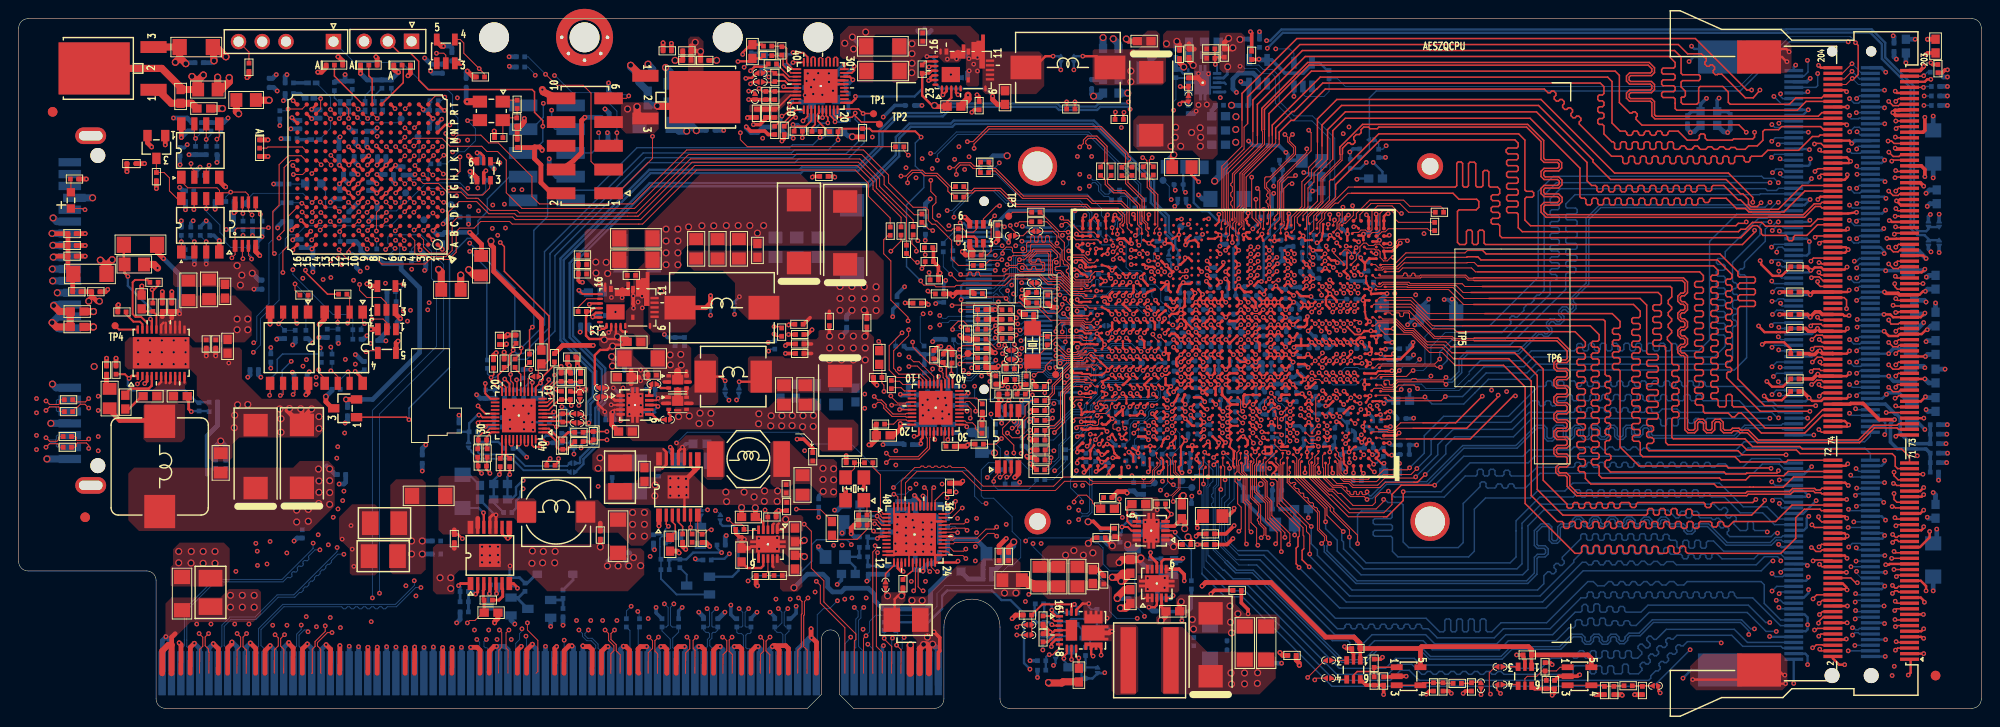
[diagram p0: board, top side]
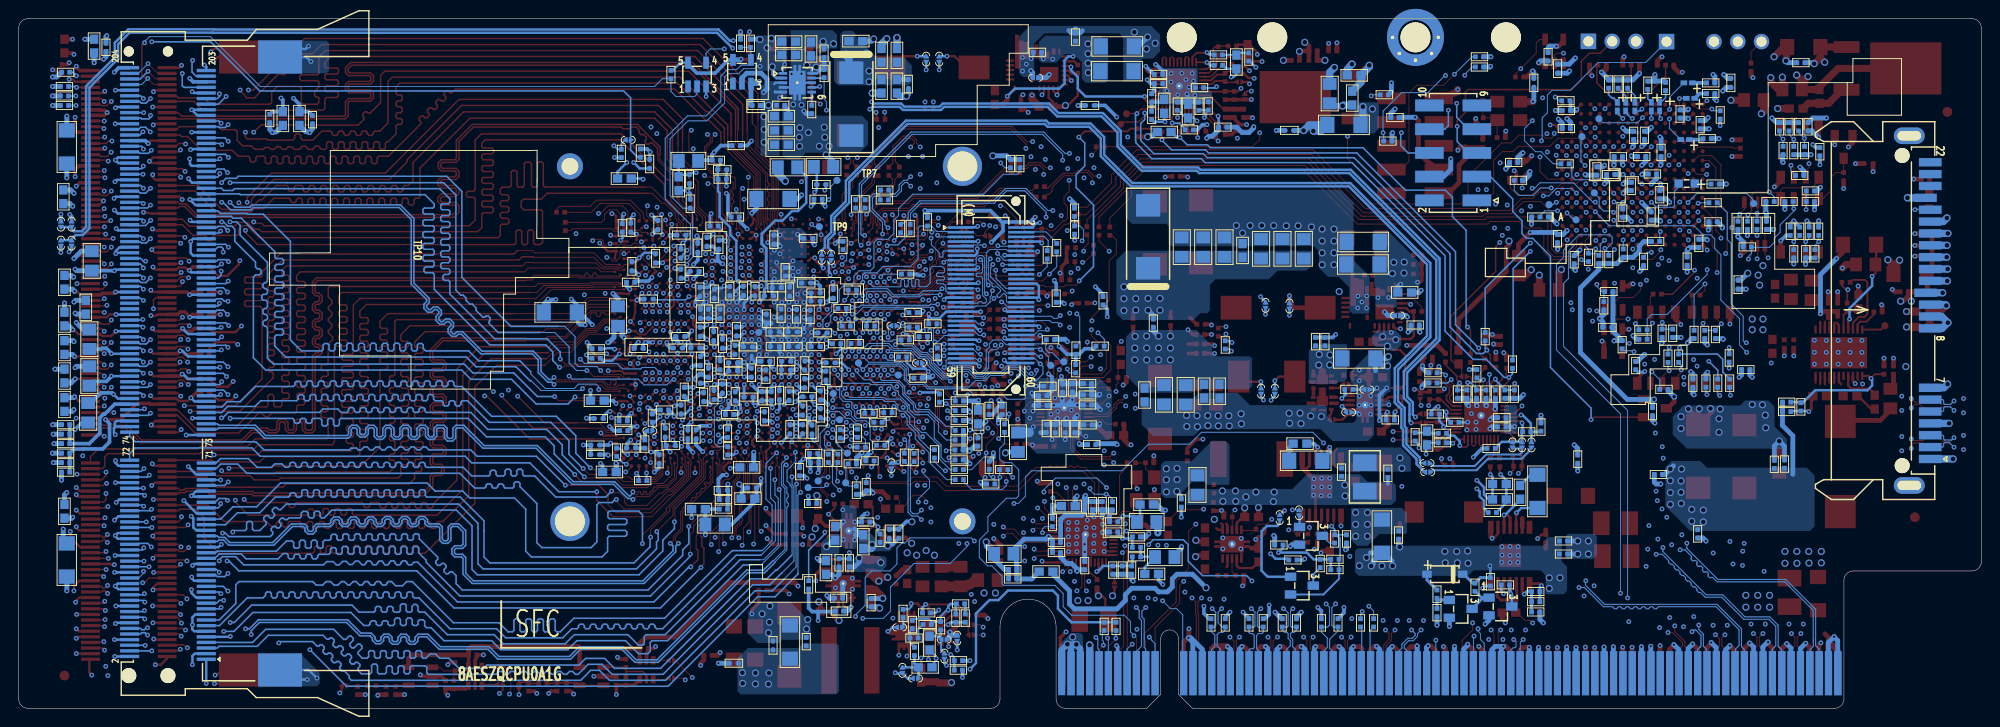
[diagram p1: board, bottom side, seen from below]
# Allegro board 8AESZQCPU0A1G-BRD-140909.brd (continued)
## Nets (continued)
DDR3_CPU_CH1_DQ45: P4.150(DQ45) U14.T1(DDR3_1_DQ_45)
DDR3_CPU_CH1_DQ46: P4.160(DQ46) U14.Y4(DDR3_1_DQ_46)
DDR3_CPU_CH1_DQ47: P4.162(DQ47) U14.Y2(DDR3_1_DQ_47)
DDR3_CPU_CH1_DQ48: P4.165(DQ48) U14.W14(DDR3_1_DQ_48)
DDR3_CPU_CH1_DQ49: P4.167(DQ49) U14.W13(DDR3_1_DQ_49)
DDR3_CPU_CH1_DQ50: P4.177(DQ50) U14.W10(DDR3_1_DQ_50)
DDR3_CPU_CH1_DQ51: P4.179(DQ51) U14.Y11(DDR3_1_DQ_51)
DDR3_CPU_CH1_DQ52: P4.166(DQ52) U14.Y16(DDR3_1_DQ_52)
DDR3_CPU_CH1_DQ53: P4.168(DQ53) U14.Y14(DDR3_1_DQ_53)
DDR3_CPU_CH1_DQ54: P4.174(DQ54) U14.W8(DDR3_1_DQ_54)
DDR3_CPU_CH1_DQ55: P4.176(DQ55) U14.Y10(DDR3_1_DQ_55)
DDR3_CPU_CH1_DQ56: P4.183(DQ56) U14.AC8(DDR3_1_DQ_56)
DDR3_CPU_CH1_DQ57: P4.185(DQ57) U14.AD8(DDR3_1_DQ_57)
DDR3_CPU_CH1_DQ58: P4.191(DQ58) U14.AD15(DDR3_1_DQ_58)
DDR3_CPU_CH1_DQ59: P4.193(DQ59) U14.AC17(DDR3_1_DQ_59)
DDR3_CPU_CH1_DQ60: P4.180(DQ60) U14.AC11(DDR3_1_DQ_60)
DDR3_CPU_CH1_DQ61: P4.182(DQ61) U14.AC9(DDR3_1_DQ_61)
DDR3_CPU_CH1_DQ62: P4.192(DQ62) U14.AC14(DDR3_1_DQ_62)
DDR3_CPU_CH1_DQ63: P4.194(DQ63) U14.AC15(DDR3_1_DQ_63)
DDR3_CPU_CH1_DQS_DN0: P4.10(DQS0#) U14.B37(D\D\R\3\_\1\_\D\Q\S\0\)
DDR3_CPU_CH1_DQS_DN1: P4.25(DQS1#) U14.B30(D\D\R\3\_\1\_\D\Q\S\1\)
DDR3_CPU_CH1_DQS_DN2: P4.43(DQS2#) U14.C22(D\D\R\3\_\1\_\D\Q\S\2\)
DDR3_CPU_CH1_DQS_DN3: P4.60(DQS3#) U14.L29(D\D\R\3\_\1\_\D\Q\S\3\)
DDR3_CPU_CH1_DQS_DN4: P4.139(DQS4#) U14.U12(D\D\R\3\_\1\_\D\Q\S\4\)
DDR3_CPU_CH1_DQS_DN5: P4.154(DQS5#) U14.W3(D\D\R\3\_\1\_\D\Q\S\5\)
DDR3_CPU_CH1_DQS_DN6: P4.171(DQS6#) U14.W7(D\D\R\3\_\1\_\D\Q\S\6\)
DDR3_CPU_CH1_DQS_DN7: P4.186(DQS7#) U14.AD11(D\D\R\3\_\1\_\D\Q\S\7\)
DDR3_CPU_CH1_DQS_DN8: P4.75(DQS8#) U14.D14(DDR3_1_DQSBECC_0)
DDR3_CPU_CH1_DQS_DP0: P4.12(DQS0) U14.D37(DDR3_1_DQS_0)
DDR3_CPU_CH1_DQS_DP1: P4.27(DQS1) U14.D30(DDR3_1_DQS_1)
DDR3_CPU_CH1_DQS_DP2: P4.45(DQS2) U14.A21(DDR3_1_DQS_2)
DDR3_CPU_CH1_DQS_DP3: P4.62(DQS3) U14.M29(DDR3_1_DQS_3)
DDR3_CPU_CH1_DQS_DP4: P4.141(DQS4) U14.U11(DDR3_1_DQS_4)
DDR3_CPU_CH1_DQS_DP5: P4.156(DQS5) U14.W1(DDR3_1_DQS_5)
DDR3_CPU_CH1_DQS_DP6: P4.173(DQS6) U14.Y7(DDR3_1_DQS_6)
DDR3_CPU_CH1_DQS_DP7: P4.188(DQS7) U14.AD12(DDR3_1_DQS_7)
DDR3_CPU_CH1_DQS_DP8: P4.77(DQS8) U14.B14(DDR3_1_DQSECC_0)
DDR3_CPU_CH1_ECC0: P4.69(CB0) U14.D15(DDR3_1_DQECC_0)
DDR3_CPU_CH1_ECC1: P4.71(CB1) U14.C15(DDR3_1_DQECC_1)
DDR3_CPU_CH1_ECC2: P4.81(CB2) U14.D12(DDR3_1_DQECC_2)
DDR3_CPU_CH1_ECC3: P4.83(CB3) U14.E12(DDR3_1_DQECC_3)
DDR3_CPU_CH1_ECC4: P4.72(CB4) U14.D17(DDR3_1_DQECC_4)
DDR3_CPU_CH1_ECC5: P4.74(CB5) U14.B17(DDR3_1_DQECC_5)
DDR3_CPU_CH1_ECC6: P4.80(CB6) U14.C13(DDR3_1_DQECC_6)
DDR3_CPU_CH1_ECC7: P4.82(CB7) U14.B12(DDR3_1_DQECC_7)
DDR3_CPU_CH1_MA0: P4.107(A0) U14.H17(DDR3_1_MA_0)
DDR3_CPU_CH1_MA1: P4.105(A1) U14.G17(DDR3_1_MA_1)
DDR3_CPU_CH1_MA2: P4.106(A2) U14.G18(DDR3_1_MA_2)
DDR3_CPU_CH1_MA3: P4.103(A3) U14.P21(DDR3_1_MA_3)
DDR3_CPU_CH1_MA4: P4.104(A4) U14.M21(DDR3_1_MA_4)
DDR3_CPU_CH1_MA5: P4.99(A5) U14.H22(DDR3_1_MA_5)
DDR3_CPU_CH1_MA6: P4.100(A6) U14.J21(DDR3_1_MA_6)
DDR3_CPU_CH1_MA7: P4.98(A7) U14.J22(DDR3_1_MA_7)
DDR3_CPU_CH1_MA8: P4.97(A8) U14.H21(DDR3_1_MA_8)
DDR3_CPU_CH1_MA9: P4.92(A9) U14.M22(DDR3_1_MA_9)
DDR3_CPU_CH1_MA10: P4.117(A10/AP) U14.L18(DDR3_1_MA_10)
DDR3_CPU_CH1_MA11: P4.96(A11) U14.P22(DDR3_1_MA_11)
DDR3_CPU_CH1_MA12: P4.95(A12) U14.G25(DDR3_1_MA_12)
DDR3_CPU_CH1_MA13: P4.130(A13) U14.G3(DDR3_1_MA_13)
DDR3_CPU_CH1_MA14: P4.90(A14) U14.G26(DDR3_1_MA_14)
DDR3_CPU_CH1_MA15: P4.88(A15) U14.H26(DDR3_1_MA_15)
DDR3_CPU_CH1_ODT0: P4.126(ODT0) U14.L2(DDR3_1_ODT_0)
DDR3_CPU_CH1_ODT1: P4.128(NC/ODT1) U14.N2(DDR3_1_ODT_1)
DDR3_CPU_CH1_RAS_N: P4.122(RAS#) U14.L8(D\D\R\3\_\1\_\R\A\S\)
DDR3_CPU_CH1_RESET_N: N46.2 P4.30(RESET#) R292.2
DDR3_CPU_CH1_RESET_R_N: N46.1 R275.1 U14.N11(D\D\R\3\_\1\_\D\R\A\M\R\S\T\)
DDR3_CPU_CH1_VREF: C449.1 R317.1 R319.2 U14.R29(DDR3_1_VREF)
DDR3_CPU_CH1_VREFCA: C403.1 P4.84(VREFCA) R286.1 R291.2
DDR3_CPU_CH1_VREFDQ: N25.2 P4.1(VREFDQ)
DDR3_CPU_CH1_WE_N: P4.121(WE#) U14.N7(D\D\R\3\_\1\_\W\E\)
DDR3_VCCA_PWROK: U1.2(IN) U7.A9(IO_2_A9/DIFFIO_T11N) U13.2(IN)
ERROR_CPU_N0: R47.2 U7.K14(IO_3_K14/DIFFIO_R17N) U14.AL65(E\R\R\O\R\0\)
ERROR_CPU_N1: R41.2 U7.K13(IO_3_K13/DIFFIO_R16N) U14.AL62(E\R\R\O\R\1\)
ERROR_CPU_N2: R43.2 U7.K12(IO_3_K12/DIFFIO_R15N) U14.AL63(E\R\R\O\R\2\)
FLEX_CLK_SE0: R237.2 R250.2 U14.AH59(FLEX_CLK_SE0)
FLEX_CLK_SE1: R83.2 R85.2 U14.AG56(FLEX_CLK_SE1)
FP_PWR_BTN_N: R207.2 S1.B8(PWR_BTN#) U7.B16(IO_2_B16/DIFFIO_T21N)
FP_RST_BTN_N: TP8.1 U7.F1(IO_1_F1/DIFFIO_L7P)
FPGA_JMPR1: J5.2 U7.E1(IO_1_E1/DIFFIO_L6P)
GBE_CPU_SDP0_1: TP15.1 U14.T48(GBE_SDP0_1)
GBE_CPU_WOL: R103.1 R106.1 U14.V63(GBE_WOL)
GBE_OBSN: R285.1 U14.H50(GBE_OBSN)
GBE_OBSP: R285.2 U14.G50(GBE_OBSP)
GBE_RXN_0: TP16.1 U14.K48(GBE_RXN_0)
GBE_RXP_0: TP17.1 U14.H48(GBE_RXP_0)
GBE_TXN_0: TP20.1 U14.B48(GBE_TXN_0)
GBE_TXP_0: TP18.1 U14.D48(GBE_TXP_0)
GPIO_CPU_11: R46.2 U7.B5(IO_2_B5) U14.AN63(SMB_DATA1)
GPIO_CPU_12: R31.2 U7.B14(IO_2_B14/DIFFIO_T19N) U14.AR63(SMB_CLK1)
GPIO_CPU_SUS0: R101.2 U7.C13(IO_2_C13/DIFFIO_T21P) U14.V66(GPIO_SUS0)
GPIO_CPU_SUS1: R304.2 R314.2 TP19.1 U14.W54(GPIO_SUS1)
GPIO_CPU_SUS2: U7.K1(IO_1_K1/DIFFIO_L13N) U14.T53(GPIO_SUS2)
GPIO_CPU_SUS6: R288.2 U7.D10(IO_2_D10) U14.AC52(P\M\U\_\S\L\P\_\D\D\R\V\T\T\)
GPIO_CPU_SUS7: R270.2 U7.H4(IO_1_H4/DIFFIO_L12P) U14.Y50(P\M\U\_\S\L\P\_\L\A\N\)
I2C_ID_A0: R205.2 R213.1 U9.1(A0)
I2C_ID_A1: R204.2 R212.1 U9.2(A2)
I2C_ID_A2: R203.2 R211.1 U9.3(A3)
ID_EEPROM_VCC: C39.1 U4.3(C) U9.8(VCC)
ID_EEPROM_WP_P: R192.1 R195.1 U9.7(WP)
INTRUDER_N: R254.1 U14.AD53(I\N\T\R\U\D\E\R\)
IRQ_ILB_SERIRQ_CPU: R221.1 U7.C2(IO_1_C2/DIFFIO_L1N) U14.AT50(ILB_SERIRQ)
LED_SEG0_0_HI: D8.2 U7.R11(IO_4_R11/DIFFIO_B17P)
LED_SEG0_0_HI_R: D8.1 R156.1
LED_SEG0_1_HI: D2.2 U7.R12(IO_4_R12/DIFFIO_B19P)
LED_SEG0_1_HI_R: D2.1 R150.1
LED_SEG0_2_HI: D9.2 U7.R13(IO_4_R13/DIFFIO_B21N)
LED_SEG0_2_HI_R: D9.1 R175.1
LED_SEG0_3_HI: D3.2 U7.R14(IO_4_R14/DIFFIO_B22N)
LED_SEG0_3_HI_R: D3.1 R158.1
LED_SEG1_0_HI_R: D4.1 R151.1
LED_SEG1_0_LO: D4.2 U7.R8(IO_4_R8/DIFFIO_B11N)
LED_SEG1_1_HI_R: D5.1 R152.1
LED_SEG1_1_LO: D5.2 U7.R9(IO_4_R9/DIFFIO_B13N)
LED_SEG1_2_HI_R: D6.1 R153.1
LED_SEG1_2_LO: D6.2 U7.T10(IO_4_T10/DIFFIO_B14N)
LED_SEG1_3_HI_R: D7.1 R154.1
LED_SEG1_3_LO: D7.2 U7.T11(IO_4_T11/DIFFIO_B17N)
LPC_CLKRUN_N: R81.2 U14.AH48(L\P\C\_\C\L\K\R\U\N\)
LPC_FRAME_N: R32.1 U7.H3(IO_1_H3/DIFFIO_L11P)
LPC_FRAME_N_R: R32.2 U14.AH56(L\P\C\_\F\R\A\M\E\)
LPC_LAD0: R38.1 U7.B3(IO_2_B3/DIFFIO_T3P)
LPC_LAD0_R: R38.2 U14.AG54(LPC_AD0)
LPC_LAD1: R24.1 U7.E8(IO_2_E8)
LPC_LAD1_R: R24.2 U14.AM53(LPC_AD1)
LPC_LAD2: R42.1 U7.C10(IO_2_C10)
LPC_LAD2_R: R42.2 U14.AL53(LPC_AD2)
LPC_LAD3: R33.1 U7.B4(IO_2_B4/DIFFIO_T4P)
LPC_LAD3_R: R33.2 U14.AG59(LPC_AD3)
MARGIN_DN: N54.1 U7.E7(IO_2_E7/DIFFIO_T7N)
MARGIN_UP: N53.1 U7.E6(IO_2_E6)
MB_PCIE0_RX0_N: S1.A18(PCIE0_RX0_N) U14.BE64(PCIE_RXN_0)
MB_PCIE0_RX0_P: S1.A17(PCIE0_RX0_P) U14.BE63(PCIE_RXP_0)
MB_PCIE0_RX1_N: S1.A22(PCIE0_RX1_N) U14.BH64(PCIE_RXN_1)
MB_PCIE0_RX1_P: S1.A21(PCIE0_RX1_P) U14.BJ63(PCIE_RXP_1)
MB_PCIE0_RX2_N: S1.A26(PCIE0_RX2_N) U14.BK62(PCIE_RXN_2)
MB_PCIE0_RX2_P: S1.A25(PCIE0_RX2_P) U14.BJ62(PCIE_RXP_2)
MB_PCIE0_RX3_N: S1.A30(PCIE0_RX3_N) U14.BH58(PCIE_RXN_3)
MB_PCIE0_RX3_P: S1.A29(PCIE0_RX3_P) U14.BG58(PCIE_RXP_3)
MB_PCIE0_RX4_N: S1.A66(PCIE1_RX0_N) U14.BH57(PCIE_RXN_4)
MB_PCIE0_RX4_P: S1.A65(PCIE1_RX0_P) U14.BG57(PCIE_RXP_4)
MB_PCIE0_RX5_N: S1.A70(PCIE1_RX1_N) U14.BF54(PCIE_RXN_5)
MB_PCIE0_RX5_P: S1.A69(PCIE1_RX1_P) U14.BD54(PCIE_RXP_5)
MB_PCIE0_RX6_N: S1.A74(PCIE1_RX2_N) U14.BG53(PCIE_RXN_6)
MB_PCIE0_RX6_P: S1.A73(PCIE1_RX2_P) U14.BF53(PCIE_RXP_6)
MB_PCIE0_RX7_N: S1.A78(PCIE1_RX3_N) U14.BG50(PCIE_RXN_7)
MB_PCIE0_RX7_P: S1.A77(PCIE1_RX3_P) U14.BE50(PCIE_RXP_7)
MEMHOT_V1P0_N: R184.1 U14.AL46(M\E\M\H\O\T\) U37.4(OUT)
MEMHOT_V3P3_N: P1.198(EVENT#) P4.198(EVENT#) R148.1 U37.2(IN)
NCSI_ARB_OUT: TP14.1 U14.Y59(RSVD13)
PCIE0_MB_TX0_C_N: C253.1 U14.BL61(PCIE_TXN_0)
PCIE0_MB_TX0_C_P: C254.1 U14.BK60(PCIE_TXP_0)
PCIE0_MB_TX0_N: C253.2 C490.2 S1.B16(PCIE0_TX0_N)
PCIE0_MB_TX0_P: C254.2 C489.2 S1.B15(PCIE0_TX0_P)
PCIE0_MB_TX1_C_N: C235.1 U14.BM58(PCIE_TXN_1)
PCIE0_MB_TX1_C_P: C240.1 U14.BL59(PCIE_TXP_1)
PCIE0_MB_TX1_N: C235.2 C492.2 S1.B20(PCIE0_TX1_N)
PCIE0_MB_TX1_P: C240.2 C491.2 S1.B19(PCIE0_TX1_P)
PCIE0_MB_TX2_C_N: C40.1 U14.BN57(PCIE_TXN_2)
PCIE0_MB_TX2_C_P: C41.1 U14.BL57(PCIE_TXP_2)
PCIE0_MB_TX2_N: C40.2 C494.2 S1.B24(PCIE0_TX2_N)
PCIE0_MB_TX2_P: C41.2 C493.2 S1.B23(PCIE0_TX2_P)
PCIE0_MB_TX3_C_N: C29.1 U14.BN55(PCIE_TXN_3)
PCIE0_MB_TX3_C_P: C37.1 U14.BL55(PCIE_TXP_3)
PCIE0_MB_TX3_N: C29.2 C496.2 S1.B28(PCIE0_TX3_N)
PCIE0_MB_TX3_P: C37.2 C495.2 S1.B27(PCIE0_TX3_P)
PCIE0_MB_TX4_C_N: C242.1 U14.BK54(PCIE_TXN_4)
PCIE0_MB_TX4_C_P: C243.1 U14.BM54(PCIE_TXP_4)
PCIE0_MB_TX4_N: C242.2 S1.B68(PCIE1_TX0_N)
PCIE0_MB_TX4_P: C243.2 S1.B67(PCIE1_TX0_P)
PCIE0_MB_TX5_C_N: C33.1 U14.BL53(PCIE_TXN_5)
PCIE0_MB_TX5_C_P: C35.1 U14.BN53(PCIE_TXP_5)
PCIE0_MB_TX5_N: C33.2 S1.B72(PCIE1_TX1_N)
PCIE0_MB_TX5_P: C35.2 S1.B71(PCIE1_TX1_P)
PCIE0_MB_TX6_C_N: C34.1 U14.BM52(PCIE_TXN_6)
PCIE0_MB_TX6_C_P: C36.1 U14.BL52(PCIE_TXP_6)
PCIE0_MB_TX6_N: C34.2 S1.B76(PCIE1_TX2_N)
PCIE0_MB_TX6_P: C36.2 S1.B75(PCIE1_TX2_P)
PCIE0_MB_TX7_C_N: C32.1 U14.BL50(PCIE_TXN_7)
PCIE0_MB_TX7_C_P: C31.1 U14.BN50(PCIE_TXP_7)
PCIE0_MB_TX7_N: C32.2 S1.B80(PCIE1_TX3_N)
PCIE0_MB_TX7_P: C31.2 S1.B79(PCIE1_TX3_P)
PHSFLT_VCCP: R54.2 U12.18(PHSFLT_N)
PHY_MDIO0_I2C_CLK: R112.2 U14.W56(GBE_MDIO0_I2C_CLK)
PHY_MDIO0_I2C_DATA: R289.2 U14.W59(GBE_MDIO0_I2C_DATA)
PHY_MDIO1_I2C_CLK: R281.2 S1.A9(SVR_ID2/GPIO2)
PHY_MDIO1_I2C_CLK_MUX: R281.1 U14.Y54(GBE_MDIO1_I2C_CLK)
PHY_MDIO1_I2C_DATA: S1.A10(SVR_ID3/GPIO3) U14.Y53(GBE_MDIO1_I2C_DATA)
PLTRST_N: R84.2 U7.K5(IO_1_K5/DIFFIO_L15P) U14.AE62(P\M\U\_\P\L\T\R\S\T\)
PLTRST_PCIE1_N: R168.2 S1.B39(PCIE1_RESET#) U7.T15(IO_4_T15/DIFFIO_B23N)
PLTRST_PCIE2_N: R162.2 S1.A11(PCIE0_RESET#) U7.T2(IO_4_T2/DIFFIO_B2P)
PM_DDR_VTT_PWRGD: R146.2 U7.A6(IO_2_A6/DIFFIO_T8N) U38.9(PGOOD)
PM_V1P0_EN: N19.1 U7.E3(IO_1_E3/DIFFIO_L2N)
PM_V1P0_PWRGD: R354.2 R356.2 U7.A5(IO_2_A5/DIFFIO_T6P) U31.7(PGOOD)
PM_V1P1_EN: R123.2 U7.E9(IO_2_E9/DIFFIO_T12P) U25.7(EN)
PM_V1P1_PWRGD: R122.2 U7.L4(IO_1_L4/DIFFIO_L18N) U25.6(PG)
PM_V1P5_EN: R121.1 U7.M3(IO_1_M3/DIFFIO_L18P) U28.5(EN)
PM_V1P5_PWRGD: R118.2 U7.J1(IO_1_J1/DIFFIO_L11N) U28.3(PG)
PM_V1P8_EN: R341.1 U7.F4(IO_1_F4/DIFFIO_L5N) U30.5(EN)
PM_V1P8_PWRGD: R343.2 U7.L2(IO_1_L2/DIFFIO_L16P) U30.3(PG)
PM_V1P35_EN: R116.1 U7.H2(IO_1_H2/DIFFIO_L10P) U26.5(EN)
PM_V1P35_PWRGD: R337.2 U7.N1(IO_1_N1/DIFFIO_L19P) U26.3(PG)
PM_V3P3_PWRGD: R44.1 R52.1 U7.C3(IO_1_C3/DIFFIO_L2P) U8.1(EN) U17.3(PGOOD)
PM_V3P3_V1P9_EN: U7.E4(IO_1_E4/DIFFIO_L3N) U17.2(EN)
PM_V5A_PWRGD: C155.2 N20.1 R127.1 U29.3(VREG5)
PM_VCCP_EN: R264.2 U7.F2(IO_1_F2) U23.17(EN)
PM_VCCP_PWRGD: R251.2 U7.L1(IO_1_L1/DIFFIO_L15N) U23.9(PWRGD_VRDY1)
PM_VDDQ_EN: N4.1 R173.2 U3.17(EN) U7.H1(IO_1_H1/DIFFIO_L10N)
PM_VDDQ_PWRGD: R172.2 U3.9(PWRGD_VRDY1) U7.A8(IO_2_A8/DIFFIO_T11P) U11.2(IN) U36.2(IN)
PM_VNN_EN: R255.2 U7.L3(IO_1_L3/DIFFIO_L19N) U23.10(PWROK_ENL2_INMODE)
PM_VNN_PWRGD: R273.2 U7.L5(IO_1_L5) U23.3(VRDY2)
PMU_AC_PRESENT: R301.2 U14.AA47(PMU_AC_PRESENT)
PMU_GPE_N: R92.2 U14.AB63(P\M\U\_\G\P\E\)
PMU_SLP_S3_N: U7.B9(IO_2_B9/DIFFIO_T12N) U14.AF65(P\M\U\_\S\L\P\_\S\3\)
PMU_SLP_S45_N: U7.K4(IO_1_K4/DIFFIO_L16N) U14.V64(P\M\U\_\S\L\P\_\S\4\5\)
PMU_SUSCLK: R245.2 U14.AD58(PMU_SUSCLK)
PMU_WAKE_N: R80.2 U14.AD66(P\M\U\_\W\A\K\E\)
PWM1_VCCP: U12.19(PWM) U23.21(PWM1)
PWM1_VDDQ_CH01: U2.19(PWM) U3.21(PWM1)
PWM1_VNN: U20.3(PWM) U23.25(PWM1_L2)
PWRGD_COREPWR: N40.2 R61.1 R228.1 U7.F6(IO_1_F6/DIFFIO_L7N)
PWRGD_XDP_CPU: P2.41(HOOK1) R56.1 U7.G1(IO_1_G1/DIFFIO_L9P)
RSMRST_N: R277.1 U7.K2(IO_1_K2/DIFFIO_L14N) U14.AC47(R\S\M\R\S\T\)
RST_CPU_N: C70.1 R57.2 R58.2 U14.Y63(C\P\U\_\R\E\S\E\T\)
RST_XDP_CPURST_N: P2.46(RESET#/HOOK6) R58.1
RST_XDP_N: P2.48(DBR#/HOOK7) R60.1 U7.G3(IO_1_G3/DIFFIO_L8N)
RTEST_CPU_N: C312.1 P2.47(HOOK3) R244.1 U14.AD50(R\T\E\S\T\)
SA0: P4.197(SA0) R163.2
SA0_16765987: P1.197(SA0) R155.2
SA1: P4.201(SA1) R160.2
SA1_16765629: P1.201(SA1) R145.2
SA1_LED: D1.2 R25.2
SATA1_ACTIVITY: D1.1 P3.18
SATA3G_RX0_C_DN: C429.2 U14.H63(SATA_RXN_0)
SATA3G_RX0_C_DP: C428.2 U14.H62(SATA_RXP_0)
SATA3G_RX_DN0: C429.1 S1.A34(SATA0_RX_N)
SATA3G_RX_DP0: C428.1 S1.A33(SATA0_RX_P)
SATA6G_RX0_C_DN: C106.1 U14.M64(SATA3_RXN_0)
SATA6G_RX0_C_DP: C104.1 U14.M62(SATA3_RXP_0)
SATA6G_RX_DN0: C106.2 P3.5
SATA6G_RX_DP0: C104.2 P3.6
SATA6G_TX0_C_DN: C109.1 U14.T64(SATA3_TXN_0)
SATA6G_TX0_C_DP: C112.1 U14.R66(SATA3_TXP_0)
SATA6G_TX_DN0: C109.2 P3.3
SATA6G_TX_DP0: C112.2 P3.2
SATA_OBSN: R283.1 U14.L52(SATA_OBSN)
SATA_OBSP: R283.2 U14.J52(SATA_OBSP)
SGMII_RX_C_DN1: C430.2 U14.L46(GBE_RXN_1)
SGMII_RX_C_DP1: C431.2 U14.J46(GBE_RXP_1)
SGMII_RX_DN1: C430.1 S1.A46(GE0_RX_N)
SGMII_RX_DP1: C431.1 S1.A45(GE0_RX_P)
SGMII_TX_DN1: S1.B48(GE0_TX_N) U14.B46(GBE_TXN_1)
SGMII_TX_DP1: S1.B47(GE0_TX_P) U14.D46(GBE_TXP_1)
SMB_3V3_HOST_ALERT_N: R206.2 S1.B12(I2C_ALERT#) U7.C11(IO_2_C11) U14.AL58(SMBALRT_N0)
SMB_3V3_HOST_CLK: N9.1 N21.1 N22.1 R215.2 R241.2 R253.1 U8.2(SCLO) U14.AN62(SMB_CLK0) U21.9(SMBCLK) U27.6(SCLK)
SMB_3V3_HOST_DATA: N8.1 N23.1 N24.1 R62.2 R201.2 R249.1 U8.7(SDAO) U14.AP62(SMB_DATA0) U21.8(SMBDAT) U27.5(SDATA)
SMB_3V3_XDP_CLK: N9.2 P2.53(SCL)
SMB_3V3_XDP_DATA: N8.2 P2.51(SDA)
SMB_3V3A_HOST_CLK: P1.202(SCL) P4.202(SCL) R194.2 R208.1 S1.B5(I2C_SCL) U5.2(SCL) U7.J16(IO_3_J16/DIFFIO_R13N) U8.3(SCLI) U9.6(SCL)
SMB_3V3A_HOST_DATA: P1.200(SDA) P4.200(SDA) R193.2 R200.1 S1.B6(I2C_DATA) U5.1(SDA) U7.J15(IO_3_J15/DIFFIO_R14N) U8.6(SDAI) U9.5(SDA)
SMB_GBE_CPU_ALERT_N: R313.1 S1.A42(NIC_SMBUS_ALERT#) U14.T55(G\B\E\_\S\M\B\A\L\R\T\)
SMB_GBE_CPU_CLK: R115.1 R117.2 S1.B43(NIC_SMBUS_SCL)
SMB_GBE_CPU_DATA: R67.2 R78.1 S1.B44(NIC_SMBUS_SDA)
SMB_PECI_CLK_UART_TXD: R215.1 R216.2 R751.1 U14.AR65(SMB_CLK2)
SMB_PECI_DATA_UART_RXD: R201.1 R217.2 R752.1 U14.AN65(SMB_DATA2)
SMB_PMBUS_3V3STBY_CLK: R74.2 R253.2 TP1.1 U3.20(SM_CLK) U23.20(SM_CLK)
SMB_PMBUS_3V3STBY_DATA: C80.1 R72.2 R249.2 TP2.1 U3.19(SM_DIO) U23.19(SM_DIO)
SPI_CPLD_CLK: JP5.6 R247.1 R257.1 U7.C15(IO_3_C15/DIFFIO_R2P)
SPI_CPLD_CS0_N: JP1.1 R49.1 R232.2 U7.D13(IO_3_D13)
SPI_CPLD_CS1_N: JP1.3 R229.1 R235.2 U7.D15(IO_3_D15/DIFFIO_R4P)
SPI_CPLD_MISO_N: JP5.7 R48.2 U7.D14(IO_3_D14/DIFFIO_R3P)
SPI_CPLD_MOSI_N: JP5.8 R248.1 R258.1 U7.C14(IO_3_C14/DIFFIO_R1N)
SPI_CPU_CLK: R34.2 U7.E12(IO_3_E12)
SPI_CPU_CLK_R: R34.1 U14.AF46(SPI_CLK)
SPI_CPU_CS0_N: R96.2 U7.E14(IO_3_E14/DIFFIO_R1P)
SPI_CPU_CS0_R_N: R96.1 R99.1 U14.Y65(S\P\I\_\C\S\0\)
SPI_CPU_CS1_N: R93.2 U7.E13(IO_3_E13/DIFFIO_R2N)
SPI_CPU_CS1_R_N: R93.1 U14.AC58(S\P\I\_\C\S\1\)
SPI_CPU_MISO_N: R196.1 U14.AD59(SPI_MISO)
SPI_CPU_MOSI_N: R89.2 U7.E16(IO_3_E16/DIFFIO_R7P)
SPI_CPU_MOSI_R_N: R89.1 U14.AB62(SPI_MOSI)
SPI_CS#: JP1.2 JP5.5
SPI_GBE_CLK: R308.2 U24.6(SCK)
SPI_GBE_CS_N: R310.2 U24.1(CS)
SPI_GBE_MISO: R307.1 U14.W60(GBE_EE_DO)
SPI_GBE_MISO_R: R307.2 U24.2(SO)
SPI_GBE_MOSI: R300.2 U24.5(SI)
SPI_MISO_P: R196.2 U7.E15(IO_3_E15/DIFFIO_R6P)
SPI_SO_R: R48.1 U15.2(SO/IO1) U16.2(SO/IO1)
SRTCST_N: C384.1 R267.1 U14.AD49(S\R\T\C\R\S\T\)
SUSPWRDNACK: R282.1 U14.Y57(SUSPWRDNACK)
SVID_ALERT_N: N10.1 R20.1 R29.2 R66.1
SVID_CLK: N5.2 N6.1 R21.1 R70.1 R174.2
SVID_DATA: N7.2 R22.1 R23.2 R45.1 R73.1
SW_VNN: C364.2 L7.1 N44.1 U18.4(S) U18.8(S1) U19.1(D1) U19.2(D2) U19.5(D3) U19.6(D4) U19.7(D) U20.9(SWITCH)
SYS_RST_N: R218.2 S1.B11(SYS_RESET#) U7.A10(IO_2_A10/DIFFIO_T13P)
SYSPWRGD_L: D10.2 U7.E10(IO_2_E10/DIFFIO_T15P)
TGND_VCCP: N39.1 U12.24(TGND)
TGND_VDDQ_CH01: N29.1 U2.24(TGND)
THERMAL_INT#: R187.2 U5.3(O.S) U7.J14(IO_3_J14/DIFFIO_R14P)
TP_CPU_AJ31: TP10.1 U14.AJ31(VCCRAMCPUSI0GT_MOD3_1P03)
TP_CPU_AL31: TP9.1 U14.AL31(VCCCORE7VIDSI0GT_1P03)
TP_CPU_AL32: TP7.1 U14.AL32(VCCCORE6VIDSI0GT_1P03)
UART0_RXD: R752.2 S1.B32(SATA0_TX_N)
UART0_TXD: R751.2 S1.B31(SATA0_TX_P)
UART1_SOC_RXD: C327.2 JP2.1 S1.A8(COM_RX) U14.AG50(UART1_RXD)
UART1_SOC_TXD: C13.1 JP2.5 R303.1 S1.A7(COM_TX) U14.AH50(UART1_TXD)
USB_CPEN_GPIO_SUS17: U7.T4(IO_4_T4/DIFFIO_B5P) U14.T58(GBE_SDP0_0)
USB_OBSP: R227.1 U14.AR48(USB_OBSP)
USB_OC_N: U7.E5(IO_1_E5) U14.AD63(U\S\B\_\O\C\0\)
USB_RCOMP: C264.1 U14.AT46(USB_RCOMPI) U14.AT48(USB_RCOMPO)
USB_SOC_DN0: S1.B10(USB_N) U14.BC45(USB_DN_1)
USB_SOC_DP0: S1.B9(USB_P) U14.BA45(USB_DP_1)
VNN: C73.2 C74.2 C85.2 C87.2 C100.1 C101.1 C105.1 C297.2 C298.2 C307.1 C308.1 C310.1 C313.2 C329.1 C365.1 C370.1 C371.1 C374.1 L7.2 N35.1 N43.1 R261.1 R296.1 U14.AD36(VNN#AD36) U14.AD39(VNN#AD39) U14.AF36(VNN#AF36) U14.AF39(VNN#AF39) U14.AG36(VNN#AG36) U14.AG39(VNN#AG39) U14.AJ36(VNN#AJ36) U14.AJ39(VNN#AJ39) U14.AL36(VNN#AL36) U14.AL39(VNN#AL39) U14.AM25(VNN#AM25) U14.AM26(VNN#AM26) U14.AM28(VNN#AM28) U14.AM29(VNN#AM29) U14.AM31(VNN#AM31) U14.AM32(VNN#AM32) U14.AM34(VNN#AM34) U14.AM36(VNN#AM36) U14.AM38(VNN#AM38) U14.AM39(VNN#AM39) U14.AM41(VNN#AM41) U14.AM42(VNN#AM42)
VNN_RCSM: R104.1 R111.2 R240.2
VNN_RCSP: R105.1 R111.1 R240.1
VR_V1P1_SENSE: C478.2 R327.2 R331.2 R335.2 U14.AF32(VCCRAMCPUSI1_1P03_SENSE)
VR_VCCP_AVN_RTN: N15.1 R242.2 U14.AF2(VSSCPUVIDSI0_1P03_SENSE)
VR_VCCP_AVN_VSEN: N17.1 R246.2 U14.AE3(VCCCPUVIDSI0_1P03_SENSE)
VR_VNN_RTN: N49.1 N52.2
VR_VNN_VSEN: N47.1 N48.1 N50.2
VREF_DQ_CH01_OP_FB: R132.1 R135.1 R136.2 U33.3(IN-) U33.4(OUTPUT)
VREF_DQ_CH01_OP_FB_16766195: R134.1 R137.1 R138.2 U35.3(IN-) U35.4(OUTPUT)
VREF_DQ_CH01_RW: R129.1 R131.2 U32.5(RW) U33.1(IN+)
VREF_DQ_CH01_RW_16766171: R130.1 R133.2 U34.5(RW) U35.1(IN+)
VREG_3.3V: C66.2 R52.2 U17.18(VREG)
VTT_CPU_DDR: C2.1 C14.1 C174.1 C176.1 C197.1 C205.1 C207.1 C208.1 C209.1 C210.1 C216.1 C219.1 P1.203(VTT1) P1.204(VTT2) P4.203(VTT1) P4.204(VTT2) R164.1 U38.3(VO) U38.5(VOSNS)
XDP_CPU_PRDY_N: P2.5(OBSFN_A1) U14.AW56(C\X\_\P\R\D\Y\)
XDP_CPU_PREQ_N: P2.3(OBSFN_A0) R198.1 U14.AY53(C\X\_\P\R\E\Q\)
XDP_CPU_TCK: P2.57(TCK0) R76.1 TP6.1 U14.AD65(TCK)
XDP_CPU_TDI: P2.56(TDI) R69.1 TP5.1 U14.AC56(TDI)
XDP_CPU_TDO: P2.52(TDO) R236.1 TP11.1 U14.AF63(TDO)
XDP_CPU_TMS: P2.58(TMS) R75.1 TP12.1 U14.AC53(TMS)
XDP_CPU_TRST_N: P2.54(TRSTN) R64.1 TP13.1 U14.AA46(T\R\S\T\)
XDP_DFX_PORT0: P2.9(OBSDATA_A0) U14.BC64(DFX_PORT0)
XDP_DFX_PORT1: P2.11(OBSDATA_A1) U14.AY58(DFX_PORT1)
XDP_DFX_PORT2: P2.15(OBSDATA_A2) U14.AW58(DFX_PORT2)
XDP_DFX_PORT3: P2.17(OBSDATA_A3) U14.AR57(DFX_PORT3)
XDP_DFX_PORT4: P2.27(OBSDATA_B0) U14.AT54(DFX_PORT4)
XDP_DFX_PORT5: P2.29(OBSDATA_B1) U14.AY56(DFX_PORT5)
XDP_DFX_PORT6: P2.33(OBSDATA_B2) U14.AY63(DFX_PORT6)
XDP_DFX_PORT7: P2.35(OBSDATA_B3) U14.AW62(DFX_PORT7)
XDP_DFX_PORT8: P2.10(OBSDATA_C0) U14.AY59(DFX_PORT8)
XDP_DFX_PORT9: P2.12(OBSDATA_C1) U14.AT60(DFX_PORT9)
XDP_DFX_PORT10: P2.16(OBSDATA_C2) U14.BB63(DFX_PORT10)
XDP_DFX_PORT11: P2.18(OBSDATA_C3) U14.AT59(DFX_PORT11)
XDP_DFX_PORT12: P2.28(OBSDATA_D0) U14.AW64(DFX_PORT12)
XDP_DFX_PORT13: P2.30(OBSDATA_D1) U14.AW66(DFX_PORT13)
XDP_DFX_PORT14: P2.34(OBSDATA_D2) U14.AY65(DFX_PORT14)
XDP_DFX_PORT15: P2.36(OBSDATA_D3) U14.AR59(DFX_PORT15)
XDP_DFX_PORT_CLK0: R209.2 U14.AV63(DFX_PORT_CLK0)
XDP_DFX_PORT_CLK1: R214.2 U14.AV65(DFX_PORT_CLK1)
XDP_PWRGD: P2.45(HOOK2) R61.2
XDP_RSMRST_N: R53.1 U7.G2(IO_1_G2/DIFFIO_L8P)
XDP_RSMRST_R_N: P2.39(PWRGOOD/HOOK0) R53.2
N16766151: N22.2 U34.3(SCL)
N16766163: N24.2 U34.4(SDA)
N16766213: C169.1 N26.1 R134.2
N16797885: R298.1 U14.E5(DDR3_1_MON1P)
N16797887: R298.2 U14.C5(DDR3_1_MON1N)
N16797893: R311.1 U14.A8(DDR3_1_MON2P)
N16797895: R311.2 U14.A6(DDR3_1_MON2N)
N16797957: R306.1 U14.T26(DDR3_1_DQPU)
N16797963: C425.1 U14.T25(DDR3_1_CMDPU)
N16797972: R274.1 U14.T32(DDR3_1_ODTPU)
N16826964: N21.2 U32.3(SCL)
N16835626: N23.2 U32.4(SDA)
N16835653: C168.1 N25.1 R132.2
N16856509: R27.1 U14.BP8(DDR3_0_MON1P)
N16856512: R27.2 U14.BP6(DDR3_0_MON1N)
N16856524: R30.1 U14.BK5(DDR3_0_MON2P)
N16856527: R30.2 U14.BK3(DDR3_0_MON2N)
N16858306: R188.1 U14.AW21(DDR3_0_DQPU)
N16858466: C250.1 U14.BA26(DDR3_0_CMDPU)
N16858576: R223.1 U14.AW20(DDR3_0_ODTPU)
N16872739: R219.1 U14.BC38(PCIE_OBSP)
N16872742: R219.2 U14.BA38(PCIE_OBSN)
N16874707: R310.1 U14.R59(GBE_EE_CS)
N16874710: R300.1 U14.W51(GBE_EE_DI)
N16874713: R308.1 U14.T50(GBE_EE_SK)
N16877224: N41.1 U14.AG60(RSVD12)
N16885695: R272.1 U14.R55(SATA3_OBSP)
N16885698: R272.2 U14.R53(SATA3_OBSN)
N16894176: C71.1 R63.2 U14.AJ65(BRTCX1_PAD) X2.2
N16894194: C98.1 R63.1 U14.AJ63(BRTCX2_PAD) X2.1
N16894680: C323.1 U14.AD55(BVCCRTC_EXTPAD)
N16894802: N40.1 U14.AH60(COREPWROK)
N16898105: R238.1 U14.AG46(RCOMP_CORE_LVT)
N16898543: R29.1 U14.BC62(S\V\I\D\_\A\L\E\R\T\)
N16898546: N5.1 U14.BB60(SVID_CLK)
N16898549: N7.1 U14.AW53(SVID_DATA)
N16918882: R269.1 U24.7(HOLD#)
N16925199: P2.4(OBSFN_C0) R209.1
N16925202: P2.6(OBSFN_C1) R214.1
N16945830: R332.2 U14.AF34(VSSRAMCPUSI1_1P03_SENSE)
N17019721: R109.2 U27.1(X2)
N17019726: C116.1 R109.1 X3.3(X3)
N17019783: C125.1 U27.2(X1) X3.1(X1)
N17020063: R113.1 U27.37(DIFF_STOP_N_3V3)
N17022785: R126.2 U27.18(CLKREQB_N)
N17022924: R119.1 R120.2 U27.4(VREF0_2X_FSLA)
N17022990: N18.1 U27.13(VSEL_PCI_25M_PCI4_2X)
N17023227: R322.1 U27.31(PCI_STOP_N_3V3)
N17023993: R82.1 U21.11(DFB_OUT_NC)
N17024019: R82.2 U21.10(DFB_OUT_NC_N)
N17024141: R95.2 U21.32(OE4_N)
N17024148: R91.2 U21.38(OE5_N)
N17024192: R65.2 R71.1 U21.2(HIBW_BYPM_LOBW_N)
N17031771: C473.1 L21.2 R328.1 R330.1
N17058712: D11.1(ANODE) R340.1
N17058714: R340.2 R345.1 U42.1(GATE)
N17058720: R338.2 U41.1(GATE) U42.3(DRAIN)
N17058814: C450.2 L11.1 U29.10(SW1) U29.11(SW2)
N17059267: R233.2 R234.1 U15.3(WP#/IO2)
N17059277: R230.2 R231.1 U16.3(WP#/IO2)
N17059466: R256.2 U15.7(HOLD#/IO3)
N17059528: R260.2 U16.7(HOLD#/IO3)
N17060112: C103.1 L10.1 R87.2 R88.1 U17.6(LL_6) U17.7(LL_7) U17.8(LL_8) U17.9(LL_9) U17.10(LL_10) U17.11(LL_11)
N17060116: C92.1 R88.2
N17060175: C53.1 R36.2 U17.19(VDD)
N17060208: R44.2 U17.20(MODE)
N17060212: R55.2 U17.21(TRIP)
N17060239: R90.1 U17.4(VBST)
N17060256: C103.2 R90.2
N17060272: C389.2 C395.1 R87.1
N17062735: Q2.1(ADJ/GND) R149.1 R161.2
N17064609: Q1.1(ADJ/GND) R12.2 R14.2
N17089314: R183.1 U6.5(DIR)
N17090644: R199.2 U8.5(RDY)
N17142707: R171.2 R179.1 U5.7(A0)
N17142719: R170.2 R178.1 U5.6(A1)
N17142732: R169.2 R177.1 U5.5(A2)
N17144878: C111.1 R100.2 U23.1(RCSP)
N17144894: C111.2 R97.2 U23.2(RCSM)
N17145414: C107.1 N17.2 U23.4(VSEN)
N17145423: C107.2 N15.2 U23.5(VRTN)
N17145876: C94.1 C95.1 R79.2 U23.8(V18A)
N17146129: C367.1 R68.2 R262.1 U23.11(VINSEN)
N17146590: R279.2 U23.6(RRES)
N17146868: N10.2 U23.13(SVT_SVALERT)
N17146877: R73.2 U23.15(SV_DIO_VIDSEL0)
N17146886: R70.2 U23.14(SV_CLK_VIDSEL1)
N17147965: C368.1 R263.1 U23.12(VDDIO_SVADDR)
N17148213: C110.2 R104.2 U23.29(RCSM_L2)
N17148219: C110.1 R105.2 U23.30(RCSP_L2)
N17148656: C414.1 N47.2 N48.2 R296.2 U23.27(VSEN_L2)
N17148665: C414.2 N49.2 R280.2 U23.26(VRTN_L2)
N17149089: C419.1 R284.2 R287.1
N17149196: U23.37(ISEN_2) U23.38(IRTN_2)
N17149216: U23.35(ISEN_3) U23.36(IRTN_3)
N17149500: C444.1 R107.2 R316.1 R320.1
N17149614: U23.33(ISEN_2_L2) U23.34(IRTN_2_L2)
N17149691: C369.1 R265.1 U23.18(ADDR_PROT)
N17152659: C292.2 L5.1 N38.1 U12.6(SW1) U12.7(SW2) U12.8(SW3) U12.9(SW4) U12.10(SW5) U12.11(SW6)
N17152745: C292.1 U12.17(BOOST)
N17154210: C364.1 N42.2
N17167628: N11.1 U20.10(HI_GATE)
N17167629: N11.2 U18.3(G)
N17167636: N16.1 U20.6(LO_GATE)
N17167639: N16.2 U19.3(G)
N17167672: N42.1 U20.1(BOOT)
N17167678: C108.2 R276.2 U20.4(VCC)
N17167679: C96.2 N12.2 N14.2 U20.2(HVCC) U20.5(LVCC)
N17167680: N45.1 U20.8(MODE)
N17168063: C6.1 R2.2 U3.1(RCSP)
N17168068: C6.2 R6.2 U3.2(RCSM)
N17168091: C16.1 N1.2 U3.4(VSEN)
N17168094: C16.2 N2.2 U3.5(VRTN)
N17168118: C25.1 C26.1 R16.2 U3.8(V18A)
N17168130: C200.1 R19.2 R165.1 U3.11(VINSEN)
N17168147: R157.2 U3.6(RRES)
N17168149: R20.2 U3.13(SVT_SVALERT)
N17168150: R22.2 U3.15(SV_DIO_VIDSEL0)
N17168151: R21.2 U3.14(SV_CLK_VIDSEL1)
N17168168: C199.1 R167.1 U3.12(VDDIO_SVADDR)
N17168181: R140.1 U3.39(ISEN_1)
N17168182: R143.1 U3.40(IRTN_1)
N17168188: C184.1 R140.2 R142.1
N17168191: U3.37(ISEN_2) U3.38(IRTN_2)
N17168196: U3.35(ISEN_3) U3.36(IRTN_3)
N17168203: U3.33(ISEN_2_L2) U3.34(IRTN_2_L2)
N17168208: C204.1 R166.1 U3.18(ADDR_PROT)
N17168279: U3.31(ISEN_1_L2) U3.32(IRTN_1_L2)
N17179290: C156.1 N19.2 N20.2 R346.2 U31.15(ENABLE)
N17179770: R128.2 U31.5(RT_SYNC)
N17179844: C158.1 U31.2(VREF)
N17180503: C486.1 U31.14(BOOT)
N17180512: C486.2 N55.2
N17180842: L14.1 N55.1 U31.12(SW)
N17181045: N59.1 N60.2 R353.1 R355.1
N17181051: C487.2 R342.2 R347.2 R348.1 R349.1 U31.1(FB)
N17181054: N57.2 N58.1 R349.2 R352.2
N17181057: C497.1 R347.1 R353.2
N17181086: R352.1 R355.2 U31.8(VSNS)
N17181203: C487.1 C488.1 U31.3(COMP)
N17181207: C488.2 R342.1
N17181386: C497.2 R348.2
N17226208: C476.1 U30.7(SS)
N17226226: R333.1 R334.1 U30.8(FB)
N17226252: C139.1 U28.7(SS)
N17226270: R124.1 R125.1 U28.8(FB)
N17226296: C122.1 U26.7(SS)
N17226314: R321.1 R323.1 U26.8(FB)
N17250574: C10.1 R3.1 R5.2 U38.1(REFIN)
N17250701: N4.2 R10.1 U38.7(EN)
N17251874: C201.1 U38.6(REFOUT)
N17255840: R8.2 U2.18(PHSFLT_N)
N17255975: C20.2 L1.1 N28.1 U2.6(SW1) U2.7(SW2) U2.8(SW3) U2.9(SW4) U2.10(SW5) U2.11(SW6)
N17255997: C20.1 U2.17(BOOST)
N17388894: R350.1 S1.A5(SVR_ID0/GPIO0)
N17389012: R351.1 S1.A6(SVR_ID1/GPIO1)
N17417846: R7.2 U3.3(VRDY2)
N17417864: R18.2 U3.10(PWROK_ENL2_INMODE)
N17418022: R147.2 U3.30(RCSP_L2)
N17418057: R147.1 U3.29(RCSM_L2)
N17438894: N36.2 N52.1
N17439936: N35.2 N50.1
N17467924: C450.1 R315.2
N17467927: R315.1 U29.12(VBST)
N17470556: R302.1 U25.12(VBST)
N17536513: C27.1 L2.2 R13.1 X1.4(VCC)
N17536522: R13.2 X1.1(OE)
N17552359: R305.2 R312.2 U24.3(WP#)
N17555377: TP47.1 U7.D1(IO_1_D1/DIFFIO_L4P)
N17555397: TP48.1 U7.J3(IO_1_J3/DIFFIO_L14P)
N17555432: TP49.1 U7.F14(IO_3_F14/DIFFIO_R3N)
N17555507: TP51.1 U7.D7(IO_2_D7/DIFFIO_T6N)
N17555530: TP52.1 U7.R10(IO_4_R10/DIFFIO_B16P)
N17799133: N51.2 U14.C60(SATA_RXN_3) U14.C62(SATA_RXN_2) U14.D60(SATA_RXP_3) U14.E62(SATA_RXP_2) U14.G62(SATA_RXP_1) U14.G64(SATA_RXN_1) U14.L63(SATA3_RXP_1) U14.L65(SATA3_RXN_1)
N18063596: D10.1 R191.1
N18398429: R94.2 U21.19(OE1_N)
N18398432: R293.2 U21.22(OE2_N)
N18398435: R102.2 U21.28(OE3_N)
N170603760: TP4.1 U17.22(RF)

Pads without a net: B1 1 2; B2 1 2; B3 1 2; JP3 6 7 8; JP5 1 2 9 10; P1 118 120; P2 21 22 23 24 55; P3 20 21 22; P4 118 120; S1 A37 A38 A41 A49 A50 A53 A54 A57 A58 A61 A62 B40 B51 B52 B55 B56 B59 B60 B63 B64; U1 1; U2 5 23 25; U3 22 23 24 25; U7 A2 A4 A7 A11 A12 A13 A15 B1 B6 B7 B10 B11 B12 B13 C4 C6 C9 D2 D3 D4 D5 D6 D8 D9 D11 D12 D16 E2 E11 F5 F11 F12 F13 F15 F16 G4 G12 G13 G14 G15 G16 H12 H13 H14 H15 H16 J4 J5 J12 J13 L11 L12 L13 L14 L16 M1 M2 M6 M7 M8 M9 M10 M11 M12 M13 M14 M15 M16 N2 N3 N5 N6 N7 N8 N9 N10 N11 N12 N13 N14 N15 N16 P2 P4 P5 P6 P7 P8 P9 P10 P11 P12 P13 P14 P15 R1 R3 R4 R5 R6 R7 R16 T5 T12 T13; U11 1; U12 5 23 25; U13 1; U14 A42 A54 AB65 AC25 AC26 AH51 AH54 AJ34 AL34 AL49 AP20 AP21 AT34 AT51 AT63 AU34 AY46 B44 B53 B57 BA41 BA46 BB19 BB41 BB42 BD19 BD23 BD37 BD42 BD46 BE34 BE41 BF37 BF38 BF45 BF46 BG5 BG19 BG25 BG26 BG34 BG38 BG41 BG42 BG45 BG49 BH3 BH19 BH25 BH42 BH49 BK40 BL39 BL41 BL44 BL46 BL48 BM40 BM43 BM49 BN39 BN41 BN44 BN46 BN48 BP43 BP49 C42 C54 D44 D53 D57 E57 E58 G10 G42 H10 H42 J13 J38 J44 K4 L4 L7 L13 L25 L26 L38 L44 N8 P38 R37 R63 R65; U17 5; U21 13 26 27 30 33 34 40; U23 22 23 24; U27 8 9 10 16 42 43; U31 16; U36 1; U37 1

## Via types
v1: diameter 0.508, hole 0.254, TOP to BOTTOM, 2553 vias
v2: diameter 0.762, hole 0.508, TOP to BOTTOM, 302 vias
v3: diameter 0.635, hole 0.381, TOP to BOTTOM, 5 vias

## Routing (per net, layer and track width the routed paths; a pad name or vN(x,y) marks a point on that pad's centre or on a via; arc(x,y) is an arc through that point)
3.3V_FB: length 12.9
  TOP w0.203: R77.2 11.37,35.75 v1(11.81,35.31)
  TOP w0.254: v1(11.81,35.31) 12.07,35.57 U17.1
  BOTTOM w0.254: R268.2 19.37,32.77 C389.1 19.11,32.7 17.78,34.04 12.19,34.04 11.68,34.54 11.68,35.18 v1(11.81,35.31)
5V_EN: length 2.1
  TOP w0.305: U29.7 52.94,13.35 53.37,12.93 v1(53.37,12.85)
  BOTTOM w0.305: R336.1 52.54,13.08 53.14,13.08 v1(53.37,12.85)
5V_FB: length 4.3
  TOP w0.305: U29.2 49.12,12.45 v1(48.89,12.22)
  BOTTOM w0.305: R344.1 C484.1 R339.1 48.62,12.5 v1(48.89,12.22)
5V_GOOD: length 2.7
  TOP w0.305: U29.6 51.72,12.85 51.78,12.78 51.78,12.48 51.79,12.48 51.79,11.99 51.78,11.99 51.78,11.98 51.39,11.58 R127.2
5V_SS: length 3.5
  TOP w0.305: v1(50.37,12.27) 50.37,12.5 50.42,12.55 U29.4
  BOTTOM w0.305: U41.3 50.24,12.14 v1(50.37,12.27) 50.37,12.48 50.48,12.6 C483.1
12V_HOLD: length 14.7
  TOP w0.254: C135.1 47.03,18.61 v1(47.47,18.16)
  TOP w0.508: C135.1 46.61,19.1 ; U29.13 49.12,20.33
  L8_SIG w0.254: v1(47.47,18.16) 51.38,18.16 52.58,16.97 v1(52.58,15.24)
  BOTTOM w0.254: v1(52.58,15.24) 52.53,15.19 R336.2
  BOTTOM w0.305: R336.2 53.59,13.98 R338.1 54.42,13.4 55.36,14.34 D11.2
AGND_V1P0: length 6.3
  TOP w0.203: U31.4 U31.17
  TOP w0.254: v1(110.37,8.15) 110.69,8.15 110.89,8.35 U31.4
  TOP w0.508: C158.2 109.61,8.83 110.2,8.24 110.2,7.98 ; 110.2,7.98 v1(110.37,8.15) ; 110.2,7.98 R128.1
  BOTTOM w0.508: N56.2 110.05,7.83 v1(110.37,8.15) 110.37,7.65 N57.1
GND: length 1598.2
  TOP w0.102: 141.11,50.63 141.11,50.68 v1(141.13,50.7) ; v1(146.66,50.63) 146.66,50.63 146.63,50.63 ; U14.AP28 132.76,42.25 131.97,42.25 U14.AP29 ; v1(144.51,28.72) 144.51,28.71 144.51,28.71 U14.F4 ; U14.D6 143.93,27.16 v1(143.93,27.13) 143.93,27.1 U14.C6 ; 144.58,33.43 v1(144.59,33.42)
  TOP w0.127: v1(131.35,27.4) 131.35,27.23 131.57,27.01 131.57,26.67 131.51,26.61 U14.A30
  TOP w0.152: U14.AE64 115,37.48 115.33,37.48 U14.AD62 ; R116.2 v1(121.82,21.24) ; U14.AP64 114.46,42.01 U14.AN66
  TOP w0.157: v1(145.06,25.3) 144.95,25.4 144.86,25.4 144.45,25.81 U14.A5 ; 95.26,18 U27.17
  TOP w0.178: v1(131.18,32.38) 131.31,32.38 131.72,32.79 U14.R30 ; U14.A33 129.94,25.93 129.94,26.67 U14.C33 ; U14.AL9 142.97,40.01 143.62,40.01 U14.AK5 ; U14.T31 U14.T29 U14.T28
  TOP w0.203: U14.BG66 113.4,49.26 113.36,49.3 113.36,49.48 v1(113.28,49.56) 113.5,49.5 U14.BJ66 ; v1(112.61,42.21) 112.62,42.21 112.81,42.01 U14.AN66 ; U14.E46 123.65,28.02 123.32,28.35 ; 123.3,28.37 123.03,27.87 U14.E48 ; v1(146.09,26.22) 145.8,26.22 U14.C3 145.52,27.01 145.52,27.31 U14.E3 ; U14.BD65 114.78,47.19 114.86,47.27 U14.BD63 ; U14.BK10 141.11,50.63 ; U14.M56 U14.M54 ; v1(146.77,30.15) U14.K1 ; U14.AY62 v1(116.27,45.72) U14.BB62 ; v1(128.41,28.43) 128.41,28.1 U14.E37 ; v1(116.64,28.89) 116.64,28.99 U14.H59 U14.G59 ; v1(137.44,50.55) U14.BL19 ; v1(137.44,50.55) U14.BK19 ; v1(137.44,50.55) U14.BK18 U14.BK17 ; v1(144.59,33.42) U14.R5 ; U14.AA3 145.46,36.08 145.75,36.08 145.76,36.09 U14.AB1 ; U14.F1 v1(146.66,28.38) ; v1(146.09,32.62) 145.85,32.86 U14.R2 145.58,32.86 145.57,32.88 145.19,32.88 145.17,32.86 144.9,32.86 U14.R4 ; U14.T62 116.33,33.52 v1(116.35,33.63) 116.29,33.77 U14.U62 ; U14.BP58 117.3,52.79 v1(117.3,52.79) ; 118.05,28.94 v1(118.05,28.91) 118.11,28.91 U14.G56 ; 118.05,28.94 U14.H56 ; 118.05,28.94 118.05,28.95 U14.H58 ; U14.BK21 135.67,50.62 135.67,50.76 ; U14.BP55 119.42,52.62 119.27,52.76 v1(119.27,52.87) ; U14.BN37 128.42,52.04 U14.BP37 v1(128.42,52.87) ; 119.77,27.45 v1(119.77,27.34) ; 119.77,27.45 119.77,27.63 U14.E54 ; 119.77,27.45 119.17,27.83 U14.E55 ; U14.AK64 114.68,40.11 114.09,40.11 113.82,40.39 U14.AK66 v1(113.18,40.39) ; U14.C58 117.25,27.3 U14.D59 U14.E59 116.47,28.4 116.47,28.37 ; U14.AA66 113.81,35.79 114.59,35.79 U14.AA64 115.52,35.65 115.53,35.66 U14.AA62 116.54,36.18 v1(116.55,36.18) 116.55,36.31 U14.AD62 ; U14.G34 U14.E34 U14.D33 ; U14.E16 U14.E18 v1(137.86,27.4) 137.87,27.39 U14.C18 ; U14.BK42 125.68,50.08 125.25,49.99 v1(124.85,49.59) U14.BK44 ; 132.31,27.44 v1(132.31,27.44) 132.31,27.44 ; 132.31,27.44 U14.E28 ; 132.31,27.44 132.3,27.44 U14.E30 ; U14.BK39 U14.BK37 128.54,50.6 v1(128.54,50.65) ; U14.E40 v1(127.27,28.53) 127.46,28.35 U14.E39 ; v1(144.62,44.85) U14.AW5 ; v1(144.62,44.85) U14.AY5 U14.BB5 ; v1(144.62,44.85) U14.AV4 ; v1(122.01,25.22) 122.04,25.22 122.29,25.48 122.3,25.48 122.5,25.68 U14.A48 122.46,25.84 122.46,26.59 U14.C49 ; U14.BK28 133.01,50.7 133.01,50.72 133.03,50.74 ; 114.21,25.36 114.09,25.24 v1(113.99,25.24) ; 114.21,25.36 114.21,25.4 U14.A66 ; 114.21,25.36 U14.A64 ; U14.BP40 126.88,52.38 v1(127.32,52.38) ; v1(112.75,39.09) 112.85,39.09 112.95,39.19 113.47,39.19 U14.AG66 114.12,38.95 114.17,39 U14.AG64 115.02,39 115.07,38.95 U14.AG63 ; v1(142.28,52.79) 142.15,52.79 141.93,52.57 U14.BP10 ; U26.6 119.64,20.39 v1(119.2,20.83) ; v1(128.54,50.65) 128.37,50.82 U14.BL37 ; v1(128.54,50.65) 128.67,50.52 128.67,50.09 U14.BK36 ; U14.C51 121.01,25.85 U14.A51 121.06,25.5 v1(120.87,25.3) ; U14.N63 115.03,31.73 U14.N65 114.07,31.73 U14.M66 113.72,32.03 113.53,32.21 v1(113.53,32.53) ; v1(146.74,31.78) 146.41,31.78 U14.N1 ; 133.03,50.74 133.03,50.47 U14.BK27 ; 133.03,50.74 v1(133.04,50.75) ; U14.F63 U14.E64 U14.C64 U14.C66 113.46,26.75 113.26,26.55 v1(113.26,26.25) ; U14.BM62 U14.BP62 115.25,52.42 115.27,52.71 v1(115.29,52.73) 115.17,52.72 U14.BP64 U14.BM64 ; U14.BH60 116.51,49.1 116.51,48.66 v1(116.49,48.64) 116.06,48.64 U14.BF62 ; v1(122.07,50.77) U14.BK49 ; 95.26,19.2 93.66,20.8 U27.48 ; U14.BP46 123.98,52.36 v1(124.41,52.36) ; v1(144.45,31.57) 144.34,31.67 U14.N5 ; v1(124.15,50.68) U14.BK46 ; v1(124.15,50.68) U14.BM45 ; v1(124.15,50.68) U14.BK45 ; U14.R56 U14.T56 ; U14.A62 115.48,25.54 v1(115.28,25.34) 115.38,25.41 115.53,25.38 U14.A61 ; v1(116.47,28.28) 116.47,28.37 ; 116.47,28.37 U14.E61 ; 135.67,50.76 135.58,50.67 U14.BK22 ; 135.67,50.76 v1(135.67,50.78) ; v1(116.45,29.63) 116.14,29.94 U14.J63 ; v1(131.55,52.99) 131.55,52.6 131.5,52.55 131.5,52.54 131.3,52.35 U14.BP31 131.3,52.29 131.44,52.14 131.44,51.9 U14.BN30 ; U14.AK62 115.49,40.09 v1(115.38,40.09) U14.AH62 116.17,38.92 v1(116.18,38.92) 116.18,38.9 U14.AF62 ; U14.BF4 U14.BE5 ; U14.B55 U14.D55 ; U14.BK51 v1(120.93,49.76) ; v1(120.93,49.76) U14.BK53 ; v1(120.93,49.76) U14.BH50 ; U14.H66 113.4,29.19 v1(113.27,29.07) ; v1(124.86,28.67) 124.86,28.76 U14.E45 U14.C45 124.36,26.03 U14.A45 124.13,25.5 124.41,25.21 v1(124.47,25.21) ; v1(113.11,47.81) 113.25,47.95 U14.BE66 ; U14.AT5 U14.AP5 U14.AN5 ; U14.BK24 v1(134.37,50.01) ; v1(134.37,50.01) U14.BL25 ; v1(134.37,50.01) U14.BK26 ; U14.BK48 122.77,49.95 122.61,49.79 122.61,49.78 ; U14.A59 116.97,25.77 116.73,25.46 116.62,25.36 v1(116.62,24.92) ; v1(113.26,43.74) 113.26,43.65 113.46,43.45 U14.AT66 113.77,43.5 U14.AT64 ; v1(134.26,24.97) 134.26,25.19 134.57,25.5 U14.A24 ; v1(120.93,52.83) 120.86,52.76 U14.BP52 ; U14.T47 122.91,33.8 122.91,34.09 123.28,34.46 ; v1(139.13,25.23) 139.13,25.75 U14.A15 ; v1(147.08,40.64) 147.04,40.59 U14.AL1 ; v1(140.29,52.84) 140.31,52.82 U14.BP13 ; v1(140.6,25.18) 140.51,25.27 U14.A12 ; v1(129.13,28.45) 128.84,28.11 U14.E36 ; U14.BB65 114.07,46.42 113.86,46.42 113.76,46.52 U14.BB66 113.28,46.95 v1(112.96,46.95) ; U14.BF1 U14.BG1 ; U14.N62 v1(116.34,32.29) U14.R62 ; U14.AW26 133.29,44.45 133.29,44.33 v1(133.25,44.3) 133.09,44.3 132.97,44.39 U14.AW28 ; U14.BM22 135.67,51.35 135.86,52.21 U14.BP22 135.8,52.74 135.9,52.84 v1(135.9,52.94) ; U14.AL42 124.92,41.3 ; U14.BH62 v1(115.29,49.17) 115.28,49.06 115.27,49.06 U14.BG63 ; U14.AG5 143.69,39.15 v1(143.69,39.19) ; U14.BM61 U14.BP61 ; U14.AR62 U14.AR60 ; U14.BK64 U14.BK66 113.39,50.54 v1(113.18,50.75) ; U14.E14 U14.E13 v1(140.29,27.42) ; U14.BD60 U14.BD62 ; v1(113.56,33.76) 113.63,33.69 U14.U65 ; U14.Y60 U14.W62 116.04,34.82 v1(116.04,34.43) ; U14.E49 U14.G48 ; U14.E52 v1(121.07,28.06) ; v1(121.07,28.06) U14.D51 ; v1(121.07,28.06) U14.E50 ; U14.BN14 U14.BL14 U14.BK15 139.08,49.82 v1(138.92,49.82) ; U14.A18 137.64,25.22 ; U14.M60 116.97,31.02 v1(117,30.99) ; U14.AD4 U14.AD2 ; U14.AH57 U14.AG57 ; U14.E10 U14.D10 U14.B10 141.79,26.2 142.14,25.85 U14.A9 142.14,25.43 v1(141.99,25.27) ; U14.A57 118,24.93 v1(117.86,24.79) ; v1(129.86,49.85) U14.BL34 ; U14.K32 U14.K34
  TOP w0.254: U14.BJ1 v1(146.72,49.72) ; U7.G6 39.82,55.62 v1(39.32,55.12) 38.83,54.62 U7.F7 ; U14.BM66 U14.BP66 113.85,52.52 v1(114.09,52.75) ; P1.143 200.92,50.25 200.9,50.24 199.95,50.24 v1(199.9,50.29) ; U14.U65 114.54,33.69 114.68,33.82 114.71,33.82 v1(114.71,33.82) 114.73,33.82 114.73,33.82 114.85,33.82 114.9,33.77 U14.U63 ; U14.BD34 v1(129.15,46.73) U14.BB34 ; v1(122.63,49.74) 122.61,49.76 122.61,49.78 123.28,49.78 123.56,49.49 U14.BG46 ; P1.41 203.43,17.25 204.47,18.29 v1(204.47,18.92) ; v1(142.7,32.18) 142.39,32.18 U14.N10 ; U12.22 61.47,41.83 v1(61.42,41.88) 61.42,41.99 61.76,42.33 U12.21 ; U14.AW46 U14.AY45 124.48,45.47 124.52,45.47 v1(124.61,45.56) 124.74,45.43 125.37,45.43 U14.BA42 ; U14.J63 114.71,29.94 U14.J64 114.62,29.99 114.44,29.81 113.85,29.81 U14.J66 ; v1(70.59,23.69) 71.24,23.04 U25.5 ; P1.58 v1(195.59,22.35) ; v1(204.09,12.57) 204.09,13.08 203.52,13.65 P1.29 ; P1.178 195.9,60.75 196.13,60.52 v1(196.13,60.45) ; v1(125.17,34.65) U14.W42 v1(125.17,35.45) ; v1(125.17,34.65) U14.V44 ; v1(125.17,34.65) U14.V42 ; v1(140.65,35.21) 140.66,35.21 U14.W11 ; P1.17 v1(203.8,10.05) ; U14.BD32 v1(130.55,47.49) U14.BE32 ; U14.L50 121.41,31.4 ; 121.41,31.4 121.47,31.4 U14.N50 ; 121.41,31.4 121.4,31.42 121.4,31.43 v1(121.31,31.52) ; v1(195.61,62.43) 195.49,62.55 P1.184 ; P1.205 188.28,4.1 188.82,3.56 v1(188.98,3.56) ; P1.205 185.19,3.07 v1(179.12,3.07) ; P1.205 187.68,2.64 v1(189.05,2.64) ; U14.AM46 v1(124.37,41.85) ; v1(124.37,41.85) U14.AP44 v1(124.37,42.65) ; v1(124.37,41.85) U14.AM44 124.92,41.3 124.92,40.8 U14.AL44 ; U14.AA66 112.83,35.88 v1(112.67,36.04) ; U14.BB54 119.64,46.53 v1(119.29,46.18) ; v1(195.38,4.67) 194.79,4.67 194.12,5.34 P1.2 ; U14.AA25 v1(134.77,35.45) U14.AA23 ; U2.21 97.78,67.73 97.56,67.51 97.56,67.28 97.61,67.23 ; P1.67 v1(203.75,25.05) ; U14.W4 v1(144,34.65) ; v1(144,34.65) 144.03,34.68 U14.Y5 ; v1(144,34.65) 144.03,34.62 U14.V5 ; U14.L30 131.72,30.57 v1(132.06,30.23) 132.06,30.21 U14.J29 ; v1(140.3,44.36) 139.88,43.94 139.88,43.17 U14.AR13 ; v1(140.3,44.36) 141.02,43.63 U14.AT11 ; v1(140.3,44.36) 140.19,44.46 140.19,44.49 U14.AW14 ; U14.AD14 139.86,37.54 v1(139.51,37.19) ; P1.23 203.52,11.85 203.91,11.46 v1(203.91,11.35) ; v1(128.89,47.71) 128.89,47.41 U14.BC37 ; v1(124.37,42.65) U14.AP46 123.93,42.21 123.37,42.21 U14.AN47 ; v1(124.37,42.65) U14.AT44 U14.AU44 U14.AW44 ; v1(117.84,48.15) 118,48.15 U14.BE57 ; U14.G34 v1(129.39,29.09) U14.H34 129.4,29.83 v1(129.32,29.83) 129.37,29.83 U14.K34 129.4,30.6 v1(129.35,30.6) 129.38,30.6 U14.L34 129.41,31.34 v1(129.36,31.35) 129.49,31.49 U14.N34 v1(129.36,32.16) 129.41,32.16 U14.P34 ; v1(137.6,43.14) U14.AR17 138.34,43.13 138.34,43.14 v1(138.36,43.16) ; v1(137.6,43.14) U14.AR19 ; v1(137.6,43.14) U14.AT19 ; v1(200.85,29.11) 200.99,29.25 P1.73 ; U14.AW9 v1(142.55,44.43) ; U14.AN5 144.54,41.4 144.54,41.4 v1(144.54,41.39) 144.54,41.39 144.53,41.39 144.51,41.39 U14.AL5 ; v1(137.98,36.49) 137.63,36.84 U14.AC18 U14.AC20 ; P1.53 203.48,20.85 v1(203.84,21.21) ; U29.9 51.72,18.66 52.18,18.2 v1(52.34,18.2) ; U14.AT5 144.03,43.49 143.86,43.66 ; v1(121.22,41.65) U14.AM50 U14.AL50 ; U14.BD38 v1(127.16,47.87) ; P1.32 v1(195.56,14.55) ; U14.BA49 122.3,45.54 122.68,45.52 122.76,45.6 v1(122.89,45.59) ; U14.BG32 130.2,48.66 v1(130.55,49.01) U14.BH32 ; U27.34 97.26,20 U27.49 ; U14.BF29 132.48,48.57 132.63,48.58 v1(132.61,48.58) ; U14.AD41 126.73,37.08 126.73,37.06 v1(126.74,37.05) ; 93.42,8.94 93.55,10.39 93.73,10.57 93.73,11.68 94.08,12.04 v2(94.47,12.04) ; v1(116.55,36.18) 116.97,36.56 U14.AC59 ; v1(122.54,37.93) 122.61,38 ; 122.61,38 122.72,38.11 U14.AG48 ; 122.61,38 U14.AE47 123.04,37.91 U14.AD47 ; U12.4 64.4,40.54 64.63,40.31 65.04,40.31 ; U7.K9 37.32,59.12 v1(37.45,59.12) ; v1(117.07,26.8) U14.C58 ; U14.BK44 125.33,50.59 U14.BL43 ; U14.W16 138.17,34.33 v1(137.82,34.34) 137.98,34.5 U14.W17 ; U14.G48 122.63,28.86 122.87,28.87 v1(122.96,28.96) ; U14.BC30 v1(131.83,47.11) ; v1(100.51,65.66) 100.29,65.88 U2.4 ; U14.AF28 U14.AG28 v1(132.37,39.45) U14.AJ28 ; U14.K42 125.59,30.23 v1(124.83,30.99) U14.M44 ; U14.M37 128.79,31.01 v1(128.84,31) ; U14.AA28 v1(133.17,35.45) U14.AA26 ; v1(195.7,51.31) 195.54,51.15 P1.146 ; v1(123.19,46.35) 123.19,46.38 U14.BC46 123.43,46.73 123.06,47.1 123.06,47.12 122.81,47.37 v1(122.81,47.37) 122.73,47.37 122.43,47.67 122.43,47.69 U14.BE49 ; U14.E43 125.41,27.99 v1(125.57,28.14) ; v1(125.17,35.45) U14.AA42 ; v1(125.17,35.45) U14.AA44 ; P1.138 195.42,48.75 v1(195.76,49.08) 195.49,49.35 P1.140 ; v1(97.36,67.18) 97.56,67.18 97.61,67.23 ; v1(117,30.99) 116.97,30.95 U14.L60 116.35,30.36 115.99,30.36 U14.K62 ; U14.AD2 146.02,37.37 146.02,37.36 147.85,37.36 149.19,38.71 v1(149.19,39.15) ; U14.AG23 v1(135.56,38.66) ; v1(195.66,57.1) 195.66,56.83 195.38,56.55 P1.164 ; U14.T20 v1(137.33,33.66) U14.T18 ; U14.F66 113.77,28.38 113.27,27.87 v1(113.27,27.41) 113.42,27.57 U14.E66 ; U14.AU62 115.98,44.04 116.41,44.04 116.71,43.74 v1(116.79,43.74) 116.8,43.9 116.74,43.96 116.76,44.31 116.97,44.51 U14.AW59 ; P1.196 195.42,66.15 v1(195.58,65.98) ; U14.E22 135.74,27.99 135.28,27.99 ; v1(120.01,39.67) U14.AH53 U14.AG53 ; U14.AY52 120.11,46.11 v1(120.1,46.11) 120.1,46.23 U14.BB53 ; 195.56,12.75 195.55,12.75 195.55,12.98 195.18,13.35 P1.28 ; 195.56,12.75 P1.26 ; 195.56,12.75 v1(195.63,12.67) ; U14.H37 128.49,29.05 129.08,28.45 v1(129.13,28.45) ; U14.AP42 v1(125.97,42.65) U14.AP41 ; U14.G32 130.78,29.09 130.91,29.09 v1(131.02,29.09) 131.07,29.09 131.51,28.65 131.51,28.22 131.33,28.04 U14.E31 ; U14.BM3 U14.BP3 145.26,52.88 v1(145.25,52.89) ; U14.AF44 v1(124.36,37.85) U14.AD46 123.86,37.35 123.86,36.75 U14.AC46 ; U14.AM55 v1(118.94,41.65) ; v1(200.15,52.2) 200.28,52.2 200.43,52.05 P1.149 ; U14.BA29 v1(132.53,46.35) ; U14.P44 v1(124.83,31.76) ; U20.11 66.44,31.96 U20.7 ; 144.34,36.71 144.34,37.07 U14.AD5 ; 144.34,36.71 U14.AB5 ; 144.34,36.71 144.52,36.9 v1(144.57,36.9) ; U14.M57 118.11,32.15 v1(118.16,32.21) 118.11,32.16 118.11,32.02 117.77,31.68 117.74,31.68 117.63,31.56 U14.M59 ; U14.BD50 121.5,47.11 121.37,47.24 120.76,47.24 v1(120.68,47.17) 120.68,47.24 120.43,47.49 U14.BD53 ; v1(29.33,49.04) 29.33,49.14 U7.A16 ; U14.U14 139.88,33.63 v1(139.52,33.99) ; U14.T31 131.05,33.43 131.05,32.56 131.16,32.44 131.16,32.4 v1(131.18,32.38) ; U14.AY55 U14.AW55 119.03,44.3 v1(118.87,44.15) ; U14.W19 137.25,34.85 v1(137.6,35.2) ; U14.AP36 v1(129.17,41.85) U14.AP34 ; v1(63.13,40.22) 63.4,40.48 63.4,40.92 U12.2 ; U7.J10 35.82,57.61 v1(36.3,57.12) ; U14.W57 118.21,34.61 U14.Y56 118.55,35.66 v1(118.54,35.66) ; v1(137.6,35.2) 137.25,35.55 U14.Y19 136.81,35.96 U14.AB20 ; v1(137.6,35.2) U14.Y17 ; P1.195 200.98,65.85 v1(200.79,66.04) ; U14.AR60 116.97,42.18 v1(116.97,42.17) ; U14.M38 v1(127.4,30.99) ; U14.AL29 132.35,41.03 v1(132.37,41.05) ; U14.BD59 117.02,46.9 117.01,46.9 v1(116.99,46.88) 116.98,46.89 116.98,46.9 116.97,46.91 U14.BD60 ; U14.C33 130.02,27.46 U14.D33 ; v1(37.32,57.12) 37.32,57.14 37.81,57.62 U7.J8 ; U7.T1 45.46,63.98 v1(45.57,63.98) ; 86.01,66.8 86.41,67.2 U3.27 ; 86.01,66.8 U3.26 ; 86.01,66.8 U3.41 ; U14.R12 140.14,32.36 v1(139.85,32.36) ; U14.AC23 v1(135.57,36.25) U14.AC21 ; U2.22 97.61,67.23 ; P1.35 200.21,15.45 200.13,15.37 v1(199.77,15.37) ; U21.41 98.72,32.76 U21.4 ; U2.1 98.79,65.75 v1(98.89,65.65) 99.29,66.04 U2.2 ; U14.AW25 v1(134.52,45.2) U14.AW23 ; U14.AL38 v1(127.57,41.05) ; U14.AT53 120.46,43.26 v1(120.8,43.62) ; U14.T34 129.39,32.9 ; 129.39,32.9 129.02,33.29 U14.T36 U14.V36 ; 129.39,32.9 U14.P34 ; U14.V32 v1(130.77,34.65) U14.W32 ; v1(144.51,28.72) 144.51,28.64 144.17,28.3 U14.F5 ; v1(189.2,69.2) 189.17,69.2 188.67,69.7 P1.206 186.22,69.76 187.02,70.56 189.13,70.56 v1(189.43,70.26) ; P1.64 195.42,24.15 195.72,23.85 v1(195.76,23.85) ; U14.AG10 141.47,39.12 141.42,39.17 v1(141.41,39.17) U14.AH11 ; U14.BD45 124.33,47.49 124.82,47.98 v1(124.82,48.21) 125.19,48.21 U14.BE42 ; C97.2 188.78,34.42 187.61,34.42 v1(187.05,34.98) ; U14.AM12 v1(141.02,41.16) ; v1(203.84,7.49) 203.71,7.49 203.55,7.65 P1.9 ; U14.H54 U14.H52 120.52,29.09 120.69,28.91 v1(120.89,28.74) ; v1(144.45,31.57) 144.42,31.57 144.22,31.36 U14.M5 ; U7.T16 29.76,64.62 v1(29.36,65.02) ; U14.K50 v1(121.44,30.61) ; U14.AA29 132.31,35.51 v1(132.37,35.45) ; 143.86,43.66 v1(143.84,43.68) 143.84,43.98 U14.AV5 ; 143.86,43.66 U14.AU4 ; v1(128.1,32.52) U14.R38 ; P1.14 v1(195.64,9.15) ; C56.2 188.64,46.28 187.68,46.28 186.44,47.52 186.44,47.8 v1(186.33,47.9) ; U27.44 95.26,19.2 U27.49 ; v1(146.41,44.38) 146.37,44.42 U14.AV2 U14.AV4 ; U14.AJ32 U14.AG34 v1(129.17,39.45) ; v1(128.41,28.43) U14.H38 ; 137.88,41.88 137.88,41.89 v1(137.9,41.91) ; 137.88,41.88 137.88,41.79 U14.AM18 ; 137.88,41.88 137.84,41.03 U14.AL18 U14.AL20 ; v1(122.89,45.59) 123.04,45.44 123.04,44.78 U14.AW47 ; v1(122.89,45.59) 122.76,45.46 122.76,45.38 U14.AW49 ; U7.B15 v1(31.25,51.06) ; P1.44 195.4,18.15 195.66,18.4 v1(195.66,18.44) 195.34,18.75 P1.46 ; U14.BF4 144.56,48.11 U14.BF3 ; U14.T52 120.9,33.41 120.9,34.18 v1(120.81,34.26) U14.W53 121.13,35.31 U14.Y51 ; v1(203.84,23.62) 203.46,23.25 P1.61 ; U12.1 62.9,40.87 62.65,40.61 v1(62.15,40.61) ; U7.B2 v1(44.32,50.12) ; U14.AP32 130.75,42.63 v1(130.77,42.65) U14.AP31 ; U14.AW32 v1(130.55,45.2) U14.AW31 U14.AW30 ; v1(137.97,40.39) 138.36,40.77 U14.AL17 ; v1(38.33,57.12) 38.33,57.12 U7.H7 ; v1(130.77,36.25) U14.AC32 ; v1(130.77,36.25) U14.AA31 ; v1(130.77,36.25) U14.AC31 ; U7.G8 v1(38.32,55.12) 38.82,55.62 U7.G7 ; P1.157 201.26,54.45 201.12,54.3 v1(200.92,54.3) 201.38,53.85 P1.155 ; U10.2 102.49,50.21 102.24,50.47 100.57,50.47 R35.2 ; U14.E21 136.46,27.81 v1(136.81,27.46) 137.16,27.82 U14.E19 ; 98.06,16.4 U27.24 100.36,15.6 v1(100.51,15.75) ; 98.06,16.4 U27.25 ; 98.06,16.4 U27.49 ; P1.38 195.38,16.35 195.63,16.1 v1(195.63,16.05) ; U14.AG25 134,38.68 134,38.68 v1(133.96,38.64) ; 94.06,16.8 U27.11 ; 94.06,16.8 93.66,16.4 U27.12 ; 94.06,16.8 U27.49 ; U14.BM1 U14.BP1 146.08,52.65 146.36,52.94 v1(146.53,52.94) ; U14.M52 120.23,31.56 120.22,31.62 v1(120.13,31.71) 120.05,31.63 119.99,31.63 U14.M54 ; v1(107.19,34.65) 107.19,34.25 106.95,34.01 106.95,33.76 R85.1 ; U14.AA5 144.01,35.84 U14.AA3 ; U28.6 79.17,16.74 ; U14.B26 134.07,26.3 U14.A24 ; U14.AD34 U14.AC34 v1(129.17,36.25) U14.AC36 ; U14.AJ44 v1(124.37,39.45) ; v1(124.37,39.45) U14.AG44 ; v1(124.37,39.45) U14.AJ46 123.73,40.09 123.34,40.09 U14.AJ47 ; P1.190 v1(195.67,64.35) ; U7.G5 v1(40.34,55.15) ; 135.28,27.99 U14.E23 ; 135.28,27.99 135.28,28.21 v1(134.96,28.53) ; U14.AT16 138.38,43.16 138.37,43.16 138.36,43.16 v1(138.36,43.16) ; U14.BE66 114.16,47.51 U14.BD65 ; v1(40.27,64.17) U7.T6 ; U14.H1 147.43,29.19 v1(147.7,29.46) ; P1.52 195.4,20.55 v1(195.61,20.35) ; v1(125.57,28.14) 125.57,28.15 125.6,28.11 125.6,28.08 125.6,28.07 125.69,27.99 U14.E41 ; v1(125.57,28.14) U14.D42 ; v1(131.09,50.63) 131.41,50.95 U14.BL30 ; v1(131.09,50.63) 131.08,50.62 U14.BK31 ; v1(131.09,50.63) 131.23,50.63 131.61,50.26 U14.BK30 ; v1(141.03,37.18) 140.99,37.18 U14.AC12 ; U14.P34 U14.P32 ; C99.2 188.66,32.97 187.22,32.97 v1(186.77,33.43) ; U14.Y48 U14.W48 123.13,34.5 123.32,34.5 123.28,34.46 v1(123.28,34.43) ; U14.BK1 146.54,50.54 146.63,50.63 ; U14.AH17 137.99,39.52 138.34,39.17 v1(138.35,39.17) 138.36,39.16 138.37,39.16 138.71,38.82 U14.AG16 ; U14.BC5 144.05,47.63 U14.BE5 143.6,48.05 v1(143.6,48.22) ; U7.K8 37.34,58.14 v1(37.32,58.14) ; v1(146.91,27.09) 146.55,27.09 U14.E1 ; v1(126.81,29.85) 126.5,29.51 U14.H41 ; U14.Y8 v1(142.19,35.91) ; C93.2 66.84,35.65 ; C93.2 67.35,35.98 67.16,36.17 ; C93.2 67.35,35.32 67.18,35.15 ; N18.2 92.75,12.25 v2(92.96,12.04) ; P1.158 192.78,54.75 192.51,54.47 v1(192.51,54.45) ; v1(138.36,43.16) 138.35,43.16 138.34,43.16 U14.AT17 ; U14.AA36 v1(128.37,35.45) U14.W36 ; v1(129.15,45.97) U14.BA34 U14.AW34 ; U14.BG1 146.96,48.91 147.05,49.01 147.06,49.01 147.47,49.41 147.47,49.43 v1(147.83,49.78) ; U14.BK58 117.72,50.28 118.24,50.28 U14.BK57 118.31,50.26 118.83,49.73 v1(119.08,49.73) 118.97,49.84 U14.BK56 ; v1(126.81,29.09) 126.5,28.75 U14.G41 ; v1(195.55,7.42) 195.4,7.42 195.34,7.35 P1.8 ; 60.15,33.93 59.84,34.24 v1(59.84,34.32) ; 30.3,30.99 31.34,32.03 v2(31.34,32.04) ; U14.BH41 126.22,49.76 U14.BK42 ; U7.A1 v1(45.32,49.12) ; 137.64,25.22 v1(137.63,25.21) ; U14.T5 144.58,33.43 ; U14.AW19 v1(137.79,45.2) ; v1(186.56,38.94) 186.65,38.94 186.88,39.18 188.9,39.18 189.61,38.46 C88.2 ; U14.AC28 v1(132.37,36.25) U14.AC29 ; U14.AD9 142.18,37.54 142.52,37.88 142.52,37.98 142.56,38.02 v1(142.56,38.14) ; U14.BB57 118.18,46.53 v1(118.53,46.18) 118.88,46.53 U14.BB56 ; U14.P37 128.45,32.13 128.82,31.76 v1(128.86,31.76) ; U14.AD52 v1(120.43,37.65) ; P1.152 195.74,52.95 v1(196.64,53.08) ; U14.B41 126.04,26.53 v1(126.04,26.68) 126.04,27.1 U14.D41 ; U14.AL14 139.88,40.59 v1(140.23,40.23) ; U14.AP26 v1(133.97,42.65) U14.AP25 ; U14.AG57 v1(118.53,38.23) ; v1(114.96,5.59) 114.76,5.79 114.76,6.48 114.94,6.66 U31.11 115.57,6.66 115.82,6.4 v1(115.82,5.69) ; v1(203.84,22.86) 203.63,22.65 P1.59 ; U14.T56 v1(118.15,33.67) ; v1(126.91,32.8) 126.89,32.83 126.89,32.86 U14.T41 U14.T42 ; U14.M46 v1(123.41,30.97) ; U14.H46 123.78,28.9 123.3,28.37 123.32,28.35 v1(123.32,28.27) ; U14.AY12 v1(140.28,45.84) ; U14.BM5 U14.BP5 144.45,52.57 v1(144.21,52.82) ; U14.BK8 v1(143.37,49.92) ; U14.BG37 v1(128.56,48.63) ; U14.AP39 v1(127.57,42.65) U14.AP38 ; U14.AW50 U14.AW52 v1(120.42,44.15) ; v1(186.17,40.91) 186.17,40.89 186.8,40.26 188.07,40.26 188.07,40.26 188.49,40.26 188.49,40.26 189.22,40.26 C77.2 ; U7.K7 v1(38.34,58.14) ; v1(119.05,49.05) 119.08,49.01 U14.BG54 ; v1(116.51,40.13) 116.6,40.23 116.64,40.23 116.7,40.29 116.97,40.54 U14.AL59 U14.AM59 ; v1(117.3,52.79) 117.3,52.73 117.11,52.53 U14.BP59 ; U7.L10 35.78,59.62 v1(35.31,60.1) ; P1.47 203.58,19.05 203.84,19.3 v1(203.84,19.43) ; v1(118.86,36.21) 118.89,36.24 118.89,36.24 118.93,36.28 118.95,36.28 U14.AC55 ; v1(116.51,52.81) 116.29,52.6 U14.BP61 ; P1.137 203.77,48.45 v1(204.09,48.13) ; U14.U9 142.17,33.58 v1(141.81,33.93) ; v1(124.86,28.67) U14.H44 ; U14.AG26 v1(133.97,39.45) ; P1.20 v1(195.67,10.95) ; P1.70 195.5,25.95 v1(195.71,26.16) ; U14.AD20 U14.AD18 137.94,37.88 v1(137.95,37.89) 137.97,37.88 138.02,37.88 U14.AD17 ; P1.3 v1(203.84,5.85) ; U14.W39 v1(127.57,34.65) ; U7.G10 v1(36.32,56.12) U7.H9 ; U14.N48 122.78,31.44 v1(122.87,31.34) 122.86,31.33 122.8,31.33 U14.L48 ; v1(133.16,42.66) 133.16,42.64 U14.AP28 ; v1(134.94,33.04) 135.07,33.16 135.07,33.45 U14.T23 U14.T21 ; U14.AC50 121.18,36.23 v1(121.18,36.23) ; U14.BA17 v1(138.49,45.97) U14.BB17 ; U14.AK5 144.66,40.37 v1(144.69,40.4) 144.75,40.34 U14.AK3 ; U7.G9 v1(36.32,55.12) ; U14.AB1 146.89,36.09 v1(146.93,36.13) ; U14.AD56 v1(118.15,37.65) ; v1(121.56,42.16) 121.62,42.21 U14.AR50 ; U14.AM20 v1(136.37,41.05) U14.AM21 ; U14.AY38 127.09,45.66 127.09,45.69 v1(127.08,45.7) ; v1(118.8,27.41) 118.95,27.41 119.21,27.15 U14.D55 ; U14.AL55 v1(118.91,40.22) ; P1.170 195.83,58.35 v1(196.02,58.54) 195.61,58.95 P1.172 ; U14.AR56 U14.AT57 118.47,43.61 v1(118.52,43.61) ; v1(126.57,46.73) U14.BD41 ; U14.AM23 v1(135.57,41.85) U14.AP23 ; v1(203.84,8.51) 203.58,8.25 P1.11 ; U7.K11 34.85,58.62 v1(35.34,58.14) U7.K10 ; P1.78 195.39,30.75 v1(195.81,30.32) 195.64,30.15 P1.76 ; U14.R52 v1(120.43,32.27) ; U14.BH34 v1(129.15,49.01) ; U7.R15 v1(31.35,63.09) ; P1.79 v1(203.85,31.05) ; U14.P29 v1(132.77,31.76) ; U7.R2 v1(44.34,63.11) ; U14.AR8 v1(142.17,42.44) ; U14.Y13 v1(139.9,35.91) ; U14.AG41 v1(125.97,39.45) ; U14.E25 134.04,27.97 U14.E27 133.35,27.56 v1(133.21,27.41) 133.37,27.26 U14.D26 134.06,27.41 U14.E25
  TOP w0.305: R86.1 59.13,33.84 59.92,33.84 N13.2 60.05,33.83 60.35,34.14 v1(60.66,34.14) ; U29.5 51.09,13.33 51.09,12.39 51.13,12.35 v1(51.13,12.27) ; 72.37,25.47 71.89,25.95 U25.9
  TOP w0.381: U6.2 49.76,57.3 v1(49.99,57.53) ; v1(206.38,68.33) 206.12,68.33 205.8,68.01 C14.2 ; R129.2 145.73,5.27 v1(145.92,5.46) ; C72.2 188.43,42.15 v1(188.42,42.14) ; v1(60.33,45.59) 60.07,45.59 59.88,45.78 C58.2 C54.2 C50.2 ; P1.163 203.46,56.25 v1(203.84,55.88) ; v2(125.12,18.34) 125.41,18.05 C137.2 ; v1(78.11,65.15) 78.12,65.14 N3.2 79.94,65.14 R11.1 C19.2 ; C129.2 129.16,18.67 v1(130.05,19.56) ; v1(167.03,3.58) 166.93,3.58 166.78,3.43 164.78,3.43 C167.2 ; C9.2 131.93,72.28 v1(131.8,72.4) ; v1(203.96,56.9) 203.96,57.67 203.58,58.05 P1.169 ; P1.189 201.26,64.05 201.21,63.99 200.77,63.99 v1(200.53,63.75) 200.84,63.45 P1.187 ; R121.2 76.71,18.73 77.1,18.35 77.38,18.35 v1(77.64,18.08) ; U30.6 124.15,14.89 124.71,14.33 v1(124.71,13.64) ; v1(164.08,4.67) 163.87,4.89 R130.2 ; v1(78.61,62.47) 79.31,62.47 79.92,63.08 C25.2 ; C166.2 147.38,3.37 U33.2 v1(148.46,3.43) ; C102.2 57.7,33.94 v1(57.45,34.19) ; C168.2 154.8,1.84 v1(154.56,1.6) ; v1(90.32,23.5) 90.43,23.6 X3.2 ; v1(203.96,63.25) 203.96,61.85 203.76,61.65 P1.181 ; C65.2 188.47,44.55 v1(188.42,44.5) ; v1(129.92,18.16) 129.29,17.53 C138.2 ; U32.2 142.82,5.86 142.7,5.99 142.7,6.34 C162.2 142.06,6.4 v1(141.86,6.6) ; v1(99.55,38.62) 98.93,38 R71.2 ; v2(114.45,17.65) 115.06,18.26 C133.2 ; U34.2 161.16,5.18 161.04,5.3 161.04,5.46 160.97,5.52 C163.2 v1(160.27,5.71) ; R135.2 150.94,1.84 v1(150.62,1.52) ; 65.71,44.5 U12.13 ; v1(200.79,59.94) 200.88,59.85 P1.175 ; v1(97.94,8.18) 98.55,7.57 98.55,6.14 98.42,6.01 S1.A1 ; v1(65.76,44.12) 65.74,43.26 65.81,43.18 ; C128.2 115.74,19.27 115,20 114.46,20 v2(114.43,19.96)
  TOP w0.508: C84.2 v1(21.08,37.72) ; v1(54.97,6.86) 54.37,6.26 S1.A43 ; v1(84.79,8.51) 84.79,7.65 85.37,7.06 S1.A12 ; v1(71.25,6.6) 70.59,6.6 70.37,6.38 S1.A27 ; C51.2 v1(7.11,48.39) ; v1(73.94,17.34) 73.53,17.74 R123.1 ; U24.4 106.97,25.08 v1(106.59,24.71) ; C5.2 C11.2 v2(70.23,69.34) ; v1(32.16,41.07) 32.74,41.66 U16.4 ; U38.11 126.17,67.47 R10.2 ; v1(13.18,45.19) 13.16,45.16 C66.1 ; C46.2 v1(7.11,49.53) ; v2(30.18,32.05) 30.3,31.93 30.3,31 ; v1(57.56,6.6) 57.37,6.42 S1.A40 ; C39.2 v1(14.73,55.63) ; v1(68.71,6.6) 69.06,6.6 69.34,6.32 69.34,3.78 S1.A28 ; S1.A56 v1(41.37,6.5) ; C141.2 104.9,17.4 v1(105.66,18.16) ; v1(60.37,6.68) 60.44,6.6 61.04,6.6 61.37,6.27 S1.A36 ; v2(123.93,71.37) 123.93,71.3 124.21,71.02 C8.2 ; S1.A68 29.37,6.47 28.91,6.93 v1(28.91,7.04) ; S1.A71 26.37,6.17 v1(26.9,6.71) ; v1(104.5,42.66) C70.2 ; v2(84.05,17.98) 83.89,17.82 C130.1 ; U1.3 47.31,69.03 v1(47.37,69.09) ; v1(80.64,6.6) 80.75,6.71 80.9,6.71 ; v2(118.52,71.63) 118.75,71.4 R1.2 ; S1.A20 77.37,6.35 77.11,6.6 v1(76.58,6.6) ; v1(75.06,6.6) 74.72,6.6 74.37,6.25 S1.A23 ; v1(107.87,26.97) 108.01,26.84 108.67,26.84 R106.2 ; C69.2 v1(16.38,44.58) ; v1(100.53,49.78) R35.2 ; U5.4 21.46,56.43 21.97,55.92 21.98,55.92 22.1,55.8 v1(22.15,55.8) ; R77.1 v1(10.41,37.47) ; v1(89.08,18.69) 89.08,19.28 89.42,19.62 R119.2 89.88,19.64 C125.2 ; C156.2 106.68,9.98 v1(106.3,9.6) ; v1(41.66,67.69) 41.91,67.94 J3.3 ; v1(25.79,48.45) 25.36,48.89 U8.4 ; v1(18.8,6.96) 18.37,6.53 S1.A79 ; R137.2 v1(168.72,1.46) ; U11.3 40.31,42.21 40.82,41.71 v1(40.85,41.71) ; C78.2 105.06,40.62 104.74,40.3 v1(104.6,40.3) ; v1(50.93,9.14) 50.93,9.27 51.28,9.63 C155.1 ; C95.2 58.9,36.03 v1(58.9,36.7) 58.74,36.87 C89.2 ; C83.2 v1(20.07,37.72) ; v1(72.77,6.6) 73.04,6.6 73.37,6.27 S1.A24 ; 125.22,71.12 C7.2 125.79,70.55 ; C27.2 50.92,61.73 v1(50.88,61.77) ; C142.2 105.92,17.25 v2(106.47,17.8) ; C149.2 115.46,14.83 C148.1 ; v1(17.17,7.01) 17.37,6.81 S1.A80 ; R55.1 10.6,43.12 v1(10.67,43.18) ; v1(70.59,23.69) 72.66,25.77 U25.8 ; S1.A39 58.37,6.17 58.88,6.68 v1(59.21,6.68) ; C154.1 124.22,11.24 v2(124.38,11.4) ; R76.2 105.65,36.67 105.41,36.91 v1(105.41,36.98) ; v1(48.37,6.53) 49.05,6.53 49.37,6.21 S1.A48 ; v1(77.64,18.08) 77.35,17.79 C139.2 78.09,17.13 ; v1(107.19,34.65) 107.22,34.65 107.24,34.67 C98.2 ; J2.3 38.35,69.6 v1(38.23,69.72) ; S1.A75 22.37,6.47 22.81,6.91 v1(22.81,7.09) ; C134.2 71.04,17.35 v1(71.37,17.02) ; R99.2 108.33,28.71 v1(108.18,28.86) ; S1.A15 82.37,6.41 82.07,6.71 80.9,6.71 ; C28.2 55.13,60.01 55.19,60.07 ; 30.3,31 C114.2 30.25,30.33 28.7,31.88 ; 30.3,31 v2(31.34,32.04) ; U13.3 v1(37.69,40.56) ; v1(107.06,42.44) 107.34,42.17 C71.2 ; C17.2 v1(69.84,71.16) ; v1(30.89,6.88) 30.37,6.36 S1.A67 ; v1(70.66,16.64) 70.48,16.81 C136.1 ; v1(24.43,67.49) 24.64,67.69 C13.2 ; C126.1 v2(77.35,21.49) ; R124.2 78.91,13.24 v1(79.04,13.11) ; X3.4 v1(88.48,23.41) ; C30.2 v1(11.58,57.43) ; 55.19,60.07 55.75,60.07 56.01,59.82 v1(56.01,59.72) ; 55.19,60.07 55.19,58.83 55.88,58.14 55.88,56.26 57.02,55.12 JP3.2 ; v1(9.53,44.83) 9.27,44.58 C64.2 ; C96.1 66.37,35.43 ; C96.1 65.53,36.12 ; C96.1 65.53,34.72 ; 80.9,6.71 81.37,6.24 S1.A16 ; v1(104.5,38.05) 104.42,38.05 104.39,38.07 104.24,38.07 103.81,38.51 R64.2 ; C42.2 v1(7.11,50.8) ; v1(99.55,38.62) 99.86,38.31 C91.2 ; v1(20.83,6.91) 21.37,6.37 S1.A76 ; S1.A55 v1(42.37,6.55) ; v1(64.71,6.64) 64.73,6.62 64.97,6.62 65.35,6.24 S1.A32 ; C80.2 52.39,39.94 v1(52.32,40.01) 52.13,39.81 C81.2 ; U29.8 52.5,18.36 v1(52.34,18.2) ; S1.A51 v1(46.37,6.52) ; S1.A60 v1(37.37,6.53) ; v1(79.12,6.6) 78.88,6.6 78.37,6.1 S1.A19 ; v1(51.13,6.63) 50.88,6.63 50.37,6.12 S1.A47 ; v2(84.07,16.23) 83.93,16.37 C143.2 ; C131.2 v2(62.23,17.27) ; R25.1 v1(7.24,56.64) ; v1(88.54,27.03) C116.2 ; C135.2 46.61,17.12 ; 87.88,29.08 87.88,28.83 ; U9.4 v1(21.46,50.04) ; C2.2 v1(204.24,71.6) ; S1.A44 53.37,6.23 v1(53.77,6.63) ; C68.2 v1(15.37,44.58) ; J1.3 34.67,69.27 34.22,69.72 v1(34.16,69.72) ; R126.1 94.61,12.19 v2(94.47,12.04) ; v1(32.89,6.81) 33.37,6.33 S1.A64 ; v1(63.04,6.6) 62.88,6.6 62.37,6.1 S1.A35 ; S1.A59 v1(38.37,6.54) ; S1.A72 25.37,6.41 v1(24.79,6.99) ; S1.A52 v1(45.37,6.51) ; C169.2 v1(172.91,1.46) ; v1(67.18,6.6) 66.52,6.6 66.27,6.35 66.27,3.85 S1.A31 ; C94.2 v1(58.04,36.58) ; C12.2 v2(74.68,69.34) ; J4.3 v1(26.67,59.05) ; S1.A63 v1(34.37,6.71) ; C92.2 v1(9.4,37.47) ; C25.2 C26.2 ; U15.4 v1(26.9,41.12) ; 25.35,30.4 C115.2
  TOP w0.762: JP3.10 57.79,65.19 56.12,65.97 v1(56.03,66.22) ; v2(117.55,11.76) 117.55,11.91 118.34,12.7 C153.1 ; C53.2 14.48,47.5 v1(14.86,47.12) ; C76.2 v2(8,40.81) ; v1(101.57,65.61) 101.57,65.2 100.81,64.44 C24.2 ; S1.A4 95.4,6.75 v2(95.42,6.77) ; 9.4,47.29 C57.2 ; 9.4,47.29 v2(8.74,47.96) ; 9.4,47.29 9.4,47.4 v2(10.01,48.01) ; v2(20.9,69.29) C4.2 21.13,70.76 v2(22.17,69.72) ; X1.2 v1(47.98,64.92) ; v2(21.79,64.19) R14.1 ; v2(22.53,67.49) 22.53,67.03 21.72,66.22 C18.2 v2(21.29,67.54) ; v2(26.8,65.08) 25.4,65.08 C21.2 ; v2(48.16,46.94) 48.77,46.33 C55.2 ; v2(117.02,14.02) 117.7,14.02 118.14,14.45 C144.2 118.11,13.61 v2(117.96,13.61) ; v2(124.6,22.76) 124.48,22.64 124.48,22.43 C124.1 ; v2(110.19,2.76) 110.23,2.71 111.61,2.71 111.74,2.84 113.42,2.84 C165.2 ; v2(47.29,46.35) C61.2
  TOP w1.016: C145.2 C146.2
  L2_GND w0.381: 15.9,7.01 15.74,7.17 v1(15.74,7.66)
  L3_SIG w0.254: v1(124.37,42.65) 124.5,42.78 124.5,43.62 123.7,44.42 123.7,45.85 v1(123.19,46.35)
  BOTTOM w0.178: v1(143.6,48.22) 144.03,47.78 C279.2
  BOTTOM w0.203: R227.2 121.02,41.44 v1(121.22,41.65) ; v1(138.92,49.82) 138.83,49.82 138.58,50.07 138.58,50.61 C256.2 ; v1(124.37,39.45) 124.38,39.44 124.38,38.84 C331.2
  BOTTOM w0.254: v1(107.31,45.54) 107.41,45.45 P2.25 ; P4.140 199.19,49.35 199.61,48.93 v1(199.61,48.67) 199.52,48.75 P4.138 ; R275.2 142.21,31.93 142.46,32.18 v1(142.7,32.18) ; P4.29 191.24,13.65 191.49,13.9 v1(191.49,14.05) ; C318.2 129.58,39.86 v1(129.17,39.45) 129.55,39.06 C329.2 ; C346.2 126.02,36.2 126.74,36.92 v1(126.74,37.05) ; P4.175 191.34,59.85 191.41,59.79 v1(191.61,59.79) ; v1(178.99,70.86) 179.29,70.56 180.29,70.56 181.15,69.7 ; v1(188.32,17.54) 188.32,17.54 188.62,17.25 P4.41 ; P4.155 191.08,53.85 v1(191.68,54.45) P4.157 ; C425.2 133.51,27.11 v1(133.21,27.41) ; v1(121.18,36.23) 121.93,36.98 C344.2 ; N36.1 123.32,47.69 123.32,46.74 123.19,46.61 v1(123.19,46.35) ; P4.190 199.56,64.35 v1(199.64,64.26) ; 112.98,36.35 114.33,36.35 114.97,37 R245.1 ; 112.98,36.35 113.3,36.66 N41.2 ; 112.98,36.35 v1(112.67,36.04) ; v1(140.29,27.42) 140.7,27.84 C423.2 140.82,28.23 C415.2 ; C377.2 127.66,32.95 v1(128.1,32.52) ; v1(107.21,36.6) 107.56,36.95 P2.59 ; P4.164 199.51,56.55 v1(199.7,56.36) ; P2.13 107.7,48.45 107.44,48.7 v1(107.44,49.18) ; v1(134.77,35.45) 134.66,35.45 C350.2 C343.2 ; P4.32 199.47,14.55 199.47,14.55 v1(199.74,14.55) ; P4.78 199.53,30.75 199.71,30.57 199.71,30.21 199.65,30.15 ; v1(115.38,40.09) 115.35,40.06 114.95,40.06 114.69,39.8 R237.1 ; R295.1 120.96,27.95 v1(121.07,28.06) ; v1(123.75,55.44) 123.75,55.47 123.63,55.59 C233.2 ; P4.79 v1(191.41,31.05) ; R238.2 122.04,38.44 v1(122.54,37.93) ; v1(120.42,44.15) 120.36,44.2 R221.2 ; R346.1 111.86,10.21 v1(111.56,10.52) ; C381.2 126.36,33.35 v1(126.91,32.8) 126.57,32.8 C393.2 ; P4.59 191.18,22.65 v1(191.51,22.74) 191.01,23.25 P4.61 ; P4.189 v1(191.48,64.05) 190.88,63.45 P4.187 ; P4.53 190.95,20.85 v1(192.33,22.23) ; P4.195 191.3,65.85 v1(191.44,65.99) ; P4.172 199.37,58.95 v1(199.65,58.67) 199.33,58.35 P4.170 ; v1(112.75,39.09) 112.76,39.1 C323.2 ; v1(191.83,56.68) 191.83,56.62 191.46,56.25 P4.163 ; v1(144.19,58.41) 143.55,57.77 C226.2 ; v1(134.96,28.53) 134.96,28.74 134.71,28.99 C416.2 ; P4.38 v1(199.68,16.35) ; v1(187.35,7.7) 187.4,7.65 P4.9 ; C410.2 127.48,29.35 v1(128.41,28.43) ; C273.2 139.14,49.6 v1(138.92,49.82) ; v1(104.5,42.66) 104.48,42.66 104.26,42.45 P2.38 ; v1(116.62,24.92) N51.1 ; P4.58 199.25,22.35 v1(199.56,22.04) ; v1(132.37,39.45) 132.45,39.37 C332.2 132.61,38.85 C337.2 ; v1(191.7,58.8) 191.67,58.77 191.67,58.23 191.49,58.05 P4.169 ; C308.2 125.92,42.6 v1(125.97,42.65) ; C359.2 125.35,35.26 v1(125.17,35.45) ; v1(125.97,39.45) 126.63,38.79 C330.2 ; P4.143 191.34,50.25 191.6,50 v1(191.6,49.95) 191.6,48.72 191.33,48.45 P4.137 ; P4.196 v1(199.64,66.15) ; v1(107.34,49.99) 107.39,49.99 107.43,49.95 P2.7 ; P4.47 191.01,19.05 191.31,19.36 191.31,20.32 v1(191.54,20.55) ; P4.28 199.4,13.35 v1(199.67,13.08) 199.34,12.75 P4.26 ; v1(107.38,47.16) 107.58,46.95 P2.19 ; R226.2 119.24,40.96 119.24,41.34 v1(118.94,41.65) ; v1(145.25,52.89) 145.42,52.73 C252.2 ; C457.2 v1(138,20.39) ; v1(199.64,9.07) 199.56,9.15 P4.14 ; v1(107.39,51.59) 107.49,51.49 109.17,51.49 P2.1 ; R188.2 145.92,57.42 v1(144.93,58.41) ; P4.2 v1(199.72,5.55) ; R279.1 54.97,30.61 v1(54.95,30.62) ; P2.31 110.76,43.95 v1(110.99,43.73) ; C384.2 111.64,33.81 113.51,33.81 v1(113.56,33.76) ; P4.149 191.48,52.05 v1(191.66,52.23) ; v1(199.67,29.29) 199.8,29.42 199.8,29.99 199.65,30.15 ; P2.26 101.1,45.45 100.84,45.19 v1(100.84,43.74) 101.05,43.95 P2.32 ; v1(128.37,35.45) 128.38,35.47 C349.2 128.38,37.11 C342.2 ; v1(199.75,20.14) 199.34,20.55 P4.52 ; 199.65,30.15 P4.76 ; P4.158 199.62,54.75 v1(199.8,54.57) ; 112.61,41.97 112.67,41.91 112.67,41.31 C312.2 ; 112.61,41.97 v1(112.61,42.21) ; 112.61,41.97 112.38,41.75 111.47,41.75 110.77,42.45 P2.37 107.07,42.45 v1(107.06,42.44) ; v1(121.56,42.16) 121.54,42.19 121.54,42.21 121.45,42.3 R224.2 ; P4.35 191.23,15.45 v1(191.39,15.29) ; P4.8 v1(199.75,7.35) ; v1(110.72,4.6) 110.95,4.83 N58.2 ; C178.2 101.43,69.76 v1(101.68,69.52) ; P4.73 v1(192.08,29.25) ; v1(117,30.99) 117.25,30.99 R278.1 ; P4.23 191.02,11.85 191.52,12.34 v1(191.52,12.7) ; v1(178.08,3.23) 178.95,4.1 P4.205 181,3.07 v1(179.12,3.07) ; v1(199.57,51.34) 199.38,51.15 P4.146 ; P4.70 199.33,25.95 199.64,26.26 v1(199.64,26.51) ; 181.15,69.7 179.21,69.7 v1(178.73,69.22) ; 181.15,69.7 P4.206 ; C411.2 126.39,29.09 v1(126.81,29.09) ; v1(116.34,32.29) 116.55,32.08 R271.1 ; v1(199.76,53.32) 199.39,52.95 P4.152 ; P4.44 199.41,18.15 199.66,18.4 v1(199.66,18.5) 199.41,18.75 P4.46 ; C227.2 134.24,56.66 R189.2 v1(134.28,55.87) ; C310.2 130.29,42.17 130.75,42.63 v1(130.77,42.65) ; C382.2 137.2,33.8 v1(137.33,33.66) ; v1(127.57,42.65) 127.56,42.66 C307.2 ; U38.4 127.19,66.45 ; C390.2 139.75,32.46 v1(139.85,32.36) ; v1(104.55,37.26) 104.24,36.95 P2.60 ; v1(104.49,39.64) 104.3,39.45 P2.50 ; v1(135.9,52.94) 136.04,52.81 C250.2 ; C320.2 123.51,40.15 123.73,39.92 123.77,39.92 124.25,39.45 v1(124.37,39.45) ; P2.14 104.46,48.45 v1(104.5,48.49) ; P4.181 v1(191.49,61.65) ; P4.11 191.22,8.25 191.41,8.44 v1(191.41,8.94) 191.41,9.73 191.09,10.05 P4.17 ; v1(100.74,51.97) 100.92,51.97 100.97,51.92 101.12,51.92 101.59,51.45 P2.2 ; P2.49 107.57,39.45 107.47,39.34 v1(107.24,39.34) ; v1(191.85,25.86) 191.04,25.05 P4.67 ; C231.2 138.21,56.13 138.21,55.58 v1(138.44,55.36) 138.49,55.41 C232.2 ; C275.2 141.96,48.74 143.07,48.74 v1(143.6,48.22) ; C251.2 144.5,52.52 v1(144.21,52.82) ; P4.64 v1(199.64,24.15) ; U38.8 U38.11 ; P2.8 100.7,49.95 v1(100.53,49.78) ; P4.3 191.16,5.85 191.41,5.6 v1(191.41,4.67) ; P2.20 104.28,46.95 104.37,46.86 v1(104.5,46.86) ; N45.2 66.75,31.67 v1(66.55,31.47) ; v1(127.57,41.05) 127.67,40.94 C319.2 ; P4.184 v1(199.67,62.55) ; P4.20 v1(199.59,10.95) ; v1(124.37,42.65) 124.24,42.77 C299.2 ; U37.3 v1(136.45,65.48)
  BOTTOM w0.305: v1(51.13,12.27) 51.14,12.28 51.14,12.33 51.37,12.56 C483.2 ; v1(128.54,50.65) 128.56,50.63 C260.2 ; v1(123.41,30.97) 124.08,30.97 C397.2 ; v1(146.74,31.78) 146.91,31.78 147.46,31.23 C401.2 ; v1(123.28,34.43) 123.62,34.77 C354.2 ; N56.1 v1(109.58,6.24) ; R294.1 117.34,28.19 v1(116.64,28.89) ; C317.2 136.64,40.78 v1(136.37,41.05) ; C287.2 132.8,45.14 133.25,44.69 v1(133.25,44.3) ; R228.2 113.84,40.69 113.54,40.39 v1(113.18,40.39) ; C288.2 134.43,45.12 v1(134.52,45.2) 134.75,44.97 135.43,44.97 C294.2 ; C327.1 120.05,39.63 v1(120.01,39.67) ; C290.2 127.51,45.27 v1(127.08,45.7) ; v1(130.77,36.25) 130.72,36.2 C353.2 ; C306.2 135.46,41.74 v1(135.57,41.85) 135.68,41.74 C305.2 C304.2 ; C345.2 135.54,36.23 v1(135.57,36.25) ; C303.2 129.08,41.77 v1(129.17,41.85) ; v1(132.77,31.76) 132.77,32.5 133.17,32.9 C380.2 ; 127.19,66.45 U38.11 ; v1(129.15,45.97) 129.37,45.74 C286.2 129.37,44.26 C296.2 ; v1(128.86,31.76) 128.86,31.77 128.6,32.03 C375.2 ; C289.2 130.63,45.12 v1(130.55,45.2) ; C376.2 124.48,33.97 v1(125.17,34.65) ; v1(129.36,32.16) 129.47,32.26 C379.2 C378.2 130.64,32.93 v1(131.18,32.38) 131.42,32.63 C383.2
  BOTTOM w0.381: v1(144.45,31.57) 144.87,31.14 C402.2 ; v1(69.09,40.01) 69.41,39.69 C326.2 C325.2 ; C412.2 125.12,28.93 v1(124.86,28.67) ; C316.2 132.6,40.82 v1(132.37,41.05) ; v1(122.63,49.74) 122.39,49.97 C264.2 ; v1(136.81,27.46) 137.52,28.17 C418.2 ; 153.82,42.88 152.96,43.74 v1(152.53,43.74) ; 153.82,42.88 153.82,43.33 v1(153.37,43.79) ; 153.82,42.88 C302.2 ; v1(196.13,60.45) 196.26,60.58 196.3,60.58 196.47,60.75 P4.178 ; C257.2 125.04,49.79 v1(124.85,49.59) ; v1(203.96,29.84) 203.23,30.58 C396.2 ; C293.2 124.24,45.2 v1(124.61,45.56) 124.66,45.51 C284.2 ; C281.2 138.55,46.02 v1(138.49,45.97) 138.49,46.42 C280.2 ; C204.2 C195.2 87.7,64.88 R166.2 ; 122.83,44.83 122.83,45.54 v1(122.89,45.59) ; C335.2 138.07,38.89 v1(138.35,39.17) 138.96,38.56 C334.2 ; C453.2 v2(124.6,22.76) ; v1(144.51,28.72) 144.92,28.3 C424.2 ; v3(132.9,23.98) 132.51,23.59 132.26,23.59 ; v1(204.55,52.85) 204.34,52.64 N32.1 ; v1(132.37,35.45) 132.35,35.43 C352.2 ; C432.2 141.48,25.78 v1(141.99,25.27) ; C492.1 76.64,9.59 76.2,10.03 v1(76.2,11.05) ; v1(144.62,44.85) 144.97,45.2 C283.2 ; v1(78.99,10.29) 78.36,9.65 C491.1 ; v1(137.97,40.39) 138.57,39.79 C322.2 ; R213.2 R212.2 ; v1(92.53,6.71) 92.42,6.59 S1.B7 ; v1(80.39,10.29) 80.9,9.78 C490.1 ; C340.2 137.77,36.69 v1(137.98,36.49) ; C438.2 126.44,26.28 v1(126.04,26.68) ; v1(124.47,25.21) 124.4,25.29 C435.2 124.4,27.18 C426.2 ; C489.1 82.61,9.59 83.19,10.16 v1(83.19,10.92) ; C248.2 141.68,52.2 v1(142.28,52.79) ; v1(137.44,50.55) 137.34,50.45 C268.2 ; R274.2 129.51,30.76 v1(129.35,30.6) ; 132.26,23.59 C446.2 ; 132.26,23.59 132.65,23.2 132.65,22.49 C451.2 ; C373.2 134.95,33.05 v1(134.94,33.04) 134.94,33.48 C363.2 ; N31.1 v1(205.49,52.88) ; R223.2 143.73,43.79 v1(143.84,43.68) ; v1(92.51,63.27) 93.75,64.52 C198.2 ; v1(146.66,28.38) 146.86,28.18 C422.2 ; v1(143.69,39.19) 144.15,38.73 C336.2 ; R242.1 148.87,38.7 148.87,38.83 v1(149.19,39.15) ; C255.2 20.89,50.61 v1(21.46,50.04) ; v1(137.82,34.34) C366.2 ; v1(82.85,62.46) 82.85,62.46 83.34,62.46 83.9,61.9 R173.1 ; C496.1 68.2,10.22 v1(68.2,10.79) ; v1(146.91,27.09) 146.98,27.16 C427.2 ; C495.1 70.61,10.41 v1(70.99,10.79) ; R181.2 146.23,58.94 v1(146.25,58.96) ; v1(134.26,24.97) 134.69,24.97 135.13,24.54 C449.2 135.04,23.23 R317.2 ; C413.2 146.34,29.72 v1(146.77,30.15) ; v1(137.86,27.4) 138.41,27.95 C417.2 ; v1(137.6,43.14) 137.6,43.61 C291.2 ; C351.2 136.5,35.43 136.82,35.76 C357.2 137.19,35.76 137.6,35.35 v1(137.6,35.2) ; v2(114.43,19.96) 114.46,20 115,20 115.82,19.18 C464.2 C463.2 ; R332.1 72.52,15.88 v1(72.39,16) ; v1(133.96,38.64) 134.06,38.54 C328.2 ; v1(132.77,31.76) 133.08,31.45 C398.2 ; v1(146.09,32.62) 146.39,32.92 C385.2 ; v1(134.37,50.01) 134.44,50.09 C263.2 ; R275.2 141.78,31.93 C391.2 ; v1(129.17,36.25) 129.62,36.7 C341.2 ; v1(135.56,38.66) 135.64,38.73 C321.2 ; C441.2 63.5,24 ; C241.2 138.15,55.07 v1(138.44,55.36) ; v1(135.67,50.78) 136.06,50.39 C261.2 ; v1(120.55,19.94) R321.2 119.82,20.46 119.46,20.83 v1(119.2,20.83) ; C222.2 v1(17.27,58.17) ; v1(101.14,34.47) C360.2
  BOTTOM w0.508: 127.66,63.99 128.02,64.36 C197.2 ; v1(54.86,32.38) 55.04,32.56 C367.2 R262.2 ; v1(75.56,10.29) 74.87,9.59 C493.1 ; C244.2 37.89,52.55 v1(37.45,52.11) ; C225.2 38.4,58.2 v1(38.34,58.14) ; v1(24.79,6.99) 24.37,6.56 S1.B73 ; R177.2 21.26,59.19 21.26,58.47 v1(21.21,58.42) ; C420.2 104.32,27.43 v2(104.42,27.33) ; v1(203.84,41.27) 203.1,40.54 C324.2 ; C210.2 178.56,62.03 v1(178.87,61.62) 179.3,61.72 C209.2 ; R277.2 108.31,30.82 v1(108.17,30.67) ; S1.B69 28.37,6.5 v1(28.91,7.04) ; C214.2 43.96,62.72 v1(44.34,63.11) ; 119.94,18.57 120.47,18.57 ; 119.94,18.57 120.57,19.2 ; 119.94,18.57 C470.2 ; C211.2 v1(29.12,62.01) ; C311.2 v1(205.1,43.38) ; R1.2 118.75,71.4 v2(118.52,71.63) ; C276.2 203.3,48.92 v1(204.09,48.13) ; v1(30.89,6.88) 31.37,6.4 S1.B66 ; 97.64,72.54 97.37,72.28 C170.2 ; C404.2 96.06,30.37 C409.2 ; 120.9,61.34 C196.2 121.01,61.29 ; C223.2 34.27,61.02 v1(34.39,61.14) ; v1(79.12,6.6) 79.37,6.36 S1.B18 ; v1(61.42,41.88) 61.57,42.04 N39.2 ; C403.2 v1(206.36,30.35) ; C203.2 31.42,63.16 v1(31.35,63.09) ; C439.2 146.06,25.3 146.06,26.19 v1(146.09,26.22) ; C174.2 v1(202.92,71.6) ; S1.B77 20.37,6.45 v1(20.83,6.91) ; 96.19,72.52 96.43,72.28 C170.2 ; v1(204.08,43.48) 203.9,43.66 C301.2 ; v1(204.09,31.96) 204.28,31.78 C386.2 ; v1(76.58,6.6) 76.56,6.6 76.37,6.42 S1.B21 ; C456.1 99.29,21.64 v1(99.39,21.74) R322.2 ; 64.82,37.41 C90.2 63.65,37.44 63.63,37.47 ; 64.82,37.41 64.82,36.12 ; 64.82,37.41 64.03,36.63 v2(63.53,36.63) ; v1(204.09,39.24) 204.19,39.34 C333.2 ; C392.2 105.18,31.03 v1(105.18,30.52) ; R305.1 105.71,26.9 v1(105.71,27.33) ; C455.2 94.04,21.22 R318.2 93.28,20.9 C459.2 ; C455.2 C454.2 95.11,20.67 v1(94.95,20.5) ; C455.2 v1(94.06,20.47) ; v1(52.55,30.88) 52.32,31.11 C400.2 ; v1(43.43,46.86) 43.56,46.99 C274.2 ; S1.B82 15.37,7.24 15.74,7.62 v1(15.74,7.66) 16.37,7.03 S1.B81 ; v1(52.96,32.38) 53.01,32.44 C368.2 ; 120.55,18.06 v1(120.55,18.03) ; R299.2 v1(206.39,27.3) ; v1(27.71,51.41) 27.71,51.52 C247.2 ; v1(53.98,32.38) 54.03,32.44 R263.2 ; C208.2 182.42,61.7 v1(182.85,61.62) 183.13,61.95 C207.2 ; S1.B37 v1(60.37,6.68) ; C485.2 117.56,11.75 v2(117.55,11.76) ; v2(123.93,71.37) 123.93,71.2 123.83,71.09 C179.2 ; C285.2 25.73,45.82 v2(24.99,46.56) ; v1(132.77,72.4) C173.2 ; R212.2 v1(18.8,47.52) ; R231.2 v1(32.13,39.69) ; v1(29.46,17.91) 29.78,18.22 C465.2 ; v1(97.87,31.04) 98.02,30.89 C408.2 97.01,30.37 C409.2 ; C437.2 22.15,28.07 v2(21.62,28.6) 21.06,28.04 C436.2 ; C407.2 98.93,30.37 ; 98.93,30.37 98.93,30.91 v1(98.83,31.01) ; 98.93,30.37 98.95,30.39 C406.2 ; v1(118.8,27.41) 118.86,27.41 119.36,26.92 R303.2 ; C170.2 96.93,72.72 ; C206.2 63.18,63.69 v1(62.74,64.14) ; S1.B78 19.37,6.39 v1(18.8,6.96) ; v1(32.89,6.81) 32.37,6.28 S1.B65 ; v1(52.58,29.91) 52.37,30.12 C405.2 ; v1(203.96,36.45) 203.81,36.6 C356.2 ; R144.1 52.58,68.63 v1(52.5,68.71) ; C176.2 200.66,71.88 v1(200.57,71.97) ; v1(131.35,27.4) 131.35,25.8 R306.2 ; v1(90.75,13.61) 90.9,13.76 C481.2 C480.2 C479.2 ; v1(73.94,17.34) 73.77,17.51 U39.2 ; v1(131.55,52.99) 131.06,53.48 C238.2 ; v1(44.07,68.2) 44.3,67.97 C186.2 ; C473.2 86.33,16.4 85.57,17.16 v1(85.57,17.31) ; v1(125.98,63.91) 125.71,63.63 C201.2 ; R167.2 84.87,65.4 ; R167.2 84.63,64.88 C200.2 ; R167.2 85.11,64.88 C199.2 ; v1(59.84,34.32) 59.84,34.47 59.5,34.81 R255.1 ; C217.2 38.01,61.76 v1(38.35,62.1) ; C237.2 204.44,55.47 v1(204.09,55.12) ; C249.2 v1(22.21,51.24) ; C462.1 122.28,19.46 v1(121.77,19.96) ; v1(46.86,9.14) 47.23,9.51 R344.2 ; R183.2 50.48,58.16 50.88,57.76 v1(50.88,57.71) ; R264.1 51.99,32.06 v1(52.03,32.02) ; v1(63.04,6.6) 63.37,6.28 S1.B34 ; R265.2 C369.2 49.37,33.18 v1(49,33.55) ; v1(47.98,64.92) 47.88,65.02 C188.2 ; v1(36.02,37.85) 36.08,37.85 36.8,37.12 C347.2 ; C474.2 v1(204.85,12.57) ; C183.2 47.18,69.28 v1(47.37,69.09) ; C202.2 v1(45.57,63.98) ; S1.B13 84.37,7.08 v1(84.84,7.54) 84.58,7.54 83.37,6.33 S1.B14 ; S1.B49 v1(48.37,6.53) ; v1(67.18,6.6) 67.37,6.42 S1.B30 ; v1(89.08,18.69) 89.43,18.35 C468.2 ; JP5.4 57.53,56.9 56.77,57.66 v1(56.77,58.8) ; C442.2 34.99,24.19 34.8,24 v1(34.29,24) ; C175.2 90.21,70.83 v2(89.2,71.83) ; R192.2 17.6,55.37 v1(17.22,55.75) ; C309.2 145.87,43.85 v1(146.41,44.38) ; R333.2 122.22,14.35 v1(122.63,13.94) 122.99,14.3 C476.2 ; 63.04,15.75 63.93,16.64 C132.2 64.19,16.64 ; v1(16.56,63.17) 18.05,63.17 C213.2 ; 97.82,32.47 v1(97.26,33.03) C361.2 96.95,33.54 C372.2 ; 97.82,32.47 U21.41 98.32,32.37 ; 97.82,32.47 C387.2 ; C234.2 38.04,55.41 v1(38.32,55.12) ; C215.2 72.54,61.85 v2(72.52,61.82) ; C315.2 40.49,41.34 v1(40.85,41.71) 40.84,41.71 40.39,42.16 C300.2 ; C475.2 95.93,18.52 U27.49 ; R197.2 97.02,53.99 v1(97.54,54.52) ; v1(96.75,31.34) 97,31.09 C409.2 ; v1(71.25,6.6) 71.37,6.48 S1.B26 ; S1.B62 v1(35.37,6.64) ; S1.B17 80.34,3.78 80.34,6.3 v1(80.64,6.6) ; C434.2 v1(206.29,26.29) ; v1(54.97,6.86) 54.97,6.76 55.37,6.36 S1.B42 ; 64.19,16.64 65.38,16.64 ; 64.19,16.64 65.07,15.75 65.07,15.44 v2(65.28,15.24) ; 98.32,32.37 C362.2 ; 98.32,32.37 98.38,32.42 C388.2 ; J5.3 48.14,52.54 48.14,51.82 v1(48.13,51.82) ; U42.2 v1(56.92,8.76) ; v1(130.76,67.08) 130.98,66.85 U36.3 131.65,64.63 R164.2 ; S1.B61 v1(36.37,6.58) ; S1.B54 v1(43.37,6.52) ; C230.2 v1(38.33,57.12) ; v1(31.09,36.02) 30.86,35.79 C358.2 ; v1(36.3,57.12) 36.25,57.18 C229.2 ; C461.2 93.95,18.87 v1(94.01,18.82) ; R234.2 27.67,39.56 v1(27.61,39.5) ; v1(58.24,8.89) R345.2 ; v1(204.22,20.45) 204.32,20.35 C458.2 ; S1.B58 v1(39.37,6.58) ; S1.B53 v1(44.37,6.55) ; S1.B38 59.37,6.52 v1(59.21,6.68) ; U41.2 52.68,9.42 v1(53.09,9.02) ; C218.2 35.72,61.76 v1(35.32,62.16) ; v1(68.71,6.6) 68.37,6.26 S1.B29 ; v1(101.7,68.22) 101.51,68.03 N29.2 ; v1(45.32,49.12) 45.35,49.16 C258.2 ; S1.B46 51.37,6.39 v1(51.13,6.63) 52.01,6.63 52.37,6.27 S1.B45 ; C282.2 204.4,46.33 204.22,46.15 v1(204.11,46.15) ; v1(27.66,66.07) 27.28,66.45 C189.2 ; v1(37.45,59.12) 37.37,59.04 C224.2 ; S1.B57 v1(40.37,6.55) ; v2(115.01,65.51) 114.81,65.71 C191.2 ; v2(20.9,69.29) 20.69,69.09 C185.2 ; C399.2 106.77,30.44 v1(106.51,30.71) ; U30.11 121.83,13.3 R341.2 ; R325.1 67.92,17.07 v1(68.02,16.97) ; S1.B22 75.37,6.29 v1(75.06,6.6) ; C494.1 73.28,9.78 v1(72.77,10.29) ; v1(119.77,27.34) 120.36,26.82 R304.1 ; C466.2 62.36,17.27 ; C355.2 v1(206.12,36.3) ; v1(64.71,6.64) 64.37,6.3 S1.B33 ; C236.2 33.72,54.52 v1(33.35,54.15) ; R178.2 R179.2 v1(18.22,59.25) ; S1.B50 v1(47.37,6.53) ; R286.2 v1(206.31,29.34) ; S1.B25 72.37,6.3 72.67,6.6 v1(72.77,6.6) ; R155.1 v1(206.38,66.55) ; S1.B70 27.37,6.24 v1(26.9,6.71) ; v1(34.92,30.53) 35.18,30.78 C394.2 ; C501.2 v1(135.13,4.83) ; C228.2 42.33,57.06 v1(42.4,57.13) ; v1(22.81,7.09) 22.86,7.09 23.37,6.58 S1.B74 ; C221.2 v1(204.85,63.37) ; R280.1 v1(47.12,31.37) ; v2(106.47,17.8) 106.47,17.37 C471.2 105.64,15.98 104.52,14.86 C477.2 C482.2 ; C277.2 v1(31.48,46.69) ; R211.2 v1(20.07,47.55) ; v1(34.32,52.15) 34.4,52.24 C245.2 ; S1.B41 v1(56.37,6.63)
  BOTTOM w0.762: P3.19 v2(7.91,54.63) ; v2(3.61,34.7) 4,34.3 P3.7 ; C194.2 69.72,68.07 v2(69.22,68.58) ; P3.12 v2(3.64,45.74) ; P3.13 v2(3.6,47.01) ; v2(95.42,6.77) 95.4,6.75 S1.A4 ; P3.11 v2(4.13,44.47) ; C181.2 117.68,71.09 v2(117.12,71.65) ; v2(72.52,61.82) 71.91,62.43 C212.2 70.64,61.77 v2(71.48,61.77) ; C193.2 115.7,65.51 v2(115.01,65.51) ; C460.2 88.11,19.79 v1(88.11,18.77) ; P3.1 v2(3.02,26.68) ; C192.2 v2(118.67,65.84) ; P3.17 4.07,52.09 v2(3.68,52.48) ; v2(67.34,68.94) 67.37,68.93 67.84,68.38 R149.2 ; P3.4 v2(3.44,30.49) ; C182.2 v2(116.03,71.78)
  vias: v1(1.91,33.15) v1(1.91,31.62) v1(1.91,29.21) v1(1.91,27.69) v1(8.51,33.4) v1(8.51,31.88) v1(8.51,29.08) v1(8.51,27.56) v1(12.78,39.37) v1(12.78,38.1) v1(12.78,36.83) v1(14.05,39.37) v1(14.05,38.1) v1(14.05,36.83) v1(15.32,39.37) v1(15.32,38.1) v1(15.32,36.83) v1(16.59,39.37) v1(16.59,38.1) v1(16.59,36.83) v1(17.86,39.37) v1(17.86,38.1) v1(17.86,36.83) v1(19.05,9.02) v1(20.57,9.02) v1(22.48,36.96) v1(23.11,9.02) v1(24.64,9.02) v1(27.18,8.89) v1(28.7,8.89) v1(30.77,9.81) v1(31.86,8.73) v1(32.05,18.57) v1(33.13,17.5) v1(33.34,9.71) v1(33.66,20.45) v1(34.42,8.63) v1(34.61,18.11) v1(35.56,19.56) v1(35.69,17.03) v1(35.86,15.19) v1(41.43,13.11) v1(42.5,12.03) v1(48.77,8.38) v1(49.58,17.3) v1(49.56,16.38) v1(49.58,15.62) v1(50.29,8.38) v1(50.42,17.32) v1(50.42,16.36) v1(50.42,15.6) v1(51.18,7.37) v1(51.28,17.3) v1(51.28,16.41) v1(51.33,15.62) v1(52.7,7.37) v1(54.07,30.62) v1(54.07,29.86) v1(54.56,31.54) v1(55.04,29.79) v1(59.69,9.4) v1(61.21,9.4) v1(62.48,9.4) v1(64.01,9.4) v1(65.33,33.45) v1(65.3,32.44) v1(65.35,31.47) v1(65.79,42.82) v1(66.27,43.48) v1(66.55,36.2) v1(66.55,35.05) v1(66.55,33.43) v1(66.57,32.44) v1(66.7,44.12) v1(66.73,42.85) v1(67.36,9.6) v1(69.72,24.61) v1(69.72,23.67) v1(69.72,22.76) v1(70.59,24.61) v1(70.64,22.76) v1(71.4,24.56) v1(71.45,23.67) v1(71.45,22.81) v1(79.2,18.19) v1(79.22,17.07) v1(81.03,11.68) v1(81.15,18.24) v1(81.15,17.07) v1(82.55,11.68) v1(84.15,65.61) v1(84.3,67.13) v1(84.43,67.94) v1(84.79,66.47) v1(85.01,65.74) v1(85.12,67.28) v1(85.22,12.45) v1(85.55,67.97) v1(85.99,65.66) v1(86.69,67.94) v1(86.7,67.03) v1(87.13,66.09) v1(89.15,11.81) v1(90.53,33.63) v1(90.53,32.11) v1(90.68,11.81) v1(93.8,17.63) v1(93.85,27.56) v1(93.85,26.04) v1(93.85,16.79) v1(94.01,19.68) v1(94.23,37.85) v1(94.23,36.32) v1(94.94,57.85) v1(94.95,19.33) v1(94.92,18.49) v1(94.97,17.65) v1(94.97,16.81) v1(95.5,13.59) v1(95.66,20.14) v1(95.78,19.35) v1(95.94,16.74) v1(96.01,56.77) v1(96.01,24) v1(95.96,17.55) v1(96.67,58.82) v1(96.72,32.46) v1(96.75,19.89) v1(96.75,19.13) v1(96.77,18.36) v1(96.82,17.6) v1(96.77,16.76) v1(97.03,13.59) v1(97.36,31.9) v1(97.54,42.29) v1(97.54,40.77) v1(97.64,17.53) v1(97.66,19.89) v1(97.69,19.13) v1(97.69,18.36) v1(97.66,16.76) v1(97.75,57.75) v1(98.35,33.15) v1(98.45,52.73) v1(98.83,31.78) v1(98.81,24) v1(99.14,33.22) v1(99.24,32.44) v1(99.34,22.52) v1(99.53,51.66) v1(99.54,31.47) v1(100.15,58.75) v1(100.46,20.32) v1(100.6,60.1) v1(101.22,57.67) v1(101.69,59.02) v1(102.18,68.94) v1(102.36,17.3) v1(102.36,15.77) v1(102.49,20.32) v1(102.49,18.8) v1(102.59,69.65) v1(102.59,68.2) v1(105.66,19.68) v1(112.39,21.46) v1(112.39,19.94) v1(113.28,59.05) v1(113.54,57.15) v1(113.54,55.63) v1(114.81,59.05) v1(118.09,20.43) v1(120.8,13.92) v1(120.8,12.75) v1(121.74,18.06) v1(122.61,12.9) v1(126.24,67.92) v1(127.3,67.89) v1(157.6,34.05) v1(159.21,33.9) v2(17.12,16.79) v2(17.12,15.57) v2(18.44,15.54) v2(18.47,16.79) v2(19.74,16.79) v2(19.74,15.52) v2(21.01,16.79) v2(21.01,15.52) v2(23.11,31.37) v2(23.06,30.02) v2(23.37,47.37) v2(23.42,32.49) v2(23.72,45.29) v2(23.88,46.35) v2(24.51,32.51) v2(27.94,32.03) v2(28.07,30.99) v2(28.07,29.54) v2(28.98,32.08) v2(32.13,31.22) v2(32.13,29.95) v2(45.09,13.97) v2(46.23,13.97) v2(46.23,12.83) v2(54.91,15.52) v2(54.97,16.84) v2(56.13,16.79) v2(56.06,15.57) v2(57.4,16.79) v2(57.35,15.57) v2(62.99,15.24) v2(63.45,37.64) v2(64.14,15.24) v2(65.79,16.13) v2(66.55,15.27) v2(68.1,23.9) v2(68.07,22.73) v2(69.27,51.28) v2(69.27,50.01) v2(69.27,48.74) v2(69.27,47.47) v2(70.54,51.28) v2(70.54,50.01) v2(70.54,48.74) v2(70.54,47.47) v2(70.61,31.23) v2(71.68,51.51) v2(71.76,31.28) v2(72.8,30.47) v2(72.9,31.59) v2(73.1,51.64) v2(74.02,30.51) v2(74.07,31.57) v2(74.37,51.64) v2(75.72,51.66) v2(75.67,23.14) v2(75.74,22.12) v2(76.99,51.66) v2(77.62,23.14) v2(78.23,51.66) v2(78.69,22.63) v2(79.04,50.85) v2(79.2,31.52) v2(79.17,30.45) v2(79.71,51.66) v2(79.81,23.27) v2(79.78,22.15) v2(80.52,31.31) v2(80.47,30.23) v2(81.2,23.27) v2(81.15,22.15) v2(81.64,30.23) v2(81.66,31.31) v2(82.78,31.32) v2(82.75,30.25) v2(83.92,31.32) v2(83.87,30.14) v2(85.04,31.34) v2(85.01,30.16) v2(88.39,71.17) v2(89.33,70.56) v2(90.63,72.36) v2(112.01,16.38) v2(112.9,16.89) v2(113.92,16.38) v2(114.94,16.64) v2(122.81,71.12) v2(123.29,60.15) v2(123.75,61.11) v2(123.8,62.18) v2(124.33,60.15) v2(125.5,61.62) v2(125.58,9.5) v2(125.7,8.48) v2(126.42,62.13) v2(126.44,60.15) v2(126.47,61.11) v2(129.62,10.95) v2(129.67,9.22) v2(129.77,8.08) v2(130.45,10.11) v3(126.24,64.57) v3(127.13,64.62)
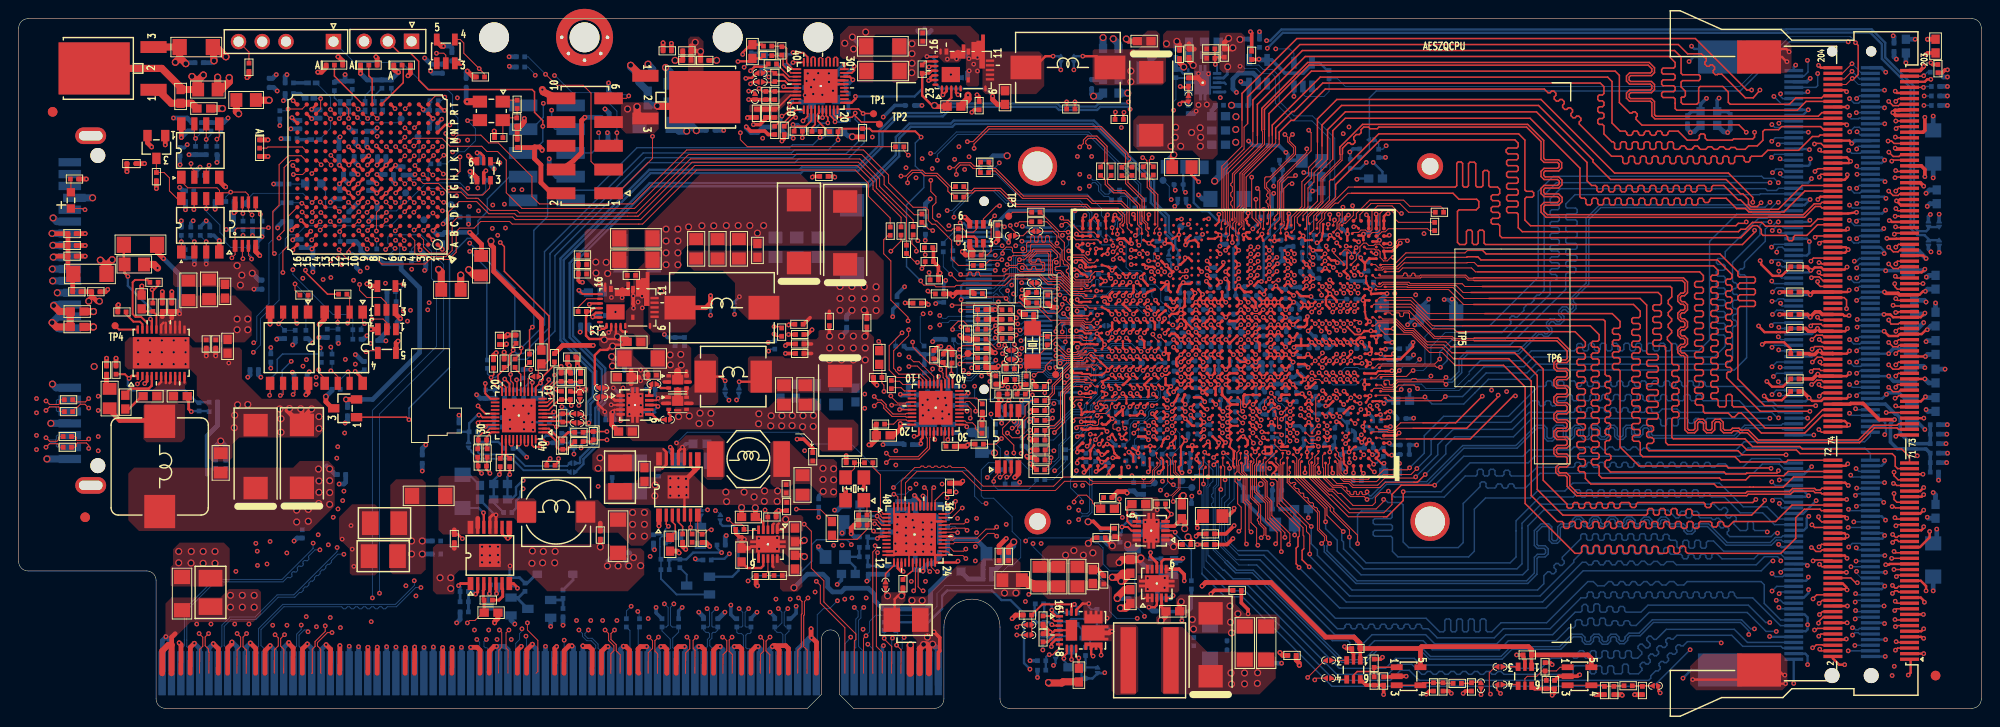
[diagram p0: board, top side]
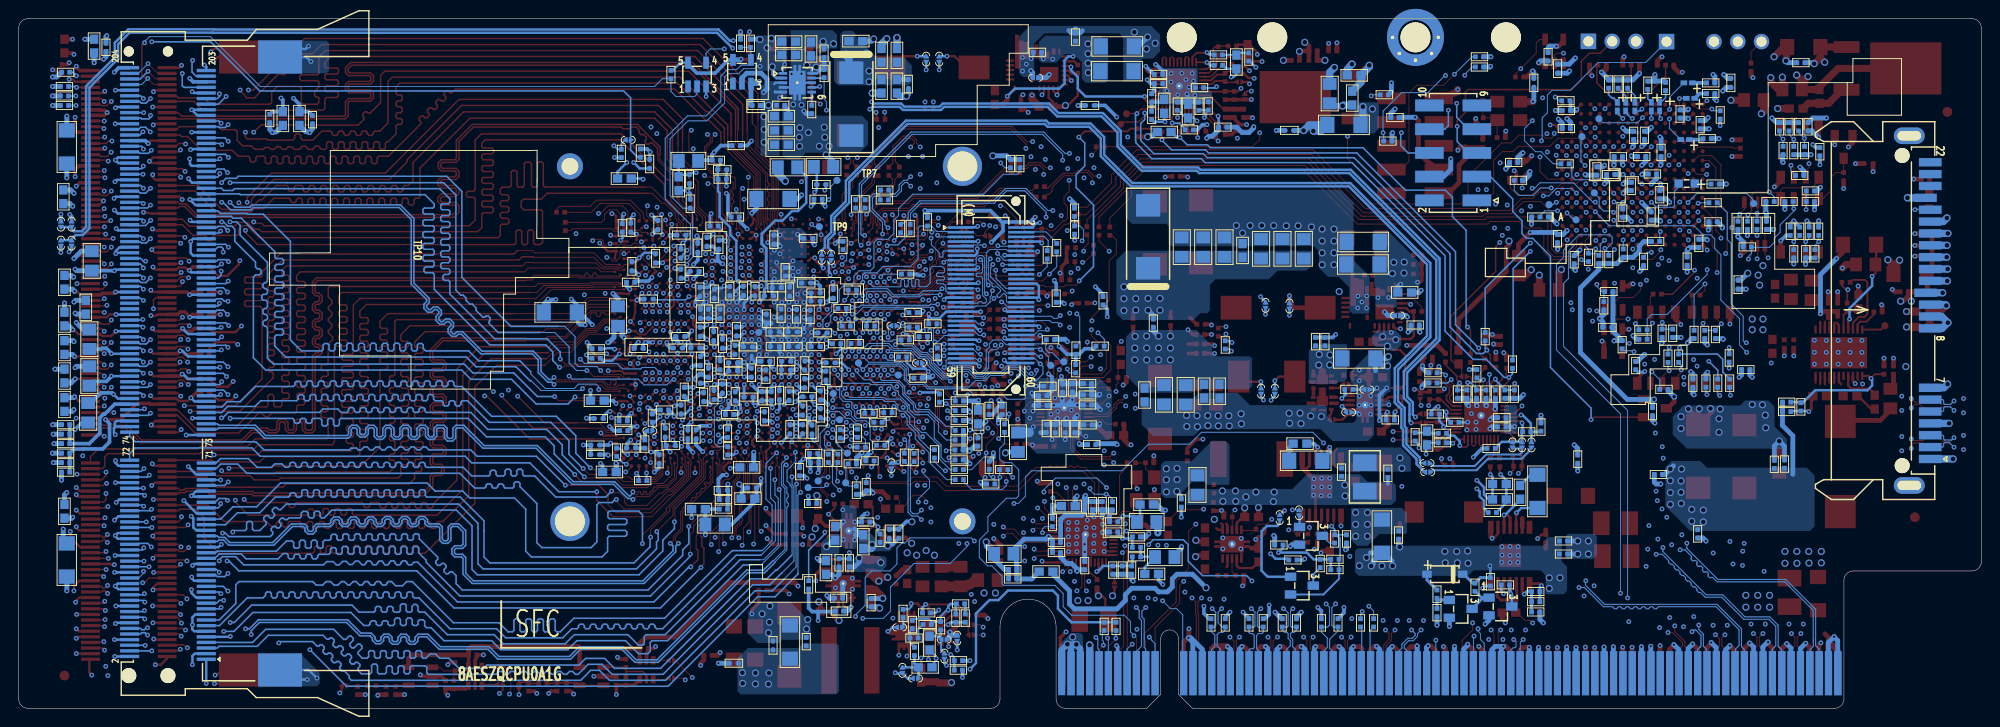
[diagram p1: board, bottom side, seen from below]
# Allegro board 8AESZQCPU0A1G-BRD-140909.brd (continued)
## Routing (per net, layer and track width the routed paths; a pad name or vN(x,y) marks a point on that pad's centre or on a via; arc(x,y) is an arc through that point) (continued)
V1P0: length 249.6
  TOP w0.099: v1(107.14,40.46) 106.99,40.62 C78.1 ; 48.93,58.56 U6.6
  TOP w0.203: U14.AC38 U14.AA38 ; U14.AT21 v1(136.42,43.47) U14.AU21
  TOP w0.254: v1(133.97,43.45) U14.AU26 v1(133.17,43.45) ; v1(133.97,43.45) U14.AT25 v1(134.77,43.45) ; v1(133.97,43.45) U14.AU25 v1(134.77,43.45) ; v1(133.97,43.45) U14.AT26 v1(133.17,43.45) ; N6.2 106.01,49.95 v1(105.92,49.86) ; U14.N42 v1(125.41,32.14) U14.P42 ; U14.W38 v1(128.37,34.65) U14.V38 128.07,34.15 U14.T37 ; v1(126.77,43.45) U14.AU41 ; v1(126.77,43.45) U14.AT39 ; v1(126.77,43.45) U14.AU39 v1(127.57,43.45) ; U14.AU41 v1(125.97,43.45) ; U14.AU41 126.66,44.26 126.66,44.29 v1(126.67,44.3) 126.6,44.38 U14.AW41 ; v1(123.58,33.86) 123.61,33.89 123.61,33.89 U14.V46 ; U14.BA37 128.52,45.63 128.61,45.63 v1(128.61,45.63) 128.6,45.63 U14.AY37 ; U14.W25 v1(133.97,35.45) U14.W26 ; v1(127.57,43.45) U14.AT38 ; v1(127.57,43.45) U14.AU38 v1(128.37,43.45) ; v1(126.68,33.8) 126.71,33.83 126.71,33.84 U14.V39 ; v1(126.68,33.8) 126.68,33.96 U14.V41 ; v1(126.68,33.8) 126.69,33.8 126.71,33.79 126.88,33.79 U14.T39 ; v1(125.97,43.45) U14.AT41 ; v1(125.97,43.45) U14.AT42 ; U14.N41 126.5,31.71 v1(126.81,31.37) ; U14.V25 v1(133.97,34.65) U14.V26 ; U14.AG38 v1(127.57,39.45) U14.AJ38 ; U14.L42 v1(125.41,31.37) ; v1(133.17,43.45) U14.AU28 ; v1(133.17,43.45) U14.AT28 ; v1(134.77,43.45) U14.AU23 ; v1(134.77,43.45) U14.AT23 v1(135.57,42.65) U14.AT21 ; U14.V20 v1(136.37,34.65) U14.W21 ; 132.37,37.05 132.37,37.06 U14.AD28 ; 132.37,37.05 U14.AD29 ; 132.37,37.05 v1(132.37,37.04) ; v1(126.77,35.45) U14.AA41 ; U14.AF38 v1(127.57,37.85) U14.AD38 ; U14.AJ29 v1(132.37,40.25) 132.75,40.63 U14.AL28 ; U14.V23 v1(135.56,34.65) 135.57,34.65 U14.V21 ; U14.T44 U14.R44 v1(124.83,32.52) ; U14.AA38 v1(127.57,35.45) 127.18,35.84 U14.AA39 ; U14.L41 126.5,30.95 v1(126.81,30.61) 126.5,30.28 U14.K41 ; v1(127.15,32) 126.93,32.01 U14.P41 ; U14.W23 135.55,35.43 v1(135.55,35.46) 135.57,35.46 U14.AA21 ; v1(128.37,43.45) U14.AU36 ; v1(128.37,43.45) U14.AT36 ; v1(129.17,43.45) U14.AU36 ; U14.AU36 U14.AW36 ; U14.AC42 v1(125.17,36.25) ; U14.AC44 v1(124.35,36.24) ; U14.AC39 v1(126.77,36.25) U14.AC41 ; U14.W46 v1(124.37,34.65) U14.W44 ; U14.T45 U14.R46 v1(123.43,32.52) ; U14.W41 126.38,35.04 v1(126.77,34.65)
  TOP w0.381: v1(126.11,19.3) 126.11,19.96 L12.2
  TOP w0.508: R69.2 R75.2 104.67,36.47 v1(104.83,36.63) ; 48.93,58.56 48.68,58.56 v1(48.11,59.13) ; v1(101.23,52.55) 101.26,52.55 101.77,52.04 U10.6 ; R50.2 110.54,42.92 v1(111.07,42.92) ; R45.2 107.56,44.04 v1(107.29,44.04) 107.29,44.01 107.92,43.38 R51.1 ; R23.1 89.22,61.15 v2(89.2,61.16) ; v2(50.53,50) 50.53,49.59 50.83,49.3 50.83,46.75 55.93,41.64 R66.2 ; L3.1 123.42,59.05 v2(123.6,59.23)
  L3_SIG w0.381: v1(113.03,53.26) 113.03,54.36 111.76,55.63 v1(111.76,56.24) ; v1(101.23,52.55) 101.47,52.31 101.47,51.66 100.63,50.83 98.76,50.83 98,50.07 v1(97,50.07)
  L5_SIG w0.254: 127.61,33.02 127.46,32.87 127.46,32.41 127.15,32.11 v1(127.15,32)
  L5_SIG w0.381: v1(126.68,33.8) 127.4,33.8 ; 127.3,35.1 127.15,35.1 126.77,34.72 v1(126.77,34.65) ; v1(127.15,32) 126.81,31.66 v1(126.81,31.37) v1(126.81,30.61) ; v1(126.77,36.25) 127.4,36.25 ; v1(126.77,35.45) v1(127.57,35.45)
  L7_VCC w0.762: v2(105.77,59.13) 105.54,59.13 102.57,62.1 90.14,62.1 v2(89.2,61.16)
  L8_SIG w0.381: v1(113.21,46.33) 113.13,46.41 110.46,46.41 108.1,44.04 v1(107.29,44.04) ; v1(97,50.07) 97,49.63 98.01,48.63 98.01,47.87 98.7,47.17 101.24,47.17 101.63,46.79 101.63,45.14 102.29,44.48 102.29,42.29 v1(100.81,40.82) ; v1(107.14,40.46) 107.34,40.46 109.45,42.57 110.49,42.57 110.84,42.92 v1(111.07,42.92)
  L10_SIG w0.381: 98.27,39.47 98.04,39.24 v1(97.79,39.24)
  L10_SIG w0.508: v2(89.2,61.16) 88.58,61.79 88.58,62.8 87.52,63.86 82.87,63.86 82.5,63.48 82.5,63.2 81.79,62.48 80.11,62.48 78.18,60.55 48.98,60.55 48.17,59.74 48.17,59.19 v1(48.11,59.13) 48.17,59.07 48.17,58.41 49.91,56.67 49.91,50.62 v2(50.53,50)
  BOTTOM w0.254: P2.44 100.94,40.95 v1(100.81,40.82) ; v1(116.2,3.81) 116.14,3.75 N59.2 114.9,3.2 N60.1 ; C286.1 128.41,45.43 v1(128.61,45.63) ; P2.43 107.76,40.95 107.27,40.46 v1(107.14,40.46) ; C381.1 125.13,32.82 v1(124.83,32.52) 124.37,32.06 C397.1 ; v1(127.57,39.45) 127.67,39.45 128.5,40.28 C318.1
  BOTTOM w0.305: v1(128.37,34.65) 128.6,34.42 C375.1
  BOTTOM w0.381: C342.1 127.39,37.68 v1(127.57,37.85) ; C357.1 136.51,34.79 v1(136.37,34.65) ; C316.1 132.77,39.85 v1(132.37,40.25) ; C359.1 126.41,34.3 v1(126.77,34.65) ; R220.2 113.9,46.46 113.77,46.33 v1(113.21,46.33) ; C373.1 135.61,34.6 v1(135.56,34.65) 135.52,34.7 C363.1 134.01,34.7 v1(133.97,34.65) ; v1(123.7,53.72) 124.02,54.04 C239.2 ; v1(125.41,31.37) 125.41,30.6 C412.1 ; v1(126.81,31.37) 126.81,31.38 C393.1 ; v1(123.43,32.52) 123.91,33 C376.1 ; v1(127.57,35.45) 127.42,35.6 C349.1 126.8,36.22 v1(126.77,36.25) ; C354.1 124.18,36.08 124.34,36.24 v1(124.35,36.24) ; C410.1 127.09,30.34 v1(126.81,30.61) 126.54,30.34 C411.1 ; C257.1 126.24,50.29 v1(126.67,50.72) ; v1(127.57,39.45) 127.6,39.42 C330.1 ; C352.1 131.73,36.4 v1(132.37,37.04) ; C304.1 137.06,43.02 136.69,43.39 ; v1(105.92,49.86) 104.67,51.1 104.67,51.92 ; 104.67,51.92 106.02,53.26 v1(113.03,53.26) ; 104.67,51.92 104.55,52.04 101.74,52.04 v1(101.23,52.55) ; C377.1 126.8,33.92 v1(126.68,33.8) ; v1(97,50.07) 97.02,50.1 R202.1
  BOTTOM w0.508: R236.2 99.1,39.5 98.04,39.5 v1(97.79,39.24) ; R185.2 R184.2 104.28,59.13 v2(105.77,59.13) ; C287.1 132.46,44.16 v1(133.17,43.45) ; v1(113.03,53.26) 112.77,53 R198.2 ; v1(113.25,42.51) 113.41,42.35 R225.1 ; R174.1 88.24,61.68 88.74,61.25 89.11,61.25 v2(89.2,61.16) ; L16.2 122.84,58.55 123.52,59.23 v2(123.6,59.23) ; C350.1 C343.1 132.44,36.98 132.37,37.04 v1(132.37,37.04) ; v1(128.52,49.45) 128.74,49.67 C260.1
  BOTTOM w0.762: v2(127.97,56.41) 128.78,57.23 L17.1
  vias: v2(129.72,3.78) v2(129.77,2.59) v2(131.17,3.78) v2(131.17,2.62) v2(132.54,2.67) v2(132.56,3.81)
V1P0_LDOOUT: length 7.2
  TOP w0.203: v1(113.43,5.38) 113.35,5.38 113.15,5.59 U31.10
  TOP w0.254: C165.1 113.43,4.3 v1(113.43,5.38) ; v1(110.5,6.6) 110.5,6.89 110.96,7.35 U31.6
  L5_SIG w0.203: v1(113.43,5.38) 112.09,6.72 110.62,6.72 v1(110.5,6.6)
V1P1: length 31.2
  TOP w0.157: U14.AG32 v1(130.77,39.45) ; U14.AG29 v1(131.57,39.45) ; U14.AG31 v1(130.77,38.65)
  TOP w0.254: U14.AD32 130.75,37.07 131.34,37.07 131.36,37.05 v1(131.57,37.05) U14.AD31 ; U14.AF29 v1(132.37,37.85) ; v1(130.77,38.65) U14.AF31
  TOP w0.508: U25.1 v1(68.51,19.51) ; C120.1 84,24.94
  L3_SIG w0.508: v1(68.51,19.51) 68.51,18.97 69.25,18.24 75.46,18.24 v1(75.71,18.49) 76.32,19.1 82.22,19.1 86.08,22.97 v2(86.08,23.22)
  BOTTOM w0.305: v1(130.77,38.65) 130.81,38.61 131.41,38.61 C332.1
  BOTTOM w0.381: v2(86.08,23.22) 85.6,22.73 C452.2 ; 131.57,37.76 v1(131.57,37.05) 131.48,37.13 C341.1
  BOTTOM w0.508: R327.1 75.6,18.38 v1(75.71,18.49)
  vias: v2(86.06,25.68) v2(86.06,24.49) v2(87.2,25.64) v2(87.2,24.46) v2(87.2,23.16)
V1P1_FB: length 14.6
  TOP w0.157: U25.2 69.29,19.71 v1(69.52,19.48)
  BOTTOM w0.157: C478.1 R331.1 68.61,16.06 68.61,17.29 68.6,17.29 68.6,18.07 68.61,18.08 68.61,18.21 68.8,18.39 68.89,18.39 R324.2 ; R324.2 69.19,19.15 v1(69.52,19.48) ; R324.2 R325.2
  BOTTOM w0.203: U40.2 70.39,12.18 68.72,13.86 C478.1
V1P1_MARGIN_DN_D: length 2.2
  BOTTOM w0.203: U40.3 71.48,14.31 R335.1
V1P1_MARGIN_DN_G: length 10.2
  BOTTOM w0.254: U40.1 76.36,14.08 77.01,14.73 77.01,17.82 77.01,17.82 77.01,18.96 76.45,19.52 75.33,19.52 75.08,19.77 N54.2
V1P1_MARGIN_UP_D: length 1.6
  BOTTOM w0.097: U39.3 69.74,17.68 R324.1
V1P1_MARGIN_UP_G: length 1.2
  BOTTOM w0.254: N53.2 72.95,20.55 U39.1
V1P1_SS: length 2.2
  TOP w0.157: U25.4 70.59,19.91 71.04,19.46 C134.1
V1P1_SW: length 4.1
  TOP w0.305: U25.10 71.24,27.72 v1(71.02,27.94) 70.59,27.51 U25.11
  BOTTOM w0.381: v1(71.02,27.94) 71.4,28.32 C421.2
V1P1_VBST: length 2
  BOTTOM w0.381: R302.2 74.07,27.89 C421.1
V1P1_VREGS: length 2.8
  TOP w0.157: C136.2 70.26,18.85 70.26,19.63 69.94,19.95 U25.3
V1P5: length 23.3
  TOP w0.254: 80.77,15.11 80.67,15.22 U28.9
  BOTTOM w0.508: v2(82.96,12.9) 84.4,14.35 86.06,14.35 86.56,13.84 86.56,12.98 87.09,12.46 88.02,12.46 88.42,12.85 90.91,12.85 91.59,12.17 91.59,11.53 92.48,10.64 97.04,10.64 97.56,11.16 97.56,12.57 99.34,14.35 L20.1
V1P5_CLK_LVIO: length 13.1
  TOP w0.254: U27.30 v1(99.81,18.4)
  BOTTOM w0.508: R329.1 R326.1 99.4,17.99 v1(99.81,18.4) 100.1,18.11 102.41,18.11 103.34,17.18 C471.1 103.25,16.23 103.25,15.44 103.19,15.38 C477.1 C482.1 101.6,13.84 L20.2
V1P5_CLK_VDD_CORE: length 17.2
  TOP w0.152: U27.40 96.86,22.62 v1(96.76,22.72)
  TOP w0.157: v1(96.75,14.68) 96.86,14.79 U27.21
  L3_SIG w0.508: v1(96.76,22.72) 98.76,20.72 98.76,16.76 97.92,15.93 97.33,15.93 96.82,15.42 96.82,14.76 v1(96.75,14.68)
  BOTTOM w0.508: R329.2 98.51,16.16 97.84,15.49 97.33,15.49 96.82,14.99 96.82,14.76 v1(96.75,14.68) 96.6,14.83 C475.1 ; v1(96.76,22.72) 96.95,22.52 C456.2
V1P5_CLK_VDDIF: length 10.6
  TOP w0.254: U27.41 96.46,22.17 v1(95.85,22.78)
  BOTTOM w0.508: 95.94,22.53 95.94,22.69 v1(95.85,22.78) ; 95.94,22.53 95.54,22.13 C454.1 C455.1 ; 95.94,22.53 95.94,20.95 96.24,20.65 98.04,20.65 98.51,20.18 R326.2
V1P8: length 10
  TOP w0.254: U14.AL41 v1(125.97,41.05) ; U14.AU47 123.24,43.78 v1(123.56,43.45) U14.AU46 ; U14.AF41 v1(125.96,38.66) 125.57,38.27 U14.AF42 ; U14.AJ41 v1(125.97,40.25)
  TOP w0.762: v2(120.07,16.08) 119.91,15.93 C144.1 118.08,15.93 v2(117.75,15.6)
  BOTTOM w0.203: C319.1 126.7,40.27 125.98,40.27 v1(125.97,40.25)
  BOTTOM w0.381: v1(125.97,41.05) v1(125.97,40.25) ; C295.1 123.15,43.87 v1(123.56,43.45)
  BOTTOM w0.508: v2(120.07,16.08) 120.07,15.63 120.57,15.13 R334.2
V1P8A: length 26.5
  TOP w0.254: v1(38.28,60.17) 38.82,59.63 U7.L7 ; U7.K6 v1(39.32,58.12) U7.J7 ; U7.G11 34.85,55.62 v1(35.31,55.17) 35.82,54.65 U7.F10 ; U7.J9 v1(36.32,58.12) ; U7.H8 v1(38.32,56.12) ; U7.H10 v1(35.32,56.12)
  TOP w0.762: 19.2,66.95 C18.1 R12.1 17.32,66.47 15.32,68.48 Q1.2 ; 19.2,66.95 v2(18.54,67.61) ; 19.2,66.95 19.2,67.21 v2(19.76,67.77) ; C21.1 23.29,63.87 v2(23.53,63.63)
  BOTTOM w0.508: C224.1 35.9,58.55 v1(36.32,58.12) ; v1(38.32,56.12) 38.15,56.3 C234.1 ; v1(35.32,56.12) 34.75,56.7 C229.1 ; C225.1 39.29,58.16 v1(39.32,58.12)
V1P35: length 18.2
  TOP w0.254: U14.V34 v1(129.17,34.65) U14.W34 v1(129.17,35.45) U14.AA34 U14.AA32 ; U14.V31 v1(131.57,34.65) ; v1(131.57,42.65) U14.AT31
  TOP w0.381: 117.73,18.16 117.51,18.38 C128.1 ; v2(117.02,17.4) 116.27,18.15 C133.1 ; v1(125.98,18.41) 126.24,18.67 C129.1 ; C138.1 v1(126.11,17.53)
  BOTTOM w0.381: 117.09,17.65 116.84,17.91 C463.1 ; 116.7,17.51 116.5,17.51 C464.1 ; v1(125.29,25.34) C435.1 125.39,26.39 C426.1 ; v1(129.17,34.65) 129.47,34.35 C379.1 C378.1 130.81,33.89 v1(131.57,34.65) ; v1(125.65,24.61) 125.92,24.88 C438.1 ; v1(125.53,22.71) 125.49,22.67 C453.1
  BOTTOM w0.762: v2(118.67,17.53) 118.67,17.22 118.8,17.09 C470.1
V3P3: length 222.8
  TOP w0.203: U30.2 U30.1
  TOP w0.254: U26.2 123.3,18.5 123.44,18.36 ; U14.AW42 125.68,44.65 v1(125.87,44.44) 125.68,44.07 U14.AU42 ; U14.AD42 v1(125.17,37.05) ; U14.AD44 v1(124.37,37.05) ; 81.86,19.28 81.69,19.1 U28.1 81.17,19.62 81.33,19.79 ; 80.8,19.76 80.67,19.63 U28.2 ; U30.1 120.5,11.82 ; U14.AJ42 v1(125.17,40.25)
  TOP w0.381: v1(97.33,43.21) 97.31,43.21 97.16,43.36 C67.2 ; v2(123.57,17.3) 123.8,17.53 C137.1 ; 98.41,46.42 98.41,47.27 R41.1 97.88,49.23 R37.2 ; U34.1 161.86,4.47 C163.1 ; C79.2 84.38,40.01 v1(84.89,40.51) ; R65.1 98.36,38.73 v1(98.68,38.73) ; R101.1 101.63,28.27 v1(101.52,28.17) ; C162.1 143.55,6.38 U32.1 ; R112.1 108.88,25.53 v1(108.22,26.18)
  TOP w0.508: v1(104.57,49.89) 104.77,50.08 R31.1 ; v1(98.58,46.58) 98.41,46.42 R43.1 ; 149.91,6.4 150.11,6.6 161.54,6.6 161.86,6.29 C163.1 167.89,5.71 168.28,5.33 U35.5 ; 149.91,6.4 149.99,6.32 U33.5 ; 149.91,6.4 C162.1 143.52,6.97 142.88,7.62 139.83,7.62 133.99,13.46 127,13.46 v1(126.62,13.08) ; R94.1 91.72,30.37 91.72,29.66 91.72,29.26 L8.1 91.77,28.78 91.19,28.19 v1(90.98,28.19) ; R62.1 101.64,39.5 R60.2 101,39.61 v1(100.71,39.9) ; U22.2 v3(35.02,33.06) ; R95.1 103.08,30.84 103.1,30.89 v1(103.1,30.93) 103.1,31.66 R91.1 ; R47.1 99.72,44.35 v1(99.95,44.12) 100.36,44.53 102.07,44.53 R46.1 ; R56.2 v1(104.57,41.63) 104.57,41.63 R57.1 ; R115.2 117.6,23.18 118.46,23.18 v1(118.6,23.04) ; v1(91.82,34.59) 91.48,34.94 91.48,35.41 R78.2 ; R81.1 104.99,34.69 105.13,34.54 v1(105.23,34.54) 105.23,34.67 105.7,35.14 R80.1 ; v1(108.46,35.03) 108.46,34.87 108.85,34.48 R83.1 ; R102.1 101.4,28.04 v1(101.52,28.17) ; R84.1 104.89,33.2 v1(105.11,32.97) 104.77,32.62 U24.8 ; v1(108.26,27.52) 108.38,27.65 R103.2 ; R92.1 108.37,31.86 v1(108.22,31.71) ; v1(101.02,24.31) 100.81,24.1 R113.2
  TOP w0.762: L6.1 v2(8,42.46) ; C153.2 118.44,10.72 v2(117.88,10.72)
  L5_SIG w0.508: v2(8.08,36.58) 8.08,38.48 9.54,39.95 9.54,42.46 ; 9.54,42.46 v2(8,42.46) ; 9.54,42.46 9.54,43.07 10.79,44.32 10.79,46.99 12.7,48.9 12.7,62.55 16.17,66.01 24.05,66.01 28.6,70.56 JP2.3 ; v1(126.62,13.08) 126.62,11.91 125.09,10.39 123.04,10.39 121.72,11.71 120.29,11.71 119.3,10.72 v2(117.88,10.72)
  BOTTOM w0.305: v1(125.17,37.05) 125.28,37.17 C346.1 ; v1(124.37,37.05) 124.29,36.98 C344.1 ; C320.1 125.09,40.18 v1(125.17,40.25) ; C299.1 C293.1 125.87,44.45 v1(125.87,44.44)
  BOTTOM w0.381: R241.1 95.01,38.48 95.93,38.48 96.53,37.88 R243.2 97.83,37.88 v1(98.68,38.73) ; L21.1 88.04,13.72 v1(87.58,13.26) ; C392.1 105.12,32.32 105.41,32.03 105.41,31.81 105.79,31.43 R269.2 ; C338.2 v1(26.97,36.4) ; R250.1 96.9,37.86
  BOTTOM w0.508: R312.1 106.92,24 v1(107.11,24.2) ; C485.1 118.02,10.86 v2(117.88,10.72) ; v1(92.48,28.22) 92.58,28.32 94.63,28.32 R293.1 ; 96.9,37.86 R243.2 ; C394.1 35.18,32.89 v3(35.02,33.06) 37.88,33.06 42.9,38.07 42.9,44.98 40.92,46.96 R216.1 40.91,47.58 R217.1 39,47.58 R210.1 37.25,48.27 36.6,48.92 36.6,49.45 36.09,49.96 R206.1 ; v1(105.11,32.97) 104.78,32.63 C392.1 ; R282.2 108.91,28.72 108.92,28.71 ; v1(108.22,26.18) 108.3,26.18 108.71,26.59 R301.1 ; C442.1 33.88,25.02 v2(33.27,25.62) 32.94,25.95 ; R268.1 C395.2 21.27,30.26 20.17,29.16 20.17,25.04 ; R314.1 119.67,22.9 R313.2 118.81,23.26 v1(118.6,23.04) ; R288.1 108.92,28.71 ; 108.92,28.71 108.92,27.67 R297.1 108.38,27.65 v1(108.26,27.52) 107.73,28.05 R289.1 ; v1(108.22,31.71) 108.36,31.85 R270.1 ; v1(87.3,21.21) 87.6,21.21 88.2,21.8 L18.1 ; C462.2 122.89,17.98 v2(123.57,17.3)
  vias: v2(29.74,21.21) v2(29.74,19.94) v2(30.99,21.29) v2(30.99,20.02) v2(32.08,25.6) v2(32.13,24.33) v2(32.13,23.11) v2(32.11,21.92) v2(33.27,24.36) v2(33.27,23.09) v2(33.27,21.82) v2(82.07,20.22)
V3P3_CLK_PCI: length 4.2
  TOP w0.254: v1(91.88,18.18) 92.08,18.37 92.51,18.37 92.54,18.4 U27.7
  BOTTOM w0.254: R328.2 C468.1 91.01,18.18 v1(91.88,18.18) 92.39,18.69 C461.1
V3P3_CLK_VDD25: length 7.4
  TOP w0.254: U27.15 94.46,14.82 v1(94.64,14.64) 94.5,14.64 94.48,14.66 94.39,14.66 94.06,14.99 U27.14
  BOTTOM w0.254: R330.2 90.84,15.3 C481.1 C480.1 C479.1 93.98,15.24 94.58,14.64 v1(94.64,14.64)
V3P3_CLK_XTAL: length 5.8
  TOP w0.099: U27.3 92.42,20 v1(91.85,20.57)
  BOTTOM w0.203: v1(91.85,20.57) 92.39,20.03 C459.1
  BOTTOM w0.254: L18.2 90.02,20.27 C460.1 90.98,20.57 v1(91.85,20.57)
V3P3_CLKBUF_VDD: length 19.4
  TOP w0.157: U21.16 v1(94.26,31.96) ; v1(94.34,33.6) 94.38,33.56 U21.12 ; v1(101.47,31.8) 101.31,31.96 U21.35 ; v1(94.33,30.46) 94.42,30.36 U21.20 ; v1(95.81,29.11) 96.16,29.11 96.32,29.27 U21.21 ; v1(99.42,28.75) 99.52,28.86 U21.29 ; v1(101.6,33.73) 101.45,33.73 101.28,33.56 U21.39 ; v1(101.45,30.13) 101.45,30.21 101.29,30.36 U21.31
  TOP w0.254: U21.25 97.92,28.95 98.02,28.85 v1(98.02,28.75)
  TOP w0.508: v1(94.33,30.46) 94.33,29.89 93.66,29.22 L8.2
  BOTTOM w0.508: R259.1 95.19,34.75 95.19,34.31 95.19,34.31 C372.1 94.42,33.52 v1(94.34,33.6) ; C406.1 100.65,29.5 ; C388.1 101.39,32.42 ; C409.1 96.51,29.48 ; v1(94.33,30.46) 94.46,30.33 C404.1 ; C387.1 94.76,32.47 v1(94.26,31.96) ; 101.42,33.45 R266.1 100.88,32.87 100.85,32.85
  BOTTOM w1.016: C420.1 101.88,29.51
V3P3_CLKBUF_VDDA: length 5.1
  TOP w0.157: U21.1 99.92,35.66 v1(99.8,35.79) 99.8,36.87 C91.1
  BOTTOM w0.381: C360.1 99.43,35.42 v1(99.8,35.79)
  BOTTOM w0.508: R266.2 99.43,34.01 C360.1
V3P3_CLKBUF_VDDR: length 4
  TOP w0.157: v1(98.42,35.52) 98.42,35.51 98.32,35.41 U21.5
  BOTTOM w0.381: C362.1 98.42,34.81 v1(98.42,35.52)
  BOTTOM w0.508: C362.1 98.3,34.73 C361.1 97.24,34.75 R259.2
V3P3_SF100: length 38
  TOP w0.152: v1(41.76,30.89) 41.49,31.16 U22.1
  BOTTOM w0.152: JP5.3 52.53,56.9 50.14,54.51 50.14,53.16 49.15,52.17 49.15,50.8 48.64,50.29 48.01,50.29 46.1,48.39 46.1,36.47 41.76,32.13 v1(41.76,30.89)
V3P3_SPI: length 11.6
  TOP w0.305: v1(36,36.06) 36.81,35.25 U16.8
  TOP w0.508: v1(30.73,33.55) 30.96,33.78 U15.8 ; v3(32.87,33.35) 32.87,32.8 33.56,32.11 U22.3
  BOTTOM w0.305: C347.1 36.72,35.97 36.09,35.97 v1(36,36.06)
  BOTTOM w0.508: v1(34.21,39.05) 34.16,39.1 R230.1 ; R233.1 29.59,39.17 v1(29.31,38.89) ; R235.1 36.88,39.5 v1(37.26,39.88) ; R260.1 33.52,34 v3(32.87,33.35) ; R256.1 29.46,35.79 v1(29.29,35.97) ; R232.1 30.98,39.56 v1(31.45,39.09) ; C358.1 30.86,33.68 v1(30.73,33.55)
V3P3A: length 213.5
  TOP w0.102: U7.H6 v1(40.32,56.12)
  TOP w0.203: v1(49.94,30.17) 50.1,30.33 U23.28
  TOP w0.254: U7.T14 31.82,64.58 v1(31.35,64.11) ; U7.P16 v1(29.24,63.21) ; R7.1 79.9,68.66 78.74,68.66 v1(78.31,68.22) ; U7.A3 42.82,49.19 v1(42.96,49.05) ; U7.T3 43.28,64.16 v1(43.28,64.08) ; U7.C1 v1(44.33,51.13) ; U3.28 88.92,67.6 v1(89.26,67.26) ; U7.J6 v1(40.32,58.12) ; U7.A14 31.82,49.6 v1(31.37,49.15) ; v1(37.32,60.05) 37.4,60.05 U7.L8 ; U7.L9 v1(36.32,60.12) ; U7.P1 44.83,62.62 v1(45.26,63.05) ; U7.J11 v1(34.32,58.12) ; v1(204.6,67.31) 204.22,67.31 203.96,67.05 P1.199 ; U14.AG42 v1(125.17,39.45) ; U7.F9 v1(36.32,54.12) ; U7.F8 v1(38.32,54.12) ; U7.H11 v1(34.32,56.12)
  TOP w0.305: v1(29.21,51.18) 29.65,51.62 U7.C16
  TOP w0.381: R18.1 80.2,61.4 79.83,61.77 78.31,61.77 v1(77.85,62.23) ; v1(81.31,21.18) 81.34,21.15 C123.1 ; C9.1 132.68,69.43 v1(132.72,69.47)
  TOP w0.508: C81.1 52.13,38.93 v1(52.2,38.99) ; C7.1 125.22,69.27 v2(125.68,68.81) ; v2(124.66,68.63) 124.21,69.09 C8.1 ; U10.1 101.77,49.26 102.1,48.93 R40.1 101.33,48.51 v1(100.97,48.87) ; v1(40.59,39.29) 40.39,39.09 40.39,38.05 U13.5 ; U4.1 v1(15.68,60.3) ; v1(54.1,63.12) 54.1,62.8 54.05,62.76 54.05,62.72 53.87,62.54 53.87,62.45 53.73,62.3 53.59,62.3 L2.1 53.34,62.25 C28.1 ; C5.1 71.95,70.9 ; C5.1 71.95,69.77 ; C5.1 72.47,70.36 ; U8.8 23.15,53.14 v1(23.05,53.04) ; 25.78,60.83 v1(26.67,60.83) ; J3.1 40.13,68.4 40.28,68.25 40.38,68.25 40.56,68.07 v1(40.64,68.07) ; v1(14.22,60.07) 13.78,60.51 U4.2 ; R16.1 78.02,63.23 v1(77.98,63.19) ; U1.5 44.73,71.36 45.24,70.85 v1(45.45,70.85) ; JP3.4 59.36,58.6 60.22,59.46 60.22,62.89 v1(60.58,63.25) ; U5.8 v1(17.4,61.09) ; J2.1 v1(36.58,67.94) ; C12.1 v2(72.96,70.29) ; v1(32,68.07) 32.38,68.07 32.89,68.58 J1.1 ; v1(48.29,57.44) 48.35,57.44 48.93,56.86 U6.1 ; C55.1 49.53,48.46 49.53,49.66 v1(48.26,50.93) ; R74.1 50.8,37.76 v1(51.09,38.05) ; C89.1 59.79,37.43 v1(59.79,36.63) 60.12,36.3 R79.1 ; R118.1 81.04,20.92 v1(81.31,21.18) ; U11.5 37.73,45.18 37.5,45.42 v1(37.26,45.42) ; C17.1 v1(68.95,71.22) ; R72.1 v1(51.94,38.11)
  TOP w0.762: v2(68.34,64.48) 68.4,64.41 72.87,64.41 Q2.2 ; C61.1 45.21,46.69 v2(44.93,46.96) ; 17.22,69.6 C4.1 Q1.3 ; 17.22,69.6 v2(16.76,69.14) ; 17.22,69.6 17.27,69.6 v2(17.88,68.99)
  L3_SIG w0.508: v1(107.29,32.97) 107.5,33.18 107.5,33.88 108,34.39 108.84,34.39 110.24,35.79 111.96,35.79 v1(112.19,35.56)
  BOTTOM w0.102: 125.27,38.8 125.21,38.74 C331.1
  BOTTOM w0.254: 124.46,68.07 124.58,67.95 U38.10 125.15,68.38 ; R148.2 140.02,68.26 139.19,69.09 U37.5 ; v1(108.2,4.19) 108.2,4.21 107.57,4.84 107.57,10.13 106.12,11.58 105.17,11.58 104.15,12.6 99.35,12.6 98.8,12.06 98.8,10.65 97.55,9.4 97.54,9.4 97.35,9.21 R350.2 R351.2 ; v1(58.12,32.28) 58.34,32.28 58.86,31.76 R273.1
  BOTTOM w0.305: v1(125.17,39.45) 125.27,39.35 125.27,38.8
  BOTTOM w0.381: 124.46,10.35 125.09,10.35 125.48,10.73 R337.1 ; 124.46,10.35 v1(124.46,9.4) ; 124.46,10.35 122.68,10.35 R343.1 ; v1(89.26,67.26) 88.85,66.85 C190.1 88.48,66.07 C195.1 ; v1(18.03,60.33) 17.72,60.01 C222.1 ; v1(49.94,30.17) 49.99,30.12 C405.1 C400.1 ; R356.1 v1(109.01,3.3) ; R203.1 19.43,51.54 v1(20.07,52.17) 20.45,51.79 C255.1 ; v1(18.67,52.17) 18.41,51.92 R204.1 ; P4.199 191.33,67.05 v1(191.69,67.41) ; U37.5 138.38,68.91 137.44,67.97 135.48,67.97 134.06,69.39 U36.5 ; C202.1 43.96,64.97 R162.1 ; R252.1 v1(54.79,36.25) ; R168.1 v1(27.94,62.36)
  BOTTOM w0.508: v1(29.24,63.21) 29.54,62.9 C211.1 ; v1(34.32,58.12) 34.27,58.18 C223.1 ; R200.2 v1(25.02,50.6) ; C236.1 34.32,55.49 v1(34.32,56.12) ; R191.2 v1(27.28,56.11) ; v1(63.12,66.93) 63.12,65.98 R159.1 ; C245.1 36.32,54.11 v1(36.32,54.12) ; R141.1 v1(52.48,69.72) ; v2(17.88,68.99) 17.98,69.09 C185.1 ; C218.1 36.05,60.39 v1(36.32,60.12) ; v1(48.26,50.93) 45.57,50.93 C258.1 44.74,50.71 v1(44.33,51.13) ; v1(45.26,63.05) 44.85,62.64 C214.1 ; C194.1 69.46,64.48 v2(68.34,64.48) ; v1(22.4,63.17) 21.91,62.67 R169.1 R170.1 R171.1 ; v1(60.58,63.25) 62.27,63.25 C206.1 ; J5.1 46.15,52.58 v1(45.42,51.84) ; R244.2 111.71,37.31 111.43,37.03 v1(111.43,36.93) ; v1(28.32,65.02) 28.51,65.21 R158.2 ; C274.1 v1(42.96,49.05) ; R199.1 v1(26.04,50.47) 25.49,49.92 R208.2 ; v1(60.07,40.26) 60.13,40.32 C314.1 ; 34.92,67.12 v1(34.92,67.82) ; 34.92,67.12 R154.2 ; 34.92,67.12 33.91,67.12 R156.2 ; C217.1 37.19,60.17 v1(37.32,60.05) ; v1(36.58,67.94) 37.27,67.25 R153.2 R152.2 R151.2 39.88,67.31 v1(40.64,68.07) ; R145.1 205.93,67.56 v1(206.38,67.56) ; v1(17.4,61.09) 18.1,61.79 C213.1 ; v1(38.32,54.12) 38.37,54.08 C244.1 ; v1(45.45,70.85) 45.47,70.87 46.16,70.87 46.35,70.68 C183.1 ; v1(29.21,51.18) 29.15,51.24 C247.1 ; v1(31.35,64.11) 31.42,64.05 C203.1 ; U36.5 132.79,69.39 v1(132.72,69.47) ; v1(112.19,35.56) 112.29,35.56 112.42,35.43 113.22,35.43 R254.2 ; v1(62.99,61.59) 63.06,61.53 R176.1 ; R251.1 59.28,35.91 59.79,36.41 v1(59.79,36.63) ; v1(25.91,35.43) 25.64,35.7 C348.1 ; v2(124.66,68.63) 124.41,68.38 R146.1 123.82,69.21 ; R194.1 v1(21.02,53.4) ; C228.1 40.5,57.95 v1(40.32,58.12) ; R150.2 28.51,67.63 v1(28.7,67.82) ; R160.1 v1(206.38,65.53) ; R187.1 18.99,57.49 v1(19.41,57.91) ; 107.35,32.91 v1(107.29,32.97) ; 107.35,32.91 107.36,32.9 R267.2 ; 107.35,32.91 C399.1 ; R218.1 36.13,47.18 v1(36.55,46.76) ; R190.1 48.9,56.51 48.37,57.04 48.37,57.36 v1(48.29,57.44) ; v1(77.85,62.23) 77.85,62.12 78.36,61.61 79.09,61.61 79.67,62.2 R172.1 ; C202.1 43.38,63.98 v1(43.28,64.08) ; C433.1 43.18,27.81 v1(43.56,28.19) ; C277.1 31.48,49.04 v1(31.37,49.15) 31.2,49.31 R207.1 ; R175.2 v1(28.07,60.96) ; R193.1 v1(23.05,53.04) 22.99,52.97 C249.1 ; C230.1 40.09,56.35 v1(40.32,56.12) ; R163.1 v1(206.38,64.52) ; R205.1 v1(17.4,52.17) ; R195.2 v1(17.84,53.35)
  BOTTOM w0.762: v2(68.34,64.48) 68.28,64.54 R161.1
  vias: v2(72.39,71.27)
V5A: length 54.9
  TOP w0.254: N12.1 61.65,34.68 61.65,37.8 62.2,38.35 62.97,38.35 62.97,38.36 63.37,38.76 v2(63.55,38.76) 63.7,38.91 64.67,38.91 65.1,39.52 ; U2.3 99.79,65.35 99.34,64.9 C24.1 ; v2(97.99,64.52) 97.74,64.52 96.67,65.58 R8.1 96.69,67.94 97.41,67.94 97.7,68.23 U2.20 ; C126.2 79.05,20.47 79.67,19.85 U28.4 ; U12.3 63.9,39.93 v2(64.06,39.78) 63.8,39.52 61.06,39.52 60.71,39.88 60.71,41.91 60.74,41.95 R54.1 61.19,42.47 61.55,42.83 U12.20
  TOP w0.305: v1(47.07,13.13) 47.29,13.35 U29.1 ; C154.2 122.28,10.85 U30.4
  TOP w0.381: C124.2 123.67,19.5 U26.4 ; v1(94.84,43.38) 94.87,43.36 C67.1 ; C79.1 v1(82.37,40.01)
  TOP w0.508: v2(7.49,43.56) 7.49,43.69 7.81,44.01 7.81,44.13 ; L4.1 C64.1 7.81,44.13 ; 7.81,44.13 8.38,43.56 v2(8.64,43.56) ; v1(134.95,5.97) 135.25,5.66 C164.2 ; C124.2 124.76,19.99 v2(124.76,19.23) ; v2(122.22,9.4) 122.3,9.4 122.75,9.85 C154.2 ; C24.1 98.12,64.39 v2(97.99,64.52) ; C82.1 65.1,39.52 64.31,39.52 v2(64.06,39.78) ; v2(78.82,21.46) C126.2 ; C131.1 62.23,19.81
  TOP w0.762: Q2.3 66.73,63.12 66.17,63.68 v2(66.17,64.39)
  BOTTOM w0.305: v1(47.07,13.13) 47.23,12.97 R339.2 C484.2
  BOTTOM w0.381: v1(132.05,51.31) 132.88,52.13 C246.2 ; R354.1 v1(108.21,5.1) ; v1(131.6,60.71) 132.08,60.22 C220.2 ; C338.1 v1(26.97,38.61)
  BOTTOM w0.762: v2(66.17,64.39) 66.17,62.69 C212.1
  vias: v2(62.66,39.45) v2(65.15,64.14) v2(65.68,20.95) v2(65.68,19.68) v2(65.68,18.41) v2(66.95,20.95) v2(66.95,19.68) v2(66.95,18.41)
V12A: length 72.2
  TOP w0.254: v1(62.71,31.72) 62.71,31.83 61.96,32.58 N14.1 ; 16.13,41.4 16.24,41.29 U17.15 ; U17.16 15.74,41.27 ; U17.14 16.74,41.38 ; U2.14 100.49,69.63 v1(100.36,69.49) ; 15.49,41.27 15.24,41.02 U17.17 ; 68.86,25.65 69.29,26.08 U25.13 69.29,27.44 68.99,27.74 ; U17.13 17.24,41.37 ; U12.16 62.75,45.45
  TOP w0.381: R19.1 81.92,60.96 v1(81.66,60.71) ; v1(83.29,28.8) 84,28.8 84.96,27.84 C113.1 ; U18.5 71.85,34.92 ; C38.1 84.99,56.92 v1(84.91,56.85) ; C150.2 127.94,12.62 v1(127.56,12.24) ; C75.1 82.45,41.1 v1(82.37,41.02) ; C85.1 82.22,38.99 v1(82.04,38.81) ; v1(102.54,65.66) 102.77,65.43 C23.1 ; C87.1 v1(82.04,37.97) ; U18.2 69.07,34.92 ; U18.6 71.46,36.1
  TOP w0.508: R36.1 14.81,48.82 v1(15.49,48.13) ; C69.1 C68.1 15.37,41.91 ; C69.1 16.38,41.78 ; C69.1 16.95,42.48 v1(17.21,42.23) ; 16.37,6.78 16.37,7.61 16.74,7.98 ; C127.1 40.67,20.09 ; v1(61.47,38.84) 58.2,38.84 R68.1
  TOP w0.635: S1.A81 16.37,6.78 16,6.78 15.37,6.15 S1.A82 ; S1.A2 97.42,6.54 97.13,6.83 v2(96.82,6.83) 96.82,6.78 96.42,6.37 S1.A3
  TOP w0.762: U18.7 70.51,36.07
  BOTTOM w0.254: v1(100.36,69.49) 100.55,69.68 C178.1
  BOTTOM w0.381: R276.1 62.8,31.64 v1(62.71,31.72) ; C452.1 v1(85.6,20.45)
  BOTTOM w0.508: C472.1 v2(43.18,16.51) ; v1(17.21,42.23) 17.21,46.42 v1(15.49,48.13) ; C469.1 v2(43.18,17.91) ; v1(61.34,40.26) 61.02,40.58 C314.2 ; C433.2 v1(43.18,25.4) ; C348.2 24.75,35.67 v1(24.51,35.43)
  BOTTOM w0.635: S1.A3 96.42,6.37 96.82,6.78 v2(96.82,6.83) 97.13,6.83 ; S1.B1 98.42,6.23 v2(97.79,6.86) 97.76,6.83 97.13,6.83 ; 97.13,6.83 97.42,6.54 S1.A2
  vias: v1(63.42,43.97) v1(64.57,43.94) v1(99.36,69.47) v2(22.66,12.09) v2(22.66,10.82) v2(23.37,41.66) v2(23.37,40.51) v2(23.93,12.09) v2(23.93,10.82) v2(24.51,41.66) v2(24.51,40.51) v2(25.2,12.09) v2(25.2,10.82) v2(42.04,17.91) v2(42.04,16.51) v2(61.75,47.75) v2(61.77,46.58) v2(62,25.68) v2(62.2,26.8) v2(62.87,47.73) v2(63.02,46.53) v2(69.7,37.82) v2(69.72,36.75) v2(70.84,37.87) v2(70.89,36.73) v2(95.58,71.12) v2(95.58,70.05) v2(95.58,69.04) v2(95.55,68.02) v2(95.58,11.53) v2(96.67,11.53) v2(97.23,7.62) v2(105.49,12.34) v2(106.71,12.34)
V12A_PM_V1P0: length 12.8
  TOP w0.203: v1(112.65,5.23) 112.65,5.23 U31.9
  TOP w1.016: L13.1 107.71,13.72 108.17,13.26 108.41,13.26 108.46,13.21 108.5,13.21 108.65,13.06 C145.1 C146.1
  L8_SIG w0.254: v1(112.65,5.23) 112.65,5.85 113.03,6.22 115.44,6.22 115.95,6.73 115.95,9.14 v1(116.46,9.65)
VCC3P3_SATA1: length 11.9
  TOP w0.762: v2(3.74,43.1) 4.38,42.46 L6.2 C76.1 4.05,40.81 v2(3.58,41.27)
  BOTTOM w0.762: P3.9 4.23,41.93 v2(3.58,41.27) 4.2,40.66 P3.8 ; v2(3.74,43.1) 3.84,43.2 P3.10
VCC5_SATA1: length 16.9
  TOP w0.508: v2(3.57,50.82) 3.59,50.8 C42.1 C46.1 ; C51.1 3.81,48.39 v2(3.7,48.28) ; C51.1 C46.1 ; C51.1 5.27,47.05 C57.1 5.78,46.42 L4.2 ; v2(3.66,49.55) 3.68,49.53 C46.1
  BOTTOM w0.762: P3.14 v2(3.7,48.28) ; P3.15 v2(3.66,49.55) ; P3.16 v2(3.57,50.82)
VCCA_PCIE_1P0: length 0.7
  TOP w0.102: U14.AW38 U14.AW39
VCCA_PLLDDR0_AVN: length 19.2
  TOP w0.254: v1(131.57,43.45) U14.AU31
  L3_SIG w0.254: v1(131.57,43.45) 131.55,43.45 131.05,43.95 130.3,43.95 129.15,45.09 128.38,45.09 128.03,45.45 128.03,52.36 126.15,54.25 125.81,54.25 v1(124.84,55.22)
  BOTTOM w0.254: L16.1 124.6,57.63 C233.1 124.6,55.46 v1(124.84,55.22)
VCCA_PLLDDR1_AVN: length 19.8
  TOP w0.254: U14.W31 v1(130.77,35.45)
  TOP w0.381: v1(130.05,21.41) 130.05,21.21 129.54,20.7 128.93,20.7 L12.1
  L3_SIG w0.381: v1(130.05,21.41) 128.96,21.41 127.99,22.38 127.99,25.22 129.91,27.14 129.91,34.59 v1(130.77,35.45)
  BOTTOM w0.305: v1(130.77,35.45) 130.55,35.24 C353.1
VCCACKDDR_0: length 19.3
  TOP w0.254: U14.AT32 v1(130.77,43.45) U14.AU32
  BOTTOM w0.254: L17.2 125.73,56.93 125.73,54.1 126.62,53.21 127.25,53.21 128.27,52.2 129.06,52.2 130.49,50.76 130.49,50.32
  BOTTOM w0.305: v1(130.77,43.45) 130.21,44.01 C296.1 130.21,44.81 130.01,45.02 130.01,49.23 130.49,49.72 130.49,50.32
VCCACKDDR_1: length 44.8
  TOP w0.254: v1(126.25,56.35) 125.45,57.14 125.45,57.64 125.22,57.87 L3.2 ; U14.V28 v1(133.17,34.65) U14.W28
  L3_SIG w0.127: 135.38,43.55 135.38,43.51 ; 135.38,43.51 135.38,43.45 134.98,43.05 133.33,43.05 133.32,43.05 132.89,43.05 132.55,43.39 132.55,43.89 135,43.89 135.38,43.51 ; 136.03,35.21 135.87,35.05 135.27,35.05 134.41,34.19 133.62,34.19 v1(133.17,34.65) 133.17,34.8 133.56,35.2 133.56,35.7 133.72,35.87 134.17,35.87 135.05,36.75 135.84,36.75 136.05,36.54 136.71,36.54 136.83,36.67
  L3_SIG w0.254: 136.03,35.21 136.83,36.02 136.83,37.52 136.98,37.67 136.98,39.47 136.84,39.61 136.84,42.09 135.38,43.55 ; v1(126.25,56.35) 129.16,53.44 129.16,49.9 129.67,49.4 129.67,45.35 130.58,44.44 131.59,44.44 132.13,43.89 132.55,43.89
  BOTTOM w0.305: C380.1 133.12,34.07 133.12,34.61 v1(133.17,34.65)
VCCCLKDDR0: length 28.8
  TOP w0.254: U14.AU29 132.35,43.47 132.35,42.68 ; 132.35,42.68 132.34,42.68 U14.AT29 ; 132.35,42.68 v1(132.37,42.66)
  L10_SIG w0.254: v1(137.5,57.34) 137.5,56.1 136.4,54.99 134.97,54.99 133.87,53.9 133.02,53.9 132.37,53.25 132.37,52.83 130.62,51.08 130.62,49.92 129.93,49.23 129.93,44.69 130.34,44.28 131.54,44.28 132.4,43.42 132.4,42.68 v1(132.37,42.66)
  BOTTOM w0.254: v1(137.5,57.34) 137.55,57.29 138.05,57.29 C231.1 138.24,57.1 139.17,57.1 C232.1 L15.2
  BOTTOM w0.305: C289.1 131.58,44.15 132.4,43.34 132.4,42.68 v1(132.37,42.66)
VCCCLKDDR1: length 20.4
  TOP w0.254: U14.W29 v1(132.37,34.65) U14.V29
  L3_SIG w0.254: v1(130.57,24.61) 130.44,24.74 130.44,32.75 132.34,34.65 v1(132.37,34.65)
  BOTTOM w0.305: v1(132.37,34.65) 132.39,34.63 C383.1
  BOTTOM w0.381: L19.2 133.7,19.67 131.23,22.13 C451.1 131.05,22.62 C446.1 130.57,24.07 v1(130.57,24.61)
VCCP: length 61.1
  TOP w0.102: 144.58,37.94 v1(144.58,37.94)
  TOP w0.127: U14.AD21 v1(135.57,37.85) ; v1(134.77,37.85) U14.AD23
  TOP w0.203: U14.AE1 146.87,37.72 v1(147.1,37.94) ; v1(146.97,39.16) U14.AH1
  TOP w0.254: U14.AJ23 v1(134.77,40.25) U14.AJ25 v1(133.97,40.25) U14.AJ26 ; v1(133.97,37.85) U14.AD26 ; v1(133.97,37.85) U14.AF26 ; v1(133.97,37.85) U14.AD25 v1(134.77,37.85) U14.AF25 ; v1(145.24,39.68) 145.27,39.65 U14.AH3 ; v1(145.24,39.68) 145.48,39.91 U14.AJ2 ; v1(145.24,39.68) 145.09,39.83 U14.AJ4 ; U14.AJ21 v1(136.37,39.45) ; v1(136.37,39.45) U14.AK20 ; v1(136.37,39.45) U14.AG21 ; v1(136.45,38.63) 136.64,38.82 U14.AG19 ; U14.AJ5 143.89,39.67 143.89,39.67 143.49,39.67 143.49,39.67 143.45,39.67 U14.AH7 143.28,39.52 v1(142.93,39.17) ; v1(142.93,39.17) 142.96,39.17 U14.AG7 ; v1(142.93,39.17) U14.AH8 ; U14.AL21 v1(135.57,41.05) U14.AL23 v1(134.77,41.05) U14.AL25 v1(133.97,41.05) U14.AL26 ; U14.AF23 v1(135.57,37.85) U14.AD23 ; U14.AG17 U14.AG19 ; U14.AG19 U14.AH19 ; U14.AH10 v1(142.17,39.17) 142.2,39.17 U14.AG8 ; U14.AG11 141,38.82 140.66,39.16 v1(140.65,39.16) 140.65,39.17 U14.AH13 ; U14.AE5 144.58,37.94 ; U14.AF21 v1(136.37,37.85) U14.AF20 ; v1(136.37,37.05) U14.AD21 ; U14.AG13 140.23,38.82 v1(139.88,39.17) U14.AH14 ; U14.AH4 144.51,38.74 U14.AF4 144.76,38.11 v1(144.58,37.94) ; U14.AH16 139.09,39.2 139.11,39.18 v1(139.11,39.18) 139.47,38.82 U14.AG14
  TOP w0.381: v1(87.33,56.85) 87.25,56.92 C38.2 ; C74.1 90.75,42.34 v2(90.47,42.62) ; C23.2 102.25,64.05 v1(101.98,63.78) ; 84.68,41.81 83.97,41.1 C75.2 ; C73.1 86.74,42.49
  BOTTOM w0.254: v1(77.11,44.04) 76.59,43.52 N37.1 ; v1(133.97,37.85) 133.94,37.88 C337.1 ; v1(149.25,37.82) 149.25,37.74 148.97,37.47 R246.1
  BOTTOM w0.381: C340.1 136.86,37.85 v1(136.37,37.85) ; C351.1 136.19,36.88 v1(136.37,37.05) ; C297.1 98.98,45.47 99.19,45.67 v1(99.19,45.8) ; v1(142.17,39.17) v1(142.93,39.17) 143.18,38.92 C336.1 ; v1(125.22,53.72) 124.9,54.04 C239.1 ; v1(136.45,38.63) 136.53,38.56 C335.1 ; C334.1 140.27,38.56 140.65,38.94 v1(140.65,39.16) ; v1(139.11,39.18) 139.31,39.18 139.69,39.56 C322.1 139.88,39.6 v1(139.88,39.17) ; v1(136.37,39.45) 136.73,39.81 C317.1 ; v1(134.77,37.85) 134.95,37.67 C345.1 ; v1(149.38,41.03) 149.95,41.03 150.19,41.27 150.19,42.29 C302.1 ; C321.1 135.64,40.98 v1(135.57,41.05) ; v1(134.77,40.25) 134.7,40.18 C328.1 ; C302.1 149.94,42.37 v1(148.62,41.05) ; C302.1 150.27,43.18 v1(150.88,43.79) ; v1(94.79,45.11) 93.98,44.3 C298.1 ; v2(91.74,45.11) 91.77,45.09
  BOTTOM w0.508: v2(89.15,42.6) 88.6,42.04 C313.1 ; C238.1 126.67,54.51 v1(126.24,54.94) ; v1(145.24,39.68) 145.44,39.87 145.44,40.5 C309.1 146.3,40.5 146.3,39.7 146.84,39.16 v1(146.97,39.16)
  vias: v2(87.88,45.14) v2(87.88,43.87) v2(87.88,42.6) v2(89.15,45.14) v2(89.15,43.87) v2(90.47,45.11) v2(90.47,43.84) v2(91.74,43.84) v2(91.74,42.57)
VCCP_RCSM: length 28.1
  TOP w0.152: R59.2 81.5,40.84 v1(80.82,40.84) ; R98.2 v1(62.94,29.62)
  TOP w0.254: R97.1 60.47,29.62 R98.2
  L8_SIG w0.152: v1(62.94,29.62) 63.09,29.47 65.31,29.47 67.23,31.39 67.23,33.42 68.26,34.44 68.6,34.44 69.88,34.44 71.65,36.22 71.65,37.56 72.53,38.43 75.13,38.43 76.45,39.75 78.87,39.75 79.96,40.84 v1(80.82,40.84)
VCCP_RCSP: length 28.1
  TOP w0.152: v1(80.82,40.06) 81.06,39.81 R59.1 ; R98.1 v1(62.94,28.73)
  TOP w0.254: R100.1 61.29,28.54 R98.1
  L8_SIG w0.152: v1(80.82,40.06) 80,40.06 79.29,39.34 76.68,39.34 75.36,38.02 72.69,38.02 72.06,37.39 72.06,35.99 70.1,34.04 68.43,34.04 67.64,33.25 67.64,31.56 67.64,31.23 65.47,29.06 63.27,29.06 v1(62.94,28.73)
VCCP_TSEN_N: length 8.2
  TOP w0.203: v1(59.94,32.41) 60.05,32.51 N13.1
  TOP w0.254: R110.2 57.76,26.38 v1(57.76,26.72)
  L8_SIG w0.254: v1(59.94,32.41) 59.94,31.88 58.9,30.84 58.9,28.68 57.76,27.53 v1(57.76,26.72)
VCCP_TSEN_P: length 11.6
  TOP w0.178: R86.2 C102.1 57.84,33.05 56.72,31.93 U23.7
  TOP w0.203: v1(59.13,32.39) 59.03,32.5 R86.2
  TOP w0.254: R110.1 56.5,26.35 v1(56.87,26.72)
  L8_SIG w0.254: v1(59.13,32.39) 59.05,32.32 59.05,31.78 58.32,31.04 58.32,29.03 56.87,27.58 v1(56.87,26.72)
VCCP_VR_HOT_N: length 83.8
  TOP w0.102: U7.F3 v1(43.32,54.12)
  TOP w0.127: U23.16 53.32,35.07 53.28,35.12 v1(53.28,35.15)
  TOP w0.178: U3.16 86.01,63.22 v1(86,63.22)
  L3_SIG w0.097: v1(43.32,54.12) 43.16,54.12 42.83,54.45 42.83,55.35 43.8,56.32 43.8,57.14 44.94,58.28 45.76,58.28 47.8,60.32 48.48,60.32 50.62,62.46 55.16,62.46 55.49,62.79 58.6,62.79 61.09,60.29 80,60.29 81.68,61.97 84.56,61.97 85.74,63.15 85.93,63.15 v1(86,63.22) ; v1(41.15,42.52) 41.68,41.99 42.09,41.99 46.86,37.21 52.41,37.21 53.28,36.35 v1(53.28,35.15)
  L8_SIG w0.097: v1(43.32,54.12) 43.32,53.43 44.88,51.87 44.88,49.07 42.93,47.12 42.93,45.34 41.15,43.56 v1(41.15,42.52)
  BOTTOM w0.203: R252.2 53.74,35.13 53.3,35.13 v1(53.28,35.15)
VDDQ_CPU_DDR: length 402.3
  TOP w0.152: U14.BG9 142.12,48.7 142.12,47.1 U14.BC10
  TOP w0.203: U14.L5 v1(143.83,30.16) U14.J5 ; U14.G7 v1(143.71,28.46) U14.G5 ; U14.K26 v1(134.06,30.61) ; U14.E7 142.92,27.99 v1(142.34,27.41) 142.34,27.95 U14.E9 ; U14.K18 138.01,30.59 138.02,30.59 v1(138.04,30.61) ; U14.BC13 139.83,47.07 v1(139.8,47.1) ; v1(136.04,32.52) U14.R22 ; U14.BK13 140.31,50.53 v1(140.31,50.62) 140.34,50.62 U14.BK12
  TOP w0.254: U14.BH17 v1(138.49,49.01) U14.BG15 ; U14.M3 v1(145.71,31.42) ; P1.110 195.42,40.35 195.68,40.6 v1(195.68,40.65) ; P1.85 203.54,32.85 v1(204.03,33.34) ; U14.H14 v1(140.02,28.71) U14.H13 ; U14.L22 135.69,30.58 v1(136.04,30.23) U14.L21 ; U14.P25 v1(134.06,32.9) U14.P26 ; P1.101 v1(204.02,37.65) ; U14.N13 v1(140.64,31.23) ; P1.94 195.6,35.55 v1(195.9,35.85) ; v1(204.22,40.51) 204.09,40.51 203.63,40.05 P1.109 201.27,40.05 201.06,39.84 200.11,39.84 v1(199.6,40.35) ; U14.BF13 140.44,47.94 140.84,47.94 v1(141.1,47.68) ; v1(204.01,44.63) 203.76,44.63 203.38,44.25 P1.123 ; U14.P18 137.68,32.55 v1(138.04,32.9) 138.38,32.56 U14.P17 ; 143.88,50.74 143.73,50.59 U14.BL7 ; 143.88,50.74 v1(143.89,50.75) ; 143.88,50.74 U14.BK6 ; v1(203.96,46.99) 203.62,46.65 P1.131 ; v1(191.57,33.22) 191.9,32.89 192.87,32.89 193.13,33.15 P1.86 195.6,33.15 v1(195.9,33.45) ; v1(203.96,35.25) P1.93 ; U14.BC15 139.74,47.07 139.78,47.07 v1(139.8,47.1) ; v1(113.86,69.79) 115.33,69.79 116.58,68.54 116.94,68.48 117.02,68.53 ; P1.124 195.66,44.55 v1(195.86,44.75) ; U14.BM9 142.19,50.77 v1(142.18,50.76) 142.16,50.74 U14.BK9 ; U14.BC10 142.23,46.36 v1(142.24,46.1) ; U14.BJ4 145.33,49.96 145.47,50.09 v1(145.6,50.09) ; v1(195.85,42.03) 195.81,42 195.34,42 195.19,42.15 P1.116 ; U14.BE19 v1(137.79,47.49) 138.14,47.14 U14.BD17 ; v1(133.81,48.25) 133.8,48.24 U14.BE26 ; U14.AY19 v1(137.79,45.97) ; U14.K17 138.06,30.58 138.06,30.59 v1(138.04,30.61) ; v1(195.63,47.22) 195.36,46.95 P1.132 193.11,46.95 192.88,47.18 192.17,47.18 191.86,46.86 v1(191.74,46.86) ; U14.BC7 v1(143.66,46.39) ; v1(134.06,30.61) U14.K25 ; U14.K10 141.31,30.6 141.07,30.6 v1(141.01,30.66) ; U14.BD21 136.15,47.52 v1(135.8,47.87) 135.45,48.22 U14.BF23 ; v1(199.58,42.15) 200.27,42.15 200.57,41.85 P1.115 203.52,41.85 v1(203.96,42.29) ; v1(134.68,47.57) 134.63,47.57 134.17,47.11 U14.BD25 ; U14.R21 v1(136.04,32.52) ; U14.AY21 135.83,45.56 135.83,45.58 v1(135.81,45.59) 135.8,45.57 135.79,45.57 U14.AY23 ; P1.102 195.6,37.95 v1(195.9,38.25) ; U14.N14 v1(139.88,31.23)
  TOP w0.381: R136.1 153.05,1.84 v1(153.29,1.6) ; C97.1 191.97,35.25 192.48,35.76 v1(192.51,35.76) 192.72,35.55 P1.94 ; P1.102 194.1,37.97 193.01,37.97 v1(192.72,38.25) 192.56,38.25 192.17,37.87 191.65,37.87 191.57,37.95 C88.1 ; C56.1 191.36,47.25 v1(191.74,46.86) ; U32.6 144.17,2.48 R131.1 C166.1 v1(146.05,1.47) ; v1(191.57,33.22) 190.88,33.91 C99.1 ; v1(131.55,10.11) 131.55,10.57 130.82,11.29 C150.1 ; v1(199.63,44.55) 199.77,44.41 201.08,44.41 201.24,44.25 P1.123 ; P1.110 192.77,40.35 v1(192.47,40.65) 192.16,40.35 191.51,40.35 191.2,40.65 C77.1 ; C72.1 191.41,42.15 v1(191.71,41.85) 191.71,41.9 192.23,42.42 192.71,42.42 192.98,42.15 P1.116 ; U34.6 162.2,2.1 R133.1 C167.1 164.34,1.65 v1(164.08,1.4) ; P1.124 192.01,44.55 v1(191.71,44.25) 191.41,44.55 C65.1
  TOP w0.508: v1(48.01,68.2) 48.64,67.56 R9.1 ; v2(129.46,71.7) 129,71.24 R5.1 129.8,70.57 v2(129.92,70.68) ; v1(13.46,58.29) C30.1 ; C164.1 136.69,5.17 137.01,4.85 137.01,4.62 v1(137.03,4.6) ; v1(171.58,1.4) 171.51,1.46 R138.1
  L3_SIG w0.508: v1(43.43,69.6) 43.56,69.6 44.96,68.2 v1(48.01,68.2) 49.17,67.03 56.59,67.03 58.34,65.28 58.34,63.83 61.21,60.96 65.74,60.96 66.8,62.03 69.98,62.03 70.82,62.87 74.42,62.87 v1(75.44,61.85) 77.6,64.01 78.84,64.01 79.58,64.74 90.17,64.74 90.3,64.87 96.29,64.87 v1(96.65,64.52) 97.43,63.73 99.09,63.73 100.23,64.87 106.63,64.87 107.65,63.86 115.75,63.86 117.02,65.13 117.02,66.22 117.86,67.06 v2(119,67.06)
  L5_SIG w0.508: v1(43.43,69.6) 43.43,69.57 42.95,69.09 28.83,69.09 v1(27.56,67.82) 24.99,65.25 16.48,65.25 13.46,62.23 v1(13.46,58.29) 13.46,51.56 20.65,44.37 24.69,44.37 v1(25.17,44.86) 27.28,42.75 38.13,42.75 39.29,41.58 v1(39.29,39.32)
  BOTTOM w0.178: C273.1 138.92,48.41 138.92,48.58 v1(138.49,49.01)
  BOTTOM w0.254: P4.110 v1(199.6,40.35) ; P4.109 191.87,40.05 v1(192.47,40.65) ; C226.1 142.48,59.47 v1(142.43,59.53) ; P4.131 191.53,46.65 v1(191.74,46.86) ; v1(143.89,50.75) 143.96,50.75 144.03,50.82 144.36,50.82 C251.1 ; v1(192.51,35.76) 192.46,35.71 192.33,35.71 191.87,35.25 P4.93 ; P4.85 191.2,32.85 v1(191.57,33.22) ; N27.1 v1(113.86,69.79) ; C252.1 145.39,50.95 145.39,50.32 145.54,50.16 145.54,50.15 v1(145.6,50.09) ; v1(191.71,41.85) 191.7,41.85 P4.115 ; v1(199.77,46.82) 199.64,46.95 P4.132 ; v1(200.09,37.95) 200.09,37.95 P4.102 ; P4.123 191.71,44.25 v1(191.71,44.25) ; P4.101 191.87,37.65 192.47,38.25 v1(192.72,38.25) ; P4.94 200.09,35.55 v1(200.09,35.55) ; P4.124 v1(199.63,44.55) ; v1(141.01,30.66) 140.97,30.62 140.97,30.29 140.82,30.14 C415.1 ; v1(199.58,42.15) P4.116 ; v1(199.85,33.6) 199.39,33.15 P4.86
  BOTTOM w0.305: U38.2 128.92,67.45 129.31,67.84 129.31,68.61 v2(129.36,68.66) ; C423.1 139.74,28.43 v1(140.02,28.71) ; v1(143.71,28.46) 143.95,28.22 C424.1
  BOTTOM w0.381: C279.1 144.09,46.82 v1(143.66,46.39) ; v1(140.64,31.23) 140.45,31.42 C391.1 139.88,31.36 v1(139.88,31.23) ; v1(134.06,30.61) 134.06,29.98 C416.1 ; v1(139.8,47.1) 139.69,46.99 C281.1 ; C402.1 145.76,31.38 v1(145.71,31.42) ; C398.1 134.38,31.84 134.04,32.18 134.04,32.88 v1(134.06,32.9) ; v1(135.81,45.59) 135.81,45.5 136.28,45.04 136.73,45.04 136.75,45.06 C291.1 ; v1(149.26,31.05) 149.21,31.01 C401.1 ; C280.1 137.19,46.57 v1(137.79,45.97) ; C417.1 138.41,30.25 v1(138.04,30.61) ; v1(142.24,46.1) 142.62,45.72 143.95,45.72 C283.1 ; v1(136.53,18.55) L19.1 C457.1 R319.1 ; C413.1 144.38,30.16 v1(143.83,30.16) ; v1(204.62,48.85) 204.34,49.12 N34.1 ; C275.1 141.11,47.68 v1(141.1,47.68) ; v1(140.31,50.62) 140.28,50.64 C256.1 ; v1(135.8,47.87) 135.09,47.87 ; 135.09,47.87 134.79,47.57 v1(134.68,47.57) ; 135.09,47.87 135.2,47.98 135.2,49 C263.1 135.41,49.12 135.71,49.43 C261.1 ; v1(199.85,33.6) 200,33.76 201.19,33.76 202.29,32.66 C396.1 ; C432.1 141.74,27.41 v1(142.34,27.41) ; C324.1 201.16,38.46 201.09,38.52 200.61,38.52 200.09,38 v1(200.09,37.95) ; C366.1 138.31,32.9 v1(138.04,32.9) ; C220.1 134.86,60.22 v1(135.59,59.49) 135.8,59.28 R182.1 137.23,58.66 L15.1 ; v1(142.18,50.76) 141.72,51.23 C248.1 ; v1(142.43,59.53) 142.76,59.86 R180.1 ; C246.1 133.78,52.58 134.11,52.91 134.11,54.93 v1(134.29,55.11) ; C427.1 C422.1 v1(149.58,28.18) ; C418.1 137.09,30.23 v1(136.04,30.23) ; N33.1 v1(205.49,48.77) ; v1(200.09,35.55) 200.09,35.51 200.61,34.98 201.98,34.98 C356.1 ; C268.1 137.34,47.94 v1(137.79,47.49) ; C424.1 143.95,27.83 R292.1 ; C276.1 199.78,46.84 v1(199.77,46.82) ; C382.1 136.36,32.83 v1(136.04,32.52) ; C439.1 147.54,25.3 147.54,26 v1(147.74,26.21) ; C385.1 v1(148.82,34.03)
  BOTTOM w0.508: v1(204.85,23.09) 205.1,22.83 C458.1 ; v1(204.03,33.34) 204.11,33.25 C386.1 ; C474.1 205.23,18.03 v1(205.23,19.18) ; v1(203.96,46.99) 203.81,46.84 C276.1 ; v1(203.96,42.29) 203.86,42.19 C301.1 ; v1(204.01,44.63) 204.24,44.86 C282.1 ; C189.1 27.15,67.41 v1(27.56,67.82) ; C237.1 204.5,54 v1(204.22,53.72) ; v2(130.68,71.57) 130.72,71.62 R139.1 ; v1(203.96,35.25) 204.39,34.82 C355.1 ; C191.1 116,67.28 C193.1 ; C285.1 v1(25.17,44.86) ; v1(204.22,40.51) 204.62,40.92 C311.1 ; R309.1 v1(205.42,24.42) ; C186.1 44.09,68.94 v1(43.43,69.6) ; C221.1 v1(204.85,56.77) ; v1(48.01,68.2) 47.88,68.07 C188.1 ; 39.41,40.77 39.41,40.34 R239.1 39.26,39.36 v1(39.29,39.32) ; 39.41,40.77 R222.1 ; 39.41,40.77 C315.1 ; C198.1 v1(96.65,64.52) ; v1(204.02,37.65) 204.24,37.87 C333.1 ; R291.1 v1(206.23,28.32) ; C215.1 v1(75.44,61.85)
  BOTTOM w0.762: v2(121.46,70) 121.46,69.82 121.16,69.52 121.16,68.1
  vias: v2(119,68.2) v2(119.25,70.1)
VDDQ_CPU_SEN_N: length 156.7
  TOP w0.254: N2.1 78.51,67.03 v1(78.31,66.83)
  L5_SIG w0.254: v1(133.53,71.45) 133.35,71.27 133.34,71.27 133.24,71.17 131.71,71.17 130.57,70.03 123.86,70.03 123.07,69.24 118.12,69.24 117.27,68.4 117.27,65.86 114.71,63.3 94.03,63.3 92.6,64.72 88.55,64.72 88.39,64.57 77.9,64.57 77.36,65.11 77.36,66.52 77.61,66.78 78.06,66.78 78.11,66.83 v1(78.31,66.83)
  BOTTOM w0.254: N31.2 N32.2 204.34,51.29 204.11,51.06 203.23,51.06 202.79,51.5 202.79,66.58 199.72,69.65 199.72,71.22 198.27,72.66 189.15,72.66 189.13,72.64 135.12,72.64 133.92,71.45 v1(133.53,71.45)
VDDQ_CPU_SEN_P: length 158.3
  TOP w0.254: N1.1 78.95,67.97 78.45,67.46 78.05,67.46 77.99,67.41 v1(77.8,67.41)
  L5_SIG w0.254: v1(133.6,70.64) 133.43,70.82 131.86,70.82 130.71,69.67 124,69.67 123.22,68.88 118.26,68.88 117.63,68.25 117.63,65.71 114.86,62.94 93.88,62.94 92.46,64.37 88.7,64.37 88.54,64.21 77.75,64.21 77,64.96 77,66.67 77.75,67.41 v1(77.8,67.41)
  BOTTOM w0.254: N33.2 N34.2 204.34,50.22 203.92,50.64 203.15,50.64 202.43,51.36 202.43,66.43 199.36,69.5 199.36,71.07 198.12,72.31 189.3,72.31 189.28,72.29 135.26,72.29 133.79,70.82 133.72,70.82 133.6,70.7 v1(133.6,70.64)
VDDQ_RCSM: length 46.7
  TOP w0.152: R15.2 v1(112.13,64.9)
  TOP w0.254: v1(76.96,69.22) 76.99,69.24 78.21,69.24 R4.2 79.39,69.55 R6.1
  L3_SIG w0.152: v1(76.96,69.22) 80.37,69.22 81.46,68.12 83.41,68.12 83.97,68.68 87.66,68.68 88.19,68.15 90.7,68.15 94.28,71.73 103.99,71.73 105,70.71 105,66.42 105.77,65.66 107.01,65.66 107.77,64.9 v1(112.13,64.9)
VDDQ_RCSP: length 46.9
  TOP w0.152: v1(113.02,64.9) R15.1
  TOP w0.254: v1(77.47,69.98) 77.47,70.18 78.31,71.02 R4.1 79.54,71.02 R2.1
  L3_SIG w0.152: v1(77.47,69.98) 77.47,69.85 77.67,69.65 80.54,69.65 81.64,68.55 83.23,68.55 84.05,69.37 91.31,69.37 94.08,72.14 103.82,72.14 104.16,72.14 105.41,70.88 105.41,66.6 105.99,66.01 107.34,66.01 108.03,65.33 112.8,65.33 113.02,65.11 v1(113.02,64.9)
VDDQ_TSEN_N: length 44.5
  TOP w0.203: N3.1 78.51,66.05 v1(78.11,66.05)
  TOP w0.254: v1(117.35,63.8) 117.31,63.77 R17.2
  L8_SIG w0.254: v1(117.35,63.8) 117.35,65.66 116.74,66.27 98.3,66.27 97.54,65.51 94.85,65.51 93.63,64.29 80.34,64.29 78.58,66.05 v1(78.11,66.05)
VDDQ_TSEN_P: length 47.6
  TOP w0.203: U3.7 80.94,66 C19.1 R11.2 79.54,66.03 v1(79.22,66.34)
  TOP w0.254: R17.1 118.2,63.72 v1(118.26,63.78)
  L8_SIG w0.254: v1(118.26,63.78) 117.83,64.21 117.83,65.79 116.84,66.78 98.04,66.78 97.28,66.01 94.55,66.01 93.33,64.8 80.85,64.8 79.3,66.34 v1(79.22,66.34)
7-SEGMENT CONTROL: length 5.3
  TOP w0.099: J4.2 26.54,59.94 26.67,60.07 30.35,60.07 30.8,59.62 U7.L15
C0_CLK: length 2.6
  TOP w0.099: U15.6 28.3,33.61 28.17,33.48 v1(27.99,33.48)
  BOTTOM w0.097: R257.2 28.19,33.57 28.1,33.48 v1(27.99,33.48)
C0_CS: length 1.8
  TOP w0.099: R49.2 30.96,44.21 U15.1
C0_MO: length 2.2
  TOP w0.099: v1(26.85,33.5) 26.9,33.55 U15.5
  BOTTOM w0.097: R258.2 26.92,33.58 v1(26.85,33.5)
C1_CLK: length 2.7
  TOP w0.099: U16.6 34.14,35.51 33.53,36.12 v1(33.4,36.12)
  BOTTOM w0.097: R247.2 33.53,36.25 v1(33.4,36.12)
C1_CS: length 2.1
  TOP w0.099: U16.1 36.81,41.38 37.01,41.17 v1(37.01,41.17)
  BOTTOM w0.097: v1(37.01,41.17) 36.64,40.8 R229.2
C1_MO: length 2.6
  TOP w0.099: v1(32.11,36.22) 32.11,35.94 32.38,35.66 32.38,35.66 32.74,35.3 U16.5
  BOTTOM w0.097: v1(32.11,36.22) 32.11,36.74 R248.2
CLK_14M_SOC: length 62.5
  TOP w0.099: R120.1 87.02,20.04 85.8,21.26 83.57,21.26 83.52,21.31 v1(83.21,21.31)
  TOP w0.254: U14.AM56 118.21,41.61 v1(118.15,41.61)
  L3_SIG w0.097: v1(106.55,38.94) 106.58,38.96 106.58,39.24 107.06,39.73 108.05,39.73 109.73,41.4 114.45,41.4 115.09,40.77 115.54,40.77 116.05,41.27 117.86,41.27 118.15,41.56 v1(118.15,41.61)
  L10_SIG w0.097: v1(83.21,21.31) 83.21,27.69 84.48,28.96 84.75,28.96 92.65,36.85 92.65,39.97 95.65,42.97 95.65,43.64 97.23,45.22 104.22,45.22 105.23,44.21 105.23,42.31 105.75,41.79 105.75,39.74 v1(106.55,38.94)
CLK_25M_CPLD: length 5
  TOP w0.102: U7.H5 v1(41.32,56.12)
  BOTTOM w0.097: R186.2 43.81,57.99 43.81,56.9 43.49,56.57 42.58,56.57
  BOTTOM w0.102: 42.58,56.57 41.76,56.57 41.32,56.13 v1(41.32,56.12)
CLK_25M_CPLD_R: length 8.8
  TOP w0.099: X1.3 48.08,62.94 v1(48.03,62.89)
  BOTTOM w0.097: v1(48.03,62.89) 48.87,62.05 48.87,60.73 47.7,59.56 47.09,59.56 45.8,58.27 R186.1
CLK_96M_SOC_USB_DN: length 58.6
  TOP w0.104: U14.BA50 121.62,45.65 121.62,45.86 121.51,45.97 v1(121.2,45.97) ; v1(96.77,12.57) 96.67,12.57 96.24,13 96.24,14.81 96.46,15.02 U27.20
  L10_SIG w0.104: v1(121.2,45.97) 121.05,45.97 120.85,45.77 120.85,45.34 120.37,44.86 119.37,44.86 119.3,44.79 116.67,44.79 114.91,43.03 114.91,41.12 113.47,39.68 111.97,39.68 111.93,39.64 110.17,39.64 109.36,38.83 109.36,25.03 106.68,22.35 106.68,19.18 107.33,18.53 107.33,17.13 106.39,16.19 105.07,16.19 103.16,14.29 99.43,14.29 98.49,15.23 96.68,15.23 96.34,14.89 96.34,13.01 96.51,12.84 96.51,12.84 96.52,12.84 96.52,12.83 v1(96.77,12.57)
CLK_96M_SOC_USB_DP: length 58.9
  TOP w0.104: v1(121.2,46.73) 121.55,46.38 U14.BB50 ; v1(95.76,12.57) 95.79,12.57 95.95,12.73 95.95,14.93 96.06,15.04 U27.19
  L10_SIG w0.104: v1(95.76,12.57) 96.08,12.9 96.07,12.9 96.07,15 96.57,15.5 98.6,15.5 99.54,14.56 103.05,14.56 104.96,16.46 106.28,16.46 107.06,17.24 107.06,18.42 106.41,19.07 106.41,22.46 109.09,25.14 109.09,38.94 110.06,39.9 111.82,39.9 111.86,39.95 113.36,39.95 114.64,41.23 114.64,43.14 116.56,45.06 119.19,45.06 119.25,45.12 120.26,45.12 120.59,45.45 120.59,45.99 121.2,46.6 v1(121.2,46.73)
CLK_100M_CLKBUFF_DN: length 35.5
  TOP w0.091: U21.7 97.52,35.26 96.15,36.63 95.9,36.63 95.3,36.63 v1(95.25,36.58) ; v1(101.35,16.03) 101.02,16.36 99.84,16.36 99.45,16.74 98.91,16.74 U27.26
  L10_SIG w0.094: v1(95.25,36.58) 95.66,36.17 95.66,30.55 97.07,29.14 97.07,28.01 95.92,26.86 95.92,25.72 94.15,23.94 94.15,22.19 95.25,21.09 96.16,21.09 96.32,20.93 96.54,20.93 96.69,21.09 96.91,21.09 97.07,20.93 97.29,20.93 97.45,21.09 98.34,21.09 98.87,20.56 98.87,20.2 98.78,20.1 98.75,20.1 98.65,20.01 98.65,19.82 98.75,19.73 98.78,19.73 98.87,19.63 98.87,19.44 98.78,19.35 98.75,19.35 98.65,19.26 98.65,19.07 98.75,18.97 98.78,18.97 98.87,18.88 98.87,18.69 98.78,18.6 98.75,18.6 98.65,18.5 98.65,18.32 98.75,18.22 98.78,18.22 98.87,18.13 98.87,17.94 98.78,17.85 98.75,17.85 98.65,17.75 98.65,17.57 98.75,17.47 98.78,17.47 98.87,17.38 98.87,17 99.6,16.27 101.1,16.27 v1(101.35,16.03)
CLK_100M_CLKBUFF_DP: length 35.7
  TOP w0.091: v1(95.25,37.59) 95.76,37.08 95.9,37.08 96.34,37.09 97.92,35.5 U21.6 ; U27.27 99.64,17.2 100.03,16.81 101.12,16.81 v1(101.35,17.04)
  L10_SIG w0.094: v1(101.35,17.04) 101.04,16.74 99.8,16.74 99.34,17.2 99.34,20.75 98.54,21.56 95.44,21.56 94.61,22.38 94.61,23.75 96.39,25.53 96.39,26.67 97.54,27.81 97.54,29.34 96.13,30.75 96.13,31.75 96.14,31.76 96.14,36.7 v1(95.25,37.59)
CLK_100M_PCIE0_SLOT_DN: length 40.9
  TOP w0.107: S1.A14 83.37,6.23 83.74,6.6 83.74,10.04 83.82,10.12 83.82,11.43 v1(83.44,11.81) ; v1(91.54,32.36) 91.92,32.74 92.22,32.74 92.56,32.41 92.56,32.13 93.45,31.24 94.89,31.24 94.97,31.16 U21.18
  L10_SIG w0.114: v1(83.44,11.81) 83.81,12.19 83.81,13.63 84.77,14.59 84.77,15.48 84.66,15.59 84.66,15.94 84.77,16.05 84.77,16.33 84.58,16.52 84.58,16.79 84.77,16.98 84.77,17.24 84.58,17.43 84.58,17.7 84.77,17.89 84.77,27.03 88.67,30.93 91.46,30.93 92.37,31.84 92.37,32.52 92.16,32.73 91.92,32.73 v1(91.54,32.36)
CLK_100M_PCIE0_SLOT_DP: length 41
  TOP w0.107: v1(91.54,33.38) 91.92,32.99 92.33,32.99 92.81,32.51 92.81,32.23 93.55,31.49 94.89,31.49 94.97,31.56 U21.17 ; v1(84.45,11.81) 84.07,11.43 84.07,10.01 83.99,9.93 83.99,6.6 84.37,6.23 S1.A13
  L10_SIG w0.114: v1(91.54,33.38) 91.92,33 92.27,33 92.63,32.64 92.63,31.72 91.57,30.66 88.78,30.66 85.04,26.92 85.04,14.48 84.08,13.52 84.08,12.19 v1(84.45,11.81)
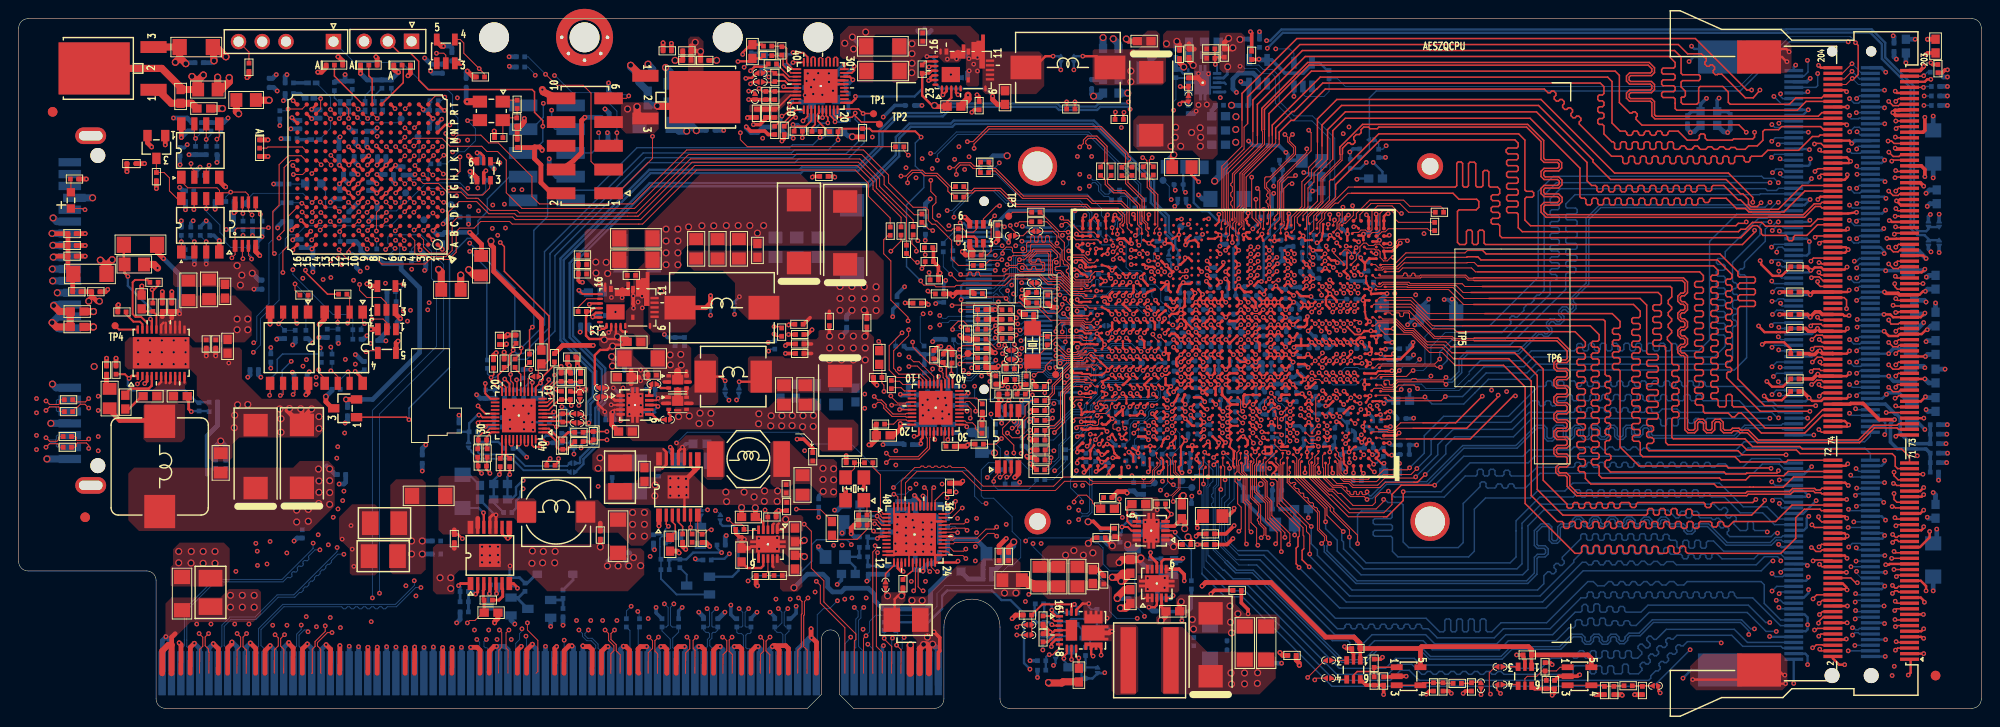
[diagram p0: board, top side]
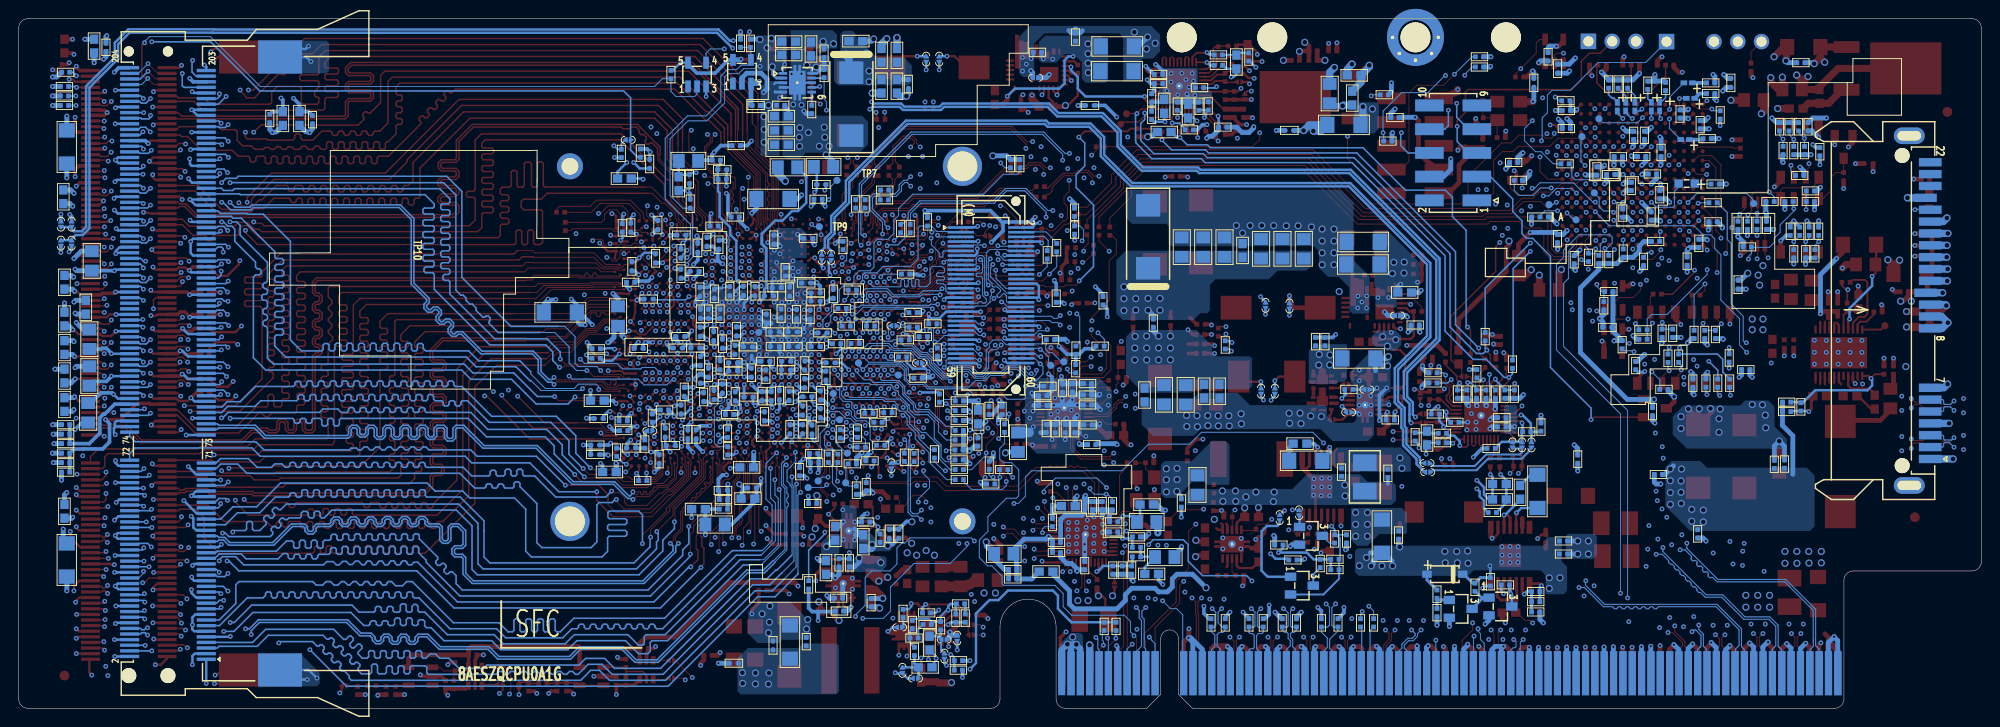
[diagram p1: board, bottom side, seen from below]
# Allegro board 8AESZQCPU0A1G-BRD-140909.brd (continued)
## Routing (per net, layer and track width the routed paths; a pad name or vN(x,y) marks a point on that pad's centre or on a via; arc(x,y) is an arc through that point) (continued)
CLK_100M_PCIE1_SLOT_DN: length 64.9
  TOP w0.107: U21.24 97.52,29.01 97.47,28.96 97.47,27.8 96.35,26.67 93.22,26.67 v1(92.84,26.29)
  L10_SIG w0.114: v1(59.94,8.38) 60.32,8.01 60.32,7.5 62.6,5.22 81.54,5.22 82.73,6.4 82.73,9.04 84.43,10.74 85.62,10.74 86.58,11.7 86.58,13.55 90.12,17.09 90.12,21.13 89.33,21.92 89.33,25.15 90.85,26.66 92.46,26.66 v1(92.84,26.29)
  BOTTOM w0.107: S1.B36 61.37,6.07 61.74,6.44 61.74,6.76 61.26,7.24 60.78,7.24 60.33,7.69 60.33,8 v1(59.94,8.38)
CLK_100M_PCIE1_SLOT_DP: length 64.9
  TOP w0.107: U21.23 97.12,29.01 97.22,28.91 97.22,27.9 96.24,26.92 93.22,26.92 v1(92.84,27.3)
  L10_SIG w0.114: v1(60.96,8.38) 60.59,8.01 60.59,7.61 62.71,5.49 63.92,5.49 64.12,5.69 64.38,5.69 64.58,5.49 64.84,5.49 65.04,5.69 65.29,5.69 65.5,5.49 65.75,5.49 65.95,5.69 66.21,5.69 66.41,5.49 66.66,5.49 66.87,5.69 67.12,5.69 67.32,5.49 67.58,5.49 67.78,5.69 68.04,5.69 68.24,5.49 81.43,5.49 82.46,6.52 82.46,9.15 84.32,11.01 85.51,11.01 86.31,11.81 86.31,13.66 89.85,17.2 89.85,21.02 89.07,21.81 89.07,25.26 90.74,26.93 92.46,26.93 v1(92.84,27.3)
  BOTTOM w0.107: S1.B35 62.37,6.07 61.99,6.44 61.99,6.87 61.37,7.49 60.88,7.49 60.58,7.8 60.58,8 v1(60.96,8.38)
CLK_100M_SOC_GBE_DN: length 34.5
  TOP w0.081: 114.79,23.92 114.81,23.92 114.95,24.05 121.11,24.05 121.51,24.46 121.51,25.4 122.12,26 122.12,26.5 121.74,26.87 U14.D50
  TOP w0.091: 114.79,23.92 114.55,23.92 114.17,24.3 111.91,24.3 110.93,23.31 103,23.31 100.99,25.32 96.08,25.32 94.89,24.13 94.89,22.25 94.86,22.23 U27.45
CLK_100M_SOC_GBE_DP: length 34.3
  TOP w0.081: U14.B50 121.82,25.97 121.33,25.48 121.33,24.54 121.03,24.24 114.95,24.24 114.81,24.37 114.79,24.37
  TOP w0.091: U27.46 94.46,22.23 94.43,22.25 94.43,24.32 95.89,25.78 96.43,25.78 96.57,25.92 96.79,25.92 96.93,25.78 97.16,25.78 97.3,25.92 97.52,25.92 97.66,25.78 97.89,25.78 98.03,25.92 98.25,25.92 98.4,25.78 98.62,25.78 98.76,25.92 98.99,25.92 99.13,25.78 99.35,25.78 99.49,25.92 99.72,25.92 99.86,25.78 101.18,25.78 103.19,23.77 110.74,23.77 111.72,24.75 114.36,24.75 114.74,24.37 114.79,24.37
CLK_100M_SOC_HFHPLL_DN: length 36.6
  TOP w0.091: U14.J37 v1(128.8,29.47) ; v1(100.97,21.44) 100.9,21.44 99.83,20.37 99.51,20.37 99.48,20.4 U27.35
  L3_SIG w0.081: v1(128.8,29.47) 128.51,29.76 128.34,29.76 127.94,29.35 127.94,27.56 126.1,25.72 121.88,25.72 121.47,25.32 121.47,24.5 121.62,24.36 121.62,24.34
  L3_SIG w0.094: 121.62,24.34 121.62,24.08 121.01,23.47 118.01,23.47 117.07,22.53 101.76,22.53 100.97,21.74 v1(100.97,21.44)
CLK_100M_SOC_HFHPLL_DP: length 36.4
  TOP w0.091: U27.36 99.48,20.8 99.51,20.83 99.64,20.83 100.24,21.42 v1(100.24,22.15) ; U14.L37 128.8,30.25 v1(128.8,30.23)
  L3_SIG w0.081: v1(128.8,30.23) 128.51,29.94 128.27,29.94 127.75,29.43 127.75,27.64 126.02,25.91 121.8,25.91 121.29,25.39 121.29,24.5 121.15,24.36 121.15,24.34
  L3_SIG w0.094: 121.15,24.34 121.15,24.27 120.82,23.94 117.81,23.94 116.87,23 101.56,23 100.71,22.15 v1(100.24,22.15)
CLK_100M_SOC_MPLL0_DN: length 78.4
  TOP w0.091: v1(104.65,18.42) 104.35,18.72 103.68,18.72 102.72,17.75 100.15,17.75 100,17.6 U27.28 ; U14.BM13 140.08,51.76 v1(140.12,51.8)
  L3_SIG w0.081: v1(140.12,51.8) 140.2,51.88 140.2,52.21 140.12,52.29 140.06,52.29 140.04,52.3 139.9,52.3 138.72,51.12 138.72,50.39 137.25,48.92 137.25,45.06 137.57,44.74 137.57,43.94 137.2,43.58 137.2,42.89 137.49,42.61 137.49,37.16 137.29,36.96 137.29,35.59 137,35.3 137,34.04 136.76,33.8 136.76,30.66 137.44,29.99 137.44,26.76 137.58,26.61 137.58,26.59
  L3_SIG w0.094: 137.58,26.59 137.58,26.05 135.98,24.45 135.98,23.82 132.3,20.14 125.34,20.14 124.25,21.23 122.65,21.23 121.85,22.03 119.42,22.03 118.58,21.18 116.03,21.18 115.58,20.74 115.58,19.67 114.88,18.97 111.99,18.97 111.46,19.51 111.46,20.85 110.79,21.51 107.44,21.51 106.86,20.93 106.86,19.53 106,18.68 104.9,18.68 v1(104.65,18.42)
CLK_100M_SOC_MPLL0_DP: length 78.2
  TOP w0.091: v1(104.65,19.41) 104.42,19.18 104.35,19.18 104.35,19.18 103.49,19.18 102.53,18.21 100.19,18.21 99.97,18 98.86,18 U27.29 ; U14.BN12 140.77,52.25 v1(140.79,52.26)
  L3_SIG w0.081: v1(140.79,52.26) 140.41,52.26 140.2,52.47 140.13,52.47 140.11,52.49 139.82,52.49 138.54,51.2 138.54,50.47 137.06,48.99 137.06,44.98 137.38,44.66 137.38,44.02 137.02,43.66 137.02,42.82 137.3,42.53 137.3,37.23 137.1,37.03 137.1,35.67 136.82,35.38 136.82,34.12 136.58,33.88 136.58,30.59 137.25,29.92 137.25,26.76 137.11,26.61 137.11,26.59
  L3_SIG w0.094: v1(104.65,19.41) 104.9,19.15 105.81,19.15 106.39,19.73 106.39,21.12 107.25,21.98 110.99,21.98 111.93,21.04 111.93,19.7 112.18,19.44 114.69,19.44 115.11,19.87 115.11,20.93 115.83,21.65 118.38,21.65 119.23,22.5 122.05,22.5 122.85,21.7 124.44,21.7 125.53,20.61 132.1,20.61 135.51,24.02 135.51,24.64 137.11,26.25 137.11,26.59
CLK_100M_SOC_MPLL1_DN: length 59.2
  TOP w0.091: v1(101.47,19.05) 101.24,19.28 99.87,19.28 99.77,19.18 98.89,19.18 98.87,19.2 U27.32 ; U14.L14 139.67,30.57 v1(140.01,30.23)
  L3_SIG w0.081: v1(140.01,30.23) 140.02,30.23 140.1,30.15 140.1,30.03 140.18,29.95 140.34,29.95 140.72,29.56 140.72,28.6 139.89,27.77 139.89,23.2 139.25,22.57 139.25,22.36 139.24,22.35
  L3_SIG w0.094: v1(101.47,19.05) 101.77,19.34 102.73,19.34 103.04,19.03 103.04,17.25 104.44,15.84 109.25,15.84 110.06,15.04 115.78,15.04 116.09,15.36 116.1,15.36 116.7,15.96 116.7,15.96 116.93,16.19 118.5,16.19 119.64,15.05 119.66,15.05 119.68,15.04 135.84,15.04 139.24,18.44 139.24,22.35
CLK_100M_SOC_MPLL1_DP: length 58.9
  TOP w0.091: v1(101.47,20.07) 101.14,19.74 99.68,19.74 99.58,19.63 98.89,19.63 U27.33 ; U14.J14 139.67,29.83 v1(140.02,29.48)
  L3_SIG w0.081: v1(140.02,29.48) 140.1,29.56 140.1,29.68 140.18,29.76 140.26,29.76 140.54,29.49 140.54,28.68 139.71,27.85 139.71,23.28 139.12,22.69 138.92,22.69 138.91,22.68
  L3_SIG w0.094: v1(101.47,20.07) 101.73,19.81 102.92,19.81 103.5,19.23 103.5,17.44 104.63,16.31 104.88,16.31 104.99,16.43 105.25,16.43 105.37,16.31 105.63,16.31 105.75,16.43 106.01,16.43 106.12,16.31 106.38,16.31 106.5,16.43 106.76,16.43 106.87,16.31 107.13,16.31 107.25,16.43 107.51,16.43 107.63,16.31 107.88,16.31 108,16.43 108.26,16.43 108.38,16.31 108.64,16.31 108.75,16.43 109.01,16.43 109.13,16.31 109.45,16.31 110.25,15.51 115.58,15.51 115.9,15.83 115.9,15.83 116.23,16.15 116.23,16.15 116.73,16.66 118.7,16.66 119.84,15.52 119.86,15.52 119.87,15.51 135.64,15.51 138.77,18.64 138.77,22.54 138.91,22.68
CLK_100M_SOC_PCIE_DN: length 45.5
  TOP w0.091: v1(122.62,46.7) 122.57,46.74 122.57,46.79 U14.BD49 ; U21.15 95,32.36 94.99,32.37 94.96,32.37 94.87,32.46 94.24,32.46 94.23,32.46 93.43,32.46 v1(93.41,32.44)
  L8_SIG w0.094: v1(122.62,46.7) 122.49,46.57 122.49,45.69 121.42,44.62 116.58,44.62 114.47,42.5 114.47,38.14 113.02,36.69 112.53,36.69 111.28,35.44 111.28,33.93 109.92,32.58 108.36,32.58 107.26,31.47 105.52,31.47 103.28,29.24 96.86,29.24 95.58,30.52 95.58,31.86 94.82,32.63 93.6,32.63 v1(93.41,32.44)
CLK_100M_SOC_PCIE_DP: length 45.2
  TOP w0.091: U14.BB49 121.99,46.61 121.99,46.64 v1(121.9,46.73) ; U21.14 95,32.76 94.9,32.66 94.03,32.66 93.32,33.38 v1(93.32,33.43)
  L8_SIG w0.094: v1(93.32,33.43) 93.45,33.43 93.78,33.1 95.01,33.1 96.05,32.06 96.05,30.71 97.06,29.71 103.08,29.71 105.32,31.94 107.06,31.94 108.16,33.05 109.72,33.05 110.81,34.13 110.81,35.64 112.33,37.16 112.82,37.16 114,38.33 114,42.7 116.39,45.09 121.23,45.09 122.02,45.88 122.02,46.61 v1(121.9,46.73)
CLK_100M_SOC_SATA3_DN: length 34.5
  TOP w0.091: v1(117.68,29.87) 117.18,29.87 117.09,29.97 117.09,30.34 U14.L59 ; v1(98.3,14.63) 98.12,14.63 97.66,15.09 U27.23
  L8_SIG w0.094: v1(98.3,14.63) 98.4,14.63 98.66,14.89 98.97,14.89 99.15,15.07 99.34,15.07 99.53,14.89 99.72,14.89 99.9,15.07 100.1,15.07 100.28,14.89 100.47,14.89 100.66,15.07 100.85,15.07 101.03,14.89 101.22,14.89 101.41,15.07 101.6,15.07 101.78,14.89 101.98,14.89 102.16,15.07 102.35,15.07 102.53,14.89 102.73,14.89 102.91,15.07 103.1,15.07 103.29,14.89 103.99,14.89 105.09,15.99 108.9,15.99 111.42,18.5 111.42,23.51 112.76,24.85 115.35,24.85 115.8,25.3 115.8,25.47 116.36,26.03 116.89,26.03 117.54,26.68 117.54,27.79 117.12,28.21 117.12,29.25 117.68,29.8 v1(117.68,29.87)
CLK_100M_SOC_SATA3_DP: length 34.7
  TOP w0.091: v1(118.38,29.96) 118.15,30.19 U14.L57 ; v1(97.49,14.63) 97.26,14.86 U27.22
  L8_SIG w0.094: v1(118.38,29.96) 118.38,29.83 117.59,29.05 117.59,28.4 118.01,27.98 118.01,26.48 117.09,25.56 116.56,25.56 116.27,25.27 116.27,25.11 115.55,24.38 112.95,24.38 111.89,23.32 111.89,18.31 109.1,15.52 105.28,15.52 104.18,14.42 98.89,14.42 98.63,14.16 98.08,14.16 97.61,14.63 v1(97.49,14.63)
CLK_100M_SOC_SATA_DN: length 23.4
  TOP w0.091: v1(102.39,31.8) 102.36,31.83 102.36,32.19 101.74,32.82 101.38,32.82 101.32,32.76 U21.37 ; v1(119.42,30.26) 119.77,30.61 U14.L54
  L5_SIG w0.081: 112.64,29.62 112.65,29.63 114.09,29.63 114.66,30.2 116.68,30.2 117.39,29.49 118.45,29.49 118.95,30 119.16,30 v1(119.42,30.26)
  L5_SIG w0.094: 112.64,29.62 112.51,29.76 112.25,29.76 110.96,28.46 109.23,28.46 109.12,28.57 108.86,28.57 108.74,28.46 104.83,28.46 102.39,30.9 v1(102.39,31.8)
CLK_100M_SOC_SATA_DP: length 23.6
  TOP w0.091: U14.J54 119.72,29.85 v1(119.32,29.45) ; U21.36 101.55,32.36 101.9,32 101.9,31.24 101.82,31.15 v1(101.82,31.05)
  L5_SIG w0.081: 112.56,29.29 112.72,29.45 114.16,29.45 114.74,30.02 116.6,30.02 117.31,29.31 118.53,29.31 119.03,29.81 119.2,29.81 119.28,29.73 119.32,29.69 v1(119.32,29.45)
  L5_SIG w0.094: v1(101.82,31.05) 101.82,30.81 104.63,27.99 111.16,27.99 112.45,29.29 112.56,29.29
CLK_100M_XDP_DN: length 29.9
  TOP w0.091: v1(97.92,23.62) 97.71,23.42 97.71,21.66 U27.38
  L10_SIG w0.094: v1(98.55,41.02) 98.3,41.27 97.16,41.27 96.9,41.02 96.9,38.76 97.25,38.41 97.25,35.52 97.69,35.08 98.91,35.08 100.45,33.54 100.45,28.36 99.95,27.86 99.95,27.73 99.96,27.73 99.96,27.59 99.83,27.46 99.69,27.46 99.69,27.47 99.56,27.47 99.42,27.33 99.42,27.2 99.43,27.2 99.43,27.06 99.29,26.93 99.16,26.93 99.16,26.93 99.02,26.93 98.89,26.8 98.89,26.67 98.89,26.66 98.89,26.53 98.76,26.4 98.63,26.4 98.62,26.4 98.49,26.4 98.36,26.27 98.36,26.14 98.36,26.13 98.36,26 98.23,25.87 98.1,25.87 98.09,25.87 97.96,25.87 97.66,25.57 97.66,23.88 v1(97.92,23.62)
  BOTTOM w0.091: P2.42 101.14,41.45 101.1,41.49 99.66,41.49 99.44,41.27 98.81,41.27 v1(98.55,41.02)
CLK_100M_XDP_DP: length 30.1
  TOP w0.091: v1(96.9,23.62) 96.94,23.62 97.26,23.3 U27.39
  L10_SIG w0.094: v1(96.9,23.62) 97.19,23.91 97.19,25.77 99.98,28.55 99.98,33.35 98.72,34.61 97.5,34.61 96.78,35.33 96.78,38.22 96.43,38.57 96.43,41.22 96.96,41.74 98.26,41.74 v1(98.55,42.04)
  BOTTOM w0.091: P2.40 99.47,41.95 99.25,41.73 98.86,41.73 v1(98.55,42.04)
CLK_C: length 14.1
  TOP w0.099: R117.1 117.78,21.98 v1(117.78,22.4) ; U14.P50 121.57,32.52 121.46,32.41 121.31,32.41 v1(121.28,32.38)
  L5_SIG w0.097: v1(117.78,22.4) 118.1,22.72 118.1,23.2 118.54,23.65 119.2,23.65 119.56,24 119.56,25.9 121.84,28.18 121.84,31.78 121.31,32.31 121.31,32.36 v1(121.28,32.38)
CLK_LPC0: length 65.7
  TOP w0.099: R28.1 96.57,52.82 95.82,52.82 92.88,55.76 92.6,56.04 92.6,56.87 90.2,59.27 71.67,59.27 65.9,53.5 65.5,53.5 53.84,53.5 52.17,55.17 52.17,58.66 51.24,59.59 50.1,59.59 49.55,60.15 46.15,60.15 45.3,61 42.2,61 U7.M4
CLK_LPC0_R: length 47.3
  TOP w0.099: R28.2 97.39,51.26 97.58,51.26 97.72,51.12 v1(97.8,51.12)
  TOP w0.254: U14.AG51 v1(120.81,38.23)
  L3_SIG w0.097: v1(101.09,36.17) 101.09,36.25 101.42,36.58 101.42,37.34 101.7,37.62 101.7,47.19 101.04,47.85 99.09,47.85 97.76,49.17 96.4,49.17 96.23,49.35 96.2,49.35 95.79,49.76 95.79,50.75 96.16,51.12 97.46,51.12 v1(97.8,51.12)
  BOTTOM w0.097: v1(101.09,36.17) 101.09,35.79 101.52,35.36 101.89,35.36 102.98,36.45 104.11,36.45 104.75,35.81 106.17,35.81 106.65,35.33 107.7,35.33 108.41,36.04 109.5,36.04 110.11,35.43 111.15,35.43 112.52,36.8 112.52,37.19 113,37.67 113.31,37.67
  BOTTOM w0.102: 113.31,37.67 113.54,37.67 113.55,37.68 113.55,37.68 114.36,38.48 116.33,38.48 116.89,39.04 119.08,39.04 119.51,38.61 120.44,38.61 v1(120.81,38.23)
CLK_LPC1: length 2.7
  TOP w0.099: R26.1 106.34,53.09 TP3.1
CLK_LPC1_R: length 21.5
  TOP w0.099: R26.2 109.32,53.09 111.38,51.03 112.06,51.03 112.14,50.95 v1(112.29,50.95)
  TOP w0.254: v1(122.61,41.71) 122.61,41.54 U14.AM49
  L5_SIG w0.097: v1(112.29,50.95) 112.6,51.26 113.97,51.26 114.86,50.37 114.86,48.27 115.77,47.36 117.87,47.36 118.64,46.58 120.25,46.58 120.5,46.34 120.5,45.49 122.4,43.59 122.4,41.91 v1(122.61,41.71)
CLKPWRGD: length 105.6
  TOP w0.099: U21.3 99.12,35.19 98.91,35.41 98.91,35.86 98.65,36.12 v1(98.65,36.25) 98.65,36.35 98.17,36.83 97.51,36.83 96.56,37.79 96.55,37.79 95.68,38.66 95.68,39.16 v1(95.65,39.19) ; v1(93.64,22.91) 93.7,22.91 93.72,22.89 93.8,22.89 94.07,22.62 94.07,21.61 U27.47
  TOP w0.102: U7.K3 v1(43.32,59.12)
  L3_SIG w0.097: v1(49.12,55.68) 49.95,55.68 51.98,57.71 52.01,57.71 52.02,57.71 55.15,57.71 55.16,57.71 55.55,57.71 55.77,57.49 84.19,57.49 84.31,57.38 88.9,57.38 93.9,52.37 93.9,47.22 94.34,46.78 94.34,42.91 94.36,42.89 94.36,42.88 95.81,41.43 95.81,39.35 v1(95.65,39.19)
  L10_SIG w0.097: v1(98.65,36.25) 100.23,36.25 100.69,35.79 100.69,34.27 101.07,33.89 101.07,27.57 99.55,26.05 99.55,23.75 98.06,22.26 95.72,22.26 95.25,22.73 95.25,23.4 v1(95.38,23.53) ; v1(49.12,55.68) 49.12,55.88 47.6,57.41 47.6,59.16 45.87,60.88 44.07,60.88 43.79,60.6 43.79,59.84 43.32,59.37 v1(43.32,59.12)
  BOTTOM w0.097: R318.1 92.96,22.4 93.45,22.89 93.59,22.89 93.59,22.89 93.59,22.75 93.72,22.75 93.72,22.83 v1(93.64,22.91) 94.92,22.91 95.38,23.37 v1(95.38,23.53)
CPLD_AD1: length 5.2
  TOP w0.152: U7.T7 41.15,66.95 41.15,68.71 J3.2
CPLD_AD2: length 4.4
  TOP w0.152: J2.2 37.47,67.69 37.82,67.33 U7.T8
CPLD_AD3: length 5.5
  TOP w0.152: U7.T9 33.78,67.66 J1.2
CPLD_TCK: length 42.9
  TOP w0.099: U7.P3 42.82,62.61 v1(42.34,62.13) ; v1(67.82,61.21) 67.82,58.85 64.08,55.12 JP3.1
  L5_SIG w0.097: v1(42.34,62.13) 42.88,62.66 42.88,65.3 43.99,66.42 53.59,66.42 54.91,67.74 v1(55.27,67.74) 55.45,67.74 57.68,65.51 59.36,65.51 62.33,62.53 65.76,62.53 67.08,61.21 v1(67.82,61.21)
  BOTTOM w0.097: v1(55.27,67.74) 55.27,67.84 54.48,68.63 R144.2
CPLD_TDI: length 37.8
  TOP w0.099: v1(65.28,65.54) 65.02,65.28 JP3.9
  TOP w0.102: U7.L6 v1(39.34,60.1)
  L5_SIG w0.097: v1(39.34,60.1) 39.34,64.56 42.47,67.69 52.95,67.69 54.42,69.17 56.66,69.17 60.09,65.74 65.18,65.74 65.28,65.64 65.28,65.54 v1(65.28,65.54)
  BOTTOM w0.097: v1(65.28,65.54) 65.15,65.66 R159.2
CPLD_TDO: length 39.4
  TOP w0.099: JP3.3 62.1,57.66 61.24,58.52 61.24,65.84 60.4,66.67 57.56,66.67 v1(56.38,67.86)
  TOP w0.102: U7.M5 v1(41.32,61.12)
  L5_SIG w0.097: v1(41.32,61.12) 41.94,61.74 41.94,65.15 43.71,66.93 53.21,66.93 54.75,68.47 55.89,68.47 56.38,67.98 v1(56.38,67.86)
  BOTTOM w0.097: v1(56.38,67.86) 54.51,69.72 R141.2
CPLD_TMS: length 36
  TOP w0.099: JP3.5 63.91,60.2 64.01,60.3 v1(64.01,61.59)
  TOP w0.102: U7.N4 v1(41.33,62.12)
  L5_SIG w0.097: v1(57.33,67.72) 57.33,67.78 56.29,68.82 54.57,68.82 53.09,67.34 43.31,67.34 40.82,64.85 40.82,62.63 v1(41.33,62.12)
  BOTTOM w0.097: R176.2 63.94,61.53 v1(64.01,61.59) 64.01,63.91 62.03,65.89 59.22,65.89 57.39,67.72 v1(57.33,67.72)
CPU_GBE_LED_0: length 7.2
  TOP w0.254: U14.P46 v1(123.43,31.76)
  BOTTOM w0.097: R295.2 119.39,28.75
  BOTTOM w0.102: 119.39,28.75 119.84,29.19 119.84,30.28 120.04,30.48 120.47,30.48 121.01,31.02 121.46,31.02 122.2,31.76 v1(123.43,31.76)
CPU_GBE_LED_1: length 7
  TOP w0.254: U14.W50 v1(122.34,34.26)
  BOTTOM w0.097: 120.98,32.84 120.85,32.72 120.85,32.08 120.55,31.78 120.55,31.27 120.32,31.04 118.93,31.04 R278.2
  BOTTOM w0.102: v1(122.34,34.26) 122.15,34.08 122.15,33.23 121.76,32.84 120.98,32.84
CPU_GBE_LED_2: length 8.1
  TOP w0.254: U14.P48 122.81,32.17 v1(122.9,32.17)
  BOTTOM w0.097: 118.9,30.05 118.9,28.78 118.27,28.15 R294.2
  BOTTOM w0.102: 118.9,30.05 118.95,30.1 118.95,30.39 119.33,30.77 120.38,30.77 120.9,31.29 120.9,31.72 121.13,31.95 121.59,31.95 121.78,32.14 122.87,32.14 v1(122.9,32.17)
CPU_GBE_LED_3: length 1.2
  TOP w0.254: U14.R58 117.4,32.26 v1(117.37,32.26)
  BOTTOM w0.097: R271.2 117.44,32.2
  BOTTOM w0.102: 117.44,32.2 v1(117.37,32.26)
CPU_IERR_N: length 138.9
  TOP w0.099: v1(27.85,50.32) 27.85,50.59 28.4,51.13 28.4,57.88 29.15,58.62 U7.K16
  TOP w0.254: U14.AM52 120.46,41.65 v1(120.45,41.65)
  L3_SIG w0.097: v1(120.45,41.65) 120.45,41.61 120.45,41.6 120.45,41.07 120.93,40.59 120.93,39.47 120.7,39.24 116.84,39.24 116.47,39.61 115.87,39.61 115.71,39.45 115.06,39.45 113.71,40.8 110.44,40.8 109.6,39.95 109.6,38.13 107.38,35.91 104.54,35.91 104.07,36.37 103,36.37 101.93,35.31 100.99,35.31 100.41,35.89 100.41,36.45 99.72,37.13 97.76,37.13 96.65,38.25 96.65,42.09 v1(96.77,42.21) 96.77,43.28 95.91,44.15 95.91,46.21 94.71,47.41 94.71,52.9 89.43,58.19 87.05,58.19 87.05,58.19 56.44,58.19 55.78,58.85 51.23,58.85 50.42,58.04 50.42,57.28 49.73,56.59 48.26,56.59 47.45,55.78 47.45,53.2 46.89,52.64 46.89,51.77 44.81,49.68 42.54,49.68 41.52,48.67 36.25,48.67 35.33,49.58 28.59,49.58 v1(27.85,50.32)
  BOTTOM w0.097: R243.1 96.47,39.18 96.47,41.91 v1(96.77,42.21)
CPU_MCERR_N: length 126.1
  TOP w0.099: v1(27.36,48.67) 27.2,48.82 27.2,53.19 27.86,53.85 27.86,58.18 28.82,59.13 30.24,59.13 30.75,58.62 U7.K15 ; R37.1 96.91,48.63 v1(97,48.54)
  TOP w0.254: U14.AL52 120.45,40.23 v1(120.45,40.18)
  L5_SIG w0.097: v1(27.36,48.67) 27.4,48.62 34.9,48.62 35.18,48.34 41.1,48.34 43.41,50.65 44.53,50.65 44.93,51.05 44.93,55.35 46.2,56.62 51.23,56.62 51.94,57.33 83.67,57.33 84.61,56.39 84.99,56.39 84.99,56.39 90.07,56.39 95.28,51.18 95.28,48.65 95.62,48.31 96.77,48.31 v1(97,48.54) 97.84,48.54 98.3,48.08 101.88,48.08 103.88,46.08 106.49,46.08 106.78,46.37 108.04,46.37 109.14,45.26 109.14,42.39 110.21,41.33 113.56,41.33 115.24,39.65 116.48,39.65 116.88,39.25 118.23,39.25 118.31,39.17 120.09,39.17 120.45,39.52 v1(120.45,40.18)
CPU_NMI: length 113.1
  TOP w0.099: v1(33.34,52.11) U7.C12
  TOP w0.254: U14.AL56 v1(118.15,40.22)
  L3_SIG w0.097: v1(118.15,40.22) 118.15,40.76 117.93,40.97 116.15,40.97 115.7,40.51 114.99,40.51 114.3,41.2 110.06,41.2 107.83,38.97 107.15,38.97 106.89,38.71 106.89,38.37 105.98,37.46 104.94,37.46 104.75,37.64 103.89,37.64 102.92,38.61 102.92,52.32 100.89,54.36 97.99,54.36 97.72,54.09 95.04,54.09 89.88,59.24 60.15,59.24 58.27,61.12 51.83,61.12 49.01,58.29 48.26,58.29 48.25,58.29 47.7,58.29 44.86,55.45 44.86,54.11 42.86,52.11 41.66,52.11 41.16,51.61 35.99,51.61 34.98,52.63 33.86,52.63 v1(33.34,52.11)
  BOTTOM w0.097: v1(118.15,40.22) 118.4,40.47 R226.1
CPU_PROCHOT_1P0_N: length 23.1
  TOP w0.099: U10.4 103.22,52.36 104.6,53.75 104.93,53.75 v1(104.95,53.77)
  TOP w0.254: U14.BB59 v1(117.76,46.18)
  L5_SIG w0.097: v1(104.95,53.77) 104.98,53.75 109.07,53.75 111.19,51.63 111.19,50.43 111.71,49.91 112.79,49.91 112.87,49.99 113.69,49.99 113.98,49.7 113.98,48.55 116.09,46.44 117.5,46.44 v1(117.76,46.18)
  BOTTOM w0.097: R220.1 117.48,46.46 v1(117.76,46.18)
CPU_PROCHOT_3P3_N: length 81.3
  TOP w0.099: U10.3 103.22,48.75 R40.2 103.65,48.51 104.05,48.92 104.05,52.32 v1(104.43,52.71)
  TOP w0.102: v1(39.33,52.24) 39.33,52.14 U7.C7
  L3_SIG w0.097: v1(104.43,52.71) 103.04,52.71 100.79,54.95 94.72,54.95 90.07,59.59 60.29,59.59 58.42,61.47 51.69,61.47 48.86,58.64 47.59,58.64 46.73,57.78 45.47,57.78 45.01,57.32 45.01,56.65 43.87,55.51 43.87,53.9 42.56,52.6 41.58,52.6 41.17,52.19 39.38,52.19 v1(39.33,52.24)
CPU_PROCHOT_DIR: length 88
  TOP w0.099: v1(97.6,56.5) 97.6,55.31 98.15,54.76 98.15,54.1 97.79,53.74 97.79,52.45 98.08,52.16 98.23,52.16 99.29,51.1 99.76,51.1 99.98,51.32 R35.1 101.03,51.32 101.4,50.95 102.16,50.95 102.49,51.28 102.49,51.8 U10.5
  TOP w0.102: U7.C8 v1(37.33,51.13)
  L3_SIG w0.097: v1(91.34,61.14) 93.81,58.67 95.61,58.67 97.6,56.68 v1(97.6,56.5)
  L8_SIG w0.097: v1(46.94,65.33) 47.27,65.66 52.98,65.66 55.24,63.4 57.68,63.4 60.33,60.76 77.14,60.76 77.98,61.59 79.71,61.59 80.14,62.03 90.65,62.03 91.34,61.34 v1(91.34,61.14)
  L10_SIG w0.097: v1(46.94,65.33) 46.74,65.13 46.74,63.68 44.75,61.7 42.98,61.7 41.88,60.6 39.09,60.6 38.76,60.27 38.76,59.41 37.85,58.5 37.85,51.91 37.33,51.39 v1(37.33,51.13)
CPU_PWRBTN_N: length 119.3
  TOP w0.102: v1(44.32,57.07) 44.29,57.07 43.82,57.54 U7.J2
  TOP w0.254: U14.AC49 v1(121.96,36.25)
  L3_SIG w0.097: v1(110.77,27.56) 110.77,27.61 112.14,28.98 112.14,31.06 113.13,32.05 113.79,32.05 115.32,33.58 115.32,34.51 115.73,34.92 121.29,34.92 121.96,35.59 v1(121.96,36.25) 121.15,37.05 114.67,37.05 112.04,34.42 109.58,34.42 109.1,33.94 108.29,33.94 108.06,33.71 108.06,33 107.59,32.54 104.62,32.54 104.37,32.79 101.45,32.79 99.88,34.36 95.93,34.36 94.83,35.46 94.2,35.46 93.73,35.93 93.73,40.54 93.04,41.23 93.04,46.18 91.43,47.79 91.43,50.03 86.05,55.41 84.34,55.41 83.56,56.18 54.44,56.18 54.22,56.41 52.56,56.41 50.98,54.83 50.98,54.2 50.73,53.95 v1(50.73,53.86)
  L8_SIG w0.097: v1(44.32,57.07) 44.32,56.79 45.01,56.11 46.47,56.11 48.39,54.18 50.39,54.18 50.62,53.95 50.63,53.95 v1(50.73,53.86)
  BOTTOM w0.097: R297.2 110.68,27.65 v1(110.77,27.56)
CPU_RSTBTN_N: length 99
  TOP w0.102: U7.B8 v1(38.32,50.12)
  TOP w0.254: v1(117.36,41.65) 117.41,41.65 U14.AM58
  L5_SIG w0.097: v1(38.32,50.12) 38.32,50.49 39.83,51.99 39.83,56.38 41.14,57.68 43.23,57.68 44.22,58.67 45.59,58.67 45.92,59.01 45.92,59.62 46.3,59.99 52.79,59.99 53.73,60.93 59.46,60.93 60.93,59.47 85.71,59.47 86,59.18 90.4,59.18 94.51,55.07 100.24,55.07 100.84,54.47 100.84,54.47 103.44,51.87 104.72,51.87 105.26,52.41 108.53,52.41 109.68,51.26 109.68,48.46 116.49,41.65 v1(117.36,41.65)
  BOTTOM w0.102: R210.2 38.31,50.12 v1(38.32,50.12)
CPU_RSVD_AR51: length 13.6
  TOP w0.099: v1(111.67,43.23) 111.66,43.22 111.66,42.81 111.12,42.27 110.1,42.27 108.99,43.38 R51.2
  TOP w0.254: v1(120.82,42.91) 120.84,42.88 120.86,42.88 U14.AR51
  BOTTOM w0.097: v1(111.67,43.23) 112.45,43.23
  BOTTOM w0.102: v1(120.82,42.91) 120.78,42.91 120.75,42.94 120.08,42.94 119.89,43.13 112.55,43.13 112.45,43.23
CPU_RSVD_AR53: length 35.5
  TOP w0.254: U14.AR53 v1(120.8,42.19)
  L5_SIG w0.097: v1(112.24,42.75) 112.19,42.8 111.5,42.8 111.19,42.49 110.78,42.49 110.41,42.85 110.41,45.59 107.89,48.12 107.89,50.07 107.55,50.4 97.66,50.4 97.45,50.61 96.72,50.61 96.22,50.11 v1(96.22,50.04)
  BOTTOM w0.097: R197.1 R202.2 96.46,51.63 96.06,51.23 96.06,50.19 v1(96.22,50.04) ; v1(120.8,42.19) 120.75,42.24 120.32,42.24 119.63,42.93 112.34,42.93 112.24,42.83 v1(112.24,42.75)
CPU_RSVD_AR54: length 5.5
  TOP w0.254: U14.AR54 119.28,42.2 v1(119.28,42.19)
  BOTTOM w0.102: R225.2 115.12,42.72 118.77,42.72 119.28,42.21 v1(119.28,42.19)
CPU_THERMTRIP_1P0_N: length 79.6
  TOP w0.099: v1(111.4,44.25) 111.33,44.25 111.23,44.35 110.31,44.35 110.2,44.23 R50.1
  TOP w0.102: U6.4 50.48,58.47 50.58,58.37 v1(51.49,58.37)
  TOP w0.254: U14.AT56 v1(119.26,43.64)
  L5_SIG w0.097: v1(51.49,58.37) 53.67,58.37 53.98,58.06 85.13,58.06 85.46,57.73 89.72,57.73 95.46,51.99 97.66,51.99 98.91,50.75 101.47,50.75 101.57,50.65 107.72,50.65 108.18,50.19 108.18,48.26 110.72,45.72 110.72,44.76 111.24,44.25 v1(111.4,44.25)
  BOTTOM w0.102: v1(111.4,44.25) 111.48,44.25 111.53,44.3 113.34,44.3 113.6,44.04 116.52,44.04 117.1,44.63 119.1,44.63 119.28,44.45 119.28,43.66 v1(119.26,43.64)
CPU_THERMTRIP_3P3_N: length 21.2
  TOP w0.102: U7.C5 v1(40.29,51.1) ; v1(46.02,55.69) 47.36,55.69 48.11,54.94 49.66,54.94 50.38,55.66 U6.3
  L3_SIG w0.097: v1(46.02,55.69) 45.95,55.62 45.95,53.17 44.49,51.71 41.8,51.71 41.19,51.1 v1(40.29,51.1)
  BOTTOM w0.097: v1(46.02,55.69) 47.15,55.69 47.96,54.89 49.45,54.89 49.97,55.41 R190.2
CSN1_VCCP: length 29.8
  L8_SIG w0.254: v1(59.41,27.2) 60.58,27.2 61.97,28.59 61.97,33.57 67.37,38.98 73.38,38.98 75.38,40.98 75.38,41.83 75.71,42.16 v1(76.59,42.16)
  BOTTOM w0.203: R290.2 59.08,28.41 C419.2
  BOTTOM w0.254: N37.2 v1(76.59,42.16) ; v1(59.41,27.2) 59.41,28.08 C419.2
CSN1_VCCP_R: length 2.1
  TOP w0.178: U23.40 56.12,28.79 v1(56.55,28.36)
  BOTTOM w0.381: v1(56.55,28.36) 56.61,28.41 R290.1
CSN1_VDDQ_CH01: length 39.4
  L5_SIG w0.254: v1(80.26,67.56) 80.75,68.05 83.54,68.05 84.07,68.58 87.02,68.58 87.96,67.64 87.96,66.83 88.57,66.22 94.89,66.22 95.27,65.84 97.8,65.84 98.26,66.29 101.53,66.29 101.68,66.45 110.88,66.45 112.01,67.58 112.01,67.59 112.75,68.33 v1(112.9,68.33)
  BOTTOM w0.254: R143.2 81.13,68.81 80.75,68.43 C184.2 79.71,67.86 80.01,67.56 v1(80.26,67.56) ; N27.2 v1(112.9,68.33)
CSN1_VNN: length 35.5
  TOP w0.254: R108.2 v1(52.54,25.02)
  L10_SIG w0.254: v1(76.81,32.99) 76.81,32.88 76.56,32.63 76.56,31.25 74.42,29.11 65.08,29.11 63.78,27.81 62.07,27.81 61.41,28.47 58.87,28.47 57.79,27.4 56.43,27.4 53.98,24.94 v1(53.98,24.39)
  BOTTOM w0.254: v1(76.81,32.99) 77.06,33.25 N43.2 ; v1(52.54,25.02) 52.3,24.78 C444.2 R316.2 52.7,22.35 53.21,22.86 53.21,23.66 53.94,24.38 53.98,24.38 v1(53.98,24.39)
CSN1_VNN_R: length 2.2
  TOP w0.203: R108.1 52.12,27.17 52.12,28.79 U23.32
CSP1_VCCP: length 26.6
  L8_SIG w0.254: v1(60.17,27.86) 60.72,27.86 61.61,28.76 61.61,33.72 67.22,39.33 73.23,39.33 75.02,41.12 75.02,41.75 74.71,42.06 v1(74.03,42.06)
  BOTTOM w0.254: R287.2 60.17,28.2 v1(60.17,27.86) ; N38.2 v1(74.03,42.06)
CSP1_VCCP_R: length 3.9
  TOP w0.178: U23.39 54.92,28.16 55.11,27.97 55.65,27.97 v1(55.8,28.12)
  BOTTOM w0.254: v1(55.8,28.12) 55.8,28.58 56.4,29.17 56.96,29.17 R284.1
CSP1_VDDQ_CH01: length 39.3
  L5_SIG w0.254: v1(111.51,68.33) 111.51,67.79 110.52,66.8 98.05,66.8 97.59,66.34 95.48,66.34 95.1,66.73 88.82,66.73 88.49,67.06 88.49,67.84 87.25,69.09 83.69,69.09 83.19,68.58 79.6,68.58 78.97,69.22 78.23,69.22 v1(77.62,68.61)
  BOTTOM w0.254: 78.27,69.25 v1(77.62,68.61) ; 78.27,69.25 R142.2 78.29,69.27 78.27,69.25 ; N28.2 v1(111.51,68.33)
CSP1_VNN: length 33.2
  L10_SIG w0.254: v1(53.98,23.5) 53.34,24.13 53.34,24.81 56.28,27.75 57.65,27.75 58.72,28.83 61.56,28.83 62.22,28.16 63.64,28.16 64.73,29.26 64.94,29.46 74.27,29.46 76.2,31.4 76.2,32.76 v1(76,32.97)
  BOTTOM w0.254: N44.2 75.59,33.45 76,33.05 v1(76,32.97) ; R320.2 53.21,21.4 53.21,22.21 53.67,22.67 53.67,23.19 v1(53.98,23.5)
CSP1_VNN_R: length 2.1
  TOP w0.203: R107.1 51.72,26.94 U23.31
CTBTRIGINOUT: length 2.8
  TOP w0.099: v1(123.49,41.02) 123.28,41.02 U14.AM47
  BOTTOM w0.097: v1(123.49,41.02) 123.11,41.4 123.11,42.02 R224.1
CTBTRIGOUT: length 35.4
  TOP w0.254: U14.AL47 122.66,40.19 v1(122.66,40.13)
  BOTTOM w0.097: 115.77,53.57 114.33,55.02 106.75,55.02 104.62,57.15 103.12,57.15 102.87,57.4 R185.1 ; 122.35,43.43 122.45,43.33 122.91,43.33 123.01,43.23 123.01,42.52
  BOTTOM w0.102: v1(122.66,40.13) 123.14,40.61 123.8,40.61 123.95,40.77 123.95,41.58 123.01,42.52 ; 122.35,43.43 122.2,43.59 122.2,44.78 121.6,45.38 120.82,45.38 120.63,45.58 120.63,46.26 120.06,46.82 118.89,46.82 118.49,47.22 118.49,49.83 118.14,50.19 116.99,50.19 116.36,50.83 116.36,52.22 115.85,52.73 115.85,53.49 115.77,53.57
DAT_C: length 33.7
  TOP w0.099: R67.1 92.35,38.3 92.35,38.94 v1(92.02,39.27)
  TOP w0.254: U14.T59 117.28,33.58 117.28,33.66 117.32,33.69 v1(117.34,33.71)
  L5_SIG w0.097: v1(117.34,33.71) 116.83,33.71 116.51,34.04 115.59,34.04 113.38,31.83 112.27,31.83 110.97,30.53 109.96,30.53 108.38,32.11 105.08,32.11 104.55,32.64 101.75,32.64 100.38,34.01 100.37,34.01 100.3,34.08 98.13,34.08 96.7,35.51 96.7,37.62 95.83,38.48 92.94,38.48 92.15,39.27 v1(92.02,39.27)
DDR3_0_DRAM_PWROK: length 31.4
  TOP w0.102: v1(138.49,48.25) 138.14,48.6 U14.BG17
  BOTTOM w0.097: U36.4 131.65,70.68 R139.2 C173.1
  BOTTOM w0.102: v1(138.49,48.25) 138.48,48.25 138.08,48.65 138.08,49.18 138.1,49.2 138.1,51.76 140.82,54.48 140.82,61.01 138.43,63.4 136.45,63.4 134.87,64.97 134.87,67.67 134.19,68.35 133.17,68.35 132.69,68.83 131.95,68.83 131.65,69.14 U36.4
DDR3_0_VCCA_PWROK: length 127.1
  TOP w0.099: U1.4 47.25,71.57 47.62,71.2 47.62,70.1 v1(49.28,68.45) 49.85,67.88 R9.2
  TOP w0.102: v1(138.49,47.49) 138.14,47.84 U14.BE17
  L5_SIG w0.097: v1(130.68,68.71) 130.68,67.72 128.93,65.96 125.53,65.96 124.89,65.33 121.92,65.33 119.61,63.02 116.87,63.02 115.8,61.95 96.16,61.95 94.71,60.5 88.8,60.5 87.27,62.03 80.32,62.03 79.89,61.59 77.95,61.59 77.51,61.15 69.97,61.15 67.49,63.63 67.49,64.77 65.84,66.42 60.17,66.42 56.9,69.7 54.2,69.7 53.78,69.27 52.73,68.22 49.5,68.22 v1(49.28,68.45)
  BOTTOM w0.097: v1(130.68,68.71) 130.97,68.71 131.22,68.46 132.43,68.46 132.97,67.92 134.09,67.92 134.47,67.54 134.47,64.77 136.37,62.87 138.38,62.87 140.31,60.93 140.31,54.89 138.94,53.52 C241.1 137.9,53.26 137.9,49.28 137.88,49.27 137.88,48.27 138.49,47.67 v1(138.49,47.49)
DDR3_1_DRAM_PWROK: length 156.9
  TOP w0.099: U11.4 40.31,45.32 40.41,45.42 41,45.42 41.05,45.36 v1(41.14,45.36)
  TOP w0.152: v1(138.03,31.37) 138.38,31.02 U14.L17
  L3_SIG w0.152: v1(138.03,31.37) 138.03,31.33 138.56,30.8 138.56,25.3 132.82,19.56 131.44,19.56 131.19,19.3 131.19,18.41 129.54,16.76 125.27,16.76 123.95,18.09 122.86,18.09 122.05,17.28 120.01,17.28 119.52,17.77 119.52,18.21 119.2,18.53 110.98,18.53 110.11,17.65 109.41,17.65 v1(109.4,17.64)
  L3_SIG w0.254: v1(34.14,27.99) 42.34,19.79 52.68,19.79 54.08,18.39 54.08,14.99 54.61,14.45 60.81,14.45 63.25,16.89 66.93,16.89 v1(67.56,16.26)
  L8_SIG w0.097: v1(34.14,27.99) 33.88,28.24 33.88,33.78 35.48,35.38 36.07,35.38 38.86,38.18 38.86,40.94 39.56,41.64 39.56,43.65 41.14,45.22 v1(41.14,45.36)
  L8_SIG w0.152: v1(67.56,16.26) 68.39,15.43 76.24,15.43 v1(78.04,13.63) ; v1(89.09,17.51) 90.28,17.51 91.59,16.21 98.96,16.21 100.74,17.98 102.72,17.98 103.99,16.71 108.64,16.71 109.4,17.48 v1(109.4,17.64)
  BOTTOM w0.097: v1(41.14,45.36) 41.14,45.15 40.59,44.6 R222.2 40.39,44.51 C300.1
  BOTTOM w0.152: v1(78.04,13.63) 78.61,14.2 83.31,14.2 84.86,15.75 84.86,17.53 85.38,18.04 88.61,18.04 89.09,17.56 v1(89.09,17.51)
DDR3_1_VCCA_PWROK: length 156.6
  TOP w0.099: U13.4 38.19,38.27 37.28,38.27 v1(37.17,38.16)
  TOP w0.254: U14.N17 138.38,31.79 v1(138.03,32.14)
  L3_SIG w0.254: 41.78,19.02 52.68,19.02 53.44,18.26 53.44,14.81 54.79,13.46
  L3_SIG w0.305: v1(138.03,32.14) 138.35,31.82 141.58,31.82 142.06,31.34 142.06,30.33 141.38,29.64 141.38,24.43 141.04,24.1 141.04,16.22 138.82,14.01 126.96,14.01 126.49,14.48 120.27,14.48 120.19,14.4 119.23,14.4 118.92,14.71 116.33,14.71 115.73,14.1 97.27,14.1 97.25,14.12 93.09,14.12 91.84,15.38 68.9,15.38 66.98,13.46 54.79,13.46 ; 41.78,19.02 v1(34.04,26.77)
  L8_SIG w0.097: v1(37.17,38.16) 36.4,37.39 35.81,37.39 32.26,33.83 32.26,32.89 33.36,31.8 33.36,27.3 33.88,26.77 v1(34.04,26.77)
  BOTTOM w0.097: R239.2 38.23,38.27 37.28,38.27 v1(37.17,38.16)
  BOTTOM w0.254: C390.1 138.67,31.49 v1(138.03,32.14)
DDR3_CPU_CH0_BA0: length 109.7
  TOP w0.102: v1(141.21,52.87) 141.29,52.79 141.29,52.18 141.06,51.96 141.06,51.33 U14.BL12
  TOP w0.157: v1(200.56,43.13) 200.64,43.05 P1.119
  L5_SIG w0.191: v1(142.34,62.21) 142.34,63.93 144.47,66.07 173.84,66.07 177.19,62.71 178.69,62.71 179.93,61.47 179.93,59.97 183.81,56.1 183.81,53.64 184,53.45 187.6,53.45 187.73,53.31 187.73,52.88 187.54,52.69 184.49,52.69 184.3,52.5 184.3,50.84 184.49,50.65 184.89,50.65 185.12,50.88 185.12,51.64 185.55,52.08 186.5,52.08 186.69,51.89 186.69,50.84 186.88,50.65 187.87,50.65 188.03,50.5 188.03,50.05 187.84,49.86 186.91,49.86 186.72,49.67 186.72,48.78 186.52,48.59 186.07,48.59 185.88,48.78 185.88,49.67 185.69,49.86 184.84,49.86 184.56,49.58 184.56,48.77 184.75,48.58 184.95,48.58 185.14,48.39 185.14,48.01 184.95,47.82 184.75,47.82 184.56,47.63 184.56,46.99 184.86,46.69 187.55,46.69 188.34,45.9 188.8,45.9 191.34,43.36 192.02,43.36 192.11,43.46 192.26,43.6 196.03,43.6 196.57,43.05 197.28,43.05 197.7,43.48 200.21,43.48 v1(200.56,43.13)
  L8_SIG w0.191: v1(141.21,52.87) 141.21,53.04 140.82,53.43 140.82,61.51 141.52,62.21 v1(142.34,62.21)
DDR3_CPU_CH0_BA1: length 108.6
  TOP w0.102: U14.BL10 141.28,51.25 141.28,51.82 141.62,52.16 141.62,53.55 v1(141.69,53.63)
  TOP w0.157: P1.108 193.17,39.75 192.99,39.92 192.34,39.92 v1(191.87,39.45)
  L5_SIG w0.191: v1(191.87,39.45) 191.85,39.47 189.51,39.47 188.72,40.26 176.37,40.26 175.15,41.48 174.6,41.48 174.42,41.29 174.15,41.29 173.88,41.56 173.88,41.83 174.2,42.16 174.2,42.42 173.93,42.69 173.66,42.69 173.34,42.37 173.07,42.37 172.8,42.64 172.8,42.91 173.12,43.23 173.12,43.5 172.81,43.82 171.74,43.82 171.55,44.01 171.55,44.39 171.74,44.58 172.81,44.58 173,44.77 173,45.15 172.81,45.34 171.74,45.34 171.55,45.53 171.55,45.91 171.74,46.1 172.81,46.1 173,46.29 173,46.68 172.81,46.87 171.74,46.87 171.55,47.06 171.55,47.44 171.74,47.63 172.81,47.63 173,47.82 173,48.2 172.81,48.39 171.74,48.39 171.55,48.58 171.55,48.96 171.74,49.15 172.81,49.15 173,49.34 173,49.72 172.81,49.91 171.74,49.91 171.55,50.1 171.55,50.49 171.74,50.68 172.81,50.68 173,50.87 173,51.25 172.81,51.44 171.74,51.44 171.55,51.63 171.55,52.01 171.74,52.2 172.81,52.2 173,52.39 173,52.77 172.81,52.96 171.74,52.96 171.55,53.15 171.55,53.53 171.74,53.72 172.81,53.72 173,53.91 173,54.3 172.81,54.49 171.74,54.49 171.55,54.68 171.55,55.06 171.74,55.25 172.81,55.25 173,55.44 173,55.82 172.81,56.01 171.74,56.01 171.55,56.2 171.55,56.58 171.74,56.77 172.81,56.77 173,56.96 173,57.34 172.81,57.53 171.74,57.53 171.55,57.72 171.55,58.11 171.74,58.3 172.81,58.3 173,58.49 173,58.87 172.81,59.06 171.74,59.06 171.55,59.25 171.55,59.63 171.74,59.82 172.81,59.82 173,60.01 173,60.53 171.7,61.82 148.64,61.82 146.69,59.87 146.69,58.04 143.33,54.69 142.75,54.69 v1(141.69,53.63)
DDR3_CPU_CH0_BA2: length 107.6
  TOP w0.157: U14.BC8 142.55,46.72 v1(142.93,46.34) ; P1.91 201.02,34.65 v1(200.85,34.35)
  L5_SIG w0.102: 149.4,48.49 148.13,48.49 147.73,48.9 145.57,48.9 145.41,49.05 145.07,49.05 144.8,48.78 144.8,47.98 143.96,47.14 143.73,47.14 v1(142.93,46.34)
  L5_SIG w0.191: v1(200.85,34.35) 200.85,34.6 200.45,35 199.54,35 198.15,33.61 198.15,20.43 197.83,20.12 197.1,20.12 196.4,20.82 195.41,20.82 195,20.41 195,18.52 193.17,16.69 165.23,16.69 160.93,20.98 160.93,42.67 159.57,44.04 159.3,44.04 159,43.74 158.73,43.74 158.46,44.01 158.46,44.28 158.76,44.58 158.76,44.85 158.49,45.12 158.22,45.12 157.92,44.81 157.65,44.81 157.38,45.08 157.38,45.35 157.68,45.66 157.68,45.92 155.13,48.48 149.41,48.48 149.4,48.49
DDR3_CPU_CH0_CAS_N: length 113.3
  TOP w0.157: P1.125 201.02,44.85 200.74,45.14 v1(200.74,45.44) ; v1(133.82,49.01) 133.47,49.36 U14.BH26
  L5_SIG w0.102: v1(133.82,49.01) 133.82,50.04 134.09,50.31 134.09,52.11 136.3,54.32 136.3,55.25
  L5_SIG w0.191: 136.3,55.25 137.08,56.03 137.08,57.85 137.37,58.14 137.37,63 142.15,67.78 174.58,67.78 177.94,64.43 179.4,64.43 181.55,62.28 181.94,62.28 182.13,62.47 182.13,64.02 182.32,64.21 182.7,64.21 182.89,64.02 182.89,62.4 183.08,62.2 183.46,62.2 183.65,62.4 183.65,64.02 183.84,64.21 184.23,64.21 184.42,64.02 184.42,62.4 184.61,62.2 184.99,62.2 185.18,62.4 185.18,64.02 185.37,64.21 185.75,64.21 185.94,64.02 185.94,62.4 186.38,61.95 188.82,61.95 189.48,61.29 189.48,59.89 189.94,59.44 189.94,46.28 191.06,45.16 193.75,45.16 194.13,45.54 194.13,46.28 194.46,46.61 197.15,46.61 198.14,45.62 200.56,45.62 v1(200.74,45.44)
DDR3_CPU_CH0_CK_DN0: length 110.9
  TOP w0.157: v1(200.09,41.55) 200.34,41.12 201.12,41.12 201.25,41.25 P1.113 ; v1(136.5,46.35) 136.15,46.7 U14.BC21
  L5_SIG w0.102: v1(136.5,46.35) 136.5,46.23 136.66,46.07 136.91,46.07 137.01,46.17 137.01,47.79 137.9,48.67 137.9,51.77 141.5,55.37 141.5,55.41 141.51,55.43
  L5_SIG w0.135: 141.51,55.43 142.11,56.03 143.32,56.03 145.51,58.23 145.51,60.62 147.82,62.93 172.33,62.93 175.12,60.15 175.12,59.47 174.83,59.18 174.26,59.18 174.12,59.05 174.12,58.78 174.26,58.64 174.83,58.64 175.12,58.36 175.12,57.87 174.83,57.58 174.26,57.58 174.12,57.45 174.12,57.18 174.26,57.04 174.83,57.04 175.12,56.76 175.12,56.27 174.83,55.98 174.26,55.98 174.12,55.85 174.12,55.58 174.26,55.44 174.83,55.44 175.12,55.16 175.12,54.67 174.83,54.38 174.26,54.38 174.12,54.25 174.12,53.98 174.26,53.84 174.83,53.84 175.12,53.56 175.12,53.07 174.83,52.78 174.26,52.78 174.12,52.65 174.12,52.38 174.26,52.24 174.83,52.24 175.12,51.96 175.12,51.47 174.83,51.18 174.26,51.18 174.12,51.05 174.12,50.78 174.26,50.64 174.83,50.64 175.12,50.36 175.12,49.87 174.83,49.58 174.26,49.58 174.12,49.45 174.12,49.18 174.26,49.04 174.83,49.04 175.12,48.76 175.12,48.27 174.83,47.98 174.26,47.98 174.12,47.85 174.12,47.58 174.26,47.44 174.83,47.44 175.12,47.16 175.12,46.67 174.83,46.38 174.26,46.38 174.12,46.25 174.12,45.98 174.26,45.84 174.83,45.84 175.12,45.55 175.12,43.86 177.29,41.68 188.55,41.68 190.04,40.2 197.11,40.2 198.27,41.36 199.66,41.36 199.87,41.58 200.06,41.58 v1(200.09,41.55)
DDR3_CPU_CH0_CK_DN1: length 112.2
  TOP w0.157: U14.BG21 136.15,48.98 v1(136.5,48.63) ; P1.114 192.77,41.55 v1(192.47,41.85)
  L5_SIG w0.102: 142.4,57.31 142.38,57.29 142.38,57.25 136.4,51.27 136.4,50.85 136.61,50.65 136.61,50.5 136.45,50.35 136.45,49.96 136.55,49.86 136.55,49.66 136.35,49.46 136.35,48.79 v1(136.5,48.63)
  L5_SIG w0.135: v1(192.47,41.85) 192.47,41.78 192.07,41.38 191.53,41.38 191.45,41.46 190.56,41.46 189.16,42.86 178.98,42.86 178.11,43.73 178.11,45.54 177.82,45.82 176.37,45.82 176.23,45.96 176.23,46.23 176.37,46.36 177.82,46.36 178.11,46.65 178.11,47.14 177.82,47.42 176.37,47.42 176.23,47.56 176.23,47.83 176.37,47.96 177.82,47.96 178.11,48.25 178.11,48.74 177.82,49.02 176.37,49.02 176.23,49.16 176.23,49.43 176.37,49.56 177.82,49.56 178.11,49.85 178.11,50.34 177.82,50.62 176.37,50.62 176.23,50.76 176.23,51.03 176.37,51.16 177.82,51.16 178.11,51.45 178.11,51.94 177.82,52.22 176.37,52.22 176.23,52.36 176.23,52.63 176.37,52.76 177.82,52.76 178.11,53.05 178.11,53.54 177.82,53.82 176.37,53.82 176.23,53.96 176.23,54.23 176.37,54.36 177.82,54.36 178.11,54.65 178.11,55.14 177.82,55.43 176.37,55.43 176.23,55.56 176.23,55.83 176.37,55.96 177.82,55.96 178.11,56.25 178.11,56.74 177.82,57.03 176.37,57.03 176.23,57.16 176.23,57.43 176.37,57.56 177.82,57.56 178.11,57.85 178.11,58.68 172.72,64.07 147.37,64.07 143.28,59.99 143.28,58.19 142.4,57.31
DDR3_CPU_CH0_CK_DP0: length 111
  TOP w0.157: v1(136.5,45.59) 136.15,45.94 U14.BA21 ; v1(200.85,40.35) 201.15,40.65 P1.111
  L5_SIG w0.102: v1(136.5,45.59) 136.5,45.76 136.61,45.87 137,45.87 137.22,46.09 137.22,47.71 138.1,48.59 138.1,50.45 138.22,50.57 138.22,50.78 138.1,50.9 138.1,51.69 141.64,55.23 141.68,55.23 141.7,55.25
  L5_SIG w0.135: v1(200.85,40.35) 200.1,41.1 198.38,41.1 197.22,39.94 189.93,39.94 188.45,41.42 177.18,41.42 174.85,43.75 174.85,45.45 174.72,45.58 174.15,45.58 173.86,45.87 173.86,46.35 174.15,46.64 174.72,46.64 174.85,46.78 174.85,47.05 174.72,47.18 174.15,47.18 173.86,47.47 173.86,47.96 174.15,48.24 174.72,48.24 174.85,48.38 174.85,48.65 174.72,48.78 174.15,48.78 173.86,49.07 173.86,49.56 174.15,49.84 174.72,49.84 174.85,49.98 174.85,50.25 174.72,50.38 174.15,50.38 173.86,50.67 173.86,51.16 174.15,51.44 174.72,51.44 174.85,51.58 174.85,51.85 174.72,51.98 174.15,51.98 173.86,52.27 173.86,52.76 174.15,53.04 174.72,53.04 174.85,53.18 174.85,53.45 174.72,53.58 174.15,53.58 173.86,53.87 173.86,54.36 174.15,54.64 174.72,54.64 174.85,54.78 174.85,55.05 174.72,55.18 174.15,55.18 173.86,55.47 173.86,55.96 174.15,56.24 174.72,56.24 174.85,56.38 174.85,56.65 174.72,56.78 174.15,56.78 173.86,57.07 173.86,57.56 174.15,57.84 174.72,57.84 174.85,57.98 174.85,58.25 174.72,58.38 174.15,58.38 173.86,58.67 173.86,59.16 174.15,59.44 174.72,59.44 174.85,59.58 174.85,60.04 172.22,62.67 147.93,62.67 145.77,60.52 145.77,58.12 143.42,55.77 142.22,55.77 141.7,55.25
DDR3_CPU_CH0_CK_DP1: length 112.2
  TOP w0.157: v1(136.5,47.87) 136.15,48.22 U14.BF21 ; v1(191.74,40.92) 191.95,41.12 192.84,41.12 193.01,40.95 P1.112
  L5_SIG w0.102: v1(136.5,47.87) 136.66,48.03 136.66,48.21 136.67,48.22 136.68,48.22 136.97,48.51 136.97,51.55 142.53,57.11 142.57,57.11 142.59,57.13
  L5_SIG w0.135: 142.59,57.13 143.54,58.08 143.54,59.88 147.47,63.81 172.61,63.81 177.85,58.57 177.85,57.96 177.72,57.83 176.26,57.83 175.97,57.54 175.97,57.05 176.26,56.76 177.72,56.76 177.85,56.63 177.85,56.36 177.72,56.23 176.26,56.23 175.97,55.94 175.97,55.45 176.26,55.16 177.72,55.16 177.85,55.03 177.85,54.76 177.72,54.62 176.26,54.62 175.97,54.34 175.97,53.85 176.26,53.56 177.72,53.56 177.85,53.43 177.85,53.16 177.72,53.02 176.26,53.02 175.97,52.74 175.97,52.25 176.26,51.96 177.72,51.96 177.85,51.83 177.85,51.56 177.72,51.42 176.26,51.42 175.97,51.14 175.97,50.65 176.26,50.36 177.72,50.36 177.85,50.23 177.85,49.96 177.72,49.82 176.26,49.82 175.97,49.54 175.97,49.05 176.26,48.76 177.72,48.76 177.85,48.63 177.85,48.36 177.72,48.22 176.26,48.22 175.97,47.94 175.97,47.45 176.26,47.16 177.72,47.16 177.85,47.03 177.85,46.76 177.72,46.62 176.26,46.62 175.97,46.34 175.97,45.85 176.26,45.56 177.72,45.56 177.85,45.43 177.85,43.62 178.87,42.6 189.05,42.6 190.45,41.2 191.34,41.2 191.62,40.92 v1(191.74,40.92)
DDR3_CPU_CH0_CKE0: length 109.4
  TOP w0.157: P1.87 201.15,33.45 200.92,33.23 200.81,33.23 v1(200.77,33.19) ; v1(145.24,48.65) 144.91,48.65 U14.BG4
  L5_SIG w0.191: v1(145.24,48.65) 146.85,47.04 152.86,47.04 154.41,45.49 154.41,25.3 165.84,13.87 176.12,13.87 176.31,14.06 176.31,14.57 176.5,14.76 176.88,14.76 177.07,14.57 177.07,14.06 177.26,13.87 177.64,13.87 177.83,14.06 177.83,14.57 178.02,14.76 178.41,14.76 178.6,14.57 178.6,14.06 178.79,13.87 179.17,13.87 179.36,14.06 179.36,14.57 179.55,14.76 179.93,14.76 180.12,14.57 180.12,14.06 180.31,13.87 180.69,13.87 180.88,14.06 180.88,14.57 181.07,14.76 181.45,14.76 181.64,14.57 181.64,14.06 181.83,13.87 182.22,13.87 182.41,14.06 182.41,14.47 182.6,14.66 182.98,14.66 183.17,14.47 183.17,14.06 183.36,13.87 187.88,13.87 188.29,13.46 193.24,13.46 194.44,14.66 194.44,15.68 195.34,16.59 198.5,16.59 199.19,17.27 200.71,17.27 201.57,18.13 201.57,32.38 v1(200.77,33.19)
DDR3_CPU_CH0_CKE1: length 109.6
  TOP w0.102: v1(147.07,48.26) 146.81,48.26 146.43,47.88 146.05,47.88 146.05,47.89 146.04,47.89 145.67,48.26 145.67,48.9 145.51,49.05 145.15,49.05 145.05,49.15 144.2,49.15 U14.BH5
  TOP w0.157: P1.89 201.32,34.05 201.15,33.89 200.55,33.89 v1(200.09,34.35)
  L5_SIG w0.191: v1(147.07,48.26) 147.42,47.91 153.19,47.91 155.3,45.8 155.3,25.73 165.24,15.79 166.81,15.79 167,15.6 167,15.2 167.19,15.01 167.57,15.01 167.76,15.2 167.76,15.6 167.95,15.79 168.33,15.79 168.52,15.6 168.52,15.2 168.71,15.01 169.1,15.01 169.29,15.2 169.29,15.6 169.48,15.79 169.86,15.79 170.05,15.6 170.05,15.2 170.24,15.01 170.62,15.01 170.81,15.2 170.81,15.6 171,15.79 171.38,15.79 171.57,15.6 171.57,15.2 171.76,15.01 172.14,15.01 172.33,15.2 172.33,15.6 172.52,15.79 172.91,15.79 173.1,15.6 173.1,15.2 173.29,15.01 173.67,15.01 173.86,15.2 173.86,15.6 174.05,15.79 174.43,15.79 174.62,15.6 174.62,15.2 174.81,15.01 175.19,15.01 175.38,15.2 175.38,15.6 175.57,15.79 186.4,15.79 187.15,15.03 189.41,15.03 189.69,14.76 193.29,14.76 193.62,15.09 193.62,16.03 195.35,17.75 198.35,17.75 198.73,18.13 198.73,33.36 199.72,34.35 v1(200.09,34.35)
DDR3_CPU_CH0_CS_N0: length 112.1
  TOP w0.157: v1(134.62,48.26) 134.56,48.26 U14.BE25 ; P1.127 v1(203.76,45.45)
  L5_SIG w0.102: 136.96,54.96 136.96,54.59 134.85,52.49 134.85,48.49 v1(134.62,48.26)
  L5_SIG w0.191: 136.96,54.96 138.12,56.12 138.12,58.7 138.71,59.28 138.71,63.22 139,63.51 139.66,63.51 139.93,63.78 139.93,64.44 142.7,67.21 174.35,67.21 174.35,67.18 177.67,63.86 179.16,63.86 181.08,61.94 181.08,61.28 181.27,61.09 183.08,61.09 183.29,60.88 183.29,60.13 183.48,59.94 185.54,59.94 185.73,60.13 185.73,60.97 185.92,61.16 188.24,61.16 188.75,60.65 188.75,59.8 188.51,59.55 186.73,59.55 186.49,59.31 185.92,59.31 185.7,59.09 185.7,58.38 185.92,58.17 189,58.17 189.36,57.81 189.36,46.33 190.9,44.79 191.94,44.79 192.15,44.58 194.83,44.58 195.58,45.33 197.11,45.33 197.37,45.07 199.84,45.07 200.1,44.81 201.85,44.81 202.5,45.45 v1(203.76,45.45)
DDR3_CPU_CH0_CS_N1: length 111.1
  TOP w0.157: U14.BB25 134.22,46.35 v1(134.63,46.76) ; v1(200.8,46.24) 200.98,46.05 P1.129
  L5_SIG w0.102: 132.54,50.79 132.54,49.83 132.21,49.5 132.21,47.13 132.61,46.73 132.69,46.73 132.91,46.51 132.91,46.16 132.59,45.84 132.59,45.52 132.81,45.3 134.07,45.3 134.41,45.64 134.41,46.33 134.43,46.34 134.43,46.56 v1(134.63,46.76)
  L5_SIG w0.191: v1(200.8,46.24) 199.44,46.24 196.12,49.56 195.94,49.56 195.73,49.78 195.7,49.78 193.85,51.63 193.85,62.37 186.15,70.07 139.28,70.07 133.82,64.61 133.82,53.43 133.81,53.41 133.81,53.35 132.54,52.08 132.54,50.79
DDR3_CPU_CH0_DQ0: length 86.9
  TOP w0.102: U14.AM15 139.47,41.16 v1(139.5,41.16)
  TOP w0.157: P1.5 201.04,6.45 v1(200.81,6.22)
  L3_SIG w0.102: 147.22,33.38 144.9,35.69 144.4,35.69 143.13,36.97 143.13,37.16 142.64,37.65 142.33,37.65 142.18,37.8 142.18,38.05 141.79,38.43 140.84,38.43 140.27,39.01 140.27,39.37 139.85,39.79 139.85,40.81 v1(139.5,41.16)
  L3_SIG w0.135: v1(200.81,6.22) 196.34,6.22 195.96,6.6 193.24,6.6 192.91,6.93 191.19,6.93 189.46,5.2 165.42,5.2 155.52,15.1 155.52,26.21 149.46,32.27 148.33,32.27 147.22,33.38
DDR3_CPU_CH0_DQ1: length 86.8
  TOP w0.102: U14.AM14 140.23,41.16 v1(140.26,41.16)
  TOP w0.157: v1(200.89,7.14) 200.98,7.05 P1.7
  L3_SIG w0.102: v1(140.26,41.16) 140.62,40.8 140.62,39.95 141.03,39.54 141.03,39 141.27,38.76 143.6,38.76 144.12,38.24 144.12,36.75 144.7,36.17 145.07,36.17 147.42,33.81
  L3_SIG w0.135: v1(200.89,7.14) 200.65,6.9 199.35,6.9 199.07,7.18 196.08,7.18 195.86,6.96 195.32,6.96 195.04,7.24 190.7,7.24 189.23,5.77 165.66,5.77 165.2,6.22 165.2,6.65 164.8,7.06 164.36,7.06 156.09,15.34 156.09,26.58 149.42,33.25 147.99,33.25 147.42,33.81
DDR3_CPU_CH0_DQ2: length 86.9
  TOP w0.102: v1(143.38,40.45) 143.33,40.5 143.26,40.5 142.96,40.81 U14.AL8
  TOP w0.157: v1(200.81,8.74) 200.92,8.85 P1.13
  L3_SIG w0.102: v1(143.38,40.45) 144.1,40.45 144.53,40.01 145.04,40.01 145.08,40.06 145.66,40.06 146.09,39.63 147.21,39.63 148.59,38.25 152.34,38.25 153.55,37.04
  L3_SIG w0.135: 153.55,37.04 153.95,36.64 153.95,33.91 157.83,30.03 158.02,30.03 158.14,30.16 158.33,30.16 158.52,29.97 158.52,29.78 158.4,29.65 158.4,29.46 160.17,27.69 160.17,27.06 160.31,26.93 160.49,26.93 160.63,26.8 160.63,26.53 160.49,26.39 160.31,26.39 160.17,26.26 160.17,25.99 160.31,25.85 160.49,25.85 160.63,25.72 160.63,25.45 160.49,25.31 160.31,25.31 160.17,25.18 160.17,24.91 160.31,24.78 160.49,24.78 160.63,24.64 160.63,24.37 160.49,24.24 160.31,24.24 160.17,24.1 160.17,23.83 160.31,23.7 160.49,23.7 160.63,23.56 160.63,23.3 160.49,23.16 160.24,23.16 160.13,23.05 160.13,22.74 160.24,22.62 160.49,22.62 160.63,22.49 160.63,22.22 160.49,22.08 160.31,22.08 160.17,21.95 160.17,21.68 160.31,21.55 160.49,21.55 160.63,21.41 160.63,21.14 160.49,21.01 160.31,21.01 160.17,20.87 160.17,14.25 164.11,10.32 186.05,10.32 186.73,9.63 190.33,9.63 190.53,9.83 192.19,9.83 192.42,9.6 192.48,9.6 192.5,9.58 192.87,9.58 192.88,9.6 195.83,9.6 196.32,9.11 196.45,9.11 197.03,8.53 200.56,8.53 200.76,8.74 v1(200.81,8.74)
DDR3_CPU_CH0_DQ3: length 86.9
  TOP w0.102: U14.AM8 143.26,41.51 v1(143.51,41.26)
  TOP w0.157: v1(200.76,9.5) 200.81,9.45 P1.15
  L3_SIG w0.102: v1(143.51,41.26) 144.03,41.26 144.32,40.98 145.03,40.98 145.16,41.1 147.43,41.1 148.7,39.83 152.63,39.83 154.03,38.43
  L3_SIG w0.135: v1(200.76,9.5) 200.75,9.52 197.21,9.52 196.72,10.01 195.98,10.01 195.29,10.69 189.43,10.69 189.09,10.35 187.52,10.35 186.42,11.45 167.85,11.45 166.98,12.32 166.79,12.32 166.66,12.19 166.47,12.19 166.28,12.38 166.28,12.57 166.41,12.7 166.41,12.89 165.79,13.51 165.6,13.51 165.17,13.08 164.98,13.08 164.78,13.27 164.78,13.46 165.22,13.89 165.22,14.08 165.02,14.27 164.83,14.27 164.43,13.87 164.24,13.87 164.05,14.06 164.05,14.25 164.45,14.66 164.45,14.85 164.26,15.04 164.07,15.04 163.67,14.63 163.48,14.63 163.28,14.82 163.28,15.01 163.69,15.42 163.69,15.61 163.5,15.8 163.31,15.8 162.9,15.39 162.71,15.39 162.52,15.58 162.52,15.77 162.93,16.18 162.93,16.37 162.33,16.97 162.33,28.48 155.24,35.57 155.24,37.21 154.03,38.43
DDR3_CPU_CH0_DQ4: length 86.9
  TOP w0.102: v1(138.74,41.16) 138.71,41.16 U14.AM17
  TOP w0.157: v1(192.71,6.32) 192.71,6.31 192.87,6.15 P1.4
  L3_SIG w0.102: v1(138.74,41.16) 138.73,41.15 138.73,38.2 139.13,37.8 139.13,36.72 138.76,36.35 138.76,35.56 139.77,34.55 140.83,34.55
  L3_SIG w0.135: 140.83,34.55 142.93,34.55 144.05,33.43 144.05,31.23 144.69,30.59 148.48,30.59 154.39,24.68 154.39,13.54 156.11,11.82 156.11,11.63 156.1,11.62 156.1,11.43 156.3,11.24 156.49,11.24 156.56,11.32 156.75,11.32 156.94,11.13 156.94,10.94 156.87,10.86 156.87,10.67 157.06,10.48 157.25,10.48 157.32,10.56 157.51,10.56 157.71,10.37 157.71,10.18 157.63,10.1 157.63,9.91 157.82,9.72 158.01,9.72 158.09,9.8 158.28,9.8 158.47,9.6 158.47,9.41 158.39,9.34 158.39,9.15 158.58,8.96 158.77,8.96 158.85,9.03 159.04,9.03 159.54,8.53 159.54,8.34 159.34,8.14 159.34,7.95 159.54,7.76 159.73,7.76 159.91,7.94 160.13,7.94 164.01,4.07 191.9,4.07 192.71,4.88 v1(192.71,6.32)
DDR3_CPU_CH0_DQ5: length 86.9
  TOP w0.102: U14.AL15 139.38,40.54 v1(139.38,40.37)
  TOP w0.157: P1.6 193.02,6.75 192.96,6.81 192.35,6.81 192.02,6.48 v1(191.95,6.48)
  L3_SIG w0.102: v1(139.38,40.37) 139.49,40.26 139.49,38.6 139.7,38.39 140.31,38.39 140.64,38.07 140.64,37.75 140.64,37.75 140.64,36.6 140.79,36.45 142.95,36.45 144.88,34.52 145.29,34.52 146.52,33.29
  L3_SIG w0.135: 146.52,33.29 148.26,31.55 149.39,31.55 154.95,25.98 154.95,14.85 155.34,14.46 155.34,14.2 155.18,14.04 155.18,13.85 155.38,13.66 155.57,13.66 155.72,13.81 155.91,13.81 156.1,13.62 156.1,13.43 155.95,13.28 155.95,13.09 156.14,12.9 156.33,12.9 156.48,13.05 156.67,13.05 156.86,12.86 156.86,12.67 156.71,12.52 156.71,12.33 156.9,12.14 157.09,12.14 157.24,12.29 157.43,12.29 157.62,12.1 157.62,11.91 157.47,11.76 157.47,11.57 157.66,11.38 157.85,11.38 158,11.53 158.19,11.53 158.39,11.34 158.39,11.15 158.23,10.99 158.23,10.8 158.42,10.61 158.61,10.61 158.77,10.77 158.96,10.77 159.15,10.58 159.15,10.39 158.99,10.23 158.99,10.04 159.19,9.85 159.38,9.85 159.53,10 159.72,10 159.91,9.81 159.91,9.62 159.76,9.47 159.76,9.28 159.95,9.09 160.14,9.09 160.29,9.24 160.48,9.24 160.67,9.05 160.67,8.86 160.52,8.71 160.52,8.52 160.71,8.33 160.9,8.33 161.05,8.48 161.24,8.48 161.43,8.29 161.43,8.1 161.25,7.91 161.25,7.72 161.44,7.53 161.63,7.53 161.81,7.72 162,7.72 162.2,7.53 162.2,7.34 162.04,7.18 162.04,6.99 162.23,6.8 162.42,6.8 162.58,6.96 162.77,6.96 162.96,6.77 162.96,6.1 163.09,5.97 163.75,5.97 163.96,5.77 163.96,5.33 164.16,5.13 164.59,5.13 165.09,4.63 190.38,4.63 191.95,6.2 v1(191.95,6.48)
DDR3_CPU_CH0_DQ6: length 86.9
  TOP w0.102: U14.AM11 141.44,41.51 v1(141.79,41.16)
  TOP w0.157: v1(192.58,9.12) 192.58,9.27 193.06,9.75 P1.16
  L3_SIG w0.102: 150.99,34.97 147.53,38.43 146.79,38.43 146.07,39.15 144.98,39.15 144.1,40.03 142.99,40.03 141.86,41.16 v1(141.79,41.16)
  L3_SIG w0.135: 150.99,34.97 151.84,34.12 152.9,34.12 153.95,33.08 153.95,32.88 153.54,32.48 153.54,32.29 153.73,32.1 153.92,32.1 154.33,32.5 154.52,32.5 154.71,32.31 154.71,32.12 154.3,31.72 154.3,31.53 154.49,31.34 154.68,31.34 155.09,31.74 155.28,31.74 155.47,31.55 155.47,31.36 155.06,30.95 155.06,30.76 155.25,30.57 155.44,30.57 155.85,30.98 156.04,30.98 156.23,30.79 156.23,30.6 155.82,30.19 155.82,30 156.02,29.81 156.21,29.81 156.61,30.22 156.8,30.22 156.99,30.03 156.99,29.84 156.58,29.43 156.58,29.24 156.77,29.05 156.97,29.05 157.37,29.46 157.56,29.46 157.76,29.27 157.76,29.07 157.32,28.64 157.32,28.45 157.51,28.26 157.71,28.26 158.16,28.72 158.34,28.72 158.54,28.52 158.54,28.33 158.11,27.91 158.11,27.72 158.3,27.53 158.49,27.53 158.9,27.93 159.09,27.93 159.56,27.46 159.56,14.06 163.87,9.75 171.69,9.75 171.94,9.5 172.23,9.5 172.48,9.75 172.76,9.75 173.06,9.45 173.25,9.45 173.55,9.75 173.84,9.75 174.12,9.47 174.35,9.47 174.63,9.75 174.92,9.75 175.22,9.45 175.41,9.45 175.71,9.75 176,9.75 176.27,9.47 176.51,9.47 176.78,9.75 177.07,9.75 177.35,9.47 177.59,9.47 177.86,9.75 178.54,9.75 178.72,9.58 179.08,9.58 179.26,9.75 179.62,9.75 179.8,9.58 180.16,9.58 180.33,9.75 180.7,9.75 180.9,9.55 181.21,9.55 181.41,9.75 181.78,9.75 181.95,9.58 182.31,9.58 182.49,9.75 183.36,9.75 183.64,9.47 184.05,9.47 184.32,9.75 185.58,9.75 186.59,8.74 190.35,8.74 191.02,9.41 191.98,9.41 192.28,9.12 v1(192.58,9.12)
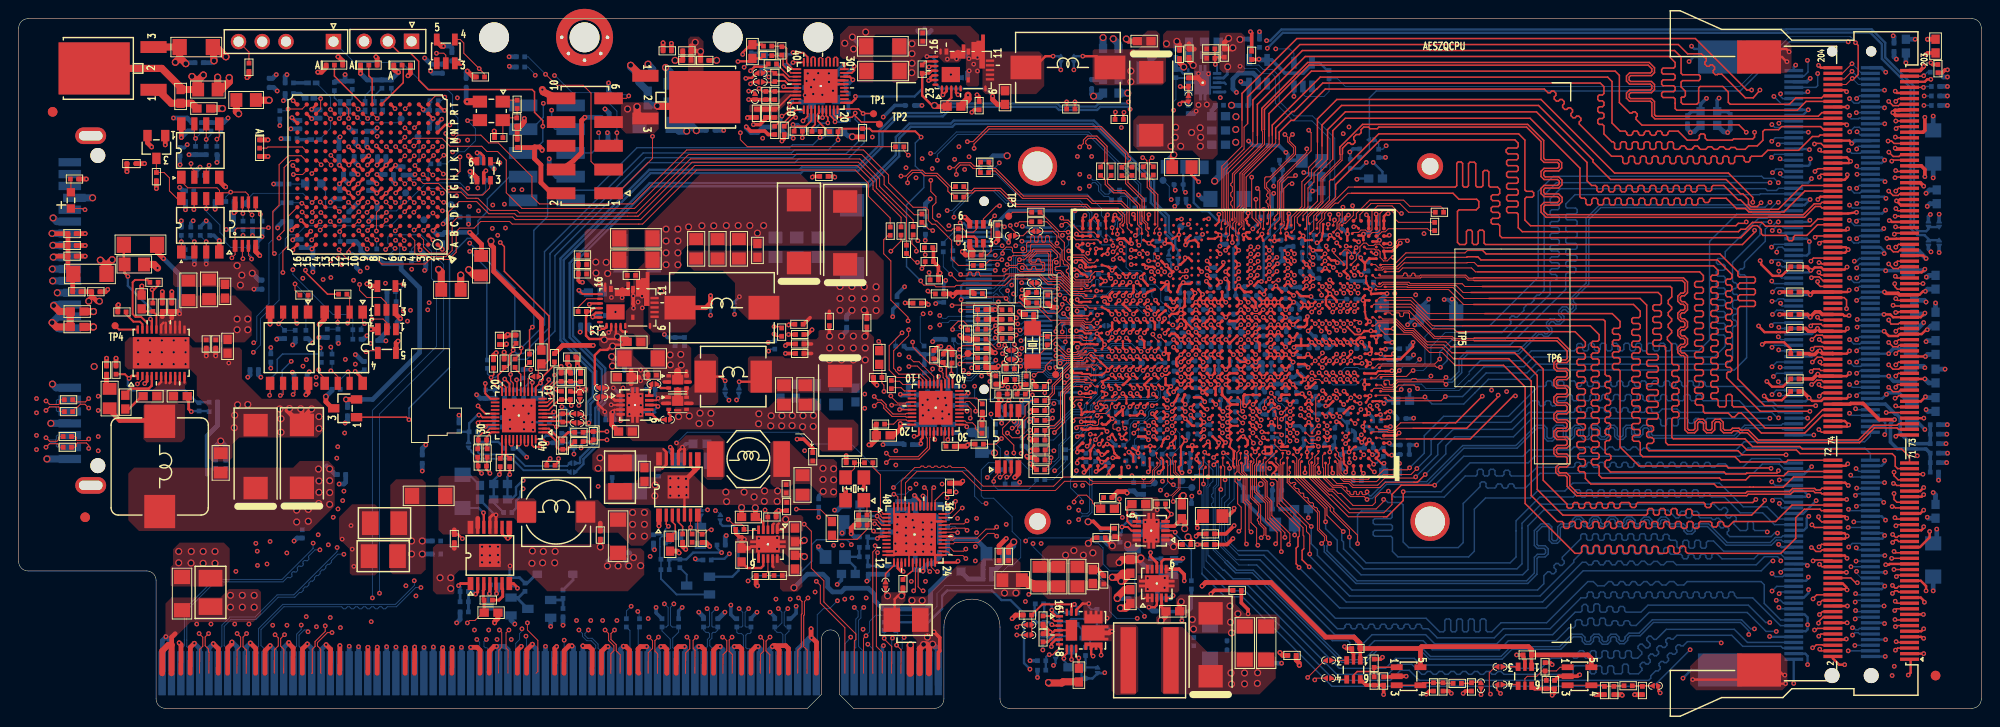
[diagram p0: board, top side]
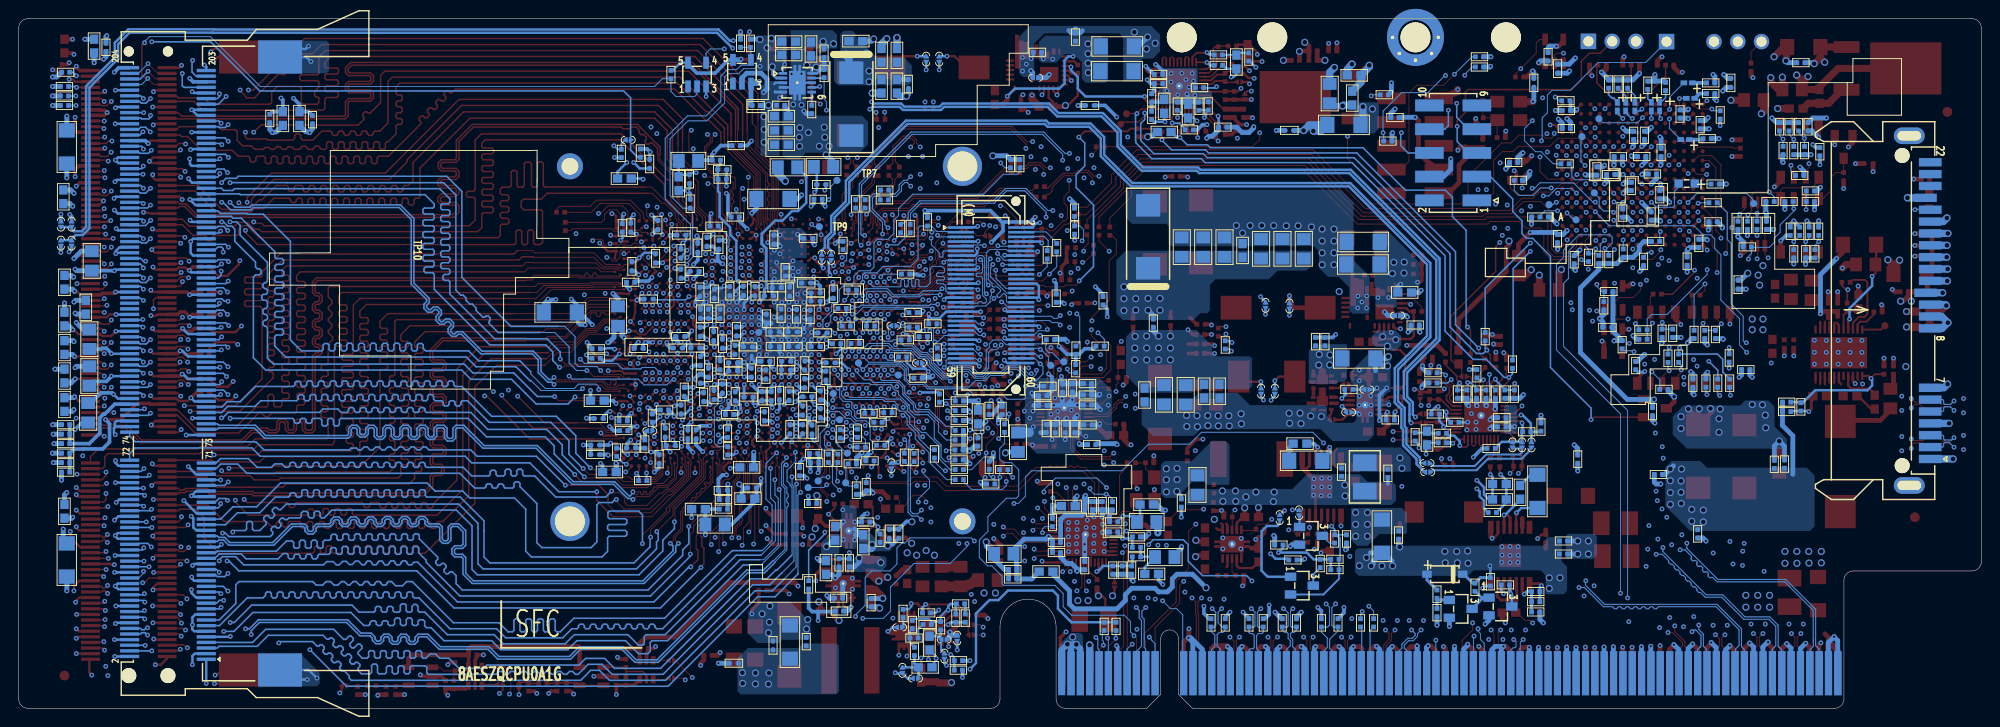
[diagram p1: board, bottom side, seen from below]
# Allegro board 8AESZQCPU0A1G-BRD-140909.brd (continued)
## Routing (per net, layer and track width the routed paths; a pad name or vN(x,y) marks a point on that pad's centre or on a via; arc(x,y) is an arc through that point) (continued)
DDR3_CPU_CH0_DQ7: length 86.9
  TOP w0.102: U14.AM9 142.2,41.51 v1(142.55,41.16)
  TOP w0.157: P1.18 193,10.35 v1(192.68,10.03)
  L3_SIG w0.102: v1(142.55,41.16) 142.86,41.16 143.16,40.86 144.02,40.86 144.11,40.78 145.59,40.78 146.31,40.06 147.5,40.06 148.85,38.7 152.84,38.7 153.14,38.4
  L3_SIG w0.135: v1(192.68,10.03) 192.38,10.34 190.08,10.34 189.7,9.96 187.25,9.96 186.32,10.88 164.34,10.88 164.14,11.09 164.14,11.28 164.52,11.66 164.52,11.85 164.33,12.04 164.14,12.04 163.76,11.66 163.57,11.66 163.38,11.85 163.38,12.04 163.76,12.43 163.76,12.62 163.57,12.81 163.38,12.81 162.97,12.4 162.83,12.4 162.59,12.63 162.59,12.78 163,13.19 163,13.38 162.81,13.57 162.62,13.57 162.23,13.18 162.04,13.18 161.76,13.46 161.76,16.63 161.63,16.77 161.3,16.77 161.16,16.9 161.16,17.17 161.3,17.31 161.63,17.31 161.76,17.44 161.76,17.71 161.63,17.84 161.35,17.84 161.21,17.98 161.21,18.25 161.35,18.38 161.63,18.38 161.76,18.52 161.76,18.79 161.63,18.92 161.35,18.92 161.21,19.06 161.21,19.33 161.35,19.46 161.63,19.46 161.76,19.59 161.76,19.86 161.63,20 161.35,20 161.21,20.13 161.21,20.4 161.35,20.54 161.63,20.54 161.76,20.67 161.76,20.94 161.63,21.08 161.35,21.08 161.21,21.21 161.21,21.48 161.35,21.61 161.63,21.61 161.76,21.75 161.76,22.02 161.63,22.15 161.35,22.15 161.21,22.29 161.21,22.56 161.35,22.69 161.63,22.69 161.76,22.83 161.76,23.09 161.63,23.23 161.35,23.23 161.21,23.36 161.21,23.63 161.35,23.77 161.63,23.77 161.76,23.9 161.76,24.17 161.63,24.31 161.35,24.31 161.21,24.44 161.21,24.71 161.35,24.84 161.63,24.84 161.76,24.98 161.76,25.25 161.63,25.38 161.35,25.38 161.21,25.52 161.21,25.79 161.35,25.92 161.63,25.92 161.76,26.06 161.76,26.33 161.63,26.46 161.35,26.46 161.21,26.59 161.21,28.52 158.37,31.37 157.33,31.37 154.53,34.16 154.53,37.01 153.14,38.4
DDR3_CPU_CH0_DQ8: length 85.7
  TOP w0.102: v1(139.17,42.37) 139.16,42.38 139.16,42.52 139.43,42.79 U14.AR14
  TOP w0.157: v1(200.74,10.46) 200.92,10.65 P1.19
  L3_SIG w0.102: v1(139.17,42.37) 139.56,41.98 143.04,41.98 143.31,42.25 147.45,42.25 148.3,43.1 150.45,43.1
  L3_SIG w0.135: 150.45,43.1 151.78,41.78 155.15,41.78 164.45,32.47 164.45,19.52 170.42,13.55 185.03,13.55 185.13,13.66 188.4,13.66 189.87,12.19 192.86,12.19 193.52,11.53 195.72,11.53 196.12,11.14 196.12,11.09 196.29,10.92 197.05,10.92 197.51,10.46 v1(200.74,10.46)
DDR3_CPU_CH0_DQ9: length 85.7
  TOP w0.102: v1(140.64,43.14) 140.61,43.14 U14.AT13
  TOP w0.157: v1(200.79,11.46) 200.99,11.25 P1.21
  L3_SIG w0.135: v1(200.79,11.46) 197.38,11.46 197.02,11.82 195.93,11.82 195.58,12.17 193.78,12.17 192.72,13.22 189.27,13.22 188.57,13.92 187.05,13.92 186.84,14.12 170.65,14.12 165.02,19.75 165.02,32.77 163.83,33.96 163.83,34.22 163.57,34.47 163.32,34.47 162.79,35 162.79,35.53 162.55,35.77 162.02,35.77 154.94,42.85 152.45,42.85 151.05,44.25 v1(149.48,44.25)
  L10_SIG w0.102: v1(149.48,44.25) 148.18,44.25 147.22,43.28 145.01,43.28 143.75,42.02 141.1,42.02 141,42.12 141,42.79 v1(140.64,43.14)
DDR3_CPU_CH0_DQ10: length 85.8
  TOP w0.102: v1(141.41,43.14) 141.44,43.14 U14.AT10
  TOP w0.157: v1(200.91,14.1) 201.07,14.25 P1.31
  L3_SIG w0.102: v1(141.41,43.14) 142.08,43.81 143.16,43.81 143.72,43.26 144.2,43.26 146.91,45.97 150.85,45.97
  L3_SIG w0.135: 150.85,45.97 150.91,46.04 154.82,46.04 155.02,45.84 157.48,45.84 168.2,35.12 168.2,23.06 169.69,21.57 170.56,21.57 171.06,21.07 171.06,20.2 171.58,19.69 171.77,19.69 172.03,19.95 172.22,19.95 172.41,19.76 172.41,19.57 172.15,19.3 172.15,19.11 174.54,16.72 186.04,16.72 186.13,16.81 189.76,16.81 190.09,16.49 192.62,16.49 192.72,16.38 193.12,16.38 194.26,15.24 194.26,14.48 194.9,13.84 195.86,13.84 195.9,13.88 196.92,13.88 197.06,13.74 200.3,13.74 200.66,14.1 v1(200.91,14.1)
DDR3_CPU_CH0_DQ11: length 85.7
  TOP w0.102: U14.AR11 140.67,42.44 140.63,42.44 v1(140.6,42.41)
  TOP w0.157: P1.33 v1(200.65,14.85)
  L3_SIG w0.102: 146.76,46.41 144.5,44.15 143.74,44.15 143.61,44.02 141.69,44.02 141.53,43.87 140.58,43.87 140.22,43.51 140.22,42.87 140.57,42.52 140.57,42.44 v1(140.6,42.41)
  L3_SIG w0.135: v1(200.65,14.85) 200.53,14.73 200.53,14.48 200.13,14.07 197.1,14.07 197,14.17 195.82,14.17 195.75,14.1 195.22,14.1 194.77,14.55 194.77,15.34 193.37,16.74 192.74,16.74 192.72,16.75 190.54,16.75 190.2,17.09 187.99,17.09 187.79,17.29 176.22,17.29 168.77,24.74 168.77,35.35 157.71,46.41 146.76,46.41
DDR3_CPU_CH0_DQ12: length 85.7
  TOP w0.102: v1(138.36,42.41) U14.AR16
  TOP w0.157: P1.22 192.97,11.55 192.65,11.23 v1(192.64,11.23)
  L3_SIG w0.102: 148.44,41.83 143.5,41.83 143.24,41.57 141.05,41.57 141.04,41.56 140.15,41.56 140.15,41.57 138.95,41.57 138.36,42.16 v1(138.36,42.41)
  L3_SIG w0.135: v1(192.64,11.23) 192.42,11.01 190.31,11.01 188.29,13.02 186.33,13.02 185.72,12.42 168.3,12.42 163.32,17.4 163.32,32 160.07,35.26 159.88,35.26 159.35,34.73 159.11,34.73 158.97,34.87 158.97,35.11 159.5,35.64 159.5,35.83 159.31,36.02 159.12,36.02 158.61,35.51 158.42,35.51 158.23,35.7 158.23,35.89 158.74,36.4 158.74,36.59 158.55,36.78 158.35,36.78 157.85,36.27 157.66,36.27 157.47,36.46 157.47,36.65 157.97,37.16 157.97,37.35 157.78,37.54 157.59,37.54 157.08,37.03 156.89,37.03 156.7,37.23 156.7,37.42 157.21,37.92 157.21,38.11 154.72,40.6 150.75,40.6 149.52,41.83 148.44,41.83
DDR3_CPU_CH0_DQ13: length 85.7
  TOP w0.102: U14.AT14 139.15,43.14 v1(139.12,43.14)
  TOP w0.157: v1(192,11.71) 192,11.76 192.39,12.15 P1.24
  L3_SIG w0.102: 148.31,42.44 147.91,42.04 143.42,42.04 143.18,41.8 143.15,41.8 143.12,41.77 139.03,41.77 138.76,42.04 138.76,42.67 138.76,42.67 138.76,42.79 v1(139.12,43.14)
  L3_SIG w0.135: 148.31,42.44 149.96,42.44 151.21,41.19 154.93,41.19 163.89,32.24 163.89,17.63 164.24,17.28 164.43,17.28 164.78,17.63 164.97,17.63 165.16,17.44 165.16,17.25 164.81,16.9 164.81,16.71 165,16.52 165.19,16.52 165.54,16.87 165.73,16.87 165.92,16.68 165.92,16.49 165.57,16.14 165.57,15.95 165.76,15.76 165.95,15.76 166.3,16.11 166.49,16.11 166.68,15.92 166.68,15.73 166.33,15.38 166.33,15.19 166.52,15 166.71,15 167.06,15.35 167.25,15.35 167.44,15.16 167.44,14.97 167.1,14.62 167.1,14.43 167.56,13.96 167.75,13.96 168.15,14.36 168.34,14.36 168.53,14.17 168.53,13.98 168.13,13.58 168.13,13.39 168.54,12.99 185.25,12.99 185.55,13.28 188.4,13.28 190.23,11.46 191.75,11.46 v1(192,11.71)
DDR3_CPU_CH0_DQ14: length 85.7
  TOP w0.102: v1(142.17,43.14) 142.2,43.14 U14.AT8
  TOP w0.157: P1.34 192.95,15.15 v1(192.68,15.42)
  L3_SIG w0.102: v1(142.17,43.14) 142.17,43.26 142.46,43.56 143.12,43.56 143.62,43.06 144.45,43.06 147.04,45.64 151.69,45.64
  L3_SIG w0.135: v1(192.68,15.42) 192.68,16.05 192.51,16.23 189.51,16.23 189.2,16.54 186.72,16.54 186.34,16.16 173.69,16.16 173.56,16.29 173.56,16.6 173.42,16.74 173.15,16.74 173.02,16.6 173.02,16.29 172.88,16.16 172.49,16.16 172.24,16.41 172.24,17.11 172.68,17.55 172.68,17.74 172.49,17.93 172.3,17.93 171.86,17.49 171.67,17.49 171.48,17.68 171.48,17.87 171.92,18.31 171.92,18.5 171.73,18.69 171.54,18.69 171.09,18.25 170.9,18.25 170.71,18.44 170.71,18.63 171.16,19.07 171.16,19.26 170.97,19.46 170.78,19.46 170.33,19.01 170.14,19.01 169.95,19.2 169.95,19.39 170.4,19.84 170.4,20.03 170.21,20.22 170.02,20.22 169.57,19.77 169.38,19.77 169.19,19.96 169.19,20.15 169.63,20.6 169.63,20.79 169.44,20.98 169.25,20.98 168.81,20.53 168.62,20.53 168.43,20.72 168.43,20.91 168.87,21.36 168.87,21.55 168.68,21.74 168.49,21.74 168.05,21.29 167.86,21.29 167.05,22.1 167.05,23.12 167.19,23.26 167.3,23.26 167.44,23.39 167.44,23.66 167.3,23.8 167.19,23.8 167.05,23.93 167.05,34.98 167.05,35.45 157.33,45.17 154.55,45.17 153.95,45.77 151.84,45.77 151.71,45.64 151.69,45.64
DDR3_CPU_CH0_DQ15: length 85.8
  TOP w0.102: v1(141.41,42.44) 141.44,42.44 U14.AR10
  TOP w0.157: v1(192,15.77) 192.1,15.88 193.99,15.88 P1.36
  L3_SIG w0.135: v1(147.24,44.4) 148.15,45.3 153.64,45.3 154.34,44.6 157.1,44.6 166.49,35.21 166.49,21.58 166.67,21.4 166.67,21.05 166.58,20.95 166.58,20.43 166.72,20.29 167.08,20.29 167.46,20.67 167.65,20.67 167.84,20.48 167.84,20.29 167.24,19.69 167.24,19.5 167.43,19.31 167.62,19.31 168.22,19.91 168.41,19.91 168.6,19.71 168.6,19.52 168.01,18.93 168.01,18.74 168.2,18.55 168.39,18.55 168.98,19.14 169.17,19.14 169.36,18.95 169.36,18.76 169.07,18.47 168.77,18.17 168.77,17.98 168.96,17.79 169.15,17.79 169.73,18.37 169.92,18.37 170.11,18.18 170.11,17.99 169.53,17.41 169.53,17.22 169.72,17.03 169.91,17.03 170.48,17.59 170.67,17.59 170.86,17.4 170.86,17.21 170.29,16.64 170.29,16.45 171.15,15.59 186.58,15.59 187.25,16.26 189,16.26 189.4,15.86 191.91,15.86 v1(192,15.77)
  L10_SIG w0.102: v1(141.41,42.44) 141.41,42.54 141.79,42.92 141.79,43.3 142.01,43.52 142.02,43.52 142.07,43.58 143.16,43.58 143.49,43.25 144.07,43.25 144.64,43.81 146.66,43.81 v1(147.24,44.4)
DDR3_CPU_CH0_DQ16: length 86.3
  TOP w0.102: U14.AY9 142.52,45.13 v1(142.55,45.13)
  TOP w0.157: P1.37 v1(200.41,16.05)
  L3_SIG w0.102: 153.09,48.23 148.97,48.23 148.26,47.52 145.91,47.52 144.11,45.72 142.85,45.72 142.55,45.42 v1(142.55,45.13)
  L3_SIG w0.135: v1(200.41,16.05) 200.26,15.9 199.3,15.9 199.17,15.77 199.17,15.53 199.03,15.4 198.76,15.4 198.63,15.53 198.63,15.77 198.49,15.9 198.22,15.9 198.09,15.77 198.09,15.53 197.95,15.39 197.68,15.39 197.55,15.53 197.55,15.77 197.42,15.9 197.15,15.9 196.75,16.31 196.11,16.31 195.91,16.51 194.18,16.51 192.7,17.99 190.77,17.99 189.34,19.42 178.6,19.42 172.27,25.75 172.27,27.18 172.4,27.31 172.6,27.31 172.74,27.45 172.74,27.71 172.6,27.85 172.4,27.85 172.27,27.98 172.27,28.25 172.4,28.39 172.6,28.39 172.74,28.52 172.74,28.79 172.6,28.93 172.4,28.93 172.27,29.06 172.27,29.33 172.4,29.47 172.6,29.47 172.74,29.6 172.74,29.87 172.6,30 172.4,30 172.27,30.14 172.27,30.41 172.4,30.54 172.6,30.54 172.74,30.68 172.74,30.95 172.6,31.08 172.4,31.08 172.27,31.22 172.27,31.48 172.4,31.62 172.6,31.62 172.74,31.75 172.74,32.02 172.6,32.16 172.4,32.16 172.27,32.29 172.27,32.56 172.4,32.7 172.6,32.7 172.74,32.83 172.74,33.1 172.6,33.23 172.4,33.23 172.27,33.37 172.27,33.64 172.4,33.77 172.58,33.77 172.72,33.91 172.72,34.18 172.58,34.31 172.4,34.31 172.27,34.45 172.27,34.95 158.98,48.23 153.09,48.23
DDR3_CPU_CH0_DQ17: length 86.3
  TOP w0.102: v1(141.79,45.13) 141.76,45.13 U14.AY11
  TOP w0.157: v1(200.66,16.79) 200.8,16.65 P1.39
  L3_SIG w0.102: 152.07,48.81 148.96,48.81 147.98,47.83 145.85,47.83 143.97,45.95 142.71,45.95 141.89,45.13 v1(141.79,45.13)
  L3_SIG w0.135: 152.07,48.81 159.21,48.81 173.34,34.68 173.34,33.92 173.6,33.66 173.6,33.34 173.34,33.08 173.34,32.83 173.47,32.69 173.49,32.69 173.62,32.56 173.62,32.29 173.49,32.16 173.47,32.16 173.34,32.02 173.34,31.75 173.47,31.62 173.49,31.62 173.62,31.48 173.62,31.21 173.49,31.08 173.47,31.08 173.34,30.94 173.34,30.68 173.47,30.54 173.49,30.54 173.62,30.41 173.62,30.14 173.49,30 173.47,30 173.34,29.87 173.34,29.6 173.47,29.46 173.49,29.46 173.62,29.33 173.62,29.06 173.49,28.93 173.47,28.93 173.34,28.79 173.34,28.52 173.47,28.39 173.49,28.39 173.62,28.25 173.62,27.98 173.49,27.85 173.47,27.85 173.34,27.71 173.34,27.44 173.47,27.31 173.49,27.31 173.62,27.17 173.62,26.91 173.49,26.77 173.47,26.77 173.34,26.64 173.34,25.67 173.65,25.36 173.96,25.36 174.15,25.17 174.15,24.98 174.09,24.92 174.09,24.73 174.28,24.54 174.47,24.54 174.53,24.6 174.72,24.6 174.91,24.41 174.91,24.21 174.85,24.16 174.85,23.97 175.04,23.78 175.23,23.78 175.29,23.83 175.48,23.83 175.67,23.64 175.67,23.45 175.61,23.4 175.61,23.21 175.8,23.02 175.99,23.02 176.05,23.07 176.24,23.07 176.43,22.88 176.43,22.69 176.38,22.63 176.38,22.44 176.57,22.25 176.76,22.25 176.8,22.3 177,22.3 177.19,22.11 177.19,21.92 177.14,21.87 177.14,21.68 177.33,21.49 177.54,21.49 177.9,21.13 177.9,20.92 178.83,19.99 184.77,19.99 185.02,19.74 189.43,19.74 190.7,18.47 192.81,18.47 194.46,16.81 196.32,16.81 196.47,16.66 196.82,16.66 196.96,16.8 197.22,16.8 197.36,16.93 197.36,17.09 197.49,17.22 197.76,17.22 197.9,17.09 197.9,16.8 198.03,16.66 198.29,16.66 198.42,16.8 198.42,16.92 198.43,16.93 198.43,17.09 198.57,17.22 198.84,17.22 198.97,17.09 198.97,16.93 199.11,16.8 200.65,16.8 v1(200.66,16.79)
DDR3_CPU_CH0_DQ18: length 86.3
  TOP w0.102: U14.AY15 139.47,45.13 v1(139.5,45.13)
  TOP w0.157: P1.49 200.98,19.65 v1(200.86,19.53)
  L3_SIG w0.102: v1(139.5,45.13) 139.43,45.2 139.43,46.93 139.42,46.94 139.42,47.26 139.64,47.48 139.91,47.48 139.92,47.49 139.94,47.49 141.33,48.89 143.59,48.89 145.91,51.21 147.62,51.21
  L3_SIG w0.135: 147.62,51.21 151.8,51.21 152.02,50.98 159.81,50.98 177.04,33.75 177.04,32.19 177.31,31.92 177.31,31.65 177.17,31.52 177.11,31.52 176.98,31.38 176.98,31.12 177.11,30.98 177.15,30.98 177.29,30.85 177.29,30.58 177.15,30.44 177.11,30.44 176.98,30.31 176.98,30.04 177.11,29.9 177.23,29.9 177.35,29.79 177.35,29.48 177.23,29.37 177.11,29.37 176.98,29.23 176.98,26.41 181.39,21.99 184.61,21.99 185.67,20.94 189.93,20.94 190.77,20.1 192.22,20.1 192.88,19.44 195.03,19.44 195.57,18.9 195.94,18.9 196.57,19.53 v1(200.86,19.53)
DDR3_CPU_CH0_DQ19: length 86.2
  TOP w0.157: v1(138.49,45.2) 138.49,45.17 U14.AW17 ; P1.51 200.91,20.25 v1(200.76,20.4)
  L3_SIG w0.102: v1(138.49,45.2) 138.89,45.6 138.89,48.97 139.35,49.42 139.35,50.2 140.35,51.2 141.75,51.2 142.72,52.17 145.11,52.17
  L3_SIG w0.135: v1(200.76,20.4) 200.57,20.59 195.99,20.59 195.79,20.79 195.36,20.79 194.68,21.47 186.1,21.47 185.1,22.47 185.1,27.78 160.45,52.43 148.47,52.43 148.21,52.17 145.11,52.17
DDR3_CPU_CH0_DQ20: length 86.2
  TOP w0.102: v1(143.31,44.43) 143.28,44.43 U14.AW8
  TOP w0.157: v1(191.82,17.2) 191.89,17.2 192.31,16.79 192.8,16.79 192.96,16.95 P1.40
  L3_SIG w0.102: 153.57,47.06 150.21,47.06 150.09,46.94 146.09,46.94 143.58,44.43 v1(143.31,44.43)
  L3_SIG w0.135: 153.57,47.06 158.56,47.06 169.75,35.87 169.75,34.74 169.88,34.61 170.26,34.61 170.4,34.47 170.4,34.2 170.26,34.07 169.88,34.07 169.75,33.93 169.75,33.66 169.88,33.53 170.26,33.53 170.4,33.39 170.4,33.13 170.26,32.99 169.88,32.99 169.75,32.86 169.75,32.59 169.88,32.45 170.26,32.45 170.4,32.32 170.4,32.05 170.26,31.91 169.88,31.91 169.75,31.78 169.75,31.51 169.88,31.38 170.26,31.38 170.4,31.24 170.4,30.97 170.26,30.84 169.88,30.84 169.75,30.7 169.75,30.43 169.88,30.3 170.26,30.3 170.4,30.16 170.4,29.89 170.26,29.76 169.88,29.76 169.75,29.63 169.75,29.36 169.88,29.22 170.26,29.22 170.4,29.09 170.4,28.82 170.26,28.68 169.88,28.68 169.75,28.55 169.75,28.28 169.88,28.14 170.26,28.14 170.4,28.01 170.4,27.74 170.26,27.61 169.88,27.61 169.75,27.47 169.75,27.2 169.88,27.07 170.24,27.07 170.38,26.93 170.38,26.66 170.24,26.53 169.88,26.53 169.75,26.39 169.75,26.12 169.88,25.99 170.34,25.99 170.47,25.86 170.47,25.59 170.34,25.45 169.88,25.45 169.75,25.32 169.75,24.71 170.14,24.32 170.33,24.32 170.55,24.54 170.74,24.54 170.93,24.35 170.93,24.16 170.71,23.94 170.71,23.75 170.9,23.56 171.09,23.56 171.31,23.78 171.5,23.78 171.69,23.59 171.69,23.4 171.47,23.18 171.47,22.99 171.66,22.8 171.85,22.8 172.07,23.01 172.26,23.01 172.45,22.82 172.45,22.63 172.24,22.42 172.24,22.23 172.43,22.04 172.62,22.04 172.83,22.25 173.02,22.25 173.21,22.06 173.21,21.87 173,21.66 173,21.47 173.19,21.27 173.38,21.27 173.59,21.49 173.78,21.49 173.98,21.3 173.98,21.11 173.76,20.89 173.76,20.7 173.95,20.51 174.14,20.51 174.36,20.74 174.55,20.74 174.74,20.55 174.74,20.35 174.52,20.13 174.52,19.94 174.71,19.75 174.9,19.75 175.07,19.92 175.26,19.92 175.45,19.73 175.45,19.53 175.28,19.37 175.28,19.18 176.17,18.29 186,18.29 186.25,18.04 189.83,18.04 190.67,17.2 v1(191.82,17.2)
DDR3_CPU_CH0_DQ21: length 86.3
  TOP w0.102: v1(143.31,45.13) 143.28,45.13 U14.AY8
  TOP w0.157: P1.42 192.91,17.55 v1(192.63,17.27)
  L3_SIG w0.102: 153.36,47.63 149.54,47.63 149.12,47.22 145.98,47.22 143.89,45.13 v1(143.31,45.13)
  L3_SIG w0.135: v1(192.63,17.27) 192.63,17.3 192.2,17.73 190.55,17.73 189.98,18.3 186.52,18.3 185.97,18.85 177.13,18.85 176.77,19.22 176.77,19.41 176.89,19.53 176.89,19.72 176.7,19.91 176.51,19.91 176.39,19.79 176.2,19.79 175.8,20.19 175.8,20.53 176.13,20.86 176.13,21.05 175.94,21.24 175.75,21.24 175.42,20.91 175.23,20.91 175.04,21.1 175.04,21.29 175.37,21.62 175.37,21.81 175.18,22 174.99,22 174.66,21.67 174.47,21.67 174.28,21.86 174.28,22.05 174.61,22.38 174.61,22.57 174.42,22.76 174.23,22.76 173.9,22.43 173.7,22.43 173.51,22.62 173.51,22.82 173.84,23.15 173.84,23.34 173.65,23.53 173.46,23.53 173.13,23.2 172.94,23.2 172.75,23.39 172.75,23.58 173.08,23.91 173.08,24.1 172.89,24.29 172.7,24.29 172.37,23.96 172.18,23.96 171.99,24.15 171.99,24.34 172.32,24.67 172.32,24.86 172.13,25.05 171.94,25.05 171.61,24.72 171.42,24.72 171.04,25.1 171.04,26.39 171.18,26.52 171.54,26.52 171.68,26.66 171.68,26.93 171.54,27.06 171.18,27.06 171.04,27.2 171.04,27.47 171.18,27.6 171.54,27.6 171.68,27.74 171.68,28 171.54,28.14 171.18,28.14 171.04,28.27 171.04,28.54 171.18,28.68 171.54,28.68 171.68,28.81 171.68,29.08 171.54,29.22 171.18,29.22 171.04,29.35 171.04,29.62 171.18,29.75 171.54,29.75 171.68,29.89 171.68,30.16 171.54,30.29 171.18,30.29 171.04,30.43 171.04,30.7 171.18,30.83 171.54,30.83 171.68,30.97 171.68,31.24 171.54,31.37 171.18,31.37 171.04,31.5 171.04,31.77 171.18,31.91 171.54,31.91 171.68,32.04 171.68,32.31 171.54,32.45 171.18,32.45 171.04,32.58 171.04,32.85 171.18,32.99 171.54,32.99 171.68,33.12 171.68,33.39 171.54,33.52 171.18,33.52 171.04,33.66 171.04,33.93 171.18,34.06 171.53,34.06 171.67,34.2 171.67,34.47 171.53,34.6 171.18,34.6 171.04,34.74 171.04,35.37 158.78,47.63 153.36,47.63
DDR3_CPU_CH0_DQ22: length 86.3
  TOP w0.157: v1(191.87,19.63) 192.16,19.35 P1.48 ; v1(140.26,45.13) 140.23,45.13 U14.AY14
  L3_SIG w0.102: 148.03,50.57 147.76,50.57 147.43,50.24 146.53,50.24 145.82,49.53 144.84,49.53 143.98,48.67 141.5,48.67 140.23,47.4 140.23,46.77 139.66,46.2 139.66,45.73 v1(140.26,45.13)
  L3_SIG w0.135: 148.03,50.57 149.53,50.57 149.77,50.32 159.66,50.32 175.79,34.19 175.79,33.12 175.93,32.99 176.28,32.99 176.41,32.85 176.41,32.58 176.28,32.45 175.93,32.45 175.79,32.31 175.79,32.04 175.93,31.91 176.28,31.91 176.41,31.78 176.41,31.51 176.28,31.37 175.93,31.37 175.79,31.24 175.79,30.97 175.93,30.83 176.28,30.83 176.41,30.7 176.41,30.43 176.28,30.29 175.93,30.29 175.79,30.16 175.79,29.89 175.93,29.76 176.28,29.76 176.41,29.62 176.41,29.35 176.28,29.22 175.93,29.22 175.79,29.08 175.79,28.81 175.93,28.68 176.28,28.68 176.41,28.54 176.41,28.28 176.28,28.14 175.93,28.14 175.79,28.01 175.79,26.46 176.19,26.06 176.45,26.06 176.86,25.65 176.86,25.46 176.5,25.09 176.5,24.9 176.69,24.71 176.88,24.71 177.24,25.08 177.43,25.08 177.63,24.89 177.63,24.7 177.26,24.33 177.26,24.14 177.45,23.95 177.64,23.95 178.01,24.32 178.2,24.32 178.39,24.13 178.39,23.94 178.02,23.57 178.02,23.38 178.21,23.19 178.4,23.19 178.77,23.56 178.96,23.56 179.15,23.36 179.15,23.17 178.78,22.81 178.78,22.62 179.05,22.34 179.25,22.34 179.56,22.66 179.75,22.66 179.94,22.47 179.94,22.28 179.73,22.07 179.73,21.67 179.97,21.43 184.77,21.43 185.52,20.68 189.81,20.68 190.86,19.63 v1(191.87,19.63)
DDR3_CPU_CH0_DQ23: length 86.3
  TOP w0.102: v1(139.41,44.21) 139.41,44.49 U14.AW15
  TOP w0.157: P1.50 192.93,19.95 192.58,20.29 v1(192.58,20.5)
  L3_SIG w0.102: 144.98,51 144.32,50.34 143.03,50.34 142.87,50.18 142.09,50.18 141.31,49.4 140.56,49.4 140.55,49.39 140.37,49.39 140.06,49.09 139.67,49.09 139.18,48.61 139.18,45.61 138.94,45.37 138.94,44.95 139.41,44.49 v1(139.41,44.21)
  L3_SIG w0.135: v1(192.58,20.5) 191.88,21.2 185.93,21.2 184.57,22.56 183.35,22.56 183.21,22.69 183.21,22.96 183.08,23.1 182.81,23.1 182.67,22.96 182.67,22.69 182.54,22.56 181.73,22.56 180.91,23.38 180.91,23.57 181.06,23.72 181.06,23.95 180.92,24.1 180.68,24.1 180.48,23.9 180.29,23.9 180.1,24.09 180.1,24.28 180.3,24.48 180.3,24.67 180.11,24.86 179.92,24.86 179.72,24.66 179.53,24.66 179.34,24.85 179.34,25.04 179.54,25.24 179.54,25.43 179.35,25.62 179.16,25.62 178.96,25.42 178.77,25.42 177.91,26.27 177.91,26.86 178.05,27 178.43,27 178.56,27.13 178.56,27.4 178.43,27.54 178.05,27.54 177.91,27.67 177.91,28.57 178.05,28.71 178.37,28.71 178.51,28.84 178.51,29.11 178.37,29.25 178.05,29.25 177.91,29.38 177.91,29.65 178.05,29.79 178.37,29.79 178.51,29.92 178.51,30.19 178.37,30.32 178.05,30.32 177.91,30.46 177.91,30.73 178.05,30.86 178.37,30.86 178.51,31 178.51,31.27 178.37,31.4 178.17,31.4 178.03,31.54 178.03,31.8 178.17,31.94 178.37,31.94 178.51,32.07 178.51,33.08 159.88,51.71 145.69,51.71 144.98,51
DDR3_CPU_CH0_DQ24: length 80.7
  TOP w0.102: U14.AN4 144.99,41.84 145.38,41.45 147.31,41.45 148.32,40.44 149.19,40.44 150.73,38.89 152.5,38.89 153.34,38.05
  TOP w0.157: P1.55 200.8,21.45 200.66,21.59 v1(200.46,21.59) ; 153.34,38.05 160.07,38.05 162.48,35.64 162.48,23.42 165.23,20.68 174.13,20.68 174.29,20.83 174.29,21.22 174.45,21.38 174.76,21.38 174.92,21.22 174.92,20.83 175.08,20.68 175.39,20.68 175.55,20.83 175.55,21.22 175.71,21.38 176.02,21.38 176.18,21.22 176.18,20.83 176.34,20.68 176.65,20.68 176.81,20.83 176.81,21.22 176.97,21.38 177.28,21.38 177.44,21.22 177.44,20.83 177.6,20.68 178.25,20.68 178.41,20.83 178.41,21.15 178.57,21.31 178.88,21.31 179.04,21.15 179.04,20.83 179.2,20.68 185.42,20.68 186.82,22.07 v1(186.82,22.28)
  L3_SIG w0.135: v1(186.82,22.28) 186.82,22.38 187.32,22.89 189.59,22.89 191.2,24.5 196.98,24.5 198.5,22.99 199.52,22.99 200.46,22.05 v1(200.46,21.59)
DDR3_CPU_CH0_DQ25: length 80.7
  TOP w0.102: U14.AN2 145.76,41.87 145.97,41.65 147.39,41.65 148.41,40.64 149.27,40.64 150.7,39.22 152.71,39.22 153.23,38.69
  TOP w0.157: v1(185.88,22.35) 185.55,22.02 181.25,22.02 181.08,21.85 181.08,21.65 180.93,21.49 180.61,21.49 180.45,21.65 180.45,21.86 180.3,22.02 173.24,22.02 173.08,21.86 173.08,21.65 172.92,21.49 172.61,21.49 172.45,21.65 172.45,21.86 172.29,22.02 171.49,22.02 171.33,21.86 171.33,21.57 171.18,21.41 170.86,21.41 170.7,21.57 170.7,21.86 170.55,22.02 170.23,22.02 170.07,21.86 170.07,21.57 169.92,21.41 169.6,21.41 169.44,21.57 169.44,21.86 169.29,22.02 168.97,22.02 168.81,21.86 168.81,21.57 168.66,21.41 168.34,21.41 168.18,21.57 168.18,21.86 168.03,22.02 167.71,22.02 167.55,21.86 167.55,21.57 167.4,21.41 167.08,21.41 166.92,21.57 166.92,21.86 166.77,22.02 166.45,22.02 166.29,21.86 166.29,21.57 166.14,21.41 165.82,21.41 165.66,21.57 165.66,21.86 163.12,24.4 163.12,36.29 160.72,38.69 153.23,38.69 ; v1(200.66,22.99) 200.66,22.35 200.96,22.05 P1.57
  L3_SIG w0.135: v1(200.66,22.99) 200.15,23.5 198.88,23.5 197.17,25.21 196.41,25.21 196.27,25.34 196.27,25.34 196.21,25.4 192.84,25.4 192.45,25.01 191.13,25.01 189.43,23.32 186.84,23.32 v1(185.88,22.35)
DDR3_CPU_CH0_DQ26: length 80.8
  TOP w0.102: U14.AU1 148.92,43.66 150.98,41.6 153.08,41.6
  TOP w0.157: P1.63 200.94,23.85 200.72,24.07 v1(200.6,24.07) ; 153.08,41.6 169.58,41.6 169.75,41.43 169.75,35.73 169.91,35.58 170.17,35.58 170.33,35.42 170.33,35.1 170.17,34.95 169.91,34.95 169.75,34.79 169.75,34.47 169.91,34.32 170.17,34.32 170.33,34.16 170.33,33.84 170.17,33.69 169.91,33.69 169.75,33.53 169.75,33.21 169.91,33.06 170.17,33.06 170.33,32.9 170.33,32.58 170.17,32.43 169.91,32.43 169.75,32.27 169.75,31.95 169.91,31.8 170.17,31.8 170.33,31.64 170.33,31.32 170.17,31.17 169.91,31.17 169.75,31.01 169.75,30.69 169.91,30.54 170.17,30.54 170.33,30.38 170.33,30.06 170.17,29.91 169.91,29.91 169.75,29.75 169.75,29.43 169.91,29.28 170.17,29.28 170.33,29.12 170.33,28.8 170.17,28.65 169.91,28.65 169.75,28.49 169.75,27.34 169.91,27.19 170.2,27.19 170.36,27.03 170.36,26.71 170.2,26.56 169.91,26.56 169.75,26.4 169.75,25.86 170.32,25.29 182.47,25.29 182.67,25.08 184.8,25.08 184.89,25.18 188.13,25.18 188.29,25.33 v1(188.29,25.43)
  L3_SIG w0.135: v1(188.29,25.43) 188.49,25.43 188.77,25.7 190.47,25.7 191.57,26.8 197.87,26.8 198.29,26.37 198.29,25.87 198.45,25.7 198.96,25.7 v1(200.6,24.07)
DDR3_CPU_CH0_DQ27: length 80.7
  TOP w0.102: U14.AU3 145.61,43.95 149.06,43.95 150.77,42.24 156.87,42.24
  TOP w0.157: v1(200.66,25.27) 200.66,24.89 201.1,24.45 P1.65 ; 156.87,42.24 170.51,42.24 171.35,41.4 171.35,40.82 171.19,40.67 170.69,40.67 170.54,40.51 170.54,40.19 170.69,40.04 171.19,40.04 171.35,39.88 171.35,39.56 171.19,39.41 170.69,39.41 170.54,39.25 170.54,38.93 170.69,38.78 171.19,38.78 171.35,38.62 171.35,38.3 171.19,38.15 170.69,38.15 170.54,37.99 170.54,37.67 170.69,37.52 171.19,37.52 171.35,37.36 171.35,37.04 171.19,36.89 170.69,36.89 170.54,36.73 170.54,36.41 170.69,36.26 171.19,36.26 171.35,36.1 171.35,27.97 173.39,25.93 182.73,25.93 182.94,25.72 187.46,25.72 v1(187.5,25.68)
  L3_SIG w0.135: v1(200.66,25.27) 200.66,26.92 200.28,27.3 191.01,27.3 190.02,26.31 188.14,26.31 v1(187.5,25.68)
DDR3_CPU_CH0_DQ28: length 80.7
  TOP w0.102: U14.AL2 145.61,40.63 146.21,40.03 149.02,40.03 150.97,38.07 152.32,38.07 153.7,36.7
  TOP w0.157: 153.7,36.7 158.88,36.7 161.19,34.39 161.19,21.92 166.52,16.59 167.09,16.59 167.25,16.74 167.25,17.27 167.41,17.42 167.72,17.42 167.88,17.27 167.88,16.74 168.04,16.59 168.35,16.59 168.51,16.74 168.51,17.27 168.67,17.42 168.98,17.42 169.14,17.27 169.14,16.74 169.3,16.59 169.61,16.59 169.77,16.74 169.77,17.27 169.93,17.42 170.24,17.42 170.4,17.27 170.4,16.74 170.56,16.59 170.87,16.59 171.03,16.74 171.03,17.27 171.19,17.42 171.5,17.42 171.66,17.27 171.66,16.74 171.82,16.59 172.13,16.59 172.29,16.74 172.29,17.27 172.45,17.42 172.76,17.42 172.92,17.27 172.92,16.74 173.08,16.59 173.39,16.59 173.55,16.74 173.55,17.27 173.71,17.42 174.02,17.42 174.18,17.27 174.18,16.74 174.34,16.59 174.65,16.59 174.81,16.74 174.81,17.17 174.97,17.32 175.28,17.32 175.44,17.17 175.44,16.74 175.6,16.59 176.31,16.59 176.47,16.74 176.47,17.22 176.62,17.37 176.94,17.37 177.1,17.22 177.1,16.74 177.25,16.59 177.57,16.59 177.73,16.74 177.73,17.19 177.88,17.35 178.2,17.35 178.36,17.19 178.36,16.79 178.56,16.59 188.54,16.59 190.14,18.19 190.14,20.4 191.06,21.31 192.74,21.31 192.9,21.15 P1.54
DDR3_CPU_CH0_DQ29: length 80.7
  TOP w0.102: U14.AL4 145.1,40.95 145.4,41.25 147.22,41.25 148.24,40.23 149.1,40.23 150.75,38.58 152.35,38.58 153.52,37.41
  TOP w0.157: P1.56 189.75,21.75 187.99,19.99 183.49,19.99 182.96,19.46 182.63,19.46 182.42,19.66 182.42,19.83 182.26,19.99 181.95,19.99 181.79,19.83 181.79,19.56 181.63,19.41 181.32,19.41 181.16,19.56 181.16,19.83 181,19.99 179.94,19.99 179.79,19.83 179.79,19.41 179.63,19.25 179.31,19.25 179.16,19.41 179.16,19.83 179,19.99 178.68,19.99 178.53,19.83 178.53,19.41 178.37,19.25 178.05,19.25 177.9,19.41 177.9,19.83 177.74,19.99 177.42,19.99 177.27,19.83 177.27,19.41 177.11,19.25 176.79,19.25 176.64,19.41 176.64,19.83 176.48,19.99 176.17,19.99 176.01,19.83 176.01,19.41 175.85,19.25 175.54,19.25 175.38,19.41 175.38,19.83 175.22,19.99 174.91,19.99 174.75,19.83 174.75,19.41 174.59,19.25 174.28,19.25 174.12,19.41 174.12,19.83 173.96,19.99 173.65,19.99 173.49,19.83 173.49,19.41 173.33,19.25 173.02,19.25 172.86,19.41 172.86,19.83 172.7,19.99 172.39,19.99 172.23,19.83 172.23,19.41 172.07,19.25 171.76,19.25 171.6,19.41 171.6,19.83 171.44,19.99 171.13,19.99 170.97,19.83 170.97,19.41 170.81,19.25 170.5,19.25 170.34,19.41 170.34,19.83 170.18,19.99 169.87,19.99 169.71,19.83 169.71,19.41 169.55,19.25 169.24,19.25 169.08,19.41 169.08,19.83 168.92,19.99 168.61,19.99 168.45,19.83 168.45,19.41 168.29,19.25 167.98,19.25 167.82,19.41 167.82,19.83 167.66,19.99 167.35,19.99 167.19,19.83 167.19,19.41 167.03,19.25 166.72,19.25 166.56,19.41 166.56,19.83 166.4,19.99 166.09,19.99 165.93,19.83 165.93,19.41 165.77,19.25 165.46,19.25 165.3,19.41 165.3,19.83 165.14,19.99 164.62,19.99 161.84,22.76 161.84,35.01 159.44,37.41 153.52,37.41
DDR3_CPU_CH0_DQ30: length 80.8
  TOP w0.102: U14.AR2 148.93,42.94 151.26,40.61 153.56,40.61 153.87,40.3
  TOP w0.157: 153.87,40.3 166.53,40.3 167.63,39.2 167.63,38.78 167.48,38.62 166.88,38.62 166.73,38.46 166.73,38.15 166.88,37.99 167.48,37.99 167.63,37.83 167.63,37.52 167.48,37.36 166.88,37.36 166.73,37.2 166.73,36.89 166.88,36.73 167.48,36.73 167.63,36.57 167.63,36.26 167.48,36.1 166.88,36.1 166.73,35.94 166.73,35.63 166.88,35.47 167.48,35.47 167.63,35.31 167.63,35 167.48,34.84 166.88,34.84 166.73,34.68 166.73,34.37 166.88,34.21 167.48,34.21 167.63,34.05 167.63,33.74 167.48,33.58 166.88,33.58 166.73,33.42 166.73,33.11 166.88,32.95 167.48,32.95 167.63,32.79 167.63,32.48 167.48,32.32 166.88,32.32 166.73,32.16 166.73,31.85 166.88,31.69 167.48,31.69 167.63,31.53 167.63,31.22 167.48,31.06 166.88,31.06 166.73,30.9 166.73,30.59 166.88,30.43 167.48,30.43 167.63,30.27 167.63,29.96 167.48,29.8 166.88,29.8 166.73,29.64 166.73,29.33 166.88,29.17 167.48,29.17 167.63,29.01 167.63,28.7 167.48,28.54 166.88,28.54 166.73,28.38 166.73,28.07 166.88,27.91 167.48,27.91 167.63,27.75 167.63,27.44 167.48,27.28 167.01,27.28 166.85,27.12 166.85,26.81 167.01,26.65 167.48,26.65 167.63,26.49 167.63,26.09 167.48,25.93 167.04,25.93 166.88,25.78 166.88,25.46 167.04,25.3 167.48,25.3 167.63,25.15 167.63,24.59 168.22,24.01 181.4,24.01 181.74,23.67 185.23,23.67 185.23,23.67 185.61,23.67 185.61,23.67 188.82,23.67 189.9,24.75 P1.66
DDR3_CPU_CH0_DQ31: length 80.7
  TOP w0.102: 154.48,40.94 151.28,40.94 148.99,43.24 145.01,43.24 U14.AR4
  TOP w0.157: 154.48,40.94 168.15,40.94 169.11,39.98 169.11,39.44 168.95,39.28 168.43,39.28 168.28,39.12 168.28,38.81 168.43,38.65 168.95,38.65 169.11,38.49 169.11,38.18 168.95,38.02 168.43,38.02 168.28,37.86 168.28,37.55 168.43,37.39 168.95,37.39 169.11,37.23 169.11,36.92 168.95,36.76 168.43,36.76 168.28,36.6 168.28,36.29 168.43,36.13 168.95,36.13 169.11,35.97 169.11,35.66 168.95,35.5 168.43,35.5 168.28,35.34 168.28,35.03 168.43,34.87 168.95,34.87 169.11,34.71 169.11,34.4 168.95,34.24 168.43,34.24 168.28,34.08 168.28,33.77 168.43,33.61 168.95,33.61 169.11,33.45 169.11,33.14 168.95,32.98 168.43,32.98 168.28,32.82 168.28,32.51 168.43,32.35 168.95,32.35 169.11,32.19 169.11,31.88 168.95,31.72 168.43,31.72 168.28,31.56 168.28,31.25 168.43,31.09 168.95,31.09 169.11,30.93 169.11,30.62 168.95,30.46 168.43,30.46 168.28,30.3 168.28,29.99 168.43,29.83 168.95,29.83 169.11,29.67 169.11,29.36 168.95,29.2 168.43,29.2 168.28,29.04 168.28,28.73 168.43,28.57 168.95,28.57 169.11,28.41 169.11,28.1 168.95,27.94 168.43,27.94 168.28,27.78 168.28,27.47 168.43,27.31 168.95,27.31 169.11,27.15 169.11,26.84 168.95,26.68 168.43,26.68 168.28,26.52 168.28,26.21 168.43,26.05 168.95,26.05 169.11,25.89 169.11,24.94 169.4,24.65 181.98,24.65 182.19,24.44 184.8,24.44 185.24,24.89 188.87,24.89 189.33,25.35 P1.68
DDR3_CPU_CH0_DQ32: length 90.2
  TOP w0.157: v1(200.09,47.55) 200.58,47.06 201.12,47.06 201.31,47.25 P1.133 ; U14.BA32 v1(130.55,45.97)
  L3_SIG w0.102: v1(130.55,45.97) 130.55,45.87 131.73,44.69 133.76,44.69 133.84,44.6 134.94,44.6 135.4,45.07 135.4,48.8 136.87,50.27 136.87,50.97
  L3_SIG w0.135: v1(200.09,47.55) 199.29,47.55 197.21,45.47 194.28,45.47 193.68,44.87 191.25,44.87 189.23,42.85 184.94,42.85 183.72,44.07 171.16,44.07 165.2,50.03 165.2,50.22 165.32,50.34 165.32,50.53 165.13,50.72 164.94,50.72 164.82,50.6 164.63,50.6 164.44,50.79 164.44,50.98 164.65,51.19 164.65,51.38 164.46,51.57 164.26,51.57 164.06,51.36 163.86,51.36 163.67,51.55 163.67,51.74 163.88,51.95 163.88,52.14 163.69,52.33 163.5,52.33 163.29,52.12 163.1,52.12 162.91,52.31 162.91,52.5 163.12,52.71 163.12,52.91 162.93,53.1 162.74,53.1 162.53,52.89 162.34,52.89 162.15,53.08 162.15,53.27 162.36,53.48 162.36,53.67 162.17,53.86 161.98,53.86 161.77,53.65 161.58,53.65 161.03,54.2 140.88,54.2 137.76,51.09 136.99,51.09 136.87,50.97
DDR3_CPU_CH0_DQ33: length 90.3
  TOP w0.157: v1(200.85,47.55) 201.02,47.85 P1.135 ; U14.BA30 v1(131.83,46.35)
  L3_SIG w0.102: 137.85,52.68 136.98,52.68 134.93,50.64 134.93,49.59 134.2,48.86 134.2,48.86 133.98,48.63 133.66,48.63 133.41,48.38 133.41,47.03 133.11,46.73 132.35,46.73 131.96,46.35 v1(131.83,46.35)
  L3_SIG w0.135: 137.85,52.68 140.52,55.35 145.1,55.35 147.86,58.12 147.86,59.62 148.92,60.68 154.51,60.68 154.64,60.55 154.64,60.15 154.78,60.02 155.05,60.02 155.18,60.15 155.18,60.55 155.32,60.68 155.59,60.68 155.72,60.55 155.72,60.15 155.86,60.02 156.13,60.02 156.26,60.15 156.26,60.5 156.39,60.63 156.66,60.63 156.8,60.5 156.8,60.19 156.97,60.02 158.76,60.02 158.94,60.21 158.94,60.55 159.08,60.68 160.63,60.68 175.14,46.17 186.42,46.17 187.32,45.27 188.35,45.27 191.47,48.39 199.11,48.39 199.49,48.01 200.36,48.01 200.82,47.55 v1(200.85,47.55)
DDR3_CPU_CH0_DQ34: length 90.3
  TOP w0.102: v1(131.83,48.63) 131.48,48.28 U14.BF30
  TOP w0.157: v1(200.69,50.75) 200.8,50.85 P1.145
  L3_SIG w0.102: 137.18,55.67 136.35,54.84 136.16,54.84 131.85,50.53 131.85,50.02 131.35,49.51 131.35,49.02 131.73,48.63 v1(131.83,48.63)
  L3_SIG w0.135: 137.18,55.67 139.69,58.18 140.21,58.18 146,63.97 151.88,63.97 152.09,64.18 152.09,64.51 152.22,64.64 152.49,64.64 152.63,64.51 152.63,64.1 152.76,63.97 153.03,63.97 153.17,64.1 153.17,64.51 153.3,64.64 153.57,64.64 153.7,64.51 153.7,64.1 153.84,63.97 154.11,63.97 154.24,64.1 154.24,64.51 154.38,64.64 154.65,64.64 154.78,64.51 154.78,64.1 154.92,63.97 155.19,63.97 155.32,64.1 155.32,64.51 155.45,64.64 155.72,64.64 155.86,64.51 155.86,64.1 155.99,63.97 156.55,63.97 156.69,64.1 156.69,64.43 156.82,64.57 157.09,64.57 157.23,64.43 157.23,64.1 157.36,63.97 164.25,63.97 178.39,49.83 186.03,49.83 186.76,50.56 189.15,50.56 189.44,50.85 192.03,50.85 192.03,50.85 192.4,50.85 192.4,50.85 200.59,50.85 v1(200.69,50.75)
DDR3_CPU_CH0_DQ35: length 90.2
  TOP w0.102: U14.BD30 131.48,47.52 v1(131.83,47.87)
  TOP w0.157: v1(200.82,51.52) 200.89,51.45 P1.147
  L3_SIG w0.102: 136.57,55.69 132.67,51.79 131.9,51.79 131.55,51.44 131.55,50.01 131.01,49.47 131.01,48.66 131.8,47.87 v1(131.83,47.87)
  L3_SIG w0.135: 136.57,55.69 138.04,57.16 138.04,57.56 139.39,58.92 140.01,58.92 146.73,65.64 147.66,65.64 147.79,65.5 147.79,64.96 147.93,64.82 148.2,64.82 148.33,64.96 148.33,65.5 148.47,65.64 163.67,65.64 178.91,50.4 186.05,50.4 187.26,51.6 188.46,51.6 188.62,51.76 195.98,51.76 196.29,51.45 197.72,51.45 198.16,51.88 199.7,51.88 200.07,51.52 v1(200.82,51.52)
DDR3_CPU_CH0_DQ36: length 90.3
  TOP w0.157: P1.134 192.96,47.55 192.81,47.7 v1(192.63,47.7) ; U14.BB32 v1(130.55,46.73)
  L3_SIG w0.102: 136.5,50.93 136.5,50.19 135.2,48.89 135.2,45.15 134.85,44.81 134.12,44.81 134.02,44.91 131.93,44.91 131.1,45.75 131.1,46.18 v1(130.55,46.73)
  L3_SIG w0.135: v1(192.63,47.7) 192.51,47.7 192.19,47.38 191.61,47.38 190.98,46.76 190.98,45.52 189.48,44.01 185.78,44.01 184.78,45.01 172.03,45.01 170.11,46.94 170.11,47.13 170.26,47.28 170.26,47.47 170.07,47.66 169.88,47.66 169.73,47.51 169.54,47.51 169.35,47.7 169.35,47.89 169.69,48.23 169.69,48.42 169.5,48.61 169.31,48.61 168.96,48.27 168.77,48.27 168.58,48.46 168.58,48.65 168.93,48.99 168.93,49.18 168.74,49.37 168.55,49.37 168.2,49.03 168.01,49.03 167.82,49.22 167.82,49.41 168.16,49.75 168.16,49.95 167.97,50.14 167.78,50.14 167.44,49.79 167.25,49.79 167.06,49.98 167.06,50.17 167.4,50.52 167.4,50.71 167.21,50.9 167.02,50.9 166.68,50.55 166.49,50.55 166.3,50.75 166.3,50.94 166.64,51.28 166.64,51.47 166.45,51.66 166.26,51.66 165.92,51.32 165.73,51.32 165.54,51.51 165.54,51.7 165.88,52.04 165.88,52.23 165.69,52.42 165.5,52.42 165.15,52.08 164.96,52.08 164.77,52.27 164.77,52.46 165.12,52.8 165.12,52.99 164.93,53.18 164.74,53.18 164.39,52.84 164.2,52.84 164.01,53.03 164.01,53.22 164.35,53.56 164.35,53.76 164.16,53.95 163.97,53.95 163.63,53.6 163.44,53.6 163.25,53.79 163.25,53.98 163.59,54.33 163.59,54.52 163.4,54.71 163.21,54.71 162.87,54.36 162.68,54.36 162.15,54.89 148.03,54.89 147.73,54.59 140.69,54.59 137.69,51.59 136.99,51.59 136.5,51.1 136.5,50.93
DDR3_CPU_CH0_DQ37: length 90.2
  TOP w0.157: v1(131.83,45.59) 131.84,45.46 131.6,45.21 U14.AY30 ; v1(191.77,47.85) 191.77,47.91 192.04,48.18 194.09,48.18 P1.136
  L3_SIG w0.102: 137.16,52.22 136.19,51.25 136.19,50.2 134.64,48.64 134.46,48.64 134.21,48.39 134.21,46.46 134.1,46.35 133.1,46.35 132.72,45.97 132.65,45.97 132.27,45.59 v1(131.83,45.59)
  L3_SIG w0.135: 137.16,52.22 137.87,52.22 140.64,54.99 146.04,54.99 146.55,55.5 152.48,55.5 152.62,55.63 152.62,56.43 152.75,56.57 153.02,56.57 153.16,56.43 153.16,55.63 153.29,55.5 153.56,55.5 153.69,55.63 153.69,56.43 153.83,56.57 154.1,56.57 154.23,56.43 154.23,55.63 154.37,55.5 154.64,55.5 154.77,55.63 154.77,56.43 154.91,56.57 155.17,56.57 155.31,56.43 155.31,55.63 155.44,55.5 155.71,55.5 155.85,55.63 155.85,56.5 156.02,56.67 156.21,56.67 156.39,56.5 156.39,55.7 156.59,55.5 158.46,55.5 158.6,55.63 158.6,57.04 158.73,57.18 159,57.18 159.14,57.04 159.14,55.63 159.27,55.5 159.59,55.5 159.72,55.63 159.72,57.04 159.86,57.18 160.13,57.18 160.26,57.04 160.26,55.63 160.4,55.5 160.67,55.5 160.8,55.63 160.8,56.46 160.93,56.6 161.2,56.6 161.34,56.46 161.34,55.71 161.55,55.5 163.5,55.5 173.42,45.58 185.92,45.58 186.49,45 189.53,45 190.5,45.97 190.5,46.79 191.57,47.85 v1(191.77,47.85)
DDR3_CPU_CH0_DQ38: length 90.3
  TOP w0.102: U14.BG29 132.18,49.05 132.5,49.36 v1(132.61,49.36)
  TOP w0.157: v1(192.68,49.76) 192.86,49.95 P1.142
  L3_SIG w0.102: v1(132.61,49.36) 132.61,49.64 133.42,50.45 133.42,51.06 136.36,54 136.52,54 139.1,56.58 139.86,56.58
  L3_SIG w0.135: 139.86,56.58 140.35,57.06 141.4,57.06 147.17,62.84 161.83,62.84 162.27,62.39 162.46,62.39 162.72,62.65 162.91,62.65 163.1,62.45 163.1,62.26 162.84,62.01 162.84,61.82 163.03,61.63 163.22,61.63 163.48,61.88 163.67,61.88 163.86,61.69 163.86,61.5 163.61,61.25 163.61,61.06 163.8,60.87 163.99,60.87 164.24,61.12 164.43,61.12 164.62,60.93 164.62,60.74 164.37,60.49 164.37,60.3 164.56,60.1 164.75,60.1 165,60.36 165.19,60.36 165.38,60.17 165.38,59.98 165.13,59.72 165.13,59.53 165.32,59.34 165.51,59.34 165.76,59.6 165.95,59.6 166.15,59.41 166.15,59.22 165.89,58.96 165.89,58.77 166.08,58.58 166.27,58.58 166.53,58.84 166.72,58.84 166.91,58.64 166.91,58.45 166.65,58.2 166.65,58.01 166.84,57.82 167.03,57.82 167.29,58.07 167.48,58.07 167.67,57.88 167.67,57.69 167.42,57.44 167.42,57.25 167.61,57.06 167.8,57.06 168.05,57.31 168.24,57.31 168.43,57.12 168.43,56.93 168.18,56.68 168.18,56.49 168.37,56.29 168.56,56.29 168.81,56.55 169,56.55 169.19,56.36 169.19,56.17 168.94,55.91 168.94,55.72 169.13,55.53 169.32,55.53 169.57,55.79 169.76,55.79 169.96,55.6 169.96,55.41 169.7,55.15 169.7,54.96 169.89,54.77 170.08,54.77 170.34,55.03 170.53,55.03 170.72,54.83 170.72,54.64 170.46,54.39 170.46,54.2 170.65,54.01 170.84,54.01 171.1,54.26 171.29,54.26 171.48,54.07 171.48,53.88 171.23,53.63 171.23,53.44 171.42,53.25 171.61,53.25 171.86,53.5 172.05,53.5 172.24,53.31 172.24,53.12 171.99,52.87 171.99,52.68 172.18,52.48 172.37,52.48 172.62,52.74 172.81,52.74 173,52.55 173,52.36 172.75,52.1 172.75,51.91 172.94,51.72 173.13,51.72 173.38,51.98 173.57,51.98 173.77,51.79 173.77,51.6 173.51,51.34 173.51,51.15 173.7,50.96 173.89,50.96 174.15,51.22 174.34,51.22 174.53,51.02 174.53,50.83 174.27,50.58 174.27,50.39 174.72,49.94 174.91,49.94 174.99,50.02 175.18,50.02 175.37,49.83 175.37,49.29 175.96,48.7 186.01,48.7 187.14,49.83 189.45,49.83 189.8,49.48 192.39,49.48 v1(192.68,49.76)
DDR3_CPU_CH0_DQ39: length 90.3
  TOP w0.102: v1(131.83,49.4) 131.48,49.05 U14.BG30
  TOP w0.157: P1.144 192.36,50.55 v1(192.22,50.4)
  L3_SIG w0.102: 139.58,57.1 139.15,57.1 136.39,54.34 136.06,54.34 132.2,50.47 132.2,49.71 131.88,49.4 v1(131.83,49.4)
  L3_SIG w0.135: v1(192.22,50.4) 189.9,50.4 189.59,50.09 186.84,50.09 186.02,49.27 177.15,49.27 176.67,49.75 176.67,49.94 176.93,50.21 176.93,50.4 176.74,50.59 176.55,50.59 176.29,50.32 176.1,50.32 175.73,50.68 175.73,50.87 175.96,51.1 175.96,51.29 175.77,51.48 175.58,51.48 175.35,51.25 175.16,51.25 174.97,51.44 174.97,51.63 175.2,51.86 175.2,52.05 175.01,52.24 174.82,52.24 174.59,52.01 174.4,52.01 174.21,52.21 174.21,52.4 174.44,52.62 174.44,52.81 174.25,53 174.06,53 173.83,52.78 173.64,52.78 173.45,52.97 173.45,53.16 173.68,53.39 173.68,53.58 173.49,53.77 173.3,53.77 173.07,53.54 172.88,53.54 172.69,53.73 172.69,53.92 172.92,54.15 172.92,54.34 172.72,54.53 172.53,54.53 172.31,54.3 172.12,54.3 171.92,54.49 171.92,54.68 172.15,54.91 172.15,55.1 171.96,55.29 171.77,55.29 171.54,55.06 171.35,55.06 171.16,55.25 171.16,55.44 171.39,55.67 171.39,55.86 171.2,56.05 171.01,56.05 170.78,55.82 170.59,55.82 170.4,56.02 170.4,56.21 170.63,56.43 170.63,56.62 170.44,56.81 170.25,56.81 170.02,56.59 169.83,56.59 169.64,56.78 169.64,56.97 169.87,57.2 169.87,57.39 169.68,57.58 169.49,57.58 169.26,57.35 169.07,57.35 168.88,57.54 168.88,57.73 169.11,57.96 169.11,58.15 168.91,58.34 168.72,58.34 168.5,58.11 168.31,58.11 168.11,58.3 168.11,58.49 168.34,58.72 168.34,58.91 168.15,59.1 167.96,59.1 167.73,58.87 167.54,58.87 167.35,59.06 167.35,59.25 167.58,59.48 167.58,59.67 167.39,59.86 167.2,59.86 166.97,59.63 166.78,59.63 166.59,59.83 166.59,60.02 166.82,60.24 166.82,60.43 166.63,60.62 166.44,60.62 166.21,60.4 166.02,60.4 165.83,60.59 165.83,60.78 166.06,61.01 166.06,61.2 165.87,61.39 165.68,61.39 165.45,61.16 165.26,61.16 165.07,61.35 165.07,61.54 165.3,61.77 165.3,61.96 165.1,62.15 164.91,62.15 164.69,61.92 164.5,61.92 164.3,62.11 164.3,62.3 164.53,62.53 164.53,62.72 164.34,62.91 164.15,62.91 163.92,62.68 163.73,62.68 163.01,63.4 146.92,63.4 141.16,57.64 140.12,57.64 139.58,57.1
DDR3_CPU_CH0_DQ40: length 82.8
  TOP w0.102: 142.62,55.12 142.22,55.12 141.17,54.06 140.86,54.06 139.74,52.94 139.74,52.41 139.23,51.9 139.23,50.95 U14.BL16
  TOP w0.157: v1(185.74,51.15) 185.74,50.93 184.44,49.63 156.96,49.63 156.8,49.79 156.8,51.02 156.64,51.17 156.33,51.17 156.17,51.02 156.17,49.79 156.01,49.63 155.7,49.63 155.54,49.79 155.54,51.02 155.38,51.18 155.07,51.18 154.91,51.02 154.91,49.79 154.75,49.63 154.18,49.63 153.95,49.86 153.95,53.18 154.11,53.34 155.96,53.34 156.24,53.62 156.24,54.24 156,54.48 154.11,54.48 153.47,55.12 142.62,55.12 ; v1(200.78,52.65) 201.16,52.65 201.16,52.65 P1.151
  L3_SIG w0.135: v1(185.74,51.15) 185.69,51.2 185.69,51.81 186.74,52.87 196.02,52.87 196.26,52.62 197.23,52.62 197.27,52.65 v1(200.78,52.65)
DDR3_CPU_CH0_DQ41: length 82.8
  TOP w0.102: 140.4,56.57 140.24,56.41 140.24,54.36 138.57,52.69 138.57,51.18 U14.BL17
  TOP w0.157: 140.4,56.57 140.62,56.57 145.52,61.47 160.5,61.47 161.16,60.81 161.16,55.48 161.32,55.32 161.95,55.32 162.1,55.17 162.1,54.85 161.95,54.69 161.32,54.69 161.16,54.54 161.16,52.25 161.76,51.65 183.74,51.65 184,51.9 184.7,51.9 v1(184.85,52.05) ; P1.153 201.09,53.25 v1(200.86,53.48)
  L3_SIG w0.135: v1(200.86,53.48) 200.67,53.48 200.3,53.85 197.31,53.85 196.99,53.53 196.26,53.53 195.98,53.25 185.35,53.25 184.85,52.75 v1(184.85,52.05)
DDR3_CPU_CH0_DQ42: length 82.8
  TOP w0.102: U14.BL21 136.52,51.28 136.52,52.56 137.6,53.65 137.6,56.01 138.32,56.72 138.32,57.64 139.45,58.78 139.45,60.19
  TOP w0.157: P1.159 201.26,55.05 201.09,54.88 200.56,54.88 v1(200.09,55.35) ; 139.45,60.19 139.45,62.43 141.55,64.52 162.62,64.52 168.45,58.68 168.45,58.47 170.33,56.59 182.7,56.59 184.24,55.05 184.5,55.05 185.09,54.46 185.09,53.96 185.36,53.69 185.74,53.69 185.74,53.7 186.03,53.7 v1(186.44,54.1)
  L3_SIG w0.135: v1(200.09,55.35) 198.53,55.35 197.73,54.56 194.42,54.56 193.57,53.7 186.74,53.7 186.46,53.91 v1(186.44,54.1)
DDR3_CPU_CH0_DQ43: length 82.9
  TOP w0.102: U14.BN21 136.15,52.56 137.3,53.7 137.3,56.36 138.02,57.08 138.02,57.89 138.97,58.84 138.97,60.59
  TOP w0.157: v1(185.55,54.15) 185.55,54.67 182.94,57.28 170.76,57.28 162.88,65.16 141.04,65.16 138.97,63.08 138.97,60.59 ; v1(200.85,55.35) 201.15,55.65 P1.161
  L3_SIG w0.135: v1(185.55,54.15) 185.55,54.23 185.93,54.61 190.52,54.61 190.89,54.99 197.36,54.99 198.22,55.84 200.62,55.84 200.85,55.62 v1(200.85,55.35)
DDR3_CPU_CH0_DQ44: length 82.8
  TOP w0.102: 142.95,55.78 142.27,55.78 139.43,52.94 139.43,52.41 138.92,51.9 U14.BM16
  TOP w0.157: 142.95,55.78 153.71,55.78 153.87,55.94 153.87,58.31 154.03,58.47 154.34,58.47 154.5,58.31 154.5,55.94 154.66,55.78 154.97,55.78 155.13,55.94 155.13,58.29 155.29,58.45 155.75,58.45 155.91,58.29 155.91,55.94 156.06,55.78 156.52,55.78 156.67,55.94 156.67,57.4 156.83,57.56 157.15,57.56 157.3,57.4 157.3,55.94 157.46,55.78 158.24,55.78 158.47,55.54 158.47,55.11 158.31,54.96 157.71,54.96 157.56,54.8 157.56,54.48 157.71,54.33 158.31,54.33 158.47,54.17 158.47,53.85 158.31,53.7 157.71,53.7 157.56,53.54 157.56,53.22 157.71,53.07 158.31,53.07 158.47,52.91 158.47,52.59 158.31,52.44 157.71,52.44 157.56,52.28 157.56,51.96 157.71,51.81 158.31,51.81 158.47,51.65 158.47,50.6 158.7,50.37 184.27,50.37 185.56,51.65 186.05,51.65 186.46,51.24 186.46,50.8 186.65,50.61 189.12,50.61 189.27,50.45 189.27,50.2 189.43,50.04 189.75,50.04 189.9,50.2 189.9,50.45 190.06,50.61 191.34,50.61 192.48,51.75 P1.148
DDR3_CPU_CH0_DQ45: length 82.8
  TOP w0.102: 140.91,55.53 140.91,54.73 138.87,52.68 U14.BP16
  TOP w0.157: P1.150 192.49,52.35 191.73,51.59 186.92,51.59 186.51,52 185.51,52 184.77,51.26 184.27,51.26 184.01,51.01 160.88,51.01 160.45,51.44 160.45,52.87 160.29,53.03 159.36,53.03 159.21,53.19 159.21,53.5 159.36,53.66 160.29,53.66 160.45,53.82 160.45,54.13 160.29,54.29 159.36,54.29 159.21,54.45 159.21,54.76 159.36,54.92 160.29,54.92 160.45,55.08 160.45,55.39 160.29,55.55 159.36,55.55 159.21,55.71 159.21,56.02 159.36,56.18 160.29,56.18 160.45,56.34 160.45,56.65 160.29,56.81 159.36,56.81 159.21,56.97 159.21,57.28 159.36,57.44 160.29,57.44 160.45,57.6 160.45,57.91 160.29,58.07 159.36,58.07 159.21,58.23 159.21,58.54 159.36,58.7 160.29,58.7 160.45,58.86 160.45,59.17 160.29,59.33 159.36,59.33 159.16,59.53 159.16,59.76 159.36,59.96 160.29,59.96 160.45,60.12 160.45,60.48 160.1,60.83 145.69,60.83 140.91,56.05 140.91,55.53
DDR3_CPU_CH0_DQ46: length 82.8
  TOP w0.102: U14.BP19 137.43,52.74 138.96,54.28 138.96,57.11 140.61,58.76
  TOP w0.157: P1.160 191.11,55.35 188.88,53.11 185.36,53.11 185.13,53.11 184.77,53.47 183.81,53.47 182.7,54.58 181.08,54.58 180.92,54.43 180.92,54.28 180.76,54.13 180.45,54.13 180.29,54.28 180.29,54.43 180.13,54.58 179.82,54.58 179.66,54.43 179.66,54.03 179.5,53.87 179.19,53.87 179.03,54.03 179.03,54.43 178.87,54.58 178.56,54.58 178.4,54.43 178.4,54.03 178.24,53.87 177.93,53.87 177.77,54.03 177.77,54.43 177.61,54.58 177.3,54.58 177.14,54.43 177.14,54.03 176.98,53.87 176.67,53.87 176.51,54.03 176.51,54.43 176.35,54.58 176.04,54.58 175.88,54.43 175.88,54.03 175.72,53.87 175.41,53.87 175.25,54.03 175.25,54.43 175.09,54.58 174.78,54.58 174.62,54.43 174.62,54.03 174.46,53.87 174.15,53.87 173.99,54.03 173.99,54.43 173.83,54.58 173.52,54.58 173.36,54.43 173.36,54.03 173.2,53.87 172.89,53.87 172.73,54.03 172.73,54.43 172.57,54.58 172.26,54.58 172.1,54.43 172.1,54.03 171.94,53.87 171.63,53.87 171.47,54.03 171.47,54.43 171.31,54.58 171,54.58 170.84,54.43 170.84,54.03 170.68,53.87 170.37,53.87 170.21,54.03 170.21,54.43 170.05,54.58 169.74,54.58 169.58,54.43 169.58,54.03 169.42,53.87 169.11,53.87 168.95,54.03 168.95,54.43 168.79,54.58 168.48,54.58 168.32,54.43 168.32,54.03 168.16,53.87 167.85,53.87 167.69,54.03 167.69,54.43 167.53,54.58 167.21,54.58 167.06,54.74 167.06,57.81 161.72,63.14 141.94,63.14 140.61,61.81 140.61,58.76
DDR3_CPU_CH0_DQ47: length 82.9
  TOP w0.102: U14.BN19 136.81,51.96 136.81,52.5 137.95,53.65 137.95,55.68 138.6,56.33 138.6,57.3 140.05,58.75
  TOP w0.157: P1.162 190.83,55.95 188.28,53.4 185.25,53.4 184.24,54.41 183.98,54.41 182.44,55.95 181.3,55.95 181.14,55.79 181.14,55.48 180.99,55.32 180.67,55.32 180.52,55.48 180.52,55.79 180.36,55.95 179.73,55.95 179.58,55.79 179.58,55.43 179.42,55.27 179.1,55.27 178.95,55.43 178.95,55.79 178.79,55.95 178.47,55.95 178.32,55.79 178.32,55.43 178.16,55.27 177.84,55.27 177.69,55.43 177.69,55.79 177.53,55.95 177.21,55.95 177.06,55.79 177.06,55.43 176.9,55.27 176.58,55.27 176.43,55.43 176.43,55.79 176.27,55.95 175.95,55.95 175.8,55.79 175.8,55.43 175.64,55.27 175.32,55.27 175.17,55.43 175.17,55.79 175.01,55.95 174.69,55.95 174.54,55.79 174.54,55.43 174.38,55.27 174.06,55.27 173.91,55.43 173.91,55.79 173.75,55.95 173.43,55.95 173.28,55.79 173.28,55.43 173.12,55.27 172.8,55.27 172.65,55.43 172.65,55.79 172.49,55.95 172.17,55.95 172.02,55.79 172.02,55.43 171.86,55.27 171.54,55.27 171.39,55.43 171.39,55.79 171.23,55.95 170.92,55.95 170.76,55.79 170.76,55.43 170.6,55.27 170.29,55.27 170.13,55.43 170.13,55.79 169.97,55.95 169.66,55.95 169.5,55.79 169.5,55.43 169.34,55.27 169.03,55.27 168.87,55.43 168.87,55.79 168.71,55.95 168.31,55.95 167.81,56.44 167.81,58.42 162.4,63.83 141.95,63.83 140.05,61.93 140.05,58.75
DDR3_CPU_CH0_DQ48: length 92.2
  TOP w0.102: v1(138.03,61.87) 138.29,61.61 138.29,59.66 134.93,56.29 134.93,52.31 134.42,51.8 U14.BM25
  TOP w0.157: P1.165 200.84,56.85 v1(200.77,56.78)
  L3_SIG w0.135: v1(138.03,61.87) 138.03,60.77 138.23,60.58 139.78,60.58 140.26,61.06 140.26,61.25 139.98,61.53 139.98,61.72 140.17,61.92 140.36,61.92 140.64,61.64 140.83,61.64 141.02,61.83 141.02,62.02 140.74,62.3 140.74,62.49 140.93,62.68 141.12,62.68 141.4,62.4 141.59,62.4 141.79,62.59 141.79,62.78 141.51,63.06 141.51,63.25 141.7,63.44 141.89,63.44 142.17,63.16 142.36,63.16 142.55,63.35 142.55,63.54 142.27,63.82 142.27,64.01 142.46,64.2 142.65,64.2 142.93,63.92 143.12,63.92 143.31,64.11 143.31,64.3 143.03,64.58 143.03,64.77 143.22,64.96 143.41,64.96 143.69,64.68 143.88,64.68 144.45,65.26 144.45,65.45 144.2,65.7 144.2,65.89 144.39,66.08 144.58,66.08 144.83,65.83 145.02,65.83 146.01,66.82 163.94,66.82 175.51,55.24 185.12,55.24 185.49,55.62 186.63,55.62 186.87,55.38 192.83,55.38 193.66,56.2 197.63,56.2 198.58,57.15 200.4,57.15 v1(200.77,56.78)
DDR3_CPU_CH0_DQ49: length 92.3
  TOP w0.102: U14.BP25 134.37,52.58 134.72,52.94 134.72,56.4 137.82,59.5 v1(137.82,59.87)
  TOP w0.157: v1(200.84,57.55) 200.94,57.45 P1.167
  L3_SIG w0.135: v1(200.84,57.55) 200.63,57.76 197.99,57.76 196.88,56.64 194.92,56.64 194.82,56.74 193.53,56.74 192.59,55.8 187.15,55.8 186.67,56.28 185.32,56.28 184.86,55.83 175.84,55.83 175.18,56.49 175.18,56.82 174.89,57.11 174.56,57.11 174.32,57.35 174.32,57.54 174.45,57.67 174.45,57.86 174.26,58.05 174.07,58.05 173.94,57.92 173.75,57.92 173.56,58.11 173.56,58.3 173.69,58.43 173.69,58.62 173.5,58.81 173.31,58.81 173.18,58.68 172.99,58.68 172.8,58.87 172.8,59.07 172.93,59.19 172.93,59.38 172.74,59.57 172.54,59.57 172.42,59.45 172.23,59.45 172.04,59.64 172.04,59.83 172.16,59.95 172.16,60.14 171.97,60.34 171.78,60.34 171.66,60.21 171.47,60.21 171.27,60.4 171.27,60.59 171.4,60.72 171.4,60.91 171.21,61.1 171.02,61.1 170.89,60.97 170.7,60.97 170.51,61.16 170.51,61.35 170.64,61.48 170.64,61.67 170.45,61.86 170.26,61.86 170.13,61.73 169.94,61.73 169.75,61.92 169.75,62.11 169.88,62.24 169.88,62.43 169.69,62.62 169.5,62.62 169.37,62.49 169.18,62.49 168.99,62.68 168.99,62.88 169.12,63 169.12,63.19 168.93,63.38 168.73,63.38 168.61,63.26 168.42,63.26 168.23,63.45 168.23,63.64 168.35,63.76 168.35,63.95 168.16,64.15 167.97,64.15 167.85,64.02 167.66,64.02 167.46,64.21 167.46,64.4 167.59,64.53 167.59,64.72 167.4,64.91 167.21,64.91 167.08,64.78 166.89,64.78 166.7,64.97 166.7,65.16 166.83,65.29 166.83,65.48 166.64,65.67 166.45,65.67 166.32,65.54 166.13,65.54 165.94,65.73 165.94,65.92 166.07,66.05 166.07,66.24 165.88,66.43 165.69,66.43 165.56,66.3 165.37,66.3 165.18,66.49 165.18,66.69 165.31,66.81 165.31,67 165.12,67.19 164.92,67.19 164.8,67.07 164.61,67.07 164.29,67.38 143.94,67.38 138.93,62.38 137.86,62.38 137.54,62.06 137.54,60.15 v1(137.82,59.87)
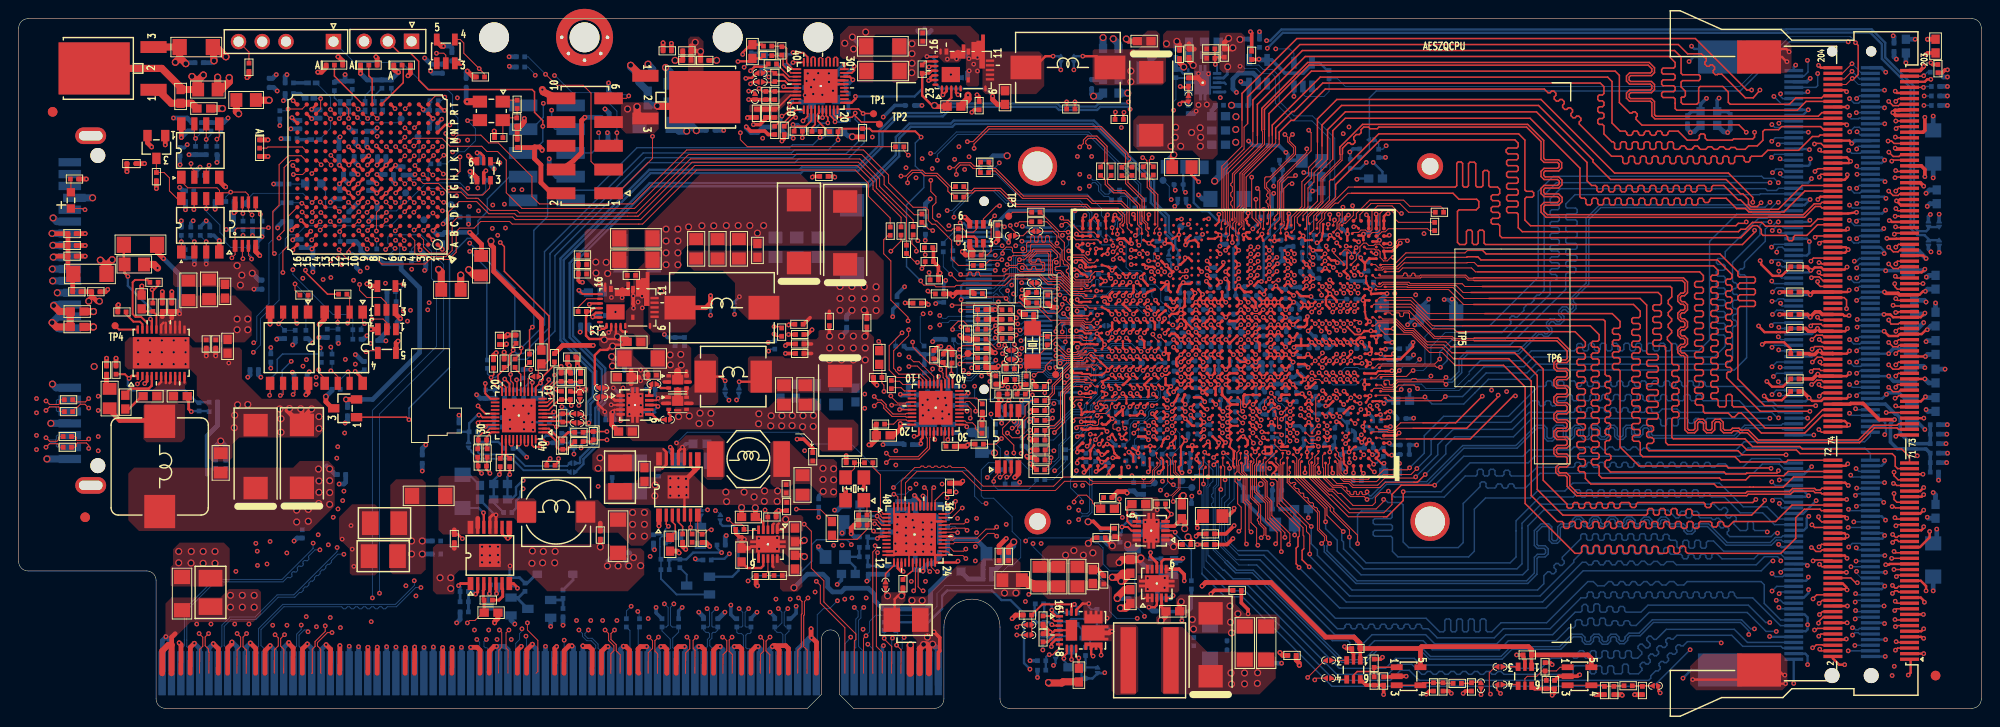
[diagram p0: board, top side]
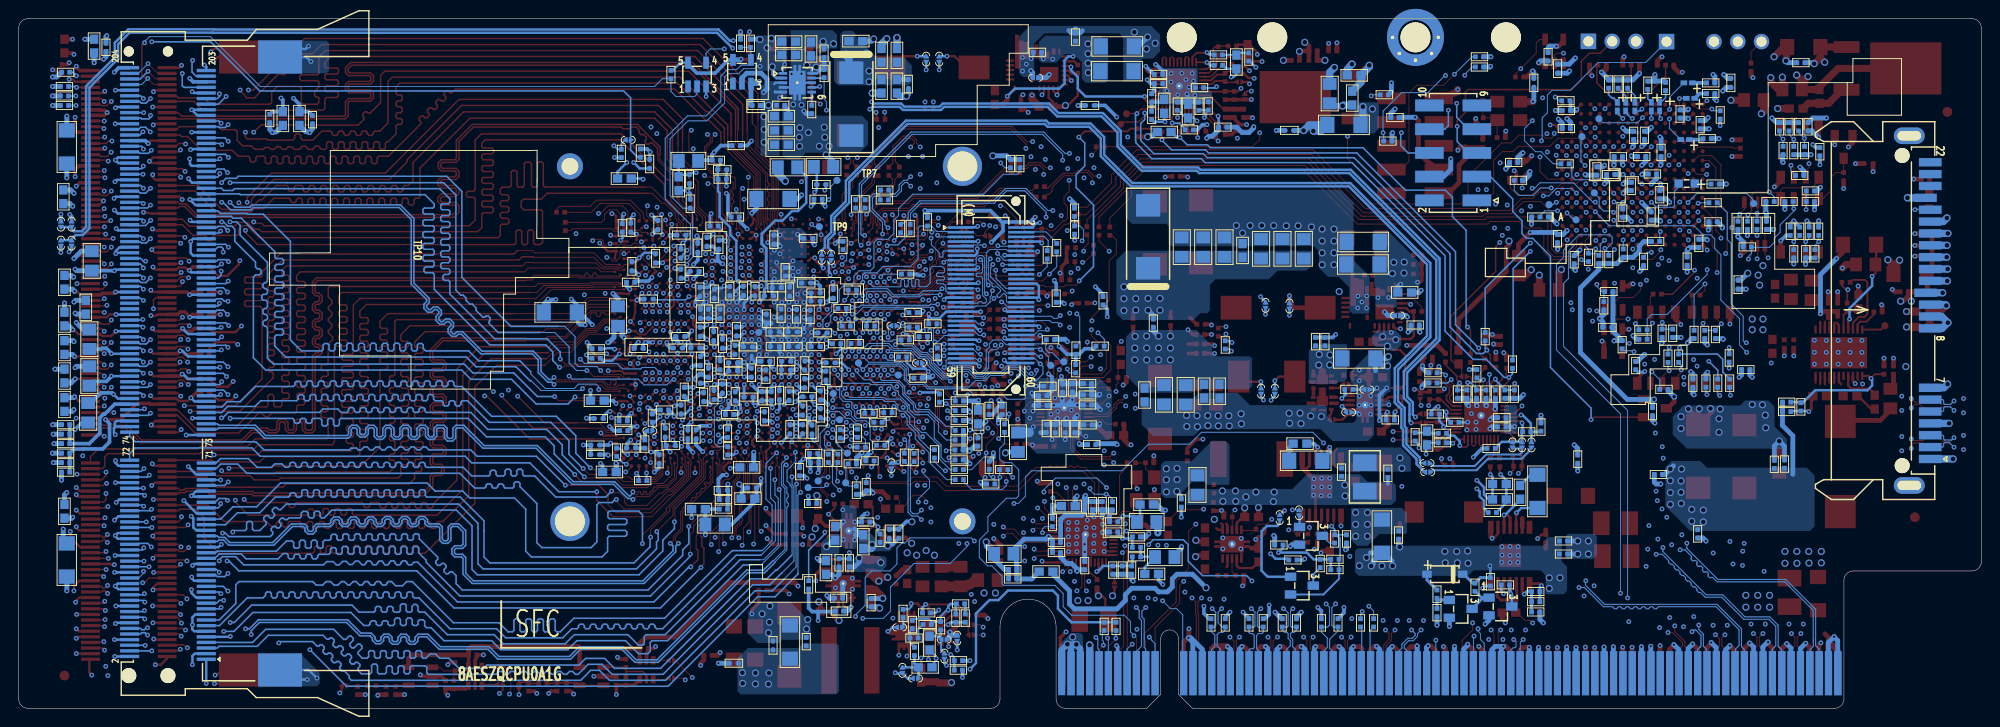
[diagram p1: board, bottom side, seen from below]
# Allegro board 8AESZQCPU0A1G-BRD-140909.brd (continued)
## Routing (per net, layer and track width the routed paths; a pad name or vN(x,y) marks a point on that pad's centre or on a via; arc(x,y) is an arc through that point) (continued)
DDR3_CPU_CH0_DQ50: length 92.2
  TOP w0.102: U14.BL28 132.57,51.12 132.89,51.44 132.89,51.85 132.82,51.92 132.82,51.95 132.38,52.39 v1(132.38,54.48)
  TOP w0.157: P1.177 200.66,60.45 200.41,60.71 v1(200.03,60.71)
  L3_SIG w0.135: v1(200.03,60.71) 199.84,60.9 190.03,60.9 189.61,61.32 187.32,61.32 186.19,60.18 183.38,60.18 181.89,61.67 180.54,61.67 171.15,71.07 139.32,71.07 132.58,64.33 132.58,56.58 131.75,55.75 131.75,55.04 132.31,54.48 v1(132.38,54.48)
DDR3_CPU_CH0_DQ51: length 92.2
  TOP w0.102: v1(131.93,56.84) 131.93,53.19 131.96,53.16 131.96,52.5 132.61,51.85 132.61,51.73 U14.BN28
  TOP w0.157: P1.179 200.88,61.05 v1(200.8,61.13)
  L3_SIG w0.135: v1(200.8,61.13) 200.58,61.35 197.36,61.35 197.21,61.2 191.68,61.2 190.69,61.2 190.25,61.65 186.85,61.65 185.95,60.75 184.66,60.75 182.85,62.56 180.49,62.56 179.37,63.68 179.37,63.98 179.37,64.29 179.19,64.48 178.58,64.48 171.42,71.63 139.04,71.63 132.05,64.63 132.05,60.09 131.73,59.77 131.73,57.04 v1(131.93,56.84)
DDR3_CPU_CH0_DQ52: length 92.2
  TOP w0.102: U14.BL23 135.03,51.3 135.41,51.67 135.41,52.08 135.36,52.13 135.36,55.61 135.9,56.14 v1(136.25,56.14)
  TOP w0.157: P1.166 192.83,57.15 192.67,56.99 v1(192.67,56.84)
  L3_SIG w0.135: v1(192.67,56.84) 192.06,56.24 189.31,56.24 188.82,56.72 186.68,56.72 186.55,56.85 185.2,56.85 184.74,56.4 176.8,56.4 175.54,57.66 175.54,57.99 175.79,58.23 175.79,58.43 175.6,58.62 175.41,58.62 175.09,58.3 174.9,58.3 174.71,58.49 174.71,58.68 175.03,59 175.03,59.19 174.84,59.38 174.65,59.38 174.33,59.06 174.14,59.06 173.95,59.25 173.95,59.44 174.26,59.76 174.26,59.95 174.07,60.14 173.88,60.14 173.57,59.82 173.38,59.82 173.18,60.01 173.18,60.2 173.5,60.52 173.5,60.71 173.31,60.9 173.12,60.9 172.8,60.58 172.61,60.58 172.42,60.77 172.42,60.97 172.74,61.28 172.74,61.47 172.55,61.66 172.36,61.66 172.04,61.35 171.85,61.35 171.66,61.54 171.66,61.73 171.98,62.04 171.98,62.24 171.79,62.43 171.6,62.43 171.28,62.11 171.09,62.11 170.9,62.3 170.9,62.49 171.22,62.81 171.22,63 171.03,63.19 170.84,63.19 170.52,62.87 170.33,62.87 170.14,63.06 170.14,63.25 170.45,63.57 170.45,63.76 170.26,63.95 170.07,63.95 169.76,63.63 169.57,63.63 169.37,63.82 169.37,64.01 169.69,64.33 169.69,64.52 169.5,64.71 169.31,64.71 168.99,64.39 168.8,64.39 168.61,64.58 168.61,64.78 168.93,65.09 168.93,65.28 168.74,65.47 168.55,65.47 168.23,65.16 168.04,65.16 167.85,65.35 167.85,65.54 168.17,65.85 168.17,66.05 167.98,66.24 167.79,66.24 167.47,65.92 167.28,65.92 167.09,66.11 167.09,66.3 167.41,66.62 167.41,66.81 167.22,67 167.03,67 166.71,66.68 166.52,66.68 166.33,66.87 166.33,67.06 166.64,67.38 166.64,67.57 166.45,67.76 166.26,67.76 165.95,67.44 165.76,67.44 165.25,67.95 143.31,67.95 138.21,62.85 137.67,62.85 137.23,62.41 137.23,59.69 137.1,59.56 137.1,56.86 136.39,56.14 v1(136.25,56.14)
DDR3_CPU_CH0_DQ53: length 92.2
  TOP w0.102: v1(136.62,57.02) 136.44,56.84 135.81,56.84 135.15,56.18 135.15,51.87 U14.BN23
  TOP w0.157: v1(192.2,57.45) 192.5,57.75 P1.168
  L3_SIG w0.135: v1(192.2,57.45) 189.36,57.45 189,57.81 186.75,57.81 186.36,57.42 184.8,57.42 184.35,56.97 178.13,56.97 176.19,58.91 176.19,59.1 176.27,59.17 176.27,59.36 176.08,59.56 175.89,59.56 175.81,59.48 175.62,59.48 175.13,59.97 175.13,60.16 175.26,60.29 175.26,60.48 175.07,60.67 174.88,60.67 174.75,60.54 174.56,60.54 174.37,60.73 174.37,60.92 174.5,61.05 174.5,61.24 174.3,61.43 174.11,61.43 173.99,61.31 173.8,61.31 173.61,61.5 173.61,61.69 173.73,61.81 173.73,62 173.54,62.19 173.35,62.19 173.23,62.07 173.03,62.07 172.84,62.26 172.84,62.45 172.97,62.58 172.97,62.77 172.78,62.96 172.59,62.96 172.46,62.83 172.27,62.83 172.08,63.02 172.08,63.21 172.21,63.34 172.21,63.53 172.02,63.72 171.83,63.72 171.7,63.59 171.51,63.59 171.32,63.78 171.32,63.97 171.45,64.1 171.45,64.29 171.26,64.48 171.07,64.48 170.94,64.35 170.75,64.35 170.56,64.54 170.56,64.73 170.69,64.86 170.69,65.05 170.49,65.24 170.3,65.24 170.18,65.12 169.99,65.12 169.8,65.31 169.8,65.5 169.92,65.62 169.92,65.81 169.73,66 169.54,66 169.42,65.88 169.22,65.88 169.03,66.07 169.03,66.26 169.16,66.39 169.16,66.58 168.97,66.77 168.78,66.77 168.65,66.64 168.46,66.64 168.27,66.83 168.27,67.02 168.4,67.15 168.4,67.34 168.21,67.53 168.02,67.53 167.89,67.4 167.7,67.4 167.51,67.59 167.51,67.78 167.64,67.91 167.64,68.1 167.45,68.29 167.26,68.29 167.13,68.16 166.94,68.16 166.59,68.52 142.74,68.52 136.83,62.61 136.83,60.38 136.37,59.92 135.92,59.92 135.79,60.05 135.79,60.5 135.65,60.63 135.39,60.63 135.25,60.5 135.25,60.05 135.12,59.92 134.73,59.92 134.59,59.78 134.59,58.94 134.73,58.8 136.34,58.8 136.47,58.67 136.47,58.06 136.32,57.91 134.73,57.91 134.59,57.78 134.59,57.2 134.85,56.95 136.55,56.95 v1(136.62,57.02)
DDR3_CPU_CH0_DQ54: length 92.2
  TOP w0.102: U14.BM27 133.18,52.09 133.22,52.13 v1(133.22,53.38)
  TOP w0.157: P1.174 192.85,59.55 192.7,59.71 v1(192.7,59.75)
  L3_SIG w0.135: v1(133.22,53.38) 133.22,53.53 133.86,54.16 133.86,63.97 139.82,69.93 168.62,69.93 169.04,69.51 169.23,69.51 169.46,69.74 169.65,69.74 169.84,69.55 169.84,69.36 169.61,69.13 169.61,68.94 169.81,68.75 170,68.75 170.22,68.98 170.41,68.98 170.61,68.79 170.61,68.6 170.38,68.37 170.38,68.18 170.57,67.99 170.76,67.99 170.99,68.22 171.18,68.22 171.37,68.03 171.37,67.84 171.14,67.61 171.14,67.42 171.33,67.23 171.52,67.23 171.75,67.46 171.94,67.46 172.13,67.27 172.13,67.08 171.9,66.85 171.9,66.66 172.09,66.47 172.28,66.47 172.51,66.69 172.7,66.69 172.89,66.5 172.89,66.31 172.66,66.08 172.66,65.89 172.85,65.7 173.04,65.7 173.27,65.93 173.46,65.93 173.65,65.74 173.65,65.55 173.42,65.32 173.42,65.13 173.62,64.94 173.81,64.94 174.03,65.17 174.22,65.17 174.42,64.98 174.42,64.79 174.19,64.56 174.19,64.37 174.38,64.18 174.57,64.18 174.8,64.41 174.99,64.41 175.18,64.22 175.18,64.03 174.95,63.8 174.95,63.61 175.14,63.42 175.33,63.42 175.56,63.65 175.75,63.65 175.94,63.46 175.94,63.27 175.71,63.04 175.71,62.85 175.9,62.66 176.09,62.66 176.32,62.88 176.51,62.88 176.7,62.69 176.7,62.5 176.47,62.27 176.47,62.08 176.66,61.89 176.85,61.89 177.08,62.12 177.27,62.12 177.46,61.93 177.46,61.74 177.23,61.51 177.23,61.32 177.43,61.13 177.62,61.13 177.84,61.36 178.03,61.36 178.23,61.17 178.23,60.98 178,60.75 178,60.56 178.36,60.2 178.55,60.2 178.81,60.47 179,60.47 179.19,60.28 179.19,60.09 178.93,59.82 178.93,59.63 179.61,58.95 186.87,58.95 187.33,59.42 190.2,59.42 190.32,59.3 192.24,59.3 v1(192.7,59.75)
DDR3_CPU_CH0_DQ55: length 92.3
  TOP w0.102: U14.BP28 132.8,52.43 132.8,55.38 v1(132.53,55.64)
  TOP w0.157: v1(192.14,60.39) 192.2,60.45 192.85,60.45 193.15,60.15 P1.176
  L3_SIG w0.135: v1(192.14,60.39) 190.66,60.39 190.12,59.85 186.67,59.85 186.37,59.55 181.85,59.55 181.43,59.97 181.15,59.97 180.89,59.71 180.7,59.71 180.51,59.9 180.51,60.09 180.81,60.4 180.81,60.59 180.55,60.85 180.36,60.85 180.19,60.67 180,60.67 179.81,60.86 179.81,61.05 179.98,61.23 179.98,61.42 178.98,62.42 178.54,62.42 178.29,62.16 178.1,62.16 177.9,62.35 177.9,62.54 178.16,62.8 178.16,62.99 177.97,63.18 177.78,63.18 177.52,62.93 177.33,62.93 177.14,63.12 177.14,63.31 177.4,63.56 177.4,63.75 177.21,63.94 177.02,63.94 176.76,63.69 176.57,63.69 176.38,63.88 176.38,64.07 176.63,64.32 176.63,64.51 176.44,64.7 176.25,64.7 176,64.45 175.81,64.45 175.62,64.64 175.62,64.83 175.87,65.08 175.87,65.27 175.68,65.47 175.49,65.47 175.24,65.21 175.05,65.21 174.86,65.4 174.86,65.59 175.11,65.85 175.11,66.04 174.92,66.23 174.73,66.23 174.48,65.97 174.29,65.97 174.09,66.16 174.09,66.35 174.35,66.61 174.35,66.8 174.16,66.99 173.97,66.99 173.71,66.74 173.52,66.74 173.33,66.93 173.33,67.12 173.59,67.37 173.59,67.56 173.4,67.75 173.21,67.75 172.95,67.5 172.76,67.5 172.57,67.69 172.57,67.88 172.82,68.13 172.82,68.32 172.63,68.51 172.44,68.51 172.19,68.26 172,68.26 171.81,68.45 171.81,68.64 172.06,68.89 172.06,69.08 171.87,69.28 171.68,69.28 171.43,69.02 171.24,69.02 171.05,69.21 171.05,69.4 171.3,69.66 171.3,69.85 171.11,70.04 170.92,70.04 170.67,69.78 170.48,69.78 169.76,70.5 139.58,70.5 133.15,64.07 133.15,56.26 v1(132.53,55.64)
DDR3_CPU_CH0_DQ56: length 93
  TOP w0.102: U14.BN32 130.58,51.81 130.58,53.42 130.91,53.74 130.91,57.19 134.13,60.42 134.13,61.34
  TOP w0.157: v1(185.74,61.65) 185.74,61.13 185.55,60.93 183.49,60.93 183.36,60.81 180.67,60.81 180.46,61.02 180.46,61.31 180.3,61.47 179.99,61.47 179.83,61.31 179.83,61.02 179.62,60.81 178.53,60.81 177.57,61.77 176.62,61.77 176.47,61.61 176.47,61.47 176.31,61.32 175.99,61.32 175.84,61.47 175.84,61.61 175.68,61.77 175.36,61.77 175.21,61.61 175.21,61.47 175.05,61.32 174.73,61.32 174.58,61.47 174.58,61.61 174.42,61.77 174.1,61.77 173.95,61.61 173.95,61.47 173.79,61.32 173.47,61.32 173.32,61.47 173.32,61.61 173.16,61.77 172.84,61.77 172.69,61.61 172.69,61.47 172.53,61.32 172.21,61.32 172.06,61.47 172.06,61.61 171.9,61.77 171.35,61.77 170.48,62.64 170.48,67.08 170.02,67.55 139.27,67.55 134.13,62.41 134.13,61.34 ; P1.183 201.09,62.25 v1(200.88,62.04)
  L3_SIG w0.135: v1(185.74,61.65) 185.74,62.19 186.66,63.12 188.77,63.12 188.9,62.99 195.66,62.99 195.67,63 198.42,63 199.38,62.04 v1(200.88,62.04)
DDR3_CPU_CH0_DQ57: length 93
  TOP w0.102: U14.BK32 130.37,50.47 130.23,50.62 130.23,51.9 130.35,52.03 130.35,53.52 130.67,53.84 130.67,57.26 133.78,60.37 133.78,61.25
  TOP w0.157: P1.185 v1(200.85,62.85) ; v1(184.85,61.65) 184.06,62.44 178.43,62.44 178.4,62.41 173.69,62.41 173.06,63.03 173.06,63.26 173.19,63.38 173.19,63.61 172.96,63.83 172.74,63.83 172.61,63.7 172.39,63.7 171.27,64.82 171.27,67.74 170.83,68.19 138.32,68.19 133.78,63.65 133.78,61.25
  L3_SIG w0.135: v1(184.85,61.65) 184.91,61.71 184.91,62.31 186.18,63.58 191.72,63.58 192.04,63.9 194.1,63.9 195,64.8 196.59,64.8 197.56,63.83 199.29,63.83 200.27,62.85 v1(200.85,62.85)
DDR3_CPU_CH0_DQ58: length 92.9
  TOP w0.102: U14.BN35 129.1,53.14 128.98,53.26 128.98,53.29 128.96,53.31 128.96,57.7 131.11,59.86 131.11,62.19 131.5,62.58
  TOP w0.157: v1(200.09,64.95) 200.55,64.49 201.14,64.49 201.3,64.65 P1.191 ; 131.5,62.58 131.5,65.44 137.09,71.03 177.58,71.03 178.57,70.04 180.05,70.04 180.57,69.52 180.57,69.3 180.43,69.15 180.43,68.93 180.65,68.7 180.87,68.7 181.02,68.85 181.24,68.85 181.46,68.63 181.46,68.4 181.32,68.26 181.32,68.04 181.54,67.81 181.76,67.81 181.82,67.87 182.22,67.87 184.75,65.33 185.6,65.33 v1(186.31,66.17)
  L3_SIG w0.135: v1(200.09,64.95) 200.08,64.94 198.31,64.94 196.76,66.49 186.63,66.49 v1(186.31,66.17)
DDR3_CPU_CH0_DQ59: length 92.9
  TOP w0.102: U14.BM36 128.68,52.01 128.85,52.18 128.85,53.06 128.74,53.17 128.74,57.99 130.89,60.15 130.89,62.96
  TOP w0.157: v1(200.85,64.95) 201.15,65.25 P1.193 ; v1(185.42,66.17) 184.92,66.16 179.41,71.67 136.76,71.67 130.89,65.8 130.89,62.96
  L3_SIG w0.135: v1(185.42,66.17) 186.17,66.92 197.52,66.92 198.95,65.49 200.32,65.49 v1(200.85,64.95)
DDR3_CPU_CH0_DQ60: length 93
  TOP w0.102: U14.BM31 131.1,51.33 131.1,52.06 131,52.16 131,53.1 131.34,53.44 131.34,56.85 134.87,60.38 134.87,60.9
  TOP w0.157: P1.180 192.76,61.35 192.6,61.19 191.92,61.19 190.45,59.72 187.15,59.72 186.51,59.08 185.42,59.08 185.26,58.92 185.26,58.63 185.1,58.47 184.79,58.47 184.63,58.63 184.63,58.92 184.47,59.08 183.76,59.08 183.6,58.92 183.6,58.45 183.45,58.29 183.13,58.29 182.97,58.45 182.97,58.92 182.82,59.08 182.5,59.08 182.34,58.92 182.34,58.45 182.19,58.29 181.87,58.29 181.71,58.45 181.71,58.92 181.56,59.08 181.24,59.08 181.08,58.92 181.08,58.45 180.93,58.29 180.61,58.29 180.45,58.45 180.45,58.92 180.3,59.08 179.98,59.08 179.82,58.92 179.82,58.45 179.67,58.29 179.35,58.29 179.19,58.45 179.19,58.92 179.04,59.08 178.72,59.08 178.56,58.92 178.56,58.45 178.41,58.29 178.09,58.29 177.93,58.45 177.93,58.92 177.78,59.08 177.46,59.08 177.3,58.92 177.3,58.45 177.15,58.29 176.83,58.29 176.67,58.45 176.67,58.92 176.52,59.08 176.2,59.08 176.04,58.92 176.04,58.45 175.89,58.29 175.57,58.29 175.41,58.45 175.41,58.92 175.26,59.08 174.94,59.08 174.78,58.92 174.78,58.45 174.63,58.29 174.31,58.29 174.15,58.45 174.15,58.92 174,59.08 173.68,59.08 173.52,58.92 173.52,58.45 173.37,58.29 173.05,58.29 172.89,58.45 172.89,58.92 172.74,59.08 172.42,59.08 172.26,58.92 172.26,58.45 172.11,58.29 171.79,58.29 171.63,58.45 171.63,58.92 171.48,59.08 170.43,59.08 166.98,62.53 166.98,62.76 167.15,62.93 167.15,63.15 166.93,63.37 166.71,63.37 166.54,63.2 166.31,63.2 166.09,63.42 166.09,63.65 166.26,63.82 166.26,64.04 166.04,64.26 165.82,64.26 165.65,64.09 165.42,64.09 165.2,64.31 165.2,64.54 165.37,64.71 165.37,64.93 165.15,65.15 164.93,65.15 164.75,64.98 164.53,64.98 164.31,65.21 164.31,65.43 164.48,65.6 164.48,65.82 164.26,66.05 164.03,66.05 163.86,65.87 163.64,65.87 163.25,66.27 139.8,66.27 136.45,62.92 136.13,62.92 134.87,61.66 134.87,60.9
DDR3_CPU_CH0_DQ61: length 92.9
  TOP w0.102: U14.BL32 130.53,51.25 130.89,51.61 130.89,51.94 130.8,52.03 130.8,53.28 131.11,53.59 131.11,57.11 134.5,60.5 134.5,60.99
  TOP w0.157: 134.5,60.99 134.5,62.09 136.28,63.87 136.46,63.87 138.88,66.29 138.91,66.29 139.53,66.91 169.24,66.91 169.62,66.52 169.62,65.79 169.46,65.64 169.12,65.64 168.96,65.48 168.96,65.16 169.12,65.01 169.46,65.01 169.62,64.85 169.62,64.53 169.46,64.38 169.12,64.38 168.96,64.22 168.96,63.9 169.12,63.75 169.46,63.75 169.62,63.59 169.62,63.27 169.46,63.12 169.12,63.12 168.96,62.96 168.96,62.64 169.12,62.49 169.46,62.49 169.62,62.33 169.62,61.47 170.46,60.63 170.6,60.63 170.76,60.47 170.76,59.97 170.92,59.82 171.23,59.82 171.39,59.97 171.39,60.47 171.55,60.63 171.86,60.63 172.02,60.47 172.02,59.97 172.18,59.82 172.49,59.82 172.65,59.97 172.65,60.47 172.81,60.63 173.12,60.63 173.28,60.47 173.28,59.97 173.44,59.82 173.75,59.82 173.91,59.97 173.91,60.47 174.07,60.63 174.38,60.63 174.54,60.47 174.54,59.97 174.7,59.82 175.01,59.82 175.17,59.97 175.17,60.47 175.33,60.63 175.64,60.63 175.8,60.47 175.8,59.97 175.96,59.82 176.27,59.82 176.43,59.97 176.43,60.47 176.59,60.63 176.9,60.63 177.06,60.47 177.06,59.97 177.22,59.82 177.6,59.82 177.76,59.97 177.76,60.02 177.91,60.17 178.23,60.17 178.39,60.02 178.39,59.97 178.54,59.82 179.01,59.82 179.17,59.97 179.17,60.01 179.33,60.16 179.64,60.16 179.8,60.01 179.8,59.97 179.96,59.82 180.51,59.82 180.78,60.09 181.14,60.09 181.41,59.82 181.77,59.82 182.04,60.09 182.4,60.09 182.67,59.82 183.01,59.82 183.21,60.02 183.64,60.02 183.84,59.82 184.73,59.82 185.11,60.19 186.03,60.19 186.63,60.79 186.63,61.72 186.83,61.93 188.31,61.93 188.63,62.25 192.8,62.25 193.1,61.95 P1.182
DDR3_CPU_CH0_DQ62: length 92.9
  TOP w0.102: U14.BK35 129.35,50.45 129.56,50.66 129.56,51.43 129.61,51.48 129.61,52.11 129.58,52.14 129.58,53.37 129.41,53.54 129.41,57.3 132.54,60.43 132.54,61.3
  TOP w0.157: P1.192 191.26,64.95 190.31,64.01 177.42,64.01 177.24,64.19 177.24,64.76 177.24,64.76 177.24,65.21 177.08,65.36 175.95,65.36 175.79,65.52 175.79,65.84 175.95,65.99 177.08,65.99 177.24,66.15 177.24,66.47 177.08,66.62 175.95,66.62 175.79,66.78 175.79,67.1 175.95,67.25 177.08,67.25 177.24,67.41 177.24,67.73 177.08,67.88 175.95,67.88 175.79,68.04 175.79,68.35 175.95,68.51 177.08,68.51 177.24,68.67 177.24,69.12 176.6,69.75 137.66,69.75 132.54,64.64 132.54,61.3
DDR3_CPU_CH0_DQ63: length 92.9
  TOP w0.102: U14.BL35 129.18,51.43 129.41,51.66 129.41,52.03 129.33,52.11 129.33,53.24 129.21,53.36 129.21,57.55 132.06,60.39 132.06,61.75
  TOP w0.157: P1.194 193.13,65.55 192.91,65.33 190.15,65.33 189.47,64.65 183.13,64.65 182.93,64.85 182.93,65.95 182.33,66.54 179.91,66.54 179.76,66.39 179.76,64.85 179.55,64.65 178.08,64.65 177.89,64.84 177.89,65.34 177.95,65.41 178.18,65.41 178.33,65.56 178.33,66.04 177.88,66.5 177.88,67.02 178.03,67.17 179.78,67.17 179.93,67.33 179.93,67.65 179.78,67.8 178.03,67.8 177.88,67.96 177.88,69.7 177.18,70.39 137.35,70.39 132.06,65.1 132.06,61.75
DDR3_CPU_CH0_DQS_DN0: length 87
  TOP w0.102: U14.AL12 140.99,40.46 v1(141.02,40.46)
  TOP w0.157: P1.10 192.84,7.95 v1(192.61,7.72)
  L3_SIG w0.102: 148.82,34.82 148.79,34.82 148.76,34.85 147.11,34.85 145.05,36.9 145.05,38.39 143.86,39.58 141.72,39.58 141.35,39.95 141.35,40.13 v1(141.02,40.46)
  L3_SIG w0.135: v1(192.61,7.72) 192.56,7.67 189.94,7.67 189.19,6.92 183.86,6.92 182.57,8.21 178.86,8.21 178.14,7.49 176.29,7.49 175.57,8.21 164.14,8.21 158.72,13.63 158.72,15.45 158.55,15.63 157.64,15.63 157.35,15.92 157.35,16.4 157.64,16.69 158.59,16.69 158.72,16.82 158.72,19.69 158.59,19.83 157.41,19.83 157.12,20.12 157.12,20.6 157.41,20.89 158.6,20.89 158.73,21.02 158.73,21.29 158.6,21.43 157.41,21.43 157.12,21.72 157.12,22.2 157.41,22.49 158.6,22.49 158.73,22.62 158.73,22.89 158.6,23.03 157.41,23.03 157.12,23.32 157.12,23.8 157.41,24.09 158.44,24.09 158.73,24.38 158.73,25.86 149.77,34.82 148.82,34.82
DDR3_CPU_CH0_DQS_DN1: length 86.3
  TOP w0.102: v1(142.93,42.44) 142.96,42.44 U14.AR7
  TOP w0.157: P1.25 201.14,12.45 201.01,12.58 200.77,12.58 v1(200.49,12.3)
  L3_SIG w0.102: 152.1,44.67 152.07,44.67 152.04,44.7 148.68,44.7 147.37,43.38 147.37,42.95 147.27,42.85 146.85,42.85 146.63,42.63 143.12,42.63 v1(142.93,42.44)
  L3_SIG w0.135: 152.1,44.67 153.22,44.67 154.16,43.73 156.78,43.73 160.63,39.88 160.63,39.69 160.31,39.36 160.31,38.95 160.65,38.61 161.06,38.61 161.38,38.93 161.57,38.93 161.76,38.74 161.76,38.55 161.42,38.21 161.42,37.8 161.76,37.46 162.17,37.46 162.52,37.8 162.71,37.8 165.66,34.85 165.66,19.92 170.81,14.76 186.9,14.76 187.17,15.04 189,15.04 189.48,14.55 192.43,14.55 193.85,13.13 195.91,13.13 196.32,12.72 197.73,12.72 198.16,12.29 200.35,12.29 200.36,12.3 v1(200.49,12.3)
DDR3_CPU_CH0_DQS_DN2: length 86.3
  TOP w0.102: v1(141.79,44.43) 141.44,44.78 U14.AW11
  TOP w0.157: P1.43 201.14,17.85 200.99,18 200.77,18 v1(200.52,17.75)
  L3_SIG w0.102: 149,49.38 148.97,49.38 148.94,49.41 148.62,49.41 147.9,48.69 146.18,48.69 145.06,47.57 144.5,47.57 144.13,47.19 143.59,47.19 143.21,47.57 141.94,47.57 140.98,46.61 140.98,45.96 141.15,45.78 141.15,44.94 141.66,44.43 v1(141.79,44.43)
  L3_SIG w0.135: v1(200.52,17.75) 200.01,17.75 199.99,17.73 194.26,17.73 193.07,18.92 190.71,18.92 189.48,20.14 185.04,20.14 184.63,20.55 179.67,20.55 174.33,25.89 174.33,27.69 174.62,27.98 174.8,27.98 174.94,28.12 174.94,28.38 174.8,28.52 174.62,28.52 174.33,28.81 174.33,29.29 174.62,29.58 174.79,29.58 174.92,29.72 174.92,29.98 174.79,30.12 174.62,30.12 174.33,30.41 174.33,30.89 174.62,31.18 174.8,31.18 174.94,31.32 174.94,31.58 174.8,31.72 174.69,31.72 174.33,32.08 174.33,34.48 159.44,49.38 149,49.38
DDR3_CPU_CH0_DQS_DN3: length 81.4
  TOP w0.102: U14.AP1 146.32,42.32 146.73,42.32 146.94,42.11 147.14,42.11 147.35,42.32 147.67,42.32 147.78,42.21 147.78,42.01 147.87,41.92 148.06,41.92 148.18,42.04 148.18,42.27 148.23,42.32 148.7,42.32 148.82,42.21 148.82,41.78 148.95,41.66 149.37,41.66 151.43,39.6 153.28,39.6 153.49,39.39 155.7,39.39 155.75,39.33
  TOP w0.157: 155.75,39.33 164.58,39.33 165.68,38.23 165.68,37.44 165.53,37.28 164.59,37.28 164.26,36.96 164.26,36.41 164.59,36.08 165.53,36.08 165.68,35.92 165.68,35.61 165.53,35.45 164.59,35.45 164.26,35.13 164.26,34.58 164.59,34.25 165.53,34.25 165.68,34.1 165.68,33.78 165.53,33.62 164.59,33.62 164.26,33.3 164.26,32.75 164.59,32.42 165.53,32.42 165.68,32.27 165.68,31.95 165.53,31.79 164.59,31.79 164.26,31.47 164.26,30.92 164.59,30.6 165.53,30.6 165.68,30.44 165.68,30.12 165.53,29.97 164.59,29.97 164.26,29.64 164.26,29.09 164.59,28.77 165.53,28.77 165.68,28.61 165.68,28.29 165.53,28.14 164.59,28.14 164.26,27.81 164.26,27.26 164.59,26.94 165.53,26.94 165.68,26.78 165.68,26.27 165.53,26.12 164.78,26.12 164.46,25.79 164.46,25.24 164.78,24.92 165.49,24.92 165.68,24.72 165.68,23.75 166.68,22.75 184.9,22.75 185.06,22.91 189.59,22.91 189.92,23.24 192.05,23.24 192.21,23.08 192.82,23.08 192.94,22.95 P1.60
DDR3_CPU_CH0_DQS_DN4: length 89.3
  TOP w0.102: v1(132.73,47.15) 132.6,47.15 U14.BC29
  TOP w0.157: v1(200.09,49.35) 200.59,48.85 201.09,48.85 201.29,49.05 P1.139
  L3_SIG w0.102: 139.13,54.66 139.11,54.65 139.07,54.65 137.54,53.11 136.9,53.11 133.89,50.1 133.89,49.65 133.2,48.96 133.2,48.14 133.06,48 133.06,47.72 133.06,47.71 133.06,47.48 v1(132.73,47.15)
  L3_SIG w0.135: v1(200.09,49.35) 200.01,49.43 199.96,49.43 199.85,49.54 194.12,49.54 193.35,48.77 190.8,48.77 189.46,47.42 189.46,46.9 188.64,46.08 188.05,46.08 187.74,46.38 187.43,46.38 186.97,46.84 186.24,46.84 185.51,47.57 174.66,47.57 164.87,57.36 164.87,57.73 164.45,58.15 164.08,58.15 163.18,59.05 163.18,59.46 163.45,59.73 163.45,59.92 163.26,60.12 163.07,60.12 162.8,59.84 162.39,59.84 162.05,60.19 162.05,60.59 162.32,60.86 162.32,61.05 162.13,61.24 161.94,61.24 161.67,60.97 161.26,60.97 160.38,61.86 148.9,61.86 147.07,60.02 147.07,58.67 144.31,55.92 140.38,55.92 139.13,54.66
DDR3_CPU_CH0_DQS_DN5: length 82.9
  TOP w0.102: U14.BN17 138,51.97 138,52.56 139.55,54.11 139.55,56.6 141.6,58.65 141.6,59.27 141.65,59.31 141.65,59.33
  TOP w0.157: 141.65,59.33 141.65,59.93 142.23,60.52 142.43,60.52 142.6,60.35 142.77,60.35 142.98,60.55 142.98,60.73 142.85,60.86 142.85,61.14 143.12,61.4 143.45,61.4 143.64,61.59 143.64,61.92 143.92,62.2 144.42,62.2 144.6,62.03 145.36,62.03 145.54,62.2 161.34,62.2 162.89,60.65 162.89,58.74 163.21,58.42 164.66,58.42 164.82,58.26 164.82,57.95 164.66,57.79 163.21,57.79 162.89,57.46 162.89,56.91 163.21,56.59 164.66,56.59 164.85,56.4 164.85,56.15 164.66,55.96 163.21,55.96 162.89,55.64 162.89,55.09 163.21,54.76 164.66,54.76 164.86,54.56 164.86,54.33 164.66,54.13 163.21,54.13 162.89,53.81 162.89,53.09 163.44,52.55 191.08,52.55 192.24,53.71 192.79,53.71 192.94,53.55 P1.154
DDR3_CPU_CH0_DQS_DN6: length 91.1
  TOP w0.102: U14.BL26 133.69,51.16 133.75,51.24 133.93,51.42 133.93,53.73 133.88,53.78 133.88,55.42 133.53,55.78 133.53,56.2 136.63,59.3 136.63,60.07 135.99,60.7 135.99,61.11 v1(136.3,61.41)
  TOP w0.157: v1(200.42,58.56) 200.53,58.67 202.3,58.67 P1.171
  L3_SIG w0.135: v1(136.3,61.41) 136.02,61.69 136.02,63.84 141.29,69.11 167.62,69.11 168.19,68.54 168.71,68.54 168.94,68.31 168.94,67.79 169.32,67.41 169.84,67.41 170.07,67.18 170.07,66.66 170.45,66.28 171.01,66.28 171.2,66.09 171.2,65.53 171.58,65.14 172.2,65.14 172.33,65.01 172.33,64.4 172.72,64.01 173.33,64.01 173.46,63.88 173.46,63.26 173.85,62.88 174.46,62.88 174.6,62.74 174.6,62.13 175.31,61.41 175.75,61.41 176.06,61.1 176.06,60.66 178.64,58.09 193.5,58.09 194.41,59.01 197.36,59.01 197.47,59.12 199.84,59.12 199.85,59.11 199.87,59.11 v1(200.42,58.56)
DDR3_CPU_CH0_DQS_DN7: length 92.1
  TOP w0.102: 133.3,61.93 133.3,61.93 133.3,60.35 130.07,57.11 130.07,52.54 130.15,52.46 130.15,52.14 129.91,51.9 U14.BM34
  TOP w0.157: P1.186 194.05,63.08 175.07,63.08 174.75,63.4 174.75,64.81 174.59,64.97 172.36,64.97 172.03,65.29 172.03,65.84 172.36,66.17 174.59,66.17 174.75,66.32 174.75,66.64 174.59,66.8 172.36,66.8 172.03,67.12 172.03,67.67 172.36,67.99 174.59,67.99 174.75,68.15 174.75,68.44 174.35,68.83 138.04,68.83 133.29,64.08 133.29,61.94 133.3,61.93
DDR3_CPU_CH0_DQS_DN8: length 82.4
  TOP w0.102: 155.75,45.78 155.69,45.78 155.65,45.82 155.08,45.82 154.76,46.15 150.09,46.15 149.99,46.06 145.16,46.06 144.95,46.27 U14.BB4
  TOP w0.157: P1.75 201.14,29.85 200.99,30.01 198.56,30.01 196.97,28.43 186.03,28.43 184.97,29.48 184.16,29.48 183.95,29.69 183.49,29.69 183.28,29.48 182.43,29.48 182.1,29.81 182.1,30.5 181.94,30.65 181.63,30.65 181.47,30.5 181.47,29.81 181.15,29.48 180.6,29.48 180.27,29.81 180.27,30.5 180.12,30.65 179.8,30.65 179.64,30.5 179.64,29.81 179.32,29.48 178.6,29.48 178.28,29.81 178.28,37.59 178.12,37.75 177.84,37.75 177.52,38.07 177.52,38.62 177.84,38.95 178.12,38.95 178.28,39.1 178.28,39.42 178.12,39.58 177.84,39.58 177.52,39.9 177.52,40.45 177.84,40.77 178.12,40.77 178.28,40.93 178.28,41.25 178.12,41.4 177.84,41.4 177.52,41.73 177.52,42.28 177.84,42.6 178.12,42.6 178.28,42.76 178.28,43.08 178.12,43.23 177.84,43.23 177.52,43.56 177.52,44.11 177.84,44.43 178.12,44.43 178.28,44.59 178.28,45.52 178.01,45.78 155.75,45.78
DDR3_CPU_CH0_DQS_DP0: length 87
  TOP w0.102: U14.AL11 141.82,40.4 v1(141.85,40.4)
  TOP w0.157: v1(192.15,8.38) 192.3,8.38 192.47,8.55 P1.12
  L3_SIG w0.102: 148.82,35.08 148.79,35.08 148.76,35.05 147.19,35.05 145.26,36.99 145.26,38.48 143.95,39.79 141.81,39.79 141.55,40.04 141.55,40.21 141.74,40.4 v1(141.85,40.4)
  L3_SIG w0.135: v1(192.15,8.38) 192.15,8.11 191.97,7.93 189.83,7.93 189.08,7.18 183.97,7.18 182.68,8.47 178.75,8.47 178.03,7.75 176.4,7.75 175.68,8.47 164.25,8.47 158.99,13.73 158.99,15.56 158.66,15.89 157.75,15.89 157.61,16.02 157.61,16.29 157.75,16.43 158.7,16.43 158.99,16.72 158.99,19.8 158.7,20.09 157.52,20.09 157.39,20.22 157.39,20.49 157.52,20.63 158.71,20.63 158.99,20.92 158.99,21.4 158.71,21.69 157.52,21.69 157.39,21.82 157.39,22.09 157.52,22.23 158.71,22.23 158.99,22.52 158.99,23 158.71,23.29 157.52,23.29 157.39,23.42 157.39,23.69 157.52,23.83 158.55,23.83 158.99,24.27 158.99,25.96 149.88,35.08 148.82,35.08
DDR3_CPU_CH0_DQS_DP1: length 86.3
  TOP w0.102: U14.AT7 142.96,43.14 v1(142.93,43.14)
  TOP w0.157: v1(200.49,13.15) 200.77,12.87 200.96,12.87 201.14,13.05 P1.27
  L3_SIG w0.102: 152.1,44.93 152.07,44.93 152.04,44.9 148.6,44.9 146.76,43.06 146.76,43.05 146.55,42.84 143.24,42.84 v1(142.93,43.14)
  L3_SIG w0.135: v1(200.49,13.15) 200.42,13.15 199.82,12.55 198.27,12.55 197.84,12.98 196.43,12.98 196.02,13.39 193.96,13.39 192.54,14.82 189.59,14.82 189.11,15.3 187.06,15.3 186.79,15.02 170.92,15.02 168.78,17.17 165.92,20.02 165.92,34.96 162.81,38.06 162.41,38.06 162.06,37.72 161.87,37.72 161.68,37.91 161.68,38.1 162.03,38.44 162.03,38.85 161.68,39.2 161.27,39.2 160.95,38.87 160.76,38.87 160.57,39.06 160.57,39.25 160.89,39.58 160.89,39.98 156.89,43.99 154.27,43.99 153.33,44.93 152.1,44.93
DDR3_CPU_CH0_DQS_DP2: length 86.3
  TOP w0.102: U14.AW12 140.99,44.43 v1(141.01,44.43)
  TOP w0.157: P1.45 201.14,18.45 200.98,18.29 200.83,18.29 v1(200.52,18.6)
  L3_SIG w0.102: 149,49.64 148.97,49.64 148.94,49.61 148.53,49.61 147.82,48.9 146.1,48.9 144.97,47.77 141.86,47.77 140.78,46.69 140.78,45.87 140.95,45.7 140.95,44.49 v1(141.01,44.43)
  L3_SIG w0.135: 149,49.64 159.55,49.64 174.6,34.59 174.6,32.19 174.8,31.98 174.91,31.98 175.2,31.69 175.2,31.21 174.91,30.92 174.73,30.92 174.6,30.78 174.6,30.52 174.73,30.38 174.9,30.38 175.18,30.09 175.18,29.61 174.9,29.32 174.73,29.32 174.6,29.18 174.6,28.92 174.73,28.78 174.91,28.78 175.2,28.49 175.2,28.01 174.91,27.72 174.73,27.72 174.6,27.58 174.6,26 179.78,20.82 184.74,20.82 185.15,20.4 189.59,20.4 190.82,19.18 193.18,19.18 194.37,17.99 199.88,17.99 200.5,18.6 v1(200.52,18.6)
DDR3_CPU_CH0_DQS_DP3: length 81.4
  TOP w0.102: 155.75,39.62 155.74,39.62 155.71,39.59 153.58,39.59 153.37,39.8 151.51,39.8 148.79,42.52 145.28,42.52 U14.AP3
  TOP w0.157: 155.75,39.62 164.7,39.62 165.97,38.34 165.97,37.32 165.64,37 164.7,37 164.55,36.84 164.55,36.52 164.7,36.37 165.64,36.37 165.97,36.04 165.97,35.49 165.64,35.17 164.7,35.17 164.55,35.01 164.55,34.7 164.7,34.54 165.64,34.54 165.97,34.21 165.97,33.66 165.64,33.34 164.7,33.34 164.55,33.18 164.55,32.87 164.7,32.71 165.64,32.71 165.97,32.38 165.97,31.83 165.64,31.51 164.7,31.51 164.55,31.35 164.55,31.04 164.7,30.88 165.64,30.88 165.97,30.56 165.97,30.01 165.64,29.68 164.7,29.68 164.55,29.52 164.55,29.21 164.7,29.05 165.64,29.05 165.97,28.73 165.97,28.18 165.64,27.85 164.7,27.85 164.55,27.7 164.55,27.38 164.7,27.22 165.64,27.22 165.97,26.9 165.97,26.16 165.64,25.83 164.9,25.83 164.74,25.67 164.74,25.36 164.9,25.2 165.6,25.2 165.97,24.84 165.97,23.87 166.8,23.03 184.78,23.03 184.94,23.2 189.47,23.2 189.8,23.53 192.17,23.53 192.33,23.36 192.76,23.36 192.94,23.55 P1.62
DDR3_CPU_CH0_DQS_DP4: length 89.3
  TOP w0.102: v1(132.61,47.85) 132.61,47.75 132.36,47.49 U14.BD29
  TOP w0.157: v1(200.85,49.35) 201.15,49.65 P1.141
  L3_SIG w0.102: 138.95,54.85 138.93,54.83 138.93,54.79 137.45,53.32 136.82,53.32 133.68,50.18 133.68,49.74 133,49.05 133,48.23 v1(132.61,47.85)
  L3_SIG w0.135: v1(200.85,49.35) 200.72,49.35 200.28,49.8 194.01,49.8 193.24,49.03 190.7,49.03 189.2,47.53 189.2,47.01 188.53,46.34 188.16,46.34 187.85,46.64 187.54,46.64 187.07,47.1 186.35,47.1 185.62,47.84 174.77,47.84 165.13,57.47 165.13,57.84 164.56,58.41 164.19,58.41 163.44,59.16 163.44,59.35 163.72,59.63 163.72,60.03 163.37,60.38 162.96,60.38 162.69,60.1 162.5,60.1 162.31,60.3 162.31,60.49 162.58,60.75 162.58,61.16 162.23,61.5 161.83,61.5 161.56,61.24 161.37,61.24 160.49,62.12 148.79,62.12 146.8,60.13 146.8,58.78 145.16,57.14 144.75,57.14 144.51,56.9 144.51,56.49 144.2,56.18 142.22,56.18 141.93,56.46 141.53,56.46 141.25,56.18 140.27,56.18 138.95,54.85
DDR3_CPU_CH0_DQS_DP5: length 83
  TOP w0.102: U14.BM18 137.8,51.41 137.8,52.64 139.35,54.19 139.35,56.68 141.4,58.74 141.4,59.27 141.36,59.31 141.36,59.33
  TOP w0.157: P1.156 192.94,54.15 192.79,53.99 192.13,53.99 190.96,52.83 163.55,52.83 163.17,53.21 163.17,53.69 163.33,53.85 164.78,53.85 165.15,54.22 165.15,54.68 164.78,55.05 163.33,55.05 163.17,55.2 163.17,55.52 163.33,55.68 164.78,55.68 165.13,56.03 165.13,56.52 164.78,56.87 163.33,56.87 163.17,57.03 163.17,57.35 163.33,57.5 164.78,57.5 165.1,57.83 165.1,58.38 164.78,58.7 163.33,58.7 163.17,58.86 163.17,60.77 161.46,62.49 143.8,62.49 141.36,60.05 141.36,59.33
DDR3_CPU_CH0_DQS_DP6: length 91.1
  TOP w0.102: v1(135.48,61.41) 135.79,61.11 135.79,60.62 136.42,59.99 136.42,59.39 133.91,56.87 133.45,56.87 133.32,56.74 133.32,55.69 133.68,55.34 133.68,55.14 133.51,54.97 133.51,54.83 133.68,54.66 133.68,54.51 133.47,54.3 133.47,54.16 133.68,53.95 133.68,53.7 133.73,53.65 133.73,52.96 133.65,52.88 133.65,52.45 133.73,52.37 133.73,51.98 U14.BN26
  TOP w0.157: P1.173 201.39,59.25 201.19,59.05 200.57,59.05 v1(200.11,59.52)
  L3_SIG w0.135: v1(200.11,59.52) 199.88,59.52 199.74,59.38 197.36,59.38 197.25,59.27 194.3,59.27 193.39,58.35 178.75,58.35 176.33,60.77 176.33,61.21 175.86,61.68 175.42,61.68 174.86,62.24 174.86,62.85 174.57,63.14 173.96,63.14 173.73,63.37 173.73,63.99 173.44,64.27 172.82,64.27 172.59,64.5 172.59,65.12 172.31,65.41 171.69,65.41 171.46,65.64 171.46,66.19 171.12,66.54 170.56,66.54 170.33,66.77 170.33,67.29 169.95,67.67 169.43,67.67 169.2,67.9 169.2,68.42 168.81,68.8 168.3,68.8 167.73,69.37 141.18,69.37 135.76,63.94 135.76,61.69 v1(135.48,61.41)
DDR3_CPU_CH0_DQS_DP7: length 92.1
  TOP w0.102: U14.BP34 129.86,53.72 129.69,53.89 129.69,54.18 129.86,54.35 129.86,54.66 129.69,54.83 129.69,55.14 129.86,55.31 129.86,55.8 129.69,55.97 129.69,56.13 129.86,56.3 129.86,57.2 133.1,60.43 133.1,61.73 133.01,61.82 133.01,61.93
  TOP w0.157: P1.188 192.94,63.75 192.56,63.37 175.19,63.37 175.03,63.52 175.03,64.93 174.71,65.25 172.48,65.25 172.32,65.41 172.32,65.72 172.48,65.88 174.71,65.88 175.03,66.21 175.03,66.76 174.71,67.08 172.48,67.08 172.32,67.24 172.32,67.55 172.48,67.71 174.71,67.71 175.03,68.03 175.03,68.55 174.47,69.11 137.92,69.11 133.01,64.2 133.01,61.93
DDR3_CPU_CH0_DQS_DP8: length 82.4
  TOP w0.102: U14.BB2 145.72,46.26 148.06,46.26 148.19,46.38 148.19,46.49 148.29,46.58 148.44,46.58 148.56,46.46 148.56,46.31 148.62,46.26 148.95,46.26 149.05,46.35 149.05,46.46 149.15,46.57 149.3,46.57 149.4,46.46 149.4,46.31 149.45,46.26 149.91,46.26 150,46.35 154.84,46.35 155.17,46.02 155.65,46.02 155.69,46.06 155.75,46.06
  TOP w0.157: 155.75,46.06 178.13,46.06 178.56,45.63 178.56,44.47 178.24,44.15 177.96,44.15 177.81,43.99 177.81,43.68 177.96,43.52 178.24,43.52 178.56,43.19 178.56,42.64 178.24,42.32 177.96,42.32 177.81,42.16 177.81,41.85 177.96,41.69 178.24,41.69 178.56,41.36 178.56,40.81 178.24,40.49 177.96,40.49 177.81,40.33 177.81,40.02 177.96,39.86 178.24,39.86 178.56,39.54 178.56,38.99 178.24,38.66 177.96,38.66 177.81,38.5 177.81,38.19 177.96,38.03 178.24,38.03 178.56,37.71 178.56,29.93 178.72,29.77 179.2,29.77 179.36,29.93 179.36,30.61 179.68,30.94 180.23,30.94 180.56,30.61 180.56,29.93 180.72,29.77 181.03,29.77 181.19,29.93 181.19,30.61 181.51,30.94 182.06,30.94 182.39,30.61 182.39,29.93 182.54,29.77 183.17,29.77 183.37,29.98 184.07,29.98 184.28,29.77 185.09,29.77 186.14,28.71 196.86,28.71 198.44,30.29 200.99,30.29 201.14,30.45 P1.77
DDR3_CPU_CH0_ECC0: length 81.5
  TOP w0.102: 155.4,44.5 154.56,44.5 153.82,45.24 148.72,45.24 148.56,45.39 146.03,45.39 145.76,45.12 145.4,45.12 145.07,45.45 U14.AY4
  TOP w0.157: 155.4,44.5 175.42,44.5 175.77,44.15 175.77,43.34 175.61,43.18 175.01,43.18 174.85,43.02 174.85,42.71 175.01,42.55 175.61,42.55 175.77,42.39 175.77,42.08 175.61,41.92 175.01,41.92 174.85,41.76 174.85,41.45 175.01,41.29 175.61,41.29 175.77,41.13 175.77,40.82 175.61,40.66 175.01,40.66 174.85,40.5 174.85,40.19 175.01,40.03 175.61,40.03 175.77,39.87 175.77,39.56 175.61,39.4 175.01,39.4 174.85,39.24 174.85,38.93 175.01,38.77 176.07,38.77 176.23,38.61 176.23,28.45 176.47,28.2 184.36,28.2 184.92,27.64 190.21,27.64 190.6,27.25 200.46,27.25 200.79,26.92 200.79,25.91 201.04,25.65 P1.69
DDR3_CPU_CH0_ECC1: length 81.5
  TOP w0.102: 156.6,45.14 154.74,45.14 154.44,45.44 148.9,45.44 148.75,45.59 145.9,45.59 145.75,45.45 U14.AY2
  TOP w0.157: 156.6,45.14 176.72,45.14 176.88,44.98 176.88,44.04 176.5,43.66 176.5,43.3 176.87,42.94 176.87,42.71 176.5,42.35 176.5,42.04 176.87,41.68 176.87,41.45 176.5,41.09 176.5,40.78 176.87,40.42 176.87,40.19 176.41,39.74 176.41,39.45 176.88,38.98 176.88,37.81 176.89,37.8 176.89,36.93 177.04,36.78 177.48,36.78 177.64,36.62 177.64,36.3 177.48,36.15 177.04,36.15 176.89,35.99 176.89,35.68 177.04,35.52 177.48,35.52 177.64,35.36 177.64,35.05 177.48,34.89 177.04,34.89 176.89,34.73 176.89,34.42 177.04,34.26 177.48,34.26 177.64,34.1 177.64,33.79 177.48,33.63 177.04,33.63 176.89,33.47 176.89,33.16 177.04,33 177.48,33 177.64,32.84 177.64,32.53 177.48,32.37 177.04,32.37 176.89,32.21 176.89,31.9 177.04,31.74 177.48,31.74 177.64,31.58 177.64,31.27 177.48,31.11 177.04,31.11 176.89,30.95 176.89,29 177.04,28.84 184.69,28.84 185.53,28.01 190.58,28.01 190.84,27.76 201.48,27.76 202.32,26.91 P1.71
DDR3_CPU_CH0_ECC2: length 81.5
  TOP w0.102: 156.66,48.98 155,48.98 154.76,48.74 148.43,48.74 147.19,47.5 145.78,47.5 U14.BD2
  TOP w0.157: v1(192.28,32.38) 186.82,32.38 183.96,35.24 183.96,42.79 184.16,43 185.67,43 185.83,43.16 185.83,43.47 185.67,43.63 184.11,43.63 183.96,43.79 183.96,44.05 184.16,44.26 185.67,44.26 185.83,44.42 185.83,44.73 185.67,44.89 184.11,44.89 183.96,45.05 183.96,45.31 184.16,45.52 185.67,45.52 185.83,45.68 185.83,45.99 185.67,46.15 184.11,46.15 183.96,46.31 183.96,46.7 182.03,48.62 157.01,48.62 156.66,48.98 ; v1(199.82,31.65) P1.81
  L3_SIG w0.135: v1(192.28,32.38) 192.48,32.59 199.21,32.59 199.82,31.98 v1(199.82,31.65)
DDR3_CPU_CH0_ECC3: length 81.4
  TOP w0.102: 154.94,48.26 148.47,48.26 147.45,47.24 145.95,47.24 145.84,47.13 145.84,47.13 145.83,47.13 145.53,47.13 145.16,47.49 U14.BD4
  TOP w0.157: v1(191.66,31.79) 186.35,31.79 182.75,35.38 182.75,35.85 182.91,36 183.14,36 183.29,36.15 183.29,36.32 183.13,36.48 182.81,36.48 182.65,36.64 182.65,36.95 182.81,37.11 183.16,37.11 183.32,37.27 183.32,37.58 183.16,37.74 182.81,37.74 182.65,37.9 182.65,38.21 182.81,38.37 183.16,38.37 183.32,38.53 183.32,38.84 183.16,39 182.81,39 182.65,39.16 182.65,39.47 182.81,39.63 183.16,39.63 183.32,39.79 183.32,40.1 183.16,40.26 182.81,40.26 182.65,40.42 182.65,40.73 182.81,40.89 183.16,40.89 183.32,41.05 183.32,41.36 183.16,41.52 182.81,41.52 182.65,41.68 182.65,41.99 182.81,42.15 183.16,42.15 183.32,42.31 183.32,42.62 183.16,42.78 182.81,42.78 182.65,42.94 182.65,43.25 182.81,43.41 183.16,43.41 183.32,43.57 183.32,43.88 183.16,44.04 182.81,44.04 182.65,44.2 182.65,44.51 182.81,44.67 183.16,44.67 183.32,44.83 183.32,45.14 183.16,45.3 182.81,45.3 182.65,45.46 182.65,45.77 182.81,45.93 183.16,45.93 183.32,46.09 183.32,46.43 181.76,47.98 156.46,47.98 156.13,48.32 155.95,48.32 155.95,48.32 155,48.32 154.94,48.26 ; v1(200.84,32.36) 200.95,32.25 P1.83
  L3_SIG w0.135: v1(200.84,32.36) 200.84,31.85 199.85,30.86 193.95,30.86 193.19,31.62 191.82,31.62 v1(191.66,31.79)
DDR3_CPU_CH0_ECC4: length 81.5
  TOP w0.102: 155.68,43.22 154.6,43.22 153,44.81 145.24,44.81 U14.AW3
  TOP w0.157: 155.68,43.22 172.78,43.22 173.51,42.49 173.51,41.96 173.35,41.81 172.75,41.81 172.59,41.65 172.59,41.33 172.75,41.18 173.35,41.18 173.51,41.02 173.51,40.7 173.35,40.55 172.75,40.55 172.59,40.39 172.59,40.07 172.75,39.92 173.35,39.92 173.51,39.76 173.51,39.44 173.35,39.29 172.75,39.29 172.59,39.13 172.59,38.81 172.75,38.66 173.35,38.66 173.51,38.5 173.51,38.18 173.35,38.03 172.75,38.03 172.59,37.87 172.59,37.55 172.75,37.4 173.35,37.4 173.51,37.24 173.51,36.92 173.35,36.77 172.75,36.77 172.59,36.61 172.59,36.3 172.75,36.14 173.35,36.14 173.51,35.98 173.51,35.67 173.35,35.51 172.75,35.51 172.59,35.35 172.59,35.04 172.75,34.88 173.35,34.88 173.51,34.72 173.51,34.41 173.35,34.25 172.75,34.25 172.59,34.09 172.59,33.78 172.75,33.62 173.35,33.62 173.51,33.46 173.51,33.15 173.35,32.99 172.75,32.99 172.59,32.83 172.59,32.52 172.75,32.36 173.35,32.36 173.51,32.2 173.51,31.89 173.35,31.73 172.75,31.73 172.59,31.57 172.59,31.26 172.75,31.1 173.35,31.1 173.51,30.94 173.51,30.63 173.35,30.47 172.75,30.47 172.59,30.31 172.59,30 172.75,29.84 173.35,29.84 173.51,29.68 173.51,29.37 173.35,29.21 172.83,29.21 172.67,29.05 172.67,28.74 172.83,28.58 173.35,28.58 173.51,28.42 173.51,27.2 173.78,26.92 183.64,26.92 184.2,26.36 189.12,26.36 189.31,26.55 P1.72
DDR3_CPU_CH0_ECC5: length 81.4
  TOP w0.102: U14.AY1 148.57,45.1 148.63,45.03 153.47,45.03 154.64,43.86 157.32,43.86
  TOP w0.157: P1.74 192.9,29.55 v1(192.62,29.83) ; 157.32,43.86 173.49,43.86 174.19,43.15 174.19,38.04 174.35,37.88 175.28,37.88 175.44,37.72 175.44,37.41 175.28,37.25 174.35,37.25 174.19,37.09 174.19,36.78 174.35,36.62 175.28,36.62 175.44,36.46 175.44,36.15 175.28,35.99 174.35,35.99 174.19,35.83 174.19,35.52 174.35,35.36 175.28,35.36 175.44,35.2 175.44,34.89 175.28,34.73 174.35,34.73 174.19,34.57 174.19,34.26 174.35,34.1 175.28,34.1 175.44,33.94 175.44,33.63 175.28,33.47 174.35,33.47 174.19,33.31 174.19,33 174.35,32.84 175.28,32.84 175.44,32.68 175.44,32.37 175.28,32.21 174.35,32.21 174.19,32.05 174.19,31.74 174.35,31.58 175.28,31.58 175.44,31.42 175.44,31.11 175.28,30.95 174.35,30.95 174.19,30.79 174.19,30.4 174.35,30.24 174.77,30.24 174.92,30.08 174.92,29.77 174.77,29.61 174.35,29.61 174.19,29.45 174.19,29.14 174.35,28.98 174.77,28.98 174.95,28.8 174.95,28.53 174.77,28.35 174.35,28.35 174.19,28.19 174.19,27.82 174.44,27.56 183.97,27.56 184.4,27.13 v1(189.1,27.13)
  L3_SIG w0.135: v1(189.1,27.13) 189.1,28.74 190.11,29.76 191.7,29.76 191.77,29.83 v1(192.62,29.83)
DDR3_CPU_CH0_ECC6: length 81.5
  TOP w0.102: 156.13,46.7 155.88,46.7 155.45,47.13 148.09,47.13 147.69,46.72 U14.BC1
  TOP w0.157: 156.13,46.7 179.86,46.7 180.26,46.3 180.26,45.84 180.11,45.68 179.48,45.68 179.32,45.53 179.32,45.21 179.48,45.05 180.11,45.05 180.26,44.9 180.26,44.58 180.11,44.42 179.48,44.42 179.32,44.27 179.32,43.95 179.48,43.79 180.11,43.79 180.26,43.64 180.26,43.32 180.11,43.16 179.48,43.16 179.32,43.01 179.32,42.69 179.48,42.53 180.11,42.53 180.26,42.38 180.26,42.06 180.11,41.9 179.48,41.9 179.32,41.75 179.32,41.43 179.48,41.27 180.11,41.27 180.26,41.12 180.26,40.8 180.11,40.64 179.48,40.64 179.32,40.49 179.32,40.17 179.48,40.01 180.11,40.01 180.26,39.86 180.26,39.54 180.11,39.38 179.48,39.38 179.32,39.23 179.32,38.91 179.48,38.75 180.11,38.75 180.26,38.6 180.26,38.28 180.11,38.12 179.48,38.12 179.32,37.97 179.32,37.65 179.48,37.49 180.11,37.49 180.26,37.34 180.26,37.02 180.11,36.86 179.48,36.86 179.32,36.71 179.32,36.39 179.48,36.23 180.11,36.23 180.26,36.08 180.26,35.76 180.11,35.6 179.48,35.6 179.32,35.45 179.32,35.13 179.48,34.97 180.11,34.97 180.26,34.82 180.26,34.5 180.11,34.34 179.48,34.34 179.32,34.19 179.32,33.87 179.48,33.71 180.11,33.71 180.26,33.56 180.26,33.24 180.11,33.08 179.56,33.08 179.4,32.93 179.4,32.61 179.56,32.45 180.11,32.45 180.26,32.3 180.26,31.76 180.42,31.6 182.91,31.6 183.34,31.17 183.6,31.17 184.02,31.6 184.33,31.6 186.47,29.46 191.11,29.46 193.01,31.35 P1.80
DDR3_CPU_CH0_ECC7: length 81.4
  TOP w0.102: 156.21,47.34 156.11,47.34 155.74,47.71 155.01,47.71 154.97,47.67 148.25,47.67 147.61,47.02 146.04,47.02 145.91,46.9 145.26,46.9 U14.BC3
  TOP w0.157: 156.21,47.34 181.36,47.34 181.84,46.86 181.84,46.5 181.68,46.35 181.21,46.35 181.05,46.19 181.05,45.87 181.21,45.72 181.68,45.72 181.84,45.56 181.84,45.24 181.68,45.09 181.21,45.09 181.05,44.93 181.05,44.61 181.21,44.46 181.68,44.46 181.84,44.3 181.84,43.98 181.68,43.83 181.21,43.83 181.05,43.67 181.05,43.35 181.21,43.2 181.68,43.2 181.84,43.04 181.84,42.72 181.68,42.57 181.21,42.57 181.05,42.41 181.05,42.09 181.21,41.94 181.68,41.94 181.84,41.78 181.84,41.46 181.68,41.31 181.21,41.31 181.05,41.15 181.05,40.83 181.21,40.68 181.68,40.68 181.84,40.52 181.84,40.2 181.68,40.05 181.21,40.05 181.05,39.89 181.05,39.57 181.21,39.42 181.68,39.42 181.84,39.26 181.84,38.94 181.68,38.79 181.21,38.79 181.05,38.63 181.05,38.31 181.21,38.16 181.68,38.16 181.84,38 181.84,37.68 181.68,37.53 181.21,37.53 181.05,37.37 181.05,37.05 181.21,36.9 181.68,36.9 181.84,36.74 181.84,36.42 181.68,36.27 181.21,36.27 181.05,36.11 181.05,35.79 181.21,35.64 181.68,35.64 181.84,35.48 181.84,35.16 181.68,35.01 181.21,35.01 181.05,34.85 181.05,34.53 181.21,34.38 181.68,34.38 181.84,34.22 181.84,33.9 181.68,33.75 181.21,33.75 181.05,33.59 181.05,33.27 181.21,33.12 181.68,33.12 181.84,32.96 181.84,32.42 182,32.26 182.55,32.26 182.71,32.42 182.71,33.43 182.87,33.59 183.18,33.59 183.34,33.43 183.34,32.42 183.5,32.26 184.61,32.26 186.86,30.01 191.08,30.01 193.02,31.95 P1.82
DDR3_CPU_CH0_MA0: length 109.8
  TOP w0.152: U14.BH11 141.41,49.42 v1(141.03,49.81)
  TOP w0.157: v1(200.85,39.15) 201.15,39.45 P1.107
  L5_SIG w0.102: 148.69,57.53 148.69,57.33 145.23,53.87 144.22,53.87 142.56,52.2 141.98,52.2 141.51,51.73 141.51,50.37 141.03,49.89 v1(141.03,49.81)
  L5_SIG w0.191: v1(200.85,39.15) 200.85,39.24 200.34,39.75 198.26,39.75 197.38,38.88 194.33,38.88 193.22,37.78 190.51,37.78 190.12,37.39 171.06,37.39 170.3,38.16 170.03,38.16 169.81,37.95 169.54,37.95 169.27,38.22 169.27,38.49 169.49,38.7 169.49,38.97 169.22,39.24 168.95,39.24 168.74,39.03 168.47,39.03 168.2,39.3 168.2,39.57 168.41,39.78 168.41,40.05 168.12,40.34 168.12,59.72 167.79,60.05 166.52,60.05 166.33,59.86 166.33,59.02 166.14,58.83 165.75,58.83 165.56,59.02 165.56,59.86 165.37,60.05 164.99,60.05 164.8,59.86 164.8,59.02 164.61,58.83 164.23,58.83 164.04,59.02 164.04,59.86 163.85,60.05 163.47,60.05 163.28,59.86 163.28,59.02 163.09,58.83 162.71,58.83 162.52,59.02 162.52,59.86 162.33,60.05 161.94,60.05 161.75,59.86 161.75,59.02 161.56,58.83 161.18,58.83 160.99,59.02 160.99,59.86 160.8,60.05 160.42,60.05 160.23,59.86 160.23,59.02 160.04,58.83 159.66,58.83 159.47,59.02 159.47,59.86 159.28,60.05 158.9,60.05 158.71,59.86 158.71,59.02 158.52,58.83 158.13,58.83 157.94,59.02 157.94,59.86 157.75,60.05 157.37,60.05 157.18,59.86 157.18,59.02 156.99,58.83 156.61,58.83 156.42,59.02 156.42,59.86 156.23,60.05 155.85,60.05 155.66,59.86 155.66,59.02 155.47,58.83 155.09,58.83 154.9,59.02 154.9,59.86 154.71,60.05 154.32,60.05 154.13,59.86 154.13,59.02 153.94,58.83 153.56,58.83 153.37,59.02 153.37,59.86 153.18,60.05 149.78,60.05 148.69,58.95 148.69,57.53
DDR3_CPU_CH0_MA1: length 108.7
  TOP w0.102: v1(147.96,52.96) 147.75,52.96 146.94,53.77 145.39,53.77 144.81,53.19 144.81,51.2 144.6,50.99 144.3,50.99 144.12,51.18 143.63,51.18 143.37,50.93 142.82,50.93 U14.BL8
  TOP w0.157: P1.105 201.2,38.85 201.04,38.69 200.55,38.69 v1(200.09,39.15)
  L5_SIG w0.191: v1(147.96,52.96) 147.96,53.33 148.47,53.85 165.05,53.85 165.51,53.39 165.51,29.97 166.37,29.11 166.92,29.11 167.11,29.3 167.11,30.29 167.3,30.48 167.68,30.48 167.87,30.29 167.87,29.3 168.06,29.11 168.44,29.11 168.63,29.3 168.63,30.29 168.82,30.48 169.2,30.48 169.39,30.29 169.39,29.3 169.58,29.11 169.96,29.11 170.15,29.3 170.15,30.29 170.34,30.48 170.73,30.48 170.92,30.29 170.92,29.3 171.11,29.11 171.49,29.11 171.68,29.3 171.68,30.29 171.87,30.48 172.25,30.48 172.44,30.29 172.44,29.3 172.63,29.11 173.01,29.11 173.2,29.3 173.2,30.29 173.39,30.48 173.77,30.48 173.96,30.29 173.96,29.3 174.15,29.11 174.54,29.11 174.73,29.3 174.73,30.29 174.92,30.48 175.3,30.48 175.49,30.29 175.49,29.3 175.68,29.11 176.06,29.11 176.25,29.3 176.25,30.29 176.44,30.48 176.82,30.48 177.01,30.29 177.01,29.35 177.2,29.16 177.58,29.16 177.77,29.35 177.77,30.29 177.96,30.48 178.89,30.48 179.09,30.28 179.65,30.28 179.85,30.48 183.46,30.48 185.52,32.53 188.72,32.53 191.47,35.29 192.87,35.29 193.06,35.48 193.06,36.33 194.37,37.64 196.91,37.64 198.42,39.15 v1(200.09,39.15)
DDR3_CPU_CH0_MA2: length 109.2
  TOP w0.157: U14.BG13 139.91,49.24 139.91,49.47 v1(139.9,49.47) ; v1(192.66,39.46) 192.97,39.15 P1.106
  L5_SIG w0.102: v1(139.9,49.47) 139.9,51.17 140.16,51.42 140.49,51.42 141.23,52.16 141.23,52.28 142.32,53.38 142.9,53.38 147.4,57.88 147.4,57.96
  L5_SIG w0.191: v1(192.66,39.46) 192.17,38.98 188.76,38.98 188.46,39.28 188.08,39.28 187.69,39.67 185.58,39.67 185.39,39.48 185.39,38.73 185.2,38.54 184.82,38.54 184.63,38.73 184.63,39.48 184.44,39.67 184.06,39.67 183.87,39.48 183.87,38.73 183.68,38.54 183.29,38.54 183.1,38.73 183.1,39.48 182.91,39.67 182.53,39.67 182.34,39.48 182.34,38.73 182.15,38.54 181.77,38.54 181.58,38.73 181.58,39.48 181.39,39.67 181.01,39.67 180.82,39.48 180.82,38.75 180.63,38.56 180.25,38.56 180.06,38.75 180.06,39.48 179.87,39.67 179.48,39.67 179.29,39.48 179.29,38.82 179.1,38.63 178.72,38.63 178.53,38.82 178.53,39.48 178.34,39.67 177.96,39.67 177.77,39.48 177.77,38.8 177.58,38.61 177.2,38.61 177.01,38.8 177.01,39.48 176.82,39.67 176.44,39.67 176.25,39.48 176.25,38.82 176.06,38.63 175.67,38.63 175.48,38.82 175.48,39.48 175.29,39.67 174.91,39.67 174.72,39.48 174.72,38.82 174.53,38.63 174.15,38.63 173.96,38.82 173.96,39.48 173.77,39.67 173.39,39.67 173.2,39.48 173.2,38.82 173.01,38.63 172.63,38.63 172.44,38.82 172.44,39.43 171.75,40.12 171.75,40.39 172.09,40.73 172.09,41 171.82,41.27 171.55,41.27 171.21,40.93 170.94,40.93 170.38,41.49 170.38,41.87 170.57,42.06 170.79,42.06 170.98,42.25 170.98,42.63 170.79,42.82 170.57,42.82 170.38,43.01 170.38,43.39 170.57,43.58 170.79,43.58 170.98,43.77 170.98,44.15 170.79,44.34 170.57,44.34 170.38,44.53 170.38,44.91 170.57,45.11 170.79,45.11 170.98,45.3 170.98,45.68 170.79,45.87 170.57,45.87 170.38,46.06 170.38,46.44 170.57,46.63 170.79,46.63 170.98,46.82 170.98,47.2 170.79,47.39 170.57,47.39 170.38,47.58 170.38,47.96 170.57,48.15 170.79,48.15 170.98,48.34 170.98,48.72 170.79,48.92 170.57,48.92 170.38,49.11 170.38,49.49 170.57,49.68 170.79,49.68 170.98,49.87 170.98,50.25 170.79,50.44 170.57,50.44 170.38,50.63 170.38,51.01 170.57,51.2 170.79,51.2 170.98,51.39 170.98,51.77 170.79,51.96 170.57,51.96 170.38,52.15 170.38,52.53 170.57,52.73 170.79,52.73 170.98,52.92 170.98,53.3 170.79,53.49 170.57,53.49 170.38,53.68 170.38,54.06 170.57,54.25 170.79,54.25 170.98,54.44 170.98,54.82 170.79,55.01 170.57,55.01 170.38,55.2 170.38,55.58 170.57,55.77 170.79,55.77 170.98,55.96 170.98,56.34 170.79,56.54 170.57,56.54 170.38,56.73 170.38,57.11 170.57,57.3 170.79,57.3 170.98,57.49 170.98,57.87 170.79,58.06 170.57,58.06 170.38,58.25 170.38,58.63 170.57,58.82 170.79,58.82 170.98,59.01 170.98,59.39 170.79,59.58 170.57,59.58 170.38,59.77 170.38,60.15 170.57,60.35 170.79,60.35 170.98,60.54 170.98,60.92 170.65,61.25 149.16,61.25 147.4,59.49 147.4,57.96
DDR3_CPU_CH0_MA3: length 109.7
  TOP w0.102: v1(142.62,48.26) 142.62,48.73 142.29,49.06 141.84,49.06 U14.BG11
  TOP w0.157: v1(200.85,37.95) 201.15,38.25 P1.103
  L5_SIG w0.102: 150.83,51.92 149.51,51.92 148.82,51.23 146.39,51.23 146.06,50.9 145.79,50.9 144.19,49.3 144.19,48.26 143.76,47.84 143.05,47.84 v1(142.62,48.26)
  L5_SIG w0.191: 150.83,51.92 151.87,51.92 152.45,51.33 162.61,51.33 163.79,50.15 163.79,25.08 164.08,24.79 164.52,24.79 164.83,24.48 164.83,24.09 165.02,23.9 165.4,23.9 165.59,24.09 165.59,24.42 165.78,24.61 166.16,24.61 166.35,24.42 166.35,24.09 166.54,23.9 166.92,23.9 167.11,24.09 167.11,24.42 167.3,24.61 167.69,24.61 167.88,24.42 167.88,24.09 168.07,23.9 168.45,23.9 168.64,24.09 168.64,24.42 168.83,24.61 169.21,24.61 169.4,24.42 169.4,24.09 169.59,23.9 169.97,23.9 170.16,24.09 170.16,24.42 170.35,24.61 170.73,24.61 170.92,24.42 170.92,24.09 171.11,23.9 171.5,23.9 171.69,24.09 171.69,24.42 171.88,24.61 172.26,24.61 172.45,24.42 172.45,24.09 172.64,23.9 173.02,23.9 173.21,24.09 173.21,24.42 173.4,24.61 173.78,24.61 173.97,24.42 173.97,24.09 174.16,23.9 174.54,23.9 174.73,24.09 174.73,24.42 174.92,24.61 175.31,24.61 175.5,24.42 175.5,24.09 175.69,23.9 176.07,23.9 176.26,24.09 176.26,24.42 176.45,24.61 176.83,24.61 177.02,24.42 177.02,24.09 177.21,23.9 177.59,23.9 177.78,24.09 177.78,24.42 177.97,24.61 178.35,24.61 178.54,24.42 178.54,24.09 178.73,23.9 179.12,23.9 179.31,24.09 179.31,24.42 179.5,24.61 179.88,24.61 180.07,24.42 180.07,24.09 180.26,23.9 180.57,23.9 181.23,24.56 181.53,24.56 182.19,23.9 182.55,23.9 184.84,26.19 188.19,26.19 188.52,26.52 188.52,30.02 191.24,32.74 191.77,32.74 192.05,33.02 192.05,33.55 192.53,34.04 192.79,34.04 195.25,36.5 196.94,36.5 198.89,38.45 200.35,38.45 v1(200.85,37.95)
DDR3_CPU_CH0_MA4: length 109.4
  TOP w0.157: U14.BD13 140.35,47.49 v1(140.67,47.17) ; v1(191.89,38.44) 191.89,38.44 192.17,38.71 193.04,38.71 193.2,38.55 P1.104
  L5_SIG w0.102: 146.28,55.91 145.97,55.91 142.47,52.41 141.76,52.41 140.69,51.33 140.69,50.41 140.31,50.04 140.31,47.53 v1(140.67,47.17)
  L5_SIG w0.191: v1(191.89,38.44) 191.71,38.25 190.02,38.25 189.51,37.74 184.99,37.74 184.77,37.97 171.39,37.97 171.13,38.23 171.13,38.5 171.3,38.67 171.3,38.94 171.03,39.21 170.76,39.21 170.59,39.04 170.32,39.04 170.05,39.31 170.05,39.58 170.22,39.75 170.22,40.02 169.95,40.29 169.68,40.29 169.51,40.12 169.24,40.12 168.81,40.55 168.81,41.03 169,41.22 169.62,41.22 169.81,41.41 169.81,41.79 169.62,41.99 168.9,41.99 168.71,42.18 168.71,42.56 168.9,42.75 169.62,42.75 169.81,42.94 169.81,43.32 169.62,43.51 168.9,43.51 168.71,43.7 168.71,44.08 168.9,44.27 169.62,44.27 169.81,44.46 169.81,44.84 169.62,45.03 168.9,45.03 168.71,45.22 168.71,45.6 168.9,45.8 169.62,45.8 169.81,45.99 169.81,46.37 169.62,46.56 168.9,46.56 168.71,46.75 168.71,47.13 168.9,47.32 169.62,47.32 169.81,47.51 169.81,47.89 169.62,48.08 168.9,48.08 168.71,48.27 168.71,48.65 168.9,48.84 169.62,48.84 169.81,49.03 169.81,49.41 169.62,49.61 168.9,49.61 168.71,49.8 168.71,50.18 168.9,50.37 169.62,50.37 169.81,50.56 169.81,50.94 169.62,51.13 168.9,51.13 168.71,51.32 168.71,51.7 168.9,51.89 169.62,51.89 169.81,52.08 169.81,52.46 169.62,52.65 168.9,52.65 168.71,52.84 168.71,53.22 168.9,53.42 169.62,53.42 169.81,53.61 169.81,53.99 169.62,54.18 168.9,54.18 168.71,54.37 168.71,54.75 168.9,54.94 169.62,54.94 169.81,55.13 169.81,55.51 169.62,55.7 168.9,55.7 168.71,55.89 168.71,56.27 168.9,56.46 169.62,56.46 169.81,56.65 169.81,57.03 169.62,57.23 168.9,57.23 168.71,57.42 168.71,57.8 168.9,57.99 169.62,57.99 169.81,58.18 169.81,58.56 169.62,58.75 168.9,58.75 168.71,58.94 168.71,59.32 168.9,59.51 169.62,59.51 169.81,59.7 169.81,60.31 169.44,60.68 149.58,60.68 148.09,59.19 148.09,57.71 146.28,55.91
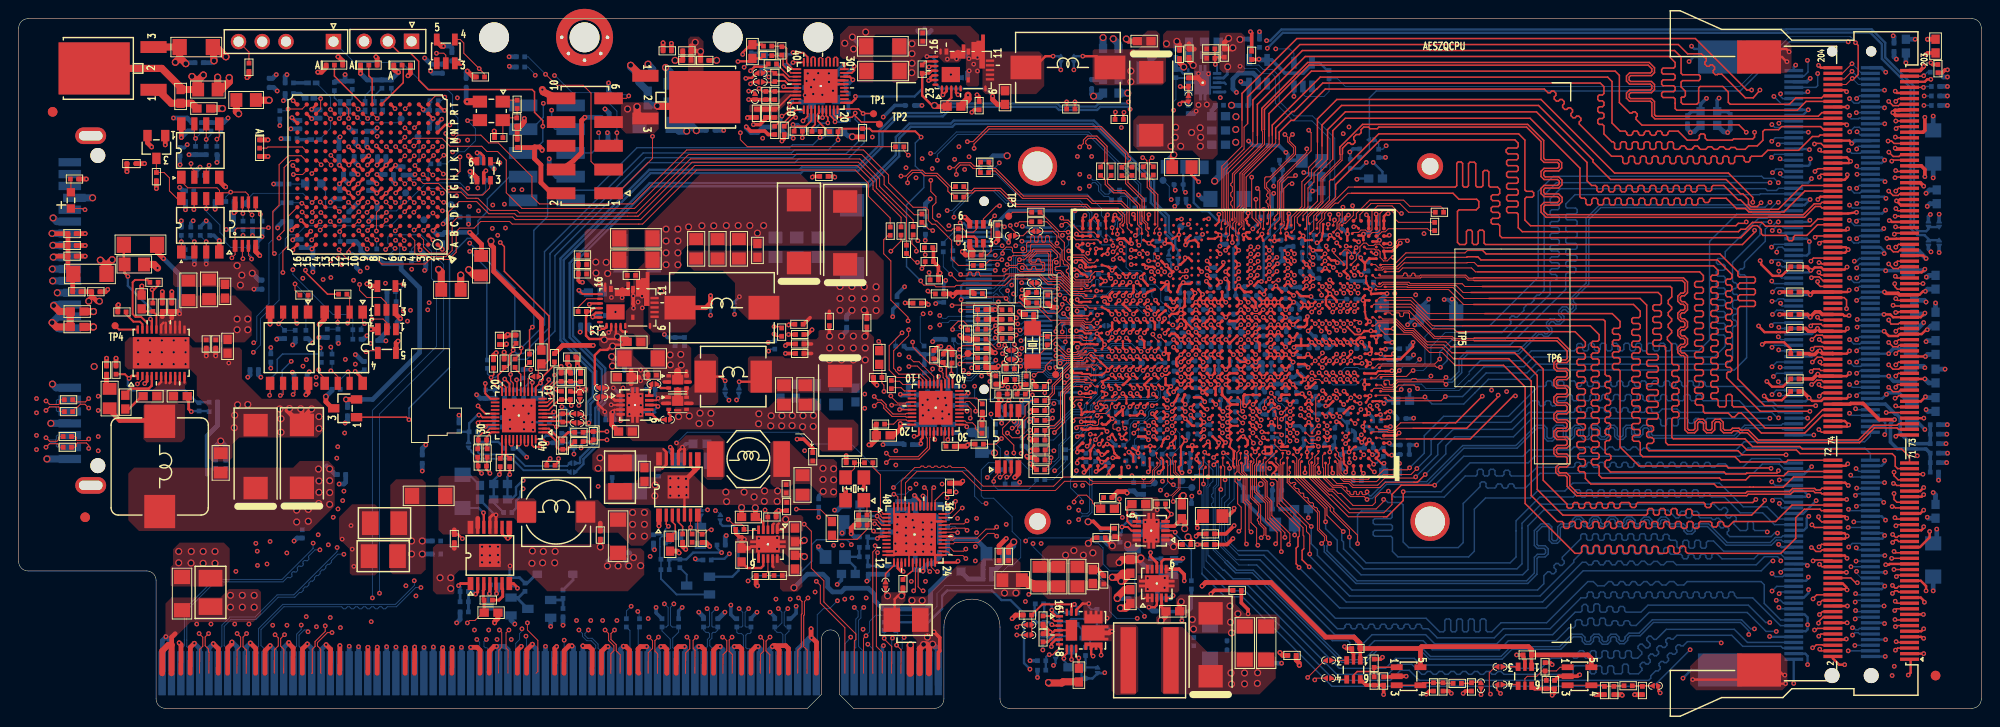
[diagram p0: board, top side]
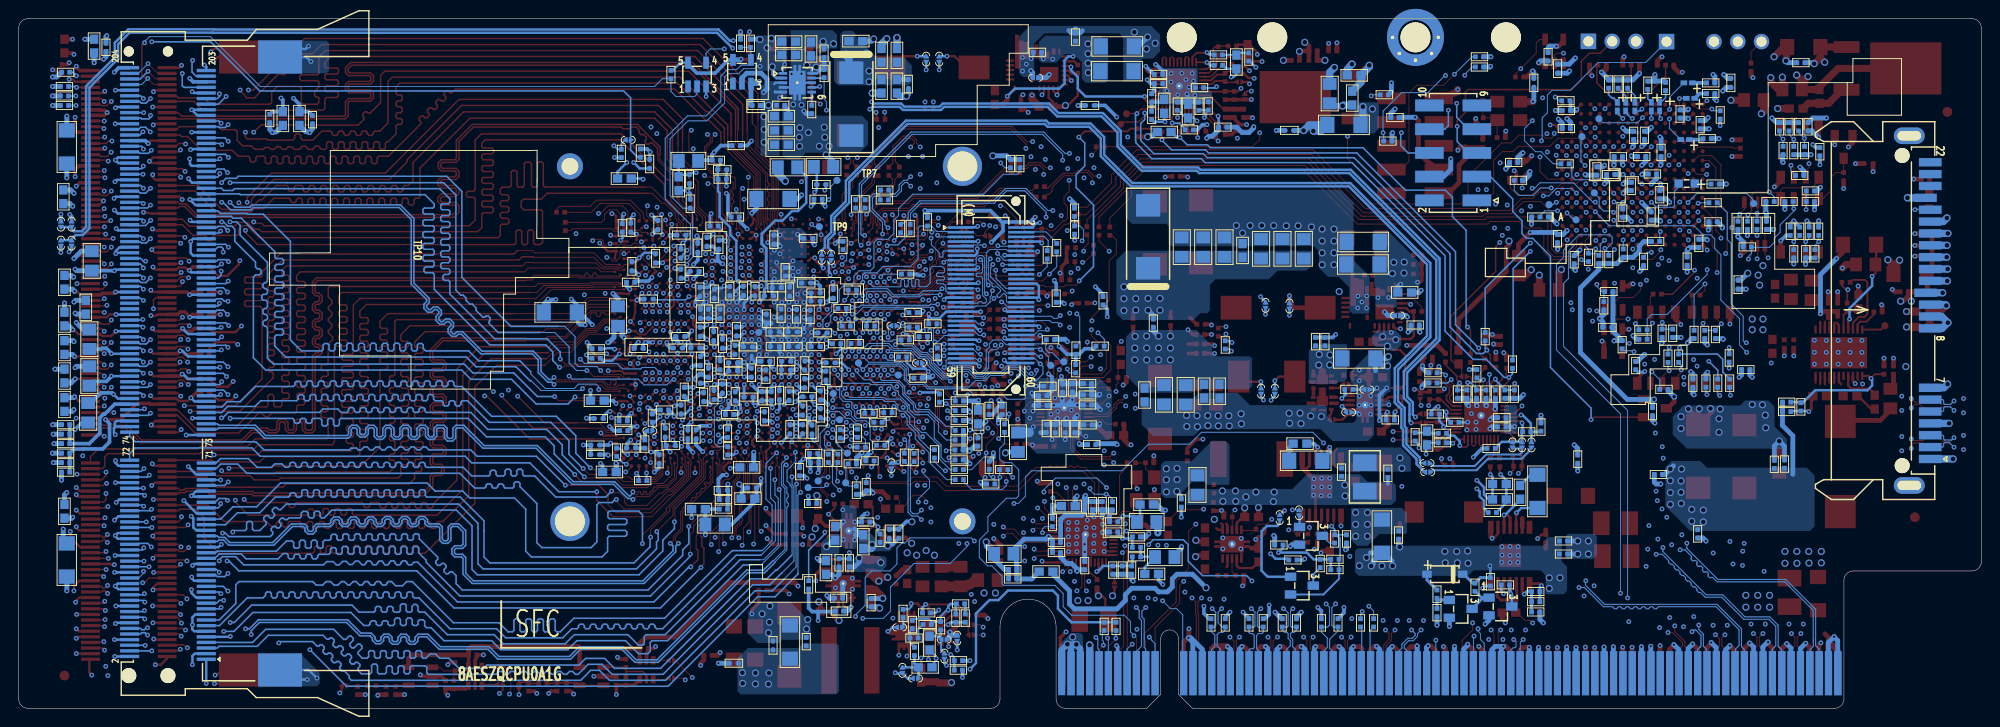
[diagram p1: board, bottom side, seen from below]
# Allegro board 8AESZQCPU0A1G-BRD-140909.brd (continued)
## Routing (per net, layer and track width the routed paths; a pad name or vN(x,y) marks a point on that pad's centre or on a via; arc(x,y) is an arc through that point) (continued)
DDR3_CPU_CH0_MA5: length 107.8
  TOP w0.157: P1.99 201.15,37.05 v1(200.85,36.75) ; v1(142.85,51.54) 142.91,51.6 143.13,51.6 U14.BM7
  L5_SIG w0.191: v1(200.85,36.75) 200.85,36.84 200.34,37.35 198.99,37.35 197.01,35.38 195.27,35.38 193.85,33.96 193.85,26.34 188.67,21.16 176.89,21.16 176.7,21.35 176.7,21.68 176.51,21.87 176.13,21.87 175.94,21.68 175.94,21.35 175.75,21.16 175.37,21.16 175.18,21.35 175.18,21.68 174.99,21.87 174.6,21.87 174.41,21.68 174.41,21.35 174.22,21.16 173.84,21.16 173.65,21.35 173.65,21.68 173.46,21.87 173.08,21.87 172.89,21.68 172.89,21.35 172.7,21.16 172.32,21.16 172.13,21.35 172.13,21.68 171.94,21.87 171.56,21.87 171.37,21.68 171.37,21.35 171.18,21.16 170.79,21.16 170.6,21.35 170.6,21.68 170.41,21.87 170.03,21.87 169.84,21.68 169.84,21.35 169.65,21.16 169.27,21.16 169.08,21.35 169.08,21.68 168.89,21.87 168.51,21.87 168.32,21.68 168.32,21.35 168.13,21.16 167.75,21.16 167.56,21.35 167.56,21.68 167.37,21.87 166.98,21.87 166.79,21.68 166.79,21.35 166.6,21.16 166.22,21.16 166.03,21.35 166.03,21.68 165.84,21.87 165.46,21.87 165.27,21.68 165.27,21.35 165.08,21.16 164.64,21.16 162.65,23.15 162.65,49.67 162.13,50.19 150.98,50.19 v1(150.37,50.8)
  L8_SIG w0.191: v1(150.37,50.8) 149.4,51.77 143.06,51.77 142.85,51.56 v1(142.85,51.54)
DDR3_CPU_CH0_MA6: length 108.2
  TOP w0.102: U14.BD10 141.79,47.62 140.72,48.69 v1(140.72,49.02)
  TOP w0.157: v1(191.92,37.05) 192.44,37.57 192.96,37.57 193.18,37.35 P1.100
  L5_SIG w0.102: 147.68,55.5 145.62,53.44 144.09,53.44 142.64,52 142.29,52 141.71,51.42 141.71,49.81 140.92,49.02 v1(140.72,49.02)
  L5_SIG w0.191: 147.68,55.5 147.96,55.78 153.38,55.78 153.67,56.06 153.67,57.82 153.86,58.01 154.24,58.01 154.43,57.82 154.43,56.06 154.62,55.87 155,55.87 155.19,56.06 155.19,57.75 155.38,57.94 155.76,57.94 155.95,57.75 155.95,56.06 156.14,55.87 156.6,55.87 156.79,56.06 156.79,56.35 156.98,56.54 157.36,56.54 157.55,56.35 157.55,56.06 157.74,55.87 158.33,55.87 158.52,56.06 158.52,57.59 158.71,57.78 159.1,57.78 159.29,57.59 159.29,56.06 159.48,55.87 159.86,55.87 160.05,56.06 160.05,57.8 160.24,57.99 160.62,57.99 160.81,57.8 160.81,56.06 161,55.87 162.7,55.87 162.89,56.06 162.89,58 163.08,58.19 163.46,58.19 163.65,58 163.65,56.06 163.84,55.87 164.22,55.87 164.41,56.06 164.41,58 164.6,58.19 164.99,58.19 165.18,58 165.18,56.06 165.37,55.87 165.75,55.87 165.94,56.06 165.94,58 166.13,58.19 166.95,58.19 167.22,57.92 167.22,39.38 168.16,38.44 168.16,38.17 167.49,37.5 167.49,37.23 167.76,36.96 168.03,36.96 168.7,37.63 168.97,37.63 169.93,36.68 186.03,36.68 186.69,36.02 189.69,36.02 190.72,37.05 v1(191.92,37.05)
DDR3_CPU_CH0_MA7: length 108.4
  TOP w0.157: P1.98 192.89,36.75 192.74,36.91 v1(192.74,37.06) ; v1(142.04,49.46) 142.11,49.4 U14.BH8
  L5_SIG w0.102: 151.38,55.15 148.11,55.15 145.38,52.42 144.51,52.42 142.62,50.53 142.62,50.05 v1(142.04,49.46)
  L5_SIG w0.191: v1(192.74,37.06) 192.25,36.58 190.98,36.58 188.85,34.44 186.74,34.44 185.09,36.09 184.52,36.09 184.33,35.9 184.33,34.56 184.14,34.37 183.76,34.37 183.56,34.56 183.56,35.9 183.37,36.09 182.99,36.09 182.8,35.9 182.8,34.56 182.61,34.37 182.23,34.37 182.04,34.56 182.04,35.9 181.85,36.09 181.47,36.09 181.28,35.9 181.28,34.56 181.09,34.37 180.71,34.37 180.52,34.56 180.52,35.9 180.33,36.09 179.95,36.09 179.75,35.9 179.75,34.56 179.56,34.37 179.18,34.37 178.99,34.56 178.99,35.9 178.8,36.09 178.42,36.09 178.23,35.9 178.23,34.56 178.04,34.37 177.66,34.37 177.47,34.56 177.47,35.9 177.28,36.09 176.9,36.09 176.71,35.9 176.71,34.56 176.52,34.37 176.14,34.37 175.94,34.56 175.94,35.9 175.75,36.09 175.37,36.09 175.18,35.9 175.18,34.56 174.99,34.37 174.61,34.37 174.42,34.56 174.42,35.9 174.23,36.09 173.85,36.09 173.66,35.9 173.66,34.56 173.47,34.37 173.09,34.37 172.9,34.56 172.9,35.9 172.71,36.09 172.33,36.09 172.13,35.9 172.13,34.56 171.94,34.37 171.56,34.37 171.37,34.56 171.37,35.9 171.18,36.09 170.8,36.09 170.61,35.9 170.61,34.56 170.42,34.37 170.04,34.37 169.85,34.56 169.85,35.9 169.66,36.09 169.28,36.09 169.09,35.9 169.09,34.63 168.9,34.44 168.52,34.44 168.32,34.63 168.32,35.61 167.84,36.09 167.46,36.09 166.65,36.91 166.65,54.79 166.29,55.15 151.38,55.15
DDR3_CPU_CH0_MA8: length 109.5
  TOP w0.102: v1(148.59,50.04) 148.44,50.19 147.66,50.19 147.42,49.95 147.42,49.77 147.19,49.54 147.19,49.53 146.95,49.29 146.48,49.29 146.47,49.28 146.02,49.28 145.62,49.67 145.14,49.67 144.99,49.53 144.45,49.53 144.2,49.78 143.89,49.78 143.51,49.4 143.51,48.9 143.13,48.51 143.13,48.05 U14.BD8
  TOP w0.157: v1(200.09,36.75) 200.55,36.29 201.16,36.29 201.32,36.45 P1.97
  L5_SIG w0.191: v1(200.09,36.75) 199.5,36.75 196.84,34.1 195.76,34.1 195.07,33.41 195.07,26.01 193.5,24.43 193.5,21.87 193.07,21.44 190.93,21.44 189.79,20.29 170.55,20.29 170.36,20.1 170.36,19.44 170.17,19.25 169.79,19.25 169.6,19.44 169.6,20.1 169.41,20.29 169.03,20.29 168.83,20.1 168.83,19.44 168.64,19.25 168.26,19.25 168.07,19.44 168.07,20.1 167.88,20.29 167.5,20.29 167.31,20.1 167.31,19.44 167.12,19.25 166.74,19.25 166.55,19.44 166.55,20.1 166.36,20.29 165.98,20.29 165.79,20.1 165.79,19.44 165.6,19.25 165.22,19.25 165.02,19.44 165.02,20.1 164.83,20.29 164.41,20.29 162.08,22.63 162.08,49.15 161.61,49.62 149.68,49.62 149.26,50.04 v1(148.59,50.04)
DDR3_CPU_CH0_MA9: length 109.3
  TOP w0.157: P1.92 193.07,34.95 192.9,35.11 192.39,35.11 191.93,34.65 v1(191.85,34.65) ; U14.BD15 v1(139.78,47.87)
  L5_SIG w0.102: v1(139.78,47.87) 139.78,47.83 139.42,47.47 139.42,46.94 139.64,46.72 140.95,46.72 141.48,47.25 141.48,48.9 141.6,49.02 142.82,49.02 142.94,48.9 143.27,48.9 143.51,49.14 143.51,49.51 146.16,52.15 146.84,52.15
  L5_SIG w0.191: v1(191.85,34.65) 191.55,34.65 188.96,32.06 186.59,32.06 182.68,28.14 181.95,28.14 181.76,27.95 181.76,27.14 181.57,26.95 181.23,26.95 181.04,27.14 181.04,28.05 180.85,28.24 180.47,28.24 180.28,28.05 180.28,27.14 180.09,26.95 179.71,26.95 179.52,27.14 179.52,28.05 179.33,28.24 178.94,28.24 178.75,28.05 178.75,27.14 178.56,26.95 178.14,26.95 177.95,27.14 177.95,27.95 177.76,28.14 177.38,28.14 177.19,27.95 177.19,27.14 177,26.95 176.62,26.95 176.43,27.14 176.43,27.95 176.24,28.14 175.86,28.14 175.67,27.95 175.67,27.14 175.48,26.95 175.1,26.95 174.9,27.14 174.9,27.95 174.71,28.14 174.33,28.14 174.14,27.95 174.14,27.14 173.95,26.95 173.57,26.95 173.38,27.14 173.38,27.95 173.19,28.14 172.81,28.14 172.62,27.95 172.62,27.14 172.43,26.95 172.05,26.95 171.86,27.14 171.86,27.95 171.67,28.14 171.29,28.14 171.09,27.95 171.09,27.14 170.9,26.95 170.52,26.95 170.33,27.14 170.33,27.95 170.14,28.14 169.76,28.14 169.57,27.95 169.57,27.14 169.38,26.95 169,26.95 168.81,27.14 168.81,27.95 168.62,28.14 168.24,28.14 168.05,27.95 168.05,27.14 167.86,26.95 167.48,26.95 167.28,27.14 167.28,27.95 167.09,28.14 166.71,28.14 166.52,27.95 166.52,27.14 166.33,26.95 165.95,26.95 165.76,27.14 165.76,27.95 164.93,28.78 164.93,52.37 164.04,53.26 149.33,53.26 148.21,52.15 146.84,52.15
DDR3_CPU_CH0_MA10: length 109.7
  TOP w0.102: U14.BN10 141.8,51.91 141.98,51.91 142.81,52.74 142.81,53.53 142.72,53.61 v1(142.72,53.78)
  TOP w0.157: v1(200.84,42.37) 200.87,42.34 201.09,42.34 201.2,42.45 P1.117
  L5_SIG w0.191: v1(141.72,61.49) 142.74,61.49 146.74,65.49 173.61,65.49 183.24,55.86 183.24,55.55 183.05,55.36 181.78,55.36 181.58,55.17 181.58,54.78 181.78,54.59 183.05,54.59 183.24,54.4 183.24,54.02 183.05,53.83 181.78,53.83 181.58,53.64 181.58,53.26 181.78,53.07 183.05,53.07 183.24,52.88 183.24,52.5 183.05,52.31 181.78,52.31 181.58,52.12 181.58,51.74 181.78,51.55 183.05,51.55 183.24,51.36 183.24,50.97 183.05,50.78 181.78,50.78 181.58,50.59 181.58,50.21 181.78,50.02 183.05,50.02 183.24,49.83 183.24,49.45 183.05,49.26 181.78,49.26 181.58,49.07 181.58,48.69 181.78,48.5 183.15,48.5 183.29,48.36 183.29,47.88 183.14,47.74 181.88,47.74 181.69,47.55 181.69,47.16 181.88,46.97 183.43,46.97 183.62,46.78 183.62,45.22 183.81,45.03 184.18,45.03 184.37,45.22 184.37,45.91 184.56,46.1 184.94,46.1 185.13,45.91 185.13,45.22 185.32,45.03 185.7,45.03 185.89,45.22 185.89,45.81 186.08,46 186.46,46 186.66,45.81 186.66,45.22 186.85,45.03 188.82,45.03 190.85,43 192.27,43 192.53,43.26 195.88,43.26 196.64,42.5 198.55,42.5 198.81,42.75 200.06,42.75 200.45,42.37 v1(200.84,42.37)
  L8_SIG w0.191: v1(142.72,53.78) 141.72,54.78 v1(141.72,61.49)
DDR3_CPU_CH0_MA11: length 109.7
  TOP w0.157: U14.BG8 142.93,49.07 143.1,49.25 v1(143.1,49.31) ; P1.96 192.82,36.15 192.66,36.31 192.07,36.31 v1(191.8,36.04)
  L5_SIG w0.102: 151.99,54.48 148.29,54.48 147.32,53.52 147.32,53.19 146.69,52.56 146.03,52.56 144.86,51.39 143.97,51.39 142.99,50.41 142.99,49.42 v1(143.1,49.31)
  L5_SIG w0.191: 151.99,54.48 165.58,54.48 166.08,53.99 166.08,34.02 167.24,32.86 167.24,31.38 167.43,31.19 167.81,31.19 168,31.38 168,32.86 168.19,33.05 168.57,33.05 168.76,32.86 168.76,31.38 168.95,31.19 169.33,31.19 169.52,31.38 169.52,32.86 169.71,33.05 170.09,33.05 170.29,32.86 170.29,31.38 170.48,31.19 170.86,31.19 171.05,31.38 171.05,32.86 171.24,33.05 171.62,33.05 171.81,32.86 171.81,31.38 172,31.19 172.38,31.19 172.57,31.38 172.57,32.86 172.76,33.05 173.14,33.05 173.33,32.86 173.33,31.38 173.52,31.19 173.9,31.19 174.1,31.38 174.1,32.86 174.29,33.05 174.67,33.05 174.86,32.86 174.86,31.38 175.05,31.19 175.43,31.19 175.62,31.38 175.62,32.86 175.81,33.05 176.19,33.05 176.38,32.86 176.38,31.38 176.57,31.19 176.95,31.19 177.14,31.38 177.14,32.86 177.33,33.05 177.71,33.05 177.91,32.86 177.91,31.38 178.1,31.19 178.48,31.19 178.67,31.38 178.67,32.86 178.86,33.05 179.24,33.05 179.43,32.86 179.43,31.38 179.62,31.19 180,31.19 180.19,31.38 180.19,32.86 180.38,33.05 180.76,33.05 180.95,32.86 180.95,31.43 181.14,31.24 181.52,31.24 181.72,31.43 181.72,32.86 181.91,33.05 182.73,33.05 182.99,32.79 183.49,32.79 183.75,33.05 185.51,33.05 186.54,34.09 189.51,34.09 191.28,35.85 191.61,35.85 v1(191.8,36.04)
DDR3_CPU_CH0_MA12: length 108.9
  TOP w0.157: v1(142.94,47.11) 143.29,47.47 U14.BD7 ; v1(200.85,35.55) 201.15,35.85 P1.95
  L5_SIG w0.102: v1(142.94,47.11) 143.17,47.35 143.87,47.35 144.59,48.07 144.59,48.87 145,49.28 148.97,49.28
  L5_SIG w0.191: v1(200.85,35.55) 200.85,35.68 200.5,36.03 199.51,36.03 197.36,33.88 197.36,27.14 194.21,23.99 194.21,19.53 193.7,19.02 191.85,19.02 191.66,18.83 191.66,18.5 191.47,18.31 191.09,18.31 190.9,18.5 190.9,18.83 190.71,19.02 190.32,19.02 190.13,18.83 190.13,18.55 189.94,18.36 189.56,18.36 189.37,18.55 189.37,18.83 188.85,19.35 186.9,19.35 184.95,17.4 165.46,17.4 161.51,21.35 161.51,42.99 160.05,44.45 160.05,44.77 160.34,45.06 160.34,45.33 160.07,45.6 159.8,45.6 159.48,45.28 159.21,45.28 158.94,45.55 158.94,45.82 159.26,46.14 159.26,46.41 158.99,46.68 158.72,46.68 158.4,46.36 158.14,46.36 157.87,46.63 157.87,46.9 158.22,47.25 158.22,47.52 157.95,47.79 157.68,47.79 157.33,47.44 157.06,47.44 156.79,47.71 156.79,47.98 157.1,48.29 157.1,48.56 156.83,48.83 156.56,48.83 156.25,48.52 155.98,48.52 155.45,49.05 149.2,49.05 148.97,49.28
DDR3_CPU_CH0_MA13: length 113.4
  TOP w0.157: P1.130 192.9,46.35 192.64,46.53 v1(192.62,46.65) ; v1(135.8,46.35) 135.45,46 U14.BA23
  L5_SIG w0.102: v1(135.8,46.35) 134.97,47.18 134.39,47.18 134.22,47.01 134.22,46.43 134.2,46.4 134.2,45.8 133.98,45.57 133.66,45.57 133.44,45.8 133.44,46.52 133.12,46.84 133.12,47.3 133.01,47.41 133.01,50.09 133.42,50.51 133.42,52.61 134.1,53.29
  L5_SIG w0.191: v1(192.62,46.65) 192.78,46.65 193.24,47.11 193.24,52.53 193.04,52.72 192.85,52.72 192.66,52.91 192.66,53.29 192.85,53.48 193.04,53.48 193.24,53.67 193.24,60.6 192.89,60.95 192.89,61.36 193.24,61.71 193.24,62.19 192,63.42 191.39,63.42 190.45,64.36 190.45,64.74 187.65,67.55 187.38,67.55 187.24,67.41 186.97,67.41 186.7,67.68 186.7,67.95 186.84,68.09 186.84,68.36 186.49,68.71 185.29,68.71 185.1,68.9 185.1,69.3 184.91,69.49 184.53,69.49 184.34,69.3 184.34,68.9 184.15,68.71 183.77,68.71 183.58,68.9 183.58,69.3 183.39,69.49 183.01,69.49 182.82,69.3 182.82,68.9 182.63,68.71 182.25,68.71 182.06,68.9 182.06,69.3 181.86,69.49 181.48,69.49 181.29,69.3 181.29,68.9 181.1,68.71 180.72,68.71 180.53,68.9 180.53,69.3 180.34,69.49 179.96,69.49 179.77,69.3 179.77,68.9 179.58,68.71 177.44,68.71 176.66,69.49 139.79,69.49 138.67,68.37 138.67,68.1 138.95,67.82 138.95,67.55 138.68,67.28 138.41,67.28 138.05,67.64 137.78,67.64 136.97,66.83 136.96,66.83 134.35,64.22 134.35,56.9 134.74,56.51 134.74,53.93 134.1,53.29
DDR3_CPU_CH0_MA14: length 106.5
  TOP w0.102: v1(141.4,46.39) U14.BC11
  TOP w0.157: P1.90 192.9,34.35 192.66,34.52 v1(192.63,34.65)
  L5_SIG w0.102: v1(141.4,46.39) 141.68,46.67 141.68,47.91 142.48,48.7 143.36,48.7 143.81,49.16 143.81,49.38 146.12,51.68 148.53,51.68 149.54,52.69
  L5_SIG w0.191: 149.54,52.69 163.46,52.69 164.36,51.79 164.36,27.24 165.61,26 165.61,25.51 165.8,25.32 166.18,25.32 166.37,25.51 166.37,26 166.56,26.19 166.94,26.19 167.13,26 167.13,25.51 167.32,25.32 167.7,25.32 167.89,25.51 167.89,26 168.08,26.19 168.47,26.19 168.66,26 168.66,25.51 168.85,25.32 169.23,25.32 169.42,25.51 169.42,26 169.61,26.19 169.99,26.19 170.18,26 170.18,25.51 170.37,25.32 170.75,25.32 170.94,25.51 170.94,26 171.13,26.19 171.51,26.19 171.7,26 171.7,25.51 171.89,25.32 172.28,25.32 172.47,25.51 172.47,26 172.66,26.19 173.04,26.19 173.23,26 173.23,25.51 173.42,25.32 173.8,25.32 173.99,25.51 173.99,26 174.18,26.19 174.56,26.19 174.75,26 174.75,25.51 174.94,25.32 175.32,25.32 175.51,25.51 175.51,26 175.7,26.19 176.09,26.19 176.28,26 176.28,25.51 176.47,25.32 176.85,25.32 177.04,25.51 177.04,26 177.23,26.19 177.61,26.19 177.8,26 177.8,25.51 177.99,25.32 178.37,25.32 178.56,25.51 178.56,26 178.75,26.19 179.13,26.19 179.32,26 179.32,25.51 179.51,25.32 179.9,25.32 180.09,25.51 180.09,26 180.28,26.19 180.66,26.19 180.85,26 180.85,25.51 181.04,25.32 181.42,25.32 181.61,25.51 181.61,26 181.83,26.21 183.18,26.21 183.73,26.76 183.73,28.21 184.06,28.54 184.33,28.54 185.24,27.63 185.51,27.63 185.78,27.9 185.78,28.17 184.87,29.08 184.87,29.35 185.14,29.62 185.41,29.62 186.32,28.7 186.59,28.7 186.86,28.97 186.86,29.24 185.95,30.16 185.95,30.42 187.13,31.6 189.21,31.6 191.78,34.18 192.16,34.18 v1(192.63,34.65)
DDR3_CPU_CH0_MA15: length 108.7
  TOP w0.157: U14.BF15 139.43,48.28 v1(139.78,48.63) ; v1(192.66,33.4) 193.01,33.75 P1.88
  L5_SIG w0.102: 145.91,49.6 145.04,49.6 144.39,48.95 144.39,48.15 143.79,47.55 142.04,47.55 141.89,47.4 141.89,46.26 141.6,45.98 141.23,45.98 140.86,46.35 139.72,46.35 138.94,47.14 138.94,47.79 v1(139.78,48.63)
  L5_SIG w0.191: 145.91,49.6 146.48,50.16 147.5,50.16 148.05,50.72 149.36,50.72 149.97,51.33 151.24,51.33 151.81,50.76 162.37,50.76 163.22,49.91 163.22,23.96 164.68,22.5 165.12,22.5 165.32,22.69 165.32,23.14 165.51,23.33 165.89,23.33 166.08,23.14 166.08,22.69 166.27,22.5 166.65,22.5 166.84,22.69 166.84,23.14 167.03,23.33 167.41,23.33 167.6,23.14 167.6,22.69 167.79,22.5 168.17,22.5 168.36,22.69 168.36,23.14 168.55,23.33 168.93,23.33 169.13,23.14 169.13,22.69 169.32,22.5 169.7,22.5 169.89,22.69 169.89,23.14 170.08,23.33 170.46,23.33 170.65,23.14 170.65,22.69 170.84,22.5 171.22,22.5 171.41,22.69 171.41,23.14 171.6,23.33 171.98,23.33 172.17,23.14 172.17,22.69 172.36,22.5 172.74,22.5 172.94,22.69 172.94,23.14 173.13,23.33 173.51,23.33 173.7,23.14 173.7,22.69 173.89,22.5 174.27,22.5 174.46,22.69 174.46,23.14 174.65,23.33 175.03,23.33 175.22,23.14 175.22,22.69 175.41,22.5 175.79,22.5 175.98,22.69 175.98,23.14 176.17,23.33 176.55,23.33 176.75,23.14 176.75,22.69 176.94,22.5 177.32,22.5 177.51,22.69 177.51,23.14 177.7,23.33 178.08,23.33 178.27,23.14 178.27,22.69 178.46,22.5 178.84,22.5 179.03,22.69 179.03,23.14 179.22,23.33 179.6,23.33 179.79,23.14 179.79,22.69 179.98,22.5 184.73,22.5 185.47,23.24 188.29,23.24 190.04,24.99 190.04,28.09 192.78,30.82 192.78,33.28 v1(192.66,33.4)
DDR3_CPU_CH0_ODT0: length 109.5
  TOP w0.157: U14.BD26 133.47,47.14 v1(133.82,47.49) ; v1(192.48,45.67) 192.48,45.44 192.77,45.15 P1.126
  L5_SIG w0.102: v1(133.82,47.49) 133.82,47.62 133.41,48.03 133.41,49.93 133.83,50.34 133.83,52.31 135.71,54.19 135.71,56.79
  L5_SIG w0.191: 135.71,56.79 135.71,57.72 136.81,58.82 136.81,61.69 136.08,62.42 136.08,62.76 141.67,68.35 174.82,68.35 176.75,66.43 177.58,66.43 177.79,66.22 177.79,65.52 178.06,65.25 178.49,65.25 178.68,65.44 178.68,67.34 178.87,67.53 179.25,67.53 179.44,67.34 179.44,65.33 180.61,64.16 181.38,64.16 182.02,64.8 182.74,64.8 183.13,65.19 183.13,67.34 183.32,67.53 183.7,67.53 183.89,67.34 183.89,65.19 184.08,65 186.24,65 186.97,64.27 186.97,63.42 187.24,63.15 187.67,63.15 187.86,63.35 187.86,64.11 188.05,64.3 188.38,64.3 188.62,64.06 188.62,63.35 188.81,63.15 189.62,63.15 190.25,62.53 190.25,60.4 190.53,60.12 190.53,46.23 191.19,45.56 192.31,45.56 192.42,45.67 v1(192.48,45.67)
DDR3_CPU_CH0_ODT1: length 112.1
  TOP w0.157: v1(191.82,46.08) 191.91,46.17 192.64,46.17 193.06,45.75 P1.128 ; v1(133.82,46.73) 133.81,46.73 133.47,46.39 U14.BB26
  L5_SIG w0.102: 135.18,56.9 135.18,53.94 133.63,52.39 133.63,50.43 133.21,50.01 133.21,47.5 133.79,46.91 133.79,46.81 133.82,46.79 v1(133.82,46.73)
  L5_SIG w0.191: v1(191.82,46.08) 191.4,46.08 191.11,46.37 191.11,61.11 190.91,61.32 190.91,62.92 188.86,64.97 187.37,64.97 186.81,65.53 184.86,65.53 184.66,65.74 184.66,66.46 184.85,66.65 185.89,66.65 186.08,66.84 186.08,67.69 185.89,67.88 185.13,67.88 185.02,67.77 184.59,67.77 184.26,68.1 182.66,68.1 182.47,67.91 182.47,66.01 182.27,65.81 180.63,65.81 180.44,66 180.44,66.34 180.63,66.53 181.53,66.53 181.72,66.72 181.72,67.91 181.53,68.1 181.26,68.1 181.07,67.91 181.07,67.35 180.88,67.16 180.5,67.16 180.3,67.35 180.3,67.91 180.11,68.1 178.07,68.1 177.88,67.91 177.88,67.25 177.68,67.06 177.3,67.06 177.11,67.25 177.11,67.91 176.92,68.1 175.88,68.1 175.06,68.92 141.13,68.92 134.88,62.68 134.88,57.2 135.18,56.9
DDR3_CPU_CH0_RAS_N: length 114.5
  TOP w0.157: v1(195.58,42.76) 195.58,43.7 195.33,43.95 P1.122 ; v1(135.8,48.63) 135.45,48.98 U14.BG23
  L5_SIG w0.102: v1(135.8,48.63) 135.8,49.76 136.11,50.07 136.11,51.7 139.68,55.27 139.68,55.83
  L5_SIG w0.191: 139.68,55.83 139.68,57.57 147.03,64.92 173.35,64.92 180.87,57.4 180.87,56.76 180.68,56.57 179.41,56.57 179.22,56.38 179.22,56 179.41,55.81 180.68,55.81 180.87,55.61 180.87,55.23 180.68,55.04 179.41,55.04 179.22,54.85 179.22,54.47 179.41,54.28 180.68,54.28 180.87,54.09 180.87,53.71 180.68,53.52 179.41,53.52 179.22,53.33 179.22,52.95 179.41,52.76 180.68,52.76 180.87,52.57 180.87,52.19 180.68,52 179.41,52 179.22,51.8 179.22,51.42 179.41,51.23 180.68,51.23 180.87,51.04 180.87,50.66 180.68,50.47 179.41,50.47 179.22,50.28 179.22,49.9 179.41,49.71 180.68,49.71 180.87,49.52 180.87,49.14 180.68,48.95 179.41,48.95 179.22,48.76 179.22,48.38 179.41,48.19 180.68,48.19 180.87,47.99 180.87,47.61 180.68,47.42 179.41,47.42 179.22,47.23 179.22,46.41 179.42,46.21 182.86,46.21 183.05,46.02 183.05,45.63 182.86,45.45 181.06,45.45 180.8,45.18 180.8,44.4 181.13,44.07 181.84,44.07 182.17,44.4 182.7,44.4 183.03,44.07 183.51,44.07 183.85,44.4 184.71,44.4 185.04,44.07 185.72,44.07 186,44.35 186.79,44.35 187.07,44.07 188.1,44.07 188.17,44 188.89,44 190.34,42.55 195.37,42.55 v1(195.58,42.76)
DDR3_CPU_CH0_RESET_N: length 133.3
  TOP w0.152: P1.30 196.04,13.95 196.55,13.44 v1(196.73,13.44)
  L3_SIG w0.152: v1(195.76,71.32) 196.12,71.69 196.73,71.69 196.84,71.58 198.91,71.58 199.94,70.55 201.87,70.55 202.95,69.47 202.95,27.23 v1(203.15,27.03)
  L5_SIG w0.152: 201.44,13.61 202.56,14.73 202.56,26.44 v1(203.15,27.03)
  L5_SIG w0.157: v1(196.73,13.44) 196.91,13.61 201.44,13.61
  BOTTOM w0.157: 144.53,60.9 N30.2 ; 144.53,60.9 144.53,65.33 145.26,66.07 184.2,66.07 189.46,71.32 v1(195.76,71.32) ; 144.53,60.9 144.53,59.75 143.75,58.97 R180.2
DDR3_CPU_CH0_RESET_R_N: length 23.7
  TOP w0.102: v1(134.8,45.83) 134.55,45.83 134.31,45.59 U14.BA25
  L10_SIG w0.102: v1(134.8,45.83) 134.8,46.07 135.17,46.44 135.17,49.49 141.07,55.4 144,55.4 145.57,56.98 145.57,59.46 v1(146.32,60.21)
  BOTTOM w0.152: v1(146.32,60.21) 145.94,59.83 R181.1 145.52,60.41 N30.1
DDR3_CPU_CH0_VREF: length 15
  TOP w0.254: U14.AY29 132.64,45.7 132.9,45.7 132.93,45.68 v1(132.97,45.68)
  BOTTOM w0.254: v1(132.97,45.68) 133.21,45.92 133.21,50.02 133.88,50.7 133.88,51.49 135,52.6 135,55.15 135.17,55.32 R189.1 135.21,56.66 C227.1 135.21,57.92 134.91,58.21 R182.2
DDR3_CPU_CH0_VREFCA: length 16.7
  TOP w0.381: P1.84 195.95,32.55 196.02,32.63 197.35,32.63 199.08,30.89 v1(200.71,30.89)
  BOTTOM w0.381: R309.2 C434.1 R299.1 204.09,27.75 203.07,27.75 203.06,27.76 201.02,27.76 200.28,28.5 200.28,30.46 v1(200.71,30.89)
DDR3_CPU_CH0_VREFDQ: length 30.2
  TOP w0.254: v1(175.64,1.65) 175.45,1.84 N26.2 ; P1.1 202.44,5.13 202.44,3.81 v1(202.18,3.56)
  L5_SIG w0.254: v1(202.18,3.56) 200.03,1.4 175.9,1.4 v1(175.64,1.65)
DDR3_CPU_CH0_WE_N: length 112.7
  TOP w0.152: U14.BC23 v1(135.8,47.11)
  TOP w0.157: v1(200.85,43.84) 201.03,43.65 P1.121
  L5_SIG w0.102: v1(135.8,47.11) 135.27,47.64 135.27,51.35 138.96,55.04 138.96,55.2
  L5_SIG w0.191: 138.96,55.2 138.96,57.94 140.56,59.54 140.56,63.27 143.93,66.64 174.08,66.64 177.43,63.28 178.93,63.28 180.51,61.7 180.51,60.21 181.05,59.66 181.32,59.66 181.9,60.25 182.17,60.25 182.44,59.98 182.44,59.71 181.86,59.13 181.86,58.86 182.13,58.59 182.4,58.59 182.98,59.17 183.25,59.17 183.52,58.9 183.52,58.63 182.94,58.05 182.94,57.78 183.18,57.53 183.63,57.53 183.83,57.34 183.83,57.29 184.02,57.1 184.4,57.1 184.59,57.29 184.59,57.34 184.78,57.53 185.16,57.53 185.35,57.34 185.35,56.93 185.54,56.74 185.92,56.74 186.11,56.93 186.11,57.34 186.3,57.53 186.68,57.53 186.87,57.34 186.87,56.93 187.06,56.74 188.46,56.74 188.77,56.43 188.77,56.02 188.53,55.78 188.48,55.78 188.48,55.77 187.19,55.77 187.19,55.78 184.72,55.78 184.38,55.44 184.38,55.12 184.73,54.76 188.58,54.76 188.87,54.47 188.87,46.28 191.38,43.77 191.98,43.77 192.34,44.13 198.18,44.13 198.29,44.02 200.67,44.02 v1(200.85,43.84)
DDR3_CPU_CH1_BA0: length 96.7
  TOP w0.102: U14.N18 137.53,31.76 v1(137.2,32.09)
  L8_SIG w0.102: v1(137.2,32.09) 137.63,32.52 138.18,32.52 138.8,31.9 141.71,31.9 142.71,30.9 144.84,30.9 146.02,29.72 147,29.72 147.51,30.23
  L8_SIG w0.191: 147.51,30.23 159.26,30.23 161.7,32.67 161.7,49.71 164.55,52.56 164.55,53.07 165.01,53.53 165.01,53.8 164.55,54.26 164.55,54.88 164.8,55.12 166.18,55.12 166.37,54.93 166.37,54.47 166.57,54.28 166.95,54.28 167.14,54.47 167.14,54.93 167.33,55.12 167.71,55.12 167.9,54.93 167.9,54.47 168.09,54.28 168.47,54.28 168.66,54.47 168.66,54.93 168.85,55.12 169.23,55.12 169.42,54.93 169.42,54.47 169.61,54.28 169.99,54.28 170.18,54.47 170.18,54.93 170.38,55.12 170.76,55.12 170.95,54.93 170.95,54.47 171.14,54.28 171.52,54.28 171.71,54.47 171.71,54.93 171.9,55.12 172.28,55.12 172.47,54.93 172.47,54.47 172.66,54.28 173.04,54.28 173.23,54.47 173.23,54.93 173.42,55.12 173.8,55.12 173.99,54.93 173.99,54.47 174.19,54.28 174.57,54.28 174.76,54.47 174.76,54.93 174.95,55.12 175.33,55.12 175.52,54.93 175.52,54.47 175.71,54.28 176.09,54.28 176.28,54.47 176.28,54.93 176.47,55.12 176.85,55.12 177.04,54.93 177.04,54.47 177.23,54.28 177.61,54.28 177.8,54.47 177.8,54.93 178,55.12 178.38,55.12 178.57,54.93 178.57,54.47 178.76,54.28 179.31,54.28 179.5,54.47 180.3,54.47 180.49,54.28 180.49,47.18 183.85,43.81 184.73,43.81 185.47,43.08 188.26,43.08 188.52,43.33 v1(188.52,43.35)
  BOTTOM w0.157: P4.119 188.68,43.05 188.52,43.21 v1(188.52,43.35)
DDR3_CPU_CH1_BA1: length 95.5
  TOP w0.102: v1(139.1,29.5) 139.05,29.5 138.67,29.12 138.12,29.12 137.77,29.47 U14.H18
  L8_SIG w0.102: v1(139.1,29.5) 139.35,29.5 139.76,29.09 140.84,29.09 141.34,28.59 141.34,26.22 141.9,25.66 142.36,25.66 142.44,25.58 144.14,25.58 144.79,24.93 144.89,24.93 144.9,24.91 145.21,24.91 145.23,24.93 145.38,24.93 145.65,25.19
  L8_SIG w0.191: 145.65,25.19 145.73,25.27 147.69,25.27 148.66,24.3 150.81,24.3 151.28,24.77 160.87,24.77 166.65,30.55 166.65,39.58 167.45,40.37 167.45,41.33 167.64,41.52 168.02,41.52 168.21,41.33 168.21,40.5 168.4,40.31 168.71,40.31 168.97,40.58 168.97,41.47 169.16,41.66 169.54,41.66 169.74,41.47 169.74,40.5 169.93,40.31 170.23,40.31 170.5,40.58 170.5,41.47 170.69,41.66 171.07,41.66 171.26,41.47 171.26,40.5 171.45,40.31 171.75,40.31 172.02,40.58 172.02,41.47 172.21,41.66 172.59,41.66 172.78,41.47 172.78,40.5 172.97,40.31 173.28,40.31 173.55,40.58 173.55,41.47 173.74,41.66 174.12,41.66 174.31,41.47 174.31,40.5 174.5,40.31 174.8,40.31 175.07,40.58 175.07,41.47 175.26,41.66 175.64,41.66 175.83,41.47 175.83,40.5 176.02,40.31 176.33,40.31 176.59,40.58 176.59,41.47 176.78,41.66 177.16,41.66 177.36,41.47 177.36,40.5 177.55,40.31 178.06,40.31 178.25,40.5 178.25,41.11 178.44,41.3 178.88,41.3 179.07,41.11 179.07,40.5 179.26,40.31 179.94,40.31 180.49,39.76 180.49,38.9 180.68,38.7 184.77,38.7 185.49,39.43 187.63,39.43 187.78,39.28 189.51,39.28 190.24,40.01 196.11,40.01 v1(196.66,39.45)
  BOTTOM w0.157: v1(196.66,39.45) 196.96,39.75 P4.108
DDR3_CPU_CH1_BA2: length 95.7
  TOP w0.102: v1(135.14,29.25) 135.08,29.31 135.08,29.35 134.96,29.47 U14.H25
  L8_SIG w0.102: 141.99,21.94 141.4,22.52 139.76,22.52 137.11,25.17 137.11,26.16 136.33,26.94 135.7,26.94 135.46,27.18 135.46,28.93 v1(135.14,29.25)
  L8_SIG w0.191: 141.99,21.94 141.99,21.79 145.03,18.75 145.03,16.39 147.6,13.82 167.75,13.82 167.75,13.82 168.22,13.82 170.95,16.56 171.96,17.56 171.96,21.41 172.94,22.39 172.94,22.66 172.23,23.37 172.23,23.64 172.5,23.91 172.77,23.91 173.48,23.2 173.74,23.2 174.01,23.47 174.01,23.74 173.31,24.45 173.31,24.72 173.58,24.99 173.84,24.99 174.55,24.28 174.82,24.28 175.09,24.55 175.09,24.82 174.38,25.52 174.38,25.79 174.65,26.06 174.92,26.06 175.63,25.36 175.9,25.36 176.17,25.62 176.17,25.89 175.46,26.6 175.46,26.87 175.73,27.14 176,27.14 176.71,26.43 176.98,26.43 177.25,26.7 177.25,26.97 176.54,27.68 176.54,27.95 176.81,28.22 177.08,28.22 177.79,27.51 178.06,27.51 178.33,27.78 178.33,28.05 177.62,28.76 177.62,29.03 177.89,29.3 178.16,29.3 178.87,28.59 179.13,28.59 179.4,28.86 179.4,29.13 178.7,29.84 178.7,30.11 178.97,30.38 179.23,30.38 179.94,29.67 180.21,29.67 180.48,29.94 180.48,30.21 179.77,30.91 179.77,31.18 180.04,31.45 180.31,31.45 181.02,30.74 181.29,30.74 181.66,31.11 181.66,31.7 182.04,32.08 182.63,32.08 183.13,32.59 184.96,32.59 185.45,33.07 185.45,33.91 186.01,34.47 187.34,34.47 187.82,34.95 v1(188.28,34.95)
  BOTTOM w0.157: P4.91 188.45,34.65 v1(188.28,34.95)
DDR3_CPU_CH1_CAS_N: length 95.6
  TOP w0.102: 149.2,29.97 147.57,29.97 147.14,29.54 146.52,29.54 146.47,29.59 144.84,29.59 U14.H4
  TOP w0.157: v1(158.3,33.51) 158.25,33.46 158.25,33.28 154.94,29.97 149.2,29.97
  L8_SIG w0.191: v1(187.66,44.55) 186.11,44.55 185.13,45.53 184.56,45.53 182.21,47.89 182.21,57.8 181.48,58.52 163.55,58.52 162.84,57.81 162.84,53.27 159.38,49.81 159.38,47.65 159.19,47.46 157.92,47.46 157.73,47.27 157.73,46.89 157.92,46.7 159.19,46.7 159.38,46.51 159.38,46.13 159.19,45.94 157.92,45.94 157.73,45.75 157.73,45.36 157.92,45.17 159.19,45.17 159.38,44.98 159.38,44.6 159.19,44.41 157.92,44.41 157.73,44.22 157.73,43.84 157.92,43.65 159.19,43.65 159.38,43.46 159.38,39.97 159.19,39.78 158.36,39.78 158.17,39.59 158.17,39.21 158.36,39.02 159.19,39.02 159.38,38.83 159.38,38.45 159.19,38.26 158.36,38.26 158.17,38.07 158.17,37.69 158.36,37.5 159.19,37.5 159.38,37.3 159.38,36.92 159.19,36.73 158.25,36.73 158.06,36.54 158.06,36.16 158.25,35.97 159.19,35.97 159.38,35.78 159.38,35.05 158.3,33.97 v1(158.3,33.51)
  BOTTOM w0.157: v1(187.66,44.55) 188.11,45.01 188.82,45.01 188.98,44.85 P4.125
DDR3_CPU_CH1_CK_DN0: length 93.5
  TOP w0.157: U14.D8 142.9,26.93 142.98,26.85 v1(142.98,26.78)
  L8_SIG w0.102: v1(142.98,26.78) 142.98,26.91 143.14,27.07 143.37,27.07 143.74,26.7 144.51,26.7 144.57,26.75 145.44,26.75 145.64,26.95 146.32,26.95 146.58,26.69 147.37,26.69 147.5,26.82 149.24,26.82 149.55,26.51 150.14,26.51 150.17,26.54 150.2,26.54
  L8_SIG w0.135: 150.2,26.54 160.27,26.54 164.91,31.18 164.91,41.96 165.77,42.82 165.77,47.57 166.06,47.85 166.54,47.85 166.83,47.57 166.83,45.71 166.96,45.58 167.23,45.58 167.37,45.71 167.37,47.57 167.66,47.85 168.14,47.85 168.43,47.57 168.43,45.71 168.56,45.58 168.83,45.58 168.97,45.71 168.97,47.57 169.26,47.85 169.74,47.85 170.03,47.57 170.03,45.71 170.16,45.58 170.43,45.58 170.57,45.71 170.57,47.57 170.86,47.85 171.34,47.85 171.63,47.57 171.63,45.71 171.76,45.58 172.03,45.58 172.17,45.71 172.17,47.57 172.46,47.85 172.94,47.85 173.23,47.57 173.23,45.71 173.37,45.58 173.63,45.58 173.77,45.71 173.77,47.57 174.06,47.85 174.54,47.85 174.83,47.57 174.83,45.71 174.97,45.58 175.57,45.58 175.71,45.71 175.71,46.63 176,46.92 176.55,46.92 176.84,46.63 176.84,45.71 176.97,45.58 177.64,45.58 182.83,40.39 183.26,40.39 183.42,40.55 183.8,40.55 183.96,40.39 184.33,40.39 184.46,40.52 184.91,40.52 185.04,40.39 186.3,40.39 186.68,40.77 187.34,40.77 v1(187.53,40.95)
  BOTTOM w0.157: P4.113 187.83,41.25 v1(187.53,40.95)
DDR3_CPU_CH1_CK_DN1: length 92.8
  TOP w0.157: v1(141.99,29.09) 142.05,29.09 142.35,29.39 U14.H9
  L8_SIG w0.102: 147.55,27.84 147.52,27.84 147.49,27.81 146.44,27.81 145.92,28.32 144.69,28.32 144.18,27.81 143.76,27.81 142.77,28.8 142.28,28.8 v1(141.99,29.09)
  L8_SIG w0.135: 147.55,27.84 148.18,27.84 148.34,27.69 159.77,27.69 163.7,31.62 163.7,43.17 163.98,43.46 164.4,43.46 164.53,43.6 164.53,43.86 164.4,44 163.98,44 163.7,44.29 163.7,44.77 163.98,45.06 164.4,45.06 164.53,45.2 164.53,45.46 164.4,45.6 163.98,45.6 163.7,45.89 163.7,46.37 163.98,46.66 164.4,46.66 164.53,46.8 164.53,47.07 164.4,47.2 163.98,47.2 163.7,47.49 163.7,48.58 164.14,49.03 166.92,49.03 167.06,49.16 167.06,49.7 167.35,49.99 167.83,49.99 168.12,49.7 168.12,49.16 168.26,49.03 168.52,49.03 168.66,49.16 168.66,49.72 168.95,50.01 169.43,50.01 169.72,49.72 169.72,49.16 169.86,49.03 170.12,49.03 170.26,49.16 170.26,49.73 170.57,50.05 171.01,50.05 171.32,49.73 171.32,49.16 171.46,49.03 171.72,49.03 171.86,49.16 171.86,49.68 172.15,49.97 172.63,49.97 172.92,49.68 172.92,49.16 173.06,49.03 173.33,49.03 173.46,49.16 173.46,49.58 173.75,49.87 174.23,49.87 174.52,49.58 174.52,49.16 174.66,49.03 174.93,49.03 175.06,49.16 175.06,49.66 175.35,49.94 175.83,49.94 176.12,49.66 176.12,49.16 178.36,46.93 178.36,46.39 183.09,41.66 190.24,41.66 191.17,42.6 193.36,42.6 193.63,42.33 193.95,42.33 194.18,42.1 194.18,41.93 194.18,41.77 194.43,41.53 196.54,41.53 196.62,41.62 v1(196.72,41.62)
  BOTTOM w0.157: P4.114 196.78,41.55 v1(196.72,41.62)
DDR3_CPU_CH1_CK_DP0: length 93.5
  TOP w0.157: U14.C9 142.38,26.8 142.38,26.3 v1(142.38,26.3)
  L8_SIG w0.102: v1(142.38,26.3) 142.39,26.31 143.18,26.31 143.37,26.5 144.6,26.5 144.65,26.55 145.53,26.55 145.72,26.74 146.24,26.74 146.49,26.49 147.46,26.49 147.59,26.62 149.16,26.62 149.47,26.31 150.14,26.31 150.17,26.28 150.2,26.28
  L8_SIG w0.135: v1(188.34,40.77) 187.98,40.77 187.71,40.5 186.79,40.5 186.41,40.12 182.72,40.12 177.53,45.31 176.86,45.31 176.57,45.6 176.57,46.53 176.44,46.66 176.11,46.66 175.97,46.53 175.97,45.6 175.68,45.31 174.86,45.31 174.57,45.6 174.57,47.46 174.43,47.59 174.17,47.59 174.03,47.46 174.03,45.6 173.74,45.31 173.26,45.31 172.97,45.6 172.97,47.46 172.83,47.59 172.57,47.59 172.43,47.46 172.43,45.6 172.14,45.31 171.66,45.31 171.37,45.6 171.37,47.46 171.23,47.59 170.96,47.59 170.83,47.46 170.83,45.6 170.54,45.31 170.06,45.31 169.77,45.6 169.77,47.46 169.63,47.59 169.36,47.59 169.23,47.46 169.23,45.6 168.94,45.31 168.46,45.31 168.17,45.6 168.17,47.46 168.03,47.59 167.76,47.59 167.63,47.46 167.63,45.6 167.34,45.31 166.86,45.31 166.57,45.6 166.57,47.46 166.43,47.59 166.16,47.59 166.03,47.46 166.03,42.71 165.17,41.85 165.17,31.07 160.38,26.28 150.2,26.28
  BOTTOM w0.157: v1(188.34,40.77) 188.45,40.65 P4.111
DDR3_CPU_CH1_CK_DP1: length 92.8
  TOP w0.157: v1(141.98,28.32) 141.98,28.34 U14.G9
  L8_SIG w0.102: v1(141.98,28.32) 141.99,28.32 142.28,28.6 142.69,28.6 143.68,27.61 144.26,27.61 144.77,28.12 145.84,28.12 146.35,27.61 147.49,27.61 147.52,27.58 147.55,27.58
  L8_SIG w0.135: 147.55,27.58 148.07,27.58 148.23,27.42 159.87,27.42 163.96,31.51 163.96,43.06 164.09,43.2 164.51,43.2 164.8,43.49 164.8,43.97 164.51,44.26 164.09,44.26 163.96,44.4 163.96,44.66 164.09,44.8 164.51,44.8 164.8,45.09 164.8,45.57 164.51,45.86 164.09,45.86 163.96,46 163.96,46.27 164.09,46.4 164.51,46.4 164.8,46.69 164.8,47.17 164.51,47.46 164.09,47.46 163.96,47.6 163.96,48.47 164.25,48.77 167.03,48.77 167.32,49.06 167.32,49.59 167.46,49.73 167.72,49.73 167.86,49.59 167.86,49.06 168.15,48.77 168.63,48.77 168.92,49.06 168.92,49.62 169.06,49.75 169.32,49.75 169.46,49.62 169.46,49.06 169.75,48.77 170.23,48.77 170.52,49.06 170.52,49.62 170.68,49.78 170.9,49.78 171.06,49.62 171.06,49.06 171.35,48.77 171.83,48.77 172.12,49.06 172.12,49.57 172.26,49.71 172.52,49.71 172.66,49.57 172.66,49.06 172.95,48.77 173.43,48.77 173.72,49.06 173.72,49.47 173.86,49.61 174.13,49.61 174.26,49.47 174.26,49.06 174.55,48.77 175.03,48.77 175.32,49.06 175.32,49.55 175.46,49.68 175.73,49.68 175.86,49.55 175.86,49.06 178.1,46.82 178.1,46.28 182.98,41.4 190.35,41.4 191.28,42.33 193.25,42.33 194.32,41.27 196.17,41.27 196.64,40.79 v1(196.7,40.79)
  BOTTOM w0.157: P4.112 196.86,40.95 v1(196.7,40.79)
DDR3_CPU_CH1_CKE0: length 92.8
  TOP w0.157: U14.N26 133.76,31.76 134.19,32.18 134.55,32.18 134.56,32.19 v1(134.81,32.19)
  L8_SIG w0.102: 136.91,24.07 136,24.98 136,25.65 134.2,27.45 134.2,28.17 134.18,28.2 134.18,30.07 134.62,30.52 135.38,30.52 135.63,30.77 135.63,31.8 135.26,32.17 134.84,32.17 v1(134.81,32.19)
  L8_SIG w0.191: 136.91,24.07 137.07,24.07 141.77,19.36 142.02,19.36 142.94,18.45 142.94,18.1 142.78,17.94 142.78,16.22 146.99,12 147.94,12 168.91,12 174.33,17.42 174.33,17.68 174.11,17.91 174.11,18.18 174.38,18.45 174.65,18.45 174.87,18.22 175.14,18.22 175.41,18.49 175.41,18.76 175.18,18.98 175.18,19.25 175.45,19.52 175.72,19.52 175.94,19.3 176.21,19.3 176.48,19.57 176.48,19.84 176.26,20.06 176.26,20.33 176.53,20.6 176.8,20.6 177.02,20.38 177.29,20.38 177.56,20.65 177.56,20.92 177.34,21.14 177.34,21.41 177.61,21.68 177.88,21.68 178.1,21.46 178.37,21.46 178.64,21.73 178.64,22 178.42,22.22 178.42,22.49 178.69,22.76 178.96,22.76 179.18,22.54 179.45,22.54 179.72,22.81 179.72,23.07 179.5,23.3 179.5,23.57 179.77,23.84 180.03,23.84 180.26,23.61 180.53,23.61 180.8,23.88 180.8,24.15 180.57,24.37 180.57,24.64 180.84,24.91 181.11,24.91 181.33,24.69 181.6,24.69 181.87,24.96 181.87,25.23 181.65,25.45 181.65,25.72 182.24,26.31 182.51,26.31 182.72,26.11 182.98,26.11 183.25,26.38 183.25,26.65 183.05,26.85 183.05,27.12 186.59,30.66 186.59,31.09 187.27,31.78 189.18,31.78 189.74,32.33 189.74,33.56 189.55,33.75 188.57,33.75 v1(188.39,33.58)
  BOTTOM w0.157: v1(188.39,33.58) 188.45,33.58 188.58,33.45 P4.87
DDR3_CPU_CH1_CKE1: length 94.3
  TOP w0.102: U14.N25 134.41,31.67 134.51,31.57 134.51,31.32 134.71,31.12 134.71,30.27 134.88,30.11 v1(134.9,30.11)
  L8_SIG w0.102: v1(134.9,30.11) 134.9,30.09 134.38,29.57 134.38,28.28 134.41,28.26 134.41,27.66 136.41,25.65 136.41,25.21 139.68,21.94
  L8_SIG w0.191: 139.68,21.94 139.88,21.74 140.36,21.74 143.89,18.21 143.89,16.86 143.89,16.86 143.89,15.91 147.23,12.57 147.7,12.57 168.68,12.57 173.16,17.06 173.16,18.55 173.49,18.88 173.49,19.15 173.1,19.54 173.1,19.86 173.34,20.11 173.61,20.11 174.03,19.69 174.3,19.69 174.57,19.96 174.57,20.23 174.15,20.64 174.15,20.91 174.42,21.18 174.69,21.18 175.11,20.77 175.38,20.77 175.65,21.04 175.65,21.31 175.23,21.72 175.23,21.99 175.5,22.26 175.77,22.26 176.19,21.85 176.46,21.85 176.72,22.12 176.72,22.38 176.31,22.8 176.31,23.07 176.58,23.34 176.85,23.34 177.26,22.92 177.53,22.92 177.8,23.19 177.8,23.46 177.39,23.88 177.39,24.15 177.66,24.42 177.93,24.42 178.34,24 178.61,24 178.88,24.27 178.88,24.54 178.46,24.96 178.46,25.23 178.73,25.5 179,25.5 179.42,25.08 179.69,25.08 179.96,25.35 179.96,25.62 179.54,26.03 179.54,26.3 179.81,26.57 180.08,26.57 180.5,26.16 180.77,26.16 181.04,26.43 181.04,26.7 180.62,27.11 180.62,27.38 180.89,27.65 181.16,27.65 181.58,27.24 181.84,27.24 182.11,27.5 182.11,27.77 181.7,28.19 181.7,28.46 181.97,28.73 182.24,28.73 182.65,28.31 182.92,28.31 183.19,28.58 183.19,28.85 182.79,29.26 182.79,29.53 183.06,29.79 183.33,29.79 183.73,29.39 184,29.39 184.38,29.77 184.38,30.04 184.01,30.4 184.01,30.67 184.28,30.94 184.55,30.94 184.92,30.58 185.19,30.58 187.6,32.99 v1(187.6,33.58)
  BOTTOM w0.157: v1(187.6,33.58) 188.08,34.05 P4.89
DDR3_CPU_CH1_CS_N0: length 94.1
  TOP w0.102: 150.27,30.56 147.87,30.56 147.06,29.74 146.6,29.74 146.5,29.84 145.52,29.84 U14.K3
  TOP w0.157: 150.27,30.56 153.76,30.56 v1(156.6,33.4)
  L8_SIG w0.191: v1(187.58,45.72) 185.75,45.72 182.78,48.69 182.78,58.8 182.42,59.16 180.36,59.16 180.17,59.35 180.17,59.5 179.98,59.69 179.6,59.69 179.41,59.5 179.41,59.35 179.22,59.16 178.84,59.16 178.65,59.35 178.65,59.5 178.46,59.69 178.08,59.69 177.89,59.5 177.89,59.35 177.7,59.16 177.32,59.16 177.13,59.35 177.13,59.5 176.94,59.69 176.55,59.69 176.36,59.5 176.36,59.35 176.17,59.16 175.79,59.16 175.6,59.35 175.6,59.5 175.41,59.69 175.03,59.69 174.84,59.5 174.84,59.35 174.65,59.16 174.27,59.16 174.08,59.35 174.08,59.5 173.89,59.69 173.51,59.69 173.32,59.5 173.32,59.35 173.13,59.16 172.74,59.16 172.55,59.35 172.55,59.5 172.36,59.69 171.98,59.69 171.79,59.5 171.79,59.35 171.6,59.16 171.22,59.16 171.03,59.35 171.03,59.5 170.84,59.69 170.46,59.69 170.27,59.5 170.27,59.35 170.08,59.16 169.7,59.16 169.51,59.35 169.51,59.5 169.32,59.69 168.93,59.69 168.74,59.5 168.74,59.35 168.55,59.16 168.17,59.16 167.98,59.35 167.98,59.5 167.79,59.69 167.41,59.69 167.22,59.5 167.22,59.35 167.03,59.16 166.65,59.16 166.46,59.35 166.46,59.5 166.27,59.69 165.89,59.69 165.7,59.5 165.7,59.35 165.51,59.16 165.07,59.16 164.64,59.59 164.03,59.59 163.6,59.16 163.09,59.16 162.69,59.56 161.95,59.56 161.54,59.16 160.88,59.16 159.97,58.24 159.97,55.89 160.16,55.7 161.51,55.7 161.7,55.51 161.7,55.13 161.51,54.94 160.16,54.94 159.97,54.75 159.97,54.37 160.16,54.18 161.51,54.18 161.7,53.99 161.7,53.61 161.51,53.42 160.16,53.42 159.97,53.23 159.97,51.21 156.6,47.84 v1(156.6,33.4)
  BOTTOM w0.157: v1(187.58,45.72) 187.85,45.45 P4.127
DDR3_CPU_CH1_CS_N1: length 94.3
  TOP w0.157: v1(144.59,32.37) 144.63,32.33 144.63,32.18 U14.N4
  L8_SIG w0.102: v1(144.59,32.37) 145.72,33.5 145.77,33.5
  L8_SIG w0.191: v1(188.34,46.79) 188.26,46.86 187.81,46.86 186.87,47.8 186.87,50.13 187.06,50.32 189.03,50.32 189.48,50.77 189.48,61.01 188.96,61.53 186.91,61.53 184.99,63.45 159.56,63.45 154.36,58.24 154.36,52.47 154.17,52.28 153.92,52.28 153.73,52.09 153.73,51.71 153.92,51.51 154.17,51.51 154.36,51.32 154.36,50.94 154.17,50.75 153.92,50.75 153.73,50.56 153.73,50.18 153.92,49.99 154.17,49.99 154.36,49.8 154.36,34.48 153.87,33.99 150.36,33.99 149.87,33.5 145.77,33.5
  BOTTOM w0.157: v1(188.34,46.79) 188.34,46.34 188.63,46.05 P4.129
DDR3_CPU_CH1_DQ0: length 92.3
  TOP w0.102: U14.B39 127.35,24.87 v1(127.25,24.77)
  BOTTOM w0.102: 128.36,14.46 127.05,15.77 127.05,23.71 127.25,23.91 v1(127.25,24.77)
  BOTTOM w0.157: 128.36,14.46 128.38,14.46 129.62,13.22 131.47,13.22 141.05,3.64 146.51,3.64 147.58,4.7 149.06,4.7 150.13,3.64 150.43,3.64 150.73,3.94 151.06,3.94 151.36,3.64 151.69,3.64 151.99,3.94 152.32,3.94 152.62,3.64 152.95,3.64 153.25,3.94 153.58,3.94 153.88,3.64 154.21,3.64 154.51,3.94 154.84,3.94 155.14,3.64 155.47,3.64 155.77,3.94 156.1,3.94 156.4,3.64 156.73,3.64 157.03,3.94 157.36,3.94 157.66,3.64 157.99,3.64 158.29,3.94 158.62,3.94 158.92,3.64 166.18,3.64 166.34,3.79 166.34,4.39 166.49,4.55 167.98,4.55 168.13,4.39 168.13,3.85 168.29,3.69 168.61,3.69 168.76,3.85 168.76,4.39 168.92,4.55 169.24,4.55 169.39,4.39 169.39,3.85 169.55,3.69 169.87,3.69 170.02,3.85 170.02,4.39 170.18,4.55 170.5,4.55 170.65,4.39 170.65,3.85 170.81,3.69 171.45,3.69 171.61,3.85 171.61,4.57 171.76,4.72 172.08,4.72 172.24,4.57 172.24,3.85 172.39,3.69 173.31,3.69 173.69,4.06 173.69,4.29 173.5,4.47 173.5,4.69 173.73,4.92 173.95,4.92 174.13,4.73 174.35,4.73 174.58,4.96 174.58,5.18 174.39,5.36 174.39,5.58 174.62,5.81 174.84,5.81 175.02,5.62 175.25,5.62 175.47,5.85 175.47,6.07 175.28,6.25 175.28,6.48 175.51,6.7 175.73,6.7 175.91,6.51 176.14,6.51 176.36,6.74 176.36,6.96 176.24,7.08 176.24,7.3 176.46,7.53 176.68,7.53 176.8,7.41 177.03,7.41 177.43,7.81 183.3,7.81 184.48,6.63 188.57,6.63 188.75,6.45 P4.5
DDR3_CPU_CH1_DQ1: length 92.3
  TOP w0.157: U14.D39 127.15,27.15 v1(126.9,27.41)
  BOTTOM w0.102: 127.33,16.32 127.25,16.4 127.25,23.62 127.46,23.83 127.46,23.98 127.79,24.31 127.79,25.48 126.9,26.37 v1(126.9,27.41)
  BOTTOM w0.157: 127.33,16.32 127.34,16.32 128.88,14.78 129.01,14.78 129.93,13.86 131.73,13.86 141.31,4.28 146.25,4.28 147.31,5.34 149.33,5.34 150.05,4.63 159.91,4.63 160.25,4.28 162.89,4.28 163.98,5.36 164.96,5.36 165.4,5.81 165.97,5.81 166.42,5.36 166.73,5.36 166.89,5.52 166.89,6.01 167.05,6.17 167.36,6.17 167.52,6.01 167.52,5.52 167.68,5.36 167.99,5.36 168.15,5.52 168.15,6.01 168.31,6.17 168.62,6.17 168.78,6.01 168.78,5.52 168.94,5.36 169.25,5.36 169.41,5.52 169.41,6.01 169.57,6.17 169.88,6.17 170.04,6.01 170.04,5.52 170.19,5.36 170.51,5.36 170.67,5.52 170.67,6.01 170.82,6.17 171.14,6.17 171.3,6.01 171.3,5.52 171.45,5.36 171.77,5.36 171.93,5.52 171.93,6.01 172.08,6.17 172.4,6.17 172.56,6.01 172.56,5.52 172.71,5.36 173.23,5.36 173.67,5.8 173.67,6.02 173.27,6.42 173.27,6.64 173.5,6.86 173.72,6.86 174.12,6.47 174.34,6.47 174.56,6.69 174.56,6.91 174.2,7.28 174.2,7.5 174.42,7.72 174.64,7.72 174.99,7.37 175.22,7.37 176.3,8.45 183.57,8.45 184.97,7.05 P4.7
DDR3_CPU_CH1_DQ2: length 92.3
  TOP w0.102: v1(129.56,25.68) 129.56,26.09 U14.B35
  BOTTOM w0.102: v1(129.56,25.68) 129.54,25.66 129.54,22.5 129.03,22 129.03,17.93 130.58,16.38
  BOTTOM w0.157: P4.13 188.51,8.85 185.54,11.82 183.86,11.82 183.59,12.09 183.59,12.29 183.43,12.45 183.12,12.45 182.96,12.29 182.96,11.98 182.8,11.82 182.49,11.82 182.33,11.98 182.33,12.29 182.17,12.45 181.86,12.45 181.7,12.29 181.7,11.98 181.54,11.82 181.23,11.82 181.07,11.98 181.07,12.29 180.91,12.45 180.6,12.45 180.44,12.29 180.44,11.98 180.28,11.82 179.97,11.82 179.81,11.98 179.81,12.29 179.65,12.45 179.34,12.45 179.18,12.29 179.18,11.98 179.02,11.82 178.71,11.82 178.55,11.98 178.55,12.29 178.39,12.45 178.08,12.45 177.92,12.29 177.92,11.98 177.76,11.82 177.45,11.82 177.29,11.98 177.29,12.29 177.13,12.45 176.82,12.45 176.66,12.29 176.66,11.98 176.5,11.82 176.19,11.82 176.03,11.98 176.03,12.29 175.87,12.45 175.56,12.45 175.4,12.29 175.4,11.98 175.24,11.82 174.93,11.82 174.77,11.98 174.77,12.29 174.61,12.45 174.3,12.45 174.14,12.29 174.14,11.98 173.98,11.82 173.67,11.82 173.51,11.98 173.51,12.29 173.35,12.45 173.04,12.45 172.88,12.29 172.88,11.98 172.72,11.82 172.41,11.82 172.25,11.98 172.25,12.29 172.09,12.45 171.78,12.45 171.62,12.29 171.62,11.98 171.46,11.82 171.15,11.82 170.99,11.98 170.99,12.29 170.84,12.45 170.52,12.45 170.36,12.29 170.36,11.98 170.21,11.82 169.89,11.82 169.73,11.98 169.73,12.29 169.58,12.45 169.26,12.45 169.1,12.29 169.1,11.98 168.95,11.82 168.63,11.82 168.47,11.98 168.47,12.29 168.32,12.45 168,12.45 167.84,12.29 167.84,11.98 167.69,11.82 167.17,11.82 163.86,8.52 158.87,8.52 157.89,7.54 151.78,7.54 150.81,8.52 150.26,8.52 150.1,8.68 150.1,8.84 149.94,8.99 149.63,8.99 149.47,8.84 149.47,8.68 149.31,8.52 149,8.52 148.84,8.68 148.84,8.84 148.68,8.99 148.37,8.99 148.21,8.84 148.21,8.68 148.05,8.52 147.74,8.52 147.58,8.68 147.58,8.84 147.42,8.99 147.11,8.99 146.95,8.84 146.95,8.68 146.79,8.52 146.48,8.52 146.32,8.68 146.32,8.84 146.16,8.99 145.85,8.99 145.69,8.84 145.69,8.68 145.53,8.52 145.22,8.52 145.06,8.68 145.06,8.84 144.9,8.99 144.59,8.99 144.43,8.84 144.43,8.68 144.27,8.52 143.96,8.52 143.8,8.68 143.8,8.84 143.64,8.99 143.33,8.99 143.17,8.84 143.17,8.68 143.01,8.52 142.7,8.52 142.54,8.68 142.54,8.84 142.38,8.99 142.07,8.99 141.91,8.84 141.91,8.68 141.75,8.52 141.1,8.52 133.23,16.38 130.58,16.38
DDR3_CPU_CH1_DQ3: length 92.4
  TOP w0.157: v1(128.9,27.34) 128.96,27.34 129.04,27.26 U14.D35
  BOTTOM w0.102: v1(128.9,27.34) 130.05,26.19 130.05,22.4 129.39,21.74 129.39,17.93 130.45,16.87
  BOTTOM w0.157: 130.45,16.87 133.64,16.87 140.89,9.63 150.6,9.63 152.04,8.18 152.44,8.18 152.6,8.34 152.6,9.41 152.75,9.56 153.07,9.56 153.23,9.41 153.23,8.34 153.38,8.18 153.7,8.18 153.86,8.34 153.86,9.41 154.01,9.56 154.33,9.56 154.49,9.41 154.49,8.34 154.64,8.18 154.96,8.18 155.12,8.34 155.12,9.41 155.27,9.56 155.59,9.56 155.75,9.41 155.75,8.34 155.9,8.18 156.22,8.18 156.38,8.34 156.38,9.41 156.53,9.56 156.85,9.56 157.01,9.41 157.01,8.34 157.16,8.18 157.63,8.18 158.6,9.16 163.49,9.16 167.89,13.56 168.48,13.56 168.94,13.11 169.66,13.11 170.12,13.56 170.43,13.56 170.59,13.41 170.59,13.35 170.75,13.19 171.06,13.19 171.22,13.35 171.22,13.41 171.38,13.56 171.69,13.56 171.85,13.41 171.85,13.35 172,13.19 172.32,13.19 172.48,13.35 172.48,13.41 172.63,13.56 172.95,13.56 173.11,13.41 173.11,13.35 173.26,13.19 173.52,13.19 173.89,13.56 174.21,13.56 174.57,13.2 174.79,13.2 175.15,13.56 175.47,13.56 175.85,13.19 176.25,13.19 176.63,13.56 177.11,13.56 177.48,13.19 178.16,13.19 178.54,13.56 186.43,13.56 186.77,13.22 186.77,11.22 188.54,9.45 P4.15
DDR3_CPU_CH1_DQ4: length 92.3
  TOP w0.102: v1(126.77,24) 126.77,25.57 U14.A39
  L10_SIG w0.135: v1(195.76,6.15) 195.3,6.15 195.02,5.87 183.3,5.87 v1(182.17,7)
  BOTTOM w0.102: 128.11,13.82 126.82,15.11 126.82,23.95 v1(126.77,24)
  BOTTOM w0.157: v1(182.17,7) 182.17,7 182.03,7.14 178.55,7.14 178.09,6.68 177.87,6.68 177.75,6.79 177.53,6.79 177.3,6.57 177.3,6.35 177.42,6.23 177.42,6.01 177.2,5.78 176.98,5.78 176.86,5.9 176.64,5.9 176.41,5.68 176.41,5.46 176.53,5.34 176.53,5.12 176.31,4.89 176.09,4.89 175.97,5.01 175.74,5.01 175.52,4.79 175.52,4.57 175.64,4.45 175.64,4.23 175.42,4 175.16,4 174.63,3.47 174.63,3.22 174.41,3 149.87,3 148.8,4.06 147.85,4.06 147.45,3.66 147.44,3.66 146.78,3 140.78,3 131.2,12.58 129.36,12.58 128.11,13.82 ; v1(195.76,6.15) P4.4
DDR3_CPU_CH1_DQ5: length 92.4
  TOP w0.102: v1(126.34,23.11) 126.34,25.63 126.75,26.04 U14.C40
  L10_SIG w0.135: v1(196.47,6.73) 196.47,5.82 196.32,5.66 195.19,5.66 194.82,5.3 182.66,5.3 181.69,6.27 v1(178.84,6.27)
  BOTTOM w0.102: 126.62,14.47 126.62,22.83 v1(126.34,23.11)
  BOTTOM w0.157: 126.62,14.47 126.62,14.38 129.06,11.94 130.94,11.94 140.52,2.36 174.92,2.36 v1(178.84,6.27) ; P4.6 196.49,6.75 v1(196.47,6.73)
DDR3_CPU_CH1_DQ6: length 92.3
  TOP w0.102: v1(128.63,23.42) 128.63,23.42 U14.A36
  L10_SIG w0.135: v1(188.06,8.23) 189.33,8.23 190.67,9.57 194.25,9.57 194.41,9.73 196.34,9.73 v1(196.51,9.56)
  BOTTOM w0.102: 131.58,15.34 130.56,15.34 128.47,17.42 128.47,23.27 v1(128.63,23.42)
  BOTTOM w0.157: v1(188.06,8.23) 186.97,8.23 184.94,10.26 174.46,10.26 173.06,8.86 172.55,8.86 172.39,9.02 172.39,9.2 172.21,9.37 171.9,9.37 171.74,9.22 171.74,9.02 171.58,8.86 171.27,8.86 171.11,9.02 171.11,9.22 170.95,9.37 170.64,9.37 170.48,9.22 170.48,9.02 170.32,8.86 169.94,8.86 169.79,9.02 169.79,9.49 169.63,9.65 169.31,9.65 169.16,9.49 169.16,9.02 169,8.86 168.68,8.86 168.53,9.02 168.53,9.49 168.37,9.65 168.05,9.65 167.9,9.49 167.9,9.02 167.74,8.86 167.42,8.86 167.27,9.02 167.27,9.31 167.11,9.47 166.72,9.47 166.57,9.31 166.57,8.83 166.36,8.63 165.88,8.63 164.49,7.24 159.4,7.24 158.42,6.26 151.25,6.26 150.28,7.24 145.08,7.24 143.69,5.85 142.67,5.85 142.42,6.1 142.42,7.05 142.23,7.24 140.57,7.24 132.47,15.34 131.58,15.34 ; v1(196.51,9.56) 196.7,9.75 P4.16
DDR3_CPU_CH1_DQ7: length 92.3
  TOP w0.102: U14.C36 128.84,26.79 128.84,26.03 129.04,25.83 129.04,24.5 v1(129.08,24.46)
  L10_SIG w0.135: v1(196.55,10.46) 194.84,10.46 194.59,10.72 190.91,10.72 189.37,9.18 v1(187.37,9.18)
  BOTTOM w0.102: 130.76,15.9 130.29,15.9 128.73,17.46 128.73,22.48 129.08,22.83 v1(129.08,24.46)
  BOTTOM w0.157: v1(187.37,9.18) 186.93,9.18 185.07,11.04 174.33,11.04 173.59,10.29 171.99,10.29 171.83,10.45 171.83,10.74 171.67,10.9 171.36,10.9 171.2,10.74 171.2,10.45 171.04,10.29 170.73,10.29 170.57,10.45 170.57,10.74 170.41,10.9 170.1,10.9 169.94,10.74 169.94,10.45 169.78,10.29 169.32,10.29 169.16,10.45 169.16,11.02 169.01,11.18 168.69,11.18 168.53,11.02 168.53,10.45 168.38,10.29 168.06,10.29 167.9,10.45 167.9,10.92 167.7,11.12 167.48,11.12 167.27,10.92 167.27,10.45 167.12,10.29 166.54,10.29 164.13,7.88 159.13,7.88 158.16,6.9 151.51,6.9 150.54,7.88 144.81,7.88 143.69,6.76 143.23,6.76 143.06,6.92 143.06,7.67 142.86,7.88 140.83,7.88 132.81,15.9 130.76,15.9 ; v1(196.55,10.46) 196.62,10.46 196.74,10.35 P4.18
DDR3_CPU_CH1_DQ8: length 86.9
  TOP w0.102: v1(131.87,18.87) 131.64,19.1 131.64,21.8 131.22,22.22 131.22,24.88 130.86,25.24 130.86,26.21 U14.B32
  L10_SIG w0.135: v1(131.87,18.87) 131.87,14.07 135.76,10.18 136.34,10.18 137.32,9.2 137.61,9.2 137.74,9.34 137.74,9.39 137.88,9.53 138.14,9.53 138.28,9.39 138.28,9.34 138.41,9.2 138.68,9.2 138.82,9.34 138.82,9.39 138.95,9.53 139.22,9.53 139.36,9.39 139.36,9.34 139.49,9.2 139.76,9.2 139.89,9.34 139.89,9.39 140.03,9.53 140.3,9.53 140.43,9.39 140.43,9.34 140.57,9.2 140.84,9.2 140.97,9.34 140.97,9.39 141.11,9.53 141.38,9.53 141.51,9.39 141.51,9.34 141.64,9.2 141.91,9.2 142.05,9.34 142.05,9.39 142.18,9.53 142.45,9.53 142.59,9.39 142.59,9.34 142.72,9.2 142.99,9.2 143.13,9.34 143.13,9.39 143.26,9.53 143.53,9.53 143.66,9.39 143.66,9.34 143.8,9.2 144.07,9.2 144.2,9.34 144.2,9.39 144.34,9.53 144.61,9.53 144.74,9.39 144.74,9.34 144.88,9.2 145.14,9.2 145.28,9.34 145.28,9.39 145.41,9.53 145.68,9.53 145.82,9.39 145.82,9.34 145.95,9.2 146.22,9.2 146.36,9.34 146.36,9.39 146.49,9.53 146.76,9.53 146.9,9.39 146.9,9.34 147.03,9.2 147.3,9.2 147.43,9.34 147.43,9.39 147.57,9.53 147.84,9.53 147.97,9.39 147.97,9.34 148.11,9.2 148.38,9.2 148.51,9.34 148.51,9.39 148.65,9.53 148.91,9.53 149.05,9.39 149.05,9.34 149.18,9.2 149.45,9.2 149.59,9.34 149.59,9.39 149.72,9.53 149.99,9.53 150.13,9.39 150.13,9.34 150.26,9.2 150.53,9.2 150.66,9.34 150.66,9.39 150.8,9.53 151.07,9.53 151.2,9.39 151.2,9.34 151.34,9.2 151.61,9.2 151.74,9.34 151.74,9.39 151.88,9.53 152.15,9.53 152.28,9.39 152.28,9.34 152.41,9.2 152.68,9.2 152.82,9.34 152.82,9.39 152.95,9.53 153.22,9.53 153.36,9.39 153.36,9.34 153.49,9.2 153.76,9.2 153.9,9.34 153.9,9.39 154.03,9.53 154.3,9.53 154.43,9.39 154.43,9.34 154.57,9.2 154.84,9.2 154.97,9.34 154.97,9.39 155.11,9.53 155.38,9.53 155.51,9.39 155.51,9.34 155.65,9.2 155.91,9.2 156.05,9.34 156.05,9.39 156.18,9.53 156.45,9.53 156.59,9.39 156.59,9.34 156.72,9.2 156.99,9.2 157.13,9.34 157.13,9.39 157.26,9.53 157.53,9.53 157.66,9.39 157.66,9.34 157.8,9.2 158.07,9.2 158.2,9.34 158.2,9.39 158.34,9.53 158.61,9.53 158.74,9.39 158.74,9.34 158.88,9.2 159.15,9.2 159.28,9.34 159.28,9.39 159.41,9.53 159.68,9.53 159.82,9.39 159.82,9.34 159.95,9.2 160.22,9.2 160.36,9.34 160.36,9.39 160.49,9.53 160.76,9.53 160.9,9.39 160.9,9.34 161.03,9.2 161.3,9.2 161.43,9.34 161.43,9.39 161.57,9.53 161.84,9.53 161.97,9.39 161.97,9.34 162.11,9.2 162.38,9.2 162.51,9.34 162.51,9.39 162.65,9.53 162.91,9.53 163.05,9.39 163.05,9.34 163.18,9.2 163.45,9.2 163.59,9.34 163.59,9.39 163.72,9.53 163.99,9.53 164.13,9.39 164.13,9.34 164.26,9.2 164.53,9.2 164.66,9.34 164.66,9.39 164.8,9.53 165.07,9.53 165.2,9.39 165.2,9.34 165.34,9.2 165.61,9.2 165.74,9.34 165.74,9.39 165.88,9.53 166.15,9.53 166.28,9.39 166.28,9.34 166.41,9.2 166.68,9.2 166.82,9.34 166.82,9.39 166.95,9.53 167.22,9.53 167.36,9.39 167.36,9.34 167.49,9.2 167.76,9.2 167.9,9.34 167.9,9.39 168.03,9.53 168.3,9.53 168.43,9.39 168.43,9.34 168.57,9.2 168.84,9.2 168.97,9.34 168.97,9.39 169.11,9.53 169.38,9.53 169.51,9.39 169.51,9.34 169.65,9.2 169.92,9.2 170.05,9.34 170.05,9.39 170.18,9.53 170.45,9.53 170.59,9.39 170.59,9.34 170.72,9.2 170.99,9.2 171.13,9.34 171.13,9.39 171.26,9.53 171.53,9.53 171.67,9.39 171.67,9.34 171.8,9.2 172.07,9.2 172.2,9.34 172.2,9.39 172.34,9.53 172.61,9.53 172.74,9.39 172.74,9.34 172.88,9.2 173.15,9.2 173.28,9.34 173.28,9.39 173.42,9.53 173.68,9.53 173.82,9.39 173.82,9.34 173.95,9.2 174.22,9.2 174.36,9.34 174.36,9.39 174.49,9.53 174.76,9.53 174.9,9.39 174.9,9.34 175.03,9.2 175.3,9.2 175.43,9.34 175.43,9.39 175.57,9.53 175.84,9.53 175.97,9.39 175.97,9.34 176.11,9.2 176.38,9.2 176.51,9.34 176.51,9.39 176.65,9.53 176.92,9.53 177.05,9.39 177.05,9.34 177.18,9.2 177.45,9.2 177.59,9.34 177.59,9.39 177.72,9.53 177.99,9.53 178.13,9.39 178.13,9.34 178.26,9.2 178.53,9.2 178.67,9.34 178.67,9.39 178.8,9.53 179.07,9.53 179.2,9.39 179.2,9.34 179.34,9.2 179.61,9.2 179.85,9.45 180.11,9.45 180.36,9.2 180.73,9.2 180.98,9.45 181.43,9.45 181.68,9.2 182.02,9.2 182.25,9.42 182.53,9.42 182.75,9.2 183,9.2 184.36,10.57 188.09,10.57 188.32,10.79 v1(188.34,10.79)
  BOTTOM w0.157: P4.19 188.49,10.65 v1(188.34,10.79)
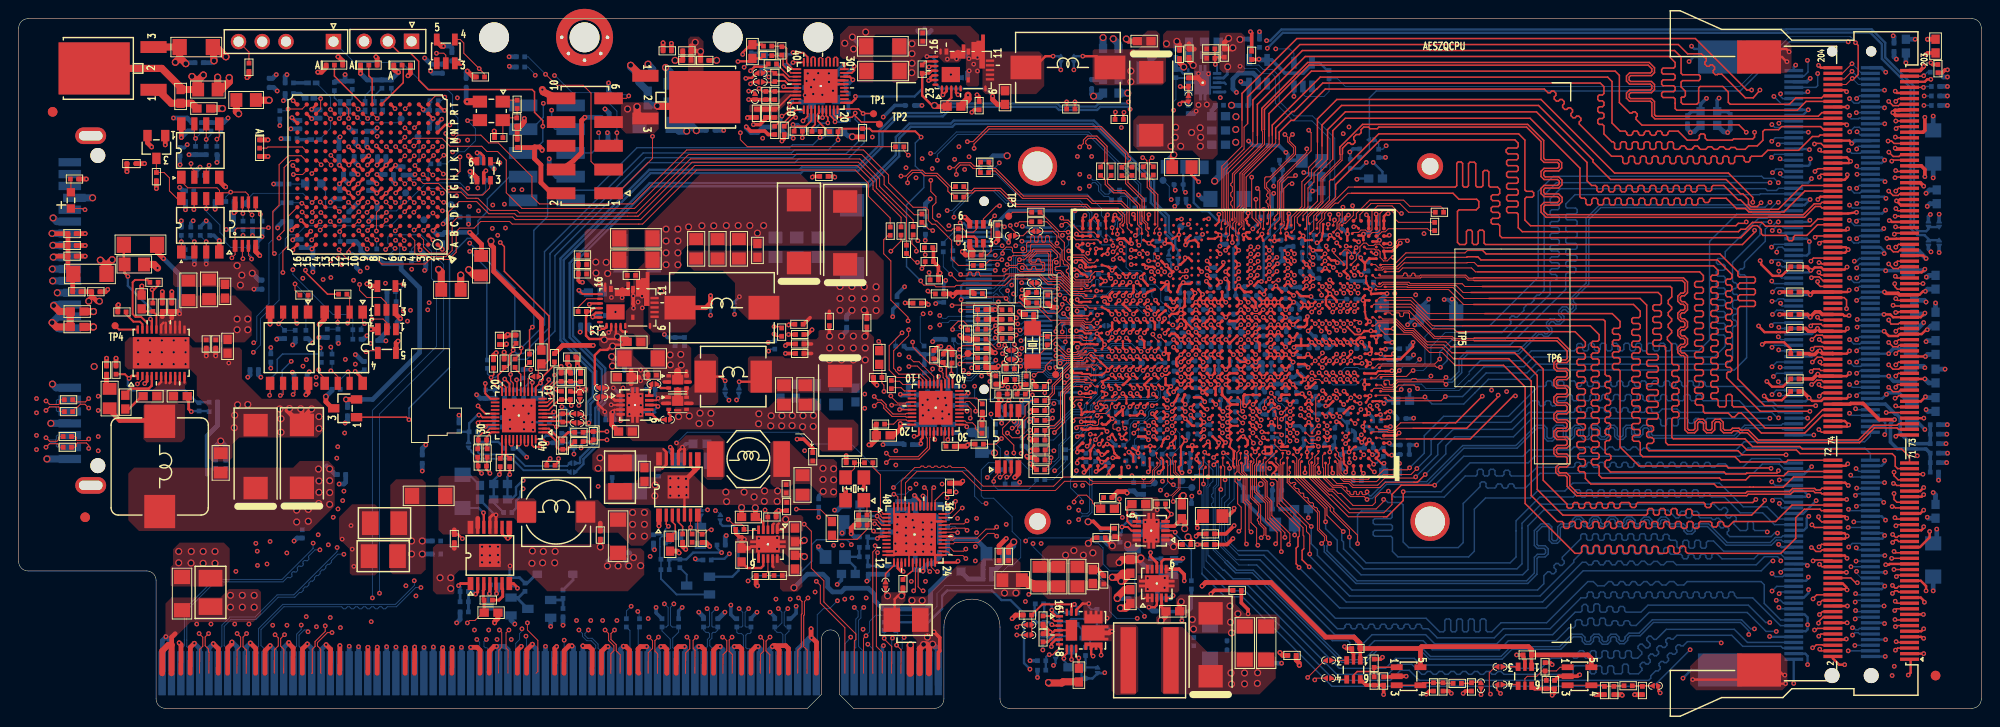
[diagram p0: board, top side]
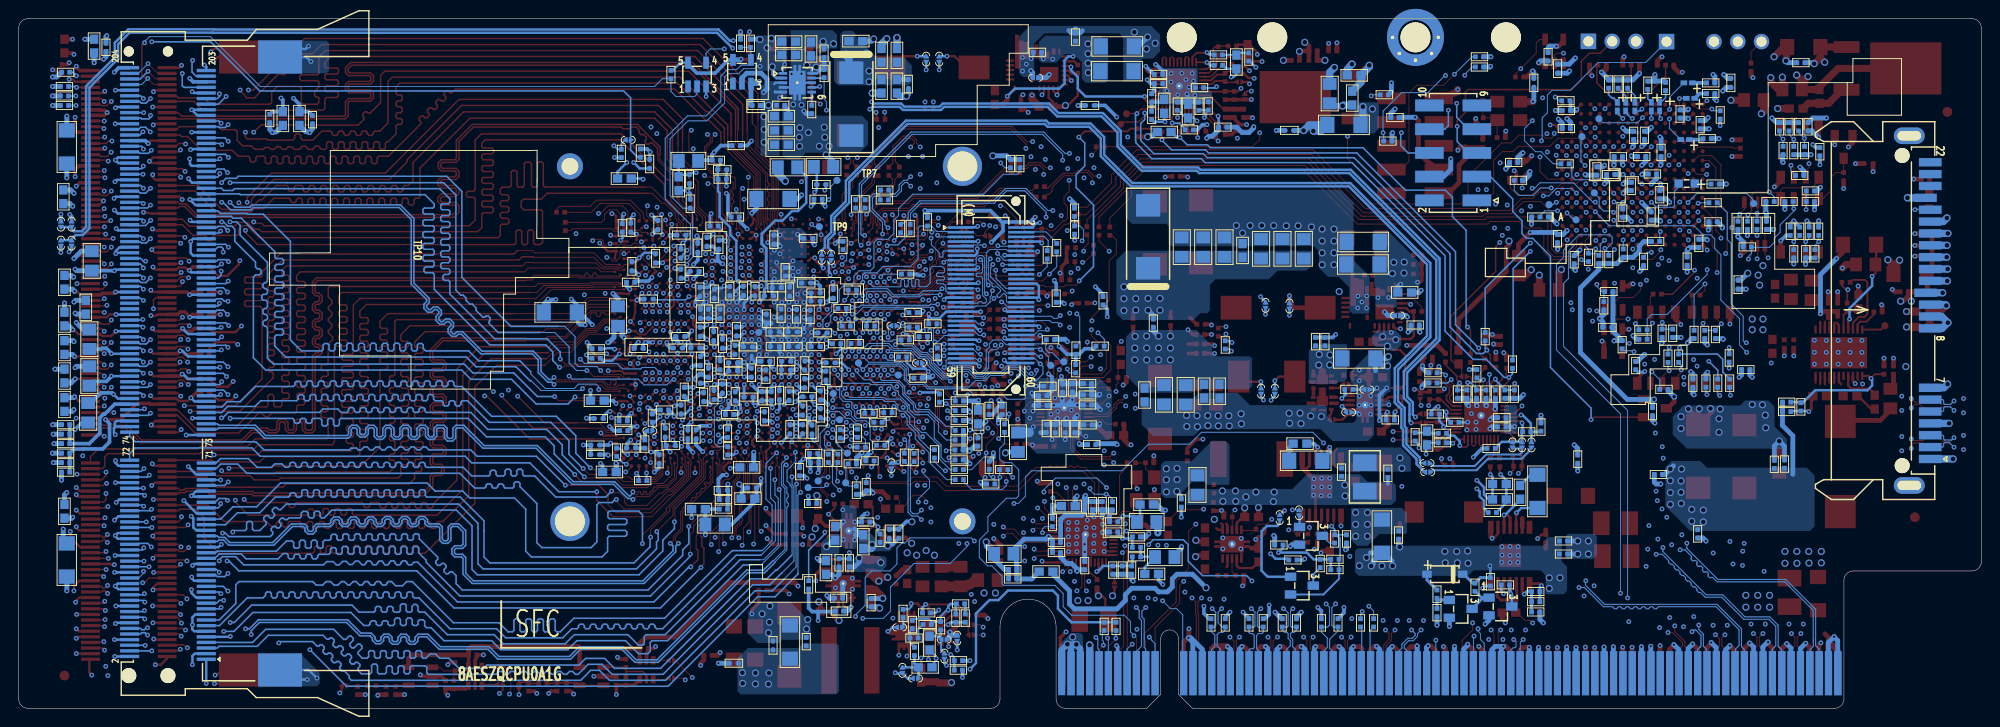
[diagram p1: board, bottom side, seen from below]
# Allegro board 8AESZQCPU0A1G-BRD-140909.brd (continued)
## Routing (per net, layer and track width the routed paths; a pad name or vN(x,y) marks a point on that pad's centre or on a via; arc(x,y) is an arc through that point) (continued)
DDR3_CPU_CH1_DQ9: length 86.9
  TOP w0.102: v1(132.59,17.45) 132.59,17.48 132.46,17.6 132.46,19.28 131.86,19.88 131.86,21.89 131.42,22.32 131.42,24.97 131.07,25.33 131.07,25.97 131.25,26.16 U14.C31
  L10_SIG w0.135: v1(188.06,11.56) 187.99,11.56 187.58,11.15 184.15,11.15 183.06,10.06 182.78,10.06 182.45,10.39 182.14,10.39 181.83,10.08 181.64,10.08 181.31,10.41 180.99,10.41 180.66,10.09 180.45,10.09 180.31,10.23 180.31,10.28 180.18,10.41 179.91,10.41 179.78,10.28 179.78,10.23 179.64,10.09 179.37,10.09 179.24,10.23 179.24,10.28 179.1,10.41 178.83,10.41 178.7,10.28 178.7,10.23 178.56,10.09 178.29,10.09 178.16,10.23 178.16,10.28 178.03,10.41 177.76,10.41 177.62,10.28 177.62,10.23 177.49,10.09 177.22,10.09 177.08,10.23 177.08,10.28 176.95,10.41 176.68,10.41 176.54,10.28 176.54,10.23 176.41,10.09 176.14,10.09 176.01,10.23 176.01,10.28 175.87,10.41 175.6,10.41 175.47,10.28 175.47,10.23 175.33,10.09 175.06,10.09 174.93,10.23 174.93,10.28 174.79,10.41 174.52,10.41 174.39,10.28 174.39,10.23 174.26,10.09 173.99,10.09 173.85,10.23 173.85,10.28 173.72,10.41 173.45,10.41 173.31,10.28 173.31,10.23 173.18,10.09 172.91,10.09 172.77,10.23 172.77,10.28 172.64,10.41 172.37,10.41 172.24,10.28 172.24,10.23 172.1,10.09 171.83,10.09 171.7,10.23 171.7,10.28 171.56,10.41 171.29,10.41 171.16,10.28 171.16,10.23 171.02,10.09 170.76,10.09 170.62,10.23 170.62,10.28 170.49,10.41 170.22,10.41 170.08,10.28 170.08,10.23 169.95,10.09 169.68,10.09 169.54,10.23 169.54,10.28 169.41,10.41 169.14,10.41 169.01,10.28 169.01,10.23 168.87,10.09 168.6,10.09 168.47,10.23 168.47,10.28 168.33,10.41 168.06,10.41 167.93,10.28 167.93,10.23 167.79,10.09 167.52,10.09 167.39,10.23 167.39,10.28 167.26,10.41 166.99,10.41 166.85,10.28 166.85,10.23 166.72,10.09 166.45,10.09 166.31,10.23 166.31,10.28 166.18,10.41 165.91,10.41 165.77,10.28 165.77,10.23 165.64,10.09 165.37,10.09 165.24,10.23 165.24,10.28 165.1,10.41 164.83,10.41 164.7,10.28 164.7,10.23 164.56,10.09 164.29,10.09 164.16,10.23 164.16,10.28 164.02,10.41 163.76,10.41 163.62,10.28 163.62,10.23 163.49,10.09 163.22,10.09 163.08,10.23 163.08,10.28 162.95,10.41 162.68,10.41 162.54,10.28 162.54,10.23 162.41,10.09 162.14,10.09 162.01,10.23 162.01,10.28 161.87,10.41 161.6,10.41 161.47,10.28 161.47,10.23 161.33,10.09 161.06,10.09 160.93,10.23 160.93,10.28 160.79,10.41 160.52,10.41 160.39,10.28 160.39,10.23 160.26,10.09 159.99,10.09 159.85,10.23 159.85,10.28 159.72,10.41 159.45,10.41 159.31,10.28 159.31,10.23 159.18,10.09 158.91,10.09 158.77,10.23 158.77,10.28 158.64,10.41 158.37,10.41 158.24,10.28 158.24,10.23 158.1,10.09 157.83,10.09 157.7,10.23 157.7,10.28 157.56,10.41 157.29,10.41 157.16,10.28 157.16,10.23 157.02,10.09 156.76,10.09 156.62,10.23 156.62,10.28 156.49,10.41 156.22,10.41 156.08,10.28 156.08,10.23 155.95,10.09 155.68,10.09 155.54,10.23 155.54,10.28 155.41,10.41 155.14,10.41 155.01,10.28 155.01,10.23 154.87,10.09 154.6,10.09 154.47,10.23 154.47,10.28 154.33,10.41 154.06,10.41 153.93,10.28 153.93,10.23 153.79,10.09 153.52,10.09 153.39,10.23 153.39,10.28 153.25,10.41 152.99,10.41 152.85,10.28 152.85,10.23 152.72,10.09 152.45,10.09 152.31,10.23 152.31,10.28 152.18,10.41 151.91,10.41 151.77,10.28 151.77,10.23 151.64,10.09 151.37,10.09 151.24,10.23 151.24,10.28 151.1,10.41 150.83,10.41 150.7,10.28 150.7,10.23 150.56,10.09 150.29,10.09 150.16,10.23 150.16,10.28 150.02,10.41 149.75,10.41 149.62,10.28 149.62,10.23 149.49,10.09 149.22,10.09 149.08,10.23 149.08,10.28 148.95,10.41 148.68,10.41 148.54,10.28 148.54,10.23 148.41,10.09 148.14,10.09 148,10.23 148,10.28 147.87,10.41 147.6,10.41 147.47,10.28 147.47,10.23 147.33,10.09 147.06,10.09 146.93,10.23 146.93,10.28 146.79,10.41 146.52,10.41 146.39,10.28 146.39,10.23 146.25,10.09 145.99,10.09 145.85,10.23 145.85,10.28 145.72,10.41 145.45,10.41 145.31,10.28 145.31,10.23 145.18,10.09 144.91,10.09 144.77,10.23 144.77,10.28 144.64,10.41 144.37,10.41 144.24,10.28 144.24,10.23 144.1,10.09 143.83,10.09 143.7,10.23 143.7,10.28 143.56,10.41 143.29,10.41 143.16,10.28 143.16,10.23 143.02,10.09 142.75,10.09 142.62,10.23 142.62,10.28 142.49,10.41 142.22,10.41 142.08,10.28 142.08,10.23 141.95,10.09 141.68,10.09 141.54,10.23 141.54,10.28 141.41,10.41 141.14,10.41 141,10.28 141,10.23 140.87,10.09 140.6,10.09 140.47,10.23 140.47,10.28 140.33,10.41 140.06,10.41 139.93,10.28 139.93,10.23 139.79,10.09 139.52,10.09 139.39,10.23 139.39,10.28 139.25,10.41 138.99,10.41 138.85,10.28 138.85,10.23 138.72,10.09 138.45,10.09 138.31,10.23 138.31,10.28 138.18,10.41 137.91,10.41 137.77,10.28 137.77,10.23 137.64,10.09 137.23,10.09 136.57,10.75 136,10.75 132.59,14.16 v1(132.59,17.45)
  BOTTOM w0.157: v1(188.06,11.56) 188.52,11.56 188.82,11.25 P4.21
DDR3_CPU_CH1_DQ10: length 86.8
  TOP w0.102: U14.A27 133.13,24.71 133.58,24.26 133.58,22.66 134.09,22.16 134.09,20.63 136.02,18.69 136.02,17.85 135.89,17.73 v1(135.89,17.53)
  L10_SIG w0.135: v1(187.6,14.44) 183.19,14.44 182.75,14 182.75,13.61 182.52,13.39 181.4,13.39 181.26,13.52 181.26,13.89 181.13,14.02 180.86,14.02 180.73,13.89 180.73,13.52 180.59,13.39 180.32,13.39 180.19,13.52 180.19,13.89 180.05,14.02 179.78,14.02 179.65,13.89 179.65,13.52 179.51,13.39 179.25,13.39 179.11,13.52 179.11,13.89 178.98,14.02 178.71,14.02 178.57,13.89 178.57,13.52 178.44,13.39 178.17,13.39 178.03,13.52 178.03,13.89 177.9,14.02 177.63,14.02 177.5,13.89 177.5,13.52 177.36,13.39 177.09,13.39 176.96,13.52 176.96,13.89 176.82,14.02 176.55,14.02 176.42,13.89 176.42,13.52 176.28,13.39 176.01,13.39 175.88,13.52 175.88,13.89 175.75,14.02 175.48,14.02 175.34,13.89 175.34,13.52 175.21,13.39 174.94,13.39 174.8,13.52 174.8,13.89 174.67,14.02 174.4,14.02 174.26,13.89 174.26,13.52 174.13,13.39 173.86,13.39 173.73,13.52 173.73,13.89 173.59,14.02 173.32,14.02 173.19,13.89 173.19,13.52 173.05,13.39 172.78,13.39 172.65,13.52 172.65,13.89 172.51,14.02 172.25,14.02 172.11,13.89 172.11,13.52 171.98,13.39 171.71,13.39 171.57,13.52 171.57,13.89 171.44,14.02 171.17,14.02 171.03,13.89 171.03,13.52 170.9,13.39 170.63,13.39 170.49,13.52 170.49,13.89 170.36,14.02 170.09,14.02 169.96,13.89 169.96,13.52 169.82,13.39 169.55,13.39 169.42,13.52 169.42,13.89 169.28,14.02 169.01,14.02 168.88,13.89 168.88,13.52 168.74,13.39 168.48,13.39 168.34,13.52 168.34,13.89 168.21,14.02 167.94,14.02 167.8,13.89 167.8,13.52 167.67,13.39 167.4,13.39 167.26,13.52 167.26,13.89 167.13,14.02 166.86,14.02 166.73,13.89 166.73,13.52 166.59,13.39 166.32,13.39 166.19,13.52 166.19,13.89 166.05,14.02 165.78,14.02 165.65,13.89 165.65,13.52 165.51,13.39 165.24,13.39 165.11,13.52 165.11,13.89 164.98,14.02 164.71,14.02 164.57,13.89 164.57,13.52 164.44,13.39 164.17,13.39 164.03,13.52 164.03,13.89 163.9,14.02 163.63,14.02 163.49,13.89 163.49,13.52 163.36,13.39 163.09,13.39 162.96,13.52 162.96,13.89 162.82,14.02 162.55,14.02 162.42,13.89 162.42,13.52 162.28,13.39 162.01,13.39 161.88,13.52 161.88,13.89 161.74,14.02 161.48,14.02 161.34,13.89 161.34,13.52 161.21,13.39 160.94,13.39 160.8,13.52 160.8,13.89 160.67,14.02 160.4,14.02 160.26,13.89 160.26,13.52 160.13,13.39 159.87,13.39 159.13,14.12 138.4,14.12 138.23,14.3 137.74,14.3 137.56,14.12 136.8,14.12 135.89,15.04 v1(135.89,17.53)
  BOTTOM w0.157: P4.31 188.9,14.25 188.75,14.1 187.94,14.1 v1(187.6,14.44)
DDR3_CPU_CH1_DQ11: length 86.8
  TOP w0.102: v1(135.49,18.29) 135.49,18.79 133.88,20.39 133.88,22.07 133.37,22.58 133.37,24.18 132.85,24.7 132.85,25.96 133.17,26.27 133.17,26.61 U14.C27
  L10_SIG w0.135: v1(188.54,14.56) 187.99,15.11 185.85,15.11 185.72,15.25 185.72,15.77 185.58,15.9 185.31,15.9 185.18,15.77 185.18,15.25 185.04,15.11 184.78,15.11 184.64,15.25 184.64,15.74 184.51,15.88 184.24,15.88 184.1,15.74 184.1,15.25 183.97,15.11 183.03,15.11 182.68,14.76 181.97,14.76 181.64,15.09 181.25,15.09 180.92,14.76 180.29,14.76 179.96,15.09 179.6,15.09 179.27,14.76 178.97,14.76 178.64,15.09 178.33,15.09 178,14.76 177.65,14.76 177.32,15.09 176.91,15.09 176.58,14.76 176.2,14.76 175.87,15.09 175.56,15.09 175.23,14.76 174.9,14.76 174.57,15.09 174.25,15.09 173.92,14.76 173.65,14.76 173.51,14.89 173.51,14.95 173.38,15.09 173.11,15.09 172.98,14.95 172.98,14.89 172.84,14.76 172.57,14.76 172.44,14.89 172.44,14.95 172.3,15.09 172.03,15.09 171.9,14.95 171.9,14.89 171.76,14.76 171.49,14.76 171.36,14.89 171.36,14.95 171.23,15.09 170.96,15.09 170.82,14.95 170.82,14.89 170.69,14.76 170.42,14.76 170.28,14.89 170.28,14.95 170.15,15.09 169.88,15.09 169.74,14.95 169.74,14.89 169.61,14.76 169.34,14.76 169.21,14.89 169.21,14.95 169.07,15.09 168.8,15.09 168.67,14.95 168.67,14.89 168.53,14.76 168.26,14.76 168.13,14.89 168.13,14.95 167.99,15.09 167.73,15.09 167.59,14.95 167.59,14.89 167.46,14.76 167.19,14.76 167.05,14.89 167.05,14.95 166.92,15.09 166.65,15.09 166.51,14.95 166.51,14.89 166.38,14.76 166.11,14.76 165.98,14.89 165.98,14.95 165.84,15.09 165.57,15.09 165.44,14.95 165.44,14.89 165.3,14.76 165.03,14.76 164.9,14.89 164.9,14.95 164.76,15.09 164.49,15.09 164.36,14.95 164.36,14.89 164.23,14.76 163.96,14.76 163.82,14.89 163.82,14.95 163.69,15.09 163.42,15.09 163.28,14.95 163.28,14.89 163.15,14.76 162.88,14.76 162.74,14.89 162.74,14.95 162.61,15.09 162.34,15.09 162.21,14.95 162.21,14.89 162.07,14.76 161.8,14.76 161.67,14.89 161.67,14.95 161.53,15.09 161.26,15.09 161.13,14.95 161.13,14.89 160.99,14.76 160.73,14.76 160.59,14.89 160.59,14.95 160.46,15.09 160.19,15.09 160.05,14.95 160.05,14.89 159.92,14.76 159.65,14.76 159.51,14.89 159.51,14.95 159.38,15.09 159.11,15.09 158.98,14.95 158.98,14.89 158.84,14.76 158.57,14.76 158.44,14.89 158.44,14.95 158.3,15.09 158.03,15.09 157.9,14.95 157.9,14.89 157.76,14.76 157.49,14.76 157.36,14.89 157.36,14.95 157.22,15.09 156.96,15.09 156.82,14.95 156.82,14.89 156.69,14.76 156.42,14.76 156.28,14.89 156.28,14.95 156.15,15.09 155.88,15.09 155.74,14.95 155.74,14.89 155.61,14.76 145.16,14.76 145.02,14.89 145.02,15.23 144.89,15.37 144.62,15.37 144.48,15.23 144.48,14.89 144.35,14.76 143.85,14.76 143.71,14.89 143.71,16.05 143.58,16.18 143.31,16.18 143.18,16.05 143.18,14.89 143.04,14.76 142.77,14.76 142.64,14.89 142.64,16.05 142.5,16.18 142.23,16.18 142.1,16.05 142.1,14.89 141.96,14.76 141.7,14.76 141.56,14.89 141.56,16.05 141.43,16.18 141.16,16.18 141.02,16.05 141.02,14.89 140.89,14.76 140.53,14.76 139.97,15.31 139.97,15.5 140.27,15.8 140.27,15.99 140.08,16.18 139.89,16.18 139.65,15.94 139.46,15.94 139.21,16.18 139.21,16.74 136.95,19 135.86,19 135.49,18.62 v1(135.49,18.29)
  BOTTOM w0.157: v1(188.54,14.56) 188.54,14.58 188.81,14.85 P4.33
DDR3_CPU_CH1_DQ12: length 86.8
  TOP w0.102: v1(130.56,18.95) 130.81,19.2 130.81,21.51 130.43,21.89 130.43,24 130.15,24.28 130.15,25.12 130.37,25.34 130.37,25.95 130.3,26.01 130.3,26.53 130.34,26.57 130.34,27.35 130.58,27.59 U14.E32
  L10_SIG w0.135: v1(196.51,11.37) 196.35,11.53 193.52,11.53 192.9,12.16 191.33,12.16 189.03,9.86 185.37,9.86 183.58,8.07 136.29,8.07 136.28,8.08 136.26,8.08 130.56,13.79 v1(130.56,18.95)
  BOTTOM w0.157: P4.22 196.68,11.55 v1(196.51,11.37)
DDR3_CPU_CH1_DQ13: length 86.8
  TOP w0.102: U14.D32 130.75,26.7 130.51,26.45 130.51,26.09 130.57,26.03 130.57,25.25 131.02,24.8 131.02,22.05 131.24,21.83 131.24,17.71 v1(131.37,17.58)
  L10_SIG w0.135: v1(196.55,12.27) 196.42,12.14 194.31,12.14 193.3,13.15 190.31,13.15 190.12,12.96 190.12,12.35 189.94,12.17 189.33,12.17 189.13,11.96 189.13,10.74 188.5,10.12 184.72,10.12 183.24,8.64 136.53,8.64 136.52,8.65 136.5,8.65 136.35,8.8 136.35,9.29 136.21,9.43 135.71,9.43 131.12,14.02 131.12,17.33 v1(131.37,17.58)
  BOTTOM w0.157: v1(196.55,12.27) 196.66,12.15 P4.24
DDR3_CPU_CH1_DQ14: length 86.9
  TOP w0.102: v1(134.49,17.6) 134.66,17.77 134.66,18.84 133.43,20.07 133.43,21.94 132.23,23.14 132.23,25.97 132.46,26.2 132.46,26.75 132.75,27.04 U14.D28
  L10_SIG w0.135: v1(196.05,15.15) 195.31,15.15 193.75,13.59 189.81,13.59 189.46,13.23 184.1,13.23 182.67,11.81 158.99,11.81 158.85,11.94 158.85,12.64 158.72,12.78 158.45,12.78 158.31,12.64 158.31,11.94 158.18,11.81 157.91,11.81 157.77,11.94 157.77,12.64 157.64,12.78 157.37,12.78 157.24,12.64 157.24,11.94 157.1,11.81 156.83,11.81 156.7,11.94 156.7,12.64 156.56,12.78 156.29,12.78 156.16,12.64 156.16,11.94 156.02,11.81 155.76,11.81 155.62,11.94 155.62,12.64 155.49,12.78 155.22,12.78 155.08,12.64 155.08,11.97 154.95,11.84 154.56,11.84 153.42,12.97 137.74,12.97 137.52,12.75 135.97,12.75 134.49,14.22 v1(134.49,17.6)
  BOTTOM w0.157: P4.34 v1(196.05,15.15)
DDR3_CPU_CH1_DQ15: length 86.8
  TOP w0.102: U14.B28 132.67,26.3 132.67,26.12 132.44,25.89 132.44,24.18 132.44,24.18 132.44,23.22 133.65,22 133.65,20.27 135.06,18.86 135.06,16.8 v1(135.1,16.76)
  L10_SIG w0.135: v1(196.6,15.75) 196.45,15.61 195.82,15.61 195.82,15.6 194.57,15.6 193.55,14.58 189.89,14.58 189.11,13.8 183.86,13.8 182.44,12.37 180.56,12.37 180.26,12.67 179.78,12.67 179.48,12.37 179.01,12.37 178.71,12.67 178.26,12.67 177.96,12.37 177.72,12.37 177.35,12.74 177.01,12.74 176.64,12.37 176.28,12.37 176.14,12.51 176.14,12.64 176.01,12.78 175.74,12.78 175.6,12.64 175.6,12.51 175.47,12.37 175.2,12.37 175.07,12.51 175.07,12.64 174.93,12.78 174.66,12.78 174.53,12.64 174.53,12.51 174.39,12.37 174.12,12.37 173.99,12.51 173.99,12.64 173.85,12.78 173.58,12.78 173.45,12.64 173.45,12.51 173.32,12.37 173.05,12.37 172.91,12.51 172.91,12.64 172.78,12.78 172.51,12.78 172.37,12.64 172.37,12.51 172.24,12.37 171.97,12.37 171.83,12.51 171.83,12.64 171.7,12.78 171.43,12.78 171.3,12.64 171.3,12.51 171.16,12.37 170.89,12.37 170.76,12.51 170.76,12.64 170.62,12.78 170.35,12.78 170.22,12.64 170.22,12.51 170.08,12.37 169.82,12.37 169.68,12.51 169.68,12.64 169.55,12.78 169.28,12.78 169.14,12.64 169.14,12.51 169.01,12.37 168.74,12.37 168.6,12.51 168.6,12.64 168.47,12.78 168.2,12.78 168.07,12.64 168.07,12.51 167.93,12.37 167.66,12.37 167.53,12.51 167.53,12.64 167.39,12.78 167.12,12.78 166.99,12.64 166.99,12.51 166.85,12.37 166.58,12.37 166.45,12.51 166.45,12.64 166.32,12.78 166.05,12.78 165.91,12.64 165.91,12.51 165.78,12.37 165.51,12.37 165.37,12.51 165.37,12.64 165.24,12.78 164.97,12.78 164.83,12.64 164.83,12.51 164.7,12.37 164.43,12.37 164.3,12.51 164.3,12.64 164.16,12.78 163.89,12.78 163.76,12.64 163.76,12.51 163.62,12.37 163.35,12.37 163.22,12.51 163.22,12.64 163.08,12.78 162.82,12.78 162.68,12.64 162.68,12.51 162.55,12.37 162.28,12.37 162.14,12.51 162.14,12.64 162.01,12.78 161.74,12.78 161.6,12.64 161.6,12.51 161.47,12.37 161.2,12.37 161.06,12.51 161.06,12.64 160.93,12.78 160.66,12.78 160.53,12.64 160.53,12.51 160.39,12.37 160.04,12.37 158.88,13.54 137.01,13.54 136.78,13.32 136.2,13.32 135.1,14.42 v1(135.1,16.76)
  BOTTOM w0.157: P4.36 v1(196.6,15.75)
DDR3_CPU_CH1_DQ16: length 80.7
  TOP w0.102: v1(138.14,16.51) 138.14,18.58 137.79,18.92 137.79,19.49 135.06,22.22 135.06,26.08 134.99,26.16 134.99,26.57 135.25,26.83 U14.D23
  BOTTOM w0.157: P4.37 189,16.05 188.52,16.53 186.2,16.53 185.67,16 182.25,16 181.69,16.56 181.32,16.56 181.16,16.4 181.16,16.15 181.01,16 180.69,16 180.53,16.15 180.53,16.33 180.38,16.48 180.06,16.48 179.9,16.33 179.9,16.15 179.75,16 179.43,16 179.27,16.15 179.27,16.33 179.12,16.48 178.8,16.48 178.64,16.33 178.64,16.15 178.49,16 178.17,16 178.01,16.15 178.01,16.33 177.86,16.48 176.8,16.48 176.64,16.64 176.64,17.04 176.49,17.2 176.17,17.2 176.01,17.04 176.01,16.64 175.86,16.48 175.54,16.48 175.38,16.64 175.38,17.17 175.23,17.32 174.91,17.32 174.75,17.17 174.75,16.64 174.6,16.48 174.28,16.48 174.12,16.64 174.12,17.17 173.97,17.32 173.65,17.32 173.49,17.17 173.49,16.64 173.34,16.48 173.02,16.48 172.86,16.64 172.86,17.17 172.71,17.32 172.39,17.32 172.23,17.17 172.23,16.64 172.08,16.48 171.76,16.48 171.6,16.64 171.6,17.17 171.45,17.32 171.13,17.32 170.97,17.17 170.97,16.64 170.82,16.48 170.5,16.48 170.34,16.64 170.34,17.17 170.19,17.32 169.87,17.32 169.71,17.17 169.71,16.64 169.56,16.48 169.24,16.48 169.08,16.64 169.08,17.17 168.93,17.32 168.61,17.32 168.45,17.17 168.45,16.64 168.3,16.48 167.98,16.48 167.82,16.64 167.82,17.17 167.67,17.32 167.35,17.32 167.19,17.17 167.19,16.64 166.4,15.84 166.4,15.63 162.79,12.02 142.39,12.02 138.14,16.27 v1(138.14,16.51)
DDR3_CPU_CH1_DQ17: length 80.7
  TOP w0.102: v1(138.3,19.46) 135.27,22.5 135.27,26.18 U14.B23
  BOTTOM w0.157: v1(138.3,19.46) 138.3,17.61 138.96,16.95 138.96,16.36 142.66,12.66 162.53,12.66 163.19,13.33 163.19,14.2 163.61,14.61 163.83,14.61 164.04,14.4 164.26,14.4 164.49,14.63 164.49,14.85 164.28,15.06 164.28,15.28 164.5,15.5 164.72,15.5 164.93,15.29 165.15,15.29 165.38,15.52 165.38,15.74 165.17,15.95 165.17,16.17 167.14,18.14 167.14,18.51 167.29,18.67 167.61,18.67 167.77,18.51 167.77,18.14 167.92,17.98 168.24,17.98 168.4,18.14 168.4,18.51 168.55,18.67 168.87,18.67 169.03,18.51 169.03,18.14 169.18,17.98 169.5,17.98 169.66,18.14 169.66,18.51 169.81,18.67 170.13,18.67 170.29,18.51 170.29,18.14 170.44,17.98 170.76,17.98 170.92,18.14 170.92,18.51 171.07,18.67 171.39,18.67 171.55,18.51 171.55,18.14 171.7,17.98 172.02,17.98 172.18,18.14 172.18,18.51 172.33,18.67 172.65,18.67 172.81,18.51 172.81,18.14 172.96,17.98 173.28,17.98 173.44,18.14 173.44,18.51 173.59,18.67 173.91,18.67 174.07,18.51 174.07,18.14 174.22,17.98 174.54,17.98 174.7,18.14 174.7,18.51 174.85,18.67 175.17,18.67 175.33,18.51 175.33,18.14 175.48,17.98 175.8,17.98 175.96,18.14 175.96,18.46 176.11,18.62 176.43,18.62 176.59,18.46 176.59,18.14 176.74,17.98 177.28,17.98 177.43,17.83 177.43,17.29 177.59,17.13 177.91,17.13 178.06,17.29 178.06,17.83 178.22,17.98 178.54,17.98 178.69,17.83 178.69,17.29 178.85,17.13 179.17,17.13 179.32,17.29 179.32,17.83 179.48,17.98 179.8,17.98 179.95,17.83 179.95,17.29 180.11,17.13 180.43,17.13 180.58,17.29 180.58,17.75 180.74,17.91 181.34,17.91 182.43,16.81 188.75,16.81 188.91,16.65 P4.39
DDR3_CPU_CH1_DQ18: length 80.7
  TOP w0.102: U14.D19 137.26,26.85 136.96,26.55 136.96,24.85 140.34,21.47 140.34,21.13 142.39,19.08 v1(142.39,18.32)
  BOTTOM w0.157: P4.49 187.87,19.65 186.59,20.92 184.21,20.92 182.52,22.61 181.13,22.61 180.98,22.76 180.98,22.91 180.82,23.06 180.5,23.06 180.35,22.91 180.35,22.76 180.19,22.61 179.87,22.61 179.72,22.76 179.72,23.24 179.56,23.39 179.24,23.39 179.09,23.24 179.09,22.76 178.93,22.61 178.61,22.61 178.46,22.76 178.46,23.24 178.3,23.39 177.98,23.39 177.83,23.24 177.83,22.76 177.67,22.61 177.35,22.61 177.2,22.76 177.2,23.24 177.04,23.39 176.72,23.39 176.57,23.24 176.57,22.76 176.41,22.61 176.09,22.61 175.94,22.76 175.94,23.24 175.78,23.39 175.46,23.39 175.31,23.24 175.31,22.76 175.15,22.61 174.83,22.61 174.68,22.76 174.68,23.24 174.52,23.39 174.2,23.39 174.05,23.24 174.05,22.76 173.89,22.61 173.57,22.61 173.42,22.76 173.42,23.24 173.26,23.39 172.95,23.39 172.79,23.24 172.79,22.76 172.63,22.61 172.32,22.61 172.16,22.76 172.16,23.24 172,23.39 171.69,23.39 171.53,23.24 171.53,22.76 171.37,22.61 171.06,22.61 170.9,22.76 170.9,23.24 170.74,23.39 170.43,23.39 170.27,23.24 170.27,22.76 170.11,22.61 169.8,22.61 169.64,22.76 169.64,23.24 169.48,23.39 169.17,23.39 169.01,23.24 169.01,22.76 168.85,22.61 168.54,22.61 168.38,22.76 168.38,23.24 168.22,23.39 167.91,23.39 167.75,23.24 167.75,22.76 167.59,22.61 167.28,22.61 167.12,22.76 167.12,23.24 166.96,23.39 166.65,23.39 166.49,23.24 166.49,22.76 166.33,22.61 162.75,22.61 160.21,20.06 160.21,19 160.21,19 160.21,16.2 159.58,15.57 144.16,15.57 142.44,17.29 142.44,18.27 v1(142.39,18.32)
DDR3_CPU_CH1_DQ19: length 80.7
  TOP w0.102: U14.B19 137.16,26.29 137.16,24.93 140.72,21.38 140.72,21.07 143.26,18.53 v1(143.26,17.62)
  BOTTOM w0.157: v1(143.26,17.62) 143.26,20.7 143.66,21.11 146.8,21.11 146.95,20.95 146.95,20.46 146.8,20.3 145.09,20.3 144.93,20.14 144.93,19.83 145.09,19.67 146.83,19.67 146.99,19.51 146.99,19.2 146.83,19.04 145.09,19.04 144.93,18.88 144.93,18.57 145.09,18.41 146.83,18.41 146.99,18.25 146.99,16.79 147.58,16.21 155.14,16.21 155.75,16.81 155.75,21.31 156.95,22.5 161.75,22.5 162.49,23.25 165.44,23.25 166.29,24.1 181.99,24.1 184.53,21.56 187.07,21.56 188.39,20.25 P4.51
DDR3_CPU_CH1_DQ20: length 80.7
  TOP w0.102: U14.C24 134.52,26.34 134.85,26.01 134.85,21.9 137.43,19.33 137.43,18.53 137.51,18.44 137.51,17.09
  TOP w0.157: 137.51,17.09 137.33,16.9 137.33,15.9 v1(138.09,15.14)
  L10_SIG w0.135: v1(188.54,15.78) 189,16.23 193.34,16.23 193.83,16.71 196.24,16.71 196.62,17.08 v1(196.62,17.17)
  BOTTOM w0.157: P4.40 196.75,16.95 196.62,17.08 v1(196.62,17.17) ; v1(138.09,15.14) 138.17,15.06 138.36,15.06 142.03,11.38 163.06,11.38 167.3,15.63 167.7,15.63 167.97,15.36 168.29,15.36 168.45,15.51 168.45,15.62 168.6,15.77 168.91,15.77 169.08,15.61 169.08,15.51 169.23,15.36 169.55,15.36 169.71,15.51 169.71,15.6 169.88,15.77 170.15,15.77 170.34,15.59 170.34,15.51 170.49,15.36 170.81,15.36 170.97,15.51 170.97,15.59 171.12,15.75 171.44,15.75 171.6,15.59 171.6,15.51 171.75,15.36 172.07,15.36 172.23,15.51 172.23,15.59 172.38,15.75 172.7,15.75 172.86,15.59 172.86,15.51 173.01,15.36 173.25,15.36 173.64,15.75 173.96,15.75 174.32,15.39 174.62,15.39 174.96,15.72 175.34,15.72 175.7,15.36 176.01,15.36 176.35,15.7 177.04,15.7 177.38,15.36 185.92,15.36 186.79,16.23 188.19,16.23 188.52,15.9 188.52,15.8 v1(188.54,15.78)
DDR3_CPU_CH1_DQ21: length 80.7
  TOP w0.102: U14.D24 134.57,27.45 133.45,26.33 133.45,25.05 133.99,24.51 134.41,24.51 134.65,24.28 134.65,21.66 137.02,19.29 137.02,18.43 136.96,18.37
  TOP w0.157: v1(137,15.08) 137,15.15 136.68,15.46 136.68,17.13 136.89,17.34 136.89,18.29 136.96,18.37
  L10_SIG w0.135: v1(187.71,15.77) 188.57,16.64 193.24,16.64 193.85,17.25 195.72,17.25 195.73,17.26 v1(195.81,17.26)
  BOTTOM w0.157: v1(187.71,15.77) 187.5,15.77 186.45,14.72 167.4,14.72 163.42,10.74 141.33,10.74 v1(137,15.08) ; P4.42 197.16,17.55 197.06,17.65 196.19,17.65 v1(195.81,17.26)
DDR3_CPU_CH1_DQ22: length 80.8
  TOP w0.102: v1(139.84,19.96) 139.84,20.05 139.78,20.11 139.78,21.36 136.55,24.58 136.55,26.22 U14.B21
  L10_SIG w0.135: v1(195.75,19.35) 194.97,19.35 193.73,18.11 188.83,18.11 v1(188.19,18.75)
  BOTTOM w0.157: v1(139.84,19.96) 139.84,19.23 141.08,17.98 141.08,16.83 143.63,14.28 160.92,14.28 161.49,14.86 161.49,19.53 163.17,21.21 176.48,21.21 177.31,20.38 177.59,20.38 177.75,20.54 177.75,20.92 177.91,21.08 178.22,21.08 178.38,20.92 178.38,20.54 178.54,20.38 178.85,20.38 179.01,20.54 179.01,20.87 179.21,21.08 179.57,21.08 179.77,20.88 179.77,20.54 179.93,20.38 181.08,20.38 181.26,20.2 181.52,20.2 181.67,20.34 181.89,20.34 182.11,20.12 182.11,19.9 181.95,19.73 181.95,19.51 182.15,19.31 182.37,19.31 182.53,19.46 182.75,19.46 182.97,19.24 182.97,19.02 182.82,18.86 182.82,18.64 183.08,18.38 187.51,18.38 187.88,18.75 v1(188.19,18.75) ; P4.48 v1(195.75,19.35)
DDR3_CPU_CH1_DQ23: length 80.7
  TOP w0.102: U14.D21 136.75,26.76 136.75,24.71 139.98,21.48 139.98,20.66 v1(141.72,18.92)
  L10_SIG w0.135: v1(187.1,18.87) 187.1,18.87 187.53,19.3 188.59,19.3 189.15,18.75 193.32,18.75 194.44,19.86 196.27,19.86 v1(196.35,19.95)
  BOTTOM w0.157: v1(187.1,18.87) 186.95,19.02 185.77,19.02 185.62,19.18 185.62,19.84 185.46,20 185.14,20 184.99,19.84 184.99,19.18 184.83,19.02 184.2,19.02 183.52,19.7 183.52,19.93 183.78,20.19 183.78,20.41 183.56,20.63 183.34,20.63 183.08,20.37 182.85,20.37 182.63,20.59 182.63,20.82 182.85,21.04 182.85,21.26 182.63,21.48 182.41,21.48 182.19,21.26 181.96,21.26 181.38,21.85 162.9,21.85 160.85,19.8 160.85,19.27 160.85,19.27 160.85,15.46 160.31,14.93 143.9,14.93 141.76,17.06 141.76,17.8 141.57,17.98 141.57,18.66 141.72,18.81 v1(141.72,18.92) ; P4.50 v1(196.35,19.95)
DDR3_CPU_CH1_DQ24: length 78.8
  TOP w0.102: v1(132.12,28.38) 132.06,28.38 131.96,28.48 131.96,28.67 131.72,28.91 U14.H30
  L10_SIG w0.102: 137.48,21.58 134.68,24.38 133.78,24.38 131.81,26.35 131.81,28.07 v1(132.12,28.38)
  L10_SIG w0.135: v1(188.39,21.92) 188.39,21.41 187.99,21.01 183.41,21.01 182.86,20.45 182.86,20.13 182.99,20 183.86,20 184,19.86 184,19.59 183.86,19.46 182.99,19.46 182.86,19.32 182.86,18.02 182.73,17.9 182.1,17.9 181.84,18.16 181.33,18.16 181.07,17.9 180.58,17.9 180.29,18.19 179.7,18.19 179.42,17.9 179.18,17.9 179.05,18.03 179.05,18.1 178.91,18.24 178.64,18.24 178.51,18.1 178.51,18.03 178.37,17.9 178.1,17.9 177.97,18.03 177.97,18.1 177.84,18.24 177.57,18.24 177.43,18.1 177.43,18.03 177.3,17.9 177.03,17.9 176.89,18.03 176.89,18.1 176.76,18.24 176.49,18.24 176.35,18.1 176.35,18.03 176.22,17.9 175.95,17.9 175.82,18.03 175.82,18.1 175.68,18.24 175.41,18.24 175.28,18.1 175.28,18.03 175.14,17.9 174.87,17.9 174.74,18.03 174.74,18.1 174.6,18.24 174.34,18.24 174.2,18.1 174.2,18.03 174.07,17.9 173.8,17.9 173.66,18.03 173.66,18.1 173.53,18.24 173.26,18.24 173.12,18.1 173.12,18.03 172.99,17.9 172.72,17.9 172.59,18.03 172.59,18.1 172.45,18.24 172.18,18.24 172.05,18.1 172.05,18.03 171.91,17.9 171.64,17.9 171.51,18.03 171.51,18.1 171.37,18.24 171.1,18.24 170.97,18.1 170.97,18.03 170.84,17.9 170.57,17.9 170.43,18.03 170.43,18.1 170.3,18.24 170.03,18.24 169.89,18.1 169.89,18.03 169.76,17.9 169.49,17.9 169.35,18.03 169.35,18.1 169.22,18.24 168.95,18.24 168.82,18.1 168.82,18.03 168.68,17.9 168.41,17.9 168.28,18.03 168.28,18.1 168.14,18.24 167.87,18.24 167.74,18.1 167.74,18.03 167.6,17.9 167.33,17.9 167.2,18.03 167.2,18.1 167.07,18.24 166.8,18.24 166.66,18.1 166.66,18.03 166.53,17.9 166.26,17.9 166.12,18.03 166.12,18.1 165.99,18.24 165.72,18.24 165.58,18.1 165.58,18.03 165.45,17.9 165.18,17.9 165.05,18.03 165.05,18.1 164.91,18.24 164.64,18.24 164.51,18.1 164.51,18.03 164.37,17.9 164.1,17.9 163.97,18.03 163.97,18.1 163.83,18.24 163.57,18.24 163.43,18.1 163.43,18.03 163.3,17.9 163.03,17.9 162.89,18.03 162.89,18.1 162.76,18.24 162.49,18.24 162.35,18.1 162.35,18.03 162.22,17.9 161.95,17.9 161.72,18.13 161.3,18.13 161.2,18.03 160.18,18.03 158.7,19.51 155.35,19.51 152.84,17 146.47,17 142.01,21.46 137.6,21.46 137.48,21.58
  BOTTOM w0.157: P4.55 188.66,21.45 188.39,21.72 v1(188.39,21.92)
DDR3_CPU_CH1_DQ25: length 78.7
  TOP w0.102: U14.H29 132.88,28.63 v1(132.88,28.39)
  L10_SIG w0.102: 139.35,22.07 137.27,22.07 134.77,24.58 134.04,24.58 132.8,25.82 132.8,28.31 v1(132.88,28.39)
  L10_SIG w0.135: 139.35,22.07 142.24,22.07 146.75,17.57 152.6,17.57 155.23,20.19 159.05,20.19 160.32,18.92 160.69,18.92 160.82,19.06 160.82,19.12 160.96,19.25 161.23,19.25 161.36,19.12 161.36,18.96 161.5,18.82 161.76,18.82 161.9,18.96 161.9,19.12 162.03,19.25 162.3,19.25 162.44,19.12 162.44,18.96 162.57,18.82 162.84,18.82 162.98,18.96 162.98,19.12 163.11,19.25 163.38,19.25 163.52,19.12 163.52,18.96 163.65,18.82 163.92,18.82 164.05,18.96 164.05,19.12 164.19,19.25 164.46,19.25 164.59,19.12 164.59,18.96 164.73,18.82 165,18.82 165.13,18.96 165.13,19.12 165.27,19.25 165.53,19.25 165.67,19.12 165.67,18.96 165.8,18.82 166.07,18.82 166.21,18.96 166.21,19.12 166.34,19.25 166.61,19.25 166.75,19.12 166.75,18.96 166.88,18.82 167.15,18.82 167.28,18.96 167.28,19.12 167.42,19.25 167.69,19.25 167.82,19.12 167.82,18.96 167.96,18.82 168.23,18.82 168.36,18.96 168.36,19.12 168.5,19.25 168.77,19.25 168.9,19.12 168.9,18.96 169.03,18.82 169.3,18.82 169.44,18.96 169.44,19.12 169.57,19.25 169.84,19.25 169.98,19.12 169.98,18.96 170.11,18.82 170.38,18.82 170.52,18.96 170.52,19.12 170.65,19.25 170.92,19.25 171.05,19.12 171.05,18.96 171.19,18.82 171.46,18.82 171.59,18.96 171.59,19.12 171.73,19.25 172,19.25 172.13,19.12 172.13,18.96 172.27,18.82 172.53,18.82 172.67,18.96 172.67,19.12 172.8,19.25 173.07,19.25 173.21,19.12 173.21,18.96 173.34,18.82 173.61,18.82 173.75,18.96 173.75,19.12 173.88,19.25 174.15,19.25 174.28,19.12 174.28,18.96 174.42,18.82 174.69,18.82 174.82,18.96 174.82,19.12 174.96,19.25 175.23,19.25 175.36,19.12 175.36,18.96 175.5,18.82 175.77,18.82 175.9,18.96 175.9,19.12 176.03,19.25 176.3,19.25 176.44,19.12 176.44,18.96 176.57,18.82 176.84,18.82 176.98,18.96 176.98,19.12 177.11,19.25 177.38,19.25 177.52,19.12 177.52,18.96 177.65,18.82 177.92,18.82 178.05,18.96 178.05,19.12 178.19,19.25 178.46,19.25 178.59,19.12 178.59,18.96 178.73,18.82 179.23,18.82 179.36,18.96 179.36,19.09 179.5,19.23 179.77,19.23 179.9,19.09 179.9,18.96 180.04,18.82 180.31,18.82 180.44,18.96 180.44,19.09 180.58,19.23 180.84,19.23 180.98,19.09 180.98,18.96 181.11,18.82 181.84,18.82 182.25,19.23 182.25,21.22 182.68,21.65 187.05,21.65 v1(187.66,22.25)
  BOTTOM w0.157: P4.57 188.97,22.05 188.57,22.45 187.86,22.45 v1(187.66,22.25)
DDR3_CPU_CH1_DQ26: length 78.9
  TOP w0.102: v1(131.18,31.16) 130.84,31.16 130.44,31.56 U14.N32
  L10_SIG w0.102: 136.04,27.89 135.64,28.3 135.64,32.92 135.09,33.46 134.58,33.46 134.41,33.29 132.22,33.29 131.57,32.64 131.57,31.71 131.18,31.31 v1(131.18,31.16)
  L10_SIG w0.135: 136.04,27.89 136.32,27.61 136.32,27.05 136.47,26.9 138.28,26.9 138.91,26.26 140.31,26.26 140.87,25.71 147.98,25.71 148.44,26.17 149.85,26.17 149.98,26.03 155.01,26.03 155.02,26.03 158.88,26.03 159.59,25.32 159.59,25.14 159.91,24.82 160.07,24.82 160.35,24.54 160.35,24.31 160.6,24.05 160.86,24.05 161.11,23.8 161.11,23.54 161.37,23.29 161.62,23.29 161.87,23.04 161.87,22.78 162.6,22.06 163.06,22.06 163.38,22.38 163.76,22.38 164.08,22.06 164.39,22.06 164.52,22.19 164.52,22.32 164.66,22.45 164.93,22.45 165.06,22.32 165.06,22.19 165.2,22.06 165.46,22.06 165.6,22.19 165.6,22.32 165.73,22.45 166,22.45 166.14,22.32 166.14,22.19 166.27,22.06 166.54,22.06 166.68,22.19 166.68,22.32 166.81,22.45 167.08,22.45 167.21,22.32 167.21,22.19 167.35,22.06 167.62,22.06 167.75,22.19 167.75,22.32 167.89,22.45 168.16,22.45 168.29,22.32 168.29,22.19 168.43,22.06 168.7,22.06 168.83,22.19 168.83,22.32 168.96,22.45 169.23,22.45 169.37,22.32 169.37,22.19 169.5,22.06 169.77,22.06 169.91,22.19 169.91,22.32 170.04,22.45 170.31,22.45 170.45,22.32 170.45,22.19 170.58,22.06 170.85,22.06 170.98,22.19 170.98,22.32 171.12,22.45 171.39,22.45 171.52,22.32 171.52,22.19 171.66,22.06 171.93,22.06 172.06,22.19 172.06,22.32 172.2,22.45 172.46,22.45 172.6,22.32 172.6,22.19 172.73,22.06 173,22.06 173.14,22.19 173.14,22.32 173.27,22.45 173.54,22.45 173.68,22.32 173.68,22.19 173.81,22.06 174.08,22.06 174.21,22.19 174.21,22.32 174.35,22.45 174.62,22.45 174.75,22.32 174.75,22.19 174.89,22.06 175.16,22.06 175.29,22.19 175.29,22.32 175.43,22.45 175.7,22.45 175.83,22.32 175.83,22.19 175.96,22.06 176.23,22.06 176.37,22.19 176.37,22.32 176.5,22.45 176.77,22.45 176.91,22.32 176.91,22.19 177.04,22.06 177.31,22.06 177.45,22.19 177.45,22.32 177.58,22.45 177.85,22.45 177.98,22.32 177.98,22.19 178.12,22.06 179.31,22.06 179.62,22.37 179.62,23.51 180.98,24.86 185.25,24.86 185.88,24.23 v1(187.58,24.23)
  BOTTOM w0.157: P4.63 187.96,23.85 v1(187.58,24.23)
DDR3_CPU_CH1_DQ27: length 78.8
  TOP w0.102: U14.L32 130.89,30.54 v1(130.98,30.54)
  L10_SIG w0.102: 136.6,30.91 136.6,33.07 135.46,34.21 132.33,34.21 130.43,32.31 130.43,30.99 130.88,30.54 v1(130.98,30.54)
  L10_SIG w0.135: v1(188.39,24.43) 188.37,24.45 188.27,24.45 187.5,25.23 186.35,25.23 186.04,25.54 180.79,25.54 178.43,23.19 178.1,23.19 177.74,23.54 177.43,23.54 177.3,23.41 177.3,23.32 177.16,23.19 176.89,23.19 176.76,23.32 176.76,23.45 176.63,23.58 176.36,23.58 176.22,23.45 176.22,23.32 176.09,23.19 175.82,23.19 175.68,23.32 175.68,23.45 175.55,23.58 175.28,23.58 175.14,23.45 175.14,23.32 175.01,23.19 174.74,23.19 174.61,23.32 174.61,23.45 174.47,23.58 174.2,23.58 174.07,23.45 174.07,23.32 173.93,23.19 173.66,23.19 173.53,23.32 173.53,23.45 173.39,23.58 173.13,23.58 172.99,23.45 172.99,23.32 172.86,23.19 172.59,23.19 172.45,23.32 172.45,23.45 172.32,23.58 172.05,23.58 171.91,23.45 171.91,23.32 171.78,23.19 171.51,23.19 171.38,23.32 171.38,23.45 171.24,23.58 170.97,23.58 170.84,23.45 170.84,23.32 170.7,23.19 170.43,23.19 170.3,23.32 170.3,23.45 170.16,23.58 169.89,23.58 169.76,23.45 169.76,23.32 169.63,23.19 169.36,23.19 169.22,23.32 169.22,23.45 169.09,23.58 168.82,23.58 168.68,23.45 168.68,23.32 168.55,23.19 168.28,23.19 168.14,23.32 168.14,23.45 168.01,23.58 167.74,23.58 167.61,23.45 167.61,23.32 167.47,23.19 167.2,23.19 167.07,23.32 167.07,23.45 166.93,23.58 166.66,23.58 166.53,23.45 166.53,23.32 166.39,23.19 166.12,23.19 165.99,23.32 165.99,23.45 165.86,23.58 165.59,23.58 165.45,23.45 165.45,23.32 165.32,23.19 165.05,23.19 164.91,23.32 164.91,23.45 164.78,23.58 164.51,23.58 164.37,23.45 164.37,23.32 164.24,23.19 163.97,23.19 163.84,23.32 163.84,23.45 163.7,23.58 163.43,23.58 163.3,23.45 163.3,23.32 163.16,23.19 162.72,23.19 161.8,24.11 161.8,24.3 161.86,24.36 161.86,24.55 161.67,24.74 161.48,24.74 161.42,24.68 161.22,24.68 161.03,24.87 161.03,25.06 161.1,25.13 161.1,25.32 160.91,25.51 160.4,25.51 160.07,25.84 160.07,26.15 159.62,26.59 148.28,26.59 148.14,26.74 147.59,26.74 147.44,26.59 146.5,26.59 146.36,26.73 143.71,26.73 143.25,27.19 142.72,27.19 142.53,27 139.19,27 137.67,28.52 137.67,29.84 136.6,30.91
  BOTTOM w0.157: v1(188.39,24.43) 188.41,24.45 P4.65
DDR3_CPU_CH1_DQ28: length 78.8
  TOP w0.102: v1(130.89,29.72) 130.69,29.72 U14.H32
  L10_SIG w0.102: v1(130.89,29.72) 130.89,29.66 130.6,29.36 130.6,25.54 136,20.14
  L10_SIG w0.135: v1(195.79,21.3) 191.28,21.3 189.84,19.86 186.44,19.86 183.34,16.76 155.07,16.76 154.1,15.8 145.95,15.8 142.23,19.51 139.06,19.51 138.66,19.91 136.23,19.91 136,20.14
  BOTTOM w0.157: P4.54 195.94,21.15 v1(195.79,21.3)
DDR3_CPU_CH1_DQ29: length 78.8
  TOP w0.102: v1(132.06,29.47) 131.72,29.81 U14.J30
  L10_SIG w0.102: v1(132.06,29.47) 130.96,28.37 130.96,26.23 132.41,24.78 132.78,24.78 136.28,21.28 136.28,21.21
  L10_SIG w0.135: 136.28,21.21 136.61,20.88 141.71,20.88 146.15,16.43 153.57,16.43 155.65,18.52 158.62,18.52 159.81,17.33 182.96,17.33 186.06,20.42 189.23,20.42 190.56,21.75 196.5,21.75 v1(196.63,21.62)
  BOTTOM w0.157: v1(196.63,21.62) 196.76,21.75 P4.56
DDR3_CPU_CH1_DQ30: length 78.7
  TOP w0.102: U14.M30 132.07,31.03 v1(132.07,30.99)
  L10_SIG w0.102: 138.33,25.17 137.46,26.04 135.33,26.04 134.68,26.68 134.68,27.87 134.26,28.29 134.26,29.87 133.6,30.52 133.6,31.19 133.5,31.29 132.37,31.29 v1(132.07,30.99)
  L10_SIG w0.135: 138.33,25.17 139.65,23.85 148.16,23.85 148.6,23.41 158.64,23.41 161.35,20.7 162.14,20.7 162.34,20.9 162.74,20.9 162.94,20.7 163.23,20.7 163.42,20.88 163.82,20.88 164,20.7 164.31,20.7 164.49,20.88 164.89,20.88 165.08,20.7 165.39,20.7 165.61,20.92 165.93,20.92 166.15,20.7 166.47,20.7 166.69,20.92 167,20.92 167.23,20.7 167.54,20.7 167.77,20.92 168.08,20.92 168.31,20.7 168.62,20.7 168.85,20.92 169.16,20.92 169.38,20.7 169.7,20.7 169.92,20.92 170.23,20.92 170.46,20.7 170.77,20.7 171,20.92 171.31,20.92 171.54,20.7 171.85,20.7 172.08,20.92 172.39,20.92 172.62,20.7 172.93,20.7 173.15,20.92 173.47,20.92 173.69,20.7 174,20.7 174.23,20.92 174.54,20.92 174.77,20.7 175.08,20.7 175.31,20.92 175.62,20.92 175.85,20.7 176.16,20.7 176.32,20.85 176.77,20.85 176.92,20.7 177.41,20.7 177.59,20.88 177.95,20.88 178.13,20.7 180.26,20.7 180.76,21.19 180.76,22.86 181.45,23.55 184.57,23.55 184.77,23.36 190.11,23.36 190.88,24.13 193.14,24.13 193.97,24.96 v1(196.02,24.96)
  BOTTOM w0.157: P4.66 196.23,24.75 v1(196.02,24.96)
DDR3_CPU_CH1_DQ31: length 78.8
  TOP w0.157: v1(132.07,31.75) 131.82,32 131.82,32.04 U14.P30
  L10_SIG w0.102: 138.61,25.68 138.4,25.68 137.59,26.49 135.59,26.49 135,27.08 135,27.92 134.49,28.43 134.49,31.54 133.48,32.56 132.68,32.56 132.48,32.37 132.48,32.17 v1(132.07,31.75)
  L10_SIG w0.135: v1(196.6,25.65) 193.47,25.65 192.53,24.71 190.86,24.71 189.79,23.65 185.14,23.65 184.6,24.19 181.18,24.19 180.19,23.2 180.19,21.72 179.96,21.49 161.5,21.49 161.25,21.73 161.25,21.92 161.34,22.01 161.34,22.2 161.15,22.39 160.96,22.39 160.87,22.3 160.68,22.3 160.28,22.7 160.28,22.89 160.39,23 160.39,23.19 160.2,23.38 160.01,23.38 159.9,23.27 159.71,23.27 159.52,23.46 159.52,23.65 159.63,23.76 159.63,23.95 159.44,24.14 159.24,24.14 159.18,24.08 158.91,24.08 158.42,24.56 150.6,24.56 150.37,24.33 148.87,24.33 148.67,24.54 140.56,24.54 139.42,25.68 138.61,25.68
  BOTTOM w0.157: v1(196.6,25.65) 196.9,25.35 P4.68
DDR3_CPU_CH1_DQ32: length 74
  TOP w0.157: v1(139.49,33.22) 139.48,33.22 139.13,32.86 U14.R15
  L10_SIG w0.102: v1(139.49,33.22) 139.43,33.15 139.43,31.15 139.5,31.08 139.5,31.07 139.72,30.85 139.73,30.85 139.96,30.61 140.17,30.61 140.17,30.61 140.18,30.61 141.13,29.65 143.9,29.65 144.15,29.4 145.36,29.4 145.49,29.27 147.18,29.27
  L10_SIG w0.135: 147.18,29.27 147.4,29.05 148.16,29.05 148.37,29.26 170.01,29.26 170.61,29.86 170.61,29.98 170.83,30.19 171.02,30.19 171.12,30.09 171.31,30.09 171.5,30.28 171.5,30.47 171.4,30.57 171.4,30.76 171.59,30.95 171.78,30.95 171.88,30.85 172.07,30.85 172.26,31.04 172.26,31.23 172.16,31.34 172.16,31.53 172.35,31.72 172.54,31.72 172.65,31.61 172.84,31.61 173.03,31.8 173.03,31.99 172.92,32.1 172.92,32.29 173.11,32.48 173.3,32.48 173.41,32.37 173.6,32.37 173.79,32.56 173.79,32.75 173.68,32.86 173.68,33.05 173.87,33.24 174.06,33.24 174.17,33.13 174.36,33.13 174.55,33.33 174.55,33.52 174.44,33.62 174.44,33.81 174.64,34 174.83,34 174.93,33.9 175.12,33.9 175.31,34.09 175.31,34.28 175.21,34.38 175.21,34.57 175.4,34.76 175.59,34.76 175.69,34.66 175.88,34.66 176.07,34.85 176.07,35.04 175.97,35.15 175.97,35.34 176.16,35.53 176.35,35.53 176.46,35.42 176.65,35.42 176.84,35.61 176.84,35.8 176.73,35.91 176.73,36.1 176.92,36.29 177.11,36.29 177.22,36.18 177.41,36.18 177.6,36.37 177.6,36.56 177.49,36.67 177.49,36.86 177.68,37.05 177.87,37.05 177.98,36.94 178.17,36.94 178.36,37.14 178.36,37.33 178.25,37.43 178.25,37.62 178.45,37.81 178.64,37.81 178.74,37.71 178.93,37.71 179.12,37.9 179.12,38.09 179.02,38.19 179.02,38.38 179.21,38.57 179.4,38.57 179.5,38.47 179.69,38.47 179.88,38.66 179.88,38.85 179.78,38.96 179.78,39.15 179.97,39.34 180.16,39.34 180.27,39.23 180.46,39.23 180.65,39.42 180.65,39.61 180.54,39.72 180.54,39.91 180.73,40.1 180.92,40.1 181.03,39.99 181.22,39.99 181.41,40.18 181.41,40.37 181.3,40.48 181.3,40.67 181.49,40.86 181.68,40.86 181.79,40.75 181.98,40.75 182.17,40.95 182.17,41.14 182.06,41.24 182.06,41.43 182.26,41.62 182.45,41.62 182.55,41.52 182.74,41.52 182.93,41.71 182.93,41.9 182.83,42 182.83,42.19 183.02,42.38 183.21,42.38 183.38,42.21 183.57,42.21 183.76,42.41 183.76,42.6 183.56,42.8 183.56,42.99 183.75,43.18 183.94,43.18 184.11,43 184.3,43 184.49,43.2 184.49,43.39 184.3,43.58 184.3,43.77 184.49,43.96 184.68,43.96 184.89,43.75 185.08,43.75 185.27,43.94 185.27,44.13 185.11,44.29 185.11,44.48 185.3,44.67 185.49,44.67 185.65,44.51 185.84,44.51 186.03,44.7 186.03,44.89 185.87,45.06 185.87,45.25 186.06,45.44 186.25,45.44 186.37,45.32 186.56,45.32 186.75,45.51 186.75,45.7 186.64,45.81 186.64,46 186.83,46.19 187.02,46.19 187.09,46.13 187.35,46.13 187.89,46.67 187.89,47.17 188.25,47.52 188.27,47.52 v1(188.3,47.55)
  BOTTOM w0.157: v1(188.3,47.55) 188.31,47.55 188.37,47.49 188.71,47.25 P4.133
DDR3_CPU_CH1_DQ33: length 74
  TOP w0.157: U14.R14 140.23,33.21 v1(140.26,33.21)
  L10_SIG w0.102: v1(140.26,33.21) 140.26,31.39 140.26,31.38 140.26,30.84 141.02,30.09 143.16,30.09 143.65,30.58 143.98,30.58 144.7,29.85 146.25,29.85 146.51,29.6 147.08,29.6
  L10_SIG w0.135: 147.08,29.6 147.42,29.94 148.37,29.94 148.49,29.83 168.81,29.83 170.76,31.78 170.99,31.78 171.06,31.71 171.4,31.71 171.59,31.9 171.59,32.09 171.45,32.24 171.45,32.43 171.64,32.62 171.83,32.62 171.97,32.48 172.16,32.48 172.35,32.67 172.35,32.86 172.21,33 172.21,33.19 172.4,33.38 172.59,33.38 172.73,33.24 172.92,33.24 173.11,33.43 173.11,33.62 172.97,33.76 172.97,33.95 173.16,34.14 173.35,34.14 173.49,34 173.69,34 173.88,34.19 173.88,34.38 173.74,34.52 173.74,34.71 173.93,34.9 174.12,34.9 174.26,34.76 174.45,34.76 174.64,34.95 174.64,35.14 174.5,35.28 174.5,35.47 174.69,35.66 174.88,35.66 175.02,35.52 175.21,35.52 175.4,35.71 175.4,35.9 175.26,36.05 175.26,36.24 175.45,36.43 175.64,36.43 175.78,36.29 175.97,36.29 176.16,36.48 176.16,36.67 176.02,36.81 176.02,37 176.21,37.19 176.4,37.19 176.54,37.05 176.73,37.05 176.92,37.24 176.92,37.43 176.78,37.57 176.78,37.76 176.97,37.95 177.16,37.95 177.3,37.81 177.5,37.81 177.69,38 177.69,38.19 177.55,38.33 177.55,38.52 177.74,38.71 177.93,38.71 178.07,38.57 178.26,38.57 178.45,38.76 178.45,38.95 178.31,39.09 178.31,39.28 178.5,39.47 178.69,39.47 178.83,39.33 179.02,39.33 179.21,39.52 179.21,39.71 179.07,39.86 179.07,40.05 179.26,40.24 179.45,40.24 179.59,40.1 179.78,40.1 179.97,40.29 179.97,40.48 179.83,40.62 179.83,40.81 180.02,41 180.21,41 180.35,40.86 180.54,40.86 180.73,41.05 180.73,41.24 180.59,41.38 180.59,41.57 180.78,41.76 180.97,41.76 181.11,41.62 181.31,41.62 181.5,41.81 181.5,42 181.36,42.14 181.36,42.33 181.55,42.52 181.74,42.52 181.88,42.38 182.07,42.38 182.26,42.57 182.26,42.76 182.05,42.97 182.05,43.16 182.22,43.33 182.41,43.33 182.6,43.14 182.83,43.14 183.02,43.33 183.02,43.52 182.85,43.69 182.85,43.88 183.04,44.07 183.23,44.07 183.4,43.91 183.59,43.91 183.78,44.1 183.78,44.29 183.57,44.49 183.57,44.69 183.76,44.88 183.95,44.88 184.24,44.59 184.43,44.59 184.62,44.78 184.62,44.97 184.33,45.26 184.33,45.45 184.52,45.64 184.71,45.64 184.92,45.43 185.13,45.43 185.32,45.62 185.32,45.81 185.17,45.97 185.17,46.27 185.44,46.55 186.39,46.55 187.55,47.72 v1(187.55,47.8)
  BOTTOM w0.157: P4.135 188.84,47.85 188.68,48.01 187.76,48.01 v1(187.55,47.8)
DDR3_CPU_CH1_DQ34: length 74
  TOP w0.157: v1(142.54,33.22) 142.52,33.22 U14.R9
  L10_SIG w0.102: v1(142.54,33.22) 143.17,33.85 146.71,33.85 147.85,32.71 151,32.71 151.32,32.38 153.62,32.38
  L10_SIG w0.135: v1(188.39,51.08) 188.34,51.08 187.93,50.67 184.91,50.67 184.57,51.01 183.44,51.01 182.31,49.88 181.56,49.88 181.05,49.37 181.05,49.08 181.18,48.95 181.18,48.76 180.99,48.57 180.8,48.57 180.62,48.75 180.43,48.75 180.24,48.56 180.24,48.37 180.45,48.16 180.45,47.97 180.26,47.78 180.07,47.78 179.85,47.99 179.66,47.99 179.47,47.8 179.47,47.61 179.66,47.42 179.66,47.23 179.47,47.04 179.28,47.04 179.09,47.23 178.9,47.23 178.71,47.04 178.71,46.85 178.9,46.66 178.9,46.47 178.71,46.28 178.52,46.28 178.33,46.47 178.14,46.47 177.95,46.28 177.95,46.09 178.13,45.9 178.13,45.71 177.94,45.52 177.75,45.52 177.57,45.7 177.38,45.7 177.19,45.51 177.19,45.32 177.37,45.14 177.37,44.95 177.18,44.76 176.99,44.76 176.81,44.94 176.62,44.94 176.43,44.75 176.43,44.56 176.61,44.38 176.61,44.19 176.42,44 176.23,44 176.04,44.18 175.85,44.18 175.66,43.99 175.66,43.8 175.85,43.61 175.85,43.42 175.66,43.23 175.47,43.23 175.28,43.42 175.09,43.42 174.9,43.23 174.9,43.04 175.09,42.85 175.09,42.66 174.9,42.47 174.71,42.47 174.52,42.66 174.33,42.66 174.14,42.47 174.14,42.28 174.32,42.09 174.32,41.9 174.13,41.71 173.94,41.71 173.76,41.89 173.57,41.89 173.38,41.7 173.38,41.51 173.56,41.33 173.56,41.14 173.37,40.95 173.18,40.95 173,41.13 172.81,41.13 172.62,40.94 172.62,40.75 172.8,40.57 172.8,40.38 172.61,40.19 172.42,40.19 172.23,40.37 172.04,40.37 171.85,40.18 171.85,39.99 172.04,39.8 172.04,39.61 171.85,39.42 171.66,39.42 171.47,39.61 171.28,39.61 171.09,39.42 171.09,39.23 171.28,39.04 171.28,38.85 171.09,38.66 170.9,38.66 170.71,38.85 170.52,38.85 170.33,38.66 170.33,38.47 170.51,38.28 170.51,38.09 170.32,37.9 170.13,37.9 169.95,38.08 169.76,38.08 169.57,37.89 169.57,37.7 169.75,37.52 169.75,37.33 169.56,37.14 169.37,37.14 169.19,37.32 169,37.32 168.81,37.13 168.81,36.94 168.99,36.76 168.99,36.57 168.8,36.38 168.61,36.38 168.37,36.62 168.18,36.62 167.99,36.43 167.99,36.24 168.23,35.99 168.23,35.8 168.04,35.61 167.85,35.61 167.61,35.85 167.42,35.85 167.23,35.66 167.23,35.47 167.47,35.23 167.47,35.04 167.28,34.85 167.09,34.85 166.84,35.09 166.65,35.09 166.46,34.9 166.46,34.71 166.7,34.47 166.7,34.28 166.51,34.09 166.32,34.09 166.09,34.32 165.9,34.32 165.71,34.13 165.71,33.94 165.99,33.66 165.99,33.5 165.77,33.28 165.61,33.28 165.35,33.54 165.16,33.54 164.97,33.35 164.97,33.16 165.15,32.98 165.15,32.73 164.8,32.38 153.62,32.38
  BOTTOM w0.157: P4.145 188.58,50.85 188.39,51.04 v1(188.39,51.08)
DDR3_CPU_CH1_DQ35: length 74
  TOP w0.157: U14.R11 141.75,32.52 141.77,32.52 v1(141.78,32.52)
  L10_SIG w0.102: 151.19,32.91 148.24,32.91 147.08,34.07 142.55,34.07 141.77,33.29 141.77,32.52 v1(141.78,32.52)
  L10_SIG w0.135: v1(187.63,51.13) 187.05,51.13 186.58,51.6 181.99,51.6 180.99,50.6 180.99,50.27 180.8,50.07 180.61,50.07 180.38,50.31 180.19,50.31 180,50.12 180,49.93 180.23,49.69 180.23,49.5 180.04,49.31 179.85,49.31 179.61,49.55 179.42,49.55 179.23,49.36 179.23,49.17 179.48,48.92 179.48,48.73 179.29,48.54 179.1,48.54 178.87,48.77 178.68,48.77 178.49,48.58 178.49,48.39 178.71,48.17 178.71,47.98 178.51,47.79 178.33,47.79 178.14,47.98 177.95,47.98 177.76,47.78 177.76,47.59 177.94,47.41 177.94,47.22 177.75,47.03 177.56,47.03 177.36,47.23 177.17,47.23 176.98,47.04 176.98,46.85 177.18,46.65 177.18,46.46 176.99,46.26 176.8,46.26 176.65,46.42 176.46,46.42 176.27,46.23 176.27,46.04 176.42,45.88 176.42,45.69 176.23,45.5 176.04,45.5 175.88,45.66 175.69,45.66 175.5,45.47 175.5,45.28 175.66,45.12 175.66,44.93 175.47,44.74 175.28,44.74 175.12,44.9 174.93,44.9 174.74,44.7 174.74,44.51 174.9,44.36 174.9,44.17 174.7,43.98 174.51,43.98 174.36,44.13 174.17,44.13 173.98,43.94 173.98,43.75 174.13,43.6 174.13,43.41 173.94,43.22 173.75,43.22 173.6,43.37 173.41,43.37 173.22,43.18 173.22,42.99 173.37,42.84 173.37,42.65 173.18,42.45 172.99,42.45 172.84,42.61 172.65,42.61 172.46,42.42 172.46,42.23 172.61,42.07 172.61,41.88 172.42,41.69 172.23,41.69 172.07,41.85 171.88,41.85 171.69,41.66 171.69,41.47 171.85,41.31 171.85,41.12 171.66,40.93 171.47,40.93 171.31,41.09 171.12,41.09 170.93,40.89 170.93,40.7 171.09,40.55 171.09,40.36 170.89,40.17 170.7,40.17 170.55,40.32 170.36,40.32 170.17,40.13 170.17,39.94 170.32,39.79 170.32,39.6 170.13,39.41 169.94,39.41 169.79,39.56 169.6,39.56 169.41,39.37 169.41,39.18 169.56,39.03 169.56,38.84 169.37,38.64 169.18,38.64 169.03,38.8 168.84,38.8 168.65,38.61 168.65,38.42 168.8,38.26 168.8,38.07 168.61,37.88 168.42,37.88 168.26,38.04 168.07,38.04 167.88,37.85 167.88,37.66 168.04,37.5 168.04,37.31 167.85,37.12 167.66,37.12 167.5,37.28 167.31,37.28 167.12,37.08 167.12,36.89 167.28,36.74 167.28,36.55 167.08,36.36 166.89,36.36 166.74,36.51 166.55,36.51 166.36,36.32 166.36,36.13 166.51,35.98 166.51,35.79 166.32,35.6 166.13,35.6 165.98,35.75 165.79,35.75 165.6,35.56 165.6,35.37 165.75,35.22 165.75,35.03 165.56,34.83 165.37,34.83 165.22,34.99 165.03,34.99 164.84,34.8 164.84,34.61 164.99,34.45 164.99,34.26 164.8,34.07 164.61,34.07 164.45,34.23 164.26,34.23 164.07,34.04 164.07,33.85 164.23,33.69 164.23,33.5 163.67,32.95 151.23,32.95 151.19,32.91
  BOTTOM w0.157: P4.147 188.8,51.45 188.69,51.56 188.06,51.56 v1(187.63,51.13)
DDR3_CPU_CH1_DQ36: length 74
  TOP w0.157: v1(138.1,33.73) 138.38,33.45 U14.T17
  L10_SIG w0.102: v1(138.1,33.73) 138.51,33.32 138.51,28.87 138.92,28.46 139.73,28.46 139.86,28.33 140.17,28.33 140.31,28.46 141.01,28.46 141.55,27.92 142.73,27.92
  L10_SIG w0.135: v1(196.66,47.12) 196.34,47.12 191.96,42.75 187.13,42.75 172.13,27.75 142.9,27.75 142.73,27.92
  BOTTOM w0.157: P4.134 197.01,47.55 196.66,47.2 v1(196.66,47.12)
DDR3_CPU_CH1_DQ37: length 74
  TOP w0.102: v1(138.98,30.86) 138.79,31.05 138.79,33.23 U14.U15
  L10_SIG w0.102: v1(138.98,30.86) 139.12,30.86 139.54,30.44 139.54,29.42 139.86,29.1 141.18,29.1 141.58,28.7 142.72,28.7 142.88,28.86 144.01,28.86 144.26,29.11 144.89,29.11 145.16,28.83 146.95,28.83
  L10_SIG w0.135: 146.95,28.83 147.12,28.67 171.45,28.67 171.79,29 171.79,29.64 171.98,29.83 172.17,29.83 172.38,29.62 172.57,29.62 172.76,29.81 172.76,30 172.55,30.21 172.55,30.4 172.74,30.59 172.93,30.59 173.13,30.39 173.32,30.39 173.51,30.58 173.51,30.77 173.31,30.97 173.31,31.16 187.29,45.14 192.88,45.14 195.59,47.85 v1(196.42,47.85)
  BOTTOM w0.157: v1(196.42,47.85) 196.66,47.85 196.96,48.15 P4.136
DDR3_CPU_CH1_DQ38: length 74
  TOP w0.157: v1(143.53,32.63) 143.35,32.63 143.27,32.71 143.08,32.71 U14.R8
  L10_SIG w0.102: 151.13,31.25 150.54,31.25 150.07,31.72 147.45,31.72 146.99,32.18 146.05,32.18 145.85,31.98 144.17,31.98 v1(143.53,32.63)
  L10_SIG w0.135: 151.13,31.25 166.47,31.25 167.14,31.91 167.14,32.41 167.28,32.55 167.78,32.55 167.97,32.74 167.97,32.93 167.9,32.99 167.9,33.18 168.09,33.38 168.28,33.38 168.35,33.31 168.54,33.31 168.73,33.5 168.73,33.69 168.67,33.76 168.67,33.95 168.86,34.14 169.05,34.14 169.11,34.07 169.3,34.07 169.49,34.26 169.49,34.45 169.43,34.52 169.43,34.71 169.62,34.9 169.81,34.9 169.87,34.84 170.06,34.84 170.25,35.03 170.25,35.22 170.19,35.28 170.19,35.47 170.38,35.66 170.57,35.66 170.63,35.6 170.82,35.6 171.02,35.79 171.02,35.98 170.95,36.04 170.95,36.23 171.14,36.42 171.33,36.42 171.4,36.36 171.59,36.36 171.78,36.55 171.78,36.74 171.71,36.8 171.71,36.99 171.9,37.19 172.09,37.19 172.16,37.12 172.35,37.12 172.54,37.31 172.54,37.5 172.48,37.57 172.48,37.76 172.67,37.95 172.86,37.95 172.92,37.88 173.11,37.88 173.3,38.07 173.3,38.26 173.24,38.33 173.24,38.52 173.43,38.71 173.62,38.71 173.68,38.65 173.87,38.65 174.06,38.84 174.06,39.03 174,39.09 174,39.28 174.19,39.47 174.38,39.47 174.44,39.41 174.63,39.41 174.83,39.6 174.83,39.79 174.76,39.85 174.76,40.04 174.95,40.23 175.14,40.23 175.21,40.17 175.4,40.17 175.59,40.36 175.59,40.55 175.52,40.61 175.52,40.8 175.71,41 175.9,41 175.97,40.93 176.16,40.93 176.35,41.12 176.35,41.31 176.29,41.38 176.29,41.57 176.48,41.76 176.67,41.76 176.73,41.69 176.92,41.69 177.11,41.88 177.11,42.07 177.05,42.14 177.05,42.33 177.24,42.52 177.43,42.52 177.49,42.46 177.68,42.46 177.87,42.65 177.87,42.84 177.81,42.9 177.81,43.09 178,43.28 178.19,43.28 178.35,43.12 178.54,43.12 178.74,43.31 178.74,43.5 178.57,43.66 178.57,43.85 178.76,44.04 178.95,44.04 179.08,43.92 179.27,43.92 179.46,44.11 179.46,44.3 179.33,44.42 179.33,44.61 179.52,44.81 179.71,44.81 179.84,44.68 180.03,44.68 180.22,44.87 180.22,45.06 180.1,45.19 180.1,45.38 180.29,45.57 180.48,45.57 180.61,45.44 180.8,45.44 180.99,45.63 180.99,45.82 180.8,46.01 180.8,46.2 180.99,46.39 181.18,46.39 181.3,46.27 181.49,46.27 181.68,46.46 181.68,46.65 181.62,46.71 181.62,46.92 181.83,47.13 182.35,47.13 182.77,47.54 182.77,48.05 183.06,48.34 183.72,48.34 185.02,49.64 186.64,49.64 186.95,49.95 188.89,49.95 189.71,49.12 194.77,49.12 v1(195.9,50.25)
  BOTTOM w0.157: P4.142 198.07,49.89 196.95,49.89 196.85,49.79 196.36,49.79 v1(195.9,50.25)
DDR3_CPU_CH1_DQ39: length 74
  TOP w0.157: v1(143.47,33.32) 143.17,33.32 U14.U8
  L10_SIG w0.102: 152.58,31.81 150.91,31.81 150.42,32.3 147.4,32.3 146.53,33.17 145.53,33.17 145.28,32.92 144.22,32.92 143.82,33.32 v1(143.47,33.32)
  L10_SIG w0.135: v1(196.66,50.25) 196.08,50.84 194.58,50.84 194.22,51.19 189.27,51.19 188.33,50.25 183.53,50.25 183.28,50 183.28,49.49 183.05,49.26 182.54,49.26 182.33,49.05 182.33,48.54 182,48.22 181.49,48.22 181.29,48.01 181.29,47.5 180.94,47.15 180.43,47.15 179.8,46.52 179.8,46.33 179.87,46.27 179.87,46.08 179.67,45.89 179.48,45.89 179.42,45.95 179.23,45.95 179.04,45.76 179.04,45.57 179.1,45.51 179.1,45.32 178.91,45.12 178.72,45.12 178.66,45.19 178.47,45.19 178.28,45 178.28,44.81 178.34,44.74 178.34,44.55 178.15,44.36 177.96,44.36 177.9,44.43 177.71,44.43 177.51,44.24 177.51,44.05 177.58,43.98 177.58,43.79 177.39,43.6 177.2,43.6 177.13,43.67 176.94,43.67 176.75,43.47 176.75,43.28 176.82,43.22 176.82,43.03 176.63,42.84 176.44,42.84 176.37,42.9 176.18,42.9 175.99,42.71 175.99,42.52 176.06,42.46 176.06,42.27 175.86,42.08 175.67,42.08 175.59,42.16 175.4,42.16 175.21,41.97 175.21,41.78 175.29,41.7 175.29,41.51 175.1,41.31 174.91,41.31 174.85,41.38 174.66,41.38 174.47,41.19 174.47,41 174.53,40.93 174.53,40.74 174.34,40.55 174.15,40.55 174.09,40.62 173.9,40.62 173.7,40.43 173.7,40.24 173.77,40.17 173.77,39.98 173.58,39.79 173.39,39.79 173.32,39.86 173.13,39.86 172.94,39.66 172.94,39.47 173.01,39.41 173.01,39.22 172.82,39.03 172.63,39.03 172.56,39.09 172.37,39.09 172.18,38.9 172.18,38.71 172.25,38.65 172.25,38.46 172.05,38.27 171.86,38.27 171.8,38.33 171.61,38.33 171.42,38.14 171.42,37.95 171.48,37.89 171.48,37.7 171.29,37.5 171.1,37.5 171.04,37.57 170.85,37.57 170.66,37.38 170.66,37.19 170.72,37.12 170.72,36.93 170.53,36.74 170.34,36.74 170.28,36.81 170.09,36.81 169.89,36.62 169.89,36.43 169.96,36.36 169.96,36.17 169.77,35.98 169.58,35.98 169.51,36.05 169.32,36.05 169.13,35.85 169.13,35.66 169.28,35.52 169.28,35.36 169.06,35.14 168.9,35.14 168.7,35.33 168.56,35.33 168.32,35.09 168.32,34.95 168.48,34.79 168.48,34.6 168.29,34.41 168.1,34.41 167.95,34.56 167.78,34.56 167.57,34.35 167.57,34.18 167.73,34.02 167.73,33.83 167.53,33.64 167.34,33.64 167.19,33.79 167.02,33.79 166.81,33.59 166.81,33.41 166.91,33.31 166.91,33.12 166.72,32.93 166.23,32.93 165.92,32.63 165.92,32.06 165.67,31.81 152.58,31.81
  BOTTOM w0.157: P4.144 196.96,50.55 v1(196.66,50.25)
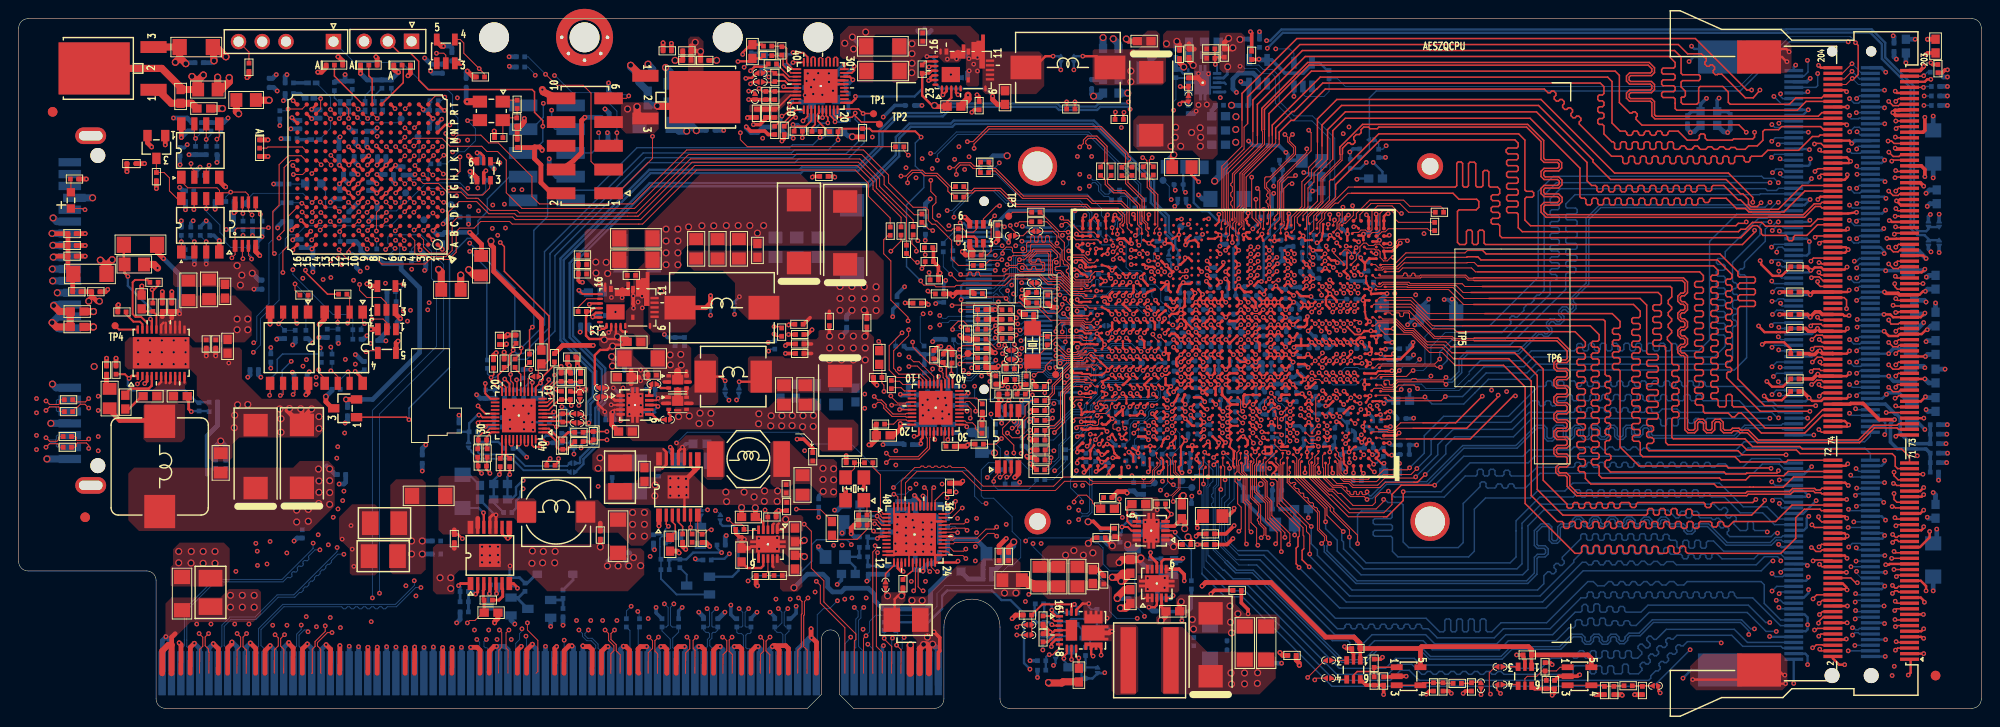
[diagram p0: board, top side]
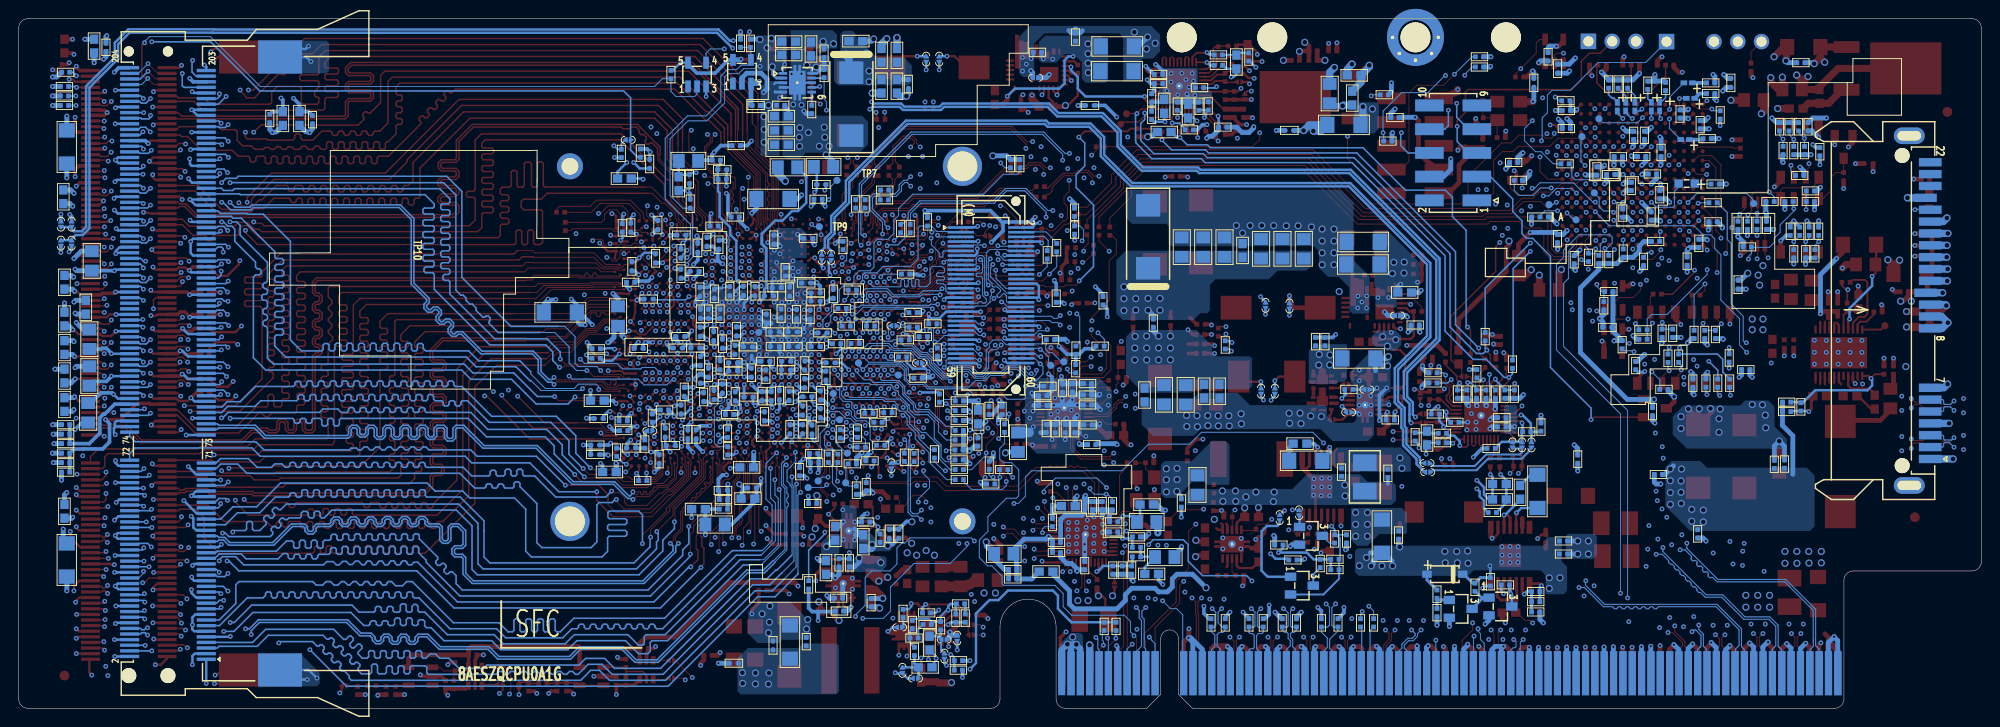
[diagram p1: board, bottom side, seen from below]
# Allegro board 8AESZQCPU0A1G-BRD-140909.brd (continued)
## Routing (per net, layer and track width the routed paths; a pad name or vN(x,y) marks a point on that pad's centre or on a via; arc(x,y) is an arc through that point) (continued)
DDR3_CPU_CH1_DQ40: length 70.2
  TOP w0.102: U14.U4 145.02,34.25 145.85,34.25 145.95,34.14 147.22,34.14 147.67,34.59 149.29,34.59 v1(149.67,34.21)
  BOTTOM w0.102: v1(149.67,34.21) 149.88,34.01 154.11,34.01 155.15,35.05
  BOTTOM w0.157: 155.15,35.05 155.28,35.05 156.76,36.53 156.81,36.53 156.83,36.55 161.06,36.55 162.1,37.59 181.43,37.59 182.6,38.76 182.6,39.79 182.44,39.95 181.82,39.95 181.66,40.1 181.66,40.42 181.82,40.58 182.44,40.58 182.6,40.73 182.6,41.05 182.44,41.21 181.79,41.21 181.64,41.36 181.64,41.68 181.79,41.84 182.44,41.84 182.6,41.99 182.6,42.31 182.44,42.47 181.79,42.47 181.64,42.62 181.64,42.94 181.79,43.1 182.44,43.1 182.6,43.25 182.6,43.57 182.44,43.73 181.79,43.73 181.64,43.88 181.64,44.2 181.79,44.36 182.44,44.36 182.6,44.51 182.6,44.83 182.44,44.99 181.79,44.99 181.64,45.14 181.64,45.46 181.79,45.62 182.44,45.62 182.6,45.77 182.6,46.09 182.44,46.25 181.79,46.25 181.64,46.4 181.64,46.72 181.79,46.88 182.44,46.88 182.6,47.03 182.6,47.35 182.44,47.51 181.82,47.51 181.66,47.66 181.66,47.98 181.82,48.14 182.44,48.14 182.6,48.29 182.6,48.87 186.18,52.45 187.07,52.45 187.27,52.65 P4.151
DDR3_CPU_CH1_DQ41: length 70.2
  TOP w0.102: U14.U2 147.75,33.93 v1(147.93,34.11)
  BOTTOM w0.102: 155.2,36.01 155.2,35.79 153.65,34.23 150.57,34.23 150.1,34.69 148.24,34.69 147.93,34.39 v1(147.93,34.11)
  BOTTOM w0.157: P4.153 188.7,53.25 188.41,52.96 185.6,52.96 185.51,52.87 183.82,52.87 180.92,49.97 180.92,39.42 179.76,38.25 177.58,38.25 177.42,38.41 177.42,38.88 177.26,39.04 176.95,39.04 176.79,38.88 176.79,38.41 176.63,38.25 176.32,38.25 176.16,38.41 176.16,38.91 176,39.07 175.69,39.07 175.53,38.91 175.53,38.41 175.37,38.25 175.06,38.25 174.9,38.41 174.9,38.91 174.74,39.07 174.43,39.07 174.27,38.91 174.27,38.41 174.11,38.25 173.8,38.25 173.64,38.41 173.64,38.91 173.48,39.07 173.17,39.07 173.01,38.91 173.01,38.41 172.85,38.25 172.54,38.25 172.38,38.41 172.38,38.91 172.22,39.07 171.91,39.07 171.75,38.91 171.75,38.41 171.59,38.25 171.28,38.25 171.12,38.41 171.12,38.91 170.96,39.07 170.65,39.07 170.49,38.91 170.49,38.41 170.33,38.25 170.02,38.25 169.86,38.41 169.86,38.91 169.7,39.07 169.39,39.07 169.23,38.91 169.23,38.41 169.07,38.25 168.76,38.25 168.6,38.41 168.6,38.91 168.44,39.07 168.13,39.07 167.97,38.91 167.97,38.41 167.81,38.25 167.5,38.25 167.34,38.41 167.34,38.88 167.18,39.04 166.87,39.04 166.71,38.88 166.71,38.51 166.45,38.25 161.85,38.25 160.79,37.19 156.38,37.19 155.2,36.01
DDR3_CPU_CH1_DQ42: length 70.2
  TOP w0.102: v1(152.13,36.49) 151.71,36.49 151.57,36.63 145.8,36.63 U14.AB2
  BOTTOM w0.157: v1(152.13,36.49) 152.86,37.22 152.86,38.15 153.59,38.89 159.59,38.89 165.53,44.83 165.53,46.45 165.69,46.6 166.47,46.6 166.62,46.76 166.62,47.08 166.47,47.23 165.69,47.23 165.53,47.39 165.53,47.71 165.69,47.86 166.59,47.86 166.75,48.02 166.75,48.34 166.59,48.49 165.69,48.49 165.53,48.65 165.53,48.97 165.69,49.12 166.59,49.12 166.75,49.28 166.75,49.6 166.59,49.75 165.69,49.75 165.53,49.91 165.53,50.23 165.69,50.38 166.59,50.38 166.75,50.54 166.75,50.86 166.59,51.01 165.69,51.01 165.53,51.17 165.53,51.49 165.69,51.64 166.59,51.64 166.75,51.8 166.75,52.12 166.59,52.27 165.69,52.27 165.53,52.43 165.53,52.75 165.69,52.9 166.59,52.9 166.75,53.06 166.75,53.38 166.59,53.53 165.69,53.53 165.53,53.69 165.53,53.98 166.53,54.97 186.28,54.97 186.36,55.05 P4.159
DDR3_CPU_CH1_DQ43: length 70.2
  TOP w0.102: U14.AB4 145.08,36.45 145.47,36.84 151.51,36.84 v1(152.05,37.38)
  BOTTOM w0.157: P4.161 188.31,55.65 188.08,55.42 187.1,55.42 186.91,55.61 184.8,55.61 184.8,55.62 181.54,55.62 181.53,55.61 164.96,55.61 163.87,54.52 163.87,54.14 164.02,53.98 164.69,53.98 164.85,53.83 164.85,53.51 164.69,53.35 164.02,53.35 163.87,53.2 163.87,52.88 164.02,52.72 164.69,52.72 164.85,52.57 164.85,52.25 164.69,52.09 164.02,52.09 163.87,51.94 163.87,51.62 164.02,51.46 164.69,51.46 164.85,51.31 164.85,50.99 164.69,50.83 164.02,50.83 163.87,50.68 163.87,50.36 164.02,50.2 164.69,50.2 164.85,50.05 164.85,49.73 164.69,49.57 164.02,49.57 163.87,49.42 163.87,49.1 164.02,48.94 164.69,48.94 164.85,48.79 164.85,48.47 164.69,48.31 164.02,48.31 163.87,48.16 163.87,47.84 164.02,47.68 164.69,47.68 164.85,47.53 164.85,47.21 164.69,47.05 164.02,47.05 163.87,46.9 163.87,46.58 164.02,46.42 164.43,46.42 164.59,46.27 164.59,45.95 164.43,45.79 164.02,45.79 163.87,45.64 163.87,44.33 159.08,39.55 153.47,39.55 152.05,38.13 v1(152.05,37.38)
DDR3_CPU_CH1_DQ44: length 70.2
  TOP w0.102: v1(150.47,33.32) 150.47,33.3 150.38,33.2 146.88,33.2 146.58,33.51 145.27,33.51 U14.T3
  L10_SIG w0.135: v1(188.28,52.05) 188.93,52.7 194.71,52.7 195.19,52.22 v1(195.88,52.22)
  BOTTOM w0.157: v1(195.88,52.22) 196.43,51.66 198.04,51.66 P4.148 ; v1(150.47,33.32) 151.22,32.57 154.62,32.57 155.79,33.74 155.79,33.74 157.26,35.21 161.61,35.21 162.6,36.2 183.57,36.2 184.89,37.52 184.89,46.15 184.65,46.39 184.23,46.39 184.07,46.55 184.07,46.86 184.23,47.02 184.46,47.02 184.66,47.22 184.66,47.75 186.88,49.98 186.88,51.27 187.2,51.59 187.62,51.59 188.08,52.05 v1(188.28,52.05)
DDR3_CPU_CH1_DQ45: length 70.2
  TOP w0.102: v1(152.65,33.36) 152.2,32.91 146.52,32.91 U14.T1
  L10_SIG w0.135: v1(196.64,52.12) 195.56,53.21 188.55,53.21 v1(187.39,52.05)
  BOTTOM w0.157: v1(196.64,52.12) 196.64,52.19 196.8,52.35 P4.150 ; v1(187.39,52.05) 186.67,52.05 186.31,51.69 186.31,50.65 183.38,47.72 183.38,45.71 183.54,45.55 183.69,45.55 183.85,45.4 183.85,45.08 183.69,44.92 183.54,44.92 183.38,44.77 183.38,44.45 183.54,44.29 183.84,44.29 184,44.14 184,43.82 183.84,43.66 183.54,43.66 183.38,43.51 183.38,42.94 183.54,42.78 183.71,42.78 183.87,42.63 183.87,42.31 183.71,42.15 183.54,42.15 183.38,42 183.38,41.68 183.54,41.52 183.69,41.52 183.87,41.35 183.87,41.07 183.69,40.89 183.54,40.89 183.38,40.74 183.38,37.49 182.73,36.84 162.33,36.84 161.39,35.89 157.03,35.89 154.5,33.36 v1(152.65,33.36)
DDR3_CPU_CH1_DQ46: length 70.2
  TOP w0.102: v1(147.73,36.15) 147.3,35.72 145.59,35.72 145.21,35.33 U14.Y4
  L10_SIG w0.135: v1(195.9,55.65) 195.68,55.87 188.66,55.87 v1(188.28,56.25)
  BOTTOM w0.102: 152.31,40.87 151.57,40.87 150.47,39.78 150.47,36.93 150.11,36.57 148.15,36.57 v1(147.73,36.15)
  BOTTOM w0.157: v1(188.28,56.25) 188.28,56.26 187.82,56.72 186.72,56.72 186.5,56.94 164.2,56.94 162.59,55.32 162.59,46.13 157.33,40.87 152.31,40.87 ; v1(195.9,55.65) 196.41,55.14 196.99,55.14 197.2,55.35 P4.160
DDR3_CPU_CH1_DQ47: length 70.2
  TOP w0.102: v1(149.21,36.15) 149.12,36.15 148.49,35.52 145.88,35.52 U14.Y2
  L10_SIG w0.135: v1(196.66,55.65) 196.72,55.71 196.72,56.17 196.53,56.37 192.21,56.37 192.01,56.16 191.18,56.16 190.65,56.7 188.07,56.7 187.62,56.25 v1(187.39,56.25)
  BOTTOM w0.102: v1(149.21,36.15) 150.3,36.15 151.1,36.96 151.1,38.68 152.63,40.21 154.26,40.21
  BOTTOM w0.157: v1(187.39,56.25) 187.38,56.26 181.27,56.26 181.27,56.25 164.54,56.25 163.23,54.94 163.23,44.75 162.69,44.22 162.45,44.22 162.13,43.89 162.13,43.65 161.74,43.26 161.47,43.26 161.06,42.85 161.06,42.58 160.34,41.86 160.11,41.86 159.99,41.98 159.76,41.98 159.54,41.76 159.54,41.54 159.67,41.41 159.67,41.19 158.69,40.21 154.26,40.21 ; v1(196.66,55.65) 196.67,55.66 196.67,55.67 196.94,55.95 P4.162
DDR3_CPU_CH1_DQ48: length 70.9
  TOP w0.102: U14.W14 139.15,35.2 v1(138.35,35.2)
  L10_SIG w0.102: v1(138.35,35.2) 138.67,35.2 139.47,34.4 140.81,34.4 140.81,34.4 141.07,34.4 141.07,34.4 142.18,34.4 142.31,34.27 144.67,34.27 144.97,34.57 148.43,34.57
  L10_SIG w0.135: v1(188.48,57.23) 188.19,57.23 187.68,56.72 186.88,56.72 186.7,56.53 186.7,55.61 186.36,55.27 185.12,55.27 184.66,55.73 184.11,55.73 183.69,55.31 183.69,55.12 184.1,54.7 184.1,54.51 183.91,54.32 183.72,54.32 183.31,54.74 183.12,54.74 182.93,54.55 182.93,54.36 183.34,53.94 183.34,53.75 183.15,53.56 182.96,53.56 182.54,53.97 182.35,53.97 179.48,51.1 179.27,51.1 178.94,50.77 178.94,50.56 178.72,50.34 178.41,50.34 178.18,50.11 178.18,49.8 177.95,49.57 177.65,49.57 177.42,49.35 177.42,49.04 177.19,48.81 176.88,48.81 176.66,48.59 176.66,48.28 176.43,48.05 176.12,48.05 175.89,47.82 175.89,47.52 175.67,47.29 175.36,47.29 175.13,47.06 175.13,46.75 174.91,46.53 174.6,46.53 174.37,46.3 174.37,45.99 174.14,45.76 173.84,45.76 173.61,45.54 173.61,45.23 173.38,45 173.07,45 172.85,44.78 172.85,44.47 172.62,44.24 172.31,44.24 172.08,44.01 172.08,43.71 171.86,43.48 171.55,43.48 171.32,43.25 171.32,42.94 171.1,42.72 170.79,42.72 170.56,42.49 170.56,42.18 170.33,41.95 170.03,41.95 169.8,41.73 169.8,41.42 169.57,41.19 169.26,41.19 169.04,40.97 169.04,40.66 168.81,40.43 168.5,40.43 168.27,40.2 168.27,39.9 168.05,39.67 167.74,39.67 167.51,39.44 167.51,39.13 167.29,38.91 166.98,38.91 166.75,38.68 166.75,38.37 166.52,38.14 166.22,38.14 165.99,37.92 165.99,37.61 165.76,37.38 165.42,37.38 165.23,37.19 165.23,36.85 165,36.62 164.8,36.62 164.46,36.28 164.46,36.09 163.05,34.67 154.47,34.67 153.61,33.81 151.15,33.81 150.34,34.62 148.48,34.62 148.43,34.57
  BOTTOM w0.157: P4.165 188.72,56.85 188.48,57.08 v1(188.48,57.23)
DDR3_CPU_CH1_DQ49: length 70.9
  TOP w0.102: v1(139.88,35.19) 139.9,35.17 139.94,35.17 U14.W13
  L10_SIG w0.135: v1(151.11,35.56) 151.11,34.91 151.83,34.19 153.16,34.19 154.22,35.26 162.46,35.26 163.62,36.42 163.62,36.61 163.57,36.67 163.57,36.86 163.76,37.05 163.95,37.05 164,37 164.2,37 164.39,37.19 164.39,37.38 164.33,37.43 164.33,37.62 164.52,37.81 164.72,37.81 164.77,37.76 164.96,37.76 165.15,37.95 165.15,38.14 165.1,38.19 165.1,38.38 165.29,38.57 165.48,38.57 165.53,38.52 165.72,38.52 165.91,38.71 165.91,38.9 165.86,38.95 165.86,39.14 166.05,39.33 166.24,39.33 166.29,39.28 166.48,39.28 166.67,39.47 166.67,39.66 166.62,39.71 166.62,39.9 166.81,40.1 167,40.1 167.05,40.04 167.24,40.04 167.43,40.23 167.43,40.42 167.38,40.48 167.38,40.67 167.57,40.86 167.76,40.86 167.81,40.81 168.01,40.81 168.2,41 168.2,41.19 168.14,41.24 168.14,41.43 168.33,41.62 168.53,41.62 168.58,41.57 168.77,41.57 168.96,41.76 168.96,41.95 168.91,42 168.91,42.19 169.1,42.38 169.29,42.38 169.34,42.33 169.53,42.33 169.72,42.52 169.72,42.71 169.67,42.76 169.67,42.95 169.86,43.14 170.05,43.14 170.1,43.09 170.29,43.09 170.48,43.28 170.48,43.47 170.43,43.52 170.43,43.71 170.62,43.91 170.81,43.91 170.86,43.85 171.05,43.85 171.24,44.04 171.24,44.23 171.19,44.29 171.19,44.48 171.38,44.67 171.57,44.67 171.62,44.62 171.82,44.62 172.01,44.81 172.01,45 171.95,45.05 171.95,45.24 172.14,45.43 172.34,45.43 172.39,45.38 172.58,45.38 172.77,45.57 172.77,45.76 172.72,45.81 172.72,46 172.91,46.19 173.1,46.19 173.15,46.14 173.34,46.14 173.53,46.33 173.53,46.52 173.48,46.57 173.48,46.76 173.67,46.95 173.86,46.95 173.91,46.9 174.1,46.9 174.29,47.09 174.29,47.28 174.24,47.33 174.24,47.52 174.43,47.72 174.62,47.72 174.67,47.66 174.86,47.66 175.05,47.85 175.05,48.04 175,48.1 175,48.29 175.19,48.48 175.38,48.48 175.43,48.43 175.63,48.43 175.82,48.62 175.82,48.81 175.76,48.86 175.76,49.05 175.95,49.24 176.15,49.24 176.2,49.19 176.39,49.19 176.58,49.38 176.58,49.57 176.53,49.62 176.53,49.81 176.72,50 176.91,50 176.96,49.95 177.15,49.95 177.34,50.14 177.34,50.33 177.29,50.38 177.29,50.57 177.48,50.76 177.67,50.76 177.72,50.71 177.91,50.71 178.1,50.9 178.1,51.09 178.05,51.14 178.05,51.33 178.24,51.53 178.43,51.53 178.48,51.47 178.67,51.47 178.86,51.66 178.86,51.85 178.81,51.91 178.81,52.1 179,52.29 179.19,52.29 179.24,52.24 179.44,52.24 179.63,52.43 179.63,52.62 179.57,52.67 179.57,52.86 179.76,53.05 179.96,53.05 180.01,53 180.2,53 180.39,53.19 180.39,53.38 180.34,53.43 180.34,53.62 180.53,53.81 180.72,53.81 180.77,53.76 180.96,53.76 181.19,53.99 181.19,54.29 181.47,54.57 182.01,54.57 184.22,56.79 184.83,56.79 184.97,56.65 184.97,56.65 185.1,56.52 185.37,56.52 185.51,56.65 185.51,56.65 185.64,56.79 186.27,56.79 186.82,57.33 v1(187.66,57.33)
  BOTTOM w0.102: v1(139.88,35.19) 140.07,35.19 140.65,34.61 143.09,34.61 143.71,35.23 150.78,35.23 v1(151.11,35.56)
  BOTTOM w0.157: P4.167 189.01,57.45 188.75,57.71 188.04,57.71 v1(187.66,57.33)
DDR3_CPU_CH1_DQ50: length 71
  TOP w0.157: U14.W10 141.43,35.21 v1(141.41,35.21)
  L10_SIG w0.102: 149.39,39.86 149.05,39.86 148.29,39.1 148.29,37.98 147.44,37.13 145.63,37.13 144.64,36.15 143.58,36.15 143.37,36.35 143.2,36.52 141.49,36.52 141.04,36.07 141.04,35.57 v1(141.41,35.21)
  L10_SIG w0.135: v1(188.26,60.33) 188.26,60.2 188.07,60 187.58,60 187.58,60 187.2,60 187.2,60 186.08,60 185.56,60.53 179.19,60.53 178.88,60.21 178.88,60.02 178.95,59.95 178.95,59.76 178.76,59.56 178.57,59.56 178.49,59.64 178.3,59.64 178.11,59.45 178.11,59.26 178.19,59.18 178.19,58.99 178,58.8 177.81,58.8 177.73,58.88 177.54,58.88 177.35,58.69 177.35,58.5 177.43,58.42 177.43,58.23 177.24,58.04 177.05,58.04 176.97,58.12 176.78,58.12 176.59,57.93 176.59,57.74 176.67,57.66 176.67,57.47 176.47,57.28 176.28,57.28 176.21,57.35 176.02,57.35 175.83,57.16 175.83,56.97 175.9,56.9 175.9,56.71 175.71,56.52 175.52,56.52 175.45,56.59 175.26,56.59 175.07,56.4 175.07,56.21 175.14,56.14 175.14,55.95 174.95,55.75 174.76,55.75 174.68,55.83 174.49,55.83 174.3,55.64 174.3,55.45 174.38,55.37 174.38,55.18 174.19,54.99 174,54.99 173.92,55.07 173.73,55.07 173.54,54.88 173.54,54.69 173.62,54.61 173.62,54.42 173.43,54.23 173.24,54.23 173.16,54.31 172.97,54.31 172.78,54.12 172.78,53.93 172.86,53.85 172.86,53.66 172.66,53.47 172.47,53.47 172.4,53.54 172.21,53.54 172.02,53.35 172.02,53.16 172.09,53.09 172.09,52.9 171.9,52.71 171.71,52.71 171.64,52.78 171.45,52.78 171.26,52.59 171.26,52.4 171.33,52.33 171.33,52.14 171.14,51.94 170.95,51.94 170.87,52.02 170.68,52.02 170.49,51.83 170.49,51.64 170.57,51.56 170.57,51.37 170.38,51.18 170.19,51.18 170.11,51.26 169.92,51.26 169.61,50.94 169.42,50.94 169.2,51.16 169.01,51.16 168.82,50.97 168.82,50.77 169.03,50.56 169.03,50.37 168.84,50.18 168.65,50.18 168.44,50.39 168.25,50.39 168.06,50.2 168.06,50.01 168.27,49.8 168.27,49.61 168.08,49.42 167.89,49.42 167.76,49.55 167.41,49.55 167.14,49.28 167.14,48.62 166.92,48.41 166.64,48.41 166.35,48.11 166.35,46.15 159.45,39.26 153.98,39.26 153.38,39.86 149.39,39.86
  BOTTOM w0.157: v1(188.26,60.33) 188.39,60.45 P4.177
DDR3_CPU_CH1_DQ51: length 70.9
  TOP w0.157: v1(140.61,35.92) 140.65,35.92 U14.Y11
  L10_SIG w0.102: 148.84,40.44 148.05,40.44 147.72,40.1 147.72,37.81 147.28,37.37 145.58,37.37 144.56,36.35 143.69,36.35 143.29,36.76 141.41,36.76 140.66,36.01 140.66,35.98 v1(140.61,35.92)
  L10_SIG w0.135: v1(187.58,60.68) 187.58,60.63 187.4,60.45 187.05,60.45 186.31,61.19 183.06,61.19 183.04,61.17 178.13,61.17 177.57,60.61 177.57,60.22 177.62,60.17 177.62,59.98 177.43,59.79 177.24,59.79 177.09,59.94 176.9,59.94 176.71,59.75 176.71,59.56 176.86,59.41 176.86,59.22 176.67,59.03 176.47,59.03 176.33,59.18 176.14,59.18 175.95,58.99 175.95,58.79 176.09,58.65 176.09,58.46 175.9,58.27 175.71,58.27 175.57,58.41 175.38,58.41 175.19,58.22 175.19,58.03 175.33,57.89 175.33,57.7 175.14,57.51 174.95,57.51 174.8,57.65 174.61,57.65 174.42,57.46 174.42,57.27 174.57,57.12 174.57,56.93 174.38,56.74 174.19,56.74 174.04,56.89 173.85,56.89 173.66,56.7 173.66,56.51 173.81,56.36 173.81,56.17 173.62,55.98 173.43,55.98 173.28,56.13 173.09,56.13 172.9,55.94 172.9,55.75 173.05,55.6 173.05,55.41 172.86,55.22 172.66,55.22 172.52,55.37 172.33,55.37 172.14,55.18 172.14,54.98 172.28,54.84 172.28,54.65 172.09,54.46 171.9,54.46 171.76,54.6 171.57,54.6 171.38,54.41 171.38,54.22 171.52,54.08 171.52,53.89 171.33,53.7 171.14,53.7 170.99,53.84 170.8,53.84 170.61,53.65 170.61,53.46 170.76,53.31 170.76,53.12 170.57,52.93 170.38,52.93 170.23,53.08 170.04,53.08 169.75,52.79 169.75,52.66 169.41,52.32 169.28,52.32 165.78,48.82 165.78,46.39 159.22,39.83 154.12,39.83 153.51,40.44 148.84,40.44
  BOTTOM w0.157: P4.179 187.95,61.05 v1(187.58,60.68)
DDR3_CPU_CH1_DQ52: length 71
  TOP w0.157: U14.Y16 v1(138.38,35.91)
  L10_SIG w0.102: v1(138.38,35.91) 138.38,35.86 139.3,34.95 139.3,34.94 139.64,34.6 139.64,34.6 141.15,34.6 141.16,34.6 142.31,34.6 142.39,34.52 143.23,34.52 143.74,35.03 144.16,35.03 144.19,35 146.66,35
  L10_SIG w0.135: v1(196.7,57.15) 196.27,57.15 195.45,57.96 189.5,57.96 189.43,57.89 188.89,57.89 188.81,57.96 186.71,57.96 186.1,57.35 183.14,57.35 161.88,36.09 150.89,36.09 149.81,35 146.66,35
  BOTTOM w0.157: v1(196.7,57.15) P4.166
DDR3_CPU_CH1_DQ53: length 71
  TOP w0.157: U14.Y14 v1(139.14,35.91)
  L10_SIG w0.102: v1(139.14,35.91) 139.14,35.82 139.5,35.46 139.5,35.03 139.72,34.81 140.04,34.81 140.05,34.81 141.23,34.81 141.24,34.8 142.43,34.8 142.48,34.75 143.16,34.75 143.67,35.26 149.66,35.26 149.97,35.57
  L10_SIG w0.135: 149.97,35.57 151.35,36.95 152.44,36.95 152.73,36.65 161.64,36.65 164.15,39.16 164.15,39.3 164.53,39.68 164.67,39.68 164.91,39.92 164.91,40.2 165.16,40.44 165.43,40.44 165.68,40.69 165.68,40.96 165.92,41.2 166.19,41.2 182.91,57.92 186.13,57.92 186.43,58.22 188.03,58.22 188.15,58.35 195.52,58.35 195.85,58.02 v1(196.67,58.02)
  BOTTOM w0.157: P4.168 196.84,57.75 196.67,57.92 v1(196.67,58.02)
DDR3_CPU_CH1_DQ54: length 71
  TOP w0.157: v1(142.17,35.21) 142.19,35.21 U14.W8
  L10_SIG w0.102: 150,39.18 147.74,36.92 145.73,36.92 144.76,35.94 143.46,35.94 143.25,36.14 143.08,36.31 142.05,36.31 141.81,36.07 141.81,36.03 141.8,36.03 141.8,35.75 141.8,35.75 141.8,35.58 v1(142.17,35.21)
  L10_SIG w0.135: 150,39.18 150.11,39.29 153.14,39.29 153.74,38.69 159.69,38.69 166.91,45.92 166.91,46.88 168.28,48.25 168.28,48.54 168.91,49.17 169.2,49.17 169.54,49.51 169.54,49.89 169.85,50.2 170.23,50.2 179.97,59.94 185.26,59.94 185.47,59.74 187.09,59.74 187.09,59.74 187.68,59.74 187.69,59.74 188.5,59.74 189.77,61.01 194.77,61.01 195.81,59.97 v1(195.81,59.72)
  BOTTOM w0.157: v1(195.81,59.72) 196.13,59.39 197.03,59.39 197.19,59.55 P4.174
DDR3_CPU_CH1_DQ55: length 71
  TOP w0.102: U14.Y10 v1(141.42,35.91)
  L10_SIG w0.135: v1(149.9,37.35) 149.9,38.11 150.51,38.72 152.92,38.72 153.52,38.13 159.92,38.13 167.48,45.68 167.48,46.49 178.5,57.51 178.69,57.51 178.85,57.36 179.04,57.36 179.23,57.55 179.23,57.74 179.08,57.89 179.08,58.09 179.27,58.28 179.46,58.28 179.79,57.95 179.98,57.95 180.17,58.14 180.17,58.33 179.84,58.66 179.84,58.85 180.35,59.36 184.91,59.36 184.98,59.29 186.86,59.29 186.99,59.42 189.02,59.42 189.19,59.26 196.19,59.26 196.66,59.73 v1(196.66,59.85)
  BOTTOM w0.102: v1(149.9,37.35) 149.46,36.91 145.96,36.91 145.37,36.32 143.43,36.32 143.28,36.47 141.94,36.47 141.42,35.95 v1(141.42,35.91)
  BOTTOM w0.157: P4.176 196.85,60.15 196.66,59.96 v1(196.66,59.85)
DDR3_CPU_CH1_DQ56: length 83.8
  TOP w0.157: U14.AC8 143.51,36.84 143.59,36.91 v1(143.74,36.91)
  L10_SIG w0.102: 152.22,41.4 152.2,41.43 148.46,41.43 148.43,41.4 148.43,41.4 147.26,40.23 146.38,40.23 146.22,40.07 146.22,39.09 145.32,38.19 145.32,37.78 144.84,37.29 143.91,37.29 143.72,37.1 143.69,37.05 v1(143.74,36.91)
  L10_SIG w0.135: 152.22,41.4 154.06,41.4 154.66,40.8 158.3,40.8 163.52,46.02 163.52,46.49 163.52,48 164.58,49.07 164.58,49.26 164.3,49.54 164.3,49.73 164.49,49.92 164.68,49.92 164.96,49.64 165.15,49.64 165.34,49.83 165.34,50.02 164.88,50.48 164.88,50.67 165.08,50.86 165.27,50.86 165.73,50.4 165.92,50.4 166.11,50.59 166.11,50.78 165.65,51.24 165.65,51.43 165.84,51.62 166.03,51.62 166.49,51.16 166.68,51.16 166.87,51.35 166.87,51.54 166.41,52 166.41,52.19 166.6,52.38 166.79,52.38 167.25,51.92 167.44,51.92 167.63,52.12 167.63,52.31 167.17,52.77 167.17,52.96 167.36,53.15 167.55,53.15 168.01,52.69 168.2,52.69 168.39,52.88 168.39,53.07 167.93,53.53 167.93,53.72 168.12,53.91 168.31,53.91 168.77,53.45 168.96,53.45 169.15,53.64 169.15,53.83 168.69,54.29 168.69,54.48 168.89,54.67 169.08,54.67 169.54,54.21 169.73,54.21 169.92,54.4 169.92,54.59 169.46,55.05 169.46,55.24 169.65,55.43 169.84,55.43 170.3,54.97 170.49,54.97 170.68,55.16 170.68,55.35 170.22,55.81 170.22,56 170.41,56.19 170.6,56.19 171.06,55.73 171.25,55.73 171.44,55.93 171.44,56.12 170.98,56.58 170.98,56.77 171.17,56.96 171.36,56.96 171.82,56.5 172.01,56.5 172.2,56.69 172.2,56.88 171.74,57.34 171.74,57.53 171.93,57.72 172.12,57.72 172.58,57.26 172.77,57.26 172.96,57.45 172.96,57.64 172.5,58.1 172.5,58.29 172.7,58.48 172.89,58.48 173.35,58.02 173.54,58.02 173.73,58.21 173.73,58.4 173.27,58.86 173.27,59.05 173.46,59.24 173.65,59.24 174.11,58.78 174.3,58.78 174.49,58.97 174.49,59.16 174.03,59.62 174.03,59.81 174.22,60 174.41,60 174.87,59.54 175.06,59.54 175.38,59.86 175.38,60.05 175,60.43 175,60.62 175.19,60.81 175.38,60.81 175.76,60.43 175.95,60.43 176.14,60.62 176.14,60.81 175.79,61.17 175.79,61.37 175.97,61.55 176.17,61.55 176.52,61.2 176.71,61.2 177.76,62.25 187.09,62.25 187.31,62.47 v1(187.59,62.47)
  BOTTOM w0.157: v1(187.59,62.47) 187.91,62.15 188.53,62.15 188.63,62.25 P4.183
DDR3_CPU_CH1_DQ57: length 83.7
  TOP w0.157: v1(143.55,37.56) 143.44,37.56 143.42,37.54 U14.AD8
  L10_SIG w0.102: v1(143.55,37.56) 143.65,37.56 143.71,37.5 144.75,37.5 145.08,37.83 145.08,38.4 145.91,39.23 145.91,40.51 146.46,41.07 147.5,41.07 148.14,41.71 152.58,41.71
  L10_SIG w0.135: 152.58,41.71 154.54,41.71 154.88,41.37 158.07,41.37 162.95,46.25 162.95,49.68 163.57,50.3 163.57,50.49 163.22,50.85 163.22,51.04 163.41,51.23 163.6,51.23 163.95,50.88 164.15,50.88 164.34,51.07 164.34,51.26 163.88,51.71 163.88,51.9 164.07,52.09 164.26,52.09 164.72,51.64 164.91,51.64 165.1,51.83 165.1,52.02 164.64,52.47 164.64,52.66 164.84,52.85 165.03,52.85 165.48,52.4 165.67,52.4 165.86,52.59 165.86,52.78 165.41,53.23 165.41,53.42 165.6,53.61 165.79,53.61 166.24,53.16 166.43,53.16 166.62,53.35 166.62,53.54 166.17,54 166.17,54.19 166.36,54.38 166.55,54.38 167,53.92 167.19,53.92 167.38,54.11 167.38,54.3 166.93,54.76 166.93,54.95 167.12,55.14 167.31,55.14 167.76,54.69 167.96,54.69 168.15,54.88 168.15,55.07 167.69,55.52 167.69,55.71 167.88,55.9 168.07,55.9 168.53,55.45 168.72,55.45 168.91,55.64 168.91,55.83 168.45,56.28 168.45,56.47 168.65,56.66 168.84,56.66 169.29,56.21 169.48,56.21 169.67,56.4 169.67,56.59 169.22,57.04 169.22,57.23 169.41,57.42 169.6,57.42 170.05,56.97 170.24,56.97 170.43,57.16 170.43,57.35 169.98,57.81 169.98,58 170.17,58.19 170.36,58.19 170.81,57.73 171,57.73 171.19,57.92 171.19,58.11 170.74,58.57 170.74,58.76 170.93,58.95 171.12,58.95 171.57,58.5 171.77,58.5 171.96,58.69 171.96,58.88 171.5,59.33 171.5,59.52 171.69,59.71 171.88,59.71 172.34,59.26 172.53,59.26 172.72,59.45 172.72,59.64 172.26,60.09 172.26,60.28 172.46,60.47 172.65,60.47 173.1,60.02 173.29,60.02 173.48,60.21 173.48,60.4 173.03,60.85 173.03,61.04 173.22,61.23 173.41,61.23 173.86,60.78 174.05,60.78 174.24,60.97 174.24,61.16 173.8,61.6 173.8,61.79 173.99,61.98 174.18,61.98 174.62,61.54 174.81,61.54 175.1,61.83 175.1,62.07 175.41,62.38 175.65,62.38 176.09,62.82 185.37,62.82 185.67,63.12 187.83,63.12 v1(188.34,62.61)
  BOTTOM w0.157: P4.185 188.58,62.85 v1(188.34,62.61)
DDR3_CPU_CH1_DQ58: length 83.8
  TOP w0.102: v1(139.5,38.03) 139.5,37.91 U14.AD15
  L10_SIG w0.102: 143.83,44.31 143.35,43.82 140.59,43.82 140.54,43.77 140.5,43.77 140.09,43.36 140.09,42.18 140.64,41.63 140.64,41.32 140.64,41.32 140.64,40.3 140.64,40.3 140.64,39.98 140.26,39.59 140.26,38.86 139.5,38.09 v1(139.5,38.03)
  L10_SIG w0.135: 143.83,44.31 145.03,44.31 146.46,45.75 150.49,45.75 150.62,45.61 150.62,44.71 150.76,44.58 151.03,44.58 151.16,44.71 151.16,45.61 151.29,45.75 151.56,45.75 151.7,45.61 151.7,44.62 151.83,44.48 152.1,44.48 152.24,44.62 152.24,45.61 152.37,45.75 152.64,45.75 152.78,45.61 152.78,44.62 152.91,44.48 153.18,44.48 153.31,44.62 153.31,45.61 153.45,45.75 153.72,45.75 153.85,45.61 153.85,44.62 153.99,44.48 154.26,44.48 154.39,44.62 154.39,45.61 154.53,45.75 154.79,45.75 154.93,45.61 154.93,44.84 155.06,44.7 155.33,44.7 155.47,44.84 155.47,45.61 155.6,45.75 156.03,45.75 156.17,45.61 156.17,45.49 156.3,45.35 156.57,45.35 156.7,45.49 156.7,45.61 156.84,45.75 157.22,45.75 159.75,48.28 159.75,58.59 167.63,66.47 184.44,66.47 185.28,65.63 187.67,65.63 187.81,65.5 v1(187.81,65.48)
  BOTTOM w0.157: v1(187.81,65.48) 188.64,64.65 P4.191
DDR3_CPU_CH1_DQ59: length 83.7
  TOP w0.102: U14.AC17 138.71,37.19 v1(138.73,37.19)
  L10_SIG w0.102: 143.12,45.53 142.93,45.35 142.93,44.27 142.68,44.03 140.51,44.03 140.45,43.98 140.09,43.98 139.8,43.68 139.8,43.11 139.58,42.89 139.58,42.16 139.88,41.85 139.88,41 139.8,40.92 139.8,39.93 139.5,39.63 139.5,38.95 138.73,38.18 v1(138.73,37.19)
  L10_SIG w0.135: 143.12,45.53 144.49,45.53 145.29,46.33 153.75,46.33 154.26,46.84 154.68,46.84 155.06,46.46 155.53,46.46 155.67,46.6 155.67,46.95 155.11,47.5 155.11,47.69 155.3,47.88 155.49,47.88 156.44,46.93 156.63,46.93 156.82,47.13 156.82,47.32 155.87,48.27 155.87,48.46 156.06,48.65 156.25,48.65 157.2,47.7 157.39,47.7 157.58,47.89 157.58,48.08 156.63,49.03 156.63,49.22 156.83,49.41 157.02,49.41 157.97,48.46 158.16,48.46 158.35,48.65 158.35,48.84 157.4,49.79 157.4,49.98 159.09,51.67 159.09,58.73 167.39,67.04 186.22,67.04 187.1,66.17 188.11,66.17 v1(188.52,65.76)
  BOTTOM w0.157: P4.193 188.75,65.25 188.49,65.51 188.49,65.73 v1(188.52,65.76)
DDR3_CPU_CH1_DQ60: length 83.8
  TOP w0.157: U14.AC11 141.49,36.84 141.78,37.13 v1(141.78,37.19)
  L10_SIG w0.102: v1(141.78,37.19) 142.22,37.63 142.78,37.63 142.94,37.79 142.94,38 143.24,38.3 144.12,38.3 144.34,38.52 144.37,38.52 144.76,38.92 144.76,39.84 145.31,40.39 145.31,40.59 146.24,41.51 147.31,41.51 148.17,42.37 150.7,42.37
  L10_SIG w0.135: 150.7,42.37 154.83,42.37 155.06,42.6 157.7,42.6 161.8,46.7 161.8,52.54 162.19,52.93 162.19,53.12 161.99,53.32 161.99,53.51 162.18,53.7 162.37,53.7 162.57,53.5 162.76,53.5 162.95,53.69 162.95,53.88 162.75,54.09 162.75,54.28 162.94,54.47 163.13,54.47 163.33,54.27 163.52,54.27 163.71,54.46 163.71,54.65 163.51,54.85 163.51,55.04 163.7,55.23 163.89,55.23 164.09,55.03 164.29,55.03 164.48,55.22 164.48,55.41 164.27,55.61 164.27,55.8 164.46,55.99 164.65,55.99 164.86,55.79 165.05,55.79 165.24,55.98 165.24,56.17 165.04,56.37 165.04,56.56 165.23,56.75 165.42,56.75 165.62,56.55 165.81,56.55 166,56.74 166,56.93 165.8,57.13 165.8,57.32 165.99,57.51 166.18,57.51 166.38,57.31 166.57,57.31 166.76,57.5 166.76,57.69 166.56,57.9 166.56,58.09 166.75,58.28 166.94,58.28 167.14,58.08 167.33,58.08 167.52,58.27 167.52,58.46 167.32,58.66 167.32,58.85 167.51,59.04 167.7,59.04 167.9,58.84 168.1,58.84 168.29,59.03 168.29,59.22 168.08,59.42 168.08,59.61 168.27,59.8 168.46,59.8 168.67,59.6 168.86,59.6 169.05,59.79 169.05,59.98 168.85,60.18 168.85,60.37 169.04,60.56 169.23,60.56 169.43,60.36 169.62,60.36 169.81,60.55 169.81,60.74 169.61,60.94 169.61,61.13 169.8,61.32 169.99,61.32 170.23,61.08 170.42,61.08 170.61,61.27 170.61,61.46 170.37,61.71 170.37,61.9 170.56,62.09 170.75,62.09 170.95,61.89 171.14,61.89 171.33,62.08 171.33,62.27 171.2,62.4 171.2,62.87 171.37,63.04 172.3,63.04 173.21,63.95 190.53,63.95 191.48,63 195.73,63 196.7,62.03 v1(196.7,61.7)
  BOTTOM w0.157: P4.180 197.04,61.35 v1(196.7,61.7)
DDR3_CPU_CH1_DQ61: length 83.7
  TOP w0.157: U14.AC9 142.19,36.84 v1(142.55,37.19)
  L10_SIG w0.102: v1(142.55,37.19) 142.74,37.19 143.14,37.59 143.14,37.86 143.33,38.05 144.14,38.05 144.19,38.1 144.21,38.1 144.43,38.32 144.63,38.32 145.03,38.72 145.08,38.72 145.66,39.3 145.66,40.62 146.31,41.27 147.41,41.27 148.18,42.04 151.51,42.04
  L10_SIG w0.135: 151.51,42.04 157.94,42.04 162.36,46.46 162.36,51.35 162.78,51.77 162.78,51.96 162.55,52.19 162.55,52.38 162.75,52.57 162.94,52.57 163.16,52.34 163.35,52.34 163.54,52.53 163.54,52.72 163.32,52.95 163.32,53.14 163.51,53.33 163.7,53.33 163.92,53.1 164.11,53.1 164.31,53.29 164.31,53.48 164.08,53.71 164.08,53.9 164.27,54.09 164.46,54.09 164.69,53.86 164.88,53.86 165.07,54.05 165.07,54.24 164.84,54.47 164.84,54.66 165.03,54.85 165.22,54.85 165.45,54.62 165.64,54.62 165.83,54.82 165.83,55.01 165.6,55.23 165.6,55.42 165.79,55.61 165.98,55.61 166.21,55.39 166.4,55.39 166.59,55.58 166.59,55.77 166.36,56 166.36,56.19 166.56,56.38 166.75,56.38 166.97,56.15 167.16,56.15 167.35,56.34 167.35,56.53 167.13,56.76 167.13,56.95 167.32,57.14 167.51,57.14 167.73,56.91 167.92,56.91 168.12,57.1 168.12,57.29 167.89,57.52 167.89,57.71 168.08,57.9 168.27,57.9 168.5,57.67 168.69,57.67 168.88,57.86 168.88,58.05 168.65,58.28 168.65,58.47 168.84,58.66 169.03,58.66 169.26,58.43 169.45,58.43 169.64,58.63 169.64,58.82 169.41,59.04 169.41,59.23 169.6,59.42 169.79,59.42 170.02,59.2 170.21,59.2 170.4,59.39 170.4,59.58 170.17,59.81 170.17,60 170.37,60.19 170.56,60.19 170.78,59.96 170.97,59.96 171.16,60.15 171.16,60.34 170.94,60.57 170.94,60.76 171.13,60.95 171.32,60.95 171.54,60.72 171.73,60.72 171.93,60.91 171.93,61.1 171.7,61.33 171.7,61.52 171.89,61.71 172.08,61.71 172.31,61.48 172.5,61.48 172.69,61.67 172.69,61.86 172.56,61.99 172.56,62.25 172.79,62.47 173.49,62.47 174.4,63.38 184.77,63.38 184.88,63.5 189.87,63.5 190.84,62.53 191.72,62.53 192.6,61.65 195.88,61.65 v1(195.92,61.69)
  BOTTOM w0.157: P4.182 197.18,61.95 196.95,62.18 196.42,62.18 v1(195.92,61.69)
DDR3_CPU_CH1_DQ62: length 83.7
  TOP w0.102: U14.AC14 140.24,37.19 v1(140.26,37.19)
  L10_SIG w0.102: v1(140.26,37.19) 140.26,38.08 141.03,38.85 141.03,39.43 141.41,39.81 141.41,41.32 141.63,41.54 141.63,41.54 141.76,41.66 144.09,41.66 144.63,42.21 146.68,42.21 147.57,43.1
  L10_SIG w0.135: 147.57,43.1 147.81,43.33 154.15,43.33 154.83,44.01 156.84,44.01 160.4,47.58 160.4,58.45 162.84,60.89 163.03,60.89 163.07,60.85 163.26,60.85 163.45,61.04 163.45,61.23 163.41,61.27 163.41,61.46 163.6,61.65 163.8,61.65 163.99,61.45 164.18,61.45 164.37,61.64 164.37,61.83 164.18,62.03 164.18,62.22 164.37,62.41 164.56,62.41 164.77,62.2 164.96,62.2 165.15,62.39 165.15,62.58 164.94,62.79 164.94,62.98 165.13,63.17 165.32,63.17 165.53,62.96 165.72,62.96 165.91,63.15 165.91,63.34 165.7,63.55 165.7,63.75 165.89,63.94 166.08,63.94 166.29,63.72 166.48,63.72 166.68,63.91 166.68,64.1 166.46,64.32 166.46,64.51 166.65,64.7 166.84,64.7 167.06,64.48 167.25,64.48 167.44,64.68 167.44,64.87 167.22,65.08 167.22,65.27 167.73,65.77 184.42,65.77 185.22,64.97 189.43,64.97 189.99,65.53 194.07,65.53 194.35,65.25 v1(195.9,65.25)
  BOTTOM w0.157: v1(195.9,65.25) 196.39,64.76 196.87,64.76 197.06,64.95 P4.192
DDR3_CPU_CH1_DQ63: length 83.7
  TOP w0.102: U14.AC15 v1(139.49,36.47)
  L10_SIG w0.102: v1(139.49,36.47) 138.68,36.47 138.31,36.84 138.31,37.71 138.34,37.74 138.34,38.41 138.73,38.81 138.73,40.46 139.12,40.85 139.12,41.66 138.74,42.04 138.74,44.1 139.39,44.75 140.42,44.75 140.42,44.75 140.61,44.75 141.28,45.42
  L10_SIG w0.135: v1(196.66,65.25) 196.66,65.57 195.68,66.55 187.58,66.55 186.52,67.61 167.06,67.61 158.1,58.65 158.1,52.32 153.35,47.56 145.53,47.56 143.9,45.92 142.81,45.92 142.47,45.59 141.46,45.59 141.28,45.42
  BOTTOM w0.157: v1(196.66,65.25) 196.96,65.55 P4.194
DDR3_CPU_CH1_DQS_DN0: length 93.2
  TOP w0.157: U14.B37 128.24,26.41 v1(127.87,26.05)
  L10_SIG w0.135: v1(196.22,7.83) 195.93,8.12 194.84,8.12 193.67,6.95 186.53,6.95 186.52,6.96 186.36,6.96 185.42,7.9 v1(185.12,7.9)
  BOTTOM w0.102: 129.07,15.62 129.07,15.68 127.81,16.93 127.81,21.51 127.64,21.68 127.64,21.89 127.81,22.06 127.81,22.47 127.65,22.63 127.65,22.89 127.81,23.05 127.81,23.6 128.18,23.97 128.18,25.98 128.11,26.05 v1(127.87,26.05)
  BOTTOM w0.157: v1(196.22,7.83) 196.48,8.1 196.82,8.1 196.97,7.95 P4.10 ; v1(185.12,7.9) 185.12,8.3 184.23,9.19 174.92,9.19 173.49,7.76 172.41,7.76 172.16,7.51 172.16,7.28 171.79,6.91 171.28,6.91 170.96,7.23 170.96,7.49 170.8,7.65 170.49,7.65 170.33,7.49 170.33,7.18 170.01,6.85 169.46,6.85 169.13,7.18 169.13,7.49 168.97,7.65 168.66,7.65 168.5,7.49 168.5,7.18 168.18,6.85 167.63,6.85 167.3,7.18 167.3,7.49 167.15,7.65 166.34,7.65 165,6.31 159.78,6.31 158.73,5.27 150.94,5.27 149.89,6.31 145.46,6.31 144.06,4.92 141.58,4.92 132,14.5 130.2,14.5 129.98,14.71 129.97,14.71 129.07,15.62
DDR3_CPU_CH1_DQS_DN1: length 86.8
  TOP w0.102: v1(132.94,18.25) 133.25,18.56 133.25,19.19 132.68,19.76 132.68,19.95 132.54,20.09 132.54,20.24 132.68,20.39 132.68,20.53 132.53,20.68 132.53,20.85 132.68,21 132.68,21.67 131.8,22.56 131.8,26.35 U14.B30
  L10_SIG w0.135: v1(188.37,12.27) 188.37,12.22 188.16,12.01 186.57,12.01 186.39,11.84 186.03,11.84 185.86,12.01 185.5,12.01 185.32,11.84 184.96,11.84 184.78,12.01 184.13,12.01 183.09,10.98 153.67,10.98 153.38,11.27 153.38,11.73 153.25,11.87 152.98,11.87 152.84,11.73 152.84,11.27 152.55,10.98 152.07,10.98 151.78,11.27 151.78,11.9 151.65,12.03 151.38,12.03 151.24,11.9 151.24,11.27 150.95,10.98 150.47,10.98 150.18,11.27 150.18,11.82 150.05,11.96 149.78,11.96 149.64,11.82 149.64,11.27 149.35,10.98 148.87,10.98 148.58,11.27 148.58,11.82 148.45,11.96 148.18,11.96 148.04,11.82 148.04,11.27 147.75,10.98 147.27,10.98 146.98,11.27 146.98,11.82 146.85,11.96 146.58,11.96 146.44,11.82 146.44,11.27 146.15,10.98 145.67,10.98 145.38,11.27 145.38,11.82 145.24,11.96 144.98,11.96 144.84,11.82 144.84,11.27 144.55,10.98 144.07,10.98 143.78,11.27 143.78,11.82 143.64,11.96 143.38,11.96 143.24,11.82 143.24,11.27 142.95,10.98 142.47,10.98 142.18,11.27 142.18,11.82 142.04,11.96 141.78,11.96 141.64,11.82 141.64,11.27 141.35,10.98 140.87,10.98 140.58,11.27 140.58,11.82 140.44,11.96 140.17,11.96 140.04,11.82 140.04,11.27 139.75,10.98 139.27,10.98 138.98,11.27 138.98,11.82 138.84,11.96 138.57,11.96 138.44,11.82 138.44,11.27 138.15,10.98 137.14,10.98 136.81,11.32 136.23,11.32 133.19,14.36 133.19,18.01 v1(132.94,18.25)
  BOTTOM w0.157: P4.25 188.57,12.45 188.39,12.27 v1(188.37,12.27)
DDR3_CPU_CH1_DQS_DN2: length 81.6
  TOP w0.102: U14.C22 135.75,26.61 135.73,26.59 135.73,24.18 136.03,23.88 138.96,20.95 138.96,19.11 139.74,18.33 139.74,17.97 v1(139.42,17.65)
  BOTTOM w0.157: P4.43 188.75,17.85 188.6,18 188.08,18 187.53,17.45 182.7,17.45 180.7,19.46 179.54,19.46 179.38,19.3 179.38,18.98 179.06,18.65 178.51,18.65 178.18,18.98 178.18,19.3 178.02,19.46 176.64,19.46 176.31,19.78 176.31,20.03 176.16,20.19 175.84,20.19 175.68,20.03 175.68,19.78 175.36,19.46 174.81,19.46 174.49,19.78 174.49,20.03 174.33,20.19 174.01,20.19 173.86,20.03 173.86,19.78 173.53,19.46 172.98,19.46 172.66,19.78 172.66,20.03 172.48,20.21 172.18,20.21 172.03,20.05 172.03,19.78 171.7,19.46 171.15,19.46 170.83,19.78 170.83,20.08 170.67,20.24 170.36,20.24 170.2,20.08 170.2,19.78 169.87,19.46 169.32,19.46 169,19.78 169,20.08 168.84,20.24 168.53,20.24 168.37,20.08 168.37,19.78 168.05,19.46 167.49,19.46 167.17,19.78 167.17,20.08 167.01,20.24 166.7,20.24 166.54,20.08 166.54,19.78 166.22,19.46 165.11,19.46 164.96,19.3 164.96,17.98 164.63,17.65 164.08,17.65 163.76,17.98 163.76,19.3 163.6,19.46 163.02,19.46 162.46,18.9 162.46,17.55 162.62,17.4 163.34,17.4 163.66,17.07 163.66,16.52 163.34,16.2 162.62,16.2 162.46,16.04 162.46,14.35 161.47,13.36 143.08,13.36 139.7,16.74 139.7,17.36 v1(139.42,17.65)
DDR3_CPU_CH1_DQS_DN3: length 78.2
  TOP w0.157: v1(132.82,30.21) U14.L29
  L10_SIG w0.102: v1(132.82,30.21) 133.13,30.21 133.6,29.74 133.6,28.11 134.16,27.55 134.16,27.36 133.98,27.18 133.98,27.03 134.11,26.89 134.11,26.75 133.98,26.62 133.98,26.37 134.16,26.18 134.16,25.98 134.68,25.46 134.68,25.42 134.69,25.4
  L10_SIG w0.135: 134.69,25.4 134.96,25.14 136.42,25.14 138.68,22.88 142.73,22.88 144.02,21.59 148.33,21.59 149.27,22.53 155.74,22.53 155.88,22.4 155.88,21.29 156.17,21 156.65,21 156.94,21.29 156.94,22.4 157.07,22.53 158.01,22.53 160.67,19.87 181.16,19.87 181.58,20.29 181.58,21.66 182.45,22.53 184.87,22.53 185.15,22.81 190.64,22.81 191.2,23.37 191.65,23.37 191.95,23.07 196.25,23.07 v1(196.53,22.79)
  BOTTOM w0.157: v1(196.53,22.79) 196.69,22.95 P4.60
DDR3_CPU_CH1_DQS_DN4: length 74.4
  TOP w0.157: U14.U12 140.86,33.56 141.02,33.41 v1(141.02,33.21)
  L10_SIG w0.102: 147.52,30.78 147.5,30.8 147.25,30.8 146.99,30.54 144.55,30.54 143.78,31.31 143.26,31.31 143.09,31.14 142.93,31.14 142.76,31.31 142.48,31.31 142.34,31.17 142.12,31.17 141.16,32.13 141.16,33.07 v1(141.02,33.21)
  L10_SIG w0.135: v1(188.11,48.82) 186.57,48.82 185.71,47.95 185.3,47.95 185.14,48.11 184.95,48.11 184.76,47.92 184.76,47.73 184.92,47.57 184.92,47.17 184.56,46.81 184.16,46.81 183.9,47.06 183.71,47.06 183.52,46.87 183.52,46.68 183.78,46.43 183.78,46.02 183.43,45.68 183.02,45.68 182.81,45.9 182.62,45.9 182.42,45.71 182.42,45.52 182.64,45.3 182.64,44.89 182.3,44.55 181.89,44.55 181.67,44.77 181.48,44.77 181.29,44.58 181.29,44.39 181.51,44.17 181.51,43.76 181.17,43.42 180.76,43.42 180.54,43.63 180.35,43.63 180.16,43.44 180.16,43.25 180.38,43.03 180.38,42.63 180.03,42.28 179.63,42.28 179.41,42.5 179.22,42.5 179.03,42.31 179.03,42.12 179.25,41.9 179.25,41.5 178.9,41.15 178.49,41.15 178.28,41.37 178.09,41.37 177.9,41.18 177.9,40.99 178.11,40.77 178.11,40.36 177.77,40.02 177.36,40.02 177.14,40.24 176.95,40.24 176.76,40.05 176.76,39.86 176.98,39.64 176.98,39.23 176.64,38.89 176.23,38.89 176.01,39.1 175.82,39.1 175.63,38.91 175.63,38.72 175.85,38.51 175.85,38.1 175.5,37.75 175.1,37.75 174.88,37.97 174.69,37.97 174.5,37.78 174.5,37.59 174.72,37.37 174.72,36.97 174.37,36.62 173.97,36.62 173.75,36.84 173.56,36.84 173.37,36.65 173.37,36.46 173.58,36.24 173.58,35.83 173.24,35.49 172.83,35.49 172.61,35.71 172.42,35.71 172.23,35.52 172.23,35.33 172.45,35.11 172.45,34.7 172.11,34.36 171.7,34.36 171.48,34.58 171.29,34.58 171.1,34.38 171.1,34.19 171.32,33.98 171.32,33.57 170.98,33.22 170.57,33.22 170.35,33.44 170.16,33.44 169.97,33.25 169.97,33.06 170.19,32.84 170.19,32.44 169.84,32.09 169.44,32.09 169.22,32.31 169.03,32.31 168.84,32.12 168.84,31.93 169.06,31.71 169.06,31.3 168.17,30.42 149.56,30.42 149.5,30.37 148.53,30.37 148.12,30.78 147.52,30.78
  BOTTOM w0.157: v1(188.11,48.82) 188.11,49.18 188.28,49.35 188.7,49.35 189,49.05 P4.139
DDR3_CPU_CH1_DQS_DN5: length 70.9
  TOP w0.102: v1(152.72,34.66) 152.45,34.94 147.59,34.94 147,34.35 146.05,34.35 145.8,34.6 U14.W3
  L10_SIG w0.135: v1(188.28,54.15) 189.03,54.91 194.84,54.91 v1(195.9,53.85)
  BOTTOM w0.157: P4.154 196.2,53.55 v1(195.9,53.85) ; v1(188.28,54.15) 188.14,54.15 187.33,53.34 185.14,53.34 184.89,53.59 169.29,53.59 168,52.31 168,45.4 166.35,43.75 166.35,43.52 166.64,43.24 166.64,42.78 166.25,42.39 165.79,42.39 165.5,42.68 165.28,42.68 165.06,42.45 165.06,42.23 165.34,41.95 165.34,41.49 164.95,41.1 164.49,41.1 164.21,41.38 163.99,41.38 163.76,41.16 163.76,40.94 164.05,40.65 164.05,40.19 163.66,39.8 163.2,39.8 162.98,40.03 162.63,40.03 160.55,37.94 155.06,37.94 154.4,37.28 154.4,35.92 153.38,34.9 152.96,34.9 v1(152.72,34.66)
DDR3_CPU_CH1_DQS_DN6: length 71.5
  TOP w0.157: v1(142.93,35.21) 142.94,35.21 143.3,34.85 U14.W7
  L10_SIG w0.102: v1(142.93,35.21) 143.21,35.48 149.48,35.48 150.72,36.72 150.72,37.28 151.34,37.91 152.46,37.91 152.78,37.59 152.78,37.54 152.8,37.53
  L10_SIG w0.135: v1(188.47,58.81) 188.45,58.83 188.24,58.83 187.9,58.49 186.21,58.49 186.21,58.49 182.29,58.49 179.31,55.5 178.9,55.5 178.44,55.96 178.25,55.96 178.06,55.77 178.06,55.58 178.52,55.12 178.52,54.72 178.17,54.37 177.77,54.37 177.36,54.78 177.17,54.78 176.98,54.59 176.98,54.4 177.39,53.99 177.39,53.58 177.04,53.24 176.64,53.24 176.22,53.65 176.03,53.65 175.84,53.46 175.84,53.27 176.25,52.86 176.25,52.45 175.91,52.11 175.5,52.11 175.09,52.52 174.9,52.52 174.71,52.33 174.71,52.14 175.12,51.73 175.12,51.32 174.78,50.97 174.37,50.97 173.96,51.39 173.77,51.39 173.58,51.19 173.58,51 173.99,50.59 173.99,50.19 173.65,49.84 173.24,49.84 172.83,50.25 172.64,50.25 172.45,50.06 172.45,49.87 172.86,49.46 172.86,49.05 172.51,48.71 172.11,48.71 171.7,49.12 171.5,49.12 171.31,48.93 171.31,48.74 171.73,48.33 171.73,47.92 171.38,47.58 170.97,47.58 170.56,47.99 170.37,47.99 170.18,47.8 170.18,47.61 170.59,47.2 170.59,46.79 170.25,46.45 169.84,46.45 169.63,46.65 169.44,46.65 169.25,46.46 169.25,46.27 169.46,46.06 169.46,45.66 161.02,37.22 153.1,37.22 152.8,37.53
  BOTTOM w0.157: v1(188.47,58.81) 188.63,58.65 P4.171
DDR3_CPU_CH1_DQS_DN7: length 84.3
  TOP w0.157: U14.AD11 v1(141.78,37.91)
  L10_SIG w0.102: 149.43,42.7 149.4,42.7 149.37,42.73 147.89,42.73 146.94,41.78 145.79,41.78 144.8,40.79 144.52,40.79 144.31,40.58 144.31,38.9 143.99,38.59 141.75,38.59 141.5,38.33 141.5,38.19 v1(141.78,37.91)
  L10_SIG w0.135: 149.43,42.7 154.39,42.7 154.4,42.7 154.61,42.7 155.09,43.19 157.31,43.19 161.23,47.11 161.23,54 162.03,54.8 162.03,55.21 161.63,55.61 161.63,55.8 161.82,55.99 162.02,55.99 162.41,55.59 162.82,55.59 163.17,55.93 163.17,56.34 162.77,56.74 162.77,56.93 162.96,57.12 163.15,57.12 163.55,56.72 163.95,56.72 164.3,57.06 164.3,57.47 163.9,57.87 163.9,58.06 164.09,58.25 164.28,58.25 164.68,57.85 165.09,57.85 165.43,58.2 165.43,58.6 165.03,59 165.03,59.19 165.22,59.38 165.41,59.38 165.81,58.98 166.22,58.98 166.56,59.33 166.56,59.74 166.16,60.14 166.16,60.33 166.35,60.52 166.54,60.52 166.94,60.12 167.35,60.12 167.7,60.46 167.7,60.87 167.3,61.27 167.3,61.46 167.49,61.65 167.68,61.65 168.08,61.25 168.48,61.25 169.15,61.92 169.15,62.33 168.99,62.49 168.99,62.74 169.13,62.88 169.37,62.88 169.54,62.71 169.94,62.71 171.81,64.58 180.29,64.58 180.3,64.57 180.89,64.57 180.9,64.58 184.7,64.58 184.94,64.34 190.93,64.34 191.09,64.5 193.29,64.5 194.15,63.64 195.76,63.64 195.9,63.5 v1(195.9,63.45)
  BOTTOM w0.157: v1(195.9,63.45) 195.9,63.26 196.07,63.08 196.85,63.08 196.92,63.15 P4.186
DDR3_CPU_CH1_DQS_DN8: length 69.8
  TOP w0.102: v1(144.27,22.35) 143.97,22.66 142.51,22.66 141.51,23.65 140.58,23.65 139.63,24.61 139.63,25.7 139.52,25.81 139.52,27.07 U14.D14
  BOTTOM w0.157: P4.75 188.75,29.85 188.6,30.01 184.8,30.01 183.69,28.91 174.74,28.91 174.42,29.23 174.42,29.85 174.26,30.01 173.95,30.01 173.79,29.85 173.79,29.34 173.46,29.02 172.91,29.02 172.59,29.34 172.59,29.85 172.43,30.01 172.12,30.01 171.96,29.85 171.96,29.1 171.64,28.78 171.09,28.78 170.76,29.1 170.76,29.85 170.6,30.01 170.29,30.01 170.13,29.85 170.13,29.1 169.81,28.78 169.26,28.78 168.93,29.1 168.93,29.85 168.78,30.01 168.46,30.01 168.3,29.85 168.3,29.1 167.98,28.78 167.43,28.78 167.1,29.1 167.1,29.85 166.95,30.01 166.63,30.01 166.47,29.85 166.47,29.1 166.15,28.78 165.6,28.78 165.28,29.1 165.28,29.85 165.12,30.01 164.61,30.01 164.45,29.85 164.45,28.92 164.12,28.6 163.57,28.6 163.25,28.92 163.25,29.85 163.09,30.01 162.49,30.01 160.32,27.83 154.63,27.83 150.77,23.97 146.35,23.97 144.83,22.45 144.37,22.45 v1(144.27,22.35)
DDR3_CPU_CH1_DQS_DP0: length 93.2
  TOP w0.157: U14.D37 128.16,27.15 v1(127.85,26.84)
  L10_SIG w0.135: v1(196.22,8.62) 195.98,8.38 194.73,8.38 193.56,7.21 186.64,7.21 185.72,8.13 v1(185.72,8.5)
  BOTTOM w0.102: v1(127.85,26.84) 127.85,26.7 128.39,26.16 128.39,23.89 128.02,23.52 128.02,17.01 129.21,15.82 129.27,15.82 129.29,15.8
  BOTTOM w0.157: 129.29,15.8 130.09,15 130.1,15 130.31,14.78 132.12,14.78 141.7,5.2 143.94,5.2 145.34,6.6 150.01,6.6 151.06,5.55 158.61,5.55 159.66,6.6 164.89,6.6 166.22,7.93 167.26,7.93 167.59,7.61 167.59,7.29 167.75,7.14 168.06,7.14 168.22,7.29 168.22,7.61 168.54,7.93 169.09,7.93 169.42,7.61 169.42,7.29 169.57,7.14 169.89,7.14 170.05,7.29 170.05,7.61 170.37,7.93 170.92,7.93 171.25,7.61 171.25,7.35 171.4,7.19 171.67,7.19 171.88,7.4 171.88,7.63 172.29,8.04 173.37,8.04 174.8,9.47 184.35,9.47 185.32,8.5 v1(185.72,8.5) ; P4.12 196.97,8.55 196.82,8.41 196.57,8.41 196.36,8.62 v1(196.22,8.62)
DDR3_CPU_CH1_DQS_DP1: length 86.8
  TOP w0.102: U14.D30 131.86,26.94 132.16,26.64 132.16,26.28 132,26.12 132,22.64 132.89,21.76 132.89,19.84 133.45,19.28 133.45,18.5 v1(133.7,18.25)
  L10_SIG w0.135: v1(133.7,18.25) 133.45,18.01 133.45,14.46 136.34,11.58 136.92,11.58 137.25,11.24 138.04,11.24 138.18,11.38 138.18,11.93 138.47,12.22 138.95,12.22 139.24,11.93 139.24,11.38 139.37,11.24 139.64,11.24 139.78,11.38 139.78,11.93 140.07,12.22 140.55,12.22 140.84,11.93 140.84,11.38 140.98,11.24 141.24,11.24 141.38,11.38 141.38,11.93 141.67,12.22 142.15,12.22 142.44,11.93 142.44,11.38 142.58,11.24 142.84,11.24 142.98,11.38 142.98,11.93 143.27,12.22 143.75,12.22 144.04,11.93 144.04,11.38 144.18,11.24 144.44,11.24 144.58,11.38 144.58,11.93 144.87,12.22 145.35,12.22 145.64,11.93 145.64,11.38 145.78,11.24 146.04,11.24 146.18,11.38 146.18,11.93 146.47,12.22 146.95,12.22 147.24,11.93 147.24,11.38 147.38,11.24 147.65,11.24 147.78,11.38 147.78,11.93 148.07,12.22 148.55,12.22 148.84,11.93 148.84,11.38 148.98,11.24 149.25,11.24 149.38,11.38 149.38,11.93 149.67,12.22 150.15,12.22 150.44,11.93 150.44,11.38 150.58,11.24 150.85,11.24 150.98,11.38 150.98,12.01 151.27,12.3 151.75,12.3 152.04,12.01 152.04,11.38 152.18,11.24 152.45,11.24 152.58,11.38 152.58,11.84 152.87,12.13 153.35,12.13 153.64,11.84 153.64,11.38 153.78,11.24 182.98,11.24 184.02,12.28 187.33,12.28 v1(187.6,12.55)
  BOTTOM w0.157: P4.27 188.11,13.05 v1(187.6,12.55)
DDR3_CPU_CH1_DQS_DP2: length 81.6
  TOP w0.102: v1(140.27,17.65) 139.94,17.97 139.94,18.41 139.17,19.19 139.17,21.03 138.97,21.23 138.97,21.38 138.86,21.48 138.72,21.48 138.55,21.65 138.55,21.9 138.44,22 138.2,22 137.98,22.22 137.98,22.45 137.88,22.55 137.65,22.55 137.5,22.7 137.5,22.95 137.42,23.03 137.17,23.03 137,23.2 137,23.39 136.88,23.52 136.68,23.52 136.46,23.74 136.46,23.89 136.51,23.95 136.59,23.95 136.65,24.01 136.65,24.08 136.56,24.17 136.34,24.17 136.25,24.09 136.11,24.09 135.93,24.26 135.93,24.51 136.08,24.66 136.08,24.72 135.93,24.86 135.93,25.04 136.08,25.18 136.08,25.29 135.93,25.43 135.93,25.73 U14.A21
  BOTTOM w0.157: v1(140.27,17.65) 139.98,17.36 139.98,16.86 143.2,13.64 161.35,13.64 162.17,14.47 162.17,16.16 162.5,16.48 163.22,16.48 163.38,16.64 163.38,16.95 163.22,17.11 162.5,17.11 162.17,17.44 162.17,19.02 162.9,19.74 163.72,19.74 164.04,19.42 164.04,18.09 164.2,17.94 164.51,17.94 164.67,18.09 164.67,19.42 165,19.74 166.1,19.74 166.26,19.9 166.26,20.2 166.58,20.52 167.13,20.52 167.46,20.2 167.46,19.9 167.61,19.74 167.93,19.74 168.09,19.9 168.09,20.2 168.41,20.52 168.96,20.52 169.28,20.2 169.28,19.9 169.44,19.74 169.76,19.74 169.91,19.9 169.91,20.2 170.24,20.52 170.79,20.52 171.11,20.2 171.11,19.9 171.27,19.74 171.59,19.74 171.74,19.9 171.74,20.17 172.07,20.49 172.59,20.49 172.94,20.15 172.94,19.9 173.1,19.74 173.41,19.74 173.57,19.9 173.57,20.15 173.9,20.47 174.45,20.47 174.77,20.15 174.77,19.9 174.93,19.74 175.24,19.74 175.4,19.9 175.4,20.15 175.72,20.47 176.27,20.47 176.6,20.15 176.6,19.9 176.76,19.74 178.14,19.74 178.47,19.42 178.47,19.09 178.62,18.94 178.94,18.94 179.1,19.09 179.1,19.42 179.42,19.74 180.81,19.74 182.81,17.74 187.41,17.74 187.96,18.29 188.59,18.29 188.75,18.45 P4.45
DDR3_CPU_CH1_DQS_DP3: length 78.2
  TOP w0.157: U14.M29 132.42,31.36 132.92,30.86 v1(132.94,30.86)
  L10_SIG w0.102: 134.88,25.59 134.86,25.61 134.82,25.61 134.37,26.06 134.37,27.64 133.81,28.19 133.81,29.97 132.94,30.83 v1(132.94,30.86)
  L10_SIG w0.135: 134.88,25.59 135.07,25.4 136.53,25.4 138.79,23.14 142.84,23.14 144.13,21.85 148.22,21.85 149.16,22.79 155.85,22.79 156.14,22.51 156.14,21.4 156.27,21.26 156.54,21.26 156.68,21.4 156.68,22.51 156.97,22.79 158.12,22.79 160.78,20.13 181.05,20.13 181.32,20.4 181.32,21.77 182.34,22.79 184.76,22.79 185.04,23.07 190.53,23.07 191.09,23.63 191.76,23.63 192.06,23.33 196.42,23.33 v1(196.66,23.57)
  BOTTOM w0.157: P4.62 196.68,23.55 v1(196.66,23.57)
DDR3_CPU_CH1_DQS_DP4: length 74.4
  TOP w0.157: v1(140.98,33.99) U14.U11
  L10_SIG w0.102: 147.47,31.04 147.44,31.01 147.18,31.01 146.91,30.74 144.63,30.74 143.86,31.51 142.07,31.51 141.36,32.22 141.36,32.97 141.42,33.04 141.42,33.54 v1(140.98,33.99)
  L10_SIG w0.135: v1(187.55,49.35) 187.28,49.08 186.46,49.08 185.6,48.22 185.41,48.22 185.25,48.37 184.84,48.37 184.5,48.03 184.5,47.62 184.66,47.46 184.66,47.27 184.46,47.07 184.27,47.07 184.01,47.33 183.61,47.33 183.26,46.98 183.26,46.58 183.51,46.32 183.51,46.13 183.32,45.94 183.13,45.94 182.91,46.16 182.51,46.16 182.16,45.82 182.16,45.41 182.38,45.19 182.38,45 182.19,44.81 182,44.81 181.78,45.03 181.37,45.03 181.03,44.68 181.03,44.28 181.25,44.06 181.25,43.87 181.06,43.68 180.87,43.68 180.65,43.9 180.24,43.9 179.9,43.55 179.9,43.14 180.12,42.93 180.12,42.74 179.93,42.54 179.74,42.54 179.52,42.76 179.11,42.76 178.77,42.42 178.77,42.01 178.98,41.79 178.98,41.6 178.79,41.41 178.6,41.41 178.38,41.63 177.98,41.63 177.63,41.29 177.63,40.88 177.85,40.66 177.85,40.47 177.66,40.28 177.47,40.28 177.25,40.5 176.85,40.5 176.5,40.15 176.5,39.75 176.72,39.53 176.72,39.34 176.53,39.15 176.34,39.15 176.12,39.37 175.71,39.37 175.37,39.02 175.37,38.62 175.59,38.4 175.59,38.21 175.4,38.02 175.21,38.02 174.99,38.23 174.58,38.23 174.24,37.89 174.24,37.48 174.46,37.26 174.46,37.07 174.26,36.88 174.07,36.88 173.86,37.1 173.45,37.1 173.1,36.76 173.1,36.35 173.32,36.13 173.32,35.94 173.13,35.75 172.94,35.75 172.72,35.97 172.32,35.97 171.97,35.63 171.97,35.22 172.19,35 172.19,34.81 172,34.62 171.81,34.62 171.59,34.84 171.18,34.84 170.84,34.49 170.84,34.09 171.06,33.87 171.06,33.68 170.87,33.49 170.68,33.49 170.46,33.7 170.05,33.7 169.71,33.36 169.71,32.95 169.93,32.74 169.93,32.55 169.73,32.35 169.54,32.35 169.33,32.57 168.92,32.57 168.58,32.23 168.58,31.82 168.79,31.6 168.79,31.41 168.06,30.68 149.45,30.68 149.39,30.63 148.64,30.63 148.22,31.04 147.47,31.04
  BOTTOM w0.157: P4.141 187.85,49.65 v1(187.55,49.35)
DDR3_CPU_CH1_DQS_DP5: length 70.9
  TOP w0.102: v1(152.72,35.42) 152.45,35.14 149.63,35.14 149.49,35.28 149.12,35.28 148.99,35.14 147.5,35.14 146.96,34.59 146.74,34.59 146.66,34.67 146.66,35 146.56,35.1 146.18,35.1 146.08,35 146.08,34.79 U14.W1
  L10_SIG w0.135: v1(187.39,54.15) 187.85,54.61 188.37,54.61 188.93,55.17 194.95,55.17 195.82,54.3 196.08,54.3 196.36,54.03 v1(196.67,54.03)
  BOTTOM w0.157: P4.156 196.8,54.15 v1(196.67,54.03) ; v1(187.39,54.15) 186.86,53.62 185.26,53.62 185.01,53.88 169.17,53.88 167.72,52.43 167.72,45.51 166.07,43.86 166.07,43.41 166.35,43.12 166.35,42.9 166.13,42.68 165.91,42.68 165.62,42.96 165.16,42.96 164.77,42.57 164.77,42.11 165.06,41.83 165.06,41.61 164.83,41.38 164.61,41.38 164.33,41.67 163.87,41.67 163.48,41.28 163.48,40.82 163.76,40.53 163.76,40.31 163.54,40.09 163.32,40.09 163.1,40.31 162.51,40.31 160.43,38.22 154.94,38.22 154.12,37.4 154.12,36.04 153.26,35.18 152.96,35.18 v1(152.72,35.42)
DDR3_CPU_CH1_DQS_DP6: length 71.5
  TOP w0.157: U14.Y7 143.3,35.55 142.95,35.91 v1(142.91,35.91)
  L10_SIG w0.102: v1(142.91,35.91) 143.13,35.69 149.4,35.69 150.52,36.81 150.52,37.37 151.26,38.11 152.54,38.11 152.92,37.73 152.96,37.73 152.98,37.71
  L10_SIG w0.135: v1(187.55,58.95) 187.53,58.95 187.32,58.75 186.11,58.75 186.1,58.75 182.18,58.75 179.2,55.77 179.01,55.77 178.55,56.22 178.14,56.22 177.8,55.88 177.8,55.47 178.26,55.01 178.26,54.82 178.07,54.63 177.88,54.63 177.47,55.04 177.06,55.04 176.71,54.7 176.71,54.29 177.13,53.88 177.13,53.69 176.93,53.5 176.74,53.5 176.33,53.91 175.93,53.91 175.58,53.57 175.58,53.16 175.99,52.75 175.99,52.56 175.8,52.37 175.61,52.37 175.2,52.78 174.79,52.78 174.45,52.44 174.45,52.03 174.86,51.62 174.86,51.43 174.67,51.24 174.48,51.24 174.07,51.65 173.66,51.65 173.32,51.3 173.32,50.9 173.73,50.49 173.73,50.3 173.54,50.1 173.35,50.1 172.94,50.51 172.53,50.51 172.19,50.17 172.19,49.76 172.6,49.35 172.6,49.16 172.4,48.97 172.21,48.97 171.8,49.38 171.4,49.38 171.05,49.04 171.05,48.63 171.46,48.22 171.46,48.03 171.27,47.84 171.08,47.84 170.67,48.25 170.26,48.25 169.92,47.91 169.92,47.5 170.33,47.09 170.33,46.9 170.14,46.71 169.95,46.71 169.74,46.92 169.33,46.92 168.99,46.57 168.99,46.17 169.2,45.96 169.2,45.77 160.91,37.48 153.21,37.48 152.98,37.71
  BOTTOM w0.157: P4.173 189.9,59.28 187.88,59.28 v1(187.55,58.95)
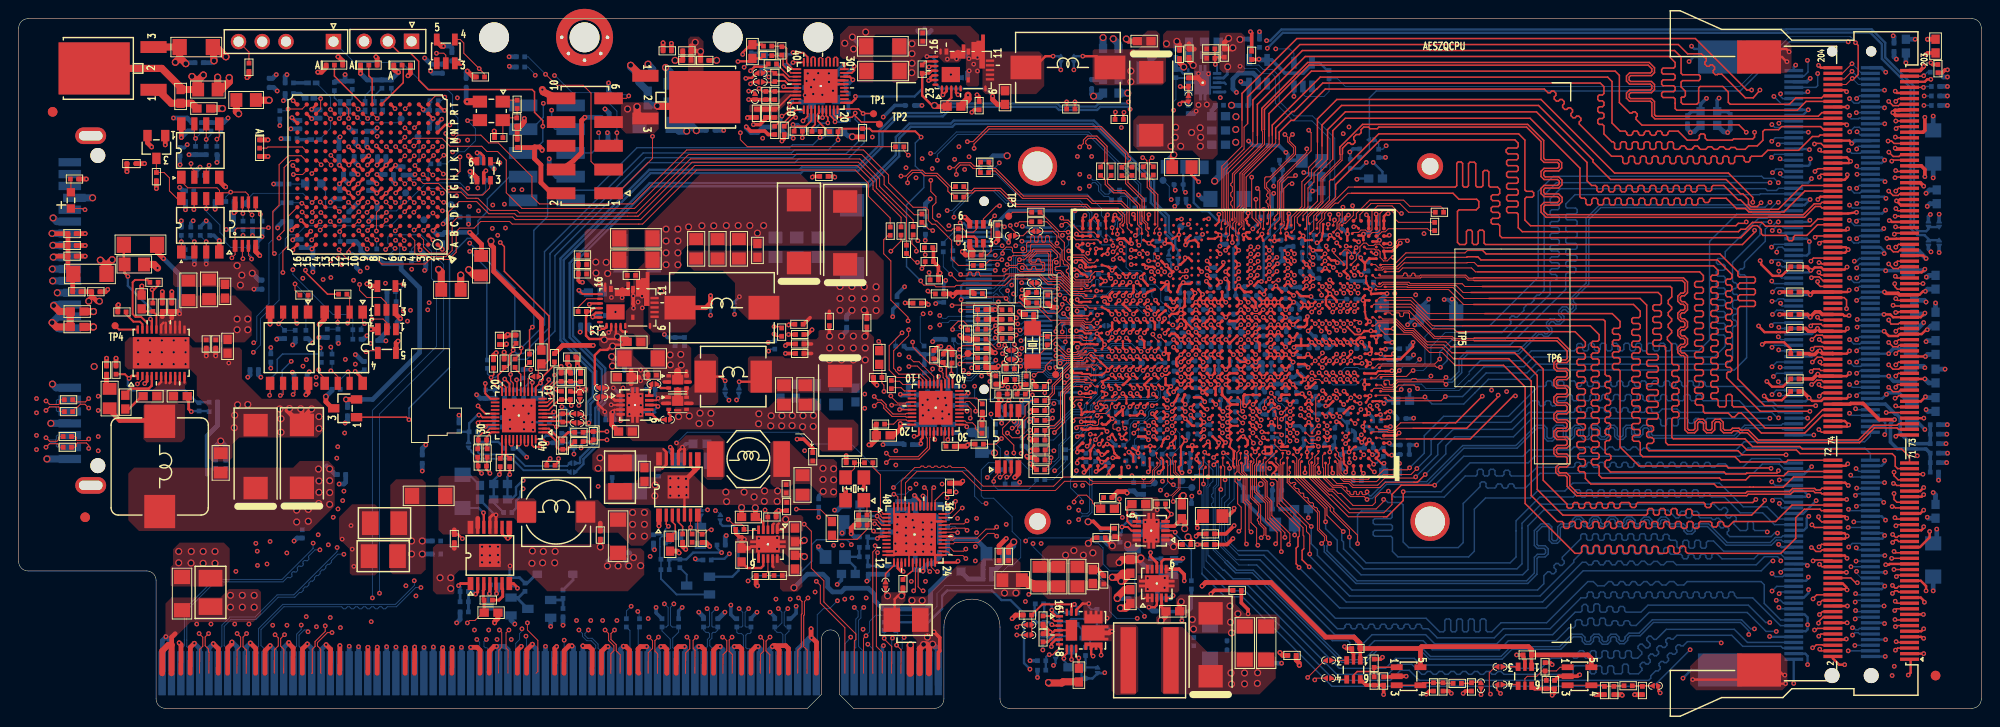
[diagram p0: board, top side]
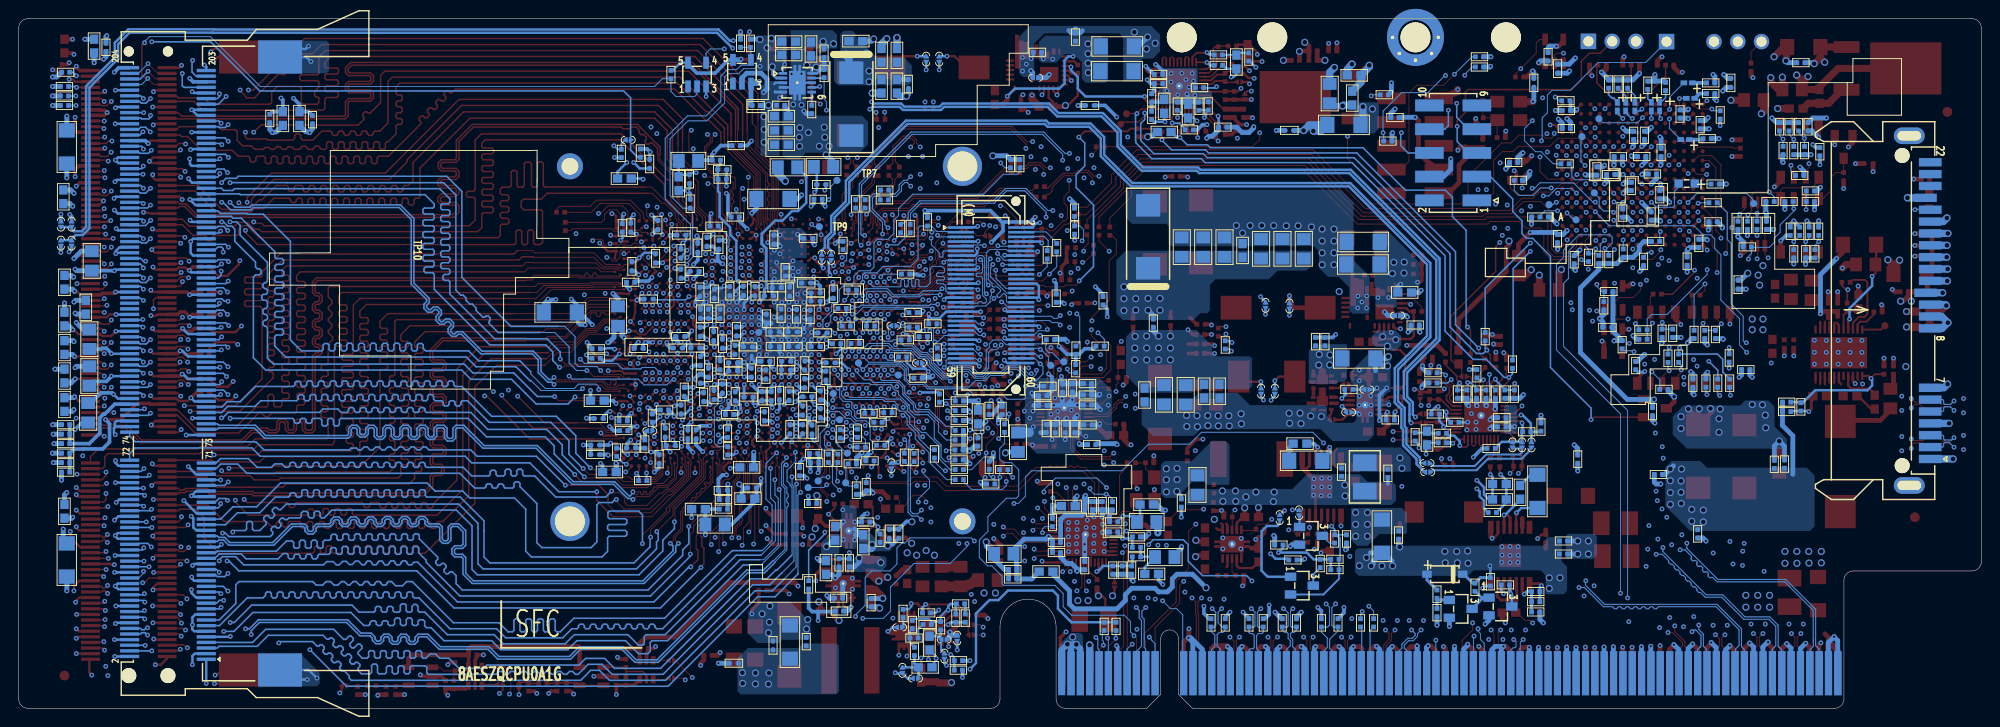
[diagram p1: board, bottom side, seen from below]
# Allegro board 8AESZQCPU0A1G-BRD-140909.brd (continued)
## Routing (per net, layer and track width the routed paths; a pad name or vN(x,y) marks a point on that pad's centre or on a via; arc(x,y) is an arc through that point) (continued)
DDR3_CPU_CH1_DQS_DP7: length 84.3
  TOP w0.157: U14.AD12 v1(141.02,37.91)
  L10_SIG w0.102: v1(141.02,37.91) 141.3,38.19 141.3,38.42 141.67,38.79 143.9,38.79 144.1,38.99 144.1,40.67 144.43,41 144.72,41 145.71,41.99 146.86,41.99 147.8,42.94 149.29,42.94 149.32,42.96 149.43,42.96
  L10_SIG w0.135: v1(196.63,63.74) 196.47,63.9 194.26,63.9 193.4,64.76 190.98,64.76 190.82,64.6 185.05,64.6 184.81,64.84 180.79,64.84 180.78,64.83 180.41,64.83 180.4,64.84 171.7,64.84 169.83,62.97 169.64,62.97 169.48,63.14 169.02,63.14 168.73,62.84 168.73,62.39 168.89,62.22 168.89,62.03 168.37,61.51 168.18,61.51 167.79,61.91 167.38,61.91 167.03,61.57 167.03,61.16 167.43,60.76 167.43,60.57 167.24,60.38 167.05,60.38 166.65,60.78 166.25,60.78 165.9,60.43 165.9,60.03 166.3,59.63 166.3,59.44 166.11,59.25 165.92,59.25 165.52,59.65 165.11,59.65 164.77,59.3 164.77,58.89 165.17,58.5 165.17,58.31 164.98,58.11 164.79,58.11 164.39,58.51 163.98,58.51 163.64,58.17 163.64,57.76 164.04,57.36 164.04,57.17 163.85,56.98 163.66,56.98 163.26,57.38 162.85,57.38 162.51,57.04 162.51,56.63 162.9,56.23 162.9,56.04 162.71,55.85 162.52,55.85 162.12,56.25 161.72,56.25 161.37,55.91 161.37,55.5 161.77,55.1 161.77,54.91 160.97,54.11 160.97,47.22 157.2,43.45 154.99,43.45 154.5,42.96 149.43,42.96
  BOTTOM w0.157: P4.188 196.64,63.75 v1(196.63,63.74)
DDR3_CPU_CH1_DQS_DP8: length 69.8
  TOP w0.102: v1(144.27,23.17) 144.27,22.99 144.15,22.86 143.84,22.86 143.74,22.96 143.74,23.11 143.66,23.19 143.54,23.19 143.45,23.11 143.45,22.96 143.35,22.86 143.21,22.86 143.13,22.94 143.13,23.16 143.08,23.22 142.93,23.22 142.86,23.15 142.86,22.95 142.77,22.86 142.59,22.86 142.44,23.01 142.44,23.14 142.35,23.23 142.23,23.23 142.11,23.34 142.11,23.57 142.01,23.67 141.78,23.67 141.6,23.86 140.67,23.86 139.83,24.7 139.83,26.24 U14.B14
  BOTTOM w0.157: v1(144.27,23.17) 144.27,23.04 144.57,22.74 144.71,22.74 146.23,24.26 150.65,24.26 154.51,28.12 160.2,28.12 162.37,30.29 163.21,30.29 163.53,29.97 163.53,29.04 163.69,28.88 164.01,28.88 164.16,29.04 164.16,29.97 164.49,30.29 165.24,30.29 165.56,29.97 165.56,29.22 165.72,29.06 166.03,29.06 166.19,29.22 166.19,29.97 166.51,30.29 167.06,30.29 167.39,29.97 167.39,29.22 167.55,29.06 167.86,29.06 168.02,29.22 168.02,29.97 168.34,30.29 168.89,30.29 169.22,29.97 169.22,29.22 169.37,29.06 169.69,29.06 169.85,29.22 169.85,29.97 170.17,30.29 170.72,30.29 171.05,29.97 171.05,29.22 171.2,29.06 171.52,29.06 171.68,29.22 171.68,29.97 172,30.29 172.55,30.29 172.87,29.97 172.87,29.46 173.03,29.3 173.35,29.3 173.5,29.46 173.5,29.97 173.83,30.29 174.38,30.29 174.7,29.97 174.7,29.35 174.86,29.19 183.57,29.19 184.68,30.29 188.6,30.29 188.75,30.45 P4.77
DDR3_CPU_CH1_ECC0: length 69.1
  TOP w0.102: U14.D15 139.07,27.32 138.69,26.93 138.69,26.17 138.51,25.99 138.51,24.87 140.13,23.25 140.55,23.25 142.46,21.34 145.24,21.34 146.05,22.14 v1(146.05,22.35)
  BOTTOM w0.157: v1(146.05,22.35) 146.18,22.35 146.51,22.02 147.88,22.02 148.13,21.77 148.13,17.81 148.75,17.2 154.03,17.2 154.56,17.73 154.56,21.92 156.37,23.73 156.37,24.07 156.53,24.23 156.84,24.23 157,24.07 157,23.73 157.16,23.57 157.95,23.57 158.11,23.73 158.11,23.85 158.27,24.01 158.58,24.01 158.74,23.85 158.74,23.73 158.9,23.57 159.21,23.57 159.37,23.73 159.37,23.86 159.53,24.02 159.84,24.02 160,23.86 160,23.73 160.16,23.57 161.21,23.57 162.79,25.15 185.57,25.15 186.56,26.14 188.39,26.14 188.88,25.65 P4.69
DDR3_CPU_CH1_ECC1: length 69.1
  TOP w0.102: v1(146.56,23.24) 146.41,23.09 145.69,23.09 145.16,22.56 145.16,22.02 144.86,21.72 142.77,21.72 141.49,23 141.17,23 140.72,23.45 140.23,23.45 138.71,24.98 138.71,25.89 139.02,26.2 U14.C15
  BOTTOM w0.157: v1(146.56,23.24) 147.19,22.61 152.53,22.61 154.79,24.87 155.92,24.87 156.07,25.02 156.07,25.42 156.23,25.58 156.55,25.58 156.7,25.42 156.7,25.02 156.86,24.87 157.18,24.87 157.33,25.02 157.33,25.42 157.49,25.58 157.81,25.58 157.96,25.42 157.96,25.02 158.12,24.87 158.77,24.87 158.92,25.02 158.92,25.32 159.08,25.47 159.4,25.47 159.55,25.32 159.55,25.02 159.71,24.87 161.52,24.87 162.43,25.78 162.54,25.78 162.55,25.79 166.36,25.79 166.51,25.94 166.51,26.16 166.67,26.31 166.99,26.31 167.14,26.16 167.14,25.94 167.3,25.79 167.62,25.79 167.77,25.94 167.77,26.16 167.93,26.31 168.25,26.31 168.4,26.16 168.4,25.94 168.56,25.79 168.88,25.79 169.03,25.94 169.03,26.16 169.19,26.31 169.51,26.31 169.66,26.16 169.66,25.94 169.82,25.79 170.14,25.79 170.29,25.94 170.29,26.16 170.45,26.31 170.77,26.31 170.92,26.16 170.92,25.94 171.08,25.79 171.4,25.79 171.55,25.94 171.55,26.16 171.71,26.31 172.03,26.31 172.18,26.16 172.18,25.94 172.34,25.79 172.65,25.79 172.81,25.94 172.81,26.16 172.97,26.31 173.28,26.31 173.44,26.16 173.44,25.94 173.6,25.79 173.91,25.79 174.07,25.94 174.07,26.16 174.23,26.31 174.54,26.31 174.7,26.16 174.7,25.94 174.86,25.79 175.17,25.79 175.33,25.94 175.33,26.16 175.49,26.31 175.8,26.31 175.96,26.16 175.96,25.94 176.12,25.79 176.43,25.79 176.59,25.94 176.59,26.16 176.75,26.31 177.06,26.31 177.22,26.16 177.22,25.94 177.38,25.79 177.69,25.79 177.85,25.94 177.85,26.16 178.01,26.31 178.32,26.31 178.48,26.16 178.48,25.94 178.64,25.79 178.95,25.79 179.11,25.94 179.11,26.16 179.27,26.31 179.58,26.31 179.74,26.16 179.74,25.94 179.9,25.79 180.21,25.79 180.37,25.94 180.37,26.16 180.53,26.31 180.84,26.31 181,26.16 181,25.94 181.16,25.79 181.47,25.79 181.85,26.16 182.6,26.16 182.98,25.79 184.49,25.79 185.42,26.72 188.42,26.72 188.89,26.25 P4.71
DDR3_CPU_CH1_ECC2: length 69.1
  TOP w0.102: U14.D12 140.87,26.91 141.28,26.5 141.28,25.08 141.89,24.47 142.54,24.47 142.75,24.26 145.29,24.26 146.05,25.02 148.97,25.02 v1(149.61,25.65)
  BOTTOM w0.157: v1(149.61,25.65) 151.13,27.18 151.13,28.67 153.06,30.61 159.66,30.61 161.97,32.92 162.53,32.92 162.69,32.76 162.69,32.52 162.84,32.36 163.16,32.36 163.32,32.52 163.32,32.76 163.47,32.92 163.79,32.92 163.95,32.76 163.95,32.52 164.1,32.36 164.42,32.36 164.58,32.52 164.58,32.76 164.73,32.92 165.45,32.92 165.61,33.08 165.61,33.42 165.77,33.58 166.08,33.58 166.24,33.42 166.24,33.08 166.4,32.92 166.71,32.92 166.87,33.08 166.87,33.42 167.03,33.58 167.34,33.58 167.5,33.42 167.5,33.08 167.66,32.92 167.97,32.92 168.13,33.08 168.13,33.42 168.29,33.58 168.6,33.58 168.76,33.42 168.76,33.08 168.92,32.92 169.23,32.92 169.39,33.08 169.39,33.42 169.55,33.58 169.86,33.58 170.02,33.42 170.02,33.08 170.18,32.92 170.49,32.92 170.65,33.08 170.65,33.42 170.81,33.58 171.12,33.58 171.28,33.42 171.28,33.08 171.44,32.92 171.75,32.92 171.91,33.08 171.91,33.42 172.07,33.58 172.38,33.58 172.54,33.42 172.54,33.08 172.7,32.92 173.01,32.92 173.17,33.08 173.17,33.42 173.33,33.58 173.64,33.58 173.8,33.42 173.8,33.08 173.96,32.92 174.27,32.92 174.43,33.08 174.43,33.42 174.59,33.58 174.9,33.58 175.06,33.42 175.06,33.08 175.22,32.92 175.53,32.92 175.69,33.08 175.69,33.42 175.85,33.58 176.16,33.58 176.32,33.42 176.32,33.08 176.48,32.92 176.79,32.92 176.95,33.08 176.95,33.42 177.11,33.58 177.42,33.58 177.58,33.42 177.58,33.08 177.74,32.92 178.05,32.92 178.21,33.08 178.21,33.42 178.37,33.58 178.68,33.58 178.84,33.42 178.84,33.08 179,32.92 179.31,32.92 179.47,33.08 179.47,33.4 179.63,33.55 179.94,33.55 180.1,33.4 180.1,33.08 180.26,32.92 184.1,32.92 184.71,32.3 187.63,32.3 188.29,31.65 P4.81
DDR3_CPU_CH1_ECC3: length 69
  TOP w0.102: U14.E12 140.97,27.6 141.23,27.34 141.23,27.01 141.48,26.75 141.48,25.18 141.99,24.67 142.72,24.67 142.88,24.51 144.4,24.51 144.64,24.75 145.28,24.75 146.05,25.53 148.62,25.53 v1(148.83,25.74)
  BOTTOM w0.157: P4.83 188.25,32.25 187.68,32.82 186.29,32.82 184.66,34.44 180.61,34.44 180.45,34.6 180.45,34.83 180.29,34.99 179.98,34.99 179.82,34.83 179.82,34.6 179.66,34.44 179.35,34.44 179.19,34.6 179.19,34.87 179.03,35.03 178.72,35.03 178.56,34.87 178.56,34.6 178.4,34.44 178.09,34.44 177.93,34.6 177.93,34.87 177.77,35.03 177.46,35.03 177.3,34.87 177.3,34.6 177.14,34.44 176.83,34.44 176.67,34.6 176.67,34.87 176.51,35.03 176.2,35.03 176.04,34.87 176.04,34.6 175.88,34.44 175.57,34.44 175.41,34.6 175.41,34.87 175.25,35.03 174.94,35.03 174.78,34.87 174.78,34.6 174.62,34.44 174.31,34.44 174.15,34.6 174.15,34.87 173.99,35.03 173.68,35.03 173.52,34.87 173.52,34.6 173.36,34.44 173.05,34.44 172.89,34.6 172.89,34.87 172.73,35.03 172.42,35.03 172.26,34.87 172.26,34.6 172.11,34.44 171.79,34.44 171.63,34.6 171.63,34.87 171.48,35.03 171.16,35.03 171,34.87 171,34.6 170.85,34.44 170.53,34.44 170.37,34.6 170.37,34.87 170.22,35.03 169.9,35.03 169.74,34.87 169.74,34.6 169.59,34.44 169.27,34.44 169.11,34.6 169.11,34.87 168.96,35.03 168.64,35.03 168.48,34.87 168.48,34.6 168.33,34.44 168.01,34.44 167.85,34.6 167.85,34.87 167.7,35.03 167.38,35.03 167.22,34.87 167.22,34.6 167.07,34.44 166.75,34.44 166.59,34.6 166.59,34.87 166.44,35.03 166.12,35.03 165.96,34.87 165.96,34.6 165.81,34.44 165.49,34.44 165.33,34.6 165.33,34.87 165.18,35.03 164.86,35.03 164.7,34.87 164.7,34.6 164.55,34.44 164.23,34.44 164.07,34.6 164.07,34.87 163.92,35.03 163.6,35.03 163.44,34.87 163.44,34.6 163.29,34.44 162.59,34.44 159.39,31.25 152.46,31.25 150.39,29.18 150.39,27.3 v1(148.83,25.74)
DDR3_CPU_CH1_ECC4: length 69.1
  TOP w0.102: 146.02,20.5 142.27,20.5 138.1,24.67 138.1,26.09 138.02,26.17 138.02,26.44 138.41,26.82 U14.D17
  TOP w0.157: 146.02,20.5 146.41,20.5 148.15,22.24 v1(148.15,23.18)
  BOTTOM w0.157: P4.72 198.13,27.27 197.54,27.86 185.04,27.86 184.15,26.97 162.23,26.97 161.52,26.26 155.3,26.26 152.21,23.18 v1(148.15,23.18)
DDR3_CPU_CH1_ECC5: length 69.1
  TOP w0.102: U14.B17 138.3,26.25 138.3,24.77 140.24,22.83 140.46,22.83 142.36,20.93 146.08,20.93 146.94,21.79 146.94,22.35
  TOP w0.157: 146.94,22.35 146.94,22.89 147.93,23.88 v1(151.51,23.88)
  BOTTOM w0.157: v1(151.51,23.88) 154.61,26.97 160.96,26.97 161.65,27.66 166.11,27.66 166.41,27.97 166.74,27.97 167.04,27.66 167.37,27.66 167.67,27.97 168,27.97 168.3,27.66 168.63,27.66 168.93,27.97 169.26,27.97 169.56,27.66 169.89,27.66 170.19,27.97 170.52,27.97 170.82,27.66 171.15,27.66 171.45,27.97 171.78,27.97 172.08,27.66 172.41,27.66 172.71,27.97 173.04,27.97 173.34,27.66 173.67,27.66 173.86,27.85 174.42,27.85 174.6,27.66 183.77,27.66 184.63,28.52 197.51,28.52 198.13,29.14 P4.74
DDR3_CPU_CH1_ECC6: length 69
  TOP w0.102: 149.28,24.19 146.24,24.19 145.67,23.62 142.75,23.62 142.31,24.06 141.05,24.06 140.11,25 140.11,26.07 140.26,26.22 U14.C13
  TOP w0.157: 149.28,24.19 149.67,24.19 v1(150.5,25.02)
  L10_SIG w0.135: v1(195.9,31.58) 195.77,31.71 193.45,31.71 191.93,30.2 188.12,30.2 187.38,30.94 v1(187.38,31.04)
  BOTTOM w0.157: v1(195.9,31.58) 196.13,31.35 P4.80 ; v1(150.5,25.02) 152.7,27.23 152.7,28.09 153.67,29.06 159.94,29.06 161.91,31.02 175.53,31.02 175.69,30.87 175.69,30.38 175.85,30.23 176.16,30.23 176.32,30.38 176.32,30.87 176.48,31.02 176.79,31.02 176.95,30.87 176.95,30.38 177.11,30.23 177.42,30.23 177.58,30.38 177.58,30.87 177.74,31.02 178.48,31.02 178.63,30.87 178.63,30.66 178.79,30.5 179.11,30.5 179.26,30.66 179.26,30.87 179.42,31.02 179.74,31.02 179.89,30.87 179.89,30.66 180.05,30.5 180.37,30.5 180.52,30.66 180.52,30.87 180.68,31.02 187.36,31.02 v1(187.38,31.04)
DDR3_CPU_CH1_ECC7: length 69
  TOP w0.102: U14.B12 141.07,26.2 141.07,24.98 141.78,24.26 142.41,24.26 142.8,23.88 145.41,23.88 146.18,24.64 149.35,24.64 v1(149.48,24.77)
  L10_SIG w0.135: v1(196.55,32.05) 196.44,32.16 193.33,32.16 191.76,30.59 188.93,30.59 188.43,31.08 v1(188.3,31.08)
  BOTTOM w0.157: v1(149.48,24.77) 151.84,27.13 151.84,28.19 153.49,29.84 159.8,29.84 161.62,31.66 166.37,31.66 166.53,31.82 166.53,32.02 166.68,32.18 167,32.18 167.16,32.02 167.16,31.82 167.31,31.66 167.63,31.66 167.79,31.82 167.79,32.02 167.94,32.18 168.26,32.18 168.42,32.02 168.42,31.82 168.57,31.66 168.89,31.66 169.05,31.82 169.05,32.02 169.2,32.18 169.52,32.18 169.68,32.02 169.68,31.82 169.83,31.66 170.15,31.66 170.3,31.82 170.3,32.02 170.46,32.18 170.78,32.18 170.93,32.02 170.93,31.82 171.09,31.66 171.41,31.66 171.56,31.82 171.56,32.02 171.72,32.18 172.04,32.18 172.19,32.02 172.19,31.82 172.35,31.66 172.67,31.66 172.82,31.82 172.82,32.02 172.98,32.18 173.3,32.18 173.45,32.02 173.45,31.82 173.61,31.66 173.93,31.66 174.08,31.82 174.08,32.02 174.24,32.18 174.56,32.18 174.71,32.02 174.71,31.82 174.87,31.66 175.49,31.66 175.86,32.03 177.45,32.03 177.82,31.66 187.59,31.66 188.17,31.08 v1(188.3,31.08) ; v1(196.55,32.05) 196.65,31.95 P4.82
DDR3_CPU_CH1_MA0: length 95.6
  TOP w0.102: v1(139.11,30.23) 138.97,30.23 138.38,29.64 U14.H17
  L8_SIG w0.102: 145.64,25.78 145.6,25.74 145.14,25.74 145.14,25.74 144.82,25.74 144.78,25.78 142.54,25.78 142.45,25.87 142,25.87 141.54,26.32 141.54,28.96 140.93,29.57 140.93,29.94 140.18,30.7 139.51,30.7 139.11,30.29 v1(139.11,30.23)
  L8_SIG w0.191: v1(188.28,39.75) 188.22,39.81 185.42,39.81 184.88,39.28 182.37,39.28 179.35,42.29 177.53,42.29 177.34,42.48 177.34,43.57 177.15,43.76 176.77,43.76 176.58,43.57 176.58,42.48 176.39,42.29 175.84,42.29 175.65,42.48 175.65,44.18 175.46,44.37 175.07,44.37 174.88,44.18 174.88,42.48 174.69,42.29 174.31,42.29 174.12,42.48 174.12,44.18 173.93,44.37 173.55,44.37 173.36,44.18 173.36,42.48 173.17,42.29 172.79,42.29 172.6,42.48 172.6,44.18 172.41,44.37 172.03,44.37 171.84,44.18 171.84,42.48 171.65,42.29 171.26,42.29 171.07,42.48 171.07,44.18 170.88,44.37 170.5,44.37 170.31,44.18 170.31,42.48 170.12,42.29 169.74,42.29 169.55,42.48 169.55,44.18 169.36,44.37 168.98,44.37 168.79,44.18 168.79,42.48 168.6,42.29 168.22,42.29 168.03,42.48 168.03,44.01 167.84,44.2 167.45,44.2 167.26,44.01 167.26,42.48 166.08,41.3 166.08,30.78 160.73,25.43 150.95,25.43 150.9,25.48 150.18,25.48 149.91,25.21 148.54,25.21 147.97,25.78 145.64,25.78
  BOTTOM w0.157: P4.107 188.58,39.45 v1(188.28,39.75)
DDR3_CPU_CH1_MA1: length 95.5
  TOP w0.102: U14.G17 138.95,28.71 v1(139.08,28.84)
  L8_SIG w0.102: v1(139.08,28.84) 139.23,28.84 139.74,28.33 140.94,28.33 141.14,28.13 141.14,26.08 141.42,25.8 141.42,25.76 141.42,25.76 141.42,25.26 142.01,24.68 142.44,24.68 142.47,24.71 142.68,24.71 142.71,24.68 146.79,24.68 146.87,24.75
  L8_SIG w0.191: v1(187.6,38.63) 187.4,38.43 185.06,38.43 184.77,38.13 179.95,38.13 179.76,38.32 179.76,39.41 179.57,39.6 179.19,39.6 179,39.41 179,38.32 178.81,38.13 178.43,38.13 178.24,38.32 178.24,39.51 178.05,39.7 177.67,39.7 177.48,39.51 177.48,38.32 177.29,38.13 176.91,38.13 176.72,38.32 176.72,39.51 176.52,39.7 176.14,39.7 175.95,39.51 175.95,38.32 175.76,38.13 175.38,38.13 175.19,38.32 175.19,39.51 175,39.7 174.62,39.7 174.43,39.51 174.43,38.32 174.24,38.13 173.86,38.13 173.67,38.32 173.67,39.51 173.48,39.7 173.1,39.7 172.91,39.51 172.91,38.32 172.71,38.13 172.33,38.13 172.14,38.32 172.14,39.51 171.95,39.7 171.57,39.7 171.38,39.51 171.38,38.32 171.19,38.13 170.81,38.13 170.62,38.32 170.62,39.51 170.43,39.7 170.05,39.7 169.86,39.51 169.86,38.32 169.67,38.13 169.29,38.13 169.1,38.32 169.1,39.51 168.9,39.7 168.52,39.7 168.33,39.51 168.33,38.32 168.14,38.13 167.57,38.13 167.26,37.82 167.26,30.34 163.17,26.25 163.17,25.98 163.88,25.27 163.88,25 163.61,24.73 163.34,24.73 162.63,25.44 162.36,25.44 162.09,25.17 162.09,24.9 162.79,24.2 162.79,23.93 162.52,23.66 162.25,23.66 161.55,24.36 161.28,24.36 161.05,24.13 160.35,24.13 160.16,23.94 160.16,23.76 159.96,23.57 159.58,23.57 159.39,23.76 159.39,23.94 159.2,24.13 158.82,24.13 158.63,23.94 158.63,23.76 158.44,23.57 158.06,23.57 157.87,23.76 157.87,23.94 157.68,24.13 157.3,24.13 157.11,23.94 157.11,23.76 156.92,23.57 156.54,23.57 156.35,23.76 156.35,23.94 156.15,24.13 155.77,24.13 155.58,23.94 155.58,23.76 155.39,23.57 155.01,23.57 154.82,23.76 154.82,23.94 154.63,24.13 154.25,24.13 154.06,23.94 154.06,23.76 153.87,23.57 153.49,23.57 153.3,23.76 153.3,23.94 153.11,24.13 152.59,24.13 151.87,23.41 148.68,23.41 147.34,24.75 146.87,24.75
  BOTTOM w0.157: v1(187.6,38.63) 187.62,38.63 187.83,38.85 P4.105
DDR3_CPU_CH1_MA2: length 94.3
  TOP w0.102: v1(139.07,28.03) 138.76,28.33 138.08,28.33 137.7,28.71 U14.G18
  L8_SIG w0.102: 144.71,24.02 141.93,24.02 141.01,24.94 141.01,25.55 140.73,25.82 140.73,27.78 140.62,27.9 139.25,27.9 139.12,28.03 v1(139.07,28.03)
  L8_SIG w0.191: 144.71,24.02 145.09,24.02 148.46,20.65 148.46,17.81 149.02,17.25 153.27,17.25 153.91,17.89 153.91,20.37 154.11,20.57 154.96,20.57 155.15,20.76 155.15,21.15 155.34,21.34 155.72,21.34 155.91,21.15 155.91,20.76 156.1,20.57 156.48,20.57 156.67,20.76 156.67,21.15 156.86,21.34 157.25,21.34 157.44,21.15 157.44,20.76 157.63,20.57 158.01,20.57 158.2,20.76 158.2,21.15 158.39,21.34 158.77,21.34 158.96,21.15 158.96,20.76 159.15,20.57 159.53,20.57 159.72,20.76 159.72,21.15 159.91,21.34 160.29,21.34 160.48,21.15 160.48,20.76 160.67,20.57 161.06,20.57 161.25,20.76 161.25,21.15 161.44,21.34 161.82,21.34 162.01,21.15 162.01,20.76 162.2,20.57 162.58,20.57 162.77,20.76 162.77,21.15 162.96,21.34 163.34,21.34 163.53,21.15 163.53,20.76 163.72,20.57 164.1,20.57 164.29,20.76 164.29,21.07 164.48,21.26 164.87,21.26 165.06,21.07 165.06,20.76 165.25,20.57 168.02,20.57 168.53,21.08 168.53,34.16 171.36,36.99 184.77,36.99 185.1,37.32 185.1,37.34 185.52,37.76 187.89,37.76 188,37.87 189.94,37.87 191.05,38.98 193.28,38.98 193.76,39.45 v1(195.9,39.45)
  BOTTOM w0.157: v1(195.9,39.45) 196.36,38.99 197.01,38.99 197.17,39.15 P4.106
DDR3_CPU_CH1_MA3: length 96.5
  TOP w0.102: U14.P21 136.36,32.14 136.04,31.82 v1(136.04,31.77)
  L8_SIG w0.102: v1(136.04,31.77) 136.94,30.88 137.53,30.88 137.64,30.99 137.88,30.99 137.89,30.99 138.2,30.99 138.31,30.99 138.67,30.63 138.67,28.67 138.91,28.43 139.34,28.43 139.66,28.12 140.79,28.12 140.93,27.98 140.93,25.96 141.22,25.67 141.22,25.13 141.89,24.46
  L8_SIG w0.191: v1(188.32,38.35) 188.04,38.35 187.76,38.08 185.32,38.08 184.85,37.61 184.82,37.61 184.77,37.56 171.11,37.56 167.89,34.34 167.89,29.06 167.7,28.86 166.97,28.86 166.78,28.67 166.78,28.29 166.97,28.1 167.7,28.1 167.89,27.91 167.89,27.15 167.7,26.96 165.11,26.96 164.92,26.76 164.92,26.38 165.11,26.19 167.7,26.19 167.89,26 167.89,25.62 167.7,25.43 165.09,25.43 164.9,25.24 164.9,24.86 165.09,24.67 165.98,24.67 166.21,24.43 166.74,24.43 166.98,24.67 167.7,24.67 167.89,24.48 167.89,22.48 167.32,21.91 166.53,21.91 166.34,22.1 166.34,22.44 166.15,22.63 165.77,22.63 165.58,22.44 165.58,22.1 165.39,21.91 164.5,21.91 164.31,22.1 164.31,22.54 164.12,22.73 163.74,22.73 163.55,22.54 163.55,22.1 163.36,21.91 162.98,21.91 162.79,22.1 162.79,22.54 162.6,22.73 162.22,22.73 162.03,22.54 162.03,22.1 161.84,21.91 161.45,21.91 161.26,22.1 161.26,22.54 161.07,22.73 160.69,22.73 160.5,22.54 160.5,22.1 160.31,21.91 159.93,21.91 159.74,22.1 159.74,22.54 159.55,22.73 159.17,22.73 158.98,22.54 158.98,22.1 158.79,21.91 158.41,21.91 158.22,22.1 158.22,22.54 158.03,22.73 157.64,22.73 157.45,22.54 157.45,22.1 157.26,21.91 156.88,21.91 156.69,22.1 156.69,22.54 156.5,22.73 156.12,22.73 155.93,22.54 155.93,22.1 155.74,21.91 155.36,21.91 155.17,22.1 155.17,22.47 154.98,22.66 147.96,22.66 146.24,24.37 141.97,24.37 141.89,24.46
  BOTTOM w0.157: v1(188.32,38.35) 188.42,38.25 P4.103
DDR3_CPU_CH1_MA4: length 93.3
  TOP w0.102: U14.M21 136.38,31.37 136.04,31.03 v1(136.04,31)
  L8_SIG w0.102: v1(136.04,31) 137.31,29.72 137.31,29.35 138.66,27.99 138.66,27.32 140.14,25.84 140.14,24.99 141.41,23.72 143.16,23.72
  L8_SIG w0.191: v1(196.66,38.25) 196.66,38.29 196.22,38.73 194.18,38.73 193.1,37.66 191.05,37.66 190.93,37.54 188.12,37.54 188.02,37.44 185.93,37.44 185.1,36.61 185.1,36.59 184.9,36.39 171.56,36.39 169.1,33.93 169.1,19.98 168.48,19.35 163.25,19.35 162.89,19.71 161.55,19.71 161.19,19.35 160.81,19.35 160.62,19.55 160.62,19.75 160.43,19.94 160.05,19.94 159.86,19.75 159.86,19.55 159.67,19.35 159.29,19.35 159.09,19.55 159.09,19.75 158.9,19.94 158.52,19.94 158.33,19.75 158.33,19.55 158.14,19.35 157.76,19.35 157.57,19.55 157.57,19.75 157.38,19.94 157,19.94 156.81,19.75 156.81,19.55 156.62,19.35 156.24,19.35 156.05,19.55 156.05,19.75 155.86,19.94 155.48,19.94 155.28,19.75 155.28,19.55 155.09,19.35 154.67,19.35 154.48,19.16 154.48,17.17 153.99,16.68 148.78,16.68 147.89,17.57 147.89,19.78 145.21,22.46 145.21,23.03 144.64,23.6 143.28,23.6 143.16,23.72
  BOTTOM w0.157: v1(196.66,38.25) 196.96,38.55 P4.104
DDR3_CPU_CH1_MA5: length 96
  TOP w0.102: U14.H22 136.02,28.76 v1(136.02,28.6)
  L8_SIG w0.102: 143.51,22.13 142.39,23.25 141.12,23.25 139.66,24.71 139.66,25.59 138.24,27.01 138.24,27.75 136.94,29.04 136.49,29.04 136.05,28.6 v1(136.02,28.6)
  L8_SIG w0.191: v1(187.6,36.55) 186.38,36.55 184.94,35.12 176.9,35.12 176.35,34.57 175.9,34.57 175.36,35.12 174.94,35.12 174.06,34.23 173.79,34.23 173.21,34.81 172.94,34.81 172.67,34.54 172.67,34.28 173.25,33.69 173.25,33.42 172.98,33.15 172.71,33.15 172.13,33.74 171.86,33.74 171.59,33.47 171.59,33.2 172.17,32.62 172.17,32.35 171.9,32.08 171.63,32.08 171.05,32.66 170.78,32.66 170.51,32.39 170.51,32.12 171.1,31.54 171.1,31.27 170.24,30.42 170.24,18.27 167.51,15.54 166.44,15.54 166.25,15.73 166.25,16.34 166.05,16.54 165.67,16.54 165.48,16.34 165.48,15.73 165.29,15.54 164.91,15.54 164.72,15.73 164.72,16.34 164.53,16.54 164.15,16.54 163.96,16.34 163.96,15.73 163.77,15.54 163.39,15.54 163.2,15.73 163.2,16.34 163.01,16.54 162.63,16.54 162.44,16.34 162.44,15.73 162.24,15.54 161.86,15.54 161.67,15.73 161.67,16.34 161.48,16.54 161.1,16.54 160.91,16.34 160.91,15.73 160.72,15.54 160.34,15.54 160.15,15.73 160.15,16.34 159.96,16.54 159.58,16.54 159.39,16.34 159.39,15.73 159.2,15.54 158.82,15.54 158.63,15.73 158.63,16.32 158.43,16.51 158.05,16.51 157.86,16.32 157.86,15.73 157.67,15.54 157.33,15.54 157.14,15.73 157.14,16.56 156.98,16.72 156.59,16.72 156.38,16.51 156.38,15.73 156.19,15.54 148.31,15.54 146.75,17.1 146.75,19.15 144.37,21.53 144.11,21.53 143.51,22.13
  BOTTOM w0.157: P4.99 188.1,37.05 v1(187.6,36.55)
DDR3_CPU_CH1_MA6: length 95.8
  TOP w0.102: U14.J21 v1(136.79,29.45)
  L8_SIG w0.102: v1(136.79,29.45) 136.92,29.45 138.45,27.92 138.45,27.18 139.88,25.74 139.88,24.86 141.28,23.46 142.6,23.46 144.14,21.92 144.59,21.92
  L8_SIG w0.191: v1(196.66,37.05) 196.66,37.32 196.35,37.64 194.14,37.64 193.07,36.58 189.71,36.58 189.07,37.22 188.25,37.22 188.15,37.12 186.2,37.12 184.77,35.69 171.67,35.69 169.67,33.69 169.67,19.48 168.15,17.96 167.26,17.96 167.07,18.15 167.07,18.32 166.88,18.51 166.5,18.51 166.3,18.32 166.3,18.15 166.11,17.96 165.63,17.96 165.44,18.15 165.44,18.45 165.25,18.64 164.68,18.64 164.49,18.45 164.49,17.97 164.3,17.78 163.92,17.78 163.73,17.97 163.73,18.45 163.54,18.64 163.16,18.64 162.97,18.45 162.97,17.97 162.78,17.78 162.4,17.78 162.21,17.97 162.21,18.45 162.02,18.64 161.64,18.64 161.45,18.45 161.45,17.97 161.26,17.78 160.87,17.78 160.68,17.97 160.68,18.45 160.49,18.64 160.11,18.64 159.92,18.45 159.92,17.92 159.73,17.72 159.35,17.72 159.16,17.92 159.16,18.45 158.97,18.64 155.28,18.64 155.09,18.45 155.09,16.41 154.79,16.11 148.54,16.11 147.32,17.33 147.32,19.56 144.95,21.92 144.59,21.92
  BOTTOM w0.157: v1(196.66,37.05) 196.96,37.35 P4.100
DDR3_CPU_CH1_MA7: length 95.4
  TOP w0.102: U14.J22 135.69,29.82 136.02,29.49 136.02,29.49 136.05,29.47 v1(136.05,29.47)
  L8_SIG w0.102: 140.46,22.16 139.81,22.16 136.84,25.14 136.84,26.13 136.27,26.7 135.65,26.7 134.61,27.74 134.61,28.34 134.58,28.37 134.58,29.44 134.8,29.66 135.87,29.66 v1(136.05,29.47)
  L8_SIG w0.191: v1(195.9,37.05) 194.63,37.05 192.76,35.18 189.61,35.18 188.91,34.48 188.48,34.48 188.48,34.48 188.01,34.48 187.65,34.12 186.39,34.12 186.08,33.81 186.08,32.54 185.39,31.85 183.63,31.85 182.8,31.03 182.8,30.55 182.39,30.15 182.12,30.15 181.96,30.31 181.69,30.31 181.42,30.04 181.42,29.77 181.59,29.61 181.59,29.34 181.32,29.07 181.05,29.07 180.88,29.23 180.62,29.23 180.35,28.96 180.35,28.69 180.51,28.53 180.51,28.26 180.24,27.99 179.97,27.99 179.81,28.15 179.54,28.15 179.27,27.88 179.27,27.61 179.43,27.45 179.43,27.18 179.16,26.91 178.89,26.91 178.73,27.08 178.46,27.08 178.19,26.81 178.19,26.54 178.35,26.37 178.35,26.1 178.08,25.83 177.81,25.83 177.65,26 177.38,26 177.11,25.73 177.11,25.46 177.27,25.3 177.27,25.03 177,24.76 176.73,24.76 176.57,24.92 176.3,24.92 176.03,24.65 176.03,24.38 176.2,24.22 176.2,23.95 175.93,23.68 175.66,23.68 175.49,23.84 175.23,23.84 174.96,23.57 174.96,23.3 175.12,23.14 175.12,22.87 174.85,22.6 174.58,22.6 174.42,22.76 174.15,22.76 173.88,22.49 173.88,22.22 174.04,22.06 174.04,21.79 173.77,21.52 173.5,21.52 173.34,21.69 173.07,21.69 172.8,21.42 172.8,21.15 172.96,20.98 172.96,20.71 172.53,20.28 172.53,17.23 168.44,13.14 147.47,13.14 144.46,16.15 144.46,16.62 144.46,18.5 140.79,22.16 140.46,22.16
  BOTTOM w0.157: P4.98 197.25,36.75 197.1,36.59 196.36,36.59 v1(195.9,37.05)
DDR3_CPU_CH1_MA8: length 95.7
  TOP w0.102: v1(136.76,28.63) 136.76,28.72 U14.H21
  L8_SIG w0.102: v1(136.76,28.63) 136.97,28.63 137.32,28.29 137.32,26.59 138.47,25.44 138.47,25.21 140.63,23.05 140.99,23.05 140.99,23.05 142.14,23.05 143.88,21.31
  L8_SIG w0.191: v1(188.47,36.5) 188.04,36.07 186.51,36.07 184.98,34.54 180.82,34.54 180.56,34.29 179.93,34.29 179.67,34.54 179.22,34.54 178.52,33.84 178.25,33.84 177.95,34.15 177.68,34.15 177.41,33.88 177.41,33.61 177.71,33.3 177.71,33.03 177.44,32.76 177.17,32.76 176.8,33.14 176.53,33.14 176.26,32.87 176.26,32.6 176.64,32.23 176.64,31.96 176.14,31.46 175.87,31.46 174.22,33.11 173.95,33.11 173.68,32.84 173.68,32.57 175.33,30.92 175.33,30.65 175.06,30.38 174.79,30.38 173.14,32.03 172.87,32.03 172.6,31.76 172.6,31.49 174.25,29.84 174.25,29.57 173.98,29.3 173.71,29.3 172.06,30.95 171.79,30.95 171.52,30.68 171.52,30.41 173.17,28.76 173.17,28.49 172.67,27.99 172.4,27.99 171.62,28.76 171.35,28.76 171.09,28.49 171.09,28.22 171.86,27.45 171.86,27.18 170.81,26.14 170.81,18.03 170.48,17.7 167.75,14.97 148.07,14.97 146.18,16.86 146.18,19.01 143.88,21.31
  BOTTOM w0.157: v1(188.47,36.5) 188.65,36.5 188.7,36.45 P4.97
DDR3_CPU_CH1_MA9: length 95.6
  TOP w0.152: U14.M22 135.56,31.37 v1(135.13,30.94)
  L8_SIG w0.102: v1(135.13,30.94) 135.05,30.94 134.94,31.05 133.96,31.05 133.68,30.77 133.68,30.17 133.97,29.87 133.97,28.11 134,28.09 134,27.36 135.74,25.62 135.74,23.92 136.52,23.14 137.28,23.14 137.42,23
  L8_SIG w0.191: 137.42,23 141.04,19.38 141.04,18.81 141.32,18.53 141.32,16.87 146.76,11.43 148.18,11.43 169.32,11.43 188.32,30.43 188.82,30.43 190.78,32.39 190.78,33.46 191.5,34.18 193.05,34.18 195.33,36.45 198.34,36.45 198.58,36.21 198.58,34.79 198.34,34.54 196.96,34.54 v1(196.66,34.85)
  BOTTOM w0.157: v1(196.66,34.85) 196.77,34.95 P4.92
DDR3_CPU_CH1_MA10: length 96.1
  TOP w0.102: v1(137.15,31.36) 137.52,30.99 U14.L18
  L8_SIG w0.102: v1(137.15,31.36) 137.34,31.36 137.74,31.76 138.19,31.76 138.29,31.66 141.53,31.66 142.13,31.06 142.13,30.3 142.73,29.7 145.3,29.7 145.8,29.21 146.69,29.21
  L8_SIG w0.191: v1(187.66,42.15) 185.03,42.15 184.67,42.51 183.44,42.51 179.35,46.6 179.35,47.24 177.88,48.72 177.88,51.9 177.69,52.1 177.31,52.1 177.11,51.9 177.11,51.24 176.92,51.05 176.54,51.05 176.35,51.24 176.35,52.01 176.16,52.2 175.78,52.2 175.59,52.01 175.59,51.24 175.4,51.05 175.02,51.05 174.83,51.24 174.83,52.01 174.64,52.2 174.26,52.2 174.07,52.01 174.07,51.24 173.88,51.05 173.5,51.05 173.3,51.24 173.3,52.01 173.11,52.2 172.73,52.2 172.54,52.01 172.54,51.24 172.35,51.05 171.97,51.05 171.78,51.24 171.78,52.01 171.59,52.2 171.21,52.2 171.02,52.01 171.02,51.24 170.83,51.05 170.45,51.05 170.26,51.24 170.26,52.01 170.07,52.2 169.69,52.2 169.49,52.01 169.49,51.24 169.3,51.05 168.92,51.05 168.73,51.24 168.73,52.01 168.54,52.2 168.16,52.2 167.97,52.01 167.97,51.24 167.78,51.05 167.4,51.05 167.21,51.24 167.21,52.01 167.02,52.2 166.64,52.2 166.45,52.01 166.45,50.53 166.26,50.34 165.57,50.34 165.38,50.53 165.38,50.93 165.25,51.05 164.67,51.05 162.85,49.23 162.85,32.04 159.77,28.96 148.21,28.96 148.07,28.82 147.07,28.82 146.69,29.21
  BOTTOM w0.157: v1(187.66,42.15) 188.1,42.6 188.12,42.6 188.13,42.6 188.51,42.6 188.51,42.6 188.8,42.6 188.94,42.45 P4.117
DDR3_CPU_CH1_MA11: length 95.8
  TOP w0.152: U14.P22 135.69,32.1 135.24,31.65 135.13,31.65 v1(135.09,31.61)
  L8_SIG w0.102: 136.38,22.56 135.43,23.51 135.43,25.64 133.8,27.28 133.8,28.01 133.77,28.03 133.77,29.68 133.41,30.05 133.41,30.82 134.23,31.65 135.05,31.65 v1(135.09,31.61)
  L8_SIG w0.191: v1(196.66,35.85) 196.13,35.33 195.37,35.33 192.91,32.86 192.91,30.9 191.78,29.77 188.47,29.77 177.49,18.79 177.49,18.36 177.12,17.99 176.69,17.99 176.21,17.51 176.21,17.24 176.3,17.16 176.3,16.89 176.03,16.62 175.76,16.62 175.67,16.7 175.4,16.7 175.13,16.43 175.13,16.17 175.28,16.02 175.28,15.75 175.01,15.48 174.74,15.48 174.6,15.63 174.33,15.63 174.06,15.36 174.06,15.09 174.21,14.94 174.21,14.67 173.94,14.4 173.67,14.4 173.52,14.55 173.25,14.55 172.98,14.28 172.98,14.01 173.13,13.86 173.13,13.59 172.86,13.32 172.59,13.32 172.44,13.47 172.17,13.47 171.9,13.2 171.9,12.93 172.05,12.78 172.05,12.51 171.78,12.24 171.51,12.24 171.36,12.39 171.09,12.39 170.82,12.12 170.82,11.71 169.97,10.86 146.52,10.86 140.75,16.63 140.75,18.2 139.05,19.9 139.05,20.37 137.96,21.46 137.49,21.46 136.38,22.56
  BOTTOM w0.157: P4.96 197.08,36.15 v1(196.66,35.85)
DDR3_CPU_CH1_MA12: length 94.9
  TOP w0.102: v1(135.86,27.35) 135.61,27.6 135.04,27.6 134.41,28.23 U14.G25
  L8_SIG w0.102: 143.34,21.21 141.71,22.85 140.49,22.85 138.13,25.2 138.13,25.46 136.24,27.35 v1(135.86,27.35)
  L8_SIG w0.191: 143.34,21.21 145.61,18.95 145.61,16.62 147.83,14.39 167.51,14.39 167.98,14.39 170.72,17.13 170.72,17.13 171.39,17.8 171.39,23.79 171.72,24.12 171.72,24.39 171.46,24.64 171.46,24.91 171.73,25.18 172,25.18 172.26,24.93 172.53,24.93 172.89,25.29 172.89,25.56 172.19,26.26 172.19,26.53 172.46,26.8 172.73,26.8 173.43,26.1 173.7,26.1 173.97,26.37 173.97,26.64 173.27,27.33 173.27,27.6 173.54,27.87 173.81,27.87 174.51,27.18 174.78,27.18 175.05,27.45 175.05,27.72 174.35,28.41 174.35,28.68 174.62,28.95 174.89,28.95 175.59,28.26 175.86,28.26 176.12,28.53 176.12,28.79 175.43,29.49 175.43,29.76 175.7,30.03 175.97,30.03 176.66,29.33 176.93,29.33 177.2,29.6 177.2,29.87 176.51,30.57 176.51,30.84 176.78,31.11 177.05,31.11 177.74,30.41 178.01,30.41 178.28,30.68 178.28,30.95 177.58,31.65 177.58,31.92 177.85,32.19 178.12,32.19 178.82,31.49 179.09,31.49 179.36,31.76 179.36,32.03 178.66,32.72 178.66,32.99 178.93,33.26 179.2,33.26 179.9,32.57 181.08,32.57 181.27,32.76 181.27,33.78 181.46,33.97 182.13,33.97 182.32,33.78 182.32,33.39 182.51,33.2 182.93,33.2 183.12,33.39 183.12,33.78 183.31,33.97 183.69,33.97 183.88,33.78 183.88,33.64 183.99,33.53 184.65,33.53 184.84,33.72 184.84,33.91 186.41,35.48 187.73,35.48 v1(187.76,35.51)
  BOTTOM w0.157: v1(187.76,35.51) 188.1,35.85 P4.95
DDR3_CPU_CH1_MA13: length 95.2
  TOP w0.102: 148.49,28.83 145.8,28.83 145.68,28.94 U14.G3
  TOP w0.157: v1(160.15,33.43) 159.92,33.43 155.32,28.83 148.49,28.83
  L8_SIG w0.191: v1(196.66,46.05) 197.28,45.43 197.28,44.65 196.88,44.25 192.46,44.25 191.92,44.78 190.83,44.78 190.05,44 188.17,44 188.1,44.07 185.83,44.07 184.94,44.96 184.33,44.96 181.64,47.65 181.64,56.67 180.42,57.89 180.01,57.89 179.58,57.45 179.2,57.45 179.01,57.65 179.01,57.7 178.82,57.89 178.44,57.89 178.25,57.7 178.25,57.65 178.06,57.45 177.68,57.45 177.49,57.65 177.49,57.7 177.3,57.89 176.92,57.89 176.73,57.7 176.73,57.65 176.53,57.45 176.15,57.45 175.96,57.65 175.96,57.7 175.77,57.89 175.39,57.89 175.2,57.7 175.2,57.65 175.01,57.45 174.63,57.45 174.44,57.65 174.44,57.7 174.25,57.89 173.87,57.89 173.68,57.7 173.68,57.65 173.49,57.45 173.11,57.45 172.92,57.65 172.92,57.7 172.72,57.89 172.34,57.89 172.15,57.7 172.15,57.65 171.96,57.45 171.58,57.45 171.39,57.65 171.39,57.7 171.2,57.89 170.82,57.89 170.63,57.7 170.63,57.65 170.44,57.45 170.06,57.45 169.87,57.65 169.87,57.7 169.68,57.89 169.3,57.89 169.11,57.7 169.11,57.65 168.91,57.45 168.53,57.45 168.34,57.65 168.34,57.7 168.15,57.89 167.77,57.89 167.58,57.7 167.58,57.65 167.39,57.45 167.01,57.45 166.82,57.65 166.82,57.7 166.63,57.89 166.25,57.89 166.06,57.7 166.06,57.65 165.87,57.45 165.49,57.45 165.3,57.65 165.3,57.7 165.1,57.89 164.72,57.89 164.53,57.7 164.53,57.65 164.34,57.45 163.8,57.45 163.41,57.06 163.41,53.03 160.15,49.77 v1(160.15,33.43)
  BOTTOM w0.157: P4.130 196.96,46.35 v1(196.66,46.05)
DDR3_CPU_CH1_MA14: length 96.3
  TOP w0.157: U14.G26 133.53,28.71 133.28,28.96 v1(133.17,28.96)
  L8_SIG w0.102: 136.77,20.6 136.77,21.16 135.16,22.77 135.16,25.62 133.59,27.19 133.59,27.92 133.57,27.95 133.57,28.56 v1(133.17,28.96)
  L8_SIG w0.191: 136.77,20.6 136.77,20.14 137.95,18.96 137.95,17.5 145.29,10.16 170.66,10.16 171.31,10.81 171.58,10.81 171.8,10.58 172.07,10.58 172.34,10.85 172.34,11.12 172.12,11.34 172.12,11.61 172.39,11.88 172.66,11.88 172.88,11.66 173.15,11.66 173.42,11.93 173.42,12.2 173.19,12.42 173.19,12.69 173.46,12.96 173.73,12.96 173.96,12.74 174.23,12.74 174.5,13.01 174.5,13.27 174.27,13.5 174.27,13.77 174.54,14.04 174.81,14.04 175.04,13.81 175.31,13.81 175.58,14.08 175.58,14.35 175.35,14.58 175.35,14.85 175.94,15.44 176.21,15.44 176.45,15.2 176.72,15.2 176.99,15.47 176.99,15.74 176.75,15.98 176.75,16.25 182.8,22.3 182.8,23.28 187.21,27.69 188.34,27.69 188.53,27.88 188.53,28.39 188.72,28.58 189.34,28.58 189.53,28.38 189.53,27.88 189.73,27.69 192.25,27.69 193.8,29.24 193.8,32.64 195.82,34.65 v1(195.9,34.65)
  BOTTOM w0.157: v1(195.9,34.65) 196.2,34.35 P4.90
DDR3_CPU_CH1_MA15: length 95.2
  TOP w0.157: U14.H26 133.37,29.47 133.25,29.58 133.03,29.58 v1(133.02,29.58)
  L8_SIG w0.102: 135.68,21.03 135.68,21.21 134.96,21.93 134.96,25.44 133.82,26.58 133.51,26.58 132.74,27.34 132.74,27.83 132.5,28.07 132.5,29.06 v1(133.02,29.58)
  L8_SIG w0.191: v1(196.66,33.45) 194.51,31.31 194.51,27.51 193.6,26.59 186.93,26.59 183.54,23.21 183.54,21.16 180.17,17.79 180.17,17.1 179.98,16.91 179.29,16.91 179.06,16.68 179.06,16.41 179.21,16.26 179.21,15.99 178.94,15.72 178.67,15.72 178.52,15.87 178.25,15.87 177.98,15.6 177.98,15.33 178.13,15.18 178.13,14.91 177.86,14.64 177.59,14.64 177.44,14.79 177.17,14.79 171.97,9.59 144.31,9.59 137.26,16.64 137.26,18.52 135.68,20.11 135.68,21.03
  BOTTOM w0.157: v1(196.66,33.45) 196.96,33.75 P4.88
DDR3_CPU_CH1_ODT0: length 95.3
  TOP w0.157: v1(146.58,31.12) 146.52,31.06 146.43,31.06 146.28,30.91 U14.L2
  L8_SIG w0.102: v1(146.58,31.12) 146.64,31.06 146.95,31.06 147.58,31.7 148.06,31.7
  L8_SIG w0.191: v1(196.66,44.85) 196.18,45.33 195.34,45.33 194.89,45.77 193.88,45.77 193.24,45.14 192.2,45.14 191.74,45.6 188.39,45.6 187.78,46.2 186.23,46.2 183.35,49.09 183.35,60.11 183.16,60.3 164.57,60.3 164.38,60.49 164.38,60.87 164.19,61.06 163.81,61.06 163.62,60.87 163.62,60.49 163.43,60.3 163.05,60.3 162.86,60.49 162.86,60.87 162.67,61.06 162.29,61.06 162.1,60.87 162.1,60.49 161.9,60.3 161.52,60.3 161.33,60.49 161.33,60.87 161.14,61.06 160.76,61.06 160.57,60.87 160.57,60.49 160.38,60.3 159.51,60.3 159.03,59.82 159.03,51.84 155.83,48.64 155.83,32.69 154.84,31.7 148.06,31.7
  BOTTOM w0.157: P4.126 196.96,45.15 v1(196.66,44.85)
DDR3_CPU_CH1_ODT1: length 95.5
  TOP w0.102: U14.N2 145.44,32.1 145.44,32.3 v1(145.36,32.38)
  L8_SIG w0.102: 147.06,32.41 146.8,32.41 146.62,32.23 145.51,32.23 v1(145.36,32.38)
  L8_SIG w0.191: 147.06,32.41 154.28,32.41 155.07,33.2 155.07,49.1 158.22,52.25 158.22,59.95 160.86,62.59 183.26,62.59 183.92,61.93 183.92,49.45 186.86,46.52 187.91,46.52 188.21,46.23 190.11,46.23 190.38,46.5 190.38,47.17 190.55,47.34 191.94,47.34 192.11,47.17 194.78,47.17 v1(195.9,46.05)
  BOTTOM w0.157: P4.128 197.11,45.75 196.92,45.57 196.38,45.57 v1(195.9,46.05)
DDR3_CPU_CH1_RAS_N: length 97.3
  TOP w0.157: U14.L8 142.95,30.47 v1(143,30.47)
  L8_SIG w0.102: v1(143,30.47) 143,30.59 143.1,30.69 144.75,30.69 145.93,29.51 147.16,29.51 147.49,29.84 148.59,29.84 148.84,29.59
  L8_SIG w0.191: v1(196.66,43.65) 190.46,43.65 189.48,42.67 185.19,42.67 184.78,43.08 183.78,43.08 179.92,46.94 179.92,48.85 179.73,49.04 179.39,49.04 179.2,49.23 179.2,49.61 179.39,49.8 179.73,49.8 179.92,49.99 179.92,50.38 179.73,50.57 179.31,50.57 179.12,50.76 179.12,51.14 179.31,51.33 179.73,51.33 179.92,51.52 179.92,52.26 179.2,52.97 179.2,53.43 179.01,53.62 178.63,53.62 178.44,53.43 178.44,52.97 178.25,52.78 177.87,52.78 177.68,52.97 177.68,53.43 177.49,53.62 177.11,53.62 176.92,53.43 176.92,52.97 176.73,52.78 176.35,52.78 176.16,52.97 176.16,53.43 175.97,53.62 175.59,53.62 175.39,53.43 175.39,52.97 175.2,52.78 174.82,52.78 174.63,52.97 174.63,53.43 174.44,53.62 174.06,53.62 173.87,53.43 173.87,52.97 173.68,52.78 173.3,52.78 173.11,52.97 173.11,53.43 172.92,53.62 172.54,53.62 172.35,53.43 172.35,52.97 172.16,52.78 171.78,52.78 171.58,52.97 171.58,53.43 171.39,53.62 171.01,53.62 170.82,53.43 170.82,52.97 170.63,52.78 170.25,52.78 170.06,52.97 170.06,53.43 169.87,53.62 169.49,53.62 169.3,53.43 169.3,52.97 169.11,52.78 168.73,52.78 168.54,52.97 168.54,53.43 168.35,53.62 167.97,53.62 167.77,53.43 167.77,52.97 167.58,52.78 167.2,52.78 167.01,52.97 167.01,53.43 166.82,53.62 166.44,53.62 166.25,53.43 166.25,52.97 166.06,52.78 165.59,52.78 162.28,49.47 162.28,32.35 159.51,29.59 148.84,29.59
  BOTTOM w0.157: P4.122 197.09,43.95 v1(196.66,43.65)
DDR3_CPU_CH1_RESET_N: length 68.9
  L5_SIG w0.152: v1(143.66,29.27) 145.64,29.27 145.98,28.93 149.64,28.93 158.85,19.71 158.85,17.86 166.6,10.11 188.8,10.11 189.23,10.54 194.41,10.54 195.1,11.23 195.1,13.11 v1(196.65,14.66)
  BOTTOM w0.097: P4.30 197.15,13.95 196.61,14.49 196.61,14.62 v1(196.65,14.66)
  BOTTOM w0.152: R292.2 143.12,28.72 v1(143.66,29.27)
  BOTTOM w0.381: R292.2 143,29.48 N46.2
DDR3_CPU_CH1_RESET_R_N: length 2.5
  TOP w0.102: U14.N11 141.02,31.56 141.35,31.24 v1(141.38,31.21)
  BOTTOM w0.254: N46.1 142.15,30.56 R275.1 141.95,30.61 141.38,31.19 v1(141.38,31.21)
DDR3_CPU_CH1_VREF: length 13.8
  TOP w0.254: U14.R29 132.42,32.82 132.17,32.57 132.13,32.57 v1(132.08,32.52)
  L3_SIG w0.178: v1(132.08,32.52) 131.62,32.06 131.62,28.29 131.85,28.05 131.85,25.99 133.86,23.99 v1(134.11,23.99)
  BOTTOM w0.178: 134.11,23.35 v1(134.11,23.99)
  BOTTOM w0.381: 134.11,23.35 134.11,22.37 R317.1 R319.2 ; C449.1 134.16,23.94 v1(134.11,23.99)
DDR3_CPU_CH1_VREFCA: length 11.2
  BOTTOM w0.381: C403.1 R286.1 R291.2 202.45,28.32 201.32,29.45 201.32,31.09 200.94,31.47 200.81,31.47 199.73,32.55 P4.84
DDR3_CPU_CH1_VREFDQ: length 39.1
  TOP w0.152: N25.2 v1(156.46,1.46)
  L10_SIG w0.254: v1(189.93,2.67) 189.93,1.97 189.36,1.4 176.78,1.4 175.51,2.67 156.84,2.67 156.46,2.29 v1(156.46,1.46)
  BOTTOM w0.254: P4.1 v1(189.93,2.67)
DDR3_CPU_CH1_WE_N: length 94.5
  TOP w0.102: v1(143.62,31.98) 143.62,31.89 U14.N7
  L8_SIG w0.102: 150.62,30.86 150.11,30.86 149.86,30.61 145.67,30.61 145.18,31.1 143.83,31.1 143.62,31.31 v1(143.62,31.98)
  L8_SIG w0.191: v1(187.6,43.56) 185.62,43.56 184.8,44.39 184.09,44.39 181.06,47.41 181.06,55.03 179.91,56.18 178.88,56.18 178.43,55.73 178.05,55.73 177.86,55.92 177.86,56.58 177.66,56.77 177.28,56.77 177.09,56.58 177.09,55.92 176.9,55.73 176.52,55.73 176.33,55.92 176.33,56.58 176.14,56.77 175.76,56.77 175.57,56.58 175.57,55.92 175.38,55.73 175,55.73 174.81,55.92 174.81,56.58 174.62,56.77 174.24,56.77 174.05,56.58 174.05,55.92 173.85,55.73 173.47,55.73 173.28,55.92 173.28,56.58 173.09,56.77 172.71,56.77 172.52,56.58 172.52,55.92 172.33,55.73 171.95,55.73 171.76,55.92 171.76,56.58 171.57,56.77 171.19,56.77 171,56.58 171,55.92 170.81,55.73 170.43,55.73 170.24,55.92 170.24,56.58 170.04,56.77 169.66,56.77 169.47,56.58 169.47,55.92 169.28,55.73 168.9,55.73 168.71,55.92 168.71,56.58 168.52,56.77 168.14,56.77 167.95,56.58 167.95,55.92 167.76,55.73 167.38,55.73 167.19,55.92 167.19,56.58 167,56.77 166.62,56.77 166.43,56.58 166.43,55.92 166.23,55.73 165.85,55.73 165.66,55.92 165.66,56.58 165.47,56.77 165.09,56.77 164.9,56.58 164.9,55.92 164.71,55.73 164.17,55.73 163.98,55.54 163.98,52.79 161.13,49.95 161.13,33.12 158.88,30.86 150.62,30.86
  BOTTOM w0.157: P4.121 189.01,43.65 188.85,43.81 188.26,43.81 188.01,43.56 v1(187.6,43.56)
DDR3_VCCA_PWROK: length 38.7
  TOP w0.099: U1.2 45.7,69.9 45.49,70.1 v1(44.7,70.1) ; U13.2 39.4,41.25 38.99,41.66 v1(37.8,41.66) ; v1(37.29,49.15) 36.82,49.62 U7.A9
  L5_SIG w0.097: v1(38.35,61.21) 38.86,61.72 38.86,65.53 41.63,68.3 43.41,68.3 44.7,69.6 v1(44.7,70.1)
  L8_SIG w0.097: v1(38.35,61.21) 37.83,60.69 37.83,49.59 37.39,49.15 v1(37.29,49.15) 38.79,47.65 38.79,46.25 38.51,45.97 38.51,42.37 v1(37.8,41.66)
ERROR_CPU_N0: length 111.8
  TOP w0.099: U7.K14 31.9,58.62 v1(32.36,58.17) ; v1(97.28,44.65) 97.28,44.55 97.38,44.45 97.98,44.45 R47.2
  TOP w0.102: v1(111.66,40.28) 111.66,40.92 111.86,41.12 113.76,41.12 114.15,40.74 U14.AL65
  L5_SIG w0.097: v1(111.66,40.28) 111.25,39.88 109.83,39.88 108.06,41.65 108.06,42.98 107.64,43.41 105.53,43.41 104.94,43.99 102.72,43.99 101.98,44.73 97.36,44.73 v1(97.28,44.65) 96.43,44.65 93.88,47.21 93.88,50.6 89.49,54.99 83.95,54.99 83.01,55.93 52.74,55.93 52.02,55.21 51.98,55.21 50.31,55.21 49.6,54.5 48.36,54.5 47.19,53.34 47.19,48.36 45.19,46.35 34.87,46.35 33.4,47.83 v1(33.4,47.9)
  L10_SIG w0.097: v1(32.36,58.17) 32.41,58.17 33.83,56.74 33.83,48.56 33.4,48.13 v1(33.4,47.9)
ERROR_CPU_N1: length 111.5
  TOP w0.099: v1(96.65,47.07) 96.99,47.41 R41.2 ; U7.K13 32.94,58.62 v1(33.43,58.14)
  TOP w0.102: U14.AL62 115.4,40.5 115.21,40.5 115.18,40.46 114.54,40.46 114.49,40.41 114.17,40.41 113.66,40.92 112.88,40.92 112.52,40.56 v1(112.52,40.41)
  L5_SIG w0.097: v1(112.52,40.41) 112.19,40.74 109.89,40.74 108.56,42.08 108.56,44.96 107.57,45.95 106.97,45.95 106.7,45.68 103.09,45.68 101.4,47.38 97.08,47.38 96.77,47.07 v1(96.65,47.07) 95.52,47.07 94.93,47.65 94.93,51.03 89.93,56.04 84.72,56.04 84.72,56.04 84.46,56.04 83.52,56.98 52.16,56.98 51.45,56.27 50.63,56.27 47.62,56.27 46.06,54.71 46.06,50.66 45.06,49.66 42.93,49.66 41.2,47.93 35.08,47.93 34.82,48.18 v1(34.19,48.18)
  L8_SIG w0.097: v1(33.43,58.14) 33.83,57.73 33.83,48.62 34.19,48.26 v1(34.19,48.18)
ERROR_CPU_N2: length 112
  TOP w0.099: v1(97.41,46.63) 97.52,46.52 R43.2 ; U7.K12 33.82,58.76 v1(33.4,59.18)
  TOP w0.102: U14.AL63 114.74,41.09 114.08,41.09 113.85,41.33 111.51,41.33 110.97,40.79 v1(110.97,40.34)
  L5_SIG w0.097: v1(34.57,47.5) 34.67,47.6 41.5,47.6 42.29,48.39 45.16,48.39 46.43,49.66 46.43,53.59 48.04,55.2 49.31,55.2 50.02,55.92 50.78,55.92 51.63,55.92 52.34,56.63 83.37,56.63 84.31,55.69 84.57,55.69 84.57,55.69 89.78,55.69 94.58,50.89 94.58,47.51 94.78,47.3 95.71,46.38 96,46.38 97.16,46.38 v1(97.41,46.63) 97.8,47.03 101.31,47.03 103.38,44.95 104.88,44.95 105.52,44.32 105.93,44.32 106.62,43.62 107.89,43.62 108.28,43.23 108.28,41.91 109.8,40.39 110.92,40.39 v1(110.97,40.34)
  L10_SIG w0.097: v1(33.4,59.18) 34.26,59.18 34.79,58.66 34.79,47.71 v1(34.57,47.5)
FLEX_CLK_SE0: length 26.1
  TOP w0.254: U14.AH59 v1(117.76,39.63)
  L8_SIG w0.097: v1(101.65,35.81) 101.52,35.69 100.84,35.69 99.57,36.96 98.42,36.96 v1(97.79,36.32)
  BOTTOM w0.097: v1(97.79,36.32) 97.79,36.11 97.59,35.9 R250.2 ; R237.2 115.58,39.1 115.27,38.79 114.38,38.79 113.47,37.88 113.39,37.88 113.39,37.87 112.9,37.87 112.32,37.29 112.32,36.91 111.05,35.64 110.21,35.64 109.6,36.25 108.31,36.25 107.59,35.53 106.76,35.53 106.27,36.02 104.85,36.02 104.22,36.65 102.82,36.65 101.93,35.76 101.7,35.76 v1(101.65,35.81)
  BOTTOM w0.102: R237.2 116.4,39.43 116.55,39.28 117.41,39.28 v1(117.76,39.63)
FLEX_CLK_SE1: length 14.9
  TOP w0.099: v1(110.31,35.01) R83.2 109.63,34.44 109.54,34.34 109.54,34.09 109.4,33.96 108.04,33.96 R85.2
  TOP w0.254: U14.AG56 v1(119.29,38.23)
  BOTTOM w0.097: v1(110.31,35.01) 110.53,35.23 111.25,35.23 112.75,36.73 112.75,37.11 113.11,37.47 113.62,37.47 113.63,37.48 113.7,37.48 114.5,38.28
  BOTTOM w0.102: v1(119.29,38.23) 118.71,38.81 117.02,38.81 116.48,38.28 114.5,38.28
FP_PWR_BTN_N: length 120.4
  TOP w0.102: U7.B16 v1(29.32,50.13)
  L3_SIG w0.097: v1(26.57,15.44) 26.19,15.06 26.19,6.65 28.05,4.79 82.57,4.79 83.9,6.12 83.9,8.9 84.65,9.65 88.21,9.65 89.99,7.87 89.99,7.42 90.55,6.86 v1(90.86,6.86)
  L8_SIG w0.097: v1(26.57,15.44) 26.37,15.65 26.37,46.05 28.63,48.31 28.63,49.43 v1(29.32,50.13)
  BOTTOM w0.097: v1(90.86,6.86) 90.88,6.86 91.42,6.32 S1.B8
  BOTTOM w0.508: R207.2 29.4,50.2 v1(29.32,50.13)
FP_RST_BTN_N: length 1.7
  TOP w0.102: v1(45.48,54.15) 45.29,54.15 U7.F1
  BOTTOM w0.097: TP8.1 45.84,53.9 45.58,54.15 v1(45.48,54.15)
FPGA_JMPR1: length 2.9
  TOP w0.102: U7.E1 45.21,53.24 v1(45.34,53.24)
  BOTTOM w0.097: 45.42,53.24 46.7,53.24 47.22,52.72 J5.2
  BOTTOM w0.102: 45.42,53.24 v1(45.34,53.24)
GBE_CPU_SDP0_1: length 1.3
  TOP w0.254: U14.T48 122.79,32.95 v1(122.9,32.95)
  BOTTOM w0.178: v1(122.9,32.95) 122.84,33.01 TP15.1
GBE_CPU_WOL: length 12.6
  TOP w0.099: 112.93,34.95 111.68,33.71 111.68,30.8 110.85,29.97 110.41,29.97 110.29,29.84 110.29,28.1 R103.1 109.82,27.64 R106.1
  TOP w0.102: U14.V63 115.14,34.44 114.76,34.83 114.12,34.83 114.09,34.86 114.09,34.86 114,34.95 112.93,34.95
GBE_OBSN: length 1.3
  TOP w0.254: U14.H50 v1(121.44,29.85)
  BOTTOM w0.254: v1(121.44,29.85) 121.55,29.74 122.13,29.74 R285.1
GBE_OBSP: length 1.4
  TOP w0.254: U14.G50 v1(121.44,29.09)
  BOTTOM w0.254: v1(121.44,29.09) 121.68,28.85 122.13,28.85 R285.2
GBE_RXN_0: length 1.4
  TOP w0.099: U14.K48 122.55,30.23 122.87,30.56 v1(122.87,30.61)
  BOTTOM w0.097: v1(122.87,30.61) 122.59,30.89 TP16.1
GBE_RXP_0: length 3.8
  TOP w0.099: U14.H48 122.52,29.47 v1(122.9,29.85)
  BOTTOM w0.097: TP17.1 121.44,27.3 122.56,28.42 122.56,29.5 v1(122.9,29.85)
GBE_TXN_0: length 5
  TOP w0.099: U14.B48 122.94,26.32 122.94,24.33 123.34,23.93 v1(123.55,23.93)
  BOTTOM w0.097: v1(123.55,23.93) 123.85,23.62 TP20.1
GBE_TXP_0: length 3.9
  TOP w0.099: v1(123.41,24.74) 123.24,24.9 123.24,26.63 122.86,27.02 U14.D48
  BOTTOM w0.097: TP18.1 124.06,24.74 v1(123.41,24.74)
GPIO_CPU_11: length 94.4
  TOP w0.099: v1(105.65,43.86) 105.49,44.02 103.47,44.02 R46.2
  TOP w0.102: v1(41.25,50.06) 41.18,50.12 41.18,50.26 U7.B5 ; U14.AN63 114.73,41.32 114.14,41.32 113.93,41.53 110.41,41.53 109.17,42.77 107.8,42.77 107.17,43.4 106.03,43.4 105.65,43.78 v1(105.65,43.86)
  L5_SIG w0.097: v1(105.65,43.86) 104.98,44.53 102.95,44.53 102.16,45.31 96.27,45.31 94.69,46.89 94.69,46.9 94.23,47.36 94.23,50.74 89.63,55.34 84.43,55.34 84.43,55.34 84.17,55.34 83.23,56.28 52.52,56.28 51.81,55.56 51.54,55.56 51.54,55.57 50.92,55.57 50.92,55.56 50.17,55.56 49.45,54.85 48.27,54.85 46.84,53.41 46.84,49.6 45.16,47.93 43.33,47.93 42.39,46.99 v1(42.05,46.99)
  L8_SIG w0.097: v1(41.25,50.06) 42.06,49.25 42.06,47 v1(42.05,46.99)
GPIO_CPU_12: length 102.7
  TOP w0.099: R31.2 105.27,51.73 v1(105.47,51.52)
  TOP w0.102: v1(112.62,43.66) 112.62,43.56 113.06,43.13 114.26,43.13 114.56,42.83 115.16,42.83 U14.AR63 ; U7.B14 31.35,50.16 v1(31.35,50.12)
  L5_SIG w0.097: v1(112.62,43.66) 112.62,44.6 108.94,48.29 108.94,50.55 108.28,51.21 105.79,51.21 v1(105.47,51.52) 105.26,51.31 103.02,51.31 101.19,53.14 101.18,53.14 100.34,53.98 98.86,53.98 98.5,53.62 94.86,53.62 94.8,53.67 94.77,53.67 90.01,58.44 85.75,58.44 85.42,58.77 60.64,58.77 59.21,60.2 53.99,60.2 53.09,59.29 50.59,59.29 49.49,58.19 44.68,58.19 43.89,57.4 43.89,56.92 43.66,56.69 41.21,56.69 40.82,56.3 40.82,52.45 38.86,50.5 38.86,50.01 38.48,49.63 36.09,49.63 35.15,50.57 31.8,50.57 v1(31.35,50.12)
GPIO_CPU_SUS0: length 120.4
  TOP w0.099: R101.2 104.6,28.27 105.16,28.83 v1(105.16,28.87) ; v1(32.26,51.18) 32.7,51.62 U7.C13
  TOP w0.102: U14.V66 112.75,34.44 111.91,33.6
  TOP w0.114: 111.91,33.6 111.91,30.61 v1(110.82,29.51)
  L3_SIG w0.097: v1(110.82,29.51) 110.59,29.29 107.9,29.29 107.19,28.57 105.45,28.57 v1(105.16,28.87)
  L5_SIG w0.097: v1(105.16,28.87) 103.63,30.39 103.63,31.5 102.84,32.28 101.6,32.28 100.15,33.73 97.69,33.73 95.58,35.84 93.88,35.84 93.04,36.68 84.58,36.68 84.05,37.21 84.05,51.3 81.53,53.83 55.48,53.83 53.96,52.31 50.13,52.31 49.58,51.76 49.58,45.98 48.09,44.5 42.27,44.5 42.12,44.35 35.15,44.35 v1(33.4,46.1)
  L8_SIG w0.097: v1(33.4,46.1) 33.4,46.33 32.44,47.29 32.44,51 v1(32.26,51.18)
GPIO_CPU_SUS1: length 16.9
  TOP w0.254: U14.W54 120.06,34.25 v1(120.1,34.21)
  L5_SIG w0.097: v1(120.1,34.21) 121.07,33.24 121.95,33.24 122.48,32.72 122.48,27.81 120.28,25.62 120.28,24.75 v1(120.37,24.66)
  BOTTOM w0.097: R304.2 121.49,25.92 121.49,24.16 TP19.1 121.17,23.79 R314.2 v1(120.37,24.66)
GPIO_CPU_SUS2: length 135.5
  TOP w0.102: U7.K1 44.92,58.62 v1(45.49,59.19)
  TOP w0.254: U14.T53 v1(119.67,33.67)
  L3_SIG w0.097: v1(43.92,43.41) 54.69,43.41 59.84,48.56 63.98,48.56 66.07,46.48 73,46.48 75.03,44.45 75.03,41.78 73.69,40.44 73.69,33.55 74.68,32.56 74.68,30.35 75.46,29.57 84.63,29.57 87.8,26.4 90.33,26.4 92.21,24.53 95.12,24.53 95.66,25.07 103.43,25.07 104.01,25.65 106.81,25.65 107.59,24.87 111.56,24.87 112.12,25.43 v1(113.18,25.43)
  L5_SIG w0.097: v1(113.74,22.07) 114.22,21.59 117.98,21.59 119.88,23.49 119.88,25.71 122.17,28 122.17,32.46 121.67,32.97 120.88,32.97 120.18,33.67 v1(119.67,33.67)
  L10_SIG w0.097: v1(43.92,43.41) 44.69,44.19 44.69,45.47 47.26,48.04 47.26,56.32 45.49,58.09 v1(45.49,59.19)
  BOTTOM w0.097: v1(113.74,22.07) 113.74,22.4 112.54,23.6 112.54,24.45 113.23,25.15 113.23,25.38 v1(113.18,25.43)
GPIO_CPU_SUS6: length 131.1
  TOP w0.099: v1(36.4,53.14) 35.89,52.62 U7.D10
  TOP w0.254: U14.AC52 120.46,36.27 120.34,36.15 v1(120.31,36.15)
  L3_SIG w0.097: v1(120.31,36.15) 120.31,36.22 119.91,36.62 114.86,36.62 112.12,33.88 110.46,33.88 109.32,32.74 108.18,32.74 107.72,32.28 100.83,32.28 99.1,34.01 95.78,34.01 94.68,35.11 94.05,35.11 93.38,35.78 93.38,39.9 92.68,40.59 92.68,45.87 91.08,47.48 91.08,49.88 85.9,55.06 84.19,55.06 83.42,55.83 54.3,55.83 54.08,56.06 52.7,56.06 51.38,54.74 51.38,53.7 49.33,51.64 49.33,48.82 48.86,48.36 47.06,48.36 46.28,47.57 37.62,47.57 37.29,47.24 v1(37.29,47.14)
  L8_SIG w0.097: v1(36.4,53.14) 36.42,53.14 36.83,52.73 36.83,50.01 36.37,49.56 36.37,48.67 37.29,47.75 v1(37.29,47.14)
  BOTTOM w0.097: 111.58,30.63 111.58,29.56 110.73,28.71 R288.2
  BOTTOM w0.102: v1(120.31,36.15) 120.31,35.93 119.53,35.15 118.85,35.15 118.57,34.87 115.9,34.87 115.4,34.37 115.4,33.59 114.23,32.42 114.23,31.99 113.97,31.72 112.67,31.72 111.58,30.63
GPIO_CPU_SUS7: length 108.8
  TOP w0.102: U7.H4 v1(42.32,56.12)
  TOP w0.254: U14.Y50 121.87,35.38 121.55,35.71 v1(121.54,35.71)
  L3_SIG w0.097: v1(52.96,55.5) 52.96,55.12 53.39,54.69 58.48,54.69 58.92,55.13 82.56,55.13 86.74,50.95 86.74,42.52 87.25,42.01 90.63,42.01 91.52,41.12 91.52,37.49 92.67,36.33 92.67,35.34 93.7,34.32 94.41,34.32 95.25,33.47 95.25,31.56 96.8,30.01 100.1,30.01 100.42,29.7 103.36,29.7 105.05,31.39 107.16,31.39 107.49,31.06 109.22,31.06 v1(110.77,32.61)
  L5_SIG w0.097: v1(121.54,35.71) 121.54,35.61 121.19,35.26 113.41,35.26 v1(110.77,32.61)
  L8_SIG w0.097: v1(52.96,55.5) 52.65,55.19 52.65,53.85 52.04,53.24 52.04,53.24 51.43,52.63 46.61,52.63 45.52,53.72 45.26,53.72 45.01,53.98 45.01,54.28 44.68,54.61 44.2,54.61 43.81,54.99 43.81,55.83 43.52,56.12 v1(42.32,56.12)
  BOTTOM w0.097: R270.2 109.91,31.85 110.67,32.61 v1(110.77,32.61)
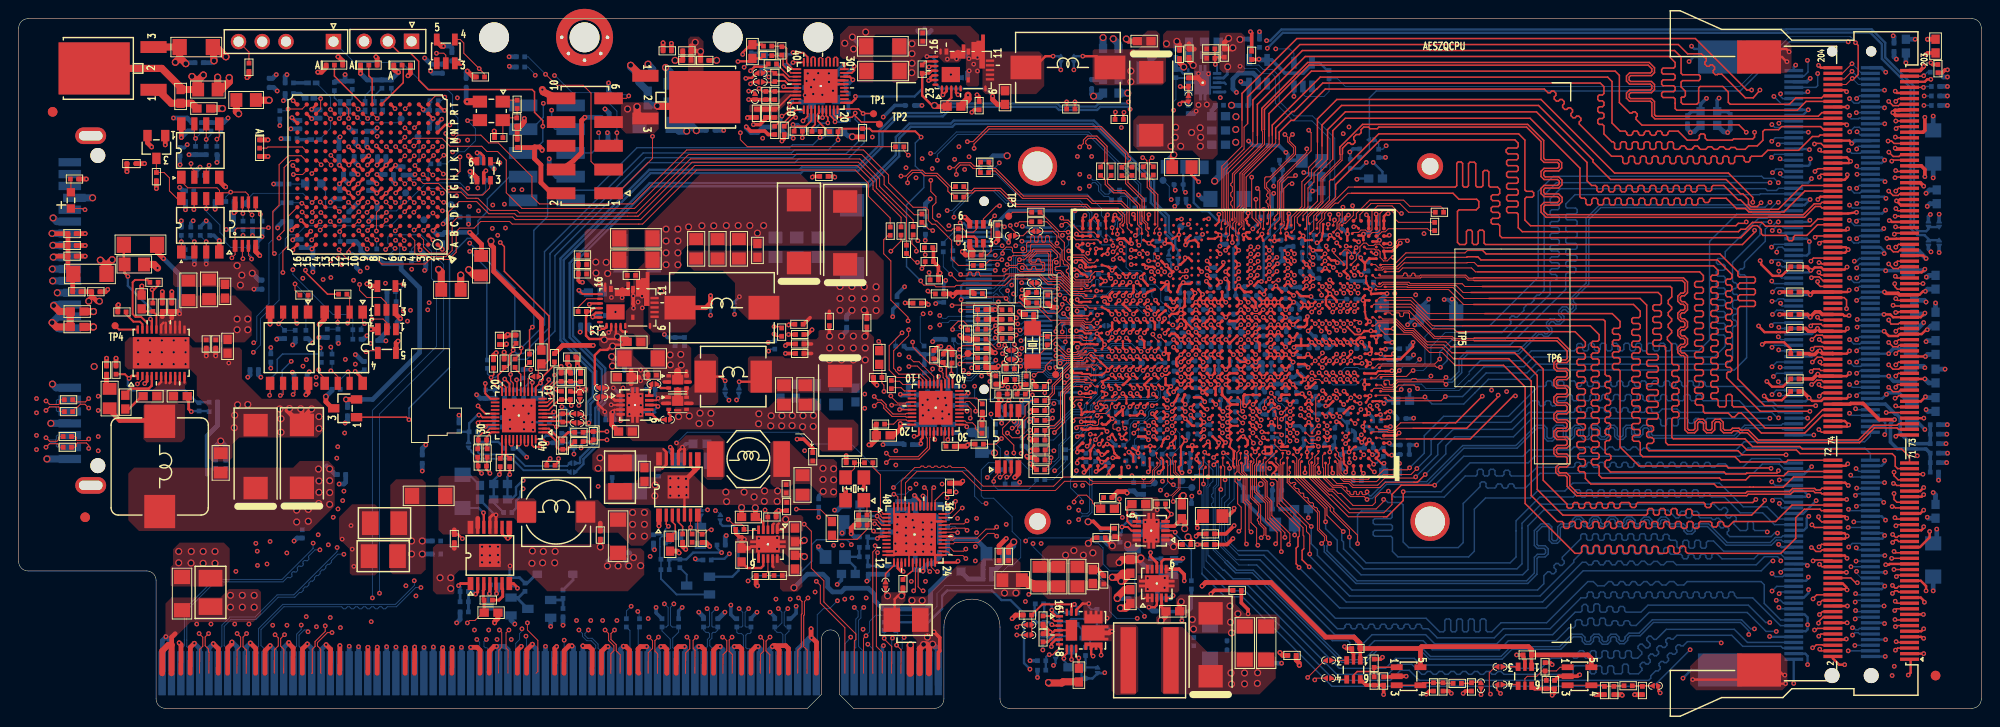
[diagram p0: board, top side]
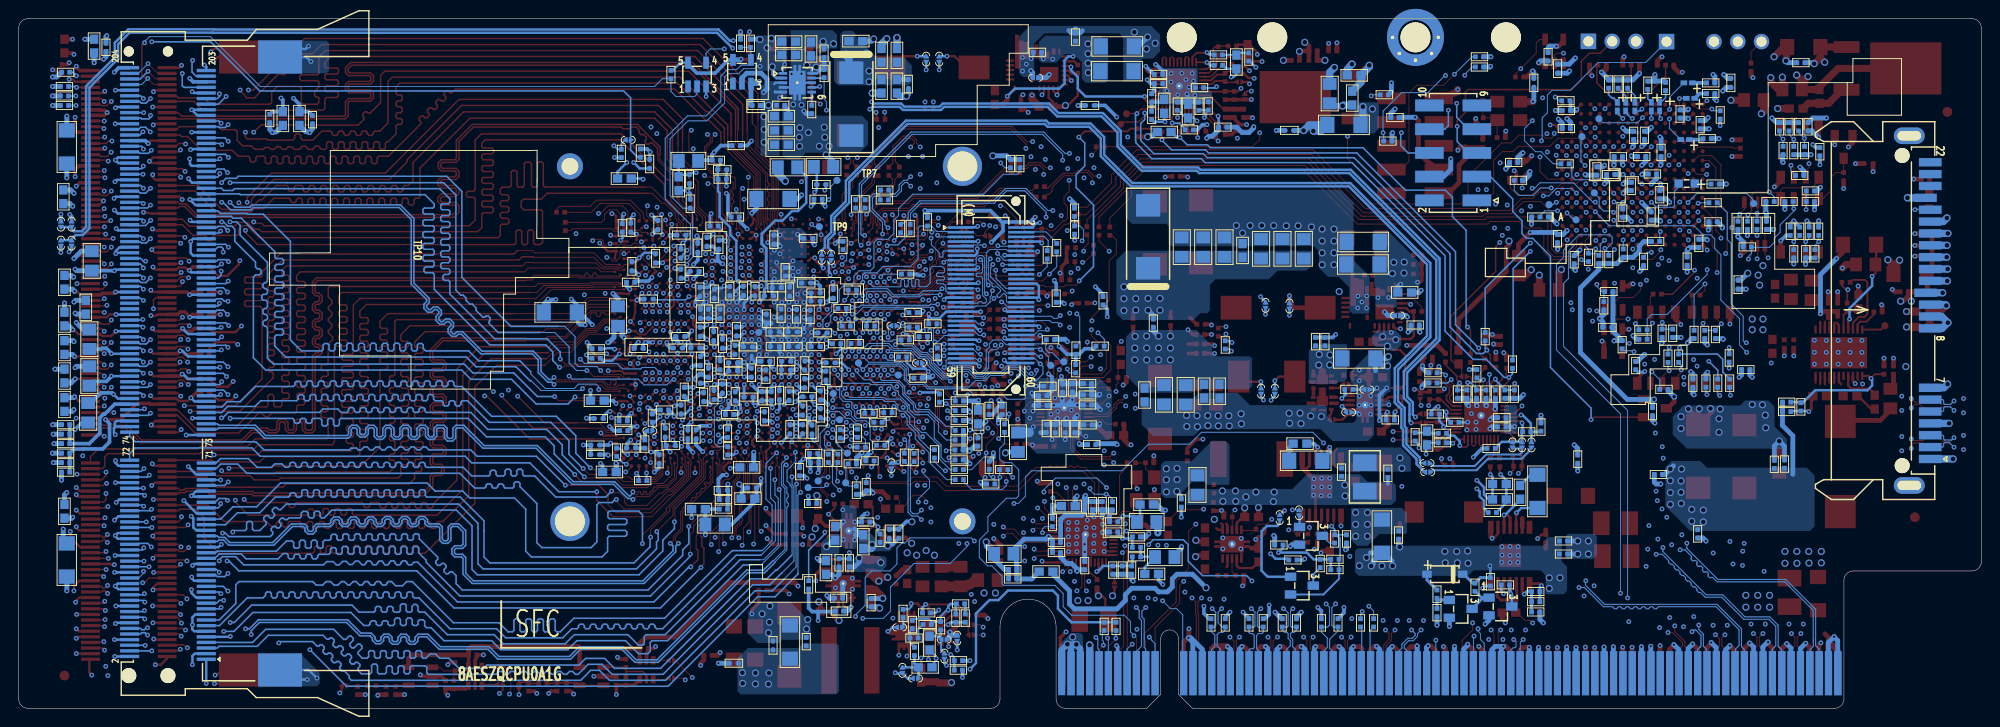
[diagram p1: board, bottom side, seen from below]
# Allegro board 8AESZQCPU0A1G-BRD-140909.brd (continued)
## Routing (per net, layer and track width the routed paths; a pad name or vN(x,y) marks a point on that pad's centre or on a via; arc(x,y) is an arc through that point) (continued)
I2C_ID_A0: length 2.8
  TOP w0.099: U9.1 v1(17.4,49.94)
  BOTTOM w0.097: R205.2 v1(17.4,49.94) 17.81,49.53 R213.1
I2C_ID_A1: length 2.8
  TOP w0.099: U9.2 v1(18.8,49.94)
  BOTTOM w0.097: R204.2 18.41,50.32 v1(18.8,49.94) R212.1
I2C_ID_A2: length 2.9
  TOP w0.099: U9.3 v1(20.07,49.94)
  BOTTOM w0.097: R211.1 v1(20.07,49.94) 19.43,50.57 R203.2
ID_EEPROM_VCC: length 6.2
  TOP w0.102: U9.8 16.95,54.55 16.13,55.37 16.13,56.77 15.56,57.34 C39.1 U4.3
ID_EEPROM_WP_P: length 3.2
  TOP w0.099: v1(18.75,53.37) 18.8,53.42 U9.7
  BOTTOM w0.097: R192.1 R195.1 18.73,53.38 v1(18.75,53.37)
INTRUDER_N: length 7.4
  TOP w0.254: U14.AD53 v1(119.67,37.65)
  BOTTOM w0.097: R254.1 114.5,35.33 114.81,35.64 114.81,36.37 115.47,37.03 119.06,37.03 v1(119.67,37.65)
IRQ_ILB_SERIRQ_CPU: length 109.4
  TOP w0.102: U7.C2 43.35,51.15 v1(43.32,51.15)
  TOP w0.254: v1(121.64,43.67) 121.69,43.62 121.68,43.55 U14.AT50
  L5_SIG w0.097: v1(121.64,43.67) 120.14,45.17 116.13,45.17 115.39,45.9 115.39,46.11 113.49,48.01 113.49,48.43 112.51,49.41 111.73,49.41 111.63,49.31 110.94,49.31 110.67,49.58 110.67,51.66 109.07,53.26 104.89,53.26 104.29,53.86 104.29,60.12 102.84,61.57 96.28,61.57 94.6,59.89 86.54,59.89 86.26,60.17 86.01,60.17 86,60.17 85.42,60.17 61.37,60.17 59.72,61.82 53.63,61.82 52.54,60.73 48.11,60.73 v1(48.03,60.81)
  L8_SIG w0.097: v1(48.03,60.81) 47.52,60.3 46.71,60.3 46.05,60.96 42.42,60.96 41.83,60.38 41.83,59.82 41.71,59.69 41.17,59.69 40.84,59.35 40.84,52.48 41.38,51.94 42.53,51.94 v1(43.32,51.15)
  BOTTOM w0.097: v1(121.64,43.67) 121.25,44.06 R221.1
LED_SEG0_0_HI: length 1.6
  TOP w0.099: U7.R11 v1(34.3,63.11)
  BOTTOM w0.152: D8.2 34.42,63.22 v1(34.3,63.11)
LED_SEG0_0_HI_R: length 1.6
  BOTTOM w0.152: D8.1 34.28,64.85 33.78,65.34 R156.1
LED_SEG0_1_HI: length 4.1
  TOP w0.099: U7.R12 v1(33.36,64.09)
  BOTTOM w0.097: D2.2 33.36,65.4 v1(33.36,64.09)
LED_SEG0_1_HI_R: length 1.5
  BOTTOM w0.381: R150.1 D2.1
LED_SEG0_2_HI: length 3.5
  TOP w0.099: U7.R13 32.82,63.62 v1(33.38,63.07)
  BOTTOM w0.097: v1(33.38,63.07) 33.38,62.08 D9.2
LED_SEG0_2_HI_R: length 1.5
  BOTTOM w0.381: D9.1 29.88,60.86 R175.1
LED_SEG0_3_HI: length 2.6
  TOP w0.099: v1(32.31,65.25) 32.31,64.14 31.82,63.65 U7.R14
  BOTTOM w0.097: v1(32.31,65.25) 32.28,65.28 D3.2
LED_SEG0_3_HI_R: length 1.5
  BOTTOM w0.381: D3.1 30.15,65.79 R158.1
LED_SEG1_0_HI_R: length 2
  BOTTOM w0.152: R151.1 39.88,65.66 39.55,65.33 39.33,65.33 38.95,64.95 D4.1
LED_SEG1_0_LO: length 1.8
  TOP w0.099: U7.R8 37.85,63.62 v1(38.35,63.12)
  BOTTOM w0.152: v1(38.35,63.12) 38.95,63.71 D4.2
LED_SEG1_1_HI_R: length 1.8
  BOTTOM w0.152: D5.1 38.06,65.55 R152.1
LED_SEG1_1_LO: length 1.9
  TOP w0.099: v1(37.34,63.12) 36.83,63.62 U7.R9
  BOTTOM w0.152: v1(37.34,63.12) 37.42,63.12 38.06,63.76 D5.2
LED_SEG1_2_HI_R: length 1.8
  BOTTOM w0.152: R153.1 37.07,65.58 D6.1
LED_SEG1_2_LO: length 1.5
  TOP w0.099: U7.T10 v1(36.32,64.13)
  BOTTOM w0.152: v1(36.32,64.13) 36.51,63.93 D6.2
LED_SEG1_3_HI_R: length 1.5
  BOTTOM w0.152: R154.1 35.69,65.23 D7.1
LED_SEG1_3_LO: length 2.5
  TOP w0.099: v1(35.31,63.12) 35.31,64.14 U7.T11
  BOTTOM w0.152: D7.2 v1(35.31,63.12)
LPC_CLKRUN_N: length 23.6
  TOP w0.099: v1(122.07,39.83) 122.62,39.28 U14.AH48 ; v1(103.81,35.84) 103.79,35.82 103.79,35.68 103.89,35.58 R81.2
  L3_SIG w0.097: v1(103.81,35.84) 103.95,35.7 107.48,35.7 109.83,38.05 109.83,39.52 110.19,39.89 114.27,39.89 114.94,39.21 115.86,39.21 116,39.35 116.4,39.35 116.75,39 121.3,39 122.07,39.78 v1(122.07,39.83)
LPC_FRAME_N: length 60.7
  TOP w0.099: U7.H3 43.29,56.16 44.93,56.16 45.85,55.24 47.32,55.24 47.98,54.58 48.92,54.58 48.92,54.58 49.14,54.58 50.44,53.28 53.32,53.28 53.59,53.02 65.3,53.02 65.3,53.02 66.1,53.02 71.87,58.79 90,58.79 92.12,56.67 92.12,55.84 92.96,55 95.71,52.25 R32.1
LPC_FRAME_N_R: length 31.3
  TOP w0.099: v1(96.05,48.92) 96.05,49.24 95.58,49.71 95.58,50.53 R32.2
  TOP w0.254: U14.AH56 v1(118.53,39.63)
  L5_SIG w0.097: v1(118.53,39.63) 118.53,40.38 118.29,40.61 114.71,40.61 113.77,41.55 110.41,41.55 109.47,42.49 109.47,45.36 108.27,46.57 106.7,46.57 106.67,46.54 106.67,46.54 106.41,46.28 104.22,46.28 102.06,48.44 98.96,48.44 98.3,49.1 96.23,49.1 v1(96.05,48.92)
LPC_LAD0: length 66.9
  TOP w0.099: U7.B3 43.32,50.12 43.32,49.38 43.98,48.72 45.54,48.72 45.97,49.15 45.97,53.09 47.12,54.23 49,54.23 50.3,52.93 53.07,52.93 53.33,52.66 65.16,52.66 65.95,52.66 66.28,52.66 72.05,58.44 89.85,58.44 91.77,56.53 91.77,55.84 91.77,55.69 92.61,54.85 92.81,54.65 95,52.47 R38.1
LPC_LAD0_R: length 32
  TOP w0.099: R38.2 95,48.69 95.99,47.69 96.13,47.69 v1(96.16,47.73)
  TOP w0.254: U14.AG54 120.08,38.21 v1(120.1,38.19)
  L5_SIG w0.097: v1(120.1,38.19) 120.1,38.22 119.38,38.94 118.08,38.94 118,39.03 116.7,39.03 116.41,39.32 115.09,39.32 113.36,41.05 110.02,41.05 108.84,42.23 108.84,45.09 107.77,46.15 106.85,46.15 106.57,45.88 103.52,45.88 101.68,47.73 v1(96.16,47.73)
LPC_LAD1: length 65.5
  TOP w0.099: R24.1 93.79,60.11 77.97,60.11 77.22,60.86 v1(77.22,61.59)
  TOP w0.102: U7.E8 v1(37.27,53.07)
  L5_SIG w0.097: v1(46.48,61.49) 46.48,61.44 46.15,61.11 46.15,60.32 45.47,59.64 44.17,59.64 43.84,59.31 43.84,58.88 43.46,58.5 41.35,58.5 40.44,57.58 39.67,57.58 38.79,56.69 38.79,53.72 38.14,53.07 v1(37.27,53.07)
  L10_SIG w0.097: v1(77.22,61.59) 76.76,61.14 70.05,61.14 68.88,62.31 60.71,62.31 59.69,61.29 46.69,61.29 v1(46.48,61.49)
LPC_LAD1_R: length 36.9
  TOP w0.099: v1(95.19,59.2) 94.7,59.69 R24.2
  TOP w0.254: U14.AM53 119.72,41.63 v1(119.66,41.63)
  L5_SIG w0.097: v1(95.19,59.2) 96.72,57.67 96.72,56.18 96.98,55.93 99.93,55.93 101.67,54.19 101.67,54.07 103.64,52.1 104.55,52.1 105.16,52.7 108.69,52.7 110.06,51.33 110.06,49.37 112.22,47.22 112.22,46.37 115.87,42.72 119.38,42.72 119.67,42.44 119.67,41.64 v1(119.66,41.63)
LPC_LAD2: length 88.6
  TOP w0.099: v1(45.69,61.52) 45.69,61.29 45.97,61.01 46.62,61.01 46.95,61.34 49.45,61.34 50.29,60.5 51.32,60.5 54.92,56.9 54.92,54.78 55.72,53.98 65.7,53.98 71.48,59.75 90.4,59.75 93.08,57.07 93.08,56.24 95.7,53.62 97.04,53.62 97.33,53.33 97.33,52.2 97.72,51.81 98.09,51.81 99.82,50.07 99.82,48.12 100.55,47.4 R42.1
  TOP w0.102: v1(36.42,52.15) 36.34,52.15 U7.C10
  L5_SIG w0.097: v1(36.42,52.15) 36.42,52.17 36.86,52.6 36.86,58.3 37.19,58.63 40.04,58.63 41.02,59.61 43.54,59.61 43.81,59.89 43.81,60.25 45.09,61.52 v1(45.69,61.52)
LPC_LAD2_R: length 23.8
  TOP w0.099: R42.2 103.33,47.4 103.87,47.94 105.14,47.94 v1(105.21,48.01)
  TOP w0.254: U14.AL53 v1(119.67,40.22)
  L5_SIG w0.097: v1(105.21,48.01) 105.21,47.32 105.02,47.14 105.02,46.63 105.18,46.47 106.26,46.47 106.57,46.78 108.49,46.78 109.8,45.47 109.8,42.58 110.57,41.81 114.05,41.81 115.03,40.83 119.29,40.83 119.67,40.45 v1(119.67,40.22)
LPC_LAD3: length 64.1
  TOP w0.099: R33.1 94.41,52.55 92.67,54.29 92.46,54.5 91.62,55.34 91.41,55.55 91.41,55.98 91.41,56.38 89.71,58.09 72.34,58.09 72.07,57.81 66.55,52.3 53.14,52.3 52.86,52.58 46.98,52.58 46.38,51.97 46.38,49 45.72,48.34 43.64,48.34 43.51,48.46 42.65,48.46 42.38,48.73 42.38,50.06 U7.B4
LPC_LAD3_R: length 34.3
  TOP w0.099: R33.2 94.41,50.01 v1(93.32,48.92)
  TOP w0.254: U14.AG59 v1(117.76,38.23)
  L5_SIG w0.097: v1(93.32,48.92) 93.32,48.82 93.3,48.79 93.3,47.29 96.49,44.09 99.07,44.09 99.51,43.65 100.1,43.65 100.56,43.19 104.6,43.19 104.68,43.11 104.99,43.11 105.07,43.19 107.35,43.19 107.85,42.69 107.85,41.42 109.7,39.57 111.02,39.57 111.55,39.04 111.55,38.46 112.14,37.87 116.02,37.87 116.76,38.61 117.38,38.61 v1(117.76,38.23)
MARGIN_DN: length 77.1
  TOP w0.099: v1(38.28,51.08) 38.28,53.06 38.82,53.6 U7.E7
  L3_SIG w0.097: v1(74.55,21.16) 74.45,21.26 74.45,21.34 73.05,22.73 73.05,28.34 71.82,29.58 64.02,29.58 63.63,29.19 59.54,29.19 58.27,27.91 56.21,27.91 55.98,27.69 55.39,27.69 54.86,28.22 47.31,28.22 47.31,28.23 46.95,28.23 40.04,35.13 32.13,35.13 v1(31.83,35.43)
  L10_SIG w0.097: v1(31.83,35.43) 31.62,35.64 31.62,38.58 32.3,39.26 32.31,39.26 32.56,39.51 32.56,39.52 32.74,39.7 32.74,42.85 34.39,44.5 37.08,44.5 37.82,45.24 37.82,50.29 38.28,50.75 v1(38.28,51.08)
  BOTTOM w0.097: N54.1 74.65,21.16 v1(74.55,21.16)
MARGIN_UP: length 78.8
  TOP w0.099: U7.E6 39.31,54.14 v1(39.31,54.19)
  L3_SIG w0.097: v1(31.82,34.67) 40.02,34.67 46.81,27.87 54.71,27.87 55.25,27.34 56.13,27.34 56.35,27.56 58.51,27.56 59.62,28.67 60.96,28.67 61.17,28.47 61.45,28.18 66.56,28.18 67.6,29.23 71.67,29.23 72.7,28.2 72.7,22.35 73.71,21.34 v1(73.71,21.24)
  L10_SIG w0.097: v1(31.82,34.67) 31.83,34.67 32.16,34.67 32.56,35.08 32.56,37.71 32.92,38.06 32.92,39.38 33.4,39.86 33.4,42.77 34.77,44.15 37.47,44.15 38.33,45.01 38.33,46.56 38.76,46.99 38.76,53.52 39.31,54.07 v1(39.31,54.19)
  BOTTOM w0.097: v1(73.71,21.24) N53.1
MB_PCIE0_RX0_N: length 142.4
  TOP w0.107: U14.BE64 114.59,47.93 114.56,47.93 113.97,48.51 112.78,48.51 v1(112.34,48.95) ; v1(79.38,7.62) 79.71,7.28 79.71,6.12 79.37,5.78 S1.A18
  L8_SIG w0.114: v1(112.34,48.95) 112.05,48.65 110.81,48.65 108.58,46.43 103.94,46.43 102.17,48.2 99.98,48.2 95.35,52.83 64.08,52.83 46.04,34.79 46.04,16.36 48.06,14.34 76.14,14.34 76.81,13.67 76.81,13.36 76.98,13.19 77.29,13.19 79.62,10.86 79.62,9.9 79.74,9.77 79.74,7.89 79.72,7.87 79.72,7.84 79.5,7.62 v1(79.38,7.62)
MB_PCIE0_RX0_P: length 142.4
  TOP w0.107: U14.BE63 115.33,47.95 115.06,47.68 114.45,47.68 113.87,48.26 112.67,48.26 112.67,48.26 112.52,48.26 v1(112.42,48.16) ; S1.A17 80.37,5.74 79.97,6.14 79.97,7.19 v1(80.39,7.62)
  L8_SIG w0.114: v1(112.42,48.16) 112.19,48.39 110.92,48.39 108.7,46.16 103.83,46.16 102.06,47.93 99.87,47.93 95.24,52.57 64.19,52.57 46.3,34.68 46.3,16.47 48.17,14.61 76.25,14.61 79.88,10.97 79.88,10.01 80.01,9.88 80.01,8 v1(80.39,7.62)
MB_PCIE0_RX1_N: length 147.7
  TOP w0.107: v1(75.31,7.62) 75.39,7.62 75.77,7.24 75.77,6.15 75.37,5.75 S1.A22 ; U14.BH64 114.67,48.98 v1(114.39,48.7)
  L8_SIG w0.114: v1(114.39,48.7) 114.05,49.04 114.05,49.35 113.65,49.75 113.65,51.28 111.68,53.25 106.21,53.25 104.73,51.78 103.27,51.78 101.03,54.01 98.41,54.01 98.05,53.66 97.32,53.66 96.63,54.36 63.47,54.36 44.48,35.36 44.48,13.72 46.48,11.71 66.29,11.71 67.44,10.56 67.71,10.56 67.9,10.38 67.9,10.1 69.12,8.88 69.33,8.88 69.55,8.66 69.55,8.45 70,8 70,6.3 70.83,5.47 71.42,5.47 71.57,5.63 71.87,5.63 72.03,5.47 72.33,5.47 72.49,5.63 72.79,5.63 72.94,5.47 73.25,5.47 73.4,5.63 73.7,5.63 73.86,5.47 74.16,5.47 74.32,5.63 74.62,5.63 74.77,5.47 75.17,5.47 75.73,6.03 75.73,7.2 v1(75.31,7.62)
MB_PCIE0_RX1_P: length 147.7
  TOP w0.107: v1(76.33,7.62) 76.02,7.32 76.02,6.1 76.37,5.75 S1.A21 ; v1(114.41,49.62) 114.55,49.75 U14.BJ63
  L8_SIG w0.114: v1(114.41,49.62) 114.16,49.62 113.92,49.86 113.92,51.39 111.79,53.52 106.1,53.52 104.62,52.04 103.38,52.04 101.14,54.28 98.3,54.28 97.94,53.92 97.43,53.92 96.74,54.62 63.36,54.62 44.21,35.47 44.21,13.61 46.37,11.44 66.18,11.44 69.74,7.89 69.74,6.19 70.72,5.21 75.28,5.21 76,5.92 76,7.29 v1(76.33,7.62)
MB_PCIE0_RX2_N: length 137.5
  TOP w0.107: U14.BK62 115.06,50.95 113.59,50.95 112.29,52.25 111.82,52.25 v1(111.6,52.47) ; v1(71.5,7.62) 71.81,7.32 71.81,6.38 71.37,5.94 S1.A26
  L8_SIG w0.114: v1(71.5,7.62) 71.83,7.95 71.83,9 71.72,9.12 71.69,9.12 71.54,9.26 71.54,9.43 71.69,9.57 71.72,9.57 71.83,9.69 71.83,9.92 71.72,10.03 71.69,10.03 71.54,10.18 71.54,10.34 71.69,10.49 71.72,10.49 71.83,10.6 71.83,12.17 70.64,13.36 47.78,13.36 45.1,16.04 45.1,35.1 63.72,53.72 96.11,53.72 96.8,53.04 97.23,53.04 99.37,50.89 108.86,50.89 110.24,52.27 111.41,52.27 v1(111.6,52.47)
MB_PCIE0_RX2_P: length 137.6
  TOP w0.107: S1.A25 72.37,6.23 72.16,6.43 72.16,7.27 v1(72.52,7.62) ; U14.BJ62 115.49,50.14 113.13,50.14 112.75,50.52 112.75,51.43 112.19,51.99 111.91,51.99 v1(111.6,51.69)
  L8_SIG w0.114: v1(72.52,7.62) 72.1,8.04 72.1,10.6 72.1,10.6 72.1,12.28 70.75,13.63 47.89,13.63 45.36,16.15 45.36,34.99 63.83,53.45 96,53.45 96.69,52.77 97.12,52.77 99.26,50.62 108.97,50.62 110.35,52.01 111.36,52.01 111.53,51.83 111.53,51.75 v1(111.6,51.69)
MB_PCIE0_RX3_N: length 146.8
  TOP w0.102: v1(117.1,48.85) 117.15,48.85 117.58,49.28 U14.BH58
  TOP w0.107: S1.A30 67.37,5.96 67.82,6.41 67.82,7.24 v1(67.44,7.62)
  L8_SIG w0.114: v1(117.1,48.85) 117.1,48.65 116.62,48.18 116.2,48.18 115.95,48.44 115.95,49.5 114.82,50.64 114.82,53.35 113.7,54.47 107.72,54.47 106.31,55.88 96.47,55.88 96.1,55.51 62.99,55.51 43.32,35.84 40.34,32.85 40.34,12.83 43.21,9.96 64.56,9.96 65.46,9.05 66.59,9.05 67.53,8.11 67.53,7.72 v1(67.44,7.62)
MB_PCIE0_RX3_P: length 146.7
  TOP w0.104: U14.BG58 117.12,48.17 v1(117.12,48.04)
  TOP w0.107: S1.A29 68.37,5.83 68.07,6.12 68.07,7.24 v1(68.45,7.62)
  L8_SIG w0.114: v1(117.12,48.04) 117,47.92 116.09,47.92 115.68,48.33 115.68,49.39 114.55,50.53 114.55,53.24 113.59,54.2 107.6,54.2 106.2,55.61 96.58,55.61 96.21,55.24 63.1,55.24 43.59,35.73 43.59,35.73 40.6,32.74 40.6,12.94 43.32,10.22 44.21,10.22 44.3,10.31 44.74,10.31 44.83,10.22 45.13,10.22 45.21,10.31 45.65,10.31 45.74,10.22 46.14,10.22 46.25,10.34 46.59,10.34 46.71,10.22 47.05,10.22 47.16,10.34 47.51,10.34 47.62,10.22 64.67,10.22 65.58,9.32 66.7,9.32 66.9,9.12 67.19,9.12 67.36,8.95 67.36,8.66 68.4,7.62 v1(68.45,7.62)
MB_PCIE0_RX4_N: length 133.1
  TOP w0.104: v1(117.93,49.77) 118.28,49.42 U14.BH57
  TOP w0.107: S1.A66 31.4,3.75 31.43,3.78 31.43,6.34 31.71,6.62 31.71,7.14 32.8,8.23 v1(32.8,8.82)
  L8_SIG w0.114: v1(117.93,49.77) 116,51.69 116,57.45 114.99,58.47 112.95,58.47 110.78,60.64 105.3,60.64 103.14,58.48 101.46,58.48 99.35,60.59 95.45,60.59 92.42,57.57 88.84,57.57 87.67,56.4 62.62,56.4 39.42,33.2 39.42,14.92 33.33,8.83 v1(32.8,8.82)
MB_PCIE0_RX4_P: length 133.1
  TOP w0.104: v1(117.94,49.01) 118.28,48.68 U14.BG57
  TOP w0.107: S1.A65 32.31,3.81 32.31,6.34 31.97,6.68 31.97,7.04 33.04,8.11 v1(33.52,8.11)
  L8_SIG w0.114: v1(117.94,49.01) 117.47,49.48 117.47,49.84 115.74,51.58 115.74,57.34 114.88,58.2 112.84,58.2 110.67,60.38 105.41,60.38 103.25,58.22 101.35,58.22 99.24,60.33 95.56,60.33 92.53,57.3 88.95,57.3 87.78,56.13 62.73,56.13 39.69,33.09 39.69,14.8 33.52,8.64 33.52,8.64 33.49,8.6 33.49,8.14 v1(33.52,8.11)
MB_PCIE0_RX5_N: length 141.3
  TOP w0.104: U14.BF54 v1(118.98,48.25)
  TOP w0.107: v1(27.43,7.87) 27.78,7.53 27.78,6.69 27.43,6.34 27.43,6.33 27.37,6.27 S1.A70
  L8_SIG w0.114: v1(27.43,7.87) 27.77,8.21 27.77,9.35 29.1,10.68 33.41,10.68 37.97,15.23 37.97,32.27 37.97,32.27 37.97,33 61.73,56.77 61.73,56.77 62.25,57.29 83.68,57.29 84.85,58.46 92.06,58.46 95.47,61.87 114.68,61.87 118.63,57.92 118.63,48.34 118.74,48.23 118.96,48.23 v1(118.98,48.25)
MB_PCIE0_RX5_P: length 141.2
  TOP w0.104: U14.BD54 v1(119.04,47.49)
  TOP w0.107: v1(28.45,7.87) 28.03,7.46 28.03,6.66 28.37,6.32 S1.A69
  L8_SIG w0.114: v1(119.04,47.49) 119.04,47.56 118.36,48.23 118.36,57.81 114.57,61.61 95.58,61.61 92.17,58.19 84.96,58.19 83.79,57.02 62.37,57.02 62,56.66 38.23,32.89 38.23,32.38 38.23,15.12 33.52,10.41 29.21,10.41 28.04,9.24 28.04,8.16 28.32,7.87 v1(28.45,7.87)
MB_PCIE0_RX6_N: length 147
  TOP w0.104: U14.BG53 120.28,49.01 120.62,48.67 v1(120.78,48.67)
  TOP w0.107: S1.A74 23.37,6.23 23.75,6.61 23.75,7.62 v1(23.37,8)
  L8_SIG w0.114: v1(120.78,48.67) 120.54,48.91 120.54,51.42 120.17,51.79 120.17,57.86 115.22,62.8 95.14,62.8 91.73,59.39 83.34,59.39 82.13,58.18 61.89,58.18 60.85,57.14 37.03,33.32 37.03,15.62 33.03,11.62 27.62,11.62 25.79,9.79 24.4,9.79 23.74,9.13 23.74,8.37 v1(23.37,8)
MB_PCIE0_RX6_P: length 147
  TOP w0.104: U14.BF53 119.96,48.56 119.96,48.61 v1(119.92,48.64)
  TOP w0.107: v1(24.38,8) 24,7.62 24,6.59 24.37,6.23 S1.A73
  L8_SIG w0.114: v1(24.38,8) 24,8.38 24,9.02 24.51,9.53 25.9,9.53 26.14,9.76 26.3,9.76 26.38,9.67 26.54,9.67 26.7,9.84 26.7,10 26.62,10.08 26.62,10.24 26.78,10.4 26.94,10.4 27.03,10.32 27.19,10.32 27.35,10.48 27.35,10.64 27.27,10.73 27.27,10.89 27.73,11.35 33.14,11.35 37.29,15.5 37.29,33.21 61.11,57.03 61.11,57.03 62,57.91 82.25,57.91 83.45,59.12 91.84,59.12 95.25,62.53 115.11,62.53 119.9,57.75 119.9,51.68 120.27,51.31 120.27,48.92 119.99,48.64 v1(119.92,48.64)
MB_PCIE0_RX7_N: length 157.3
  TOP w0.107: U14.BG50 121.55,48.6 v1(121.89,48.26) ; S1.A78 19.37,6.31 19.7,6.64 19.7,7.61 v1(19.3,8)
  L8_SIG w0.114: v1(121.89,48.26) 121.78,48.37 121.78,50.38 121.63,50.53 121.63,55.64 122.36,56.38 122.36,59.52 120.38,61.51 119.97,61.51 118.46,63.02 116.59,63.02 115.55,64.05 103.81,64.05 103.29,64.58 101.26,64.58 100.42,63.74 94.82,63.74 91.38,60.3 82.2,60.3 80.97,59.07 61.52,59.07 36.14,33.69 36.14,16.71 33.19,13.75 21.68,13.75 19.69,11.76 19.69,8.39 v1(19.3,8)
MB_PCIE0_RX7_P: length 157.2
  TOP w0.107: v1(120.9,47.88) 120.91,47.87 U14.BE50 ; v1(20.32,8) 19.95,7.63 19.95,6.69 20.31,6.34 20.31,6.06 20.37,6 S1.A77
  L8_SIG w0.114: v1(120.9,47.88) 121.51,48.49 121.51,50.27 121.36,50.42 121.36,55.75 122.1,56.49 122.1,59.41 120.27,61.24 119.86,61.24 118.35,62.75 116.48,62.75 115.44,63.79 103.7,63.79 103.18,64.31 101.37,64.31 100.53,63.47 94.93,63.47 91.49,60.03 82.31,60.03 81.08,58.8 61.63,58.8 60.22,57.4 36.41,33.58 36.41,16.6 33.3,13.49 21.79,13.49 19.96,11.65 19.96,8.24 20.19,8 v1(20.32,8)
MEMHOT_V1P0_N: length 72.7
  TOP w0.254: v1(124.36,41.05) U14.AL46
  L3_SIG w0.097: v1(134.5,70.57) 134.52,70.55 134.52,69.85 133.04,68.38 131.22,68.38 128.57,65.74 v1(128.57,65.35)
  L5_SIG w0.097: v1(124.36,41.05) 124.33,41.05 123.95,41.42 123.95,41.86 123.65,42.16 123.16,42.16 122.78,42.55 122.78,43.66 120.82,45.63 120.82,46.45 120.3,46.97 118.84,46.97 118.17,47.63 116.18,47.63 115.85,47.97 115.85,51.61 113.18,54.28 107.39,54.28 104.93,56.74 v1(104.93,58.37) 104.93,59.89 106.68,61.65 120.12,61.65 121.84,63.37 124.38,63.37 125.22,64.21 125.22,64.9 125.68,65.35 127.33,65.35
  L5_SIG w0.099: 127.33,65.35 v1(128.57,65.35)
  BOTTOM w0.097: R184.1 104.46,57.85 104.93,58.32 v1(104.93,58.37)
  BOTTOM w0.099: v1(134.5,70.57) 135.99,70.57 136.45,70.1 U37.4
MEMHOT_V3P3_N: length 73.4
  TOP w0.099: v1(196.19,67.41) 195.53,66.75 P1.198
  TOP w0.152: v1(196.54,71.23) 196.82,70.94 196.82,67.82 196.41,67.41 v1(196.19,67.41)
  BOTTOM w0.097: v1(196.19,67.41) 196.84,66.75 P4.198 ; v1(196.54,71.23) 196.54,71.36 196.06,71.83 196.04,71.83 195.99,71.88 189.48,71.88 184.15,66.55 141.95,66.55 141.12,67.37 R148.1 140.21,66.01 139.67,65.48 137.67,65.48 137.41,65.74 U37.2
NCSI_ARB_OUT: length 1.7
  TOP w0.254: U14.Y59 116.99,35.67 v1(116.99,35.67)
  BOTTOM w0.097: TP14.1 115.89,35.67 v1(116.99,35.67)
PCIE0_MB_TX0_C_N: length 1.7
  TOP w0.102: v1(116.32,50.06) 116.36,50.1 U14.BL61
  BOTTOM w0.107: C253.1 115.64,50.75 v1(116.32,50.06)
PCIE0_MB_TX0_C_P: length 3.8
  TOP w0.102: v1(117.08,49.51) 117.08,49.96 117.08,49.96 U14.BK60
  BOTTOM w0.104: v1(117.08,49.51) 117.01,49.59 116.14,49.59
  BOTTOM w0.107: C254.1 115.91,49.59 116.14,49.59
PCIE0_MB_TX0_N: length 146.4
  L10_SIG w0.114: v1(81.28,10.67) 81.65,11.04 81.65,11.82 79.19,14.28 77.85,14.28 77.68,14.11 77.39,14.11 77.23,14.28 76.94,14.28 76.77,14.11 76.48,14.11 76.31,14.28 48.78,14.28 46.06,17.01 46.06,34.86 46.06,34.87 46.06,34.87 63.98,52.79 80.2,52.79 80.75,52.24 98.78,52.24 99.35,52.81 v1(99.35,53.27)
  BOTTOM w0.107: v1(99.35,53.27) 99.88,53.27 102.23,55.63 104.39,55.63 105.71,54.31 113.58,54.31 114.83,53.05 114.83,52.4 115.44,51.79 C253.2 ; S1.B16 81.43,3.81 81.43,6.34 81.76,6.67 81.76,7.9 81.53,8.13 81.15,8.13 80.9,8.38 C490.2 81.22,8.7 81.66,9.14 81.66,10.29 v1(81.28,10.67)
PCIE0_MB_TX0_P: length 144.3
  L10_SIG w0.114: v1(100.07,52.56) 100.06,52.57 99.48,52.57 98.89,51.98 80.64,51.98 80.09,52.53 64.09,52.53 46.33,34.76 46.33,34.76 46.32,34.75 46.32,17.12 48.89,14.55 79.3,14.55 81.92,11.93 81.92,11.04 v1(82.3,10.67)
  BOTTOM w0.107: v1(100.07,52.56) 100.07,52.99 100.07,53.1 102.34,55.37 104.29,55.37 105.61,54.05 113.47,54.05 114.58,52.94 114.58,51.81 C254.2 ; S1.B15 82.37,6.28 82.02,6.63 82.02,7.85 82.42,8.26 C489.2 82.11,8.7 81.92,8.89 81.92,10.29 v1(82.3,10.67)
PCIE0_MB_TX1_C_N: length 6.6
  TOP w0.107: U14.BM58 v1(117.56,50.75)
  BOTTOM w0.107: C235.1 117.79,55.21 117.94,55.06 118.55,55.06 118.9,54.7 118.9,53.34 117.58,52.02 117.58,50.76 v1(117.56,50.75)
PCIE0_MB_TX1_C_P: length 5.8
  TOP w0.107: v1(116.99,51.43) 117.03,51.39 U14.BL59
  BOTTOM w0.107: C240.1 117.81,54.65 117.95,54.81 118.44,54.81 118.65,54.6 118.65,53.45 117.32,52.12 117.32,51.76 v1(116.99,51.43)
PCIE0_MB_TX1_N: length 145
  L10_SIG w0.114: v1(77.09,10.67) 77.46,11.04 77.46,11.28 77.14,11.61 75.34,11.61 73.55,13.39 48.41,13.39 45.09,16.72 45.09,35.15 63.61,53.68 80.56,53.68 80.73,53.52 97.79,53.52 99.01,54.74 101.43,54.74 102.15,55.46 104.76,55.46 105.48,54.74 111.38,54.74 113.17,56.52 114.18,56.52 v1(114.55,56.9)
  BOTTOM w0.107: v1(114.55,56.9) 114.94,56.52 115.29,56.52 115.8,56.01 115.8,55.47 116.24,55.03 116.63,55.03 116.9,55.32 C235.2 ; S1.B20 77.37,6.23 77.55,6.41 77.55,7.8 77.34,8 76.99,8 76.83,8.15 C492.2 77.36,8.7 77.47,8.81 77.47,10.29 v1(77.09,10.67)
PCIE0_MB_TX1_P: length 145.8
  L10_SIG w0.114: v1(114.55,55.88) 114.18,56.25 113.28,56.25 111.49,54.47 105.37,54.47 104.65,55.19 102.26,55.19 101.54,54.47 99.12,54.47 97.9,53.25 80.62,53.25 80.45,53.42 63.72,53.42 45.35,35.04 45.35,16.83 48.52,13.66 73.66,13.66 73.9,13.42 74.06,13.42 74.11,13.48 74.28,13.48 74.44,13.32 74.44,13.16 74.38,13.1 74.38,12.94 74.54,12.78 74.71,12.78 74.76,12.83 74.92,12.83 75.08,12.67 75.08,12.51 75.03,12.45 75.03,12.29 75.45,11.87 75.97,11.87 76.08,11.99 76.08,12.08 76.19,12.19 76.42,12.19 76.54,12.08 76.54,11.99 76.65,11.87 77.25,11.87 77.73,11.39 77.73,11.04 v1(78.11,10.67)
  BOTTOM w0.107: S1.B19 78.37,6.21 78.2,6.38 77.91,6.38 77.8,6.49 77.8,7.82 77.98,8 78.23,8 78.36,8.13 C491.2 77.83,8.7 77.72,8.81 77.72,10.29 v1(78.11,10.67) ; C240.2 116.92,54.49 116.61,54.78 116.14,54.78 115.54,55.37 115.54,55.91 115.19,56.26 114.94,56.26 v1(114.55,55.88)
PCIE0_MB_TX2_C_N: length 19.9
  TOP w0.107: U14.BN57 118.14,51.69 118.15,51.7 118.15,51.78 118.34,51.96 118.34,52.81 117.63,53.52 114.71,53.52 114.29,53.93 106.8,53.93 105.08,55.65 102.23,55.65 101.98,55.4 101.56,55.4 C40.1
PCIE0_MB_TX2_C_P: length 20.4
  TOP w0.107: U14.BL57 118.17,51.17 117.83,51.51 117.83,51.82 117.86,51.84 117.86,51.84 118.08,52.07 118.08,52.7 117.53,53.26 114.6,53.26 114.19,53.68 106.69,53.68 104.97,55.4 102.34,55.4 102.08,55.14 101.56,55.14 C41.1
PCIE0_MB_TX2_N: length 141.4
  TOP w0.107: v1(94.4,56.96) 94.94,56.96 95.57,57.58 96.68,57.58 97.02,57.25 98.27,57.25 99.85,55.68 100.08,55.68 C40.2
  L10_SIG w0.114: v1(73.66,10.67) 74.03,11.04 74.03,11.44 73.93,11.54 72.63,11.54 72.15,11.07 72.15,10.05 71.49,9.39 71.49,9.26 71.17,8.94 71.04,8.94 70.87,8.77 70.49,8.77 70.31,8.58 70.04,8.58 69.85,8.77 69.58,8.77 69.39,8.58 69.12,8.58 68.93,8.77 68.66,8.77 68.48,8.58 68.21,8.58 68.02,8.77 67.75,8.77 67.56,8.58 67.29,8.58 67.11,8.77 66.11,8.77 64.6,10.28 64.42,10.28 64.25,10.11 63.97,10.11 63.79,10.28 63.51,10.28 63.34,10.11 63.05,10.11 62.88,10.28 56.71,10.28 56.13,9.7 41.86,9.7 39.42,12.15 39.42,33.26 62.59,56.43 82.46,56.43 82.55,56.34 93.79,56.34 v1(94.4,56.96)
  BOTTOM w0.107: v1(73.66,10.67) 73.91,10.41 73.91,8.81 73.81,8.7 C494.2 73.28,8.38 73.53,8.13 73.79,8.13 73.91,8 73.91,7.6 73.69,7.37 73.69,6.6 73.43,6.34 73.43,5.9 73.37,5.84 S1.B24
PCIE0_MB_TX2_P: length 140.9
  TOP w0.107: C41.2 99.94,55.01 99.75,55.01 99.42,55.34 99.42,55.74 98.17,57 96.91,57 96.58,57.33 95.67,57.33 95.11,56.77 v1(95.11,56.23)
  L10_SIG w0.114: v1(95.11,56.23) 94.95,56.07 82.44,56.07 82.35,56.16 62.7,56.16 39.69,33.15 39.69,12.26 41.97,9.97 56.02,9.97 56.6,10.55 64.71,10.55 66.22,9.04 70.76,9.04 71.88,10.16 71.88,11.18 72.52,11.81 74.04,11.81 74.3,11.55 74.3,11.04 v1(74.68,10.67)
  BOTTOM w0.107: S1.B23 74.37,5.78 74.31,5.84 74.31,6.34 73.94,6.7 73.94,7.27 74.17,7.49 74.17,8 74.3,8.13 74.55,8.13 74.8,8.38 C493.2 74.27,8.7 74.17,8.81 74.17,10.22 74.62,10.67 v1(74.68,10.67)
PCIE0_MB_TX3_C_N: length 19.1
  TOP w0.107: C29.1 103.81,58.23 104.29,57.76 104.57,57.76 107.51,54.82 114.42,54.82 114.96,54.28 118.01,54.28 118.82,53.47 118.82,51.94 U14.BN55
PCIE0_MB_TX3_C_P: length 19.2
  TOP w0.107: C37.1 103.96,57.51 104.47,57.51 107.4,54.57 114.31,54.57 114.85,54.03 117.91,54.03 118.57,53.37 118.57,51.83 118.62,51.78 118.62,51.4 U14.BL55
PCIE0_MB_TX3_N: length 134.4
  TOP w0.107: v1(99.61,57.84) 100.1,57.84 100.65,58.39 101.86,58.39 102.24,58.02 102.68,58.02 102.79,58.12 102.79,58.34 102.9,58.45 C29.2
  L10_SIG w0.114: v1(69.09,11.18) 69.46,11.54 69.46,11.83 69.26,12.02 56.32,12.02 54.89,10.59 42.63,10.59 40.36,12.86 40.36,32.94 62.88,55.46 81.3,55.46 81.47,55.3 95.83,55.3 96.58,56.05 96.58,56.66 97.18,57.25 99.17,57.25 99.61,57.69 v1(99.61,57.84)
  BOTTOM w0.107: v1(69.09,11.18) 69.49,10.77 69.49,8.89 69.3,8.7 C496.2 68.83,8.28 69.73,7.39 69.73,6.42 69.31,6 69.31,3.81 S1.B28
PCIE0_MB_TX3_P: length 134.4
  TOP w0.107: C37.2 102.79,57.44 102.79,57.66 102.68,57.76 102.13,57.76 101.76,58.14 100.75,58.14 100.31,57.7 100.31,57.14 v1(100.33,57.13)
  L10_SIG w0.114: v1(70.1,11.18) 69.98,11.18 69.72,11.43 69.72,11.94 69.37,12.29 56.21,12.29 54.78,10.86 42.74,10.86 40.63,12.97 40.63,32.83 62.99,55.19 81.19,55.19 81.36,55.03 95.94,55.03 96.85,55.94 96.85,56.55 97.29,56.99 100.19,56.99 v1(100.33,57.13)
  BOTTOM w0.107: v1(70.1,11.18) 69.75,10.82 69.75,8.89 69.94,8.7 C495.2 70.61,8.15 69.98,7.52 69.98,6.51 70.31,6.18 70.31,3.81 S1.B27
PCIE0_MB_TX4_C_N: length 4.8
  TOP w0.104: U14.BK54 119.64,49.82 119.86,49.61 v1(119.86,49.55)
  BOTTOM w0.107: v1(119.86,49.55) 120.14,49.84 120.14,53.23 C242.1
PCIE0_MB_TX4_C_P: length 4.2
  TOP w0.104: U14.BM54 119.67,50.79 v1(119.48,50.6)
  BOTTOM w0.107: v1(119.48,50.6) 119.78,50.6 119.89,50.71 119.89,53.08 C243.1
PCIE0_MB_TX4_N: length 131.8
  L10_SIG w0.114: v1(30.23,8.91) 30.76,8.91 37.97,16.12 37.97,33.06 62.46,57.56 92.73,57.56 93.22,58.05 93.61,58.05 94.15,58.59 95.68,58.59 95.96,58.3 96.95,58.3 97.58,58.92 97.58,59.38 v1(97.57,59.39)
  BOTTOM w0.107: v1(30.23,8.91) 30.23,8.43 29.74,7.93 29.74,6.68 29.72,6.66 29.72,6.63 29.43,6.34 29.43,6.15 29.37,6.09 S1.B68 ; C242.2 120.07,54.81 120.07,56.11 114.51,61.67 100.33,61.67 98.04,59.39 v1(97.57,59.39)
PCIE0_MB_TX4_P: length 132.5
  L10_SIG w0.114: v1(98.29,58.65) 98.25,58.7 97.75,58.7 97.74,58.69 97.73,58.69 97.72,58.7 97.06,58.03 95.85,58.03 95.57,58.32 94.26,58.32 93.72,57.78 93.33,57.78 92.84,57.29 62.57,57.29 38.23,32.95 38.23,16.01 37.31,15.09 37.31,14.84 37.08,14.61 36.84,14.61 36.63,14.41 36.63,14.33 36.63,14.17 36.43,13.96 36.19,13.96 35.99,13.76 35.99,13.68 35.99,13.52 35.79,13.32 35.54,13.32 35.34,13.11 35.34,13.03 35.34,12.87 35.14,12.67 34.9,12.67 34.31,12.08 34.31,12.04 34.31,11.88 34.08,11.66 33.88,11.66 33.66,11.43 33.66,11.23 33.44,11.01 33.24,11.01 33.01,10.79 33.01,10.58 32.79,10.36 32.59,10.36 32.37,10.14 32.37,9.94 32.14,9.71 31.94,9.71 30.77,8.54 30.77,8.38 v1(30.96,8.2)
  BOTTOM w0.107: S1.B67 30.37,6.28 30.09,6.55 30.09,6.56 29.99,6.66 29.99,7.83 30.55,8.38 30.77,8.38 v1(30.96,8.2) ; v1(98.29,58.65) 98.29,59.28 100.43,61.42 114.4,61.42 119.81,56.01 119.81,54.81 C243.2
PCIE0_MB_TX5_C_N: length 8.7
  TOP w0.107: C33.1 116.26,56.55 116.26,56.06 117.15,55.16 118.28,55.16 119.71,53.73 119.71,51.77 120.18,51.31 U14.BL53
PCIE0_MB_TX5_C_P: length 7.5
  TOP w0.107: U14.BN53 119.96,51.99 119.96,53.84 118.38,55.42 117.26,55.42 116.51,56.16 116.51,56.65 C35.1
PCIE0_MB_TX5_N: length 137.4
  TOP w0.107: v1(114.55,60.07) 114.17,60.45 114.17,60.71 114.45,60.99 115.26,60.99 116.21,60.04 116.21,58.66 116.21,58.51 115.77,58.08 C33.2
  L10_SIG w0.114: v1(42.32,13.65) 42.83,13.65 44.07,14.89 44.07,35.4 63.25,54.57 80.93,54.57 81.1,54.41 96.19,54.41 97.97,56.18 101.76,56.18 103.62,58.05 103.62,60.31 106.21,62.9 112.48,62.9 114.18,61.2 114.18,60.45 v1(114.55,60.07)
  BOTTOM w0.107: S1.B72 25.37,6.3 25.67,6.6 25.67,8.52 28.27,11.13 40.31,11.13 42.35,13.16 42.35,13.63 v1(42.32,13.65)
PCIE0_MB_TX5_P: length 138.5
  TOP w0.107: v1(113.54,60.07) 113.92,60.45 113.92,60.81 114.35,61.24 115.37,61.24 116.46,60.14 116.46,58.66 116.46,58.35 C35.2
  L10_SIG w0.114: v1(113.54,60.07) 113.91,60.45 113.91,61.09 112.37,62.64 106.32,62.64 103.89,60.2 103.89,57.94 101.87,55.92 98.08,55.92 96.3,54.14 80.99,54.14 80.82,54.31 63.36,54.31 44.34,35.28 44.34,14.78 43.04,13.48 v1(43.04,12.93)
  BOTTOM w0.107: v1(43.04,12.93) 42.48,12.93 40.42,10.87 39.45,10.87 39.35,10.76 39.35,10.76 39.24,10.65 39.03,10.65 38.92,10.76 38.92,10.76 38.81,10.87 38.6,10.87 38.49,10.76 38.49,10.76 38.39,10.65 38.17,10.65 38.07,10.76 38.07,10.76 37.96,10.87 37.75,10.87 37.64,10.76 37.64,10.76 37.53,10.65 37.32,10.65 37.21,10.76 37.21,10.76 37.11,10.87 36.89,10.87 36.79,10.76 36.79,10.76 36.68,10.65 36.47,10.65 36.36,10.76 36.36,10.76 36.25,10.87 36.04,10.87 35.93,10.76 35.93,10.76 35.83,10.65 35.61,10.65 35.51,10.76 35.51,10.76 35.4,10.87 35.19,10.87 35.08,10.76 35.08,10.76 34.97,10.65 34.76,10.65 34.65,10.76 34.65,10.76 34.55,10.87 28.38,10.87 25.92,8.42 25.92,6.72 26.31,6.34 26.31,6.09 26.37,6.03 S1.B71
PCIE0_MB_TX6_C_N: length 7
  TOP w0.102: U14.BM52 120.81,51.46 120.81,51.87 120.42,52.25 120.42,52.46 120.44,52.49 120.44,52.57 120.45,52.57 120.45,52.68
  TOP w0.107: C34.1 118.8,57.03 118.69,56.92 118.69,56.26 120.45,54.51 120.45,52.68
PCIE0_MB_TX6_C_P: length 7.7
  TOP w0.102: U14.BL52 120.86,50.98 120.6,51.23 120.6,51.78 120.22,52.17 120.22,52.64 120.19,52.67 120.19,52.68
  TOP w0.107: 120.19,52.68 120.19,54.4 118.44,56.16 118.44,56.81 118.35,56.9 118.15,56.9 C36.1
PCIE0_MB_TX6_N: length 137.2
  TOP w0.107: v1(101.51,60.64) 102.11,60.64 103.72,62.26 115.85,62.26 118.69,59.41 118.69,59.11 118.8,59 118.87,59 118.98,58.89 118.98,58.68 118.87,58.57 118.8,58.57 118.69,58.47 118.69,58.04 118.81,57.92 C34.2
  L10_SIG w0.114: v1(101.51,60.64) 101.51,60.12 101.01,59.62 100.3,59.62 99.26,60.66 94.57,60.66 92.36,58.45 62.09,58.45 37,33.36 37,19.61 34.6,17.21 v1(34.07,17.2)
  BOTTOM w0.107: S1.B76 21.37,6.28 21.62,6.53 21.74,6.65 21.74,8.89 22.63,9.78 25.29,9.78 27.66,12.14 29.44,12.14 34.07,16.77 v1(34.07,17.2)
PCIE0_MB_TX6_P: length 136.5
  TOP w0.107: C36.2 118.44,58.3 118.44,59.31 115.74,62 103.83,62 102.22,60.39 102.22,59.93 v1(102.23,59.92)
  L10_SIG w0.114: v1(34.79,16.49) 34.79,17.02 37.27,19.5 37.27,33.25 62.2,58.18 92.47,58.18 94.68,60.39 99.15,60.39 100.19,59.35 101.12,59.35 101.68,59.92 v1(102.23,59.92)
  BOTTOM w0.107: S1.B75 22.37,6.32 21.99,6.7 21.99,8.79 22.73,9.53 25.4,9.53 27.76,11.89 29.54,11.89 30.05,12.4 30.23,12.4 30.44,12.61 30.44,12.79 30.65,13 30.84,13 31.05,13.21 31.05,13.39 31.26,13.6 31.44,13.6 31.65,13.81 31.65,14 31.86,14.21 32.04,14.21 32.25,14.42 32.25,14.6 32.46,14.81 32.65,14.81 32.86,15.02 32.86,15.2 33.07,15.41 33.25,15.41 33.46,15.62 33.46,15.81 34.14,16.49 v1(34.79,16.49)
PCIE0_MB_TX7_C_N: length 6.9
  TOP w0.107: U14.BL50 121.53,51.23 121.89,51.59 121.89,54.98 121.01,55.85 121.01,56.67 C32.1
PCIE0_MB_TX7_C_P: length 5.8
  TOP w0.107: U14.BN50 121.58,54.92 120.75,55.75 120.75,56.64 C31.1
PCIE0_MB_TX7_N: length 143.6
  TOP w0.107: C32.2 120.98,58.37 120.98,58.67 121.24,58.93 v1(121.28,58.93)
  L10_SIG w0.114: v1(121.28,58.93) 120.9,59.31 120.9,60.04 119.95,61 116.47,61 113.81,63.65 105.52,63.65 103.98,62.12 94.77,62.12 91.99,59.33 61.72,59.33 36.11,33.72 36.11,33.04 36.11,21.66 32.13,17.68 32.11,17.68 v1(31.51,17.68)
  BOTTOM w0.107: v1(31.51,17.68) 31.51,17.14 31.5,17.14 31.5,17.12 28.18,13.79 20.93,13.79 17.73,10.6 17.73,7.41 17.73,7.4 17.73,6.7 17.37,6.34 S1.B80
PCIE0_MB_TX7_P: length 144.7
  TOP w0.107: C31.2 120.72,58.34 120.72,58.61 120.4,58.93 v1(120.27,58.93)
  L10_SIG w0.114: v1(120.27,58.93) 120.64,59.3 120.64,59.93 119.84,60.73 116.36,60.73 113.7,63.39 105.63,63.39 104.09,61.85 94.88,61.85 92.1,59.07 61.83,59.07 36.38,33.61 36.38,33.15 36.38,21.55 35.65,20.82 35.65,20.66 35.66,20.64 35.66,20.48 35.5,20.32 35.34,20.32 35.32,20.33 35.16,20.33 35,20.17 35,20.01 35.02,20 35.02,19.83 34.85,19.67 34.69,19.67 34.68,19.69 34.52,19.69 34.35,19.53 34.35,19.36 34.37,19.35 34.37,19.19 34.21,19.03 34.05,19.03 34.03,19.04 33.87,19.04 33.71,18.88 33.71,18.72 33.72,18.7 33.72,18.54 33.56,18.38 33.4,18.38 33.38,18.39 33.22,18.39 32.23,17.4 v1(32.23,16.96)
  BOTTOM w0.107: v1(32.23,16.96) 31.7,16.96 31.02,16.28 31.02,16.12 31.05,16.09 31.05,15.94 30.9,15.79 30.75,15.79 30.72,15.82 30.57,15.82 30.41,15.67 30.41,15.52 30.44,15.49 30.44,15.34 30.29,15.19 30.14,15.19 30.11,15.22 29.96,15.22 29.81,15.07 29.81,14.92 29.84,14.89 29.84,14.74 29.69,14.59 29.54,14.59 29.51,14.62 29.36,14.62 29.21,14.46 29.21,14.31 29.24,14.28 29.24,14.13 29.09,13.98 28.94,13.98 28.91,14.01 28.75,14.01 28.28,13.54 21.03,13.54 17.98,10.49 17.98,7.3 17.98,7.3 17.98,6.62 18.31,6.29 18.31,3.81 S1.B79
PHSFLT_VCCP: length 3.2
  TOP w0.099: 59.86,42.91 R54.2
  TOP w0.102: 59.86,42.91 60.77,43.83 U12.18
PHY_MDIO0_I2C_CLK: length 26.7
  TOP w0.099: R112.2 110.49,26.23 110.49,26.8 v1(110.46,26.82)
  TOP w0.254: U14.W56 v1(119.29,34.26)
  L5_SIG w0.097: v1(119.29,34.26) 118.74,34.26 118.54,34.06 118.54,33.3 117.93,32.69 115.23,32.69 114.79,32.25 114.79,31.11 115.09,30.81 115.87,30.81 116.45,31.39 119.08,31.39 119.89,30.58 119.89,29.36 118.87,28.35 117.14,28.35 116.61,27.81 114.89,27.81 114.1,27.03 112.85,27.03 112.37,26.54 110.74,26.54 v1(110.46,26.82)
PHY_MDIO0_I2C_DATA: length 13.8
  TOP w0.254: U14.W59 117.74,34.28 v1(117.74,34.21)
  L5_SIG w0.097: v1(108.2,29.77) 108.51,30.07 111.12,30.07 112.37,31.32 113.36,31.32 115.09,33.05 117.43,33.05 117.74,33.37 v1(117.74,34.21)
  BOTTOM w0.097: v1(108.2,29.77) 107.95,29.77 107.37,29.18 R289.2
PHY_MDIO1_I2C_CLK: length 43.5
  TOP w0.099: S1.A9 90.4,7.49 v1(90.67,7.76)
  BOTTOM w0.097: v1(90.67,7.76) 90.67,7.81 91.03,8.17 91.03,9.29 91.7,9.96 97.32,9.96 98.24,10.88 98.24,12.29 99.11,13.16 104.6,13.16 104.78,13.34 104.78,14.15 105.87,15.24 106.32,15.24 107.21,16.13 107.21,18.01 106.3,18.92 106.3,20.5 104.32,22.48 103.25,22.48 103,22.73 103,25.53 103.76,26.29 104.65,26.29 105.03,26.67 105.03,27.81 104.52,28.32 R281.2
PHY_MDIO1_I2C_CLK_MUX: length 18.8
  TOP w0.254: U14.Y54 119.25,35.7 v1(119.24,35.7)
  L3_SIG w0.097: v1(119.24,35.7) 119.24,35.62 118.87,35.26 113.79,35.26 ; v1(104.04,31.5) 104.51,31.97 107.8,31.97 108.11,32.28 109.36,32.28 110.62,33.53
  L3_SIG w0.102: 113.79,35.26 112.06,33.53 110.62,33.53
  BOTTOM w0.097: v1(104.04,31.5) 104.04,31.09 104.52,30.61 R281.1
PHY_MDIO1_I2C_DATA: length 71.1
  TOP w0.099: S1.A10 89.42,7.22 89.58,7.39 89.58,7.95 86.16,11.38 86.16,13.64 84.81,14.99 84.81,18.95 v1(84.05,19.71)
  TOP w0.254: v1(120.79,35.67) 120.79,35.67 U14.Y53
  L3_SIG w0.102: v1(120.79,35.67) 120.79,36.36 120.31,36.84 114.77,36.84 112.06,34.14 109.6,34.14 109.19,33.73 108.65,33.73 v1(108.46,33.54)
  L8_SIG w0.097: v1(108.46,33.54) 104.71,33.54 104.22,33.05 100.74,33.05 100.05,33.73 95.17,33.73 93.62,35.28 89.84,35.28 88.72,34.16 88.72,32.49 84.1,27.86 v1(84.1,27.57)
  L10_SIG w0.097: v1(84.05,19.71) 84.05,20.32 84.06,20.33 84.06,27.53 v1(84.1,27.57)
PLTRST_N: length 169.6
  TOP w0.099: R84.2 105.77,34.2 105.84,34.26 v1(105.84,34.37)
  TOP w0.102: v1(110.97,38.35) 111.35,38.35 112.04,37.67 113.41,37.67 113.56,37.82 114.34,37.82 114.59,38.07 114.91,38.07 115.25,37.73 U14.AE62 ; U7.K5 v1(41.32,59.12)
  L3_SIG w0.097: v1(26.9,17.86) 26.95,17.91 28.19,17.91 36,10.11 65.07,10.11 65.16,10.02 65.55,10.02 66.78,8.79 81.94,8.79 84.2,11.05 88.14,11.05 88.39,11.3 v1(88.39,11.68)
  L5_SIG w0.097: v1(105.84,34.37) 106.12,34.65 106.12,35.26 106.83,35.97 107.39,35.97 109.78,38.35 v1(110.97,38.35)
  L10_SIG w0.097: v1(105.84,34.37) 105.84,34.34 105.74,34.24 105.67,34.24 104.68,33.24 104.68,30.62 103.63,29.57 103.63,26.19 102.87,25.43 102.87,15.62 102.54,15.29 99.52,15.29 98.76,16.05 91.03,16.05 88.77,13.79 88.77,13.34 88.39,12.95 v1(88.39,11.68) ; v1(41.32,59.12) 41.24,59.12 40.82,58.7 40.82,49.02 39.86,48.07 39.86,45.22 38.43,43.79 35.79,43.79 34.72,42.72 34.72,38.94 32.94,37.16 32.94,34.92 31.01,32.99 27.46,32.99 26.82,32.36 26.82,17.98 26.9,17.9 v1(26.9,17.86)
PLTRST_PCIE1_N: length 91.9
  TOP w0.099: U7.T15 30.33,64.14 v1(28.83,64.14)
  L3_SIG w0.097: v1(58.37,7.29) 58.37,6.75 57.71,6.1 38.2,6.1 37.97,6.32 37.97,7.37 28.71,16.62 v1(28.69,16.62)
  L8_SIG w0.097: v1(28.69,16.62) 28.69,18.55 27.15,20.09 27.15,32.64 27.43,32.92 27.43,35.71 27.98,36.26 27.98,38.55 28.83,39.4 28.83,47.5 29.84,48.51 29.84,51.68 28.74,52.78 28.74,64.05 v1(28.83,64.14)
  BOTTOM w0.097: v1(28.83,64.14) 28.64,63.94 R168.2 ; S1.B39 v1(58.37,7.29)
PLTRST_PCIE2_N: length 128.5
  TOP w0.099: v1(45.59,65.41) 45.47,65.53 44.58,65.53 43.82,64.77 43.82,64.63 U7.T2 ; v1(85.34,13.59) 85.78,13.16 85.78,11.25 88.4,8.63 S1.A11
  L3_SIG w0.097: v1(34.16,21.34) 34.67,21.34 37.34,18.67 37.34,16.38 42.47,11.25 53.85,11.25 54.52,11.92 67.85,11.92 68.26,12.33 81.16,12.33 82.42,13.59 v1(85.34,13.59)
  L8_SIG w0.097: v1(45.59,65.41) 39.14,65.41 37.23,63.5 37.18,63.5 36.96,63.28 36.96,63.23 35.79,62.06 35.79,53.83 35,53.04 35,49.03 34.93,48.95 34.93,48.64 35,48.56 35,45.64 36.09,44.55 36.09,39.52 33.59,37.02 33.27,37.02 32.64,36.39 32.64,34.71 31.91,33.98 31.91,32.74 32,32.64 32.71,31.93 32.71,21.52 33.15,21.08 33.91,21.08 v1(34.16,21.34)
  BOTTOM w0.097: v1(45.59,65.41) 45.21,65.02 R162.2
PM_DDR_VTT_PWRGD: length 111.5
  TOP w0.102: v1(39.26,49.1) 39.29,49.1 U7.A6
  L3_SIG w0.097: v1(123.57,64.01) 122.22,62.66 117.78,62.66 117.32,62.2 91.59,62.2 90.57,63.22 89.38,63.22 88.62,63.98 81.36,63.98 80.19,62.81 80.19,61.44 79.75,61 79.61,61 v1(79.6,61.01)
  L8_SIG w0.097: v1(79.6,61.01) 78.92,60.33 56.21,60.33 55.35,61.19 50.55,61.19 46.96,64.77 39.73,64.77 38.79,63.83 38.79,49.66 39.26,49.19 v1(39.26,49.1)
  BOTTOM w0.097: R146.2 123.82,65.17 123.57,64.92 v1(123.57,64.01)
  BOTTOM w0.203: R146.2 123.87,67.45 U38.9
PM_V1P0_EN: length 135.1
  TOP w0.102: U7.E3 v1(42.28,53.08)
  TOP w0.127: N19.1 107.06,8.94 106.84,8.71 106.83,8.71 v1(106.81,8.69)
  L5_SIG w0.097: v1(34.87,29.46) 35.46,28.88 35.46,25.15 36.86,23.75 36.86,10.13 v1(37.72,9.27)
  L8_SIG w0.097: v1(42.28,53.08) 42.32,53.08 42.77,52.63 43.15,52.63 43.84,51.94 43.84,48.41 42.57,47.15 42.57,45.6 40.16,43.18 40.16,38.89 36.12,34.85 35.7,34.85 34.44,33.59 34.44,29.9 v1(34.87,29.46)
  L10_SIG w0.097: v1(37.72,9.27) 38.89,8.1 38.89,5.26 40.34,3.81 82.65,3.81 84.18,5.33 84.18,8.92 84.89,9.63 96.17,9.63 99.74,13.2 105.57,13.2 106.12,12.65 106.12,11.86 107.13,10.85 107.13,9.04 106.93,8.84 106.93,8.81 106.84,8.71 106.83,8.71 v1(106.81,8.69)
PM_V1P0_PWRGD: length 168.5
  TOP w0.102: U7.A5 v1(41.27,49.18)
  TOP w0.127: U31.7 111.37,6.47 110.64,5.74 v1(110.27,5.74)
  L8_SIG w0.097: v1(23.24,14.66) 20.47,14.66 17.96,12.14 17.96,5.92 19.34,4.53 82.16,4.53 83.64,6.02 83.64,8.71 84.24,9.31 89.49,9.31 v1(90.35,8.46)
  L10_SIG w0.097: v1(23.24,14.66) 26.87,14.66 27.38,15.17 27.38,17.56 27.46,17.63 27.46,18.41 27.23,18.64 27.23,32.27 27.6,32.64 31.16,32.64 31.18,32.66 31.19,32.66 33.93,35.41 33.93,37.62 35.66,39.34 35.66,42.67 36.37,43.38 38.58,43.38 40.28,45.08 40.28,47.83 41.27,48.81 v1(41.27,49.18) ; v1(90.35,8.46) 91.17,9.28 96.31,9.28 96.33,9.3 96.42,9.3 99.97,12.85 104.19,12.85 105.26,11.79 105.33,11.79 106.76,10.36 106.76,9.42 106.22,8.89 106.22,7.52 108,5.74 v1(110.27,5.74)
  BOTTOM w0.203: v1(110.27,5.74) 110.25,5.71 110.14,5.71 109.94,5.51 109.94,5.14 R354.2
  BOTTOM w0.254: R354.2 R356.2
PM_V1P1_EN: length 83.3
  TOP w0.099: U25.7 72.66,18.91 R123.2 73.32,18.63 73.79,19.1 v1(74.12,19.1)
  TOP w0.102: U7.E9 v1(37.36,54.17)
  L3_SIG w0.097: v1(30.42,36.61) 30.42,35.19 31.58,34.03 40.05,34.03 46.56,27.52 54.57,27.52 55.1,26.99 56.27,26.99 56.5,27.21 58.66,27.21 59.77,28.32 60.82,28.32 61.1,28.04 61.31,27.83 66.71,27.83 67.75,28.87 71.53,28.87 72.31,28.09 72.31,20.9 v1(74.12,19.1)
  L10_SIG w0.097: v1(30.42,36.61) 30.23,36.8 30.23,42.16 34.67,46.61 35.13,46.61 35.84,47.32 35.84,51.28 36.2,51.64 36.65,51.64 36.88,51.87 36.88,53.67 37.36,54.15 v1(37.36,54.17)
PM_V1P1_PWRGD: length 87.7
  TOP w0.099: R122.2 71.89,18.73 v1(71.89,19.36) U25.6
  TOP w0.102: U7.L4 v1(41.32,60.13)
  L3_SIG w0.097: v1(30.78,37.31) 30.33,37.31 29.82,36.8 29.82,35.26 31.58,33.49 31.81,33.49 32.89,32.41 41.07,32.41 46.3,27.17 52.68,27.17 53.64,26.21 59.89,26.21 61.16,27.48 70.41,27.48 71.89,26 v1(71.89,19.36)
  L10_SIG w0.097: v1(41.32,60.13) 41.32,60.04 40.87,59.59 39.93,59.59 38.79,58.45 38.79,54.01 38.4,53.62 38.4,52.04 37.87,51.51 37.87,50.95 37.54,50.62 36.93,50.62 36.78,50.47 36.78,47.65 35.33,46.2 34.77,46.2 30.66,42.09 30.66,37.49 30.78,37.36 v1(30.78,37.31)
PM_V1P5_EN: length 86.7
  TOP w0.099: U28.5 79.09,19.02 77.73,19.02 R121.1 77.6,19.46 77.36,19.71 76.44,19.71 v1(75.92,20.23)
  TOP w0.102: v1(42.28,60.17) 42.37,60.17 U7.M3
  L3_SIG w0.097: v1(75.92,20.23) 75.92,20.57 73.4,23.09 73.4,28.49 71.96,29.93 63.84,29.93 63.72,30.05 61.61,30.05 61.34,29.77 61.24,29.77 61.23,29.77 59.19,29.77 58.59,29.16 56.26,29.16 55.88,28.79 55.68,28.58 47.09,28.58 40.19,35.48 35.05,35.48 34.8,35.74 34.8,37.19 v1(34.95,37.34)
  L10_SIG w0.097: v1(42.28,60.17) 41.78,59.68 41.78,55.91 42.82,54.86 42.82,49.89 42.09,49.15 42.09,47.84 41.61,47.36 41.61,44.53 39.62,42.55 37.16,42.55 36.39,41.78 36.39,39.07 34.95,37.63 v1(34.95,37.34)
PM_V1P5_PWRGD: length 85.6
  TOP w0.099: U28.3 80.15,19.12 R118.2 80.15,20.93 v1(79.86,21.23)
  TOP w0.102: U7.J1 44.83,57.64 44.98,57.64 v1(45.44,57.18)
  L3_SIG w0.097: v1(79.86,21.23) 79.2,20.57 76.43,20.57 73.75,23.25 73.75,28.27 73.75,28.63 72.08,30.3 63.96,30.3 63.86,30.4 61.47,30.4 61.19,30.12 61.09,30.12 61.09,30.12 59.05,30.12 58.44,29.51 56.11,29.51 55.53,28.93 47.24,28.93 39.34,36.83 v1(36.02,36.83)
  L10_SIG w0.097: v1(36.02,36.83) 36.09,36.75 37.47,36.75 38.61,37.9 38.61,39.42 39.65,40.46 41.91,40.46 43.18,41.73 43.18,43.69 44.34,44.85 44.34,45.61 46.41,47.68 46.41,54.67 45.44,55.63 v1(45.44,57.18)
PM_V1P8_EN: length 138.8
  TOP w0.102: U7.F4 v1(42.32,54.12)
  TOP w0.203: U30.5 122.78,11.81 123.32,11.81 123.52,12.01 v1(123.52,12.06)
  L3_SIG w0.254: v1(123.52,12.06) 120.52,12.06 119.66,12.93 116.41,12.93 115.77,13.57 99.88,13.57 97.05,10.74 93.01,10.74 92.08,11.68 92.08,13.71 91.77,14.02 91.77,14.04 91.07,14.73 69.11,14.73 67.24,12.86 54.42,12.86 52.82,14.45 47.42,14.45 46.25,15.62 41.02,15.62 40.13,16.51 40.13,19.05 35.94,23.24 v1(34.8,23.24)
  L10_SIG w0.097: v1(42.32,54.12) 42.14,54.12 41.71,53.7 41.71,48.85 40.7,47.84 40.7,44.28 39.32,42.9 36.68,42.9 36.04,42.27 36.04,39.22 34.28,37.46 34.28,35.26 34.06,35.04 34.06,28.85 34.92,27.99 34.92,23.37 v1(34.8,23.24)
  BOTTOM w0.508: v1(123.52,12.06) 123.24,11.79 R341.1
PM_V1P8_PWRGD: length 147.7
  TOP w0.102: U7.L2 v1(44.32,60.12)
  TOP w0.254: v1(120.93,10.82) 121.55,10.82 121.78,11.05 U30.3
  L3_SIG w0.254: v1(120.93,10.82) 119.33,12.42 116,12.42 115.42,13 100.3,13 97.28,9.98 92.68,9.98 91.44,11.23 91.44,12.34 91.19,12.6 89.97,12.6 88.34,14.22 69.34,14.22 67.56,12.44 67.54,12.44 67.45,12.35 54.13,12.35 53.46,11.68 45.85,11.68 42.8,14.73 40.13,14.73 38.61,16.26 38.61,18.53 34.92,22.23 v1(34.67,22.23)
  L10_SIG w0.097: v1(44.32,60.12) 44.91,59.54 44.91,54.21 45.1,54.02 45.1,54 45.32,53.77 45.34,53.77 46.02,53.09 46.02,48.98 43.99,46.95 43.99,45 42.83,43.83 42.83,41.88 41.79,40.84 39.36,40.84 38.25,39.73 38.25,38.18 37.46,37.39 35.79,37.39 34.64,36.24 34.64,35.12 34.42,34.9 34.42,29.06 35.36,28.12 35.36,22.45 35.13,22.23 v1(34.67,22.23)
  BOTTOM w0.508: R343.2 121.34,10.41 v1(120.93,10.82)
PM_V1P35_EN: length 113.7
  TOP w0.102: U7.H2 43.32,57.12 v1(43.27,57.12)
  TOP w0.203: U26.5 122.71,20.12 123.29,20.7 123.29,20.73 v1(123.34,20.78) 122.71,21.41 R116.1
  L5_SIG w0.097: v1(50.67,51.36) 51.31,51.36 51.84,50.83 54.22,50.83 56.17,52.77 81.09,52.77 83,50.87 83,36.71 84.14,35.57 92.45,35.57 93.95,34.06 94.72,34.06 95.31,33.47 95.31,30.67 98.36,27.62 101.92,27.62 103.3,26.24 107.57,26.24 108.07,25.74 109.97,25.74 110.07,25.84 111.86,25.84 v1(113.84,23.85)
  L8_SIG w0.097: v1(123.34,20.78) 123.26,20.86 120.62,20.86 119.46,22.02 116.13,22.02 114.3,23.85 v1(113.84,23.85) ; v1(43.27,57.12) 43.23,57.12 42.8,56.7 42.01,56.7 41.8,56.49 41.8,55.66 42.72,54.74 43.48,54.74 43.79,54.42 43.79,53.82 43.91,53.7 44.34,53.7 45.18,52.86 45.46,52.86 46.89,51.44 50.6,51.44 v1(50.67,51.36)
PM_V1P35_PWRGD: length 124.1
  TOP w0.127: U26.3 123.59,19 v1(123.75,18.85)
  TOP w0.254: v1(46.13,62.43) 45.63,62.43 U7.N1
  L5_SIG w0.157: v1(113.05,23.86) 111.91,24.99 108.23,24.99 107.34,25.88 103.15,25.88 101.79,27.24 96.71,27.24 93.73,30.23 93.73,32.1 93.88,32.25 93.88,33.58 92.27,35.19 82.62,35.19 81.48,36.32 81.48,49.66 81,50.14 72.16,50.14 71.61,50.7 55.09,50.7 54.84,50.44 51.44,50.44 v1(51.26,50.62)
  L8_SIG w0.152: 123.59,19 122.18,20.41 120.3,20.41 119.15,21.56
  L8_SIG w0.157: v1(113.05,23.86) 113.62,23.29 114.19,23.29 115.91,21.56 119.15,21.56 ; 123.59,19 v1(123.75,18.85)
  L8_SIG w0.191: v1(51.26,50.62) 51.26,50.62 51.26,50.83 51.36,50.93 51.36,51.99 52.21,52.84 52.21,52.84 53.05,53.68 53.05,53.69 54.48,55.12 54.48,59.11 53.2,60.38 49.42,60.38 48,61.8 48,61.8 47.29,62.51 46.2,62.51 v1(46.13,62.43)
  BOTTOM w0.152: R337.2 125.48,16.92 123.75,18.64 v1(123.75,18.85)
PM_V3P3_PWRGD: length 49.7
  TOP w0.099: v1(22.81,48.21) 23.15,48.55 U8.1 23.15,51.17 23.37,51.38 26.67,51.38 v1(26.72,51.44)
  TOP w0.102: U7.C3 42.38,51.18 v1(42.3,51.18)
  TOP w0.203: R44.1 14.92,45.25 14.48,44.81 v1(14.27,44.81) 14.35,44.73 R52.1
  TOP w0.305: U17.3 13.74,35 v1(13.49,34.75)
  L3_SIG w0.097: v1(42.3,51.18) 42.3,51.14 41.76,50.6 35.99,50.6 34.97,51.61 29.87,51.61 29.36,52.12 27.41,52.12 v1(26.72,51.44) ; v1(22.81,48.21) 17.68,48.21 v1(14.27,44.81)
  L8_SIG w0.203: v1(13.49,34.75) 13.49,35.03 11.73,36.78 11.73,42.42 14.12,44.81 v1(14.27,44.81)
PM_V3P3_V1P9_EN: length 43.6
  TOP w0.099: U17.2 13.24,35.21 12.74,34.71 v1(12.7,34.71)
  TOP w0.152: v1(41.3,53.14) 41.79,53.62 U7.E4
  L8_SIG w0.097: v1(12.7,34.71) 13.22,34.19 21.01,34.19 24.91,38.1 v1(25.11,38.1)
  BOTTOM w0.097: v1(25.11,38.1) 25.86,38.88 25.86,41.68 27.86,43.69 27.86,48.54 28.52,49.2 28.52,50.24 28.96,50.67 29.77,50.67 30.73,51.64 39.8,51.64 v1(41.3,53.14)
PM_V5A_PWRGD: length 81.3
  TOP w0.099: C155.2 49.81,10.23 49.71,10.13 49.56,10.13 48.82,9.4 48.24,9.4 48.01,9.17 48.01,9.14 v1(48.01,9.14)
  TOP w0.127: N20.1 v1(106.79,7.85)
  TOP w0.305: C155.2 49.8,10.25 R127.1 49.71,11.67 49.71,12.62 49.77,12.68 U29.3
  L10_SIG w0.097: v1(48.01,9.14) 47.88,9.01 47.88,5.74 49.38,4.24 82.07,4.24 83.64,5.82 83.64,9.04 84.58,9.98 95.99,9.98 99.56,13.55 106.61,13.55 107.29,12.88 107.29,11.19 107.48,10.99 107.48,8.54 v1(106.79,7.85)
PM_VCCP_EN: length 32.5
  TOP w0.102: U7.F2 v1(44.32,54.12)
  TOP w0.127: v1(52.63,35.73) 52.63,35.08 52.92,34.79 U23.17
  L3_SIG w0.097: v1(52.63,35.73) 52.63,36.11 52.1,36.63 46.53,36.63 41.81,41.35 41.68,41.35 v1(41.6,41.43)
  L10_SIG w0.097: v1(44.32,54.12) 44.81,53.64 44.81,48.87 42.94,47 42.94,44.54 42.48,44.08 42.48,42.22 41.69,41.43 v1(41.6,41.43)
  BOTTOM w0.127: R264.2 52.63,34.7 v1(52.63,35.73)
PM_VCCP_PWRGD: length 43.2
  TOP w0.102: U7.L1 v1(45.32,60.12)
  TOP w0.127: U23.9 56.57,32.74 56.9,33.06 56.9,33.37 56.64,33.63 56.64,33.67 56.55,33.76 56.55,34.3 57.33,35.08 v1(57.33,35.66)
  L3_SIG w0.157: v1(57.33,35.66) 57.33,37.11 51.79,42.65 v1(43.76,42.65)
  L10_SIG w0.097: v1(43.76,42.65) 43.94,42.65 45.04,43.75 45.04,45.26 47.67,47.88 47.67,56.6 45.97,58.29 45.97,59.39 45.32,60.04 v1(45.32,60.12)
  BOTTOM w0.127: v1(57.33,35.66) 57.57,35.91 R251.2
PM_VDDQ_EN: length 90.3
  TOP w0.099: U7.H1 46.39,56.62 47.22,57.45 v1(47.22,59)
  TOP w0.178: v1(86.58,62.65) 86.58,63.23 86.41,63.4 U3.17
  TOP w0.254: v1(124.23,64.66) 124.47,64.9 N4.1
  L3_SIG w0.097: v1(47.22,59) 47.2,59.02 47.2,59.16 48.01,59.97 49.68,59.97 51.46,61.75 51.47,61.75 51.54,61.82 59.07,61.82 60.95,59.94 80.19,59.94 81.86,61.62 84.71,61.62 85.74,62.65 v1(86.58,62.65) 87.07,62.15 90.96,62.15 91.34,61.77 117.6,61.77 v1(117.98,62.15)
  L5_SIG w0.097: v1(124.23,64.66) 122.17,64.66 119.66,62.15 v1(117.98,62.15)
  BOTTOM w0.178: v1(86.58,62.65) 86.54,62.61 85.8,62.61 85.19,62 R173.2
PM_VDDQ_PWRGD: length 135.2
  TOP w0.099: v1(36.47,45.36) 36.47,44.73 37.24,43.97 38.76,43.97 39.35,43.38 U11.2
  TOP w0.102: v1(37.27,50.17) U7.A8
  TOP w0.127: v1(81.66,63.37) 81.79,63.37 82.32,63.91 82.32,64.83 82.68,65.2 U3.9
  L5_SIG w0.097: v1(82.88,61.01) 82.58,61.32 81.25,61.32 80.46,60.52 61.66,60.52 60,62.17 57.26,62.17 56.72,62.71 55.91,62.71 55.37,62.17 53.49,62.17 52.39,61.08 49.06,61.08 48.17,61.98 44.86,61.98 43.51,60.63 40.08,60.63 39.8,60.35 39.8,59.94 39.45,59.59 36.97,59.59 35.79,58.41 35.79,51 36.61,50.17 v1(37.27,50.17)
  L8_SIG w0.097: v1(36.47,45.36) 36.47,45.42 37.8,46.74 37.8,47.98 36.78,49 36.78,49.43 37.27,49.92 v1(37.27,50.17)
  L10_SIG w0.508: v1(82.88,61.01) 82.88,60.68 83.39,60.17 91.67,60.17 94.44,62.95 102.83,62.95 104.14,64.26 115.72,64.26 116.99,62.99 127.76,62.99 128.52,63.75 128.52,64.34 130.1,65.91 v1(130.3,65.91)
  BOTTOM w0.254: v1(81.66,63.37) 81.66,63.24 81.6,63.18 R172.2
  BOTTOM w0.508: v1(82.88,61.01) 82.68,61.21 82.3,61.21 81.6,61.91 R172.2 ; U36.2 132.61,67.46 132.11,67.97 130.56,67.97 129.92,67.34 129.92,66.29 v1(130.3,65.91)
PM_VNN_EN: length 42.6
  TOP w0.102: U7.L3 v1(43.32,60.12)
  TOP w0.127: U23.10 56.06,34.26 56.72,34.92 v1(56.72,35.18)
  L3_SIG w0.157: v1(41.92,42.6) 42.01,42.6 42.09,42.67 42.65,42.67 43.43,41.88 51.63,41.88 56.62,36.89 56.62,35.28 v1(56.72,35.18)
  L10_SIG w0.097: v1(43.32,60.12) 43.21,60.12 42.85,59.77 42.85,56.72 43.81,55.75 43.81,48.34 42.58,47.11 42.58,44.81 41.86,44.09 41.86,42.85 41.92,42.79 v1(41.92,42.6)
  BOTTOM w0.127: v1(56.72,35.18) 56.73,35.18 57.1,34.81 R255.2
PM_VNN_PWRGD: length 50.2
  TOP w0.102: U7.L5 v1(40.34,60.11) ; v1(57.53,30.13) 57.52,30.14 57.4,30.14 57.21,30.33 U23.3
  L3_SIG w0.157: v1(57.53,30.13) 56.11,30.13 55.3,29.31 47.4,29.31 v1(37.66,39.05)
  L8_SIG w0.097: v1(37.66,39.05) 38.33,39.73 38.33,41.15 39.03,41.86 39.03,44.47 39.83,45.26 39.83,59.64 40.3,60.11 v1(40.34,60.11)
  BOTTOM w0.254: R273.2 57.98,30.74 57.53,30.29 v1(57.53,30.13)
PMU_AC_PRESENT: length 19.8
  TOP w0.203: v1(122.35,35.68) 122.42,35.68 122.42,35.67 122.9,35.67 U14.AA47
  BOTTOM w0.097: 111.3,26.87 110.82,26.39 110.02,26.39 R301.2
  BOTTOM w0.102: 111.3,26.87 111.3,28.17 112.04,28.91 112.04,30.73 112.72,31.42 114.1,31.42 114.72,32.04 114.72,32.42 114.76,32.46 114.76,32.46 115.85,33.55 115.85,33.83 116.04,34.02 116.21,34.02 116.45,34.26 116.45,34.42 116.67,34.64 118.82,34.64 118.96,34.78 121.73,34.78 122.37,35.42 122.37,35.66 v1(122.35,35.68)
PMU_GPE_N: length 8.5
  TOP w0.099: 110.34,33.22 110.34,32.66 109.79,32.11 R92.2
  TOP w0.102: U14.AB63 114.79,36.54 112.54,36.54 111.71,35.71 111.71,35.38 110.82,34.49 110.82,33.69 110.34,33.22
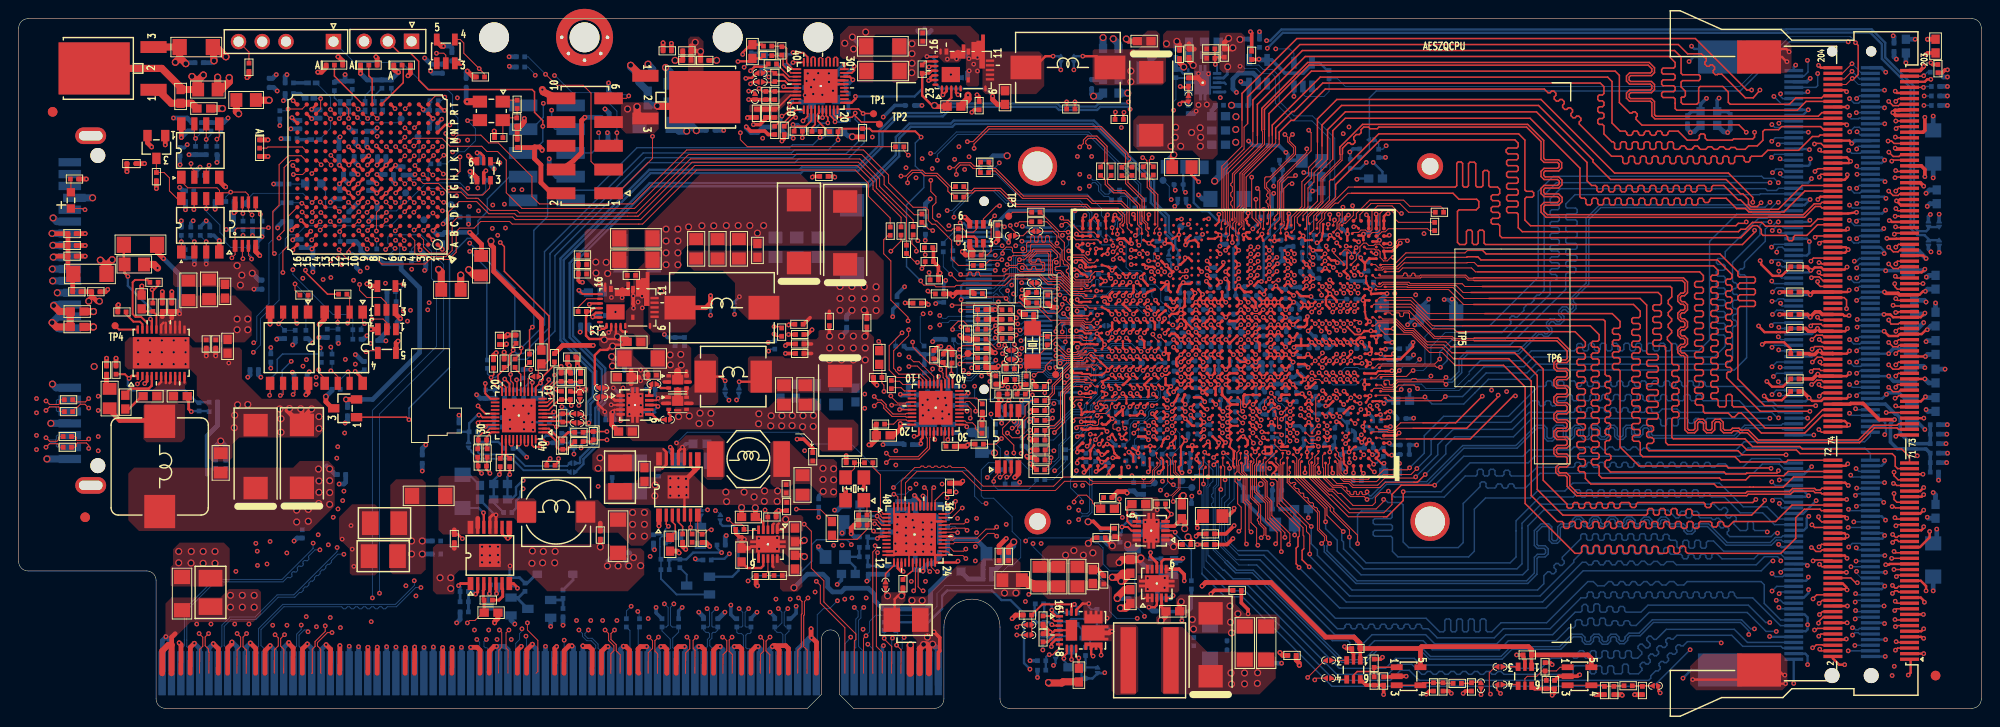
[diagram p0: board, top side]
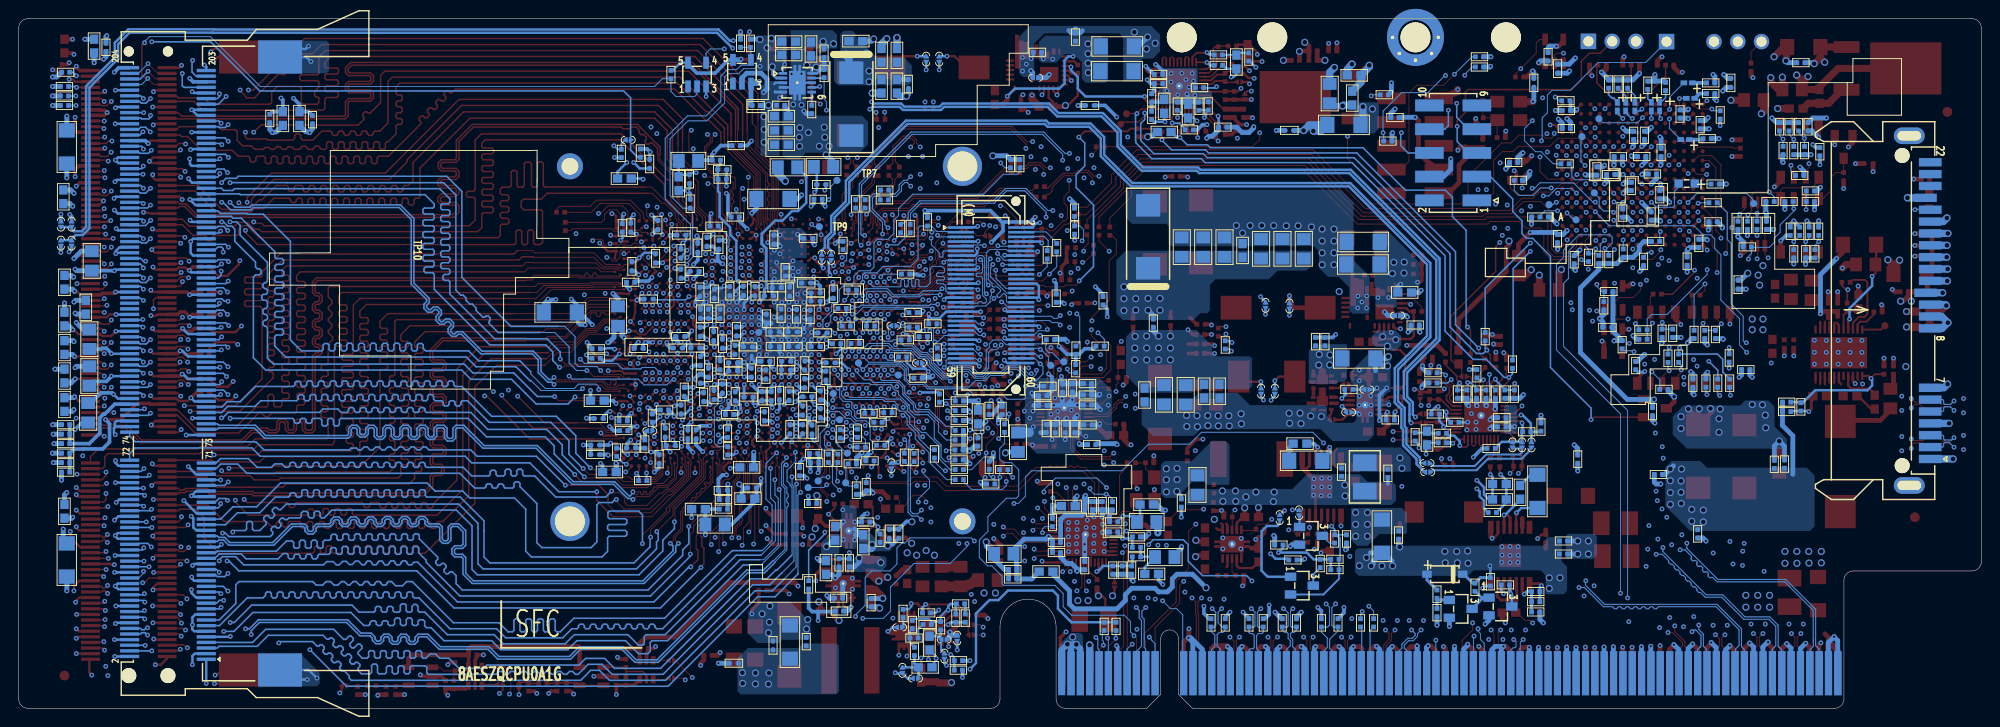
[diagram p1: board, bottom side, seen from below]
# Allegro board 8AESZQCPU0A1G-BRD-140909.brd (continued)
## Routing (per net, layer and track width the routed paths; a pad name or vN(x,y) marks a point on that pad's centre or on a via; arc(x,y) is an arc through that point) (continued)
PMU_SLP_S3_N: length 100.6
  TOP w0.102: U14.AF65 114,38.02 113.41,38.02 113.26,37.87 112.22,37.87 111.1,38.99 v1(110.97,38.99) ; U7.B9 36.39,51.05 v1(36.39,51.12)
  L5_SIG w0.097: v1(110.97,38.99) 110.92,39.04 109.8,39.04 107.57,41.27 107.57,42.57 107.24,42.89 106.46,42.89 105.83,42.27 103.99,42.27 103.73,42.01 99.82,42.01 99.09,42.75 96.49,42.75 94.94,44.3 94.08,44.3 93.23,45.15 93.23,46.18 85.13,54.28 83.62,54.28 82.67,55.23 54.72,55.23 53.91,54.42 50.51,54.42 49.89,53.8 49.87,53.8 49.86,53.8 48.97,53.8 47.63,52.45 47.63,47.93 45.75,46.05 36.07,46.05 v1(35.83,45.81)
  L8_SIG w0.097: v1(35.83,45.81) 35.84,45.82 35.84,50.65 36.31,51.12 v1(36.39,51.12)
PMU_SLP_S45_N: length 98.8
  TOP w0.099: U14.V64 114.39,34.23 114.27,34.23 114.25,34.25 v1(114.22,34.25)
  TOP w0.102: U7.K4 v1(42.32,59.12)
  L3_SIG w0.097: v1(114.22,34.25) 113.09,34.25 112.04,33.2 110.69,33.2 108.81,31.31 107.73,31.31 107.37,31.67 104.85,31.67 103.73,30.55 96.93,30.55 95.64,31.85 95.64,33.58 94.55,34.67 93.98,34.67 93.02,35.63 93.02,39.28 92.33,39.98 92.33,45.59 90.73,47.19 90.73,49.74 85.76,54.71 84.05,54.71 83.27,55.48 58.48,55.48 58.04,55.04 54.31,55.04 v1(53.85,55.5)
  L8_SIG w0.097: v1(53.85,55.5) 53.85,59.13 53.06,59.92 46.33,59.92 45.67,60.58 43.14,60.58 42.71,60.15 42.71,59.51 v1(42.32,59.12)
PMU_SUSCLK: length 2.4
  TOP w0.099: U14.AD58 117.73,37.3 v1(117.38,37.65)
  BOTTOM w0.102: R245.2 116.22,37.24 116.97,37.24 v1(117.38,37.65)
PMU_WAKE_N: length 9.8
  TOP w0.099: R80.2 106.59,34.38 v1(106.6,34.37)
  TOP w0.114: v1(111,37.72) 111.02,37.74 111.63,37.74 111.94,37.44 113.65,37.44 U14.AD66
  L5_SIG w0.097: v1(106.6,34.37) 106.53,34.44 106.53,34.75 109.45,37.67 110.95,37.67 v1(111,37.72)
PWM1_VCCP: length 23.1
  TOP w0.203: U23.21 50.48,33.14 49.93,33.69 v1(49.93,34.76)
  TOP w0.254: U12.19 61.16,43.33 v1(61.06,43.23)
  L3_SIG w0.254: v1(61.06,43.23) 60.58,42.75 60.58,35.86 58.39,33.68 56.76,33.68 56.18,34.26 50.42,34.26 v1(49.93,34.76)
PWM1_VDDQ_CH01: length 12.5
  TOP w0.254: U3.21 89.1,64.8 89.53,65.23 v1(89.53,65.48) ; v1(97.41,68.63) 97.51,68.73 U2.19
  BOTTOM w0.254: v1(89.53,65.48) 95.86,65.48 96.67,66.29 96.67,67.56 97.41,68.3 v1(97.41,68.63)
PWM1_VNN: length 18.4
  TOP w0.203: U23.25 49.93,31.53 49.15,32.32 v1(49.15,32.36) ; U20.3 63.42,32.46 v1(63.4,32.49)
  L3_SIG w0.203: v1(49.15,32.36) 50.32,33.53 55.96,33.53 56.31,33.17 62.36,33.17 63.04,32.49 v1(63.4,32.49)
PWRGD_COREPWR: length 108.6
  TOP w0.099: v1(104.88,38.87) 104.88,39.04 105.22,39.38 R61.1
  TOP w0.102: U7.F6 v1(40.32,54.12)
  L5_SIG w0.097: v1(104.88,38.87) 100.83,38.87 99.81,39.89 97.7,39.89 95.44,42.15 94.61,42.15 92.53,44.22 92.53,45.88 84.92,53.49 83.36,53.49 83.36,53.5 83.32,53.5 82.29,54.53 55.19,54.53 54.98,54.32 54.98,54.32 53.67,53.01 49.83,53.01 48.84,52.02 48.84,46.33 47.75,45.24 41.86,45.24 41.5,44.88 39.85,44.88 v1(39.24,45.49)
  L10_SIG w0.097: v1(39.24,45.49) 39.24,48.31 39.78,48.84 39.78,53.72 40.18,54.12 v1(40.32,54.12)
  BOTTOM w0.097: N40.2 115.89,40.79 R228.1 114.73,40.56 114.25,40.08 114.25,38.94 113.39,38.07 112.8,38.07 112.12,37.39 112.12,37.01 110.95,35.84 110.31,35.84 109.7,36.45 108.2,36.45 107.49,35.74 106.86,35.74 106.21,36.39 106.21,38.11 105.94,38.38 105.37,38.38 v1(104.88,38.87)
PWRGD_XDP_CPU: length 74.5
  TOP w0.099: R56.1 106.24,41.63 106.74,41.14 v1(106.89,41.14)
  TOP w0.102: U7.G1 v1(45.32,55.12)
  L5_SIG w0.097: v1(49.2,53.24) 49.33,53.24 49.35,53.26 49.35,53.27 49.45,53.37 53.37,53.37 54.88,54.88 82.44,54.88 83.46,53.85 85.06,53.85 92.88,46.03 92.88,44.53 94.89,42.52 95.72,42.52 96.68,41.56 103.78,41.56 104.26,42.05 105.7,42.05 106.61,41.14 v1(106.89,41.14)
  L8_SIG w0.097: v1(49.2,53.24) 48.95,52.98 47.22,52.98 45.32,54.88 v1(45.32,55.12)
  BOTTOM w0.097: P2.41 107.64,41.45 107.32,41.14 v1(106.89,41.14)
RSMRST_N: length 107.1
  TOP w0.099: U7.K2 43.85,58.62 v1(44.39,59.16)
  TOP w0.254: v1(122.7,36.21) 122.71,36.22 122.71,36.24 U14.AC47
  L3_SIG w0.097: v1(110.62,31.85) 109.03,30.26 107.79,30.26 106.92,31.12 105.19,31.12 103.42,29.35 100.27,29.35 99.95,29.66 96.65,29.66 94.9,31.41 94.9,31.5 94.9,31.51 94.9,32.18 93.85,33.22 93.85,33.6 91.14,36.32 91.14,40.01 90.45,40.69 86.56,40.69 86.36,40.89 86.36,50.79 82.36,54.78 59.4,54.78 58.52,53.9 52.02,53.9 v1(51.97,53.95)
  L5_SIG w0.097: v1(122.7,36.21) 122.81,36.11 122.81,35.51 122.28,34.98 113.75,34.98 v1(110.62,31.85)
  L8_SIG w0.097: v1(44.39,59.16) 46.91,56.64 46.91,56.16 48.54,54.53 51.26,54.53 51.84,53.95 v1(51.97,53.95)
  BOTTOM w0.097: R277.1 109.8,31.04 v1(110.62,31.85)
RST_CPU_N: length 33.8
  TOP w0.099: v1(100.79,42.57) 100.83,42.61 100.94,42.61 101,42.66 C70.1 102.61,41.65 R57.2 102.61,41.61 R58.2
  TOP w0.102: U14.Y63 114.76,35.11 114.39,35.48 112.7,35.48 112.17,34.95 112.01,34.95 111.91,34.85 v1(111.89,34.85)
  L3_SIG w0.097: v1(111.89,34.85) 111.91,34.85 111.94,34.87 112.17,34.87 113.11,35.81 113.11,38.2 112.6,38.71 111.89,38.71 111.18,39.42 110.72,39.42 110.29,38.99 110.29,37.9 107.67,35.28 104.55,35.28 104.24,34.98 v1(103.91,34.98)
  L10_SIG w0.097: v1(100.79,42.57) 100.87,42.57 100.89,42.54 100.92,42.54 100.95,42.52 102.13,42.52 103.4,41.25 103.4,37.37 104.27,36.5 104.27,35.31 104.01,35.05 103.99,35.05 v1(103.91,34.98)
RST_XDP_CPURST_N: length 3.2
  TOP w0.099: R58.1 104.15,40.58 v1(104.52,40.95)
  BOTTOM w0.097: v1(104.52,40.95) 104.03,40.45 P2.46
RST_XDP_N: length 79.3
  TOP w0.099: R60.1 101.54,40.98 101.09,41.43 100.53,41.43 99.92,40.82 v1(99.92,40.54)
  TOP w0.102: U7.G3 v1(43.32,55.12)
  L3_SIG w0.097: v1(46.86,54.84) 46.86,55.85 47.96,56.95 48.68,56.95 52.15,60.42 57.98,60.42 59.86,58.54 89.57,58.54 95.06,53.05 95.06,47.89 98.78,44.17 98.78,43.23 99.87,42.14 99.87,40.59 v1(99.92,40.54)
  BOTTOM w0.097: P2.48 102.7,39.97 101.33,39.97 100.89,40.41 100.05,40.41 v1(99.92,40.54) ; v1(43.32,55.12) 43.82,55.63 45.48,55.63 46.27,54.84 v1(46.86,54.84)
RTEST_CPU_N: length 16.9
  TOP w0.254: U14.AD50 v1(121.19,37.65)
  L3_SIG w0.097: v1(111.99,39.22) 112.25,39.48 113.81,39.48 116.03,37.26 120.7,37.26 121.08,37.65 v1(121.19,37.65)
  BOTTOM w0.097: v1(111.99,39.22) 111.99,38.85 R244.1 ; v1(111.99,39.22) 112.11,39.34 112.11,40.59 111.74,40.96 C312.1 ; v1(111.99,39.22) 111.65,39.22 110.97,39.9 109.25,39.9 P2.47
SA0: length 17.5
  L5_SIG w0.152: v1(203.86,64.52) 202.9,65.48 199.06,65.48 197.97,66.57 194.84,66.57 193.48,67.93 v1(192.49,67.93)
  BOTTOM w0.152: v1(192.49,67.93) 192.49,66.64 ; v1(203.86,64.52) R163.2
  BOTTOM w0.157: P4.197 192.31,66.45 192.49,66.64
SA0_16765987: length 2.4
  TOP w0.152: P1.197 v1(203.81,66.45)
  BOTTOM w0.152: v1(203.81,66.45) 203.9,66.55 R155.2
SA1: length 17.8
  L5_SIG w0.152: v1(203.89,65.53) 202.56,66.85 195.58,66.85 193.09,69.34 v1(191.39,69.34)
  BOTTOM w0.152: v1(203.89,65.53) R160.2
  BOTTOM w0.157: P4.201 191.02,67.65 191.45,68.09 191.45,69.28 v1(191.39,69.34)
SA1_16765629: length 2.4
  TOP w0.152: v1(203.84,67.69) 203.79,67.65 P1.201
  BOTTOM w0.152: v1(203.84,67.69) 204.22,68.07 R145.2
SA1_LED: length 1.4
  TOP w0.099: R25.2 5.59,56.58 D1.2
SATA1_ACTIVITY: length 3.2
  TOP w0.099: v1(7.09,53.36) 6.96,53.49 D1.1
  BOTTOM w0.097: P3.18 v1(7.09,53.36)
SATA3G_RX0_C_DN: length 2.9
  TOP w0.104: U14.H63 114.84,29.26 114.77,29.33 v1(114.66,29.33)
  BOTTOM w0.107: C429.2 114.19,27.33 114.74,27.88 114.74,28.63 114.69,28.68 114.69,29.31 v1(114.66,29.33)
SATA3G_RX0_C_DP: length 2.6
  TOP w0.104: U14.H62 115.89,29.43 v1(115.22,28.75)
  BOTTOM w0.107: v1(115.22,28.75) 114.99,28.53 114.99,27.92 115.23,27.69 C428.2
SATA3G_RX_DN0: length 72.8
  TOP w0.107: v1(62.74,8.38) 63.12,8 63.12,7.26 63.68,6.69 63.68,6.17 63.37,5.85 S1.A34
  L5_SIG w0.114: v1(62.74,8.38) 63.13,8.78 63.13,9.91 68.62,15.41 80.22,15.41 82.23,17.42 84.48,17.42 88.26,21.2 89.88,21.2 93.51,24.83 99.57,24.83 100.96,23.44 110.89,23.44 111.89,22.45 111.89,21.21 112.26,20.83 113.04,20.83 v1(113.41,21.21)
  BOTTOM w0.107: v1(113.41,21.21) 113.79,20.83 114.32,20.83 114.59,21.09 114.59,26 C429.1
SATA3G_RX_DP0: length 72.8
  TOP w0.107: S1.A33 64.37,5.72 63.94,6.15 63.94,6.8 63.37,7.37 63.37,8 v1(63.75,8.38)
  L5_SIG w0.114: v1(63.75,8.38) 63.4,8.74 63.4,9.8 68.74,15.14 80.34,15.14 82.34,17.15 84.59,17.15 88.37,20.93 89.99,20.93 93.62,24.56 99.46,24.56 100.85,23.18 110.78,23.18 111.62,22.34 111.62,21.1 112.15,20.57 113.04,20.57 v1(113.41,20.19)
  BOTTOM w0.107: C428.1 114.84,26.03 114.84,20.98 114.43,20.57 113.79,20.57 v1(113.41,20.19)
SATA6G_RX0_C_DN: length 146.9
  TOP w0.102: U14.M64 114.1,31.15 114.02,31.07 113.04,31.07 112.83,30.86
  TOP w0.107: v1(7.49,32.13) 7.09,32.54 6.6,32.54 6.27,32.2 6.14,32.2 5.78,31.84 C106.1 ; v1(112.83,30.76) 112.83,30.86
  L3_SIG w0.114: v1(7.49,32.13) 7.12,32.51 6.77,32.51 6.21,33.06 6.21,36.43 12.89,43.12 39.53,43.12 40.09,43.68 42.94,43.68 43.55,44.29 54.32,44.29 62.61,52.58 80.21,52.58 83.41,49.38 83.41,34.57 92.57,25.41 94.75,25.41 95.31,25.97 101.85,25.97 103.19,25.97 103.72,26.5 107.34,26.5 108.15,25.69 110.05,25.69 112.5,28.14 112.5,29.95 112.83,30.28 v1(112.83,30.76)
SATA6G_RX0_C_DP: length 147
  TOP w0.107: U14.M62 115.84,31.16 115.55,30.87 115.55,30.43 115.4,30.28 114.92,30.28 114.83,30.37 114.42,30.37 114.3,30.25 113.29,30.25 113.18,30.14 v1(113.18,30.01) ; C104.1 6.01,32.79 7.14,32.79 v1(7.49,33.15)
  L3_SIG w0.114: v1(113.18,30.01) 112.94,30.01 112.76,29.84 112.76,28.03 110.16,25.43 108.04,25.43 107.23,26.24 103.84,26.24 103.46,25.86 103.46,25.86 103.3,25.7 98.37,25.7 98.37,25.71 95.42,25.71 94.87,25.15 92.46,25.15 83.15,34.46 83.15,49.27 80.1,52.31 62.72,52.31 54.43,44.02 43.66,44.02 43.05,43.41 40.2,43.41 39.65,42.85 13,42.85 6.48,36.32 6.48,33.17 6.88,32.77 7.12,32.77 v1(7.49,33.15)
SATA6G_RX_DN0: length 5.6
  TOP w0.107: v1(2.92,31.88) 3.3,32.26 4.27,32.26 4.38,32.15 4.38,31.86 4.49,31.75 C106.2
  BOTTOM w0.107: v1(2.92,31.88) 3.32,32.27 3.92,32.27 4.03,32.17 4.03,31.87 4.14,31.76 P3.5
SATA6G_RX_DP0: length 5.6
  TOP w0.107: C104.2 4.49,33.02 4.38,32.91 4.38,32.62 4.27,32.51 3.3,32.51 v1(2.92,32.89)
  BOTTOM w0.107: v1(2.92,32.89) 3.29,32.53 3.92,32.53 4.03,32.63 4.03,32.93 4.14,33.03 P3.6
SATA6G_TX0_C_DN: length 155.6
  TOP w0.104: v1(112.65,33.15) 112.83,33.32 114.05,33.32 114.11,33.26 U14.T64
  TOP w0.107: C109.1 6.05,29.08 6.16,28.98 6.16,28.75 6.26,28.65 7.31,28.65 v1(7.49,28.83)
  L3_SIG w0.114: v1(7.49,28.83) 7.87,28.45 8.82,28.45 9.22,28.85 9.22,29.9 8.79,30.33 5.94,30.33 5.23,31.04 5.23,36.8 12.52,44.09 38.86,44.09 39.43,44.66 39.59,44.82 42.82,44.82 43.18,45.18 53.95,45.18 62.24,53.47 81.1,53.47 84.4,50.16 84.4,35.76 90.15,30.01 93.18,30.01 96.09,27.1 102.91,27.1 103.94,28.12 107.73,28.12 108,28.38 110.45,28.38 111.47,29.4 111.47,32.29 112.13,32.96 112.36,32.96 112.55,33.15 v1(112.65,33.15)
SATA6G_TX0_C_DP: length 155.4
  TOP w0.104: v1(112.82,32.38) 112.82,32.68 113.14,33.01 U14.R66
  TOP w0.107: C112.1 6.05,27.94 6.16,28.05 6.16,28.28 6.28,28.4 7.24,28.4 7.49,28.14 v1(7.49,27.81)
  L3_SIG w0.114: v1(7.49,27.81) 7.87,28.19 8.93,28.19 9.49,28.74 9.49,30.01 8.9,30.59 6.05,30.59 5.5,31.15 5.5,36.69 12.63,43.83 38.97,43.83 39.7,44.55 42.93,44.55 43.29,44.91 54.06,44.91 62.35,53.2 80.99,53.2 84.14,50.05 84.14,35.65 90.04,29.75 93.07,29.75 95.98,26.83 103.02,26.83 104.05,27.85 107.85,27.85 108.11,28.11 110.56,28.11 111.73,29.29 111.73,32.18 112.24,32.69 112.51,32.69 v1(112.82,32.38)
SATA6G_TX_DN0: length 5.4
  TOP w0.107: v1(2.92,28.96) 3.3,28.57 4.08,28.57 4.25,28.75 4.25,28.98 4.36,29.08 C109.2
  BOTTOM w0.107: P3.3 4.14,29.22 4.03,29.12 4.03,28.82 3.92,28.72 3.16,28.72 v1(2.92,28.96)
SATA6G_TX_DP0: length 5.4
  TOP w0.107: C112.2 4.36,27.94 4.25,28.05 4.25,28.21 4.15,28.32 3.3,28.32 v1(2.92,27.94)
  BOTTOM w0.107: P3.2 4.14,27.95 4.03,28.06 4.03,28.36 3.92,28.46 3.44,28.46 v1(2.92,27.94)
SATA_OBSN: length 1.4
  TOP w0.104: U14.L52 v1(120.91,30.24)
  BOTTOM w0.104: v1(120.91,30.24) 120.56,29.89 R283.1
SATA_OBSP: length 1.4
  TOP w0.104: U14.J52 v1(120.91,29.48)
  BOTTOM w0.104: v1(120.91,29.48) 120.44,29 R283.2
SGMII_RX_C_DN1: length 4.3
  TOP w0.091: U14.L46 123.78,30.58 v1(123.42,30.23)
  BOTTOM w0.091: v1(123.42,30.23) 124.24,29.4 124.24,27.97 123.58,27.3 123.46,27.3 123.37,27.21 C430.2
SGMII_RX_C_DP1: length 4
  TOP w0.091: U14.J46 123.78,29.56 123.69,29.47 v1(123.43,29.47)
  BOTTOM w0.091: C431.2 122.92,27.76 123.39,27.76 123.79,28.15 123.79,29.21 123.53,29.47 v1(123.43,29.47)
SGMII_RX_DN1: length 92.5
  TOP w0.091: S1.A46 51.37,6.22 51.69,6.55 51.69,8.13 v1(51.44,8.38)
  L5_SIG w0.094: v1(122.17,23.34) 122.17,23.28 120.14,21.25 120.14,20.27 118.19,18.31 112.8,18.31 110.18,15.69 104.43,15.69 103.59,14.86 100.13,14.86 99.13,15.86 92.54,15.86 90.76,14.08 83.09,14.08 81.13,12.12 73.79,12.12 72.26,10.59 72.26,9.65 69.88,7.26 69.88,5.45 69.23,4.8 52.97,4.8 51.69,6.08 51.69,8.13 v1(51.44,8.38)
  BOTTOM w0.091: C430.1 122.93,25.87 122.93,24.1 v1(122.17,23.34)
SGMII_RX_DP1: length 92.8
  TOP w0.091: v1(52.45,8.38) 52.15,8.08 52.15,6.44 52.37,6.22 S1.A45
  L5_SIG w0.094: v1(122.39,24.3) 122.39,24.16 122.21,23.99 122.21,23.99 122.04,23.81 121.98,23.81 121.7,23.54 121.7,23.48 119.67,21.45 119.67,20.46 117.99,18.78 112.61,18.78 109.99,16.16 104.23,16.16 103.4,15.33 100.32,15.33 99.32,16.33 92.34,16.33 90.57,14.55 82.9,14.55 80.93,12.59 73.6,12.59 71.79,10.78 71.79,9.85 69.41,7.46 69.41,5.64 69.03,5.27 65.82,5.27 65.63,5.46 65.47,5.46 65.28,5.27 64.91,5.27 64.77,5.41 64.51,5.41 64.37,5.27 64.16,5.27 64.02,5.41 63.76,5.41 63.62,5.27 63.41,5.27 63.27,5.41 63.01,5.41 62.87,5.27 62.65,5.27 62.52,5.41 62.25,5.41 62.11,5.27 61.9,5.27 61.76,5.41 61.5,5.41 61.36,5.27 61.15,5.27 61.01,5.41 60.75,5.41 60.61,5.27 60.4,5.27 60.26,5.41 60,5.41 59.86,5.27 59.65,5.27 59.51,5.41 59.25,5.41 59.11,5.27 58.9,5.27 58.78,5.38 58.47,5.38 58.35,5.27 58.14,5.27 58,5.41 57.74,5.41 57.6,5.27 57.39,5.27 57.25,5.41 56.99,5.41 56.85,5.27 56.64,5.27 56.48,5.44 56.26,5.44 56.1,5.27 55.89,5.27 55.72,5.44 55.51,5.44 55.35,5.27 55.14,5.27 54.97,5.44 54.76,5.44 54.6,5.27 54.38,5.27 54.22,5.44 54.01,5.44 53.84,5.27 53.17,5.27 52.16,6.28 52.16,8.09 v1(52.45,8.38)
  BOTTOM w0.091: C431.1 122.35,26.28 122.48,26.16 122.48,24.39 v1(122.39,24.3)
SGMII_TX_DN1: length 100.9
  TOP w0.081: U14.B46 123.78,25.29 124.26,24.82 124.26,23.44 123.49,22.68 123.49,22.17 v1(123.53,22.13)
  L5_SIG w0.094: v1(123.53,22.13) 123.21,22.13 122.78,21.71 122.78,17.72 122.18,17.12 119.74,17.12 118.96,16.34 117.08,16.34 116.04,15.3 113.08,15.3 111.57,13.79 99.8,13.79 98.45,15.14 93.66,15.14 92.06,13.55 92.06,10.43 91.3,9.67 88.88,9.67 88.1,10.45 85.38,10.45 83.41,8.48 83.41,5.17 82.1,3.86 50.97,3.86 49.31,5.52 49.31,7.1 49.05,7.37 v1(49.02,7.37)
  BOTTOM w0.091: v1(49.02,7.37) 49.33,7.06 49.33,6.42 49.37,6.38 S1.B48
SGMII_TX_DP1: length 100.8
  TOP w0.081: v1(122.84,22.83) 122.86,22.81 123.37,22.81 124.07,23.52 124.07,24.74 123.6,25.22 123.6,26.14 123.48,26.25 123.48,26.89 U14.D46
  L5_SIG w0.094: v1(122.84,22.83) 122.84,22.43 122.31,21.91 122.31,17.92 121.99,17.59 119.54,17.59 118.77,16.81 116.89,16.81 115.85,15.77 112.89,15.77 111.37,14.26 99.99,14.26 98.64,15.61 93.46,15.61 91.59,13.74 91.59,10.62 91.11,10.14 89.07,10.14 88.29,10.92 85.19,10.92 82.94,8.68 82.94,5.36 81.91,4.33 51.17,4.33 49.78,5.72 49.78,7.11 v1(50.04,7.37)
  BOTTOM w0.091: v1(50.04,7.37) 49.96,7.37 49.87,7.27 49.87,7.24 49.78,7.16 49.78,6.61 49.92,6.48 50.1,6.48 50.37,6.21 S1.B47
SMB_3V3_HOST_ALERT_N: length 170.6
  TOP w0.102: U7.C11 34.45,51.25 34.45,51.11 v1(34.35,51.01)
  TOP w0.254: U14.AL58 117.38,40.22 v1(117.38,40.21)
  L3_SIG w0.097: v1(117.38,40.21) 117.38,40.35 117.09,40.64 116.38,40.64 115.76,40.02 115.76,39.93 115.54,39.71 115.23,39.71 113.94,41 110.28,41 109.32,40.04 109.32,38.15 107.33,36.15 104.68,36.15 104.01,36.83 102.9,36.83 102.49,36.43 v1(101.96,36.43) 101.88,36.51 101.88,37.08 102.34,37.54 102.34,52.37 100.71,54.01 98.14,54.01 97.87,53.74 94.89,53.74 89.74,58.89 60,58.89 58.13,60.77 52,60.77 49.11,57.87 48.03,57.87 46.43,56.27 46.43,51.92 45.21,50.7 42.77,50.7 41.73,49.66 35.99,49.66 34.64,51.01 v1(34.35,51.01)
  L8_SIG w0.097: v1(101.96,36.43) 102.29,36.1 102.29,35.76 101.57,35.05 100.61,35.05 99.72,34.16 95.33,34.16 93.82,35.67 89.57,35.67 88.37,34.47 88.37,32.72 83.36,27.71 83.36,23.22 84.71,21.87 84.71,16.47 86.56,14.61 86.56,12.55 v1(87.6,11.51)
  BOTTOM w0.097: v1(87.6,11.51) 86.77,10.67 86.11,10.67 85.45,10.01 85.45,3.83 S1.B12
  BOTTOM w0.099: v1(34.35,51.01) 34.4,50.96 R206.2
SMB_3V3_HOST_CLK: length 258
  TOP w0.099: v1(157.48,1.52) 157.35,1.65 157.35,3.81 157.99,4.45 N22.1 ; U27.6 92.83,18.77 91.59,18.77 91.47,18.9 v1(91.47,18.97) ; v1(94.52,40.18) 93.14,38.81 93.14,36.2 93.93,35.41 96.44,35.41 96.72,35.13 U21.9 ; v1(137.92,3.3) 139.75,5.13 N21.1 ; v1(23.99,48.11) 23.93,48.17 U8.2 ; N9.1 105.29,37.95 v1(105.26,37.95)
  TOP w0.102: v1(115.39,41.22) 115.4,41.22 115.42,41.23 115.44,41.23 U14.AN62
  L3_SIG w0.097: v1(105.26,37.95) 106.04,38.73 106.04,42.32 106.55,42.82 107.28,42.82 108.23,41.87 108.89,41.87 109.15,41.61 114.63,41.61 115.02,41.22 v1(115.39,41.22) ; v1(119.68,9.63) 119.68,9.07 122.17,6.58 136.8,6.58 138.15,5.23 138.15,3.53 v1(137.92,3.3) 137.92,2.67 138.26,2.33 156.67,2.33 v1(157.48,1.52) ; v1(94.52,40.18) 94.52,40.25 94.2,40.57 94.2,41.86 93.53,42.53 93.53,42.55 93.51,42.56 93.51,46.44 91.91,48.05 91.91,50.22 86.25,55.89 84.54,55.89 83.76,56.66 54.64,56.66 54.42,56.88 52.36,56.88 50,54.52 50,53.16 48.77,51.93 48.77,49.41 v1(48.26,48.9) 46.81,48.9 45.92,48.01 v1(42.8,48.01) 36.58,48.01 35.15,46.58 32.69,46.58 31.81,47.47 24.79,47.47 24.16,48.11 v1(23.99,48.11)
  L8_SIG w0.097: v1(108.53,17.63) 108.31,17.63 107.92,17.25 104.42,17.25 103.43,18.24 103.43,20.4 101.68,22.15 101.68,23.27 101.24,23.7 99.91,23.7 97.78,21.56 93.78,21.56 92.89,20.68 92.89,19.91 91.95,18.97 v1(91.47,18.97) ; v1(105.26,37.95) 104.98,37.67 103.91,37.67 102.74,38.84 99.97,38.84 99.11,39.7 95,39.7 v1(94.52,40.18)
  L10_SIG w0.097: v1(94.52,40.18) 94.52,39.7 93.75,38.93 93.75,35.32 95.05,34.02 95.05,25.71 93.57,24.23 93.04,24.23 92.71,23.9 92.71,19.89 91.8,18.97 v1(91.47,18.97)
  BOTTOM w0.097: v1(42.8,48.01) 42.61,47.82 R215.2 ; v1(94.52,40.18) 93.84,39.51 R241.2 ; v1(108.53,17.63) 108.53,17.3 110.34,15.49 114.2,15.49 116.71,12.98 116.71,10.39 117.47,9.63 v1(119.68,9.63)
  BOTTOM w0.152: v1(48.26,48.9) 50.09,47.07 50.09,37.35 R253.1
SMB_3V3_HOST_DATA: length 262.1
  TOP w0.099: v1(23.99,52.96) 23.93,53.02 U8.7 ; R62.2 103.55,39.5 104.6,38.46 105.11,38.46 v1(105.51,38.86) 105.88,38.5 N8.1 ; v1(115.42,42.09) 115.57,42.24 U14.AP62 ; U27.5 92.31,19.2 91.76,19.75 v1(91.58,19.75) ; v1(95.23,40.51) 95.23,39.88 93.62,38.28 93.62,36.39 93.83,36.19 93.83,36.12 94.18,35.76 96.49,35.76 97.12,35.12 U21.8 ; v1(138.68,3.04) 138.86,3.23 N23.1
  TOP w0.152: v1(158.56,1.59) 158.18,1.97 N24.1
  L3_SIG w0.097: v1(115.42,42.09) 115.12,41.79 114.73,41.79 114.71,41.8 110.7,41.8 110.36,42.14 108.33,42.14 107.41,43.06 106.15,43.06 105.56,42.47 105.56,38.91 v1(105.51,38.86) ; v1(23.99,52.96) 24.43,52.52 24.43,50.49 25.44,49.49 27.68,49.49 28.77,48.41 31.71,48.41 33.09,47.03 34.96,47.03 36.27,48.34 42.11,48.34 42.37,48.59 45.64,48.59 46.71,49.66 48.13,49.66 v1(48.26,49.78) 47.35,50.7 47.35,52.12 48.78,53.55 48.78,53.98 52.16,57.36 55.01,57.36 55.23,57.14 83.96,57.14 84.73,56.36 88.19,56.36 92.38,52.17 92.38,48.24 93.99,46.64 93.99,42.76 94.01,42.74 94.01,42.73 94.68,42.06 94.68,41.06 v1(95.23,40.51) ; v1(120.46,9.84) 123.18,7.11 137.03,7.11 138.68,5.45 138.68,3.05 v1(138.68,3.04) 138.75,2.97 157.18,2.97 v1(158.56,1.59)
  L8_SIG w0.097: v1(107.75,17.91) 106.96,18.69 106.96,19.74 106.02,20.68 103.99,20.68 102.23,22.43 102.23,24.54 101.7,25.07 100.03,25.07 99.59,24.64 99.59,24.05 97.74,22.2 93.39,22.2 92.48,21.29 92.48,20.24 91.99,19.75 v1(91.58,19.75) ; v1(105.51,38.86) 105.08,38.43 104.34,38.43 103.45,39.32 100.3,39.32 99.44,40.18 95.55,40.18 v1(95.23,40.51)
  L10_SIG w0.097: v1(95.23,40.51) 94.82,40.92 94.28,40.92 93.27,39.9 93.27,34.72 93.88,34.11 93.88,32.2 93.58,31.9 93.58,29.78 94.52,28.85 94.52,25.86 93.37,24.71 92.84,24.71 91.21,23.07 91.21,20.09 91.49,19.81 91.52,19.81 v1(91.58,19.75)
  BOTTOM w0.097: R201.2 24,52.95 v1(23.99,52.96) ; v1(107.75,17.91) 108.08,18.24 114.63,18.24 115.19,17.68 115.52,17.68 116.03,17.17 116.03,15.44 116.76,14.71 118.72,14.71 119.43,14 119.43,11.03 120.46,10 v1(120.46,9.84)
  BOTTOM w0.152: R249.1 53.09,44.96 v1(48.26,49.78)
SMB_3V3_XDP_CLK: length 3.2
  TOP w0.099: v1(107.09,37.9) 107.09,37.87 106.56,37.34 N9.2
  BOTTOM w0.097: v1(107.09,37.9) 107.11,37.87 107.29,37.87 107.87,38.45 P2.53
SMB_3V3_XDP_DATA: length 3
  TOP w0.099: v1(107.31,38.53) 106.74,38.53 N8.2
  BOTTOM w0.097: v1(107.31,38.53) 107.31,38.56 107.71,38.95 P2.51
SMB_3V3A_HOST_CLK: length 339.7
  TOP w0.099: v1(29.34,58.09) 29.8,57.62 U7.J16 ; v1(18.44,58.29) 18.44,57.86 18.8,57.51 U5.2 ; v1(196.16,68.98) 195.13,67.95 P1.202 ; U9.6 v1(20.07,53.47) ; U8.3 24.58,48.49 24.92,48.15 v1(24.92,48.08)
  L3_SIG w0.097: v1(25.37,17.65) 25.66,17.65 26.14,17.17 27.02,17.17 28.37,15.83 28.62,15.83 36.8,7.65 36.8,6.35 37.66,5.49 82.28,5.49 82.91,6.12 82.91,9.08 84.4,10.57 88.54,10.57 89.74,9.37 92.68,9.37 94.52,7.54 94.69,7.54 v1(94.74,7.58) ; v1(200.46,3.51) 202.31,5.36 202.31,67.84 201.17,68.98 v1(196.16,68.98)
  L5_SIG w0.097: v1(200.46,3.51) 199.06,2.11 177.47,2.11 176.63,2.95 143.86,2.95 142.31,1.4 128.32,1.4 122.51,7.21 116.43,7.21 114.04,9.6 109.09,9.6 109.09,9.6 107.44,9.6 104.34,12.71 98.76,12.71 94.74,8.68 v1(94.74,7.58) ; v1(29.34,58.09) 29.32,58.11 22.59,58.11 21.59,59.11 19.25,59.11 v1(18.44,58.29)
  L8_SIG w0.097: v1(25.37,17.65) 23.37,19.66 23.37,29.08 25.3,31.01 25.3,36.6 25.83,37.13 25.83,47.17 v1(24.92,48.08)
  L10_SIG w0.097: v1(18.44,58.29) 18.44,57.86 18.82,57.48 18.82,54.71 v1(20.07,53.47)
  BOTTOM w0.097: P4.202 197.19,67.95 v1(196.16,68.98) ; R194.2 20.13,53.53 v1(20.07,53.47) 20.07,53.19 21.53,51.72 21.53,50.94 22.15,50.32 22.15,49.86 22.68,49.33 24.55,49.33 R208.1 24.6,48.68 24.92,48.36 v1(24.92,48.08) ; S1.B5 94.42,6.28 94.53,6.39 94.53,7.38 v1(94.74,7.58)
SMB_3V3A_HOST_DATA: length 343.1
  TOP w0.099: U5.1 17.4,56.39 18.08,55.7 21.21,55.7 21.49,55.42 21.49,54.57 U9.5 21.46,54.79 21.84,55.17 22.56,55.17 22.63,55.24 v1(22.68,55.24) 24.28,55.24 24.56,54.97 24.56,54.16 U8.6 24.58,53.19 v1(24.97,52.81) ; v1(29.39,57.12) 30.38,57.12 30.82,57.57 U7.J15 ; P1.200 195.34,67.35 v1(196.16,68.17)
  L3_SIG w0.097: v1(196.16,68.17) 198.4,68.17 199.01,67.56 201.38,67.56 201.93,67.01 201.93,5.74 v1(200.69,4.5) ; v1(93.5,7.52) 92.12,8.9 89.54,8.9 88.34,10.09 84.6,10.09 83.41,8.91 83.41,6.13 82.42,5.14 36.51,5.14 35.86,5.79 35.86,7.91 33.23,10.54 32.89,10.54 27.08,16.36 25.98,16.36 v1(25.53,16.81)
  L5_SIG w0.097: v1(24.97,52.81) 24.97,54.89 27.2,57.12 v1(29.39,57.12) ; v1(93.5,7.52) 93.55,7.57 93.55,13.56 94.11,14.12 97.75,14.12 98.69,13.19 105.69,13.19 106.15,12.73 106.15,11.74 107.81,10.08 114.24,10.08 116.63,7.69 123.3,7.69 129.08,1.91 141.85,1.91 144.26,4.32 150.77,4.32 151.36,3.73 164.9,3.73 166.4,5.23 198.48,5.23 199.21,4.5 v1(200.69,4.5)
  L10_SIG w0.097: v1(25.53,16.81) 25.96,17.25 25.96,33.6 25.3,34.26 25.3,36.47 25.94,37.12 25.94,43.67 26.94,44.67 26.94,46.58 28.78,48.41 28.78,56.46 29.39,57.07 v1(29.39,57.12)
  BOTTOM w0.097: v1(22.68,55.24) 22.16,54.72 R193.2 ; v1(24.97,52.81) 25.02,52.76 R200.1 ; S1.B6 93.42,7.44 v1(93.5,7.52)
  BOTTOM w0.157: P4.200 196.98,67.35 v1(196.16,68.17)
SMB_GBE_CPU_ALERT_N: length 98.4
  TOP w0.099: S1.A42 55.55,3.94 55.55,7.26 54.43,8.38 v1(54.43,9.14)
  TOP w0.254: U14.T55 118.96,33.63 v1(118.95,33.72)
  L5_SIG w0.097: v1(54.43,9.14) 55.83,10.54 59.7,10.54 61.69,12.53 61.69,15.08 63.88,17.27 67.17,17.27 68.15,18.25 74.59,18.25 75.65,19.31 82.25,19.31 84.02,21.08 84.02,25.35 84.96,26.29 87.99,29.31 94.1,29.31 96.56,26.86 101.41,26.86 102.77,25.5 107.09,25.5 108.03,24.56 111.53,24.56 112.88,23.21 117.06,23.21 118.74,24.89 v1(119.11,24.89) 119.19,24.98 119.19,27.6 120.5,28.91 120.5,31.19 120.85,31.55 120.85,32.44 120.32,32.97 119.46,32.97 118.95,33.47 v1(118.95,33.72)
  BOTTOM w0.097: R313.1 119.31,24.69 v1(119.11,24.89)
SMB_GBE_CPU_CLK: length 82.3
  TOP w0.099: v1(112.92,22.07) 112.92,22.31 113.43,22.81 114.26,22.81 114.9,22.17 114.9,21.98 115.52,21.36 R117.2 115.77,22.24 R115.1
  L5_SIG w0.097: v1(54.28,7.72) 56.59,10.03 62.36,10.03 70.1,17.77 74.39,17.77 74.39,17.77 75.62,17.77 76.68,18.83 82.46,18.83 85.16,21.53 85.16,25.81 88.18,28.83 93.9,28.83 96.36,26.38 101.31,26.38 102.57,25.12 106.81,25.12 107.75,24.18 111.31,24.18 112.92,22.57 v1(112.92,22.07)
  BOTTOM w0.097: S1.B43 54.33,3.79 54.33,7.67 v1(54.28,7.72)
SMB_GBE_CPU_DATA: length 63.2
  TOP w0.099: R67.2 92.37,36.51 R78.1 92.37,34.81 92.58,34.6 v1(92.58,33.91)
  L5_SIG w0.097: v1(53.85,8.51) 53.85,9.63 55.27,11.05 59.72,11.05 61.34,12.67 61.34,15.37 63.63,17.65 67.06,17.65 68,18.6 74.38,18.6 75.44,19.66 80.54,19.66 82.75,21.87 82.75,24.61 88.09,29.95 91.95,29.95 92.58,30.58 v1(92.58,33.91)
  BOTTOM w0.097: v1(53.85,8.51) 53.85,8.26 53.6,8 53.6,7.37 53.19,6.96 53.19,3.93 S1.B44
SMB_PECI_CLK_UART_TXD: length 164.7
  TOP w0.102: v1(111.94,43.87) 112,43.81 112,43.71 112.78,42.93 113.93,42.93 U14.AR65
  L3_SIG w0.097: v1(37.85,11.81) 37.97,11.81 39.33,10.46 65.21,10.46 65.3,10.37 v1(66.24,10.37)
  L5_SIG w0.097: v1(40.32,50.09) 41.71,51.47 41.71,54.66 43.26,56.21 44.4,56.21 44.86,56.67 44.86,57.19 45.5,57.84 49.63,57.84 50.74,58.94 53.23,58.94 53.52,59.23 59.68,59.23 60.49,58.42 85.28,58.42 85.61,58.08 89.86,58.08 95.6,52.34 97.81,52.34 99,51.16 101.8,51.16 102.03,50.93 107.98,50.93 108.51,50.39 108.51,48.31 111.94,44.88 v1(111.94,43.87)
  BOTTOM w0.097: v1(37.85,11.81) 37.85,31.88 44.7,38.73 44.7,45.47 44.17,46 44.17,48.92 43.43,49.66 42.55,49.66 42.04,49.15 R215.1 41.97,48.64 41.08,48.64 R216.2 ; v1(66.24,10.37) 66.38,10.23 66.38,9.63 R751.1
  BOTTOM w0.102: v1(40.32,50.09) 40.77,49.65 40.77,48.64 R216.2
SMB_PECI_DATA_UART_RXD: length 185.1
  TOP w0.102: U14.AN65 114.26,41.73 112.31,41.73 v1(111.8,42.23)
  L3_SIG w0.097: v1(65.53,10.92) 64.88,11.57 59.68,11.57 59.01,10.9 40.02,10.9 v1(38.61,12.32)
  L5_SIG w0.097: v1(24,50.61) 24,50.5 24.94,49.56 35.41,49.56 36.3,48.67 39.7,48.67 40.26,49.22 v1(40.27,49.22) 40.33,49.22 40.71,49.6 41.7,49.6 42.82,50.72 42.82,52.02 43.81,53 43.81,55.44 44.04,55.68 44.73,55.68 46.02,56.97 51.01,56.97 51.72,57.68 85.02,57.68 85.32,57.38 89.57,57.38 95.63,51.32 95.63,49.84 95.99,49.47 98.42,49.47 98.59,49.3 101.83,49.3 102.03,49.1 106.02,49.1 106.35,48.77 106.88,48.77 110.11,45.54 110.11,42.67 110.64,42.13 111.7,42.13 v1(111.8,42.23)
  BOTTOM w0.097: R752.1 65.02,10.41 v1(65.53,10.92) ; v1(38.61,12.32) 38.61,31.5 45.47,38.35 45.47,47.5 44.7,48.26 44.7,49.02 43.05,50.67 39.75,50.67 39.5,50.42 39.5,49.78 40.06,49.22 v1(40.27,49.22) ; R201.1 v1(24,50.61)
  BOTTOM w0.102: v1(40.27,49.22) 40.26,49.21 40.26,49.15 39.82,48.71 39.82,48.52 R217.2
SMB_PMBUS_3V3STBY_CLK: length 66.9
  TOP w0.152: 51.57,34.42 51.18,34.42 50.55,35.05 v1(50.55,35.41) 50.83,35.69 ; U3.20 87.69,64.14 89.87,64.14 v1(90.35,63.65) 91.44,63.65 TP1.1
  TOP w0.157: U23.20 51.72,34.26 51.57,34.42 ; R74.2 50.83,36.39 50.83,35.69
  BOTTOM w0.152: v1(90.35,63.65) 90.5,63.5 90.5,60.74 90.47,60.72 90.47,60.54 88.77,58.83 83.48,58.83 83.05,58.39 67.33,58.39 57.38,48.44 57.38,40.36 54.36,37.34 52.96,37.34 51.03,35.41 v1(50.55,35.41) 50.16,35.79 R253.2
SMB_PMBUS_3V3STBY_DATA: length 68.3
  TOP w0.099: 89.51,63.65 v1(89.51,63.7)
  TOP w0.152: U3.19 87.21,63.54 87.5,63.25 89.15,63.25 89.51,63.6 ; C80.1 52.91,38.75 v1(52.91,38.33) 52.91,38.23 52.53,37.85 52.53,36.78 52.24,36.49 R72.2 51.94,36.3 51.28,35.64 51.28,35.2 52.12,34.37 U23.19 ; 89.51,63.6 89.51,63.65 ; 89.51,63.6 89.51,63.4 90.17,62.74 91.87,62.74 TP2.1
  BOTTOM w0.152: R249.2 53.09,38.51 v1(52.91,38.33) 53.26,37.97 54.01,37.97 56.85,40.8 56.85,48.62 56.87,48.64 56.87,48.69 67.11,58.93 82.83,58.93 83.26,59.36 88.54,59.36 89.94,60.76 89.94,62.59 89.51,63.02 v1(89.51,63.7)
SPI_CPLD_CLK: length 78.7
  TOP w0.254: v1(30.23,52.2) 30.8,51.62 U7.C15
  L3_SIG w0.152: v1(29.16,37.13) 30.05,38.02 32.89,38.02 33.39,38.53 v1(33.39,38.66)
  L8_SIG w0.152: v1(33.39,38.66) 33.4,38.66 33.4,42.39 29.84,45.95 29.84,47.5 30.23,47.88 v1(30.23,52.2) 29.84,52.58 29.84,64.9 32.11,67.16 59.05,67.16 62.05,64.16 v1(62.05,61.59)
  BOTTOM w0.152: R247.1 33.53,38.53 33.4,38.66 v1(33.39,38.66) ; R257.1 28.19,36.17 v1(29.16,37.13) ; JP5.6 61.34,59.44 62.13,60.22 62.13,61.52 v1(62.05,61.59)
SPI_CPLD_CS0_N: length 43.6
  TOP w0.099: v1(29.57,45.42) 29.57,44.74 R49.1 ; U7.D13 32.77,52.62 v1(32.33,53.06)
  L10_SIG w0.097: JP1.1 40.89,70.23 36.03,70.23 31.8,66 31.8,57.61 32.87,56.54 32.87,53.59 v1(32.33,53.06) 32.89,52.5 32.89,47.47 30.84,45.42 v1(29.57,45.42)
  BOTTOM w0.097: v1(29.57,45.42) 30.73,44.25 R232.2
SPI_CPLD_CS1_N: length 40
  TOP w0.099: U7.D15 30.33,53.11 v1(30.33,53.11)
  L10_SIG w0.097: JP1.3 36.5,71.37 30.73,65.6 30.73,53.51 v1(30.33,53.11) 30.81,52.63 30.81,49 29.34,47.52 v1(29.34,46.94)
  BOTTOM w0.097: R235.2 R229.1 35.75,41.67 35.28,42.14 33.63,42.14 29.34,46.43 v1(29.34,46.94)
SPI_CPLD_MISO_N: length 54.9
  TOP w0.099: U7.D14 31.82,52.52 v1(31.37,52.07)
  TOP w0.152: v1(30.68,46.89) 30.68,46.69 33.05,44.32 R48.2
  L8_SIG w0.152: v1(56.13,64.74) 55.52,64.74 53.67,66.6 32.61,66.6 30.86,64.85 30.86,52.58 v1(31.37,52.07) 30.73,51.44 30.73,46.94 v1(30.68,46.89)
  BOTTOM w0.152: v1(56.13,64.74) 56.13,63.25 54.86,61.98 JP5.7
SPI_CPLD_MOSI_N: length 69.1
  TOP w0.152: v1(32.26,52.07) 31.82,51.63 U7.C14
  L8_SIG w0.152: v1(32.28,38.58) 32.92,37.95 33.1,37.95 33.1,37.94 33.69,37.94 33.69,37.95 33.96,37.95 35.71,39.7 35.71,44.17 34.42,45.47 34.42,45.97 32.84,47.55 32.84,51.49 v1(32.26,52.07) 32.89,52.7 32.89,64.44 34.62,66.17 53.34,66.17 55.5,64.01 v1(57.02,64.01)
  BOTTOM w0.152: JP5.8 57.4,61.98 57.02,62.36 v1(57.02,64.01) ; R258.1 27.66,35.98 27.66,37.34 28.23,37.91 R248.1 32.38,38.48 v1(32.28,38.58)
SPI_CPU_CLK: length 74.4
  TOP w0.099: U7.E12 33.85,53.62 v1(34.32,53.16) ; v1(34.29,49.07) 34.29,48.95 35.2,48.03 38.35,48.03 38.84,47.55 43.48,47.55 43.97,48.03 46.04,48.03 46.81,48.81 46.81,51.03 47.18,51.4 48.73,51.4 49.43,52.1 52.53,52.1 52.8,51.82 66.36,51.82 66.75,51.82 72.54,57.61 89.51,57.61 90.93,56.18 90.93,54.79 93.25,52.47 R34.2
  L8_SIG w0.097: v1(34.32,53.16) 34.77,52.7 34.77,49.56 v1(34.29,49.07)
SPI_CPU_CLK_R: length 48.3
  TOP w0.099: R34.1 93.04,50.62 92.56,50.14 92.56,48.64 93.32,47.88 93.32,43.69 95.16,41.85 v1(95.16,41.47)
  TOP w0.254: U14.AF46 v1(123.56,38.65)
  L5_SIG w0.097: v1(95.16,41.47) 95.23,41.47 96.97,39.72 96.97,39.36 100.95,35.37 102.17,35.37 103.15,36.34 103.99,36.34 104.37,35.97 104.37,34.14 105.08,33.43 107.95,33.43 108.29,33.08 109.96,33.08 111,34.12 111,35.26 112.67,36.93 122.08,36.93 123.56,38.42 v1(123.56,38.65)
SPI_CPU_CS0_N: length 116.2
  TOP w0.099: U7.E14 31.41,53.22 v1(31.41,53.07) ; v1(107.26,27.28) 107.37,27.28 107.47,27.38 107.47,28.88 107.9,29.31 108.48,29.31 R96.2
  L5_SIG w0.097: v1(32.57,45.89) 32.72,45.89 34.74,43.88 42.45,43.88 42.67,44.09 48.18,44.09 49.96,45.87 49.96,51.59 50.33,51.96 54.24,51.96 55.24,52.96 55.26,52.96 55.77,53.47 81.38,53.47 83.7,51.16 83.7,37 84.43,36.27 92.95,36.27 93.73,35.49 95.14,35.49 96.09,34.54 96.09,31.29 97.74,29.64 101.32,29.64 104.14,26.82 106.81,26.82 v1(107.26,27.28)
  L8_SIG w0.097: v1(31.41,53.07) 31.8,52.69 31.8,47.14 32.56,46.38 32.56,45.9 v1(32.57,45.89)
SPI_CPU_CS0_R_N: length 9.4
  TOP w0.099: R99.1 109.81,29.74 R96.1 110.31,30.25 110.79,30.25 111.48,30.94 111.48,33.81
  TOP w0.102: 111.48,33.81 112.84,35.17 U14.Y65
SPI_CPU_CS1_N: length 114.2
  TOP w0.099: v1(105.79,29.46) 106.3,28.96 107.09,28.96 107.56,29.43 107.56,30.73 107.92,31.09 108.64,31.09 R93.2 ; U7.E13 v1(32.26,54.18)
  L3_SIG w0.097: v1(30.4,46.02) 30.51,46.02 31.09,45.45 34.75,45.45 35.6,46.29 37.44,46.29 37.55,46.41 45.64,46.41 47.24,48.01 53.37,48.01 59.8,54.43 82.22,54.43 85.87,50.79 85.87,35.85 90.39,31.33 94.49,31.33 96.5,29.31 99.81,29.31 100.13,28.99 100.13,28.99 100.17,28.96 103.66,28.96 104.57,29.87 105.38,29.87 v1(105.79,29.46)
  L10_SIG w0.097: v1(32.26,54.18) 31.85,53.77 31.85,49.07 30.2,47.42 30.2,46.23 v1(30.4,46.02)
SPI_CPU_CS1_R_N: length 12.5
  TOP w0.099: R93.1 110.37,30.82 v1(110.62,31.06)
  TOP w0.254: U14.AC58 v1(117.35,36.21)
  L5_SIG w0.097: v1(110.62,31.06) 110.62,31.14 110.03,31.72 110.03,32.61 110.67,33.25 110.85,33.25 114.22,36.63 117.02,36.63 117.35,36.3 v1(117.35,36.21)
SPI_CPU_MISO_N: length 133.4
  TOP w0.099: v1(116.62,37.65) 116.98,37.3 U14.AD59
  L3_SIG w0.097: v1(25.15,39.12) 25.26,39.12 29.97,34.41 29.97,33.4 30.35,33.02 31.75,33.02 33.02,31.75 39.88,31.75 41.27,30.35 42.55,30.35 46.1,26.8 52.2,26.8 53.34,25.65 59.82,25.65 61.72,23.75 v1(62,23.75)
  L8_SIG w0.097: v1(70.38,28.4) 67.8,28.4 63.15,23.75 v1(62,23.75) ; v1(103.5,21.92) 104.52,21.92 105.12,22.52 109.74,22.52 112.52,25.3 112.52,27.68 114.19,29.35 114.19,32.13 115.42,33.35 115.42,34.8 116.12,35.5 116.12,37.18 116.6,37.65 v1(116.62,37.65)
  BOTTOM w0.097: v1(70.38,28.4) 71.53,29.54 83.44,29.54 84.71,28.27 89.1,28.27 91.95,25.43 101.63,25.43 102.29,24.77 102.29,22.68 103.05,21.92 v1(103.5,21.92) ; R196.1 27.18,53.02 27.18,50.16 26.77,49.76 26.77,43.29 25.48,41.95 25.48,39.32 25.28,39.12 v1(25.15,39.12)
SPI_CPU_MOSI_N: length 116.1
  TOP w0.099: U7.E16 28.8,52.61 28.8,49.48 28.27,48.95 v1(28.27,46.63) ; R89.2 108.3,32.93 107.67,32.3 107.67,31.29 107.22,30.84 107.22,30.42 106.9,30.1 v1(106.9,29.57)
  L3_SIG w0.097: v1(28.27,46.63) 28.34,46.57 29.15,46.57 30.78,44.93 37.49,44.93 38.59,46.02 45.95,46.02 47.55,47.62 53.76,47.62 60.22,54.08 81.66,54.08 85.38,50.36 85.38,35.81 90.32,30.86 93.32,30.86 93.9,30.28 93.9,30.28 94.15,30.03 94.16,30.03 96.46,27.72 102.86,27.72 103.76,28.63 104.06,28.63 104.88,29.44 105.18,29.44 105.66,28.96 106.68,28.96 106.9,29.17 v1(106.9,29.57)
SPI_CPU_MOSI_R_N: length 8.4
  TOP w0.099: 109.84,33.04 109.84,32.98 R89.1
  TOP w0.102: U14.AB62 115.38,36.74 114.88,36.74 114.88,36.74 112.63,36.74 112.62,36.75 112.45,36.75 111.51,35.81 111.51,35.48 110.59,34.57 110.59,33.79 109.84,33.04
SPI_CS#: length 27.4
  TOP w0.152: JP1.2 40.77,70.1 41.94,70.1 42.8,69.24 42.8,67.23 43.81,66.22 54.94,66.22 55.19,65.96 55.19,63.78 56.08,62.89 v1(56.08,62.28)
  BOTTOM w0.152: v1(56.08,62.28) 56.08,60.66 54.86,59.44 JP5.5
SPI_GBE_CLK: length 8.7
  TOP w0.099: U24.6 106.1,31.76 106.1,30.79 105.28,29.97 105.28,29.36 106.48,28.17 v1(106.48,27.33)
  BOTTOM w0.097: v1(106.48,27.33) 106.48,27.13 108.06,25.54 R308.2
SPI_GBE_CS_N: length 7.5
  TOP w0.099: v1(104.33,24.28) 104.33,24.63 104.77,25.07 U24.1
  BOTTOM w0.097: R310.2 108.9,24.28 108.05,23.43 104.75,23.43 104.33,23.85 v1(104.33,24.28)
SPI_GBE_MISO: length 26.6
  TOP w0.254: U14.W60 116.63,34.45 116.88,34.22 v1(116.91,34.19)
  L3_SIG w0.097: v1(116.91,34.19) 116.91,32.07 117.28,31.7 118.09,31.7 118.77,31.02 118.77,28.57 118.31,28.11 118.31,26.86 116.85,25.4 116.53,25.4 115.9,24.77 112.05,24.77 111.84,24.56 107.52,24.56 106.73,25.35 104.28,25.35 v1(103.64,24.71)
  BOTTOM w0.097: R307.1 104.16,25.23 v1(103.64,24.71)
SPI_GBE_MISO_R: length 2.2
  TOP w0.099: U24.2 105.55,25.17 105.13,24.76 105.04,24.76 v1(105.01,24.73)
  BOTTOM w0.097: v1(105.01,24.73) 105.05,24.77 R307.2
SPI_GBE_MOSI: length 11.5
  TOP w0.099: U24.5 106.97,30.48 106.48,29.98 v1(106.3,29.98)
  L8_SIG w0.097: v1(106.3,29.98) 107.1,29.98 107.77,29.31 108.41,29.31 108.99,28.73 108.99,27.46 110.85,25.6 v1(110.85,25.43)
  BOTTOM w0.097: R300.2 112.02,26.42 111.02,25.43 v1(110.85,25.43)
SPI_MISO_P: length 1.9
  TOP w0.099: v1(30.3,54.05) 30.39,54.05 U7.E15
  BOTTOM w0.097: v1(30.3,54.05) 30.25,54.1 R196.2
SPI_SO_R: length 10.7
  TOP w0.099: U15.2 29.57,41.4 v1(29.77,41.2) ; v1(35.19,41.22) 35.23,41.22 35.41,41.4 U16.2 35.41,44.03 R48.1
  L3_SIG w0.097: v1(35.19,41.22) 35.19,41.26 34.42,42.04 30.61,42.04 v1(29.77,41.2)
SRTCST_N: length 18.8
  TOP w0.254: U14.AD49 v1(121.96,37.65)
  L5_SIG w0.097: v1(121.96,37.65) 121.55,37.24 118.74,37.24 118.74,37.24 112.43,37.24 111.1,35.92 109.68,35.92 109.3,35.53 109.3,34.18 109.72,33.76 v1(109.79,33.76)
  BOTTOM w0.097: v1(109.79,33.76) R267.1 109.94,33.05 111.02,33.05 111.32,32.75 C384.1
SUSPWRDNACK: length 11.8
  TOP w0.254: U14.Y57 v1(117.76,35.66)
  BOTTOM w0.097: 111.62,31 110.77,30.15 110.2,30.15 R282.1
  BOTTOM w0.102: 111.62,31 112.59,31.97 113.8,31.97 114.03,32.2 114.03,32.51 115.2,33.67 115.2,34.46 115.82,35.08 117.63,35.08 117.76,35.21 v1(117.76,35.66)
SVID_ALERT_N: length 88.2
  TOP w0.099: v1(106.76,51.74) 107.09,52.07 R29.2
  TOP w0.127: N10.1 55.6,35.56 55.6,36.52 R66.1
  TOP w0.152: R66.1 56.31,36.86 56.74,37.29 56.74,41.98 51.97,46.75 51.97,49.4 v1(51.52,49.85)
  TOP w0.157: v1(83.85,61.06) 83.86,61.08 R20.1
  L3_SIG w0.097: v1(83.85,61.06) 83.86,61.05 84.75,61.05 85.47,61.77 89.65,61.77 93.1,58.32 95.47,58.32 96.75,57.03 96.75,56.47 97.32,55.9 100.35,55.9 101.33,56.88 104.21,56.88 106.25,54.84 106.25,52.25 v1(106.76,51.74)
  L10_SIG w0.097: v1(51.52,49.85) 51.52,50.19 53.88,52.55 53.88,53.92 59.95,60 79.74,60 81.41,61.67 83.24,61.67 v1(83.85,61.06)
SVID_CLK: length 81.2
  TOP w0.099: v1(106.1,51.66) 106.1,51.49 106.64,50.94 N6.1 107.47,50.57 107.95,51.05 N5.2
  TOP w0.152: R70.1 54.66,40.49 v1(54.97,40.79)
  TOP w0.155: R21.1 v1(85.75,61.09)
  L3_SIG w0.097: v1(106.1,51.66) 105.87,51.89 105.87,54.58 104.09,56.36 101.7,56.36 100.76,55.42 94.92,55.42 89.99,60.35 86.49,60.35 v1(85.75,61.09)
  BOTTOM w0.152: v1(85.75,61.09) 84.97,60.3 82.8,60.3 82.5,59.99 66.17,59.99 61.62,55.45 57.34,55.45 56.59,54.7 56.59,52.62 55.12,51.15 55.12,40.94 v1(54.97,40.79)
  BOTTOM w0.254: R174.2 86.03,61.09 v1(85.75,61.09)
SVID_DATA: length 90.9
  TOP w0.099: R45.1 108.9,44.88 108.37,45.42 N7.2 108.37,45.55 107.98,45.95 106.2,45.95 105.52,45.26 100.3,45.26 100.15,45.11 98.15,45.11 97.97,45.29 96.85,45.29 96.52,45.62 v1(96.52,45.75)
  TOP w0.152: v1(53.77,38.56) 53.77,38.04 R73.1
  TOP w0.203: v1(96.56,61.13) 95.94,61.75 91.34,61.75 91.05,62.04 R23.2 89.78,62.03 87.87,62.03 87.67,61.82 R22.1 v1(87.67,60.83)
  BOTTOM w0.152: v1(53.77,38.56) 56.26,41.05 56.26,48.87 66.83,59.44 82.69,59.44 83.02,59.77 86.65,59.77 87.67,60.79 v1(87.67,60.83) ; v1(96.56,61.13) 95.94,60.5 95.94,58.04 96.85,57.12 96.85,55.73 95,53.87
  BOTTOM w0.157: 95,53.87 95,47.27 v1(96.52,45.75)
SW_VNN: length 9.7
  TOP w0.203: v1(68.43,33.17) 68.22,32.96 U20.9
  TOP w0.254: L7.1 75.14,35.5 v1(75.59,35.05)
  TOP w0.381: U19.1 69,33.29 ; 70.51,33.87 U18.8 ; U19.2 68.9,32.64 ; U18.4 71.46,33.64 ; U19.5 72.04,32.64
  TOP w0.762: U19.7 70.51,33.87
  BOTTOM w0.254: v1(75.59,35.05) 75.58,35.04 75.58,34.64 N44.1 ; 68.11,33.49 C364.2 67.98,33.61 68.11,33.49 ; 68.11,33.49 v1(68.43,33.17)
SYS_RST_N: length 123.6
  TOP w0.102: v1(35.31,48.79) 35.31,49.11 U7.A10
  L3_SIG w0.097: v1(89.03,7.62) 89.03,8.31 88.03,9.3 84.84,9.3 84.25,8.71 84.25,5.94 82.75,4.44 27.89,4.44 25.81,6.53 25.81,15.04 v1(25.55,15.29)
  L10_SIG w0.097: v1(35.31,48.79) 35.26,48.74 35.26,47.32 34.98,47.04 33.1,47.04 30.75,44.69 29.04,44.69 26.34,41.99 26.34,16.08 v1(25.55,15.29)
  BOTTOM w0.097: v1(89.03,7.62) 88.77,7.37 88.77,7.29 88.42,6.93 S1.B11
  BOTTOM w0.102: v1(35.31,48.79) 35.74,48.79 36.13,48.4 R218.2
SYSPWRGD_L: length 6.1
  TOP w0.099: v1(35.29,54.16) U7.E10
  BOTTOM w0.099: v1(35.29,54.16) 34.75,53.62 32.94,53.62 32.84,53.72 32.84,55.3 32.38,55.76 D10.2
TGND_VCCP: length 1.2
  BOTTOM w0.508: N39.1 63.47,42.04 v1(63.85,42.42)
TGND_VDDQ_CH01: length 1.3
  BOTTOM w0.508: v1(99.74,67.82) 100.07,67.49 N29.1
THERMAL_INT#: length 14.8
  TOP w0.099: v1(20.37,58.12) 20.07,57.81 U5.3 ; U7.J14 31.77,57.62 v1(31.37,57.23)
  L5_SIG w0.097: v1(31.37,57.23) 30.96,57.63 20.65,57.63 20.37,57.91 v1(20.37,58.12)
  BOTTOM w0.097: R187.2 20.37,57.52 v1(20.37,58.12)
TP_CPU_AJ31: length 1.3
  TOP w0.102: v1(131.56,40.24) U14.AJ31
  BOTTOM w0.097: TP10.1 130.82,40.24 v1(131.56,40.24)
TP_CPU_AL31: length 18
  TOP w0.102: U14.AL31 131.21,40.65 131.56,41 131.56,41.03 v1(131.58,41.06)
  L3_SIG w0.102: v1(125.16,51.8) 125.25,51.71 125.25,51.64 126.05,50.84 126.05,45.2 126.28,44.97 126.28,44.08 126.5,43.85 129.33,43.85 129.88,43.3 129.88,41.13 130.47,40.55 131.08,40.55 v1(131.58,41.06)
  BOTTOM w0.097: TP9.1 124.9,51.54 v1(125.16,51.8)
TP_CPU_AL32: length 20.3
  TOP w0.102: v1(130.77,41.06) 130.75,41.06 130.37,40.68 U14.AL32
  L3_SIG w0.102: v1(130.77,41.06) 130.59,41.06 130.14,41.51 130.14,43.52 128.97,44.69 128.26,44.69 127.65,45.3 127.65,50.55 123.76,54.44 v1(123.32,54.44)
  BOTTOM w0.102: v1(123.32,54.44) 123.12,54.64 123.12,55.84 122.45,56.5 TP7.1
UART0_RXD: length 5.1
  BOTTOM w0.107: S1.B32 65.37,5.8 65.41,5.84 65.41,8.32 R752.2
UART0_TXD: length 5
  BOTTOM w0.107: R751.2 66.29,8.57 66.29,3.83 S1.B31
UART1_SOC_RXD: length 179.4
  TOP w0.099: S1.A8 91.39,3.78 91.39,16.73 91.69,17.03 91.69,17.35 v1(91.64,17.4)
  TOP w0.254: U14.AG50 v1(121.57,38.23)
  L3_SIG w0.097: v1(121.57,38.23) 121.7,38.35 122.68,38.35 123.16,37.87 123.16,35.31 122.81,34.95 122.81,34.14 121.84,33.17 121.18,33.17 120.83,32.82 120.83,31.17 120.14,30.48 120.14,29.16 119.3,28.33 119.3,27.05 116.75,24.5 112.46,24.5 112.22,24.26 108.06,24.26 107.6,23.8 100.92,23.8 100.05,24.66 95.9,24.66 95.42,24.18 93.24,24.18 92.82,23.75 92.82,18.06 92.23,17.48 91.72,17.48 v1(91.64,17.4)
  L5_SIG w0.097: v1(121.57,38.23) 121.79,38.23 123.11,39.56 123.11,40.39 122.94,40.56 121.86,40.56 121.2,41.22 120.27,41.22 120.07,41.43 120.07,42.64 119.56,43.15 115.85,43.15 112.52,46.48 112.52,47.23 110.36,49.39 110.36,51.44 108.81,52.99 104.8,52.99 104.54,53.24 102.99,53.24 102.08,54.15 102.08,57.82 99.59,60.31 95.52,60.31 94.75,59.54 86.26,59.54 85.98,59.82 61.09,59.82 59.46,61.44 53.75,61.44 52.68,60.38 47.54,60.38 47.19,60.73 v1(47.07,60.73)
  BOTTOM w0.097: v1(47.07,60.73) 46.99,60.81 46.99,63.17 46.43,63.73 46.43,65.65 45.94,66.14 43.97,66.14 41,69.11 35.92,69.11 JP2.1 ; v1(121.57,38.23) 120.94,38.86 C327.2
UART1_SOC_TXD: length 194.5
  TOP w0.099: JP2.5 24.64,70.23 C13.1 ; v1(121.36,40.03) 121.36,39.88 U14.AH50 ; v1(91.9,16.66) 91.77,16.54 91.77,6.63 92.42,5.98 S1.A7
  L3_SIG w0.097: v1(121.36,40.03) 121.36,40.08 121.89,40.61 124.1,40.61 124.77,39.95 124.77,38.02 124.77,38.02 124.77,37.68 124.77,37.68 124.77,33.79 124.38,33.4 122.66,33.4 122.2,32.94 122.2,28.28 120.47,26.55 119.42,26.55 118.75,25.87 v1(118.75,25.83) 118.66,25.74 118.66,25.03 117.91,24.28 112.88,24.28 112.42,23.83 108.33,23.83 107.92,23.41 100.58,23.41 v1(100.3,23.14) ; v1(46.43,59.54) 46.43,59.87 43.81,62.48 43.81,67.69 41.27,70.23 24.64,70.23 JP2.5 ; v1(91.9,16.66) 91.91,16.66 93.17,17.92 93.17,17.93 93.22,17.98 93.22,23.14 93.6,23.52 v1(93.6,23.62)
  L5_SIG w0.097: v1(46.43,59.54) 46.43,58.85 46.71,58.57 49.38,58.57 50.45,59.64 52.94,59.64 53.88,60.58 59.32,60.58 60.78,59.12 85.57,59.12 85.9,58.79 90.19,58.79 95,53.97 98.35,53.97 98.71,54.33 100.49,54.33 103.2,51.61 104.94,51.61 105.48,52.15 108.23,52.15 109.4,50.98 109.4,48.34 114.85,42.88 114.85,42.05 115.26,41.64 115.76,41.64 116.2,41.2 119.63,41.2 120.14,40.69 120.7,40.69 v1(121.36,40.03)
  BOTTOM w0.097: v1(100.3,23.14) 100.3,23.39 99.06,24.64 94.61,24.64 v1(93.6,23.62) ; R303.1 118.47,26 118.63,25.83 v1(118.75,25.83)
USB_CPEN_GPIO_SUS17: length 127
  TOP w0.099: U7.T4 v1(41.35,64.16)
  TOP w0.102: U14.T58 117.76,33.31 117.43,32.97 116.31,32.97 116.23,32.89 115.61,32.89 115.42,32.7 115.42,32.26 v1(115.37,32.21)
  L5_SIG w0.097: v1(115.37,32.21) 115.83,31.74 119.19,31.74 120.19,30.73 120.19,29.13 119.02,27.97 117.5,27.97 117.06,27.53 115.34,27.53 114.48,26.67 113.03,26.67 112.47,26.11 109.94,26.11 109.42,26.64 108.11,26.64 108.03,26.55 103.94,26.55 101.23,29.26 97.61,29.26 95.66,31.21 95.66,34.34 94.86,35.14 93.59,35.14 92.81,35.92 84.28,35.92 83.35,36.86 83.35,51.01 81.24,53.12 55.92,53.12 54.2,51.4 v1(52.09,51.4)
  L8_SIG w0.097: v1(52.09,51.4) 52.09,51.96 54.99,54.86 54.99,59.26 53.47,60.78 49.58,60.78 46.79,63.58 41.92,63.58 41.82,63.67 41.82,63.69 v1(41.35,64.16)
USB_OBSP: length 2.1
  TOP w0.254: v1(121.97,41.66) 121.97,41.71 122.02,41.76 122.02,42 122.66,42.56 U14.AR48
  BOTTOM w0.203: v1(121.97,41.66) 121.97,41.53 122.02,41.48 122.02,41.02 121.91,40.91 R227.1
USB_OC_N: length 98.7
  TOP w0.102: v1(108.64,35.64) 108.66,35.66 108.76,35.66 109.07,35.97 109.58,35.97 109.86,36.25 109.86,36.63 110.49,37.26 111.19,37.26 111.26,37.34 111.6,37.34 111.71,37.23 113.88,37.23 114.04,37.39 114.04,37.41 114.14,37.52 114.5,37.52 114.86,37.15 U14.AD63
  TOP w0.152: U7.E5 40.82,53.7 v1(41.3,54.18)
  L3_SIG w0.097: v1(108.64,35.64) 108.51,35.64 107.92,35.05 105.04,35.05 104.55,34.56 104.55,33.53 104.14,33.12 101.65,33.12 100.06,34.71 97.32,34.71 96.21,35.82 96.21,41.59 95.4,42.39 95.4,46.22 94.36,47.26 94.36,52.75 89.33,57.78 84.39,57.78 84.34,57.84 56.18,57.84 55.96,58.06 51.84,58.06 50.02,56.24 48.65,56.24 v1(48.06,55.65)
  BOTTOM w0.097: v1(41.3,54.18) 41.57,54.18 43.63,56.24 47.22,56.24 47.8,55.65 v1(48.06,55.65)
USB_RCOMP: length 12.2
  TOP w0.254: U14.AT46 123.69,42.77 123.57,42.77 v1(123.49,42.7) 123.34,42.81 123.28,42.8 122.72,43.19 U14.AT48
  L3_SIG w0.097: v1(123.49,42.7) 123.49,42.82 120.81,45.51 120.81,46.46 120.26,47 120.26,47.88 120.64,48.26 121.17,48.26 121.9,47.53 v1(121.9,47.49)
  BOTTOM w0.097: v1(121.9,47.49) 121.41,47.97 121.41,48.7 C264.1
USB_SOC_DN0: length 80
  TOP w0.104: U14.BC45 124.35,46.61 124.74,46.61 v1(124.96,46.82)
  L8_SIG w0.104: v1(89.41,10.79) 89.78,11.16 89.78,12.82 86.05,16.54 86.05,18.46 87.94,20.35 89.84,20.35 91.17,21.67 91.17,24.19 92.33,25.35 97.24,25.35 97.96,26.07 107.02,26.07 108.36,24.74 110.89,24.74 111.59,25.44 111.59,33.28 114.8,36.49 114.8,36.97 116.95,39.12 122.28,39.12 123.39,40.23 124.1,40.23 124.84,40.97 124.84,44.17 123.93,45.09 123.93,46.08 124.32,46.47 124.66,46.47 124.93,46.74 124.93,46.81 124.94,46.82 v1(124.96,46.82)
  BOTTOM w0.104: S1.B10 89.42,6.35 89.57,6.51 89.57,9.54 89.82,9.79 89.82,10.38 v1(89.41,10.79)
USB_SOC_DP0: length 79.5
  TOP w0.104: v1(124.93,46.16) 124.81,46.28 124.55,46.28 U14.BA45
  L8_SIG w0.104: v1(90.42,10.79) 90.04,11.18 90.04,12.93 86.32,16.65 86.32,18.35 88.05,20.08 89.95,20.08 91.44,21.56 91.44,24.08 92.44,25.08 97.35,25.08 98.07,25.81 106.91,25.81 108.25,24.47 111,24.47 111.86,25.33 111.86,33.17 115.06,36.37 115.06,36.86 117.06,38.85 122.39,38.85 123.5,39.97 124.21,39.97 125.11,40.86 125.11,44.28 124.19,45.2 124.19,45.97 124.43,46.2 124.89,46.2 v1(124.93,46.16)
  BOTTOM w0.104: v1(90.42,10.79) 90.11,10.48 90.11,9.67 89.87,9.42 89.87,6.63 90.42,6.08 S1.B9
VNN: length 80.6
  TOP w0.254: U14.AF36 v1(128.37,37.85) U14.AD36 ; U14.AJ36 v1(128.37,39.45) U14.AG36 ; U14.AL36 v1(128.37,41.05) U14.AM36 ; U14.AF39 v1(126.77,37.85) U14.AD39 ; U14.AM41 125.97,41.84 v1(125.97,41.84) 125.96,41.84 U14.AM42 ; U14.AM34 U14.AM32 v1(130.77,41.85) U14.AM31 ; v1(133.17,41.85) U14.AM26 ; v1(132.37,41.84) 132.37,41.84 U14.AM28 ; v1(131.57,41.85) U14.AM29 ; v1(133.97,41.85) U14.AM25 ; U14.AL39 126.79,41.03 v1(126.77,41.03) 126.77,41.06 U14.AM39 127.56,41.84 v1(127.57,41.84) 127.57,41.84 U14.AM38 ; L7.2 78.9,34.95 v1(77.09,34.95) ; U14.AG39 v1(126.77,39.45) U14.AJ39
  TOP w0.381: v2(86.77,39.83) 86.74,39.85 C73.2 ; C85.2 84.84,38.99 ; C74.2 90.75,40.01 v2(90.55,39.8) ; C87.2 84.84,37.97
  L3_SIG w0.203: v1(125.97,41.84) 125.97,41.85
  L3_SIG w0.254: 125.97,41.85 124.97,42.85 124.97,44.03 124.1,44.9 124.1,46.91 v1(123.9,47.11)
  L10_SIG w0.381: v1(54.36,26.87) 54.36,27.69 55.8,29.13 57.83,29.13 58.62,29.92 61.44,29.92 61.72,30.2 69.06,30.2 69.57,30.71 69.57,31.18 71.98,33.59 71.98,37.9 72.95,38.86 78.61,38.86 79.38,38.1 79.38,36.96 79.76,36.58 86.06,36.58 v2(86.77,37.29)
  BOTTOM w0.254: N35.1 124.08,47.29 v1(123.9,47.11) ; v1(77.09,34.95) 77.09,34.29 N43.1
  BOTTOM w0.381: v1(93.52,41.91) 93.52,42.71 C298.2 ; v1(125.97,41.84) 125.77,41.64 C308.1 125.31,41 ; C297.2 98.31,43.45 98.17,43.31 v1(98.12,43.31) ; v1(128.37,37.85) 128.59,38.07 C329.1 ; C307.1 v1(126.77,41.03) ; R296.1 53.42,27.81 v1(54.36,26.87) ; 130.21,40.65 130,40.87 C310.1 130.12,41.21 v1(130.77,41.85)
  BOTTOM w0.508: C313.2 88.6,40.39 v2(88.04,39.83) ; C310.1 129.48,41.21
  vias: v1(125.17,37.85) v1(125.97,37.85) v2(86.77,38.56) v2(88.04,38.56) v2(88.04,37.29) v2(89.31,39.83) v2(89.31,38.56) v2(89.31,37.29) v2(90.58,38.56) v2(90.58,37.29)
VNN_RCSM: length 42.8
  TOP w0.203: v1(49.53,25.15) 49.16,25.51 R111.2
  TOP w0.254: R104.1 49.11,25.97 R111.2
  L8_SIG w0.152: v1(80.19,39.14) 80.19,39.09 79.63,38.53 79.63,33.95 75.1,29.42 67.27,29.42 62.79,24.94 61.01,24.94 59.92,26.04 50.42,26.04 v1(49.53,25.15)
  BOTTOM w0.152: v1(80.19,39.14) 80.38,39.33 R240.2
VNN_RCSP: length 41.3
  TOP w0.178: R111.1 50.09,25.96 50.09,26.84
  TOP w0.203: R111.1 50.05,25.51 v1(50.42,25.15) ; 50.09,26.84 R105.1
  L8_SIG w0.152: v1(80.24,38.23) 80.04,38.02 80.04,34.12 80.04,33.78 75.27,29.01 67.43,29.01 62.96,24.54 60.84,24.54 60.6,24.77 59.75,25.63 50.9,25.63 v1(50.42,25.15)
  BOTTOM w0.152: v1(80.24,38.23) 80.45,38.44 R240.1
VR_V1P1_SENSE: length 104.1
  TOP w0.254: v1(130.77,37.86) 130.38,38.25 U14.AF32
  L3_SIG w0.254: v1(75.21,16.66) 75.73,17.18 76.91,17.18 77.56,16.53 82.16,16.53 82.98,17.35 84.66,17.35 85.48,16.53 85.94,16.53 86.57,17.16 86.91,17.16 v1(87.19,17.44)
  L5_SIG w0.254: v1(130.77,37.86) 130.68,37.86 130.24,37.42 130.24,27.29 128.84,25.88 128.84,25.05 127.96,24.17 127.96,14.36 128.8,13.52 128.8,11.78 128.01,11 128.01,8.89 126.46,7.34 124.97,7.34 124.2,8.12 118.74,8.12 114.99,11.86 110.11,11.86 109.75,11.51 108.03,11.51 107.95,11.43 v1(107.72,11.43)
  L8_SIG w0.254: v1(87.19,17.44) 87.45,17.19 87.45,16.67 87.93,16.19 89.45,16.19 91.38,14.27 91.38,11.05 92.04,10.39 97.16,10.39 100.03,13.26 106.89,13.26 107.44,12.71 107.44,11.68 107.7,11.43 v1(107.72,11.43)
  BOTTOM w0.254: R327.2 74.71,17.16 v1(75.21,16.66) 72.16,16.66 71.44,15.94 R335.2 R331.2 C478.2
VR_VCCP_AVN_RTN: length 156.1
  TOP w0.254: v1(60.55,31.17) 60.21,31.51 N15.1 ; U14.AF2 v1(146.24,38.43)
  L8_SIG w0.254: v1(146.24,38.43) 146.11,38.56 146.11,38.63 146.11,38.63 146.11,40.25 145.89,40.47 145.89,44.91 146.83,45.84 150.04,45.84 151.63,47.44 151.63,52.14 147.57,56.2 147.57,61.49 145.71,63.36 141.26,63.36 139.6,61.7 139.6,60.12 138.04,58.56 129.81,58.56 128.55,59.83 128.55,62.2 127.48,63.27 122.65,63.27 121.23,64.69 118.95,64.69 v1(118.75,64.9)
  BOTTOM w0.254: v1(60.55,31.17) 60.83,31.44 60.83,32.74 61.43,33.35 61.43,35.93 57.96,39.4 57.96,48.13 67.47,57.63 83.55,57.63 83.8,57.89 89.69,57.89 92.08,60.27 92.08,61.79 93.99,63.7 98.73,63.7 99.75,64.72 111.12,64.72 111.46,64.39 115.24,64.39 115.57,64.72 118.57,64.72 v1(118.75,64.9) ; R242.2 147.18,38.48 147.12,38.54 146.35,38.54 v1(146.24,38.43)
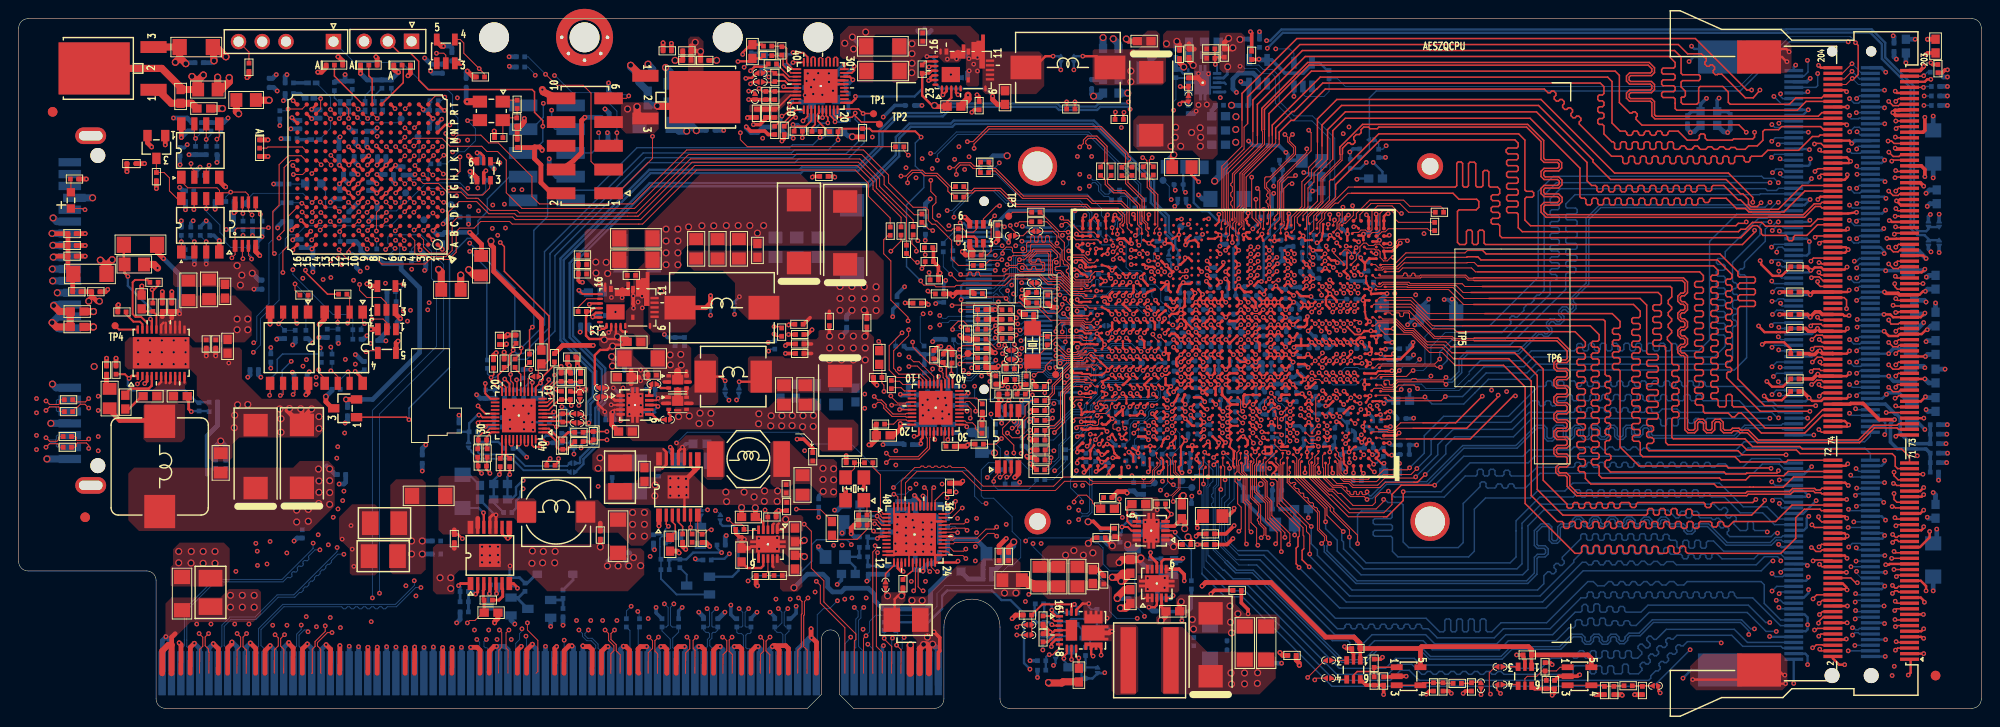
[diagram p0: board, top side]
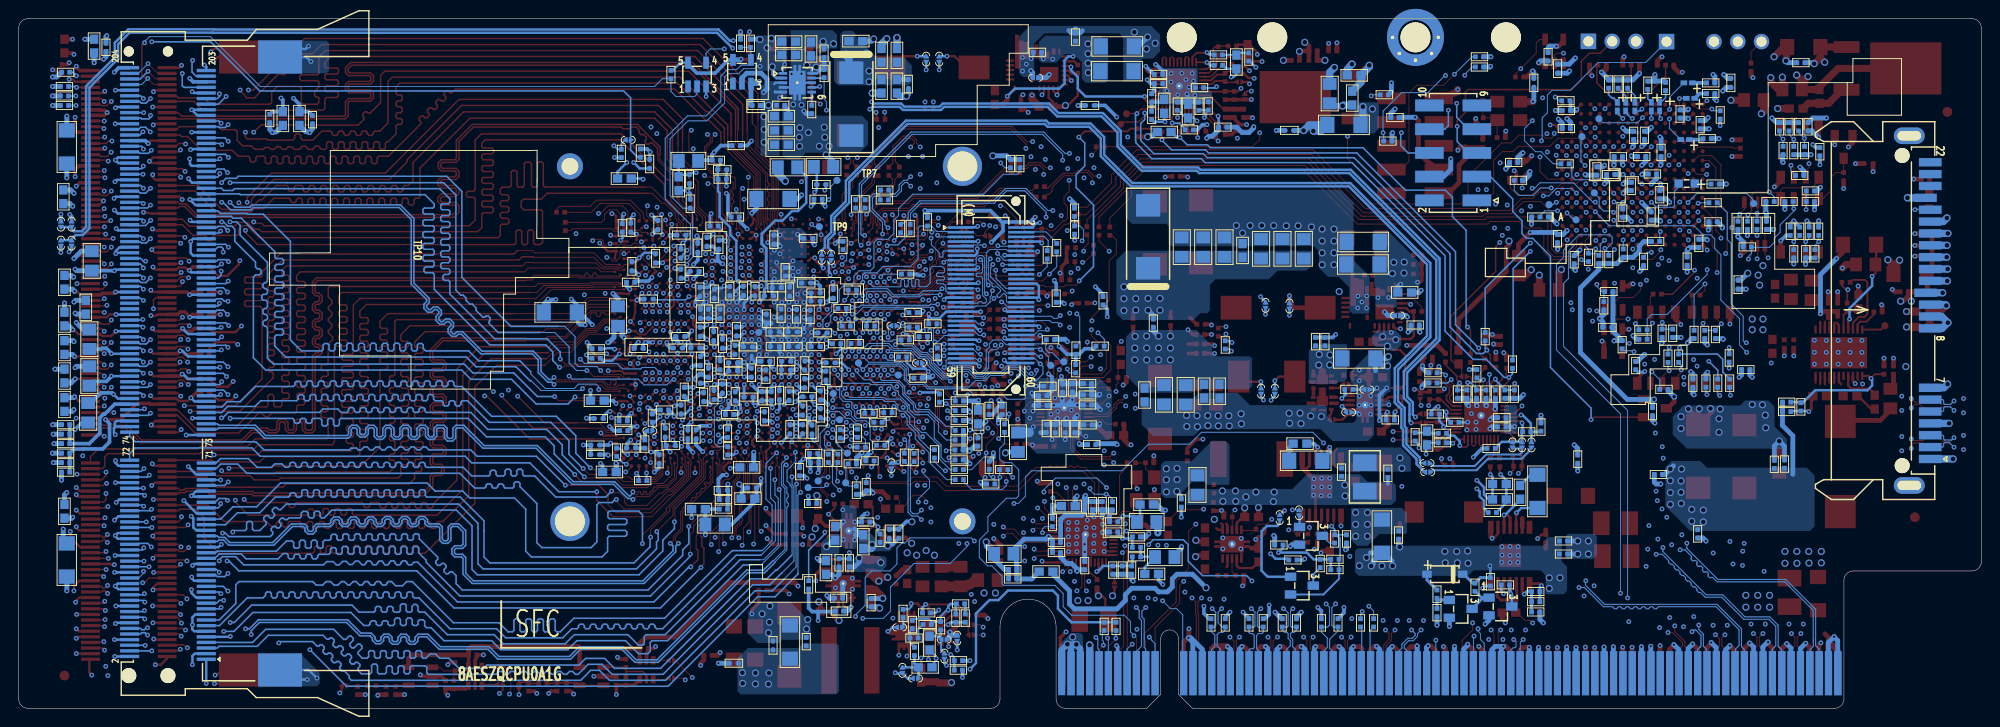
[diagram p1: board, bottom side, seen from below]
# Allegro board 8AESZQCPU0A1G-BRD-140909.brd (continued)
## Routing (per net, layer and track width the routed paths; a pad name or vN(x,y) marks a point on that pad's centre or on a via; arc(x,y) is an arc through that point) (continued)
VR_VCCP_AVN_VSEN: length 157.2
  TOP w0.254: U14.AE3 145.71,37.95 v1(145.73,37.93) ; v1(61.01,30.55) 60.99,30.53 60.07,30.53 N17.1
  L8_SIG w0.254: v1(145.73,37.93) 145.76,37.95 145.76,38.23 145.76,38.23 145.76,40.1 145.54,40.32 145.54,45.06 146.68,46.2 149.89,46.2 151.28,47.59 151.28,51.99 147.22,56.05 147.22,61.35 145.56,63 141.4,63 139.98,61.58 139.98,60 139.95,59.97 138.19,58.21 129.67,58.21 128.19,59.68 128.19,62.05 127.33,62.92 122.5,62.92 121.08,64.34 119.15,64.34 v1(118.92,64.11)
  BOTTOM w0.254: v1(61.01,30.55) 61.04,30.57 61.18,30.71 61.18,30.89 61.19,30.9 61.19,31.43 61.18,31.43 61.18,32.59 61.79,33.2 61.79,36.07 58.32,39.54 58.32,47.98 67.62,57.28 83.7,57.28 83.95,57.53 89.83,57.53 92.43,60.13 92.43,61.65 94.13,63.35 98.88,63.35 99.9,64.36 110.98,64.36 111.31,64.03 115.39,64.03 115.72,64.36 118.67,64.36 v1(118.92,64.11) ; v1(145.73,37.93) 145.76,37.93 146.49,37.19 147.49,37.19 R246.2
VR_VNN_RTN: length 11.9
  BOTTOM w0.203: N52.2 58.71,25.48 54.01,25.48 52.78,26.71 49.18,26.71 48.44,27.45 48.44,27.57 N49.1
VR_VNN_VSEN: length 12.1
  BOTTOM w0.203: N47.1 50.1,27.81 49.21,27.81 N48.1 49.15,27.38 49.36,27.17 52.97,27.17 54.2,25.93 58.69,25.93 N50.2
VREF_DQ_CH01_OP_FB: length 6.2
  TOP w0.152: R132.1 152.46,2.67 R136.2 R135.1 150.25,2.73 U33.4 U33.3
VREF_DQ_CH01_OP_FB_16766195: length 6.1
  TOP w0.099: U35.4 165.74,2.46
  TOP w0.152: R134.1 170.75,2.41 R138.2 R137.1 169.56,2.46 U35.4
VREF_DQ_CH01_RW: length 6.2
  TOP w0.152: U32.5 142.82,3.54 143.22,3.94 145.03,3.94 ; 145.03,3.94 R129.1 145.05,4.39 U33.1 ; 145.03,3.94 R131.2
VREF_DQ_CH01_RW_16766171: length 6.9
  TOP w0.099: R130.1 164.53,4 164.92,4.39 165.74,4.39 ; R130.1 163.32,3.56 163.45,3.43 R133.2 ; R130.1 163,4 162.43,3.43 161.42,3.43 161.16,3.17 U34.5
VREG_3.3V: length 3.4
  TOP w0.203: U17.18 14.74,42.09 R52.2 13.42,42.48 C66.2
VTT_CPU_DDR: length 18.8
  TOP w0.254: P1.204 192.84,68.55 192.58,68.8 v1(192.58,68.81)
  TOP w0.381: v1(204.09,69.98) 204.24,70.13 C2.1 ; C14.1 204.79,68.9 v1(204.6,69.09) ; P1.203 203.45,68.25 203.84,68.63 v1(203.84,68.71)
  BOTTOM w0.254: v1(190.14,68.84) 189.93,68.63 P4.203 ; U38.3 129.01,66.95 129.16,66.8
  BOTTOM w0.305: 129.08,65.98 129.04,65.95 U38.5
  BOTTOM w0.381: C210.1 178.98,63.86 C209.1 179.96,64.64 v1(180.59,65.28) ; C207.1 182.84,63.86 C208.1 181.74,65.1 v1(181.94,65.3) ; P4.204 199.29,68.55 v1(199.77,68.07)
  BOTTOM w0.508: v1(200.91,69.47) 200.66,69.72 C176.1 ; C174.1 v1(201.93,69.09) ; R164.1 129.79,64.52 v2(129.77,64.53)
  vias: v2(130.25,63.32) v2(130.22,61.94) v2(130.22,60.57)
XDP_CPU_PRDY_N: length 20.7
  TOP w0.254: U14.AW56 118.22,44.26 118.21,44.19 v1(118.17,44.16)
  L3_SIG w0.099: 118.21,44.2 118.58,44.56
  L3_SIG w0.102: 118.58,44.56 119.54,44.56 120.52,45.54 120.52,46.36 120.32,46.56 120.31,46.56 119.91,46.96 119.91,47.97 120.32,48.38 120.32,49.86 119.98,50.2 117.11,50.2 115.72,51.59 112.34,51.59 111.68,50.93 v1(111.68,50.62) ; v1(118.17,44.16) 118.21,44.2
  BOTTOM w0.097: v1(111.68,50.62) 111.51,50.45 P2.5
XDP_CPU_PREQ_N: length 16.2
  TOP w0.254: U14.AY53 v1(119.67,45.59)
  BOTTOM w0.097: P2.3 109.28,51.03 111.76,51.03 112.34,51.61 R198.1 113.57,51.61 113.77,51.41 113.77,48.1 114.58,47.3 116.92,47.3
  BOTTOM w0.102: v1(119.67,45.59) 119.7,45.62 119.7,46.39
  BOTTOM w0.114: 116.92,47.3 117.48,47.3 118.19,46.59 119.49,46.59 119.7,46.39
XDP_CPU_TCK: length 10.4
  TOP w0.099: v1(107.19,37.26) 107.11,37.26 106.54,36.69 R76.1 ; v1(110.97,36.47) 110.96,36.46 TP6.1
  TOP w0.102: U14.AD65 114.13,36.96 112.12,36.96 111.51,36.35 111.07,36.35 110.97,36.45 v1(110.97,36.47)
  BOTTOM w0.097: v1(107.19,37.26) 107.42,37.26 107.6,37.45 P2.57 110.53,37.45 110.77,37.21 110.77,36.65 110.94,36.47 v1(110.97,36.47)
XDP_CPU_TDI: length 29
  TOP w0.099: R69.1 102.12,37.97 TP5.1 101.22,37.62 v1(100.63,37.62)
  TOP w0.254: U14.AC56 118.48,36.6 v1(118.09,36.21)
  L10_SIG w0.097: v1(102.29,34.47) 102.36,34.54 102.36,36.75 101.36,37.76 100.86,37.76 100.78,37.68 100.69,37.68 v1(100.63,37.62)
  BOTTOM w0.097: v1(100.63,37.62) 100.69,37.68 100.82,37.68 100.83,37.69 100.96,37.69 101.22,37.95 P2.56
  BOTTOM w0.102: v1(102.29,34.47) 102.29,33.2 102.41,33.07 104.24,33.07 104.76,33.59 107.86,33.59 108.46,34.19 112.75,34.19 113.22,34.66 114.7,34.66 115.24,35.2 115.24,35.36 115.24,36.17 115.7,36.63 117.6,36.63 118.02,36.21 v1(118.09,36.21)
XDP_CPU_TDO: length 23.5
  TOP w0.102: v1(112.37,38.3) 112.37,38.31 112.52,38.31 112.75,38.07 113.16,38.07 113.31,38.23 113.69,38.23 114.02,38.56 114.93,38.56 U14.AF63
  L3_SIG w0.097: v1(112.37,38.3) 112.35,38.32 112.21,38.32 v1(110.31,36.42)
  BOTTOM w0.097: TP11.1 98.42,37.08 99.41,38.06 99.79,38.06 100.11,38.39 100.11,38.85 100.04,38.92 R236.1 100.49,39 102.68,39 P2.52 104.38,38.95 104.84,39.42 105.74,39.42 106.14,39.02 106.14,38.64 106.48,38.3 106.48,36.42 106.96,35.94 107.39,35.94 108.1,36.65 110.08,36.65 v1(110.31,36.42)
XDP_CPU_TMS: length 29.8
  TOP w0.099: R75.1 102.09,36.99 100.96,36.99 100.95,36.98 100.94,36.98 100.86,36.91 100.74,36.91 v1(100.69,36.86)
  TOP w0.254: U14.AC53 v1(119.67,36.25)
  BOTTOM w0.097: v1(119.67,36.25) 120.14,36.72 TP12.1 ; P2.58 101.28,37.45 100.88,37.05 100.88,37 100.78,36.91 100.74,36.91 v1(100.69,36.86)
  BOTTOM w0.102: v1(119.67,36.25) 119.08,36.83 115.6,36.83 115.04,36.27 115.04,35.28 114.62,34.86 113.13,34.86 112.66,34.39 108.31,34.39 107.62,35.08 106.58,35.08 106.05,35.61 104.62,35.61 103.99,36.25 103.11,36.25 101.91,35.05 101.14,35.05 100.41,35.79 100.41,36.58 v1(100.69,36.86)
XDP_CPU_TRST_N: length 39
  TOP w0.099: R64.1 102.3,38.81 100.98,38.81 100.69,38.52 v1(100.69,38.4)
  TOP w0.102: U14.AA46 v1(124.37,35.45)
  L3_SIG w0.097: v1(103.04,35.56) 103.21,35.38 104.06,35.38 104.18,35.5 107.58,35.5 110.03,37.95 110.03,39.09 110.62,39.67 114.02,39.67 115.27,38.43 116.69,38.43 116.97,38.71 122.78,38.71 123.65,37.85 123.65,36.17 v1(124.37,35.45)
  L10_SIG w0.097: v1(103.04,35.56) 103.04,38.14 102.77,38.4 v1(100.69,38.4)
  BOTTOM w0.097: TP13.1 99.82,36.96 99.82,37.59 100.08,37.85 100.08,37.85 100.4,38.18 100.41,38.18 100.63,38.4 v1(100.69,38.4) 100.69,38.42 100.79,38.53 102.64,38.53 P2.54
XDP_DFX_PORT0: length 21.9
  TOP w0.102: U14.BC64 114.13,46.77 113.61,47.29 v1(113.61,47.32)
  L3_SIG w0.102: v1(113.61,47.32) 113.54,47.4 112.52,47.4 111.99,47.93 111.99,48.63 111.59,49.03 110.17,49.03 110.05,49.15 110.05,50.37 109.95,50.47 109.59,50.47 109.49,50.37 109.49,49.3 109.38,49.2 109.18,49.2 109.08,49.3 109.08,50.37 108.98,50.47 108.77,50.47 108.67,50.37 108.67,49.3 108.57,49.2 108.37,49.2 108.27,49.3 108.27,50.37 108.16,50.47 107.94,50.47 107.84,50.37 107.84,48.96 107.49,48.62 106.77,48.62 106.64,48.74 106.36,48.74 106.23,48.62 106.02,48.62 105.84,48.79 105.84,49.2 106.15,49.5 v1(106.68,49.5)
  BOTTOM w0.097: v1(106.68,49.5) 106.81,49.5 106.88,49.58 109.07,49.58 P2.9
XDP_DFX_PORT1: length 21.7
  TOP w0.254: U14.AY58 v1(118.15,45.59)
  L3_SIG w0.102: v1(118.15,45.59) 118.15,46.73 118.35,46.93 118.35,47.08 118.21,47.22 118.07,47.22 117.73,46.89 117.59,46.89 117.44,47.03 117.44,47.17 117.78,47.51 117.78,47.65 117.63,47.8 117.49,47.8 117.16,47.46 116.79,47.46 116.11,48.14 116.11,48.77 116.01,48.87 115.82,48.87 115.72,48.98 115.72,49.18 115.82,49.28 116.01,49.28 116.11,49.38 116.11,49.65 115.94,49.82 115.45,49.82 115.34,49.92 115.34,51.07 115.23,51.18 114.93,51.18 114.83,51.08 114.83,50.13 114.73,50.03 114.38,50.03 114.28,50.14 114.28,51.08 114.18,51.18 113.86,51.18 113.72,51.04 113.72,50.06 113.62,49.96 112.73,49.96 v1(112.37,50.32)
  BOTTOM w0.097: P2.11 111.01,48.95 111.11,48.85 111.11,48.38 111.2,48.29 111.4,48.29 111.49,48.38 111.49,48.76 112.34,49.61 112.34,50.29 v1(112.37,50.32)
XDP_DFX_PORT2: length 21.8
  TOP w0.254: U14.AW58 117.33,44.14 v1(117.32,44.15)
  L3_SIG w0.097: v1(111.02,47.73) 110.79,47.96 109.87,47.96 109.77,47.86 109.77,47.54 109.67,47.45 109.48,47.45 109.38,47.54 109.38,47.86 109.29,47.96 109.09,47.96 109,47.86 109,47.54 108.9,47.45 108.71,47.45 108.61,47.54 108.61,47.86 108.51,47.96 108.09,47.96 107.89,47.76 107.89,47.11 108.01,46.99 110.35,46.99 110.44,47.09 110.44,47.23 110.54,47.32 110.73,47.32 110.83,47.23 110.83,47.09 110.93,46.99 111.58,46.99 113.08,45.49 114.14,45.49 114.31,45.67 114.31,46.52 114.47,46.67 115.04,46.67 115.53,46.18 115.53,45.49 116.09,44.93 116.09,44.79 115.87,44.57 115.87,44.43 116,44.3 116.14,44.3 116.37,44.52 116.5,44.52 116.83,44.19 117.28,44.19 v1(117.32,44.15)
  BOTTOM w0.097: P2.15 110.75,47.95 110.97,47.73 v1(111.02,47.73)
XDP_DFX_PORT3: length 22.8
  TOP w0.254: U14.AR57 v1(118.5,42.17)
  L3_SIG w0.097: v1(106.45,44.35) 106.45,44.04 106.84,43.65 108.91,43.65 110.96,45.7 111.35,45.7 112.67,44.37 114.12,44.37 115.62,42.88 117.91,42.88 118.5,42.29 v1(118.5,42.17)
  BOTTOM w0.097: v1(106.45,44.35) 106.67,44.57 106.67,48.23 106.91,48.47 107.27,48.47 107.55,48.18 107.55,47.55 107.66,47.45 P2.17
XDP_DFX_PORT4: length 22.8
  TOP w0.254: U14.AT54 v1(120.02,43.64)
  L3_SIG w0.097: v1(107.37,44.78) 107.54,44.61 107.87,44.61 108.01,44.75 108.01,45.38 108.08,45.45 108.32,45.45 108.38,45.39 108.38,44.79 108.49,44.68 108.73,44.68 108.81,44.76 108.81,45.4 108.88,45.47 109.01,45.47 109.1,45.38 109.1,44.78 109.2,44.68 109.42,44.68 110.89,46.15 111.3,46.15 112.88,44.57
  L3_SIG w0.102: v1(120.02,43.64) 120.4,43.26 120.4,42.53 120.28,42.41 119.78,42.41 119.6,42.59 119.6,43.1 119.49,43.2 119.19,43.2 119.08,43.1 119.08,42.73 118.95,42.6 118.77,42.6 118.29,43.08 115.98,43.08 114.48,44.57 112.88,44.57
  BOTTOM w0.097: P2.27 107.53,44.95 v1(107.37,44.78)
XDP_DFX_PORT5: length 21.7
  TOP w0.254: U14.AY56 v1(118.91,45.59)
  BOTTOM w0.097: P2.29 110.59,44.45 110.8,44.66 110.8,45.16 111.07,45.44 111.69,45.44 111.78,45.54 111.78,45.73 111.69,45.83 111.05,45.83 110.95,45.92 110.95,46.12 111.05,46.21 111.69,46.21 111.78,46.31 111.78,46.5 111.69,46.6 111.05,46.6 110.95,46.7 110.95,47.04 111.2,47.29 112.24,47.29 112.47,47.06 112.47,45.51 112.87,45.11 113.57,45.11 113.67,45.2 113.67,45.8 113.77,45.9 113.96,45.9 114.06,45.8 114.06,45.2 114.15,45.11 114.35,45.11 114.44,45.2 114.44,45.8 114.54,45.9 114.73,45.9 114.83,45.8 114.83,45.2 114.93,45.11 115.12,45.11 115.21,45.2 115.21,45.8 115.31,45.9 115.5,45.9 115.6,45.8 115.6,45.2 115.7,45.11 118.58,45.11 118.91,45.44 v1(118.91,45.59)
XDP_DFX_PORT6: length 21.7
  TOP w0.099: 111.94,46.05 111.58,46.41 111.58,46.47 111.45,46.61 111.25,46.61 111.15,46.51 111.15,46.43 111.05,46.33 110.85,46.33 110.62,46.56 110.62,47.89 110.86,48.13 111,48.13 111.15,48.28 111.15,48.5 110.52,49.13 108.58,49.13 108.48,49.03 108.48,48.86 107.86,48.24 107.86,48.24 107.62,48 v1(107.08,48)
  TOP w0.102: 111.94,46.05 112.8,45.19 113.9,45.19 114.17,44.92 114.52,44.92 114.87,45.27 U14.AY63
  BOTTOM w0.097: v1(107.08,48) 106.98,48 106.87,47.9 106.87,46.67 106.97,46.58 107.45,46.58 107.55,46.48 107.55,46.29 107.45,46.19 106.97,46.19 106.87,46.09 106.87,44.49 106.85,44.47 106.85,44.18 106.46,43.79 106.46,43.52 106.62,43.36 106.84,43.36 107,43.52 107.23,43.52 107.39,43.36 109.11,43.36 P2.33
XDP_DFX_PORT7: length 21.7
  TOP w0.102: v1(115.34,44.67) U14.AW62
  L3_SIG w0.097: v1(115.34,44.67) 114.77,45.24 112.97,45.24 111.47,46.74 108,46.74 107.49,46.23 105.57,46.23 105.47,46.13 105.47,45.38 105.37,45.29 105.18,45.29 105.08,45.38 105.08,46.13 104.99,46.23 104.55,46.23 104.39,46.08 104.39,44.81 104.51,44.69 v1(105.81,44.69)
  BOTTOM w0.097: v1(105.81,44.69) 105.91,44.59 105.91,44.17 106.06,44.02 106.06,43.51 106.51,43.05 107.65,43.05 107.75,42.95 P2.35
XDP_DFX_PORT8: length 21.8
  TOP w0.254: U14.AY59 117.37,45.58 v1(117.38,45.63)
  L3_SIG w0.097: 115.38,48.17 115.38,48.03 115.2,47.84 115.2,47.55 115.31,47.44 115.49,47.44 115.68,47.63 115.82,47.63 115.96,47.49 115.96,47.36 115.76,47.16 115.76,47.03 115.9,46.89 116.03,46.89 116.15,47.01 116.3,47.01 116.86,46.44 117.21,46.44 117.38,46.28 v1(117.38,45.63) ; v1(105.23,49.5) 105.23,50.42 105.59,50.77 105.92,50.77 106.02,50.68 106.02,50.36 106.11,50.27 106.31,50.27 106.4,50.36 106.4,50.68 106.5,50.77 106.69,50.77 106.79,50.68 106.79,50.36 106.89,50.27 107.08,50.27 107.18,50.36 107.18,50.68 107.27,50.77 110.46,50.77 111.07,50.16 111.79,50.16 113.69,48.26
  L3_SIG w0.102: 113.69,48.26 115.29,48.26 115.38,48.17
  BOTTOM w0.097: P2.10 105.18,49.45 v1(105.23,49.5)
XDP_DFX_PORT9: length 21.7
  TOP w0.254: v1(116.18,43.54) 116.18,43.51 116.43,43.25 U14.AT60
  L3_SIG w0.097: v1(106.25,45.29) 106.25,45.41 106.78,45.95 107.7,45.95 108.18,46.43 108.45,46.43 108.55,46.33 108.55,45.92 108.65,45.82 108.84,45.82 108.94,45.92 108.94,46.33 109.03,46.43 109.22,46.43 109.32,46.33 109.32,45.92 109.42,45.82 109.61,45.82 109.71,45.92 109.71,46.33 109.8,46.43 111.39,46.43 113.02,44.81 114.6,44.81 115.87,43.54 v1(116.18,43.54)
  BOTTOM w0.097: P2.12 104.19,48.95 104.34,49.1 106.1,49.1 106.46,48.73 106.46,45.59 106.25,45.38 v1(106.25,45.29)
XDP_DFX_PORT10: length 21.7
  TOP w0.099: v1(105.27,48.68) 105.27,48.96 105.66,49.35 106.22,49.35 106.33,49.25 106.33,48.87 106.43,48.77 107.75,48.77 107.85,48.87 107.85,49.76 107.98,49.89 108.19,49.89 108.29,49.98 108.29,50.47 108.39,50.57 108.59,50.57 108.69,50.47 108.69,49.98 108.78,49.89 108.98,49.89 109.08,49.98 109.08,50.47 109.18,50.57 109.38,50.57 109.48,50.47 109.48,49.98 109.58,49.89 109.77,49.89 109.87,49.98 109.87,50.47 109.97,50.57 110.17,50.57 110.31,50.44 110.31,49.98 110.93,49.35 111.33,49.35 111.63,49.05 111.63,48.01 111.78,47.86 111.78,47.58 111.92,47.44 112.2,47.44 112.34,47.29 112.34,47.09 112.25,47 112.19,47 112.09,46.9 112.09,46.7 112.19,46.6 112.25,46.6 112.34,46.5 112.34,46.22 112.95,45.61
  TOP w0.102: 112.95,45.61 114.63,45.61 115.06,46.04 U14.BB63
  BOTTOM w0.097: v1(105.27,48.68) 104.54,47.95 P2.16
XDP_DFX_PORT11: length 23.1
  TOP w0.254: U14.AT59 v1(117.73,43.64)
  L3_SIG w0.097: v1(104.73,47.47) 104.93,47.27 104.93,46.79 105.21,46.51 106.44,46.51 106.62,46.69 106.62,46.82 106.24,47.21 106.24,47.54 106.42,47.72 106.56,47.72 106.9,47.38 107.04,47.38 107.89,48.23 111.35,48.23 111.56,48.03 111.56,47.43 113.09,45.89 113.76,45.89 113.93,46.06 113.93,46.96 114.19,47.22 114.98,47.22 115.88,46.32 115.88,45.55 116.75,44.68 117.58,44.68 117.75,44.5 117.75,43.71 117.73,43.69 v1(117.73,43.64)
  BOTTOM w0.097: v1(104.73,47.47) 102.75,47.47 P2.18
XDP_DFX_PORT12: length 21.6
  TOP w0.099: v1(105.46,46.89) 105.74,46.89 106.02,47.17 106.76,47.17 107.19,46.74 ; 109.47,47.74 109.68,47.74 109.78,47.64 109.78,46.84 109.68,46.74 108.51,46.74
  TOP w0.102: U14.AW64 114.1,44.66 114.05,44.61 112.79,44.61 111.47,45.92 110.44,45.92 110.22,46.15 110.22,48.61 110.11,48.72 108.91,48.72 108.31,48.12 108.31,47.84 108.41,47.74 108.78,47.74 108.89,47.84 108.89,48.01 108.99,48.11 109.19,48.11 109.29,48.01 109.29,47.84 109.39,47.74 109.47,47.74 ; 108.51,46.74 107.19,46.74
  BOTTOM w0.097: P2.28 104.37,44.95 105.43,46.01 105.43,46.85 v1(105.46,46.89)
XDP_DFX_PORT13: length 21.6
  TOP w0.099: U14.AW66 112.79,44.89 111.56,46.13 110.69,46.13 110.42,46.4 110.42,48.83 110.32,48.93 108.83,48.93 108.11,48.2 108.11,47.76 108.33,47.54 109.43,47.54 109.58,47.4 109.58,47.09 109.42,46.94 108.91,46.94 108.81,47.04 108.81,47.2 108.71,47.29 108.52,47.29 108.42,47.2 108.42,47.04 108.32,46.94 108,46.94 107.87,47.07 107.87,47.23 107.52,47.59 106.95,47.59 106.76,47.4 105.99,47.4 105.89,47.5 v1(105.77,47.5)
  BOTTOM w0.097: v1(105.77,47.5) 105.79,47.47 105.79,47.38 106.02,47.15 106.02,46.17 104.3,44.45 P2.30
XDP_DFX_PORT14: length 21.7
  TOP w0.099: 107.61,48.44 107.78,48.44 108.28,48.94 108.28,49.56 108.38,49.66 110.31,49.66 111.43,48.54 111.43,47.37 111.33,47.27 111,47.27 110.9,47.17 110.9,46.96 111,46.86 111.48,46.86 111.78,46.56 111.78,46.49 112.14,46.13 ; v1(106.05,48.11) 106.38,48.44 107.51,48.44
  TOP w0.102: 107.61,48.44 107.51,48.44 ; U14.AY65 114.16,45.41 112.87,45.41 112.14,46.13
  BOTTOM w0.097: P2.34 102.75,43.42 104.17,43.42 104.3,43.55 104.3,44.13 104.53,44.36 104.66,44.36 105.05,43.97 105.19,43.97 105.33,44.1 105.33,44.24 104.94,44.63 104.94,44.77 105.27,45.1 105.75,45.1 105.84,45.19 105.84,45.46 106.25,45.86 106.25,47.81 106.05,48.02 v1(106.05,48.11)
XDP_DFX_PORT15: length 22.4
  TOP w0.254: U14.AR59 v1(117.73,42.17)
  L3_SIG w0.097: v1(117.73,42.17) 117.23,42.67 115.44,42.67 115.2,42.91 115.06,42.91 114.82,42.67 114.68,42.67 114.55,42.81 114.55,42.94 114.79,43.19 114.79,43.32 114.65,43.46 114.52,43.46 114.27,43.22 114.14,43.22 114,43.35 114,43.49 114.24,43.73 114.24,43.87 113.97,44.15 112.53,44.15 111.38,45.29 111.01,45.29 110.28,44.56 110.28,42.93 110.13,42.77 109.79,42.77 109.7,42.87 109.7,43.22 109.58,43.34 109.37,43.34 109.27,43.24 109.27,43.02 109.13,42.87 108.91,42.87 108.81,42.97 108.81,43.21 108.68,43.34 108.48,43.34 108.38,43.24 108.38,43.01 108.23,42.86 108.09,42.86 107.6,43.35 105.04,43.35 104.98,43.42 104.91,43.42 v1(104.83,43.49)
  BOTTOM w0.097: P2.36 104.19,42.95 104.65,43.42 104.76,43.42 v1(104.83,43.49)
XDP_DFX_PORT_CLK0: length 19.8
  TOP w0.102: U14.AV63 114.92,43.87 114.02,43.87 113.72,44.17 112.52,44.17 111.35,45.34 110.13,45.34 109.19,46.28 105.97,46.28 105.44,45.75 100.43,45.75 v1(99.71,46.47)
  BOTTOM w0.097: v1(99.71,46.47) 98.93,47.24 98.93,48.85 R209.2
XDP_DFX_PORT_CLK1: length 17.7
  TOP w0.102: v1(100.79,46.43) 100.79,46.35 100.86,46.28 101.48,46.28 101.58,46.38 101.58,46.58 101.68,46.69 101.89,46.69 101.99,46.58 101.99,46.38 102.09,46.28 102.29,46.28 102.39,46.38 102.39,46.58 102.5,46.69 102.7,46.69 102.8,46.58 102.8,46.38 102.9,46.28 105.44,46.28 105.64,46.48 109.3,46.48 110.1,45.68 111.37,45.68 112.65,44.4 113.99,44.4 U14.AV65
  BOTTOM w0.097: v1(100.79,46.43) 99.95,47.27 99.95,48.08 R214.2
XDP_PWRGD: length 3.6
  TOP w0.099: R61.2 106.3,39.6 106.35,39.65 106.53,39.65 106.73,39.85 v1(106.73,39.95)
  BOTTOM w0.097: P2.45 107.82,40.45 107.28,39.9 106.78,39.9 v1(106.73,39.95)
XDP_RSMRST_N: length 69.7
  TOP w0.099: v1(99.87,43.1) 99.92,43.15 102.18,43.15 102.29,43.26 104.48,43.26 105.08,42.65 R53.1
  TOP w0.102: U7.G2 v1(44.32,55.12)
  L5_SIG w0.097: v1(99.87,43.1) 99.58,43.1 98.93,43.74 96.24,43.74 95.33,44.65 94.49,44.65 93.58,45.56 93.58,46.32 85.27,54.64 83.81,54.64 82.86,55.58 54.56,55.58 53.8,54.81 50.4,54.81 49.75,54.15 48.67,54.15 v1(48.23,53.72)
  L8_SIG w0.097: v1(44.32,55.12) 44.32,55.28 44.74,55.7 45.39,55.7 45.95,55.14 45.95,54.84 47.09,53.7 48.21,53.7 v1(48.23,53.72)
XDP_RSMRST_R_N: length 3.7
  TOP w0.099: v1(106.75,41.78) 106.75,41.89 106.1,42.54 R53.2
  BOTTOM w0.097: v1(106.75,41.78) 106.92,41.95 P2.39
N16766151: length 1.6
  TOP w0.152: U34.3 N22.2
N16766163: length 1.7
  TOP w0.152: U34.4 160.31,2.54 N24.2
N16766213: length 2.2
  TOP w0.152: R134.2 173.67,2.41 C169.1 173.8,2.41 N26.1
N16797885: length 2.1
  TOP w0.157: v1(144.85,27.14) 144.84,27.15 144.84,27.2 144.48,27.57 U14.E5
  BOTTOM w0.178: R298.1 145.78,27.86 145.07,27.14 v1(144.85,27.14)
N16797887: length 2.3
  TOP w0.157: U14.C5 144.98,26.23 144.98,26.12 v1(144.98,26.12)
  BOTTOM w0.178: R298.2 145.33,26.27 145.13,26.27 144.98,26.12 v1(144.98,26.12)
N16797893: length 1.6
  TOP w0.178: U14.A8 v1(142.83,25.18)
  BOTTOM w0.178: v1(142.83,25.18) 142.83,24.4 R311.1
N16797895: length 1.8
  TOP w0.178: v1(143.89,25.15) 143.64,25.4 U14.A6
  BOTTOM w0.178: v1(143.89,25.15) 143.64,24.89 143.64,24.4 R311.2
N16797957: length 9.1
  TOP w0.102: U14.T26 133.3,32.87 v1(133.3,32.13)
  L3_SIG w0.152: v1(133.3,32.13) 133.46,31.96 133.46,30.26 133.86,29.87 v1(133.86,25.68)
  BOTTOM w0.152: 132.77,25.78 R306.1 133.76,25.78 v1(133.86,25.68)
N16797963: length 8.4
  TOP w0.102: v1(134.02,33.74) 134.02,33.66 134.41,33.28 U14.T25
  BOTTOM w0.097: v1(134.02,33.74) 134.47,33.29 134.47,32.92 134.79,32.6 135.14,32.6 135.56,32.18 135.56,28.37 135.19,28 C425.1
N16797972: length 2.5
  TOP w0.102: v1(130.98,31.78) 130.98,31.81 130.75,32.03 130.75,32.98 130.45,33.28 U14.T32
  BOTTOM w0.152: v1(130.98,31.78) 130.92,31.72 R274.1
N16826964: length 1.6
  TOP w0.099: N21.2 U32.3
N16835626: length 1.7
  TOP w0.099: U32.4 140.6,3.1 N23.2
N16835653: length 2.2
  TOP w0.152: N25.1 156.4,2.79 155.51,2.79 C168.1 155.38,2.67 R132.2
N16856509: length 11.6
  TOP w0.099: 144.25,54.07 144.56,54.38 148.19,54.38 148.84,53.72 152.15,53.72 152.46,53.4 R27.1
  TOP w0.102: 144.25,54.07 143.13,52.95 143.13,52.47 U14.BP8
N16856512: length 9.7
  TOP w0.102: U14.BP6 143.51,52.29 143.51,52.83 144.7,54.02 147.79,54.02 148.72,53.09 R27.2
N16856524: length 10.1
  TOP w0.099: R30.1 147.64,52.01 147.32,52.32 147.32,52.83 146.81,53.35 146.06,53.35 145.65,52.94 145.65,51.17 145.41,50.92 144.83,50.92 144.77,50.85
  TOP w0.102: U14.BK5 144.77,50.85
N16856527: length 6.7
  TOP w0.099: U14.BK3 145.41,50.54 145.86,51 146.22,51 146.55,51.32 150.75,51.32 150.95,51.12 R30.2
N16858306: length 27
  TOP w0.254: v1(136.42,44.18) 136.42,44.23 U14.AW21
  L10_SIG w0.203: v1(136.42,44.18) 136.28,44.18 136.21,44.26 134.3,44.26 133.64,44.92 131.89,44.92 131,45.8 131,49.59 132.17,50.76
  L10_SIG w0.254: 132.17,50.76 135.33,53.92 138.25,53.92 140.94,56.62 v1(143.19,56.62)
  BOTTOM w0.254: R188.1 143.32,56.69 143.24,56.62 v1(143.19,56.62)
N16858466: length 7
  TOP w0.102: U14.BA26 133.47,45.62 133.78,45.93 133.79,45.93 v1(133.82,45.96)
  BOTTOM w0.097: 134.16,50.61 134.16,50.58 134.01,50.43 134.01,50.23 133.96,50.18 133.96,49.85 134.01,49.8 134.01,49.39 134.22,49.18 134.22,48.85 134.22,48.84 134.22,48.08 134.19,48.05 134.19,47.69 134.22,47.66 134.22,47.33 134.23,47.33 134.23,46.6 134.24,46.58 134.24,46.38 133.82,45.96 v1(133.82,45.96)
  BOTTOM w0.102: 134.16,50.61 C250.1
N16858576: length 5.7
  TOP w0.254: v1(138.28,44.07) 137.17,44.12 U14.AW20
  BOTTOM w0.152: v1(138.28,44.07) 138.63,43.71 142.04,43.71 R223.1
N16872739: length 1.4
  TOP w0.254: U14.BC38 v1(127.16,47.11)
  BOTTOM w0.381: R219.1 127.21,47.16 v1(127.16,47.11)
N16872742: length 1.4
  TOP w0.254: U14.BA38 v1(127.16,46.35)
  BOTTOM w0.381: v1(127.16,46.35) 127.23,46.27 R219.2
N16874707: length 12.2
  TOP w0.099: U14.R59 116.81,32.44 116.81,32.05 116.31,31.55 115.6,31.55 v1(115.39,31.34)
  BOTTOM w0.097: R310.1 110.71,24.47 112.6,26.36 112.6,27.36 114.07,28.84 114.07,29.48 114.94,30.35 114.94,31.02 115.26,31.34 v1(115.39,31.34)
N16874710: length 14.8
  TOP w0.254: U14.W51 v1(121.57,34.26)
  BOTTOM w0.097: 113.78,29.56 113.67,29.46 113.67,28.9 112.45,27.67 R300.1
  BOTTOM w0.102: 113.78,29.56 114.66,30.44 114.66,31.2 115.25,31.79 115.74,31.79 115.93,31.98 115.93,32.46 116.31,32.84 117.35,32.84 117.55,33.05 121.51,33.05 121.95,33.48 121.95,33.88 v1(121.57,34.26)
N16874713: length 17
  TOP w0.254: U14.T50 121.44,33.6 121.42,33.62 v1(121.42,33.62)
  BOTTOM w0.102: R308.1 110.33,25.54 111.51,26.72 111.51,28.07 112.94,29.51 113.41,29.51 114.14,30.24 114.14,31.08 114.92,31.86 114.92,32.33 114.96,32.37 114.96,32.38 115.68,33.1 117.22,33.1 117.37,33.25 121.04,33.25 v1(121.42,33.62)
N16877224: length 4.4
  TOP w0.254: v1(117,38.21) 116.76,38.46 U14.AG60
  BOTTOM w0.097: N41.1 114.03,36.96 114.27,37.2 114.27,37.72
  BOTTOM w0.102: v1(117,38.21) 116.87,38.07 114.63,38.07 114.27,37.72
N16885695: length 1.4
  TOP w0.254: U14.R55 v1(118.91,32.27)
  BOTTOM w0.254: R272.1 118.58,31.86 118.91,32.19 v1(118.91,32.27)
N16885698: length 1.3
  TOP w0.254: U14.R53 v1(119.67,32.27)
  BOTTOM w0.254: R272.2 119.47,32.07 v1(119.67,32.27)
N16894176: length 7.8
  TOP w0.099: R63.2 109.36,39.8 X2.2
  TOP w0.102: U14.AJ65 113.98,39.67 113.77,39.88 110.14,39.88 R63.2
  TOP w0.508: C71.1 108.62,40.77 X2.2
N16894194: length 11
  TOP w0.099: 107.8,36.25 C98.1 ; 107.8,36.25 X2.1 ; 107.8,36.25 107.8,36.43 X2.1 ; X2.1 110.06,38.69 R63.1 110.23,38.91 110.97,39.65
  TOP w0.102: U14.AJ63 114.92,39.36 113.92,39.36
  TOP w0.114: 113.92,39.36 113.64,39.65 110.97,39.65
N16894680: length 8.8
  TOP w0.254: U14.AD55 v1(118.91,37.65)
  L5_SIG w0.097: v1(113.28,38.64) 113.28,38.5 113.4,38.38 116.2,38.38 116.63,38.81 117.75,38.81 117.9,38.66 118.69,38.66 118.91,38.45 v1(118.91,37.65)
  BOTTOM w0.097: v1(113.28,38.64) 113.65,39.01 113.66,39.02 C323.1
N16894802: length 2
  TOP w0.254: v1(116.98,39.7) 116.98,39.7 116.98,39.61 U14.AH60
  BOTTOM w0.097: N40.1 116.81,40.94 116.94,40.82 116.94,39.74 v1(116.98,39.7)
N16898105: length 1.4
  TOP w0.254: U14.AG46 v1(123.56,39.45)
  BOTTOM w0.305: v1(123.56,39.45) 123.13,39.02 R238.1
N16898543: length 11.6
  TOP w0.099: 112.55,46.4 112.55,47.4 111.89,48.06 111.89,49.85 111.28,50.45 111.28,50.8 110.01,52.07 R29.1
  TOP w0.102: U14.BC62 115.16,46.74 114.69,46.27 114.69,46.05 114.49,45.85 113.11,45.85 112.55,46.4
N16898546: length 11
  TOP w0.099: v1(111.1,49.76) 111.08,49.78 111.08,50.59 110.62,51.05 N5.1
  TOP w0.254: v1(116.87,46.01) 116.63,46.22 U14.BB60
  L5_SIG w0.097: v1(111.1,49.76) 111.3,49.76 111.4,49.67 112.56,49.67 113.72,48.51 113.72,48.25 115.85,46.13 116.75,46.13 v1(116.87,46.01)
N16898549: length 12.6
  TOP w0.099: v1(111.2,44.91) 109.64,44.91 N7.1
  TOP w0.254: U14.AW53 119.93,44.43 119.69,44.19 v1(119.69,44.18)
  BOTTOM w0.102: v1(111.2,44.91) 111.42,44.68 113.24,44.68 113.68,44.24 116.36,44.24 117.03,44.91 119.4,44.91 119.67,44.64 119.67,44.22 119.68,44.21 119.68,44.18 v1(119.69,44.18)
N16918882: length 2
  TOP w0.099: v1(105.95,32.94) 105.55,32.54 U24.7
  BOTTOM w0.097: R269.1 106.17,32.72 v1(105.95,32.94)
N16925199: length 4.4
  BOTTOM w0.097: P2.4 101.55,50.95 101.52,50.98 100.07,50.98 98.93,49.84 R209.1
N16925202: length 4.2
  BOTTOM w0.097: R214.1 99.95,49.4 99.95,49.4 99.85,49.5 99.85,50.06 100.29,50.51 101.55,50.51 101.61,50.45 P2.6
N16945830: length 96.6
  TOP w0.254: v1(129.98,37.84) U14.AF34
  L3_SIG w0.254: v1(76.04,16.54) 76.33,16.83 76.77,16.83 77.42,16.18 82.31,16.18 83.13,16.99 84.51,16.99 85.33,16.18 86.09,16.18 86.72,16.81 87.46,16.81 v1(88.11,17.46)
  L5_SIG w0.254: v1(108.08,12.19) 108.41,11.86 109.61,11.86 109.96,12.22 115.14,12.22 118.89,8.47 124.35,8.47 125.12,7.7 126.31,7.7 127.65,9.04 127.65,11.14 128.44,11.93 128.44,13.38 127.61,14.21 127.61,24.32 128.48,25.2 128.48,26.03 129.89,27.44 129.89,37.75 v1(129.98,37.84)
  L8_SIG w0.254: v1(108.08,12.19) 107.95,12.32 107.95,12.7 107.04,13.61 99.88,13.61 97.01,10.75 92.18,10.75 91.73,11.2 91.73,14.41 89.6,16.55 88.08,16.55 87.81,16.82 87.81,17.16 v1(88.11,17.46)
  BOTTOM w0.254: R332.2 74.23,16 75.51,16 v1(76.04,16.54)
N17019721: length 6.3
  TOP w0.099: U27.1 92.56,20.8 92.2,21.16 92.2,24.99 91.4,25.8 R109.2
N17019726: length 3.1
  TOP w0.099: R109.1 90.23,26.26 C116.1 89.43,25.66 X3.3
N17019783: length 4.4
  TOP w0.099: X3.1 90.76,21.94 C125.1 91.14,21.06 91.94,21.06 92.25,20.74 92.25,20.55 92.4,20.4 U27.2
N17020063: length 2.6
  TOP w0.099: R113.1 99.51,23.11 98.93,23.11 98.06,22.24 U27.37
N17022785: length 2.3
  TOP w0.157: U27.18 95.66,14.71 94.64,13.94 R126.2
N17022924: length 7.5
  TOP w0.099: U27.4 92.34,19.6 92.04,19.89 92.04,19.95 91.82,20.17 91.22,20.17 90.79,19.74 R119.1 90.79,19.16 89.71,18.08 87.45,18.08 R120.2
N17022990: length 2.5
  TOP w0.157: N18.1 92.75,14.39 93.66,15.3 U27.13
N17023227: length 3.2
  TOP w0.099: U27.31 98.9,18.85 100.41,18.85 v1(100.46,18.8)
  BOTTOM w0.097: v1(100.46,18.8) 100.46,19.18 100.19,19.44 R322.1
N17023993: length 2.4
  TOP w0.099: R82.1 93.49,34.32 94.41,34.32 94.76,33.96 U21.11
N17024019: length 3.2
  TOP w0.099: U21.10 96.26,34.65 94.61,34.65 94.26,35 93.46,35 R82.2
N17024141: length 3.1
  TOP w0.099: R95.2 102.87,29.43 102.36,29.95 102.36,30.25 102.06,30.56 101.45,30.56 101.24,30.76 U21.32
N17024148: length 2.7
  TOP w0.099: R91.2 102.49,33.2 100.7,33.2 U21.38
N17024192: length 3.8
  TOP w0.157: U21.2 99.52,35.25 99.26,35.51 99.26,36.5 98.81,36.95
  TOP w0.254: R65.2 98.23,37.4 98.68,36.95 98.86,36.95 R71.1
N17031771: length 4.8
  BOTTOM w0.254: L21.2 89.51,15.09 C473.1 88.44,16.21 R330.1 R328.1
N17058712: length 2.1
  BOTTOM w0.305: 59.31,14.35 59.31,13.73 R340.1
N17058714: length 2.5
  BOTTOM w0.305: R345.1 R340.2 58.06,11.59 U42.1
N17058720: length 3.5
  BOTTOM w0.305: 53.28,11.85 53.48,11.85 54.08,12.45 R338.2 ; 53.28,11.85 U41.1 ; 53.28,11.85 U42.3
N17058814: length 5.6
  TOP w0.305: U29.10 v1(51.07,20.69) 51.06,20.7 50.7,20.7 50.42,20.42 U29.11
  BOTTOM w0.254: C450.2 49.35,22.3 50.96,20.69 v1(51.07,20.69)
N17059267: length 3.6
  TOP w0.099: v1(27.81,41.15) 28.3,41.63 U15.3
  BOTTOM w0.097: R233.2 R234.1 28.45,40.51 v1(27.81,41.15)
N17059277: length 3
  TOP w0.099: U16.3 v1(34.14,41.3)
  BOTTOM w0.097: R231.1 R230.2 34.16,41.27 v1(34.14,41.3)
N17059466: length 2.1
  TOP w0.099: v1(29.36,33.58) 29.57,33.78 U15.7
  BOTTOM w0.097: v1(29.36,33.58) 29.46,33.68 R256.2
N17059528: length 3.5
  TOP w0.099: U16.7 35.41,35.84 v1(35.24,36)
  BOTTOM w0.097: v1(35.24,36) 34.4,35.17 R260.2
N17060112: length 11.9
  TOP w0.254: U17.6 15.24,34.92 14.99,34.67 ; U17.8 16.24,34.91 16.13,34.8 ; U17.9 16.74,34.69 ; U17.11 17.74,34.86 ; U17.10 17.24,34.7 ; U17.7 15.74,34.81
  TOP w0.508: R88.1 9.73,31.9 10.82,30.81 15.52,30.81 L10.1
N17060116: length 1.7
  TOP w0.508: R88.2 9.4,34.52 C92.1
N17060175: length 10.3
  TOP w0.254: v1(14.1,41.66) 14.24,41.51 U17.19 ; v1(11.68,46.23) 11.33,46.58 C53.1 11.25,47.57 R36.2
  BOTTOM w0.254: v1(11.68,46.23) 11.68,45.21 14.1,42.8 v1(14.1,41.66)
N17060208: length 8.1
  TOP w0.203: U17.20 13.74,41.25 13.11,41.88 12.5,41.88 12.19,42.19 12.19,45.59 12.45,45.85 13.78,45.85 R44.2
N17060212: length 3
  TOP w0.203: R55.2 11.49,42.16 12.28,41.38 12.98,41.38 13.24,41.12 U17.21
N17060239: length 4.4
  TOP w0.254: R90.1 11.34,33.57 11.34,33.59 11.96,34.21 13.92,34.21 14.24,34.53 U17.4
N17060256: length 2.5
  TOP w0.254: R90.2 11.79,32.03 13.06,33.3 13.21,33.3 C103.2
N17060272: length 3.8
  TOP w0.305: R87.1 18.03,33.02 18.19,32.87 18.19,32.03 v1(18.47,31.75)
  BOTTOM w0.254: C395.1 20.32,31.81 C389.2 18.53,31.81 v1(18.47,31.75)
N17062735: length 5.6
  TOP w0.762: v2(65.48,68.81) 66.6,67.69 Q2.1
  BOTTOM w0.762: v2(65.48,68.81) 65.48,68.63 R149.1 66.37,66.98 R161.2
N17064609: length 5.5
  TOP w0.762: Q1.1 14.68,65.94 15.14,65.94 16.33,64.74 R12.2 18.52,64.74 R14.2
N17089314: length 2.7
  TOP w0.254: v1(49.05,59.44) 49.4,59.44 49.76,59.08 U6.5
  BOTTOM w0.508: R183.1 49.59,58.93 49.08,59.44 v1(49.05,59.44)
N17090644: length 2.3
  TOP w0.099: U8.5 25.36,53.38 v1(25.86,52.88)
  BOTTOM w0.097: R199.2 26.04,52.7 v1(25.86,52.88)
N17142707: length 3.5
  TOP w0.099: v1(18.92,60.99) 18.8,61.11 U5.7
  BOTTOM w0.097: R171.2 19.56,61.62 v1(18.92,60.99) R179.1
N17142719: length 3.5
  TOP w0.099: U5.6 v1(20.07,60.88)
  BOTTOM w0.097: R178.1 v1(20.07,60.88) 20.57,61.39 R170.2
N17142732: length 3.6
  TOP w0.099: U5.5 21.46,61.16 v1(21.21,60.91)
  BOTTOM w0.097: R177.1 v1(21.21,60.91) 21.59,61.29 R169.2
N17144878: length 4.9
  TOP w0.203: 58.61,27.72 C111.1 57.8,27.72 57.56,27.96 57.56,28.57 56.59,29.53 U23.1
  TOP w0.254: R100.2 58.67,27.72 58.61,27.72
N17144894: length 4.6
  TOP w0.203: U23.2 56.75,29.93 58.08,28.6 C111.2
  TOP w0.254: C111.2 58.22,28.96 58.8,29.54 R97.2
N17145414: length 3.4
  TOP w0.203: C107.1 58.12,30.74 U23.4
  TOP w0.254: C107.1 59.33,30.64 N17.2
N17145423: length 3.5
  TOP w0.203: U23.5 57.51,31.14 57.9,31.53 C107.2
  TOP w0.254: C107.2 58.23,31.51 N15.2
N17145876: length 6.5
  TOP w0.157: C95.1 59.15,34.99 59.18,34.95 ; C94.1 58.07,34.95
  TOP w0.178: R79.2 57.59,34.95 56.92,34.29 56.92,33.74 57.23,33.44 57.23,33 56.56,32.33 U23.8
N17146129: length 5.9
  TOP w0.178: R68.2 57.36,37.02 57.35,36.77 56.11,35.53 56.11,35.17 55.83,34.89 v1(55.83,34.81) 55.78,34.81 55.32,34.35 U23.11
  BOTTOM w0.178: C367.1 R262.1 56.06,34.59 v1(55.83,34.81)
N17146590: length 2.6
  TOP w0.178: U23.6 57.07,31.53 57.25,31.72 v1(57.25,31.72)
  BOTTOM w0.254: R279.2 57.25,31.08 v1(57.25,31.72)
N17146868: length 2
  TOP w0.127: N10.2 54.74,35.5 54.52,35.28 U23.13
N17146877: length 2.9
  TOP w0.099: R73.2 53.11,36.35 53.21,36.25
  TOP w0.127: 53.21,36.25 53.72,35.74 U23.15
N17146886: length 3.4
  TOP w0.127: R70.2 54.12,36.48 U23.14
N17147965: length 3.4
  TOP w0.178: v1(54.97,34.86) 54.97,34.76 54.92,34.72 U23.12
  BOTTOM w0.178: C368.1 R263.1 54.03,34.25 54.64,34.86 v1(54.97,34.86)
N17148213: length 3.5
  TOP w0.178: C110.2 49.18,29.03 49.63,29.48 49.96,29.48 50.42,29.93 U23.29
  TOP w0.203: C110.2 49.18,27.83 R104.2
N17148219: length 2.4
  TOP w0.178: C110.1 50.06,29.03 50.57,29.53 U23.30
  TOP w0.203: R105.2 50.06,27.83 C110.1
N17148656: length 7.1
  TOP w0.203: U23.27 49.34,30.74 v1(49.15,30.55)
  BOTTOM w0.254: v1(49.15,30.55) 49.09,30.48 C414.1 49.15,29.53 N48.2 N47.2 51.31,28.51 R296.2
N17148665: length 6.4
  TOP w0.203: v1(49.25,31.39) 49.38,31.39 49.63,31.14 U23.26
  BOTTOM w0.254: N49.2 48.13,29.53 C414.2 ; R280.2 47.18,29.59 C414.2 ; C414.2 48.2,30.49 49.09,31.39 v1(49.25,31.39)
N17149089: length 2.6
  BOTTOM w0.203: R287.1 59.47,29.49 C419.1 59.08,29.43 R284.2
N17149196: length 1.7
  TOP w0.127: U23.38 54.52,28.19 54.41,28.08 54.23,28.08 54.12,28.2 U23.37
N17149216: length 1.7
  TOP w0.127: U23.35 53.32,28.21 53.43,28.1 53.61,28.1 53.72,28.21 53.72,28.79 U23.36
N17149500: length 5.6
  TOP w0.254: v1(51.44,25.02) 51.53,25.11 R107.2
  BOTTOM w0.254: R320.1 50.83,22.01 R316.1 C444.1 50.83,24.41 v1(51.44,25.02)
N17149614: length 1.7
  TOP w0.127: U23.34 52.92,28.2 52.81,28.08 52.63,28.08 52.5,28.21 52.5,28.78 U23.33
N17149691: length 4.2
  TOP w0.203: U23.18 52.52,34.72 v1(52,35.24)
  BOTTOM w0.203: C369.1 R265.1 50.98,34.13 52,35.15 v1(52,35.24)
N17152659: length 11.5
  TOP w0.508: v1(74.03,44.15) N38.1 73.52,42.87 L5.1
  L3_SIG w0.508: 69.09,45.34 72.9,45.34 74.03,44.21 v1(74.03,44.15)
  BOTTOM w0.203: N38.1 v1(74.03,44.15)
  BOTTOM w0.508: v1(62.14,45.38) 62.43,45.09 C292.2
  vias: v2(68.71,44.6)
N17152745: length 3.5
  TOP w0.203: v1(59.94,44.73) 60.35,44.33 U12.17
  BOTTOM w0.508: v1(59.94,44.73) 60.17,44.5 C292.1
N17154210: length 1.2
  BOTTOM w0.254: C364.1 67.2,34.11 N42.2
N17167628: length 1.3
  TOP w0.203: 67.47,33.49 U20.10
  TOP w0.254: N11.1 67.65,34.25 67.47,34.07 67.47,33.49
N17167629: length 1.4
  TOP w0.254: U18.3 68.71,34.27 N11.2
N17167636: length 1.9
  TOP w0.254: U20.6 67.78,31.46 68.35,30.89 N16.1
N17167639: length 1.2
  TOP w0.254: U19.3 69.56,31.52 69.74,31.34 N16.2
N17167672: length 1.8
  TOP w0.203: v1(64.67,34.29) 64.36,33.98 64.36,33.5 U20.1
  BOTTOM w0.254: N42.1 64.85,34.11 v1(64.67,34.29)
N17167678: length 4.3
  TOP w0.203: v1(63.55,31.7) 63.55,31.76 63.75,31.96 U20.4
  TOP w0.508: C108.2 63.45,30.35 63.45,31.6 v1(63.55,31.7)
  BOTTOM w0.381: R276.2 63.69,31.56 v1(63.55,31.7)
N17167679: length 6.9
  TOP w0.254: 63.5,33.25 63.47,33.22 63.37,33.32 N14.2 ; N12.2 63.14,34.29 ; v1(64.4,30.8) U20.5
  TOP w0.305: 63.5,33.25 63.79,32.96 U20.2
  BOTTOM w0.381: v1(64.4,30.8) 64.4,33.52 v1(63.63,34.29)
N17167680: length 1.8
  TOP w0.254: U20.8 68.24,32.46 v1(68.4,32.3)
  BOTTOM w0.254: N45.1 68.01,31.92 v1(68.4,32.3)
N17168063: length 4.6
  TOP w0.152: U3.1 82.86,68.4 82.17,69.09 82.17,70.61 81.98,70.8 C6.1 81.6,70.87 R2.2
N17168068: length 4.1
  TOP w0.152: U3.2 82.63,68 81.79,68.83 81.79,69.79 C6.2 81.6,69.85 R6.2
N17168091: length 4.1
  TOP w0.152: C16.1 80.72,68.15 79.82,68.15 N1.2
  TOP w0.203: U3.4 82.41,67.2 81.79,67.81 81.12,67.81 C16.1
N17168094: length 3.8
  TOP w0.152: N2.2 79.72,66.98 80.82,66.98 C16.2
  TOP w0.203: C16.2 80.97,67.13 81.98,67.13 82.31,66.8 U3.5
N17168118: length 5
  TOP w0.178: U3.8 82.57,65.6 81.1,64.12 C26.1
  TOP w0.508: C26.1 C25.1 R16.2
N17168130: length 5.4
  TOP w0.152: R19.2 82.84,63.22 v1(83.13,63.22)
  TOP w0.178: v1(83.13,63.22) 82.93,63.42 82.93,63.83 83.11,64.01 83.96,64.01 U3.11
  BOTTOM w0.178: v1(83.13,63.22) 82.93,63.42 82.93,63.8 R165.1 83.68,64.02 C200.1
N17168147: length 2.9
  TOP w0.178: v1(81.84,66.52) 81.96,66.4 U3.6
  BOTTOM w0.178: R157.2 83.19,66.4 81.96,66.4 v1(81.84,66.52)
N17168149: length 3.6
  TOP w0.178: U3.13 84.81,62.89 84.2,62.28 83.29,62.28 82.97,61.96 R20.2
N17168150: length 3
  TOP w0.178: U3.15 85.61,63.67 85.5,63.56 85.5,62.86 86.65,61.71 R22.2
N17168151: length 2.5
  TOP w0.178: R21.2 84.88,62.14 85.21,62.48 U3.14
N17168168: length 4
  TOP w0.178: v1(83.92,62.87) 84.41,63.35 U3.12
  BOTTOM w0.152: R167.1 84.22,63.17 v1(83.92,62.87)
  BOTTOM w0.178: R167.1 85.09,63.17 85.91,63.99 C199.1
N17168181: length 3.2
  TOP w0.203: v1(82.85,70.18) 82.88,70.15 83.95,70.15 84.41,69.69 U3.39
  BOTTOM w0.254: v1(82.85,70.18) 82.66,69.99 82.14,69.99 R140.1
N17168182: length 2.1
  TOP w0.203: v1(82.85,69.11) 82.88,69.14 U3.40
  BOTTOM w0.254: v1(82.85,69.11) 82.83,69.11 82.52,68.81 R143.1
N17168188: length 3.1
  BOTTOM w0.157: C184.1 79.67,69.86
  BOTTOM w0.203: 79.67,69.86 79.82,69.86 79.85,69.82 79.95,69.93 R140.2
  BOTTOM w0.254: C184.1 79.47,70.14 R142.1
N17168191: length 1.4
  TOP w0.127: U3.38 84.81,69.14 84.81,69.58 84.92,69.7 85.1,69.7 85.21,69.59 U3.37
N17168196: length 1.3
  TOP w0.099: U3.36 85.61,69.55 85.68,69.62 85.91,69.62 86.01,69.52 U3.35
N17168203: length 1.3
  TOP w0.127: U3.34 86.41,69.14 86.41,69.55 86.54,69.67 86.7,69.67 86.81,69.56 U3.33
N17168208: length 4
  TOP w0.178: v1(87.35,62.76) 87.35,62.92 86.81,63.45 U3.18
  BOTTOM w0.254: C204.1 88.53,62.76 v1(87.35,62.76) 87.44,62.85 R166.1
N17168279: length 1.3
  TOP w0.127: U3.31 87.61,69.56 87.5,69.67 87.33,69.67 87.21,69.55 87.21,69.14 U3.32
N17179290: length 9.2
  TOP w0.127: C156.1 108.38,8.96 N19.2 N20.2
  TOP w0.203: C156.1 109.52,11.13 112.9,11.13
  TOP w0.254: U31.15 112.65,10.87 112.9,11.13 v1(112.95,11.13)
  BOTTOM w0.254: v1(112.95,11.13) 113.3,10.78 R346.2
N17179770: length 2.1
  TOP w0.254: U31.5 110.88,7.85 110.13,7.09 R128.2
N17179844: length 2
  TOP w0.203: U31.2 110.84,9.35 110.32,9.87 109.62,9.87 C158.1
N17180503: length 3.2
  TOP w0.254: v1(114.5,11.2) 113.84,11.2 113.82,11.2 113.69,11.07 113.69,11.05 113.15,10.51 U31.14
  BOTTOM w0.203: v1(114.5,11.2) 114.47,11.17 114.47,10.88 114.76,10.6 C486.1
N17180512: length 1.1
  BOTTOM w0.254: N55.2 115.37,8.71 C486.2
N17180842: length 3
  TOP w0.508: U31.12 116.65,8.07 116.82,8.23 v1(116.99,8.23)
  BOTTOM w0.254: v1(116.99,8.23) 116.95,8.23 116.52,8.66 N55.1
N17181045: length 4.3
  BOTTOM w0.254: R355.1 113.73,4.37 N60.2 ; R355.1 114.15,4.79 R353.1 ; R355.1 113.75,4.38 N59.1
N17181051: length 9
  TOP w0.203: v1(110.54,10.52) 110.54,10.34 111.03,9.85 U31.1
  BOTTOM w0.203: R347.2 114.21,9.58 112.62,9.58 112.36,9.31 R348.1 112.04,9.28 R349.1 111.35,9.82 111.37,9.84 110.69,10.52 v1(110.54,10.52)
  BOTTOM w0.254: C487.2 109.73,11.11 R342.2 110.29,11.18 110.54,10.92 v1(110.54,10.52)
N17181054: length 4
  BOTTOM w0.203: N58.1 111.3,6.25 N57.2 111.35,7.42 ; R352.2 111.65,7.72 111.35,7.42 ; 111.35,7.42 R349.2
N17181057: length 2.3
  BOTTOM w0.203: R353.2 114.64,7.02 C497.1 114.64,8.26 R347.1
N17181086: length 3.6
  TOP w0.203: U31.8 112.15,6.42 112.15,5.89 111.84,5.58 v1(111.84,5.33)
  BOTTOM w0.203: R352.1 112.51,6.24 111.84,5.57 v1(111.84,5.33) 111.84,5.11 112.27,4.67 R355.2
N17181203: length 2.8
  TOP w0.203: U31.3 110.65,8.85 v1(110.55,8.95)
  BOTTOM w0.254: v1(110.55,8.95) 110.54,8.95 110.29,9.21 C487.1 C488.1
N17181207: length 1.1
  BOTTOM w0.254: C488.2 108.71,11.11 R342.1
N17181386: length 1.7
  BOTTOM w0.203: C497.2 113.75,8.46 R348.2
N17226208: length 4.3
  TOP w0.254: U30.7 122.28,15.7 122.53,15.95 124.46,15.95 v1(124.56,16.05)
  BOTTOM w0.508: v1(124.56,16.05) 124.31,15.8 C476.1
N17226226: length 3.8
  TOP w0.305: v1(121.11,16.66) 121.11,16.26 121.78,15.58 U30.8
  BOTTOM w0.254: v1(121.11,16.66) R334.1 R333.1
N17226252: length 3.5
  TOP w0.254: C139.1 78,15.01 79.43,15.01 79.67,15.25 U28.7
N17226270: length 3
  TOP w0.099: U28.8 80.17,14.58 R124.1 R125.1
N17226296: length 3.4
  TOP w0.203: U26.7 119.58,19.56 119.08,19.56 118.62,20.02 118.62,21.55 C122.1
N17226314: length 3.7
  TOP w0.203: U26.8 119.07,19 118.67,19.41 v1(118.05,19.41)
  BOTTOM w0.203: v1(118.05,19.41) 118.05,18.83 R323.1
  BOTTOM w0.254: v1(118.05,19.41) 118.58,19.94 R321.1
N17250574: length 3.8
  TOP w0.203: R5.2 128.11,69.68 C10.1 ; v1(128.04,68.91) 128.04,68.95 128,68.99 C10.1 ; R3.1 C10.1
  BOTTOM w0.203: v1(128.04,68.91) 128.23,68.72 U38.1
N17250701: length 2.9
  TOP w0.254: v1(124.28,66.55) 124.37,66.46 125.05,66.46 R10.1 N4.2
  BOTTOM w0.203: v1(124.28,66.55) 124.37,66.46 125.14,66.46 U38.7
N17251874: length 1.4
  BOTTOM w0.203: C201.1 125.15,64.53 U38.6
N17255840: length 1.6
  TOP w0.254: U2.18 97.06,69.23 R8.2
N17255975: length 4.3
  TOP w0.254: v1(110.68,69.79) 109.87,69.79 108.58,68.5
  TOP w0.508: L1.1 108.5,68.58 108.58,68.5
  BOTTOM w0.254: N28.1 v1(110.68,69.79)
N17255997: length 13.1
  TOP w0.203: v1(97.18,69.76) 97.21,69.73 U2.17
  TOP w0.508: v1(104.22,65.51) 104.22,65.13 104.72,64.62 C20.1
  BOTTOM w0.254: v1(97.18,69.76) 97.67,69.77 98.09,69.34 98.09,66.88 98.65,66.32 103.4,66.32 v1(104.22,65.51)
N17388894: length 4.9
  TOP w0.099: v1(93.93,6.76) 94.42,6.27 S1.A5
  BOTTOM w0.097: R350.1 94.05,8.12 94.05,7.29 93.93,7.16 v1(93.93,6.76)
N17389012: length 4.9
  TOP w0.099: S1.A6 93.42,6.61 92.61,7.42 v1(92.61,7.49)
  BOTTOM w0.097: v1(92.61,7.49) 92.61,8.29 R351.1
N17417846: length 2.7
  TOP w0.152: R7.2 82.45,67.6 U3.3
N17417864: length 4.1
  TOP w0.152: R18.2 80.95,62.29 81.39,62.74 81.92,62.74 82.56,63.39 82.56,64.52 82.84,64.8 U3.10
N17418022: length 1.9
  TOP w0.203: U3.30 v1(88.35,68.89)
  BOTTOM w0.381: v1(88.35,68.89) 88.28,68.89 87.59,68.21 R147.2
N17418057: length 2.9
  TOP w0.203: U3.29 89.13,68 89.41,68.28 v1(89.41,68.71)
  BOTTOM w0.381: R147.1 88.54,67.84 v1(89.41,68.71)
N17438894: length 105.5
  BOTTOM w0.254: N52.1 60.43,26.15 60.43,26.68 61.87,28.12 61.87,29.82 62.05,30 62.05,32 62.76,32.71 62.76,36.39 59.31,39.85 59.31,47.5 67.67,55.85 90.98,55.85 94.21,59.08 94.21,60.99 95.45,62.23 99.9,62.23 100.2,62.53 114.91,62.53 121.13,56.32 121.13,54.11 122.71,52.53 122.71,50.78 123.39,50.09 123.39,49.32 123.06,48.99 N36.2
N17439936: length 105.8
  BOTTOM w0.254: N35.2 124.08,48.99 123.75,49.32 123.75,50.24 123.06,50.93 123.06,52.68 121.49,54.25 121.49,56.46 115.06,62.89 100.06,62.89 99.75,62.59 95.31,62.59 93.85,61.13 93.85,59.23 90.84,56.21 67.52,56.21 58.95,47.65 58.95,39.7 62.41,36.25 62.41,32.86 61.7,32.15 61.7,30.15 61.52,29.97 61.52,28.27 60.07,26.82 60.07,26.3 60.01,26.24 N50.1
N17467924: length 2.3
  BOTTOM w0.254: R315.2 48.21,24.99 C450.1
N17467927: length 4
  TOP w0.254: v1(49.73,20.93) 49.73,20.75 49.77,20.72 U29.12
  BOTTOM w0.254: R315.1 49.23,21.44 v1(49.73,20.93)
N17470556: length 3.1
  TOP w0.381: v1(69.72,27.94) 69.94,27.73 U25.12
  BOTTOM w0.381: R302.1 70.51,26.64 69.72,27.43 v1(69.72,27.94)
N17536513: length 4.5
  TOP w0.099: C27.1 51.81,62.92 X1.4 52.03,63.19 L2.2 53.33,63.22 R13.1
N17536522: length 1.6
  TOP w0.099: R13.2 51.95,65.08 X1.1
N17552359: length 3.4
  TOP w0.099: U24.3 106.2,25.01 105.92,24.73 v1(105.72,24.73)
  BOTTOM w0.097: R305.2 106.15,24.93 105.95,24.73 v1(105.72,24.73) 105.55,24.56 R312.2
N17555377: length 1.9
  TOP w0.099: U7.D1 44.71,52.62 v1(44.33,53.01)
  BOTTOM w0.097: v1(44.33,53.01) 43.6,52.28 TP47.1
N17555397: length 4
  TOP w0.099: v1(42.39,58.08) 42.82,57.65 U7.J3
  BOTTOM w0.097: TP48.1 42.84,61.07 42.84,58.52 v1(42.39,58.08)
N17555432: length 8.8
  TOP w0.099: U7.F14 31.82,54.56 v1(31.39,54.13)
  BOTTOM w0.097: TP49.1 24.36,54.38 25.09,55.11 30.41,55.11 v1(31.39,54.13)
N17555507: length 4.2
  TOP w0.099: v1(39.35,53.07) 38.9,52.62 U7.D7
  BOTTOM w0.097: v1(39.35,53.07) 39.51,53.23 40.43,53.23 40.89,53.69 40.89,54.6 41.41,55.12 TP51.1
N17555530: length 5.7
  TOP w0.099: U7.R10 35.83,63.62 v1(36.24,63.21)
  BOTTOM w0.097: v1(36.24,63.21) 36.79,62.67 40.5,62.67 TP52.1
N17799133: length 6.5
  TOP w0.203: U14.G62 115.95,28.62 115.67,28.27 v1(115.62,28.27) ; v1(114.33,28.05) 114.65,28.37 114.65,28.72 U14.G64
  TOP w0.254: U14.C62 115.48,26.75 v1(115.89,26.35) 115.99,26.45 116.26,26.45 U14.C60 ; U14.E62 115.48,27.57 v1(115.91,27.14) 116.14,27.14 116.51,27.51 U14.D60 ; v1(113.69,30.66) U14.L65 115.12,30.66 U14.L63
  BOTTOM w0.381: v1(115.89,26.35) 115.96,26.28 N51.2
N18063596: length 1.8
  BOTTOM w0.099: D10.1 30.61,56.11 R191.1
N18398429: length 3.1
  TOP w0.099: R94.2 93.62,30.41 94.07,30.86 94.97,30.86 95.07,30.76 U21.19
N18398432: length 2.3
  TOP w0.254: U21.22 96.72,28.95 96.53,28.76 v1(96.53,28.32)
  BOTTOM w0.508: v1(96.53,28.32) 96.42,28.22 R293.2
N18398435: length 1.7
  TOP w0.099: U21.28 99.01,29.51 99.01,28.25 R102.2
N170603760: length 2.6
  TOP w0.203: TP4.1 10.73,40.53 U17.22

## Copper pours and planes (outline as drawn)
12V_HOLD on TOP: 45.16,24.87 48.95,24.87 49.28,24.54 49.28,18.59 45.42,18.59 44.91,19.1 44.91,24.61
GND on TOP (solid shape): outline of 222 points within 57.5,68.76 63.59,74.85
GND on BOTTOM (solid shape): outline of 222 points within 57.5,68.76 63.59,74.85
GND on TOP: 16.38,13.03 21.92,13.03 22.58,13.69 22.58,17.09 21.95,17.73 17.22,17.73 16.51,17.02 16.51,15.37 16.26,15.11 16.26,13.16
GND on TOP: 35.69,21.84 38.1,21.84 38.48,21.46 38.48,14.61 38.1,14.22 35.66,14.22 35.43,14.45 35.43,17.02 34.29,18.16 34.29,20.45
GND on TOP: 92.74,12.42 94.67,12.42 94.87,12.22 94.87,11.48 94.31,10.92 94.31,8.23 92.3,8.23 92.3,11.99
GND on TOP: 134.92,9.65 134.92,8.56 134.37,8 125.6,8 125.17,8.43 125.17,9.7 124.89,9.98 124.1,9.98 123.83,10.26 123.83,11.73 124.28,12.19 129.92,12.19 130.18,11.94 130.18,11.18 131.32,10.03 134.54,10.03
GND on TOP: 109.63,14.45 115.11,14.45 116.03,15.37 116.03,16.94 115.54,17.42 110.13,17.42 109.47,16.76 109.47,14.61
GND on TOP: 184.78,71.48 189.18,71.48 189.69,70.97 189.69,68.53 189.13,67.97 185.39,67.97 184.76,68.61 184.76,71.45
GND on TOP: 126.51,58.74 125.57,59.69 119.79,59.69 119.25,60.22 119.25,62.89 119.79,63.42 124.86,63.42 125.75,64.31 125.75,70.64 122.45,70.64 122.45,72.11 122.86,72.53 127.4,72.53 127.4,65.35 127.73,65.02 128.11,65.02 128.29,64.84 128.29,59.25 127.78,58.74
GND on TOP: 62.81,24.05 65.79,24.05 66.46,24.73 68.44,24.73 68.99,25.27 71.91,25.27 73.74,23.44 84.68,23.44 84.84,23.29 84.84,22 84.61,21.77 63.12,21.77 62.64,22.25 62.64,23.88
GND on TOP: 83.72,18.21 83.72,15.98 83.6,15.85 82.67,15.85 81.94,16.59 76.89,16.59 76.66,16.81 76.66,18.03 77.11,18.49 83.44,18.49
GND on TOP: 17.3,47.83 24.69,47.83 25.68,46.84 25.68,45.11 25.27,44.7 23.32,44.7 22.94,45.09 16.76,45.09 16.51,45.34 16.51,47.04
GND on TOP: 44.7,17.58 63.2,17.58 63.65,17.12 66.57,17.12 66.93,16.76 66.93,14.27 65.18,12.52 56.57,12.52 54.33,14.76 47.12,14.76 46.61,14.25 46.61,12.32 46.48,12.19 44.7,12.19 44.32,12.57 44.32,17.2
GND on TOP: 26.01,33.12 31.8,33.12 32.69,32.23 32.69,29.74 31.93,28.98 23.6,28.98 22.89,28.27 22.89,26.85 22.45,26.42 20.7,26.42 20.27,26.85 20.27,32.26 19.05,33.48 19.05,35.56 18.34,36.27 11.71,36.27 11.35,36.63 11.35,39.19 11.86,39.7 17.53,39.7 18.62,38.61 23.62,38.61 23.88,38.35 23.88,35.26
GND on TOP: 65.68,28.6 64.97,29.31 64.97,36.04 64.47,36.55 63.68,36.55 63.35,36.88 63.35,37.77 64.11,38.53 65.53,38.53 65.76,38.3 65.76,37.74 67.49,36.02 67.49,35.13 66.88,34.52 66.88,30.89 67.31,30.45 69.9,30.45 70.18,30.73 70.18,32.13 70.25,32.21 80.21,32.21 81.25,33.25 85.12,33.25 85.8,32.56 85.8,31.83 86.74,30.89 89.31,30.89 89.84,30.35 89.84,28.19 89.13,27.48 85.93,27.48 83.57,29.84 70.66,29.84 69.42,28.6
GND on TOP: 120.27,22.53 120.27,17.22 120.42,17.07 121.59,17.07 121.97,17.45 121.97,22.43 121.82,22.58 120.32,22.58
GND on TOP: 180.19,5.84 188.59,5.84 189.26,5.18 189.26,2.49 188.7,1.93 179.5,1.93 178.84,2.59 178.84,4.5
GND on TOP: 91.44,71.86 91.44,66.98 89.84,66.98 89.84,69.37 89.71,69.49 88.19,69.49 87.88,69.8 87.88,72.11 88.8,73.03 101.8,73.03 102.77,72.06 102.77,66.73 102.59,66.55 101.55,66.55 101.35,66.75 101.35,71.04 100.28,72.11 91.69,72.11
GND on TOP: 72.92,57.18 83.67,57.18 84.58,56.26 90.02,56.26 90.25,56.03 90.25,51.23 88.52,49.5 71.48,49.5 70.87,48.9 70.87,47.14 70.08,46.35 67.56,46.35 66.86,45.65 66.86,40.61 67.56,39.91 67.56,39.01 67.16,38.61 66.24,38.61 65.99,38.86 65.99,39.88 65.79,40.08 65.21,40.08 64.96,40.32 64.96,42.52 65.46,43.02 65.46,44.73 65.76,45.03 65.76,46.53 66.93,47.7 66.93,51.18
GND on TOP: 123.98,12.4 119.71,12.4 119.71,14.25 122.57,14.25 122.57,15.31 122.62,15.36 123.05,15.36 123.05,14.65 123.1,14.6 123.9,14.6 124.06,14.44 124.07,14.44 124.18,14.33 124.18,12.59
GND on BOTTOM: 87.64,68.48 87.64,66.67 88.01,66.3 88.01,64.67 85.33,64.67 85.23,64.56 85.23,64.13 84.06,64.13 84.06,64.67 82.31,64.67 82.31,65.91 82.48,66.09 83.73,66.09 83.83,66.19 83.83,68.53 87.59,68.53
GND on BOTTOM: 91.82,71.81 91.82,67.06 89.92,67.06 89.92,69.34 89.74,69.52 88.67,69.52 87.88,70.31 87.88,72.11 88.8,73.03 101.8,73.03 102.95,71.88 102.95,67.97 102.57,67.59 101.5,67.59 101.35,67.74 101.35,71.15 100.25,72.24 92.25,72.24
GND on BOTTOM: 128.68,6.99 130.94,6.99 131.95,8 131.95,10.29 130.81,11.43 127.48,11.43 125.27,9.22 125.27,7.54 125.48,7.34 128.32,7.34
GND on BOTTOM: 84.24,29.17 83.54,29.87 70.69,29.87 69.42,28.6 65.63,28.6 64.97,29.26 64.97,32.16 64.85,32.28 63.8,32.28 63.22,32.87 63.22,37.46 63.74,37.98 65.52,37.98 67.49,36.02 67.49,34.92 66.88,34.32 66.88,30.89 67.21,30.56 69.27,30.56 70,31.29 70,32.21 70.23,32.44 78.26,32.44 79.58,33.76 83.72,33.76 84.3,33.17 89.64,33.17 89.84,32.97 89.84,30.35 88.66,29.17 ; 1 cut-out
GND on BOTTOM: 176.78,71.17 176.78,68.22 177.06,67.94 182.04,67.94 182.04,71.45 177.06,71.45
GND on BOTTOM: 181.05,5.82 179.81,5.82 177.8,3.81 177.8,2.64 178.08,2.36 181.05,2.36
GND on BOTTOM: 68.58,55.5 91.19,55.5 91.54,55.14 91.54,52.53 90.86,51.84 87.2,51.84 86.94,51.59 86.94,49.73 86.66,49.45 71.4,49.45 71.4,49.43 70.87,48.9 70.87,47.14 69.9,46.18 68.76,46.18 67.61,45.03 67.61,42.6 67.26,42.24 65.61,42.24 65.46,42.39 65.46,46.23 67.18,47.96 67.18,54.1
GND on BOTTOM: 63.02,24.26 65.68,24.26 66.48,25.05 72.13,25.05 73.74,23.44 84.68,23.44 85.09,23.04 85.09,21.89 84.96,21.77 63.12,21.77 62.64,22.25 62.64,23.88
GND on BOTTOM: 96.44,33.45 96.44,30.76 99.82,30.76 99.82,33.45
GND on BOTTOM: 120.35,21.44 120.35,17.07 121.59,17.07 121.97,17.45 121.97,21.54 121.79,21.72 120.62,21.72
GND on BOTTOM: 44.91,15.75 44.91,18.24 44.98,18.31 46.43,18.31 46.63,18.11 46.63,17.6 46.84,17.4 65.02,17.4 65.3,17.12 66.75,17.12 67.01,16.87 67.01,14.55 66.62,14.17 54.91,14.17 54.33,14.76 47.14,14.76 46.61,14.22 46.61,12.32 46.48,12.19 44.7,12.19 44.32,12.57 44.32,15.16
GND on BOTTOM: 22.78,32.94 25.27,32.94 25.81,32.41 31.83,32.41 33.02,31.22 33.02,29.31 31.5,27.79 20.8,27.79 20.8,28.83 22.12,30.15 22.12,32.28
